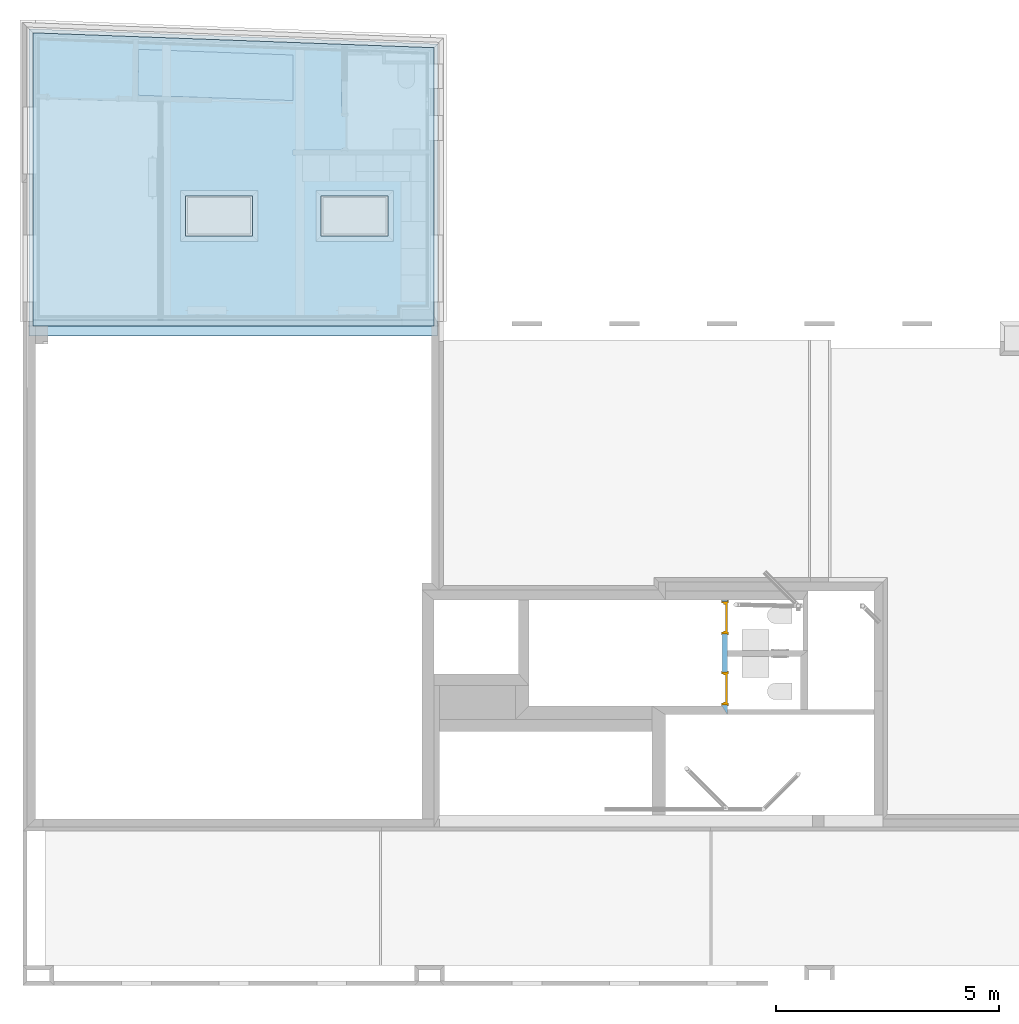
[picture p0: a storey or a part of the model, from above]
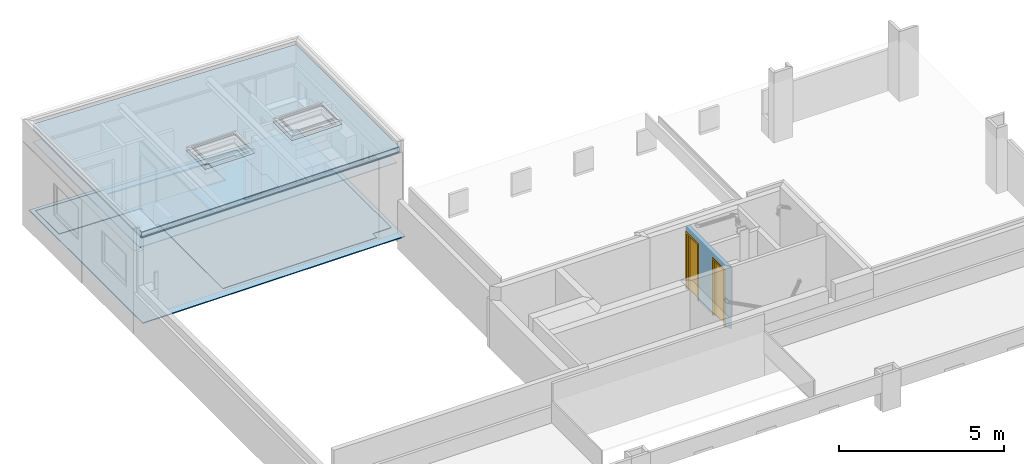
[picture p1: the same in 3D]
Properties of the parts of a building model (IFC2X3), part 2 of 16

# IfcBeam: A-Beams-Steel (159)
Name | In | Description | CodeSystem | Name = StructuralFramingCommon, Section Name | Structural Parameters, Section Name | Length (m) | Area | Cross-sectional (m2) | Area | Cross-sectional Modeled (m2) | Area | Side Surfaces Modeled (Gross) (m2) | Area | All Surfaces Modeled (Net) (m2) | Volume | Perforation(s) (m3) | Volume (Gross) (m3) | Volume (Gross Modeled) (m3) | Volume (Net) (m3) | Volume (Net Modeled) (m3) | Unit Weight | Length x Unit Weight | Volume (Gross) x Density | Volume (Gross Modeled) x Density | Volume (Net) x Density | Volume (Net Modeled) x Density | FireRating = Fire | Rating | ID | Number | ID | Keynote
RP | 5F | 5,SHE-13.STEEL.dgn ,Design Model:125234 | BS UC | UC203X203X46 | 1\BS UC\UC203X203X46 | 1.15342 | 0.00587 | 0.005784 | 1.39149 | 1.40306 | 0 | 0.006771 | 0.006671 | 0.006771 | 0.006671 | 46.100000 | 53.172740 | 53.149095 | 52.368971 | 53.149095 | 52.368971 | FD60 | RP | intumescent paint
RP | 5F | 5,SHE-13.STEEL.dgn ,Design Model:125236 | BS UC | UC203X203X46 | 1\BS UC\UC203X203X46 | 1.15342 | 0.00587 | 0.005784 | 1.39149 | 1.40306 | 0 | 0.006771 | 0.006671 | 0.006771 | 0.006671 | 46.100000 | 53.172740 | 53.149095 | 52.368971 | 53.149095 | 52.368971 | FD60 | RP | intumescent paint
RP | 5F | 5,SHE-13.STEEL.dgn ,Design Model:125238 | BS UC | UC203X203X46 | 1\BS UC\UC203X203X46 | 2.1776 | 0.00587 | 0.005784 | 2.62706 | 2.63862 | 0 | 0.012783 | 0.012595 | 0.012783 | 0.012595 | 46.100000 | 100.387360 | 100.342719 | 98.869886 | 100.342719 | 98.869886 | FD60 | RP | intumescent paint
RP | 5F | 5,SHE-13.STEEL.dgn ,Design Model:125240 | BS UC | UC203X203X46 | 1\BS UC\UC203X203X46 | 2.4968 | 0.00587 | 0.005784 | 3.01214 | 3.02371 | 0 | 0.014656 | 0.014441 | 0.014656 | 0.014441 | 46.100000 | 115.102480 | 115.051296 | 113.362570 | 115.051296 | 113.362570 | FD60 | RP | intumescent paint
RP | 5F | 5,SHE-13.STEEL.dgn ,Design Model:125242 | BS UC | UC203X203X46 | 1\BS UC\UC203X203X46 | 2.2808 | 0.00587 | 0.005784 | 2.75156 | 2.76313 | 0 | 0.013388 | 0.013192 | 0.013388 | 0.013192 | 46.100000 | 105.144880 | 105.098124 | 103.555491 | 105.098124 | 103.555491 | FD60 | RP | intumescent paint
RP | 5F | 5,SHE-13.STEEL.dgn ,Design Model:125244 | BS UC | UC203X203X46 | 1\BS UC\UC203X203X46 | 2.4849 | 0.00587 | 0.005784 | 2.99778 | 3.00935 | 0 | 0.014586 | 0.014372 | 0.014586 | 0.014372 | 46.100000 | 114.553890 | 114.502950 | 112.822273 | 114.502950 | 112.822273 | FD60 | RP | intumescent paint
RP | 5F | 5,SHE-13.STEEL.dgn ,Design Model:125246 | BS UC | UC203X203X46 | 1\BS UC\UC203X203X46 | 2.4857 | 0.00587 | 0.005784 | 2.99875 | 3.01032 | 0 | 0.014591 | 0.014377 | 0.014591 | 0.014377 | 46.100000 | 114.590770 | 114.539813 | 112.858595 | 114.539813 | 112.858595 | FD60 | RP | intumescent paint
RP | 5F | 5,SHE-13.STEEL.dgn ,Design Model:125248 | BS UC | UC203X203X46 | 1\BS UC\UC203X203X46 | 2.5992 | 0.00587 | 0.005784 | 3.13567 | 3.14724 | 0 | 0.015257 | 0.015033 | 0.015257 | 0.015033 | 46.100000 | 119.823120 | 119.769836 | 118.011852 | 119.769836 | 118.011852 | FD60 | RP | intumescent paint
RP | 5F | 5,SHE-13.STEEL.dgn ,Design Model:125250 | BS UC | UC203X203X46 | 1\BS UC\UC203X203X46 | 2.1776 | 0.00587 | 0.005784 | 2.62706 | 2.63862 | 0 | 0.012783 | 0.012595 | 0.012783 | 0.012595 | 46.100000 | 100.387360 | 100.342719 | 98.869886 | 100.342719 | 98.869886 | FD60 | RP | intumescent paint
RP | 5F | 5,SHE-13.STEEL.dgn ,Design Model:125252 | BS UC | UC203X203X46 | 1\BS UC\UC203X203X46 | 2.495 | 0.00587 | 0.005784 | 3.00997 | 3.02154 | 0 | 0.014646 | 0.014431 | 0.014646 | 0.014431 | 46.100000 | 115.019500 | 114.968353 | 113.280844 | 114.968353 | 113.280844 | FD60 | RP | intumescent paint
RP | 5F | 5,SHE-13.STEEL.dgn ,Design Model:125254 | BS UC | UC203X203X46 | 1\BS UC\UC203X203X46 | 2.179 | 0.00587 | 0.005784 | 2.62875 | 2.64031 | 0 | 0.012791 | 0.012603 | 0.012791 | 0.012603 | 46.100000 | 100.451900 | 100.407230 | 98.933451 | 100.407230 | 98.933451 | FD60 | RP | intumescent paint
RP | 5F | 5,SHE-13.STEEL.dgn ,Design Model:125256 | BS UC | UC203X203X46 | 1\BS UC\UC203X203X46 | 2.546 | 0.00587 | 0.005784 | 3.07149 | 3.08306 | 0 | 0.014945 | 0.014726 | 0.014945 | 0.014726 | 46.100000 | 117.370600 | 117.318407 | 115.596405 | 117.318407 | 115.596405 | FD60 | RP | intumescent paint
RP | 5F | 5,SHE-13.STEEL.dgn ,Design Model:125258 | BS UC | UC203X203X46 | 1\BS UC\UC203X203X46 | 2.4936 | 0.00587 | 0.005784 | 3.00828 | 3.01985 | 0 | 0.014637 | 0.014423 | 0.014637 | 0.014423 | 46.100000 | 114.954960 | 114.903841 | 113.217280 | 114.903841 | 113.217280 | FD60 | RP | intumescent paint
RP | 5F | 5,SHE-13.STEEL.dgn ,Design Model:125260 | BS UC | UC203X203X46 | 1\BS UC\UC203X203X46 | 2.546 | 0.00587 | 0.005784 | 3.07149 | 3.08306 | 0 | 0.014945 | 0.014726 | 0.014945 | 0.014726 | 46.100000 | 117.370600 | 117.318407 | 115.596405 | 117.318407 | 115.596405 | FD60 | RP | intumescent paint
RP | 5F | 5,SHE-13.STEEL.dgn ,Design Model:125262 | BS UC | UC203X203X46 | 1\BS UC\UC203X203X46 | 2.3424 | 0.00587 | 0.005784 | 2.82587 | 2.83744 | 0 | 0.01375 | 0.013548 | 0.01375 | 0.013548 | 46.100000 | 107.984640 | 107.936621 | 106.352325 | 107.936621 | 106.352325 | FD60 | RP | intumescent paint
RP | 5F | 5,SHE-13.STEEL.dgn ,Design Model:125264 | BS UC | UC203X203X46 | 1\BS UC\UC203X203X46 | 2.4936 | 0.00587 | 0.005784 | 3.00828 | 3.01985 | 0 | 0.014637 | 0.014423 | 0.014637 | 0.014423 | 46.100000 | 114.954960 | 114.903841 | 113.217280 | 114.903841 | 113.217280 | FD60 | RP | intumescent paint
RP | 5F | 5,SHE-13.STEEL.dgn ,Design Model:125266 | BS UC | UC203X203X46 | 1\BS UC\UC203X203X46 | 2.3424 | 0.00587 | 0.005784 | 2.82587 | 2.83744 | 0 | 0.01375 | 0.013548 | 0.01375 | 0.013548 | 46.100000 | 107.984640 | 107.936621 | 106.352325 | 107.936621 | 106.352325 | FD60 | RP | intumescent paint
RP | 5F | 5,SHE-13.STEEL.dgn ,Design Model:125268 | BS UC | UC203X203X46 | 1\BS UC\UC203X203X46 | 1.13364 | 0.00587 | 0.005784 | 1.36762 | 1.37919 | 0 | 0.006654 | 0.006557 | 0.006654 | 0.006557 | 46.100000 | 52.260631 | 52.237392 | 51.470650 | 52.237392 | 51.470650 | FD60 | RP | intumescent paint
RP | 5F | 5,SHE-13.STEEL.dgn ,Design Model:125270 | BS UC | UC203X203X46 | 1\BS UC\UC203X203X46 | 1.13364 | 0.00587 | 0.005784 | 1.36762 | 1.37919 | 0 | 0.006654 | 0.006557 | 0.006654 | 0.006557 | 46.100000 | 52.260631 | 52.237392 | 51.470650 | 52.237392 | 51.470650 | FD60 | RP | intumescent paint
RP | 5F | 5,SHE-13.STEEL.dgn ,Design Model:125272 | BS UC | UC203X203X46 | 1\BS UC\UC203X203X46 | 2.0364 | 0.00587 | 0.005784 | 2.45671 | 2.46828 | 0 | 0.011954 | 0.011778 | 0.011954 | 0.011778 | 46.100000 | 93.878040 | 93.836294 | 92.458962 | 93.836294 | 92.458962 | FD60 | RP | intumescent paint
RP | 5F | 5,SHE-13.STEEL.dgn ,Design Model:125274 | BS UC | UC203X203X46 | 1\BS UC\UC203X203X46 | 1.9664 | 0.00587 | 0.005784 | 2.37227 | 2.38383 | 0 | 0.011543 | 0.011373 | 0.011543 | 0.011373 | 46.100000 | 90.651040 | 90.610729 | 89.280742 | 90.610729 | 89.280742 | FD60 | RP | intumescent paint
RP | 5F | 5,SHE-13.STEEL.dgn ,Design Model:125276 | BS UC | UC203X203X46 | 1\BS UC\UC203X203X46 | 1.9597 | 0.00587 | 0.005784 | 2.36418 | 2.37575 | 0 | 0.011503 | 0.011335 | 0.011503 | 0.011335 | 46.100000 | 90.342170 | 90.301996 | 88.976541 | 90.301996 | 88.976541 | FD60 | RP | intumescent paint
RP | 5F | 5,SHE-13.STEEL.dgn ,Design Model:125278 | BS UC | UC203X203X46 | 1\BS UC\UC203X203X46 | 2.4839 | 0.00587 | 0.005784 | 2.99658 | 3.00814 | 0 | 0.01458 | 0.014366 | 0.01458 | 0.014366 | 46.100000 | 114.507790 | 114.456870 | 112.776869 | 114.456870 | 112.776869 | FD60 | RP | intumescent paint
RP | 5F | 5,SHE-13.STEEL.dgn ,Design Model:125280 | BS UC | UC203X203X46 | 1\BS UC\UC203X203X46 | 2.0297 | 0.00587 | 0.005784 | 2.44863 | 2.4602 | 0 | 0.011914 | 0.011739 | 0.011914 | 0.011739 | 46.100000 | 93.569170 | 93.527561 | 92.154761 | 93.527561 | 92.154761 | FD60 | RP | intumescent paint
RP | 5F | 5,SHE-13.STEEL.dgn ,Design Model:125282 | BS UC | UC203X203X46 | 1\BS UC\UC203X203X46 | 0.6964 | 0.00587 | 0.005784 | 0.840137 | 0.851705 | 0 | 0.004088 | 0.004028 | 0.004088 | 0.004028 | 46.100000 | 32.104040 | 32.089764 | 31.618749 | 32.089764 | 31.618749 | FD60 | RP | intumescent paint
RP | 5F | 5,SHE-13.STEEL.dgn ,Design Model:125284 | BS UC | UC203X203X46 | 1\BS UC\UC203X203X46 | 2.179 | 0.00587 | 0.005784 | 2.62875 | 2.64031 | 0 | 0.012791 | 0.012603 | 0.012791 | 0.012603 | 46.100000 | 100.451900 | 100.407230 | 98.933451 | 100.407230 | 98.933451 | FD60 | RP | intumescent paint
RP | 5F | 5,SHE-13.STEEL.dgn ,Design Model:125286 | BS UC | UC203X203X46 | 1\BS UC\UC203X203X46 | 4.25305 | 0.00587 | 0.005784 | 5.13088 | 5.14245 | 0 | 0.024965 | 0.024599 | 0.024965 | 0.024599 | 46.100000 | 196.065605 | 195.978417 | 193.101842 | 195.978417 | 193.101842 | FD60 | RP | intumescent paint
RP | 5F | 5,SHE-13.STEEL.dgn ,Design Model:125288 | BS UC | UC203X203X46 | 1\BS UC\UC203X203X46 | 4.2564 | 0.00587 | 0.005784 | 5.13492 | 5.14649 | 0 | 0.024985 | 0.024618 | 0.024985 | 0.024618 | 46.100000 | 196.220040 | 196.132784 | 193.253942 | 196.132784 | 193.253942 | FD60 | RP | intumescent paint
RP | 5F | 5,SHE-13.STEEL.dgn ,Design Model:125290 | BS UC | UC203X203X46 | 1\BS UC\UC203X203X46 | 4.2582 | 0.00587 | 0.005784 | 5.13709 | 5.14866 | 0 | 0.024996 | 0.024629 | 0.024996 | 0.024629 | 46.100000 | 196.303020 | 196.215727 | 193.335668 | 196.215727 | 193.335668 | FD60 | RP | intumescent paint
RP | 5F | 5,SHE-13.STEEL.dgn ,Design Model:125292 | BS UC | UC203X203X46 | 1\BS UC\UC203X203X46 | 4.2082 | 0.00587 | 0.005784 | 5.07677 | 5.08834 | 0 | 0.024702 | 0.02434 | 0.024702 | 0.02434 | 46.100000 | 193.998020 | 193.911752 | 191.065511 | 193.911752 | 191.065511 | FD60 | RP | intumescent paint
RP | 5F | 5,SHE-13.STEEL.dgn ,Design Model:125294 | BS UC | UC203X203X71 | 1\BS UC\UC203X203X71 | 5.53365 | 0.00904 | 0.008953 | 6.84623 | 6.86414 | 0 | 0.050024 | 0.049545 | 0.050024 | 0.049545 | 71.000000 | 392.889150 | 392.689939 | 388.929846 | 392.689939 | 388.929846 | FD60 | RP | intumescent paint
RP | 5F | 5,SHE-13.STEEL.dgn ,Design Model:125296 | BS UC | UC203X203X71 | 1\BS UC\UC203X203X71 | 5.537 | 0.00904 | 0.008953 | 6.85038 | 6.86828 | 0 | 0.050054 | 0.049575 | 0.050054 | 0.049575 | 71.000000 | 393.127000 | 392.927668 | 389.165299 | 392.927668 | 389.165299 | FD60 | RP | intumescent paint
RP | 5F | 5,SHE-13.STEEL.dgn ,Design Model:125298 | BS UC | UC203X203X71 | 1\BS UC\UC203X203X71 | 5.4672 | 0.00904 | 0.008953 | 6.76402 | 6.78193 | 0 | 0.049424 | 0.04895 | 0.049424 | 0.04895 | 71.000000 | 388.171352 | 387.974533 | 384.259591 | 387.974533 | 384.259591 | FD60 | RP | intumescent paint
RP | 5F | 5,SHE-13.STEEL.dgn ,Design Model:125300 | BS UC | UC203X203X71 | 1\BS UC\UC203X203X71 | 5.4672 | 0.00904 | 0.008953 | 6.76402 | 6.78193 | 0 | 0.049424 | 0.04895 | 0.049424 | 0.04895 | 71.000000 | 388.171352 | 387.974533 | 384.259591 | 387.974533 | 384.259591 | FD60 | RP | intumescent paint
RP | 5F | 5,SHE-13.STEEL.dgn ,Design Model:125302 | BS UC | UC305X305X240 | 1\BS UC\UC305X305X240 | 8.38637 | 0.0306 | 0.030381 | 16.2075 | 16.2683 | 0 | 0.256623 | 0.254783 | 0.256623 | 0.254783 | 240.000000 | 2012.727813 | 2014.488949 | 2000.049145 | 2014.488949 | 2000.049145 | FD60 | RP | intumescent paint
RP | 5F | 5,SHE-13.STEEL.dgn ,Design Model:125306 | BS UC | UC305X305X240 | 1\BS UC\UC305X305X240 | 8.38638 | 0.0306 | 0.030381 | 16.2075 | 16.2683 | 0 | 0.256623 | 0.254784 | 0.256623 | 0.254784 | 240.000000 | 2012.730796 | 2014.491935 | 2000.052110 | 2014.491935 | 2000.052110 | FD60 | RP | intumescent paint
RP | 5F | 5,SHE-13.STEEL.dgn ,Design Model:125308 | BS UC | UC305X305X240 | 1\BS UC\UC305X305X240 | 8.38637 | 0.0306 | 0.030381 | 16.2075 | 16.2683 | 0 | 0.256623 | 0.254783 | 0.256623 | 0.254783 | 240.000000 | 2012.727813 | 2014.488949 | 2000.049145 | 2014.488949 | 2000.049145 | FD60 | RP | intumescent paint
A-Beams-Steel | GF | 15 ,SHE-14.BALCONY.dgn,Design Model:168529 | BS5950_UC | UC152X152X51 | 1\BS5950_UC\UC152X152X51 | 5.3944 | 0.0065 | 0.006469 | 5.11389 | 5.04575 | 0.000509 | 0.035064 | 0.034897 | 0.034554 | 0.034388 | 51.200000 | 276.193337 | 275.249317 | 273.943365 | 271.252702 | 269.946750
A-Beams-Steel | GF | 15 ,SHE-14.BALCONY.dgn,Design Model:168535 | BS5950_UC | UC152X152X51 | 1\BS5950_UC\UC152X152X51 | 5.4786 | 0.0065 | 0.006469 | 5.19371 | 5.0445 | 0.001018 | 0.035611 | 0.035442 | 0.034593 | 0.034424 | 51.200000 | 280.504377 | 279.545622 | 278.219285 | 271.552392 | 270.226056
A-Beams-Steel | GF | 15 ,SHE-14.BALCONY.dgn,Design Model:168539 | BS5950_UC | UC152X152X51 | 1\BS5950_UC\UC152X152X51 | 5.4786 | 0.0065 | 0.006469 | 5.19371 | 5.0445 | 0.001018 | 0.035611 | 0.035442 | 0.034593 | 0.034424 | 51.200000 | 280.504377 | 279.545622 | 278.219285 | 271.552392 | 270.226056
A-Beams-Steel | GF | 15 ,SHE-14.BALCONY.dgn,Design Model:168541 | BS5950_UC | UC152X152X51 | 1\BS5950_UC\UC152X152X51 | 2.905 | 0.0065 | 0.006469 | 2.75394 | 2.60473 | 0.001018 | 0.018882 | 0.018793 | 0.017864 | 0.017775 | 51.200000 | 148.736000 | 148.227625 | 147.524342 | 140.234396 | 139.531113
A-Beams-Steel | GF | 15 ,SHE-14.BALCONY.dgn,Design Model:168551 | BS5950_UC | UC152X152X51 | 1\BS5950_UC\UC152X152X51 | 3.84218 | 0.0065 | 0.006469 | 3.64239 | 3.57425 | 0.000509 | 0.024974 | 0.024856 | 0.024465 | 0.024347 | 51.200000 | 196.719650 | 196.047268 | 195.117099 | 192.050653 | 191.120485
A-Beams-Steel | GF | 15 ,SHE-14.BALCONY.dgn,Design Model:169209 | BS5950_UC | UC152X152X51 | 1\BS5950_UC\UC152X152X51 | 1.01038 | 0.0065 | 0.006469 | 0.957841 | 0.970779 | 0 | 0.006567 | 0.006536 | 0.006567 | 0.006536 | 51.200000 | 51.731490 | 51.554673 | 51.310066 | 51.554673 | 51.310066
A-Beams-Steel | GF | 15 ,SHE-14.BALCONY.dgn,Design Model:174204 | BS5950_UC | UC152X152X51 | 1\BS5950_UC\UC152X152X51 | 1.01038 | 0.0065 | 0.006469 | 0.957841 | 0.970779 | 0 | 0.006567 | 0.006536 | 0.006567 | 0.006536 | 51.200000 | 51.731490 | 51.554673 | 51.310066 | 51.554673 | 51.310066
A-Beams-Steel | GF | 15 ,SHE-14.BALCONY.dgn,Design Model:174262 | BS5950_UC | UC152X152X51 | 1\BS5950_UC\UC152X152X51 | 1.01038 | 0.0065 | 0.006469 | 0.957841 | 0.970779 | 0 | 0.006567 | 0.006536 | 0.006567 | 0.006536 | 51.200000 | 51.731490 | 51.554673 | 51.310066 | 51.554673 | 51.310066
A-Beams-Steel | GF | 15 ,SHE-14.BALCONY.dgn,Design Model:179383 | BS5950_UC | UC152X152X51 | 1\BS5950_UC\UC152X152X51 | 2.905 | 0.0065 | 0.006469 | 2.75394 | 2.60473 | 0.001018 | 0.018882 | 0.018793 | 0.017864 | 0.017775 | 51.200000 | 148.736000 | 148.227625 | 147.524342 | 140.234396 | 139.531113
A-Beams-Steel | GF | 15 ,SHE-14.BALCONY.dgn,Design Model:179385 | BS5950_UC | UC152X152X51 | 1\BS5950_UC\UC152X152X51 | 2.905 | 0.0065 | 0.006469 | 2.75394 | 2.60473 | 0.001018 | 0.018882 | 0.018793 | 0.017864 | 0.017775 | 51.200000 | 148.736000 | 148.227625 | 147.524342 | 140.234396 | 139.531113
A-Beams-Steel | GF | 15 ,SHE-14.BALCONY.dgn,Design Model:179389 | BS5950_UC | UC152X152X51 | 1\BS5950_UC\UC152X152X51 | 3.84218 | 0.0065 | 0.006469 | 3.64239 | 3.57425 | 0.000509 | 0.024974 | 0.024856 | 0.024465 | 0.024347 | 51.200000 | 196.719650 | 196.047268 | 195.117099 | 192.050653 | 191.120485
A-Beams-Steel | GF | 15 ,SHE-14.BALCONY.dgn,Design Model:179391 | BS5950_UC | UC152X152X51 | 1\BS5950_UC\UC152X152X51 | 3.84218 | 0.0065 | 0.006469 | 3.64239 | 3.57425 | 0.000509 | 0.024974 | 0.024856 | 0.024465 | 0.024347 | 51.200000 | 196.719650 | 196.047268 | 195.117099 | 192.050653 | 191.120485
A-Beams-Steel | GF | 15 ,SHE-14.BALCONY.dgn,Design Model:179394 | BS5950_UC | UC152X152X51 | 1\BS5950_UC\UC152X152X51 | 5.4786 | 0.0065 | 0.006469 | 5.19371 | 5.0445 | 0.001018 | 0.035611 | 0.035442 | 0.034593 | 0.034424 | 51.200000 | 280.504377 | 279.545622 | 278.219285 | 271.552392 | 270.226056
A-Beams-Steel | GF | 15 ,SHE-14.BALCONY.dgn,Design Model:179404 | BS5950_UC | UC152X152X51 | 1\BS5950_UC\UC152X152X51 | 5.3944 | 0.0065 | 0.006469 | 5.11389 | 5.04575 | 0.000509 | 0.035064 | 0.034897 | 0.034554 | 0.034388 | 51.200000 | 276.193337 | 275.249317 | 273.943365 | 271.252702 | 269.946750
A-Beams-Steel | GF | 15 ,SHE-14.BALCONY.dgn,Design Model:179406 | BS5950_UC | UC152X152X51 | 1\BS5950_UC\UC152X152X51 | 5.3944 | 0.0065 | 0.006469 | 5.11389 | 5.04575 | 0.000509 | 0.035064 | 0.034897 | 0.034554 | 0.034388 | 51.200000 | 276.193337 | 275.249317 | 273.943365 | 271.252702 | 269.946750

# IfcBeam: S-Beams-PrecastConcrete (24)
In: GF
Type - PredefinedType: BEAM
Type - Thermal Transmittance - Is External: no; Is Below Grade: no
Type - Structural Usage - Structural | Function: Undefined; Structural | Material: Concrete
Type - Structural Parameters - Section Name: 300x600; Structural Type: Beam; Tapered Member: no
Type - Quantities | Structural - Length: 0 m; Area | Cross-sectional: 0 m2; Area | Cross-sectional Modeled: 0 m2; Volume | Perforation(s): 0 m3; Volume (Gross): 0 m3; Volume (Gross Modeled): 0 m3; Volume (Net): 0 m3; Volume (Net Modeled): 0 m3; Unit Weight: 0; Material Density: 0; Length x Unit Weight: 0; Volume (Gross) x Density: 0; Volume (Gross Modeled) x Density: 0; Volume (Net) x Density: 0; Volume (Net Modeled) x Density: 0
Type - Materials - Part Definition: S-Beams::S_BSUK_Beams_PrecastConcrete
Type - LEED Parameters - LEED | Pre-consumer Recycled (%): 0; LEED | Regional Material: no; LEED | Post-consumer Recycled (%): 0
Type - Fire Resistance - Fire | IsCombustible: no; Fire | Compartmentation: no
Type - Discipline - Discipline: Structural
Type - Construction Phase - Phase: New Construction
Type - Classification - Uniclass2015: Pr_20_85_08_15
Material: S_BSUK_Beams_PrecastConcrete
Pset_BeamCommon - IsExternal: no; LoadBearing: no
Quantities | Structural - Material Density: 2400.000000
Construction Phase - Phase: Existing to Remain
BuildingDesignerForm - Type: Beam; Material: Concrete; Grade: C40; Class: Gravity; Cope Flange Clearance: 0.000; Cope Web Clearance: 0.000; Cope Corner Treatment: 0; Cope Corner Radius: 0.000; Local Y Offset: 0.000; Local Z Offset: 0.000
Name | Description | StructuralFramingCommon, Section Name | Structural Parameters, Section Name | Length (m) | Area | Cross-sectional (m2) = Area | Cross-sectional Modeled (m2) | Area | Side Surfaces Modeled (Gross) (m2) | Area | All Surfaces Modeled (Net) (m2) | Volume (Gross) (m3) = Volume (Gross Modeled) (m3) = Volume (Net) (m3) = Volume (Net Modeled) (m3) | Unit Weight | Length x Unit Weight | Volume (Gross) x Density = Volume (Gross Modeled) x Density = Volume (Net) x Density = Volume (Net Modeled) x Density
S-Beams-PrecastConcrete | 9 ,SHE-10.CONCRETE.dgn,Design Model:202130 | 0.400X0.500 | 6\RECTANGLE\0.400X0.500 | 14.06 | 0.2 | 25.308 | 25.708 | 2.812 | 1570.000000 | 22074.200000 | 6748.800000
S-Beams-PrecastConcrete | 9 ,SHE-10.CONCRETE.dgn,Design Model:202139 | 0.400X0.500 | 6\RECTANGLE\0.400X0.500 | 14.06 | 0.2 | 25.308 | 25.708 | 2.812 | 1570.000000 | 22074.200000 | 6748.800000
S-Beams-PrecastConcrete | 9 ,SHE-10.CONCRETE.dgn,Design Model:202150 | 0.400X0.500 | 6\RECTANGLE\0.400X0.500 | 14.06 | 0.2 | 25.308 | 25.708 | 2.812 | 1570.000000 | 22074.200000 | 6748.800000
S-Beams-PrecastConcrete | 9 ,SHE-10.CONCRETE.dgn,Design Model:202152 | 0.400X0.500 | 6\RECTANGLE\0.400X0.500 | 14.06 | 0.2 | 25.308 | 25.708 | 2.812 | 1570.000000 | 22074.200000 | 6748.800000
S-Beams-PrecastConcrete | 9 ,SHE-10.CONCRETE.dgn,Design Model:202154 | 0.400X0.500 | 6\RECTANGLE\0.400X0.500 | 14.06 | 0.2 | 25.308 | 25.708 | 2.812 | 1570.000000 | 22074.200000 | 6748.800000
S-Beams-PrecastConcrete | 9 ,SHE-10.CONCRETE.dgn,Design Model:202156 | 0.400X0.500 | 6\RECTANGLE\0.400X0.500 | 14.06 | 0.2 | 25.308 | 25.708 | 2.812 | 1570.000000 | 22074.200000 | 6748.800000
S-Beams-PrecastConcrete | 9 ,SHE-10.CONCRETE.dgn,Design Model:201619 | 0.400X0.380 | 6\RECTANGLE\0.400X0.380 | 11.1535 | 0.152 | 17.3995 | 17.7035 | 1.69534 | 1193.200000 | 13308.401638 | 4068.810692
S-Beams-PrecastConcrete | 9 ,SHE-10.CONCRETE.dgn,Design Model:141247 | 0.500X1.800 | 6\RECTANGLE\0.500X1.800 | 13.62 | 0.9 | 62.652 | 64.452 | 12.258 | 7065.000000 | 96225.300000 | 29419.200000
S-Beams-PrecastConcrete | 9 ,SHE-10.CONCRETE.dgn,Design Model:201617 | 0.400X1.030 | 6\RECTANGLE\0.400X1.030 | 3.54646 | 0.412 | 10.1429 | 10.9669 | 1.46114 | 3234.200000 | 11469.967139 | 3506.741546
S-Beams-PrecastConcrete | 9 ,SHE-10.CONCRETE.dgn,Design Model:141269 | 0.300X1.030 | 6\RECTANGLE\0.300X1.030 | 25.98 | 0.309 | 69.1068 | 69.7248 | 8.02782 | 2425.650000 | 63018.387000 | 19266.768000
S-Beams-PrecastConcrete | 9 ,SHE-10.CONCRETE.dgn,Design Model:201404 | 0.400X1.030 | 6\RECTANGLE\0.400X1.030 | 3.54646 | 0.412 | 10.1429 | 10.9669 | 1.46114 | 3234.200000 | 11469.967139 | 3506.741546
S-Beams-PrecastConcrete | 9 ,SHE-10.CONCRETE.dgn,Design Model:201590 | 0.400X0.380 | 6\RECTANGLE\0.400X0.380 | 11.1535 | 0.152 | 17.3995 | 17.7035 | 1.69534 | 1193.200000 | 13308.401638 | 4068.810692
S-Beams-PrecastConcrete | 9 ,SHE-10.CONCRETE.dgn,Design Model:204340 | 0.500X0.380 | 6\RECTANGLE\0.500X0.380 | 4.07 | 0.19 | 7.1632 | 7.5432 | 0.7733 | 1491.500000 | 6070.405000 | 1855.920000
S-Beams-PrecastConcrete | 9 ,SHE-10.CONCRETE.dgn,Design Model:204388 | 0.500X0.380 | 6\RECTANGLE\0.500X0.380 | 8.29 | 0.19 | 14.5904 | 14.9704 | 1.5751 | 1491.500000 | 12364.535000 | 3780.240000
S-Beams-PrecastConcrete | 9 ,SHE-10.CONCRETE.dgn,Design Model:221948 | 0.300X0.250 | 6\RECTANGLE\0.300X0.250 | 8.36 | 0.075 | 9.196 | 9.346 | 0.627 | 588.750000 | 4921.950000 | 1504.800000
S-Beams-PrecastConcrete | 9 ,SHE-10.CONCRETE.dgn,Design Model:223033 | 0.250X0.700 | 6\RECTANGLE\0.250X0.700 | 8.40304 | 0.175 | 15.9658 | 16.3158 | 1.47053 | 1373.750000 | 11543.673441 | 3529.275956
S-Beams-PrecastConcrete | 9 ,SHE-10.CONCRETE.dgn,Design Model:223466 | 0.400X0.340 | 6\RECTANGLE\0.400X0.340 | 14.06 | 0.136 | 20.8088 | 21.0808 | 1.91216 | 1067.600000 | 15010.456000 | 4589.184000
S-Beams-PrecastConcrete | 9 ,SHE-10.CONCRETE.dgn,Design Model:223473 | 0.400X0.340 | 6\RECTANGLE\0.400X0.340 | 14.06 | 0.136 | 20.8088 | 21.0808 | 1.91216 | 1067.600000 | 15010.456000 | 4589.184000
S-Beams-PrecastConcrete | 9 ,SHE-10.CONCRETE.dgn,Design Model:224976 | 0.400X0.340 | 6\RECTANGLE\0.400X0.340 | 6.47788 | 0.136 | 9.58727 | 9.85927 | 0.880992 | 1067.600000 | 6915.788288 | 2114.381133
S-Beams-PrecastConcrete | 9 ,SHE-10.CONCRETE.dgn,Design Model:224978 | 0.400X0.340 | 6\RECTANGLE\0.400X0.340 | 6.17178 | 0.136 | 9.13424 | 9.40624 | 0.839363 | 1067.600000 | 6588.997190 | 2014.470479
S-Beams-PrecastConcrete | 9 ,SHE-10.CONCRETE.dgn,Design Model:292563 | 0.330X0.950 | 6\RECTANGLE\0.330X0.950 | 25.9 | 0.3135 | 66.304 | 66.931 | 8.11965 | 2460.975000 | 63739.252500 | 19487.160000
S-Beams-PrecastConcrete | 9 ,SHE-10.CONCRETE.dgn,Design Model:292566 | 0.370X0.950 | 6\RECTANGLE\0.370X0.950 | 14.56 | 0.3515 | 38.4384 | 39.1414 | 5.11784 | 2759.275000 | 40175.044000 | 12282.816000
S-Beams-PrecastConcrete | 9 ,SHE-10.CONCRETE.dgn,Design Model:292568 | 0.330X0.950 | 6\RECTANGLE\0.330X0.950 | 25.9 | 0.3135 | 66.304 | 66.931 | 8.11965 | 2460.975000 | 63739.252500 | 19487.160000
S-Beams-PrecastConcrete | 9 ,SHE-10.CONCRETE.dgn,Design Model:292570 | 0.370X0.950 | 6\RECTANGLE\0.370X0.950 | 14.56 | 0.3515 | 38.4384 | 39.1414 | 5.11784 | 2759.275000 | 40175.044000 | 12282.816000

# IfcBeam: SHE_A-Beams-Steel-Purlin_150m15 (639)
In: 5F
Type - Description: cold formed purlin; PredefinedType: BEAM
Type - Profile - CodeSystem: AS_C_PURLINS; Name: C15015
Type - Thermal Transmittance - Is External: no; Is Below Grade: no
Type - Structural Usage - Structural | Material: Steel
Type - Structural Parameters - Section Name: 1\AS_C_PURLINS\C15015; Structural Type: Beam; Tapered Member: no
Type - Steel Beam Results - Camber: 0 m; End 1 Shear: 0; End 2 Shear: 0
Type - Materials - Part Definition: A-Beams::A_BSUK_Beams_Steel
Type - Identification - ID | Type ID: 150m15; ID | Description: cold formed purlin
Type - Fireproofing - Has Fireproofing: no; Fireproofing Thickness: 0 m
Type - Fire Resistance - Fire | IsCombustible: no; Fire | Compartmentation: no
Type - Discipline - Discipline: Architectural
Type - Construction Phase - Phase: New Construction
Type - Classification - Uniclass2015: Pr_20_85_08_11
Material: A_BSUK_Beams_Steel
Pset_BeamCommon - FireRating: FD60; IsExternal: no; LoadBearing: no
StructuralFramingCommon - Section Name: C15015
Quantities | Structural - Area | Cross-sectional: 0.00443 m2; Volume | Perforation(s): 0 m3; Unit Weight: 3.590000; Material Density: 7850.000000
Identification - ID | Keynote: intumescent paint
Fire Resistance - Fire | Rating: FD60
BuildingDesignerForm - Cope Flange Clearance: 0.000; Cope Web Clearance: 0.000; Cope Corner Treatment: 0; Cope Corner Radius: 0.000; Local Y Offset: 0.000; Local Z Offset: 0.000
Name | Description | Length (m) | Area | Cross-sectional Modeled (m2) | Area | Side Surfaces Modeled (Gross) (m2) | Area | All Surfaces Modeled (Net) (m2) | Volume (Gross) (m3) = Volume (Net) (m3) | Volume (Gross Modeled) (m3) = Volume (Net Modeled) (m3) | Length x Unit Weight | Volume (Gross) x Density = Volume (Net) x Density | Volume (Gross Modeled) x Density = Volume (Net Modeled) x Density | ID | Number
4F | 150m15 - cold formed purlin :5,SHE-13.STEEL.dgn,Design Model:123656 | 3.9209 | 0.000457 | 2.40351 | 2.40443 | 0.01737 | 0.001794 | 14.076031 | 136.351258 | 14.081422 | 4F
4F | 150m15 - cold formed purlin :5,SHE-13.STEEL.dgn,Design Model:123658 | 3.9209 | 0.000457 | 2.40351 | 2.40443 | 0.01737 | 0.001794 | 14.076031 | 136.351258 | 14.081422 | 4F
4F | 150m15 - cold formed purlin :5,SHE-13.STEEL.dgn,Design Model:123660 | 3.9209 | 0.000457 | 2.40351 | 2.40443 | 0.01737 | 0.001794 | 14.076031 | 136.351258 | 14.081422 | 4F
4F | 150m15 - cold formed purlin :5,SHE-13.STEEL.dgn,Design Model:123662 | 3.9209 | 0.000457 | 2.40351 | 2.40443 | 0.01737 | 0.001794 | 14.076031 | 136.351258 | 14.081422 | 4F
4F | 150m15 - cold formed purlin :5,SHE-13.STEEL.dgn,Design Model:123664 | 3.9209 | 0.000457 | 2.40351 | 2.40443 | 0.01737 | 0.001794 | 14.076031 | 136.351258 | 14.081422 | 4F
4F | 150m15 - cold formed purlin :5,SHE-13.STEEL.dgn,Design Model:123666 | 3.9209 | 0.000457 | 2.40351 | 2.40443 | 0.01737 | 0.001794 | 14.076031 | 136.351258 | 14.081422 | 4F
4F | 150m15 - cold formed purlin :5,SHE-13.STEEL.dgn,Design Model:123668 | 3.9209 | 0.000457 | 2.40351 | 2.40443 | 0.01737 | 0.001794 | 14.076031 | 136.351258 | 14.081422 | 4F
4F | 150m15 - cold formed purlin :5,SHE-13.STEEL.dgn,Design Model:123670 | 3.9209 | 0.000457 | 2.40351 | 2.40443 | 0.01737 | 0.001794 | 14.076031 | 136.351258 | 14.081422 | 4F
4F | 150m15 - cold formed purlin :5,SHE-13.STEEL.dgn,Design Model:123672 | 3.9209 | 0.000457 | 2.40351 | 2.40443 | 0.01737 | 0.001794 | 14.076031 | 136.351258 | 14.081422 | 4F
4F | 150m15 - cold formed purlin :5,SHE-13.STEEL.dgn,Design Model:123674 | 3.9209 | 0.000457 | 2.40351 | 2.40443 | 0.01737 | 0.001794 | 14.076031 | 136.351258 | 14.081422 | 4F
4F | 150m15 - cold formed purlin :5,SHE-13.STEEL.dgn,Design Model:123676 | 3.9209 | 0.000457 | 2.40351 | 2.40443 | 0.01737 | 0.001794 | 14.076031 | 136.351258 | 14.081422 | 4F
4F | 150m15 - cold formed purlin :5,SHE-13.STEEL.dgn,Design Model:123678 | 3.9209 | 0.000457 | 2.40351 | 2.40443 | 0.01737 | 0.001794 | 14.076031 | 136.351258 | 14.081422 | 4F
4F | 150m15 - cold formed purlin :5,SHE-13.STEEL.dgn,Design Model:123682 | 4.2509 | 0.000457 | 2.6058 | 2.60672 | 0.018831 | 0.001945 | 15.260731 | 147.827173 | 15.266576 | 4F
4F | 150m15 - cold formed purlin :5,SHE-13.STEEL.dgn,Design Model:123684 | 4.2509 | 0.000457 | 2.6058 | 2.60672 | 0.018831 | 0.001945 | 15.260731 | 147.827173 | 15.266576 | 4F
4F | 150m15 - cold formed purlin :5,SHE-13.STEEL.dgn,Design Model:123686 | 4.2509 | 0.000457 | 2.6058 | 2.60672 | 0.018831 | 0.001945 | 15.260731 | 147.827173 | 15.266576 | 4F
4F | 150m15 - cold formed purlin :5,SHE-13.STEEL.dgn,Design Model:123688 | 4.2509 | 0.000457 | 2.6058 | 2.60672 | 0.018831 | 0.001945 | 15.260731 | 147.827173 | 15.266576 | 4F
4F | 150m15 - cold formed purlin :5,SHE-13.STEEL.dgn,Design Model:123690 | 4.2509 | 0.000457 | 2.6058 | 2.60672 | 0.018831 | 0.001945 | 15.260731 | 147.827173 | 15.266576 | 4F
4F | 150m15 - cold formed purlin :5,SHE-13.STEEL.dgn,Design Model:123692 | 4.2509 | 0.000457 | 2.6058 | 2.60672 | 0.018831 | 0.001945 | 15.260731 | 147.827173 | 15.266576 | 4F
4F | 150m15 - cold formed purlin :5,SHE-13.STEEL.dgn,Design Model:123694 | 4.2509 | 0.000457 | 2.6058 | 2.60672 | 0.018831 | 0.001945 | 15.260731 | 147.827173 | 15.266576 | 4F
4F | 150m15 - cold formed purlin :5,SHE-13.STEEL.dgn,Design Model:123696 | 4.2509 | 0.000457 | 2.6058 | 2.60672 | 0.018831 | 0.001945 | 15.260731 | 147.827173 | 15.266576 | 4F
4F | 150m15 - cold formed purlin :5,SHE-13.STEEL.dgn,Design Model:123698 | 4.2509 | 0.000457 | 2.6058 | 2.60672 | 0.018831 | 0.001945 | 15.260731 | 147.827173 | 15.266576 | 4F
4F | 150m15 - cold formed purlin :5,SHE-13.STEEL.dgn,Design Model:123700 | 4.2509 | 0.000457 | 2.6058 | 2.60672 | 0.018831 | 0.001945 | 15.260731 | 147.827173 | 15.266576 | 4F
4F | 150m15 - cold formed purlin :5,SHE-13.STEEL.dgn,Design Model:123702 | 4.2509 | 0.000457 | 2.6058 | 2.60672 | 0.018831 | 0.001945 | 15.260731 | 147.827173 | 15.266576 | 4F
4F | 150m15 - cold formed purlin :5,SHE-13.STEEL.dgn,Design Model:123704 | 4.2509 | 0.000457 | 2.6058 | 2.60672 | 0.018831 | 0.001945 | 15.260731 | 147.827173 | 15.266576 | 4F
4F | 150m15 - cold formed purlin :5,SHE-13.STEEL.dgn,Design Model:123708 | 4.2009 | 0.000457 | 2.57515 | 2.57607 | 0.01861 | 0.001922 | 15.081231 | 146.088398 | 15.087007 | 4F
4F | 150m15 - cold formed purlin :5,SHE-13.STEEL.dgn,Design Model:123710 | 4.2009 | 0.000457 | 2.57515 | 2.57607 | 0.01861 | 0.001922 | 15.081231 | 146.088398 | 15.087007 | 4F
4F | 150m15 - cold formed purlin :5,SHE-13.STEEL.dgn,Design Model:123712 | 4.2009 | 0.000457 | 2.57515 | 2.57607 | 0.01861 | 0.001922 | 15.081231 | 146.088398 | 15.087007 | 4F
4F | 150m15 - cold formed purlin :5,SHE-13.STEEL.dgn,Design Model:123714 | 4.2009 | 0.000457 | 2.57515 | 2.57607 | 0.01861 | 0.001922 | 15.081231 | 146.088398 | 15.087007 | 4F
4F | 150m15 - cold formed purlin :5,SHE-13.STEEL.dgn,Design Model:123716 | 4.2009 | 0.000457 | 2.57515 | 2.57607 | 0.01861 | 0.001922 | 15.081231 | 146.088398 | 15.087007 | 4F
4F | 150m15 - cold formed purlin :5,SHE-13.STEEL.dgn,Design Model:123718 | 4.2009 | 0.000457 | 2.57515 | 2.57607 | 0.01861 | 0.001922 | 15.081231 | 146.088398 | 15.087007 | 4F
4F | 150m15 - cold formed purlin :5,SHE-13.STEEL.dgn,Design Model:123720 | 4.2009 | 0.000457 | 2.57515 | 2.57607 | 0.01861 | 0.001922 | 15.081231 | 146.088398 | 15.087007 | 4F
4F | 150m15 - cold formed purlin :5,SHE-13.STEEL.dgn,Design Model:123722 | 4.2009 | 0.000457 | 2.57515 | 2.57607 | 0.01861 | 0.001922 | 15.081231 | 146.088398 | 15.087007 | 4F
4F | 150m15 - cold formed purlin :5,SHE-13.STEEL.dgn,Design Model:123724 | 4.2009 | 0.000457 | 2.57515 | 2.57607 | 0.01861 | 0.001922 | 15.081231 | 146.088398 | 15.087007 | 4F
4F | 150m15 - cold formed purlin :5,SHE-13.STEEL.dgn,Design Model:123726 | 4.2009 | 0.000457 | 2.57515 | 2.57607 | 0.01861 | 0.001922 | 15.081231 | 146.088398 | 15.087007 | 4F
4F | 150m15 - cold formed purlin :5,SHE-13.STEEL.dgn,Design Model:123728 | 4.2009 | 0.000457 | 2.57515 | 2.57607 | 0.01861 | 0.001922 | 15.081231 | 146.088398 | 15.087007 | 4F
4F | 150m15 - cold formed purlin :5,SHE-13.STEEL.dgn,Design Model:123730 | 4.2009 | 0.000457 | 2.57515 | 2.57607 | 0.01861 | 0.001922 | 15.081231 | 146.088398 | 15.087007 | 4F
4F | 150m15 - cold formed purlin :5,SHE-13.STEEL.dgn,Design Model:123762 | 3.9709 | 0.000457 | 2.43416 | 2.43508 | 0.017591 | 0.001817 | 14.255531 | 138.090033 | 14.260991 | 4F
4F | 150m15 - cold formed purlin :5,SHE-13.STEEL.dgn,Design Model:123764 | 3.9709 | 0.000457 | 2.43416 | 2.43508 | 0.017591 | 0.001817 | 14.255531 | 138.090033 | 14.260991 | 4F
4F | 150m15 - cold formed purlin :5,SHE-13.STEEL.dgn,Design Model:123766 | 3.9709 | 0.000457 | 2.43416 | 2.43508 | 0.017591 | 0.001817 | 14.255531 | 138.090033 | 14.260991 | 4F
4F | 150m15 - cold formed purlin :5,SHE-13.STEEL.dgn,Design Model:123768 | 3.9709 | 0.000457 | 2.43416 | 2.43508 | 0.017591 | 0.001817 | 14.255531 | 138.090033 | 14.260991 | 4F
4F | 150m15 - cold formed purlin :5,SHE-13.STEEL.dgn,Design Model:123770 | 3.9709 | 0.000457 | 2.43416 | 2.43508 | 0.017591 | 0.001817 | 14.255531 | 138.090033 | 14.260991 | 4F
4F | 150m15 - cold formed purlin :5,SHE-13.STEEL.dgn,Design Model:123772 | 3.9709 | 0.000457 | 2.43416 | 2.43508 | 0.017591 | 0.001817 | 14.255531 | 138.090033 | 14.260991 | 4F
4F | 150m15 - cold formed purlin :5,SHE-13.STEEL.dgn,Design Model:123774 | 3.9709 | 0.000457 | 2.43416 | 2.43508 | 0.017591 | 0.001817 | 14.255531 | 138.090033 | 14.260991 | 4F
4F | 150m15 - cold formed purlin :5,SHE-13.STEEL.dgn,Design Model:123776 | 3.9709 | 0.000457 | 2.43416 | 2.43508 | 0.017591 | 0.001817 | 14.255531 | 138.090033 | 14.260991 | 4F
4F | 150m15 - cold formed purlin :5,SHE-13.STEEL.dgn,Design Model:123778 | 3.9709 | 0.000457 | 2.43416 | 2.43508 | 0.017591 | 0.001817 | 14.255531 | 138.090033 | 14.260991 | 4F
4F | 150m15 - cold formed purlin :5,SHE-13.STEEL.dgn,Design Model:123780 | 3.9709 | 0.000457 | 2.43416 | 2.43508 | 0.017591 | 0.001817 | 14.255531 | 138.090033 | 14.260991 | 4F
4F | 150m15 - cold formed purlin :5,SHE-13.STEEL.dgn,Design Model:123782 | 3.9709 | 0.000457 | 2.43416 | 2.43508 | 0.017591 | 0.001817 | 14.255531 | 138.090033 | 14.260991 | 4F
4F | 150m15 - cold formed purlin :5,SHE-13.STEEL.dgn,Design Model:123784 | 3.9709 | 0.000457 | 2.43416 | 2.43508 | 0.017591 | 0.001817 | 14.255531 | 138.090033 | 14.260991 | 4F
4F | 150m15 - cold formed purlin :5,SHE-13.STEEL.dgn,Design Model:123786 | 3.9709 | 0.000457 | 2.43416 | 2.43508 | 0.017591 | 0.001817 | 14.255531 | 138.090033 | 14.260991 | 4F
4F | 150m15 - cold formed purlin :5,SHE-13.STEEL.dgn,Design Model:123790 | 3.9209 | 0.000457 | 2.40351 | 2.40443 | 0.01737 | 0.001794 | 14.076031 | 136.351258 | 14.081422 | 4F
4F | 150m15 - cold formed purlin :5,SHE-13.STEEL.dgn,Design Model:123792 | 3.9209 | 0.000457 | 2.40351 | 2.40443 | 0.01737 | 0.001794 | 14.076031 | 136.351258 | 14.081422 | 4F
4F | 150m15 - cold formed purlin :5,SHE-13.STEEL.dgn,Design Model:123794 | 3.9209 | 0.000457 | 2.40351 | 2.40443 | 0.01737 | 0.001794 | 14.076031 | 136.351258 | 14.081422 | 4F
4F | 150m15 - cold formed purlin :5,SHE-13.STEEL.dgn,Design Model:123796 | 3.9209 | 0.000457 | 2.40351 | 2.40443 | 0.01737 | 0.001794 | 14.076031 | 136.351258 | 14.081422 | 4F
4F | 150m15 - cold formed purlin :5,SHE-13.STEEL.dgn,Design Model:123798 | 3.9209 | 0.000457 | 2.40351 | 2.40443 | 0.01737 | 0.001794 | 14.076031 | 136.351258 | 14.081422 | 4F
4F | 150m15 - cold formed purlin :5,SHE-13.STEEL.dgn,Design Model:123800 | 3.9209 | 0.000457 | 2.40351 | 2.40443 | 0.01737 | 0.001794 | 14.076031 | 136.351258 | 14.081422 | 4F
4F | 150m15 - cold formed purlin :5,SHE-13.STEEL.dgn,Design Model:123802 | 3.9209 | 0.000457 | 2.40351 | 2.40443 | 0.01737 | 0.001794 | 14.076031 | 136.351258 | 14.081422 | 4F
4F | 150m15 - cold formed purlin :5,SHE-13.STEEL.dgn,Design Model:123804 | 3.9209 | 0.000457 | 2.40351 | 2.40443 | 0.01737 | 0.001794 | 14.076031 | 136.351258 | 14.081422 | 4F
4F | 150m15 - cold formed purlin :5,SHE-13.STEEL.dgn,Design Model:123806 | 3.9209 | 0.000457 | 2.40351 | 2.40443 | 0.01737 | 0.001794 | 14.076031 | 136.351258 | 14.081422 | 4F
4F | 150m15 - cold formed purlin :5,SHE-13.STEEL.dgn,Design Model:123808 | 3.9209 | 0.000457 | 2.40351 | 2.40443 | 0.01737 | 0.001794 | 14.076031 | 136.351258 | 14.081422 | 4F
4F | 150m15 - cold formed purlin :5,SHE-13.STEEL.dgn,Design Model:123810 | 3.9209 | 0.000457 | 2.40351 | 2.40443 | 0.01737 | 0.001794 | 14.076031 | 136.351258 | 14.081422 | 4F
4F | 150m15 - cold formed purlin :5,SHE-13.STEEL.dgn,Design Model:123812 | 3.9209 | 0.000457 | 2.40351 | 2.40443 | 0.01737 | 0.001794 | 14.076031 | 136.351258 | 14.081422 | 4F
4F | 150m15 - cold formed purlin :5,SHE-13.STEEL.dgn,Design Model:123814 | 3.9209 | 0.000457 | 2.40351 | 2.40443 | 0.01737 | 0.001794 | 14.076031 | 136.351258 | 14.081422 | 4F
4F | 150m15 - cold formed purlin :5,SHE-13.STEEL.dgn,Design Model:123816 | 4.2509 | 0.000457 | 2.6058 | 2.60672 | 0.018831 | 0.001945 | 15.260731 | 147.827173 | 15.266576 | 4F
4F | 150m15 - cold formed purlin :5,SHE-13.STEEL.dgn,Design Model:123818 | 4.2509 | 0.000457 | 2.6058 | 2.60672 | 0.018831 | 0.001945 | 15.260731 | 147.827173 | 15.266576 | 4F
4F | 150m15 - cold formed purlin :5,SHE-13.STEEL.dgn,Design Model:123820 | 4.2509 | 0.000457 | 2.6058 | 2.60672 | 0.018831 | 0.001945 | 15.260731 | 147.827173 | 15.266576 | 4F
4F | 150m15 - cold formed purlin :5,SHE-13.STEEL.dgn,Design Model:123822 | 4.2509 | 0.000457 | 2.6058 | 2.60672 | 0.018831 | 0.001945 | 15.260731 | 147.827173 | 15.266576 | 4F
4F | 150m15 - cold formed purlin :5,SHE-13.STEEL.dgn,Design Model:123824 | 4.2509 | 0.000457 | 2.6058 | 2.60672 | 0.018831 | 0.001945 | 15.260731 | 147.827173 | 15.266576 | 4F
4F | 150m15 - cold formed purlin :5,SHE-13.STEEL.dgn,Design Model:123826 | 4.2509 | 0.000457 | 2.6058 | 2.60672 | 0.018831 | 0.001945 | 15.260731 | 147.827173 | 15.266576 | 4F
4F | 150m15 - cold formed purlin :5,SHE-13.STEEL.dgn,Design Model:123828 | 4.2509 | 0.000457 | 2.6058 | 2.60672 | 0.018831 | 0.001945 | 15.260731 | 147.827173 | 15.266576 | 4F
4F | 150m15 - cold formed purlin :5,SHE-13.STEEL.dgn,Design Model:123830 | 4.2509 | 0.000457 | 2.6058 | 2.60672 | 0.018831 | 0.001945 | 15.260731 | 147.827173 | 15.266576 | 4F
4F | 150m15 - cold formed purlin :5,SHE-13.STEEL.dgn,Design Model:123842 | 3.9709 | 0.000457 | 2.43416 | 2.43508 | 0.017591 | 0.001817 | 14.255531 | 138.090033 | 14.260991 | 4F
4F | 150m15 - cold formed purlin :5,SHE-13.STEEL.dgn,Design Model:123844 | 3.9709 | 0.000457 | 2.43416 | 2.43508 | 0.017591 | 0.001817 | 14.255531 | 138.090033 | 14.260991 | 4F
4F | 150m15 - cold formed purlin :5,SHE-13.STEEL.dgn,Design Model:123846 | 3.9709 | 0.000457 | 2.43416 | 2.43508 | 0.017591 | 0.001817 | 14.255531 | 138.090033 | 14.260991 | 4F
4F | 150m15 - cold formed purlin :5,SHE-13.STEEL.dgn,Design Model:123848 | 3.9709 | 0.000457 | 2.43416 | 2.43508 | 0.017591 | 0.001817 | 14.255531 | 138.090033 | 14.260991 | 4F
4F | 150m15 - cold formed purlin :5,SHE-13.STEEL.dgn,Design Model:123850 | 3.9709 | 0.000457 | 2.43416 | 2.43508 | 0.017591 | 0.001817 | 14.255531 | 138.090033 | 14.260991 | 4F
4F | 150m15 - cold formed purlin :5,SHE-13.STEEL.dgn,Design Model:123852 | 3.9709 | 0.000457 | 2.43416 | 2.43508 | 0.017591 | 0.001817 | 14.255531 | 138.090033 | 14.260991 | 4F
4F | 150m15 - cold formed purlin :5,SHE-13.STEEL.dgn,Design Model:123854 | 3.9709 | 0.000457 | 2.43416 | 2.43508 | 0.017591 | 0.001817 | 14.255531 | 138.090033 | 14.260991 | 4F
4F | 150m15 - cold formed purlin :5,SHE-13.STEEL.dgn,Design Model:123856 | 3.9709 | 0.000457 | 2.43416 | 2.43508 | 0.017591 | 0.001817 | 14.255531 | 138.090033 | 14.260991 | 4F
4F | 150m15 - cold formed purlin :5,SHE-13.STEEL.dgn,Design Model:123858 | 3.9709 | 0.000457 | 2.43416 | 2.43508 | 0.017591 | 0.001817 | 14.255531 | 138.090033 | 14.260991 | 4F
4F | 150m15 - cold formed purlin :5,SHE-13.STEEL.dgn,Design Model:123860 | 3.9709 | 0.000457 | 2.43416 | 2.43508 | 0.017591 | 0.001817 | 14.255531 | 138.090033 | 14.260991 | 4F
4F | 150m15 - cold formed purlin :5,SHE-13.STEEL.dgn,Design Model:123862 | 3.9709 | 0.000457 | 2.43416 | 2.43508 | 0.017591 | 0.001817 | 14.255531 | 138.090033 | 14.260991 | 4F
4F | 150m15 - cold formed purlin :5,SHE-13.STEEL.dgn,Design Model:123864 | 3.9709 | 0.000457 | 2.43416 | 2.43508 | 0.017591 | 0.001817 | 14.255531 | 138.090033 | 14.260991 | 4F
4F | 150m15 - cold formed purlin :5,SHE-13.STEEL.dgn,Design Model:123866 | 3.9709 | 0.000457 | 2.43416 | 2.43508 | 0.017591 | 0.001817 | 14.255531 | 138.090033 | 14.260991 | 4F
4F | 150m15 - cold formed purlin :5,SHE-13.STEEL.dgn,Design Model:123868 | 4.2009 | 0.000457 | 2.57515 | 2.57607 | 0.01861 | 0.001922 | 15.081231 | 146.088398 | 15.087007 | 4F
4F | 150m15 - cold formed purlin :5,SHE-13.STEEL.dgn,Design Model:123870 | 4.2009 | 0.000457 | 2.57515 | 2.57607 | 0.01861 | 0.001922 | 15.081231 | 146.088398 | 15.087007 | 4F
4F | 150m15 - cold formed purlin :5,SHE-13.STEEL.dgn,Design Model:123872 | 4.2009 | 0.000457 | 2.57515 | 2.57607 | 0.01861 | 0.001922 | 15.081231 | 146.088398 | 15.087007 | 4F
4F | 150m15 - cold formed purlin :5,SHE-13.STEEL.dgn,Design Model:123874 | 4.2009 | 0.000457 | 2.57515 | 2.57607 | 0.01861 | 0.001922 | 15.081231 | 146.088398 | 15.087007 | 4F
4F | 150m15 - cold formed purlin :5,SHE-13.STEEL.dgn,Design Model:123876 | 4.2009 | 0.000457 | 2.57515 | 2.57607 | 0.01861 | 0.001922 | 15.081231 | 146.088398 | 15.087007 | 4F
4F | 150m15 - cold formed purlin :5,SHE-13.STEEL.dgn,Design Model:123878 | 4.2009 | 0.000457 | 2.57515 | 2.57607 | 0.01861 | 0.001922 | 15.081231 | 146.088398 | 15.087007 | 4F
4F | 150m15 - cold formed purlin :5,SHE-13.STEEL.dgn,Design Model:123880 | 4.2009 | 0.000457 | 2.57515 | 2.57607 | 0.01861 | 0.001922 | 15.081231 | 146.088398 | 15.087007 | 4F
4F | 150m15 - cold formed purlin :5,SHE-13.STEEL.dgn,Design Model:123882 | 4.2009 | 0.000457 | 2.57515 | 2.57607 | 0.01861 | 0.001922 | 15.081231 | 146.088398 | 15.087007 | 4F
5F | 150m15 - cold formed purlin :5,SHE-13.STEEL.dgn,Design Model:123895 | 3.5036 | 0.000457 | 2.14771 | 2.14862 | 0.015521 | 0.001603 | 12.577924 | 121.839442 | 12.582741 | 5F
5F | 150m15 - cold formed purlin :5,SHE-13.STEEL.dgn,Design Model:123897 | 3.5036 | 0.000457 | 2.14771 | 2.14862 | 0.015521 | 0.001603 | 12.577924 | 121.839442 | 12.582741 | 5F
5F | 150m15 - cold formed purlin :5,SHE-13.STEEL.dgn,Design Model:123899 | 3.5036 | 0.000457 | 2.14771 | 2.14862 | 0.015521 | 0.001603 | 12.577924 | 121.839442 | 12.582741 | 5F
5F | 150m15 - cold formed purlin :5,SHE-13.STEEL.dgn,Design Model:123901 | 3.5036 | 0.000457 | 2.14771 | 2.14862 | 0.015521 | 0.001603 | 12.577924 | 121.839442 | 12.582741 | 5F
5F | 150m15 - cold formed purlin :5,SHE-13.STEEL.dgn,Design Model:123903 | 3.5036 | 0.000457 | 2.14771 | 2.14862 | 0.015521 | 0.001603 | 12.577924 | 121.839442 | 12.582741 | 5F
5F | 150m15 - cold formed purlin :5,SHE-13.STEEL.dgn,Design Model:123905 | 3.5036 | 0.000457 | 2.14771 | 2.14862 | 0.015521 | 0.001603 | 12.577924 | 121.839442 | 12.582741 | 5F
5F | 150m15 - cold formed purlin :5,SHE-13.STEEL.dgn,Design Model:123907 | 3.5036 | 0.000457 | 2.14771 | 2.14862 | 0.015521 | 0.001603 | 12.577924 | 121.839442 | 12.582741 | 5F
5F | 150m15 - cold formed purlin :5,SHE-13.STEEL.dgn,Design Model:123909 | 3.5036 | 0.000457 | 2.14771 | 2.14862 | 0.015521 | 0.001603 | 12.577924 | 121.839442 | 12.582741 | 5F
5F | 150m15 - cold formed purlin :5,SHE-13.STEEL.dgn,Design Model:123911 | 3.5036 | 0.000457 | 2.14771 | 2.14862 | 0.015521 | 0.001603 | 12.577924 | 121.839442 | 12.582741 | 5F
5F | 150m15 - cold formed purlin :5,SHE-13.STEEL.dgn,Design Model:123913 | 3.5036 | 0.000457 | 2.14771 | 2.14862 | 0.015521 | 0.001603 | 12.577924 | 121.839442 | 12.582741 | 5F
5F | 150m15 - cold formed purlin :5,SHE-13.STEEL.dgn,Design Model:123915 | 3.5036 | 0.000457 | 2.14771 | 2.14862 | 0.015521 | 0.001603 | 12.577924 | 121.839442 | 12.582741 | 5F
5F | 150m15 - cold formed purlin :5,SHE-13.STEEL.dgn,Design Model:123917 | 2.50563 | 0.000458 | 1.53595 | 1.53686 | 0.0111 | 0.001146 | 8.995199 | 87.134415 | 8.998644 | 5F
5F | 150m15 - cold formed purlin :5,SHE-13.STEEL.dgn,Design Model:123919 | 2.50563 | 0.000458 | 1.53595 | 1.53686 | 0.0111 | 0.001146 | 8.995199 | 87.134415 | 8.998644 | 5F
5F | 150m15 - cold formed purlin :5,SHE-13.STEEL.dgn,Design Model:123921 | 2.50563 | 0.000458 | 1.53595 | 1.53686 | 0.0111 | 0.001146 | 8.995199 | 87.134415 | 8.998644 | 5F
5F | 150m15 - cold formed purlin :5,SHE-13.STEEL.dgn,Design Model:123923 | 2.50563 | 0.000458 | 1.53595 | 1.53686 | 0.0111 | 0.001146 | 8.995199 | 87.134415 | 8.998644 | 5F
5F | 150m15 - cold formed purlin :5,SHE-13.STEEL.dgn,Design Model:123925 | 2.50563 | 0.000458 | 1.53595 | 1.53686 | 0.0111 | 0.001146 | 8.995199 | 87.134415 | 8.998644 | 5F
5F | 150m15 - cold formed purlin :5,SHE-13.STEEL.dgn,Design Model:123927 | 2.50563 | 0.000458 | 1.53595 | 1.53686 | 0.0111 | 0.001146 | 8.995199 | 87.134415 | 8.998644 | 5F
5F | 150m15 - cold formed purlin :5,SHE-13.STEEL.dgn,Design Model:123929 | 2.50563 | 0.000458 | 1.53595 | 1.53686 | 0.0111 | 0.001146 | 8.995199 | 87.134415 | 8.998644 | 5F
5F | 150m15 - cold formed purlin :5,SHE-13.STEEL.dgn,Design Model:123931 | 2.50563 | 0.000458 | 1.53595 | 1.53686 | 0.0111 | 0.001146 | 8.995199 | 87.134415 | 8.998644 | 5F
5F | 150m15 - cold formed purlin :5,SHE-13.STEEL.dgn,Design Model:123933 | 2.50563 | 0.000458 | 1.53595 | 1.53686 | 0.0111 | 0.001146 | 8.995199 | 87.134415 | 8.998644 | 5F
5F | 150m15 - cold formed purlin :5,SHE-13.STEEL.dgn,Design Model:123935 | 1.9564 | 0.000457 | 1.19927 | 1.20019 | 0.008667 | 0.000895 | 7.023476 | 68.034788 | 7.026166 | 5F
5F | 150m15 - cold formed purlin :5,SHE-13.STEEL.dgn,Design Model:123937 | 1.9564 | 0.000457 | 1.19927 | 1.20019 | 0.008667 | 0.000895 | 7.023476 | 68.034788 | 7.026166 | 5F
5F | 150m15 - cold formed purlin :5,SHE-13.STEEL.dgn,Design Model:123939 | 1.9564 | 0.000457 | 1.19927 | 1.20019 | 0.008667 | 0.000895 | 7.023476 | 68.034788 | 7.026166 | 5F
5F | 150m15 - cold formed purlin :5,SHE-13.STEEL.dgn,Design Model:123941 | 1.9564 | 0.000457 | 1.19927 | 1.20019 | 0.008667 | 0.000895 | 7.023476 | 68.034788 | 7.026166 | 5F
5F | 150m15 - cold formed purlin :5,SHE-13.STEEL.dgn,Design Model:123943 | 1.9564 | 0.000457 | 1.19927 | 1.20019 | 0.008667 | 0.000895 | 7.023476 | 68.034788 | 7.026166 | 5F
5F | 150m15 - cold formed purlin :5,SHE-13.STEEL.dgn,Design Model:123945 | 1.9564 | 0.000457 | 1.19927 | 1.20019 | 0.008667 | 0.000895 | 7.023476 | 68.034788 | 7.026166 | 5F
5F | 150m15 - cold formed purlin :5,SHE-13.STEEL.dgn,Design Model:123947 | 1.9564 | 0.000457 | 1.19927 | 1.20019 | 0.008667 | 0.000895 | 7.023476 | 68.034788 | 7.026166 | 5F
5F | 150m15 - cold formed purlin :5,SHE-13.STEEL.dgn,Design Model:123949 | 1.9564 | 0.000457 | 1.19927 | 1.20019 | 0.008667 | 0.000895 | 7.023476 | 68.034788 | 7.026166 | 5F
5F | 150m15 - cold formed purlin :5,SHE-13.STEEL.dgn,Design Model:123951 | 1.9564 | 0.000457 | 1.19927 | 1.20019 | 0.008667 | 0.000895 | 7.023476 | 68.034788 | 7.026166 | 5F
5F | 150m15 - cold formed purlin :5,SHE-13.STEEL.dgn,Design Model:123953 | 1.9564 | 0.000457 | 1.19927 | 1.20019 | 0.008667 | 0.000895 | 7.023476 | 68.034788 | 7.026166 | 5F
5F | 150m15 - cold formed purlin :5,SHE-13.STEEL.dgn,Design Model:123955 | 1.9564 | 0.000457 | 1.19927 | 1.20019 | 0.008667 | 0.000895 | 7.023476 | 68.034788 | 7.026166 | 5F
5F | 150m15 - cold formed purlin :5,SHE-13.STEEL.dgn,Design Model:123957 | 1.9564 | 0.000457 | 1.19927 | 1.20019 | 0.008667 | 0.000895 | 7.023476 | 68.034788 | 7.026166 | 5F
5F | 150m15 - cold formed purlin :5,SHE-13.STEEL.dgn,Design Model:123959 | 1.9564 | 0.000457 | 1.19927 | 1.20019 | 0.008667 | 0.000895 | 7.023476 | 68.034788 | 7.026166 | 5F
5F | 150m15 - cold formed purlin :5,SHE-13.STEEL.dgn,Design Model:123961 | 1.9564 | 0.000457 | 1.19927 | 1.20019 | 0.008667 | 0.000895 | 7.023476 | 68.034788 | 7.026166 | 5F
5F | 150m15 - cold formed purlin :5,SHE-13.STEEL.dgn,Design Model:123963 | 1.9564 | 0.000457 | 1.19927 | 1.20019 | 0.008667 | 0.000895 | 7.023476 | 68.034788 | 7.026166 | 5F
5F | 150m15 - cold formed purlin :5,SHE-13.STEEL.dgn,Design Model:123965 | 1.9564 | 0.000457 | 1.19927 | 1.20019 | 0.008667 | 0.000895 | 7.023476 | 68.034788 | 7.026166 | 5F
5F | 150m15 - cold formed purlin :5,SHE-13.STEEL.dgn,Design Model:123967 | 1.9564 | 0.000457 | 1.19927 | 1.20019 | 0.008667 | 0.000895 | 7.023476 | 68.034788 | 7.026166 | 5F
5F | 150m15 - cold formed purlin :5,SHE-13.STEEL.dgn,Design Model:123969 | 1.9564 | 0.000457 | 1.19927 | 1.20019 | 0.008667 | 0.000895 | 7.023476 | 68.034788 | 7.026166 | 5F
5F | 150m15 - cold formed purlin :5,SHE-13.STEEL.dgn,Design Model:123971 | 1.9564 | 0.000457 | 1.19927 | 1.20019 | 0.008667 | 0.000895 | 7.023476 | 68.034788 | 7.026166 | 5F
5F | 150m15 - cold formed purlin :5,SHE-13.STEEL.dgn,Design Model:123973 | 1.9564 | 0.000457 | 1.19927 | 1.20019 | 0.008667 | 0.000895 | 7.023476 | 68.034788 | 7.026166 | 5F
5F | 150m15 - cold formed purlin :5,SHE-13.STEEL.dgn,Design Model:123975 | 1.9564 | 0.000457 | 1.19927 | 1.20019 | 0.008667 | 0.000895 | 7.023476 | 68.034788 | 7.026166 | 5F
5F | 150m15 - cold formed purlin :5,SHE-13.STEEL.dgn,Design Model:123977 | 1.9564 | 0.000457 | 1.19927 | 1.20019 | 0.008667 | 0.000895 | 7.023476 | 68.034788 | 7.026166 | 5F
5F | 150m15 - cold formed purlin :5,SHE-13.STEEL.dgn,Design Model:123979 | 1.9564 | 0.000457 | 1.19927 | 1.20019 | 0.008667 | 0.000895 | 7.023476 | 68.034788 | 7.026166 | 5F
5F | 150m15 - cold formed purlin :5,SHE-13.STEEL.dgn,Design Model:123981 | 1.9564 | 0.000457 | 1.19927 | 1.20019 | 0.008667 | 0.000895 | 7.023476 | 68.034788 | 7.026166 | 5F
5F | 150m15 - cold formed purlin :5,SHE-13.STEEL.dgn,Design Model:123983 | 1.9564 | 0.000457 | 1.19927 | 1.20019 | 0.008667 | 0.000895 | 7.023476 | 68.034788 | 7.026166 | 5F
5F | 150m15 - cold formed purlin :5,SHE-13.STEEL.dgn,Design Model:123985 | 1.9564 | 0.000457 | 1.19927 | 1.20019 | 0.008667 | 0.000895 | 7.023476 | 68.034788 | 7.026166 | 5F
5F | 150m15 - cold formed purlin :5,SHE-13.STEEL.dgn,Design Model:123987 | 1.9564 | 0.000457 | 1.19927 | 1.20019 | 0.008667 | 0.000895 | 7.023476 | 68.034788 | 7.026166 | 5F
5F | 150m15 - cold formed purlin :5,SHE-13.STEEL.dgn,Design Model:123989 | 1.9564 | 0.000457 | 1.19927 | 1.20019 | 0.008667 | 0.000895 | 7.023476 | 68.034788 | 7.026166 | 5F
5F | 150m15 - cold formed purlin :5,SHE-13.STEEL.dgn,Design Model:123991 | 1.9564 | 0.000457 | 1.19927 | 1.20019 | 0.008667 | 0.000895 | 7.023476 | 68.034788 | 7.026166 | 5F
5F | 150m15 - cold formed purlin :5,SHE-13.STEEL.dgn,Design Model:123993 | 1.9564 | 0.000457 | 1.19927 | 1.20019 | 0.008667 | 0.000895 | 7.023476 | 68.034788 | 7.026166 | 5F
5F | 150m15 - cold formed purlin :5,SHE-13.STEEL.dgn,Design Model:123995 | 1.9564 | 0.000457 | 1.19927 | 1.20019 | 0.008667 | 0.000895 | 7.023476 | 68.034788 | 7.026166 | 5F
5F | 150m15 - cold formed purlin :5,SHE-13.STEEL.dgn,Design Model:123997 | 1.9564 | 0.000457 | 1.19927 | 1.20019 | 0.008667 | 0.000895 | 7.023476 | 68.034788 | 7.026166 | 5F
5F | 150m15 - cold formed purlin :5,SHE-13.STEEL.dgn,Design Model:123999 | 1.9564 | 0.000457 | 1.19927 | 1.20019 | 0.008667 | 0.000895 | 7.023476 | 68.034788 | 7.026166 | 5F
5F | 150m15 - cold formed purlin :5,SHE-13.STEEL.dgn,Design Model:124001 | 1.9564 | 0.000457 | 1.19927 | 1.20019 | 0.008667 | 0.000895 | 7.023476 | 68.034788 | 7.026166 | 5F
5F | 150m15 - cold formed purlin :5,SHE-13.STEEL.dgn,Design Model:124003 | 1.9564 | 0.000457 | 1.19927 | 1.20019 | 0.008667 | 0.000895 | 7.023476 | 68.034788 | 7.026166 | 5F
5F | 150m15 - cold formed purlin :5,SHE-13.STEEL.dgn,Design Model:124005 | 1.9564 | 0.000457 | 1.19927 | 1.20019 | 0.008667 | 0.000895 | 7.023476 | 68.034788 | 7.026166 | 5F
5F | 150m15 - cold formed purlin :5,SHE-13.STEEL.dgn,Design Model:124007 | 1.9564 | 0.000457 | 1.19927 | 1.20019 | 0.008667 | 0.000895 | 7.023476 | 68.034788 | 7.026166 | 5F
5F | 150m15 - cold formed purlin :5,SHE-13.STEEL.dgn,Design Model:124009 | 1.9564 | 0.000457 | 1.19927 | 1.20019 | 0.008667 | 0.000895 | 7.023476 | 68.034788 | 7.026166 | 5F
5F | 150m15 - cold formed purlin :5,SHE-13.STEEL.dgn,Design Model:124011 | 3.4636 | 0.000457 | 2.12319 | 2.1241 | 0.015344 | 0.001585 | 12.434324 | 120.448422 | 12.439086 | 5F
5F | 150m15 - cold formed purlin :5,SHE-13.STEEL.dgn,Design Model:124013 | 3.4636 | 0.000457 | 2.12319 | 2.1241 | 0.015344 | 0.001585 | 12.434324 | 120.448422 | 12.439086 | 5F
5F | 150m15 - cold formed purlin :5,SHE-13.STEEL.dgn,Design Model:124015 | 3.4636 | 0.000457 | 2.12319 | 2.1241 | 0.015344 | 0.001585 | 12.434324 | 120.448422 | 12.439086 | 5F
5F | 150m15 - cold formed purlin :5,SHE-13.STEEL.dgn,Design Model:124017 | 3.4636 | 0.000457 | 2.12319 | 2.1241 | 0.015344 | 0.001585 | 12.434324 | 120.448422 | 12.439086 | 5F
5F | 150m15 - cold formed purlin :5,SHE-13.STEEL.dgn,Design Model:124019 | 3.4636 | 0.000457 | 2.12319 | 2.1241 | 0.015344 | 0.001585 | 12.434324 | 120.448422 | 12.439086 | 5F
5F | 150m15 - cold formed purlin :5,SHE-13.STEEL.dgn,Design Model:124021 | 3.4636 | 0.000457 | 2.12319 | 2.1241 | 0.015344 | 0.001585 | 12.434324 | 120.448422 | 12.439086 | 5F
5F | 150m15 - cold formed purlin :5,SHE-13.STEEL.dgn,Design Model:124023 | 3.4636 | 0.000457 | 2.12319 | 2.1241 | 0.015344 | 0.001585 | 12.434324 | 120.448422 | 12.439086 | 5F
5F | 150m15 - cold formed purlin :5,SHE-13.STEEL.dgn,Design Model:124025 | 3.4636 | 0.000457 | 2.12319 | 2.1241 | 0.015344 | 0.001585 | 12.434324 | 120.448422 | 12.439086 | 5F
5F | 150m15 - cold formed purlin :5,SHE-13.STEEL.dgn,Design Model:124027 | 3.4636 | 0.000457 | 2.12319 | 2.1241 | 0.015344 | 0.001585 | 12.434324 | 120.448422 | 12.439086 | 5F
5F | 150m15 - cold formed purlin :5,SHE-13.STEEL.dgn,Design Model:124029 | 3.4636 | 0.000457 | 2.12319 | 2.1241 | 0.015344 | 0.001585 | 12.434324 | 120.448422 | 12.439086 | 5F
5F | 150m15 - cold formed purlin :5,SHE-13.STEEL.dgn,Design Model:124031 | 3.4636 | 0.000457 | 2.12319 | 2.1241 | 0.015344 | 0.001585 | 12.434324 | 120.448422 | 12.439086 | 5F
5F | 150m15 - cold formed purlin :5,SHE-13.STEEL.dgn,Design Model:124033 | 2.50563 | 0.000458 | 1.53595 | 1.53686 | 0.0111 | 0.001146 | 8.995199 | 87.134415 | 8.998644 | 5F
5F | 150m15 - cold formed purlin :5,SHE-13.STEEL.dgn,Design Model:124035 | 2.50563 | 0.000458 | 1.53595 | 1.53686 | 0.0111 | 0.001146 | 8.995199 | 87.134415 | 8.998644 | 5F
5F | 150m15 - cold formed purlin :5,SHE-13.STEEL.dgn,Design Model:124037 | 2.50563 | 0.000458 | 1.53595 | 1.53686 | 0.0111 | 0.001146 | 8.995199 | 87.134415 | 8.998644 | 5F
5F | 150m15 - cold formed purlin :5,SHE-13.STEEL.dgn,Design Model:124039 | 2.50563 | 0.000458 | 1.53595 | 1.53686 | 0.0111 | 0.001146 | 8.995199 | 87.134415 | 8.998644 | 5F
5F | 150m15 - cold formed purlin :5,SHE-13.STEEL.dgn,Design Model:124041 | 2.50563 | 0.000458 | 1.53595 | 1.53686 | 0.0111 | 0.001146 | 8.995199 | 87.134415 | 8.998644 | 5F
5F | 150m15 - cold formed purlin :5,SHE-13.STEEL.dgn,Design Model:124043 | 2.50563 | 0.000458 | 1.53595 | 1.53686 | 0.0111 | 0.001146 | 8.995199 | 87.134415 | 8.998644 | 5F
5F | 150m15 - cold formed purlin :5,SHE-13.STEEL.dgn,Design Model:124045 | 2.50563 | 0.000458 | 1.53595 | 1.53686 | 0.0111 | 0.001146 | 8.995199 | 87.134415 | 8.998644 | 5F
5F | 150m15 - cold formed purlin :5,SHE-13.STEEL.dgn,Design Model:124047 | 2.50563 | 0.000458 | 1.53595 | 1.53686 | 0.0111 | 0.001146 | 8.995199 | 87.134415 | 8.998644 | 5F
5F | 150m15 - cold formed purlin :5,SHE-13.STEEL.dgn,Design Model:124049 | 2.50563 | 0.000458 | 1.53595 | 1.53686 | 0.0111 | 0.001146 | 8.995199 | 87.134415 | 8.998644 | 5F
5F | 150m15 - cold formed purlin :5,SHE-13.STEEL.dgn,Design Model:124051 | 2.5364 | 0.000457 | 1.55481 | 1.55573 | 0.011236 | 0.00116 | 9.105673 | 88.204546 | 9.109160 | 5F
5F | 150m15 - cold formed purlin :5,SHE-13.STEEL.dgn,Design Model:124053 | 2.5364 | 0.000457 | 1.55481 | 1.55573 | 0.011236 | 0.00116 | 9.105673 | 88.204546 | 9.109160 | 5F
5F | 150m15 - cold formed purlin :5,SHE-13.STEEL.dgn,Design Model:124055 | 2.5364 | 0.000457 | 1.55481 | 1.55573 | 0.011236 | 0.00116 | 9.105673 | 88.204546 | 9.109160 | 5F
5F | 150m15 - cold formed purlin :5,SHE-13.STEEL.dgn,Design Model:124057 | 2.5364 | 0.000457 | 1.55481 | 1.55573 | 0.011236 | 0.00116 | 9.105673 | 88.204546 | 9.109160 | 5F
5F | 150m15 - cold formed purlin :5,SHE-13.STEEL.dgn,Design Model:124059 | 2.5364 | 0.000457 | 1.55481 | 1.55573 | 0.011236 | 0.00116 | 9.105673 | 88.204546 | 9.109160 | 5F
5F | 150m15 - cold formed purlin :5,SHE-13.STEEL.dgn,Design Model:124061 | 2.5364 | 0.000457 | 1.55481 | 1.55573 | 0.011236 | 0.00116 | 9.105673 | 88.204546 | 9.109160 | 5F
5F | 150m15 - cold formed purlin :5,SHE-13.STEEL.dgn,Design Model:124063 | 2.5364 | 0.000457 | 1.55481 | 1.55573 | 0.011236 | 0.00116 | 9.105673 | 88.204546 | 9.109160 | 5F
5F | 150m15 - cold formed purlin :5,SHE-13.STEEL.dgn,Design Model:124065 | 2.5364 | 0.000457 | 1.55481 | 1.55573 | 0.011236 | 0.00116 | 9.105673 | 88.204546 | 9.109160 | 5F
5F | 150m15 - cold formed purlin :5,SHE-13.STEEL.dgn,Design Model:124067 | 2.5364 | 0.000457 | 1.55481 | 1.55573 | 0.011236 | 0.00116 | 9.105673 | 88.204546 | 9.109160 | 5F
5F | 150m15 - cold formed purlin :5,SHE-13.STEEL.dgn,Design Model:124069 | 2.5364 | 0.000457 | 1.55481 | 1.55573 | 0.011236 | 0.00116 | 9.105673 | 88.204546 | 9.109160 | 5F
5F | 150m15 - cold formed purlin :5,SHE-13.STEEL.dgn,Design Model:124071 | 3.305 | 0.000457 | 2.02596 | 2.02688 | 0.014641 | 0.001512 | 11.864950 | 114.933028 | 11.869494 | 5F
5F | 150m15 - cold formed purlin :5,SHE-13.STEEL.dgn,Design Model:124073 | 3.305 | 0.000457 | 2.02596 | 2.02688 | 0.014641 | 0.001512 | 11.864950 | 114.933028 | 11.869494 | 5F
5F | 150m15 - cold formed purlin :5,SHE-13.STEEL.dgn,Design Model:124075 | 3.305 | 0.000457 | 2.02596 | 2.02688 | 0.014641 | 0.001512 | 11.864950 | 114.933028 | 11.869494 | 5F
5F | 150m15 - cold formed purlin :5,SHE-13.STEEL.dgn,Design Model:124077 | 3.305 | 0.000457 | 2.02596 | 2.02688 | 0.014641 | 0.001512 | 11.864950 | 114.933028 | 11.869494 | 5F
5F | 150m15 - cold formed purlin :5,SHE-13.STEEL.dgn,Design Model:124079 | 3.305 | 0.000457 | 2.02596 | 2.02688 | 0.014641 | 0.001512 | 11.864950 | 114.933028 | 11.869494 | 5F
5F | 150m15 - cold formed purlin :5,SHE-13.STEEL.dgn,Design Model:124081 | 3.305 | 0.000457 | 2.02596 | 2.02688 | 0.014641 | 0.001512 | 11.864950 | 114.933028 | 11.869494 | 5F
5F | 150m15 - cold formed purlin :5,SHE-13.STEEL.dgn,Design Model:124083 | 3.5036 | 0.000457 | 2.14771 | 2.14862 | 0.015521 | 0.001603 | 12.577924 | 121.839442 | 12.582741 | 5F
5F | 150m15 - cold formed purlin :5,SHE-13.STEEL.dgn,Design Model:124085 | 3.5036 | 0.000457 | 2.14771 | 2.14862 | 0.015521 | 0.001603 | 12.577924 | 121.839442 | 12.582741 | 5F
5F | 150m15 - cold formed purlin :5,SHE-13.STEEL.dgn,Design Model:124087 | 3.5036 | 0.000457 | 2.14771 | 2.14862 | 0.015521 | 0.001603 | 12.577924 | 121.839442 | 12.582741 | 5F
5F | 150m15 - cold formed purlin :5,SHE-13.STEEL.dgn,Design Model:124089 | 3.5036 | 0.000457 | 2.14771 | 2.14862 | 0.015521 | 0.001603 | 12.577924 | 121.839442 | 12.582741 | 5F
5F | 150m15 - cold formed purlin :5,SHE-13.STEEL.dgn,Design Model:124091 | 3.5036 | 0.000457 | 2.14771 | 2.14862 | 0.015521 | 0.001603 | 12.577924 | 121.839442 | 12.582741 | 5F
5F | 150m15 - cold formed purlin :5,SHE-13.STEEL.dgn,Design Model:124093 | 3.5036 | 0.000457 | 2.14771 | 2.14862 | 0.015521 | 0.001603 | 12.577924 | 121.839442 | 12.582741 | 5F
5F | 150m15 - cold formed purlin :5,SHE-13.STEEL.dgn,Design Model:124095 | 3.5036 | 0.000457 | 2.14771 | 2.14862 | 0.015521 | 0.001603 | 12.577924 | 121.839442 | 12.582741 | 5F
5F | 150m15 - cold formed purlin :5,SHE-13.STEEL.dgn,Design Model:124097 | 3.5036 | 0.000457 | 2.14771 | 2.14862 | 0.015521 | 0.001603 | 12.577924 | 121.839442 | 12.582741 | 5F
5F | 150m15 - cold formed purlin :5,SHE-13.STEEL.dgn,Design Model:124099 | 3.5036 | 0.000457 | 2.14771 | 2.14862 | 0.015521 | 0.001603 | 12.577924 | 121.839442 | 12.582741 | 5F
5F | 150m15 - cold formed purlin :5,SHE-13.STEEL.dgn,Design Model:124101 | 3.5036 | 0.000457 | 2.14771 | 2.14862 | 0.015521 | 0.001603 | 12.577924 | 121.839442 | 12.582741 | 5F
5F | 150m15 - cold formed purlin :5,SHE-13.STEEL.dgn,Design Model:124103 | 3.5036 | 0.000457 | 2.14771 | 2.14862 | 0.015521 | 0.001603 | 12.577924 | 121.839442 | 12.582741 | 5F
5F | 150m15 - cold formed purlin :5,SHE-13.STEEL.dgn,Design Model:124105 | 1.9564 | 0.000457 | 1.19927 | 1.20019 | 0.008667 | 0.000895 | 7.023476 | 68.034788 | 7.026166 | 5F
5F | 150m15 - cold formed purlin :5,SHE-13.STEEL.dgn,Design Model:124107 | 1.9564 | 0.000457 | 1.19927 | 1.20019 | 0.008667 | 0.000895 | 7.023476 | 68.034788 | 7.026166 | 5F
5F | 150m15 - cold formed purlin :5,SHE-13.STEEL.dgn,Design Model:124109 | 1.9564 | 0.000457 | 1.19927 | 1.20019 | 0.008667 | 0.000895 | 7.023476 | 68.034788 | 7.026166 | 5F
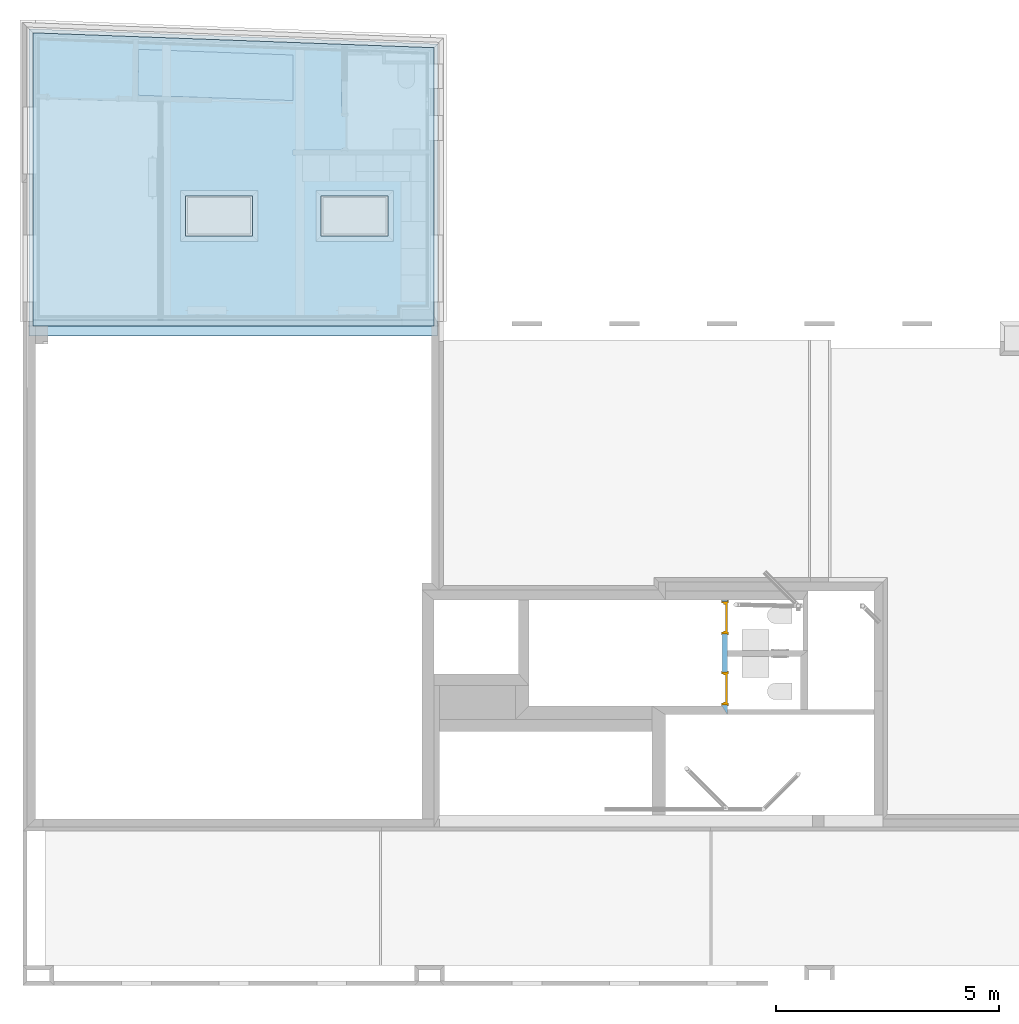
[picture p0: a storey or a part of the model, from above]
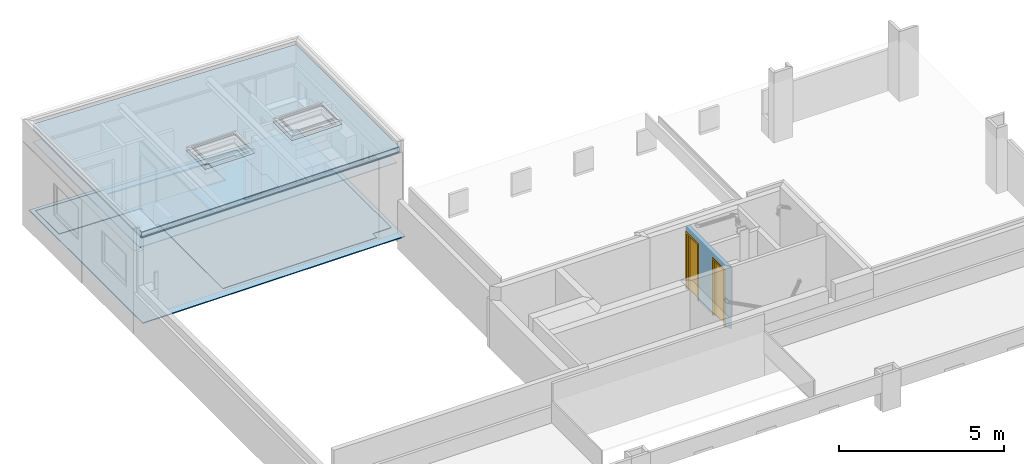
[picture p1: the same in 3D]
Properties of the parts of a building model (IFC2X3), part 3 of 16

# IfcBeam: SHE_A-Beams-Steel-Purlin_150m15 (639)
Name | Description | Length (m) | Area | Cross-sectional Modeled (m2) | Area | Side Surfaces Modeled (Gross) (m2) | Area | All Surfaces Modeled (Net) (m2) | Volume (Gross) (m3) = Volume (Net) (m3) | Volume (Gross Modeled) (m3) = Volume (Net Modeled) (m3) | Length x Unit Weight | Volume (Gross) x Density = Volume (Net) x Density | Volume (Gross Modeled) x Density = Volume (Net Modeled) x Density | ID | Number
5F | 150m15 - cold formed purlin :5,SHE-13.STEEL.dgn,Design Model:124111 | 1.9564 | 0.000457 | 1.19927 | 1.20019 | 0.008667 | 0.000895 | 7.023476 | 68.034788 | 7.026166 | 5F
5F | 150m15 - cold formed purlin :5,SHE-13.STEEL.dgn,Design Model:124113 | 1.9564 | 0.000457 | 1.19927 | 1.20019 | 0.008667 | 0.000895 | 7.023476 | 68.034788 | 7.026166 | 5F
5F | 150m15 - cold formed purlin :5,SHE-13.STEEL.dgn,Design Model:124115 | 1.9564 | 0.000457 | 1.19927 | 1.20019 | 0.008667 | 0.000895 | 7.023476 | 68.034788 | 7.026166 | 5F
5F | 150m15 - cold formed purlin :5,SHE-13.STEEL.dgn,Design Model:124117 | 1.9564 | 0.000457 | 1.19927 | 1.20019 | 0.008667 | 0.000895 | 7.023476 | 68.034788 | 7.026166 | 5F
5F | 150m15 - cold formed purlin :5,SHE-13.STEEL.dgn,Design Model:124119 | 1.9564 | 0.000457 | 1.19927 | 1.20019 | 0.008667 | 0.000895 | 7.023476 | 68.034788 | 7.026166 | 5F
5F | 150m15 - cold formed purlin :5,SHE-13.STEEL.dgn,Design Model:124121 | 1.9564 | 0.000457 | 1.19927 | 1.20019 | 0.008667 | 0.000895 | 7.023476 | 68.034788 | 7.026166 | 5F
5F | 150m15 - cold formed purlin :5,SHE-13.STEEL.dgn,Design Model:124123 | 2.50557 | 0.000458 | 1.53592 | 1.53683 | 0.0111 | 0.001146 | 8.995009 | 87.132568 | 8.998454 | 5F
5F | 150m15 - cold formed purlin :5,SHE-13.STEEL.dgn,Design Model:124125 | 2.50557 | 0.000458 | 1.53592 | 1.53683 | 0.0111 | 0.001146 | 8.995009 | 87.132568 | 8.998454 | 5F
5F | 150m15 - cold formed purlin :5,SHE-13.STEEL.dgn,Design Model:124127 | 2.50557 | 0.000458 | 1.53592 | 1.53683 | 0.0111 | 0.001146 | 8.995009 | 87.132568 | 8.998454 | 5F
5F | 150m15 - cold formed purlin :5,SHE-13.STEEL.dgn,Design Model:124129 | 2.50557 | 0.000458 | 1.53592 | 1.53683 | 0.0111 | 0.001146 | 8.995009 | 87.132568 | 8.998454 | 5F
5F | 150m15 - cold formed purlin :5,SHE-13.STEEL.dgn,Design Model:124131 | 2.50557 | 0.000458 | 1.53592 | 1.53683 | 0.0111 | 0.001146 | 8.995009 | 87.132568 | 8.998454 | 5F
5F | 150m15 - cold formed purlin :5,SHE-13.STEEL.dgn,Design Model:124133 | 2.50557 | 0.000458 | 1.53592 | 1.53683 | 0.0111 | 0.001146 | 8.995009 | 87.132568 | 8.998454 | 5F
5F | 150m15 - cold formed purlin :5,SHE-13.STEEL.dgn,Design Model:124135 | 2.50557 | 0.000458 | 1.53592 | 1.53683 | 0.0111 | 0.001146 | 8.995009 | 87.132568 | 8.998454 | 5F
5F | 150m15 - cold formed purlin :5,SHE-13.STEEL.dgn,Design Model:124137 | 2.50557 | 0.000458 | 1.53592 | 1.53683 | 0.0111 | 0.001146 | 8.995009 | 87.132568 | 8.998454 | 5F
5F | 150m15 - cold formed purlin :5,SHE-13.STEEL.dgn,Design Model:124139 | 2.50557 | 0.000458 | 1.53592 | 1.53683 | 0.0111 | 0.001146 | 8.995009 | 87.132568 | 8.998454 | 5F
5F | 150m15 - cold formed purlin :5,SHE-13.STEEL.dgn,Design Model:124141 | 1.9564 | 0.000457 | 1.19927 | 1.20019 | 0.008667 | 0.000895 | 7.023476 | 68.034788 | 7.026166 | 5F
5F | 150m15 - cold formed purlin :5,SHE-13.STEEL.dgn,Design Model:124143 | 1.9564 | 0.000457 | 1.19927 | 1.20019 | 0.008667 | 0.000895 | 7.023476 | 68.034788 | 7.026166 | 5F
5F | 150m15 - cold formed purlin :5,SHE-13.STEEL.dgn,Design Model:124145 | 1.9564 | 0.000457 | 1.19927 | 1.20019 | 0.008667 | 0.000895 | 7.023476 | 68.034788 | 7.026166 | 5F
5F | 150m15 - cold formed purlin :5,SHE-13.STEEL.dgn,Design Model:124147 | 1.9564 | 0.000457 | 1.19927 | 1.20019 | 0.008667 | 0.000895 | 7.023476 | 68.034788 | 7.026166 | 5F
5F | 150m15 - cold formed purlin :5,SHE-13.STEEL.dgn,Design Model:124149 | 1.9564 | 0.000457 | 1.19927 | 1.20019 | 0.008667 | 0.000895 | 7.023476 | 68.034788 | 7.026166 | 5F
5F | 150m15 - cold formed purlin :5,SHE-13.STEEL.dgn,Design Model:124151 | 1.9564 | 0.000457 | 1.19927 | 1.20019 | 0.008667 | 0.000895 | 7.023476 | 68.034788 | 7.026166 | 5F
5F | 150m15 - cold formed purlin :5,SHE-13.STEEL.dgn,Design Model:124153 | 1.9564 | 0.000457 | 1.19927 | 1.20019 | 0.008667 | 0.000895 | 7.023476 | 68.034788 | 7.026166 | 5F
5F | 150m15 - cold formed purlin :5,SHE-13.STEEL.dgn,Design Model:124155 | 1.9564 | 0.000457 | 1.19927 | 1.20019 | 0.008667 | 0.000895 | 7.023476 | 68.034788 | 7.026166 | 5F
5F | 150m15 - cold formed purlin :5,SHE-13.STEEL.dgn,Design Model:124157 | 1.9564 | 0.000457 | 1.19927 | 1.20019 | 0.008667 | 0.000895 | 7.023476 | 68.034788 | 7.026166 | 5F
5F | 150m15 - cold formed purlin :5,SHE-13.STEEL.dgn,Design Model:124159 | 1.9564 | 0.000457 | 1.19927 | 1.20019 | 0.008667 | 0.000895 | 7.023476 | 68.034788 | 7.026166 | 5F
5F | 150m15 - cold formed purlin :5,SHE-13.STEEL.dgn,Design Model:124161 | 1.9564 | 0.000457 | 1.19927 | 1.20019 | 0.008667 | 0.000895 | 7.023476 | 68.034788 | 7.026166 | 5F
5F | 150m15 - cold formed purlin :5,SHE-13.STEEL.dgn,Design Model:124163 | 1.9564 | 0.000457 | 1.19927 | 1.20019 | 0.008667 | 0.000895 | 7.023476 | 68.034788 | 7.026166 | 5F
5F | 150m15 - cold formed purlin :5,SHE-13.STEEL.dgn,Design Model:124165 | 1.9564 | 0.000457 | 1.19927 | 1.20019 | 0.008667 | 0.000895 | 7.023476 | 68.034788 | 7.026166 | 5F
5F | 150m15 - cold formed purlin :5,SHE-13.STEEL.dgn,Design Model:124167 | 1.9564 | 0.000457 | 1.19927 | 1.20019 | 0.008667 | 0.000895 | 7.023476 | 68.034788 | 7.026166 | 5F
5F | 150m15 - cold formed purlin :5,SHE-13.STEEL.dgn,Design Model:124169 | 1.9564 | 0.000457 | 1.19927 | 1.20019 | 0.008667 | 0.000895 | 7.023476 | 68.034788 | 7.026166 | 5F
5F | 150m15 - cold formed purlin :5,SHE-13.STEEL.dgn,Design Model:124171 | 1.9564 | 0.000457 | 1.19927 | 1.20019 | 0.008667 | 0.000895 | 7.023476 | 68.034788 | 7.026166 | 5F
5F | 150m15 - cold formed purlin :5,SHE-13.STEEL.dgn,Design Model:124173 | 1.9564 | 0.000457 | 1.19927 | 1.20019 | 0.008667 | 0.000895 | 7.023476 | 68.034788 | 7.026166 | 5F
5F | 150m15 - cold formed purlin :5,SHE-13.STEEL.dgn,Design Model:124175 | 1.9564 | 0.000457 | 1.19927 | 1.20019 | 0.008667 | 0.000895 | 7.023476 | 68.034788 | 7.026166 | 5F
5F | 150m15 - cold formed purlin :5,SHE-13.STEEL.dgn,Design Model:124177 | 1.9564 | 0.000457 | 1.19927 | 1.20019 | 0.008667 | 0.000895 | 7.023476 | 68.034788 | 7.026166 | 5F
5F | 150m15 - cold formed purlin :5,SHE-13.STEEL.dgn,Design Model:124179 | 1.9564 | 0.000457 | 1.19927 | 1.20019 | 0.008667 | 0.000895 | 7.023476 | 68.034788 | 7.026166 | 5F
5F | 150m15 - cold formed purlin :5,SHE-13.STEEL.dgn,Design Model:124181 | 1.9564 | 0.000457 | 1.19927 | 1.20019 | 0.008667 | 0.000895 | 7.023476 | 68.034788 | 7.026166 | 5F
5F | 150m15 - cold formed purlin :5,SHE-13.STEEL.dgn,Design Model:124183 | 1.9564 | 0.000457 | 1.19927 | 1.20019 | 0.008667 | 0.000895 | 7.023476 | 68.034788 | 7.026166 | 5F
5F | 150m15 - cold formed purlin :5,SHE-13.STEEL.dgn,Design Model:124185 | 1.9564 | 0.000457 | 1.19927 | 1.20019 | 0.008667 | 0.000895 | 7.023476 | 68.034788 | 7.026166 | 5F
5F | 150m15 - cold formed purlin :5,SHE-13.STEEL.dgn,Design Model:124187 | 1.9564 | 0.000457 | 1.19927 | 1.20019 | 0.008667 | 0.000895 | 7.023476 | 68.034788 | 7.026166 | 5F
5F | 150m15 - cold formed purlin :5,SHE-13.STEEL.dgn,Design Model:124189 | 1.9564 | 0.000457 | 1.19927 | 1.20019 | 0.008667 | 0.000895 | 7.023476 | 68.034788 | 7.026166 | 5F
5F | 150m15 - cold formed purlin :5,SHE-13.STEEL.dgn,Design Model:124191 | 1.9564 | 0.000457 | 1.19927 | 1.20019 | 0.008667 | 0.000895 | 7.023476 | 68.034788 | 7.026166 | 5F
5F | 150m15 - cold formed purlin :5,SHE-13.STEEL.dgn,Design Model:124193 | 1.9564 | 0.000457 | 1.19927 | 1.20019 | 0.008667 | 0.000895 | 7.023476 | 68.034788 | 7.026166 | 5F
5F | 150m15 - cold formed purlin :5,SHE-13.STEEL.dgn,Design Model:124195 | 1.9564 | 0.000457 | 1.19927 | 1.20019 | 0.008667 | 0.000895 | 7.023476 | 68.034788 | 7.026166 | 5F
5F | 150m15 - cold formed purlin :5,SHE-13.STEEL.dgn,Design Model:124197 | 1.9564 | 0.000457 | 1.19927 | 1.20019 | 0.008667 | 0.000895 | 7.023476 | 68.034788 | 7.026166 | 5F
5F | 150m15 - cold formed purlin :5,SHE-13.STEEL.dgn,Design Model:124199 | 2.50557 | 0.000458 | 1.53592 | 1.53683 | 0.0111 | 0.001146 | 8.995009 | 87.132568 | 8.998454 | 5F
5F | 150m15 - cold formed purlin :5,SHE-13.STEEL.dgn,Design Model:124201 | 2.50557 | 0.000458 | 1.53592 | 1.53683 | 0.0111 | 0.001146 | 8.995009 | 87.132568 | 8.998454 | 5F
5F | 150m15 - cold formed purlin :5,SHE-13.STEEL.dgn,Design Model:124203 | 2.50557 | 0.000458 | 1.53592 | 1.53683 | 0.0111 | 0.001146 | 8.995009 | 87.132568 | 8.998454 | 5F
5F | 150m15 - cold formed purlin :5,SHE-13.STEEL.dgn,Design Model:124205 | 2.50557 | 0.000458 | 1.53592 | 1.53683 | 0.0111 | 0.001146 | 8.995009 | 87.132568 | 8.998454 | 5F
5F | 150m15 - cold formed purlin :5,SHE-13.STEEL.dgn,Design Model:124207 | 2.50557 | 0.000458 | 1.53592 | 1.53683 | 0.0111 | 0.001146 | 8.995009 | 87.132568 | 8.998454 | 5F
5F | 150m15 - cold formed purlin :5,SHE-13.STEEL.dgn,Design Model:124209 | 2.50557 | 0.000458 | 1.53592 | 1.53683 | 0.0111 | 0.001146 | 8.995009 | 87.132568 | 8.998454 | 5F
5F | 150m15 - cold formed purlin :5,SHE-13.STEEL.dgn,Design Model:124211 | 2.50557 | 0.000458 | 1.53592 | 1.53683 | 0.0111 | 0.001146 | 8.995009 | 87.132568 | 8.998454 | 5F
5F | 150m15 - cold formed purlin :5,SHE-13.STEEL.dgn,Design Model:124213 | 2.50557 | 0.000458 | 1.53592 | 1.53683 | 0.0111 | 0.001146 | 8.995009 | 87.132568 | 8.998454 | 5F
5F | 150m15 - cold formed purlin :5,SHE-13.STEEL.dgn,Design Model:124215 | 2.50557 | 0.000458 | 1.53592 | 1.53683 | 0.0111 | 0.001146 | 8.995009 | 87.132568 | 8.998454 | 5F
5F | 150m15 - cold formed purlin :5,SHE-13.STEEL.dgn,Design Model:124217 | 2.5364 | 0.000457 | 1.55481 | 1.55573 | 0.011236 | 0.00116 | 9.105679 | 88.204607 | 9.109167 | 5F
5F | 150m15 - cold formed purlin :5,SHE-13.STEEL.dgn,Design Model:124219 | 2.5364 | 0.000457 | 1.55481 | 1.55573 | 0.011236 | 0.00116 | 9.105679 | 88.204607 | 9.109167 | 5F
5F | 150m15 - cold formed purlin :5,SHE-13.STEEL.dgn,Design Model:124221 | 2.5364 | 0.000457 | 1.55481 | 1.55573 | 0.011236 | 0.00116 | 9.105679 | 88.204607 | 9.109167 | 5F
5F | 150m15 - cold formed purlin :5,SHE-13.STEEL.dgn,Design Model:124223 | 2.5364 | 0.000457 | 1.55481 | 1.55573 | 0.011236 | 0.00116 | 9.105679 | 88.204607 | 9.109167 | 5F
5F | 150m15 - cold formed purlin :5,SHE-13.STEEL.dgn,Design Model:124225 | 2.5364 | 0.000457 | 1.55481 | 1.55573 | 0.011236 | 0.00116 | 9.105679 | 88.204607 | 9.109167 | 5F
5F | 150m15 - cold formed purlin :5,SHE-13.STEEL.dgn,Design Model:124227 | 2.5364 | 0.000457 | 1.55481 | 1.55573 | 0.011236 | 0.00116 | 9.105679 | 88.204607 | 9.109167 | 5F
5F | 150m15 - cold formed purlin :5,SHE-13.STEEL.dgn,Design Model:124229 | 2.5364 | 0.000457 | 1.55481 | 1.55573 | 0.011236 | 0.00116 | 9.105679 | 88.204607 | 9.109167 | 5F
5F | 150m15 - cold formed purlin :5,SHE-13.STEEL.dgn,Design Model:124231 | 2.5364 | 0.000457 | 1.55481 | 1.55573 | 0.011236 | 0.00116 | 9.105679 | 88.204607 | 9.109167 | 5F
5F | 150m15 - cold formed purlin :5,SHE-13.STEEL.dgn,Design Model:124233 | 2.5364 | 0.000457 | 1.55481 | 1.55573 | 0.011236 | 0.00116 | 9.105679 | 88.204607 | 9.109167 | 5F
5F | 150m15 - cold formed purlin :5,SHE-13.STEEL.dgn,Design Model:124235 | 2.5364 | 0.000457 | 1.55481 | 1.55573 | 0.011236 | 0.00116 | 9.105679 | 88.204607 | 9.109167 | 5F
5F | 150m15 - cold formed purlin :5,SHE-13.STEEL.dgn,Design Model:124237 | 2.5364 | 0.000457 | 1.55481 | 1.55573 | 0.011236 | 0.00116 | 9.105679 | 88.204607 | 9.109167 | 5F
5F | 150m15 - cold formed purlin :5,SHE-13.STEEL.dgn,Design Model:124239 | 2.5364 | 0.000457 | 1.55481 | 1.55573 | 0.011236 | 0.00116 | 9.105679 | 88.204607 | 9.109167 | 5F
5F | 150m15 - cold formed purlin :5,SHE-13.STEEL.dgn,Design Model:124241 | 2.5364 | 0.000457 | 1.55481 | 1.55573 | 0.011236 | 0.00116 | 9.105679 | 88.204607 | 9.109167 | 5F
5F | 150m15 - cold formed purlin :5,SHE-13.STEEL.dgn,Design Model:124243 | 2.5364 | 0.000457 | 1.55481 | 1.55573 | 0.011236 | 0.00116 | 9.105679 | 88.204607 | 9.109167 | 5F
5F | 150m15 - cold formed purlin :5,SHE-13.STEEL.dgn,Design Model:124245 | 2.5364 | 0.000457 | 1.55481 | 1.55573 | 0.011236 | 0.00116 | 9.105679 | 88.204607 | 9.109167 | 5F
5F | 150m15 - cold formed purlin :5,SHE-13.STEEL.dgn,Design Model:124247 | 2.5364 | 0.000457 | 1.55481 | 1.55573 | 0.011236 | 0.00116 | 9.105679 | 88.204607 | 9.109167 | 5F
5F | 150m15 - cold formed purlin :5,SHE-13.STEEL.dgn,Design Model:124249 | 2.5364 | 0.000457 | 1.55481 | 1.55573 | 0.011236 | 0.00116 | 9.105679 | 88.204607 | 9.109167 | 5F
5F | 150m15 - cold formed purlin :5,SHE-13.STEEL.dgn,Design Model:124251 | 2.5364 | 0.000457 | 1.55481 | 1.55573 | 0.011236 | 0.00116 | 9.105679 | 88.204607 | 9.109167 | 5F
5F | 150m15 - cold formed purlin :5,SHE-13.STEEL.dgn,Design Model:124253 | 2.5364 | 0.000457 | 1.55481 | 1.55573 | 0.011236 | 0.00116 | 9.105679 | 88.204607 | 9.109167 | 5F
5F | 150m15 - cold formed purlin :5,SHE-13.STEEL.dgn,Design Model:124255 | 2.5364 | 0.000457 | 1.55481 | 1.55573 | 0.011236 | 0.00116 | 9.105679 | 88.204607 | 9.109167 | 5F
5F | 150m15 - cold formed purlin :5,SHE-13.STEEL.dgn,Design Model:124257 | 0.576401 | 0.000457 | 0.353334 | 0.354249 | 0.002553 | 0.000264 | 2.069279 | 20.044630 | 2.070072 | 5F
5F | 150m15 - cold formed purlin :5,SHE-13.STEEL.dgn,Design Model:124259 | 0.576401 | 0.000457 | 0.353334 | 0.354249 | 0.002553 | 0.000264 | 2.069279 | 20.044630 | 2.070072 | 5F
5F | 150m15 - cold formed purlin :5,SHE-13.STEEL.dgn,Design Model:124261 | 0.576401 | 0.000457 | 0.353334 | 0.354249 | 0.002553 | 0.000264 | 2.069279 | 20.044630 | 2.070072 | 5F
5F | 150m15 - cold formed purlin :5,SHE-13.STEEL.dgn,Design Model:124263 | 0.576401 | 0.000457 | 0.353334 | 0.354249 | 0.002553 | 0.000264 | 2.069279 | 20.044630 | 2.070072 | 5F
5F | 150m15 - cold formed purlin :5,SHE-13.STEEL.dgn,Design Model:124275 | 2.4964 | 0.000457 | 1.53029 | 1.53121 | 0.011059 | 0.001142 | 8.962076 | 86.813561 | 8.965509 | 5F
5F | 150m15 - cold formed purlin :5,SHE-13.STEEL.dgn,Design Model:124277 | 2.4964 | 0.000457 | 1.53029 | 1.53121 | 0.011059 | 0.001142 | 8.962076 | 86.813561 | 8.965509 | 5F
5F | 150m15 - cold formed purlin :5,SHE-13.STEEL.dgn,Design Model:124279 | 2.4964 | 0.000457 | 1.53029 | 1.53121 | 0.011059 | 0.001142 | 8.962076 | 86.813561 | 8.965509 | 5F
5F | 150m15 - cold formed purlin :5,SHE-13.STEEL.dgn,Design Model:124281 | 2.4964 | 0.000457 | 1.53029 | 1.53121 | 0.011059 | 0.001142 | 8.962076 | 86.813561 | 8.965509 | 5F
5F | 150m15 - cold formed purlin :5,SHE-13.STEEL.dgn,Design Model:124283 | 2.4964 | 0.000457 | 1.53029 | 1.53121 | 0.011059 | 0.001142 | 8.962076 | 86.813561 | 8.965509 | 5F
5F | 150m15 - cold formed purlin :5,SHE-13.STEEL.dgn,Design Model:124285 | 2.4964 | 0.000457 | 1.53029 | 1.53121 | 0.011059 | 0.001142 | 8.962076 | 86.813561 | 8.965509 | 5F
5F | 150m15 - cold formed purlin :5,SHE-13.STEEL.dgn,Design Model:124287 | 2.4964 | 0.000457 | 1.53029 | 1.53121 | 0.011059 | 0.001142 | 8.962076 | 86.813561 | 8.965509 | 5F
5F | 150m15 - cold formed purlin :5,SHE-13.STEEL.dgn,Design Model:124289 | 2.4964 | 0.000457 | 1.53029 | 1.53121 | 0.011059 | 0.001142 | 8.962076 | 86.813561 | 8.965509 | 5F
5F | 150m15 - cold formed purlin :5,SHE-13.STEEL.dgn,Design Model:124291 | 2.4964 | 0.000457 | 1.53029 | 1.53121 | 0.011059 | 0.001142 | 8.962076 | 86.813561 | 8.965509 | 5F
5F | 150m15 - cold formed purlin :5,SHE-13.STEEL.dgn,Design Model:124293 | 2.4964 | 0.000457 | 1.53029 | 1.53121 | 0.011059 | 0.001142 | 8.962076 | 86.813561 | 8.965509 | 5F
5F | 150m15 - cold formed purlin :5,SHE-13.STEEL.dgn,Design Model:124295 | 1.08477 | 0.000457 | 0.664966 | 0.665881 | 0.004806 | 0.000496 | 3.894337 | 37.723540 | 3.895828 | 5F
5F | 150m15 - cold formed purlin :5,SHE-13.STEEL.dgn,Design Model:124297 | 1.08477 | 0.000457 | 0.664966 | 0.665881 | 0.004806 | 0.000496 | 3.894337 | 37.723540 | 3.895828 | 5F
5F | 150m15 - cold formed purlin :5,SHE-13.STEEL.dgn,Design Model:124299 | 1.08477 | 0.000457 | 0.664966 | 0.665881 | 0.004806 | 0.000496 | 3.894337 | 37.723540 | 3.895828 | 5F
5F | 150m15 - cold formed purlin :5,SHE-13.STEEL.dgn,Design Model:124321 | 1.08477 | 0.000457 | 0.664966 | 0.665881 | 0.004806 | 0.000496 | 3.894337 | 37.723540 | 3.895828 | 5F
5F | 150m15 - cold formed purlin :5,SHE-13.STEEL.dgn,Design Model:124323 | 1.08477 | 0.000457 | 0.664966 | 0.665881 | 0.004806 | 0.000496 | 3.894337 | 37.723540 | 3.895828 | 5F
5F | 150m15 - cold formed purlin :5,SHE-13.STEEL.dgn,Design Model:124325 | 1.08477 | 0.000457 | 0.664966 | 0.665881 | 0.004806 | 0.000496 | 3.894337 | 37.723540 | 3.895828 | 5F
5F | 150m15 - cold formed purlin :5,SHE-13.STEEL.dgn,Design Model:124327 | 1.08477 | 0.000457 | 0.664966 | 0.665881 | 0.004806 | 0.000496 | 3.894337 | 37.723540 | 3.895828 | 5F
5F | 150m15 - cold formed purlin :5,SHE-13.STEEL.dgn,Design Model:124329 | 1.08477 | 0.000457 | 0.664966 | 0.665881 | 0.004806 | 0.000496 | 3.894337 | 37.723540 | 3.895828 | 5F
5F | 150m15 - cold formed purlin :5,SHE-13.STEEL.dgn,Design Model:124331 | 1.08477 | 0.000457 | 0.664966 | 0.665881 | 0.004806 | 0.000496 | 3.894337 | 37.723540 | 3.895828 | 5F
5F | 150m15 - cold formed purlin :5,SHE-13.STEEL.dgn,Design Model:124371 | 1.08483 | 0.000457 | 0.664999 | 0.665914 | 0.004806 | 0.000496 | 3.894527 | 37.725387 | 3.896019 | 5F
5F | 150m15 - cold formed purlin :5,SHE-13.STEEL.dgn,Design Model:124373 | 1.08483 | 0.000457 | 0.664999 | 0.665914 | 0.004806 | 0.000496 | 3.894527 | 37.725387 | 3.896019 | 5F
5F | 150m15 - cold formed purlin :5,SHE-13.STEEL.dgn,Design Model:124375 | 1.08483 | 0.000457 | 0.664999 | 0.665914 | 0.004806 | 0.000496 | 3.894527 | 37.725387 | 3.896019 | 5F
5F | 150m15 - cold formed purlin :5,SHE-13.STEEL.dgn,Design Model:124377 | 1.08483 | 0.000457 | 0.664999 | 0.665914 | 0.004806 | 0.000496 | 3.894527 | 37.725387 | 3.896019 | 5F
5F | 150m15 - cold formed purlin :5,SHE-13.STEEL.dgn,Design Model:124379 | 1.08483 | 0.000457 | 0.664999 | 0.665914 | 0.004806 | 0.000496 | 3.894527 | 37.725387 | 3.896019 | 5F
5F | 150m15 - cold formed purlin :5,SHE-13.STEEL.dgn,Design Model:124381 | 1.08483 | 0.000457 | 0.664999 | 0.665914 | 0.004806 | 0.000496 | 3.894527 | 37.725387 | 3.896019 | 5F
5F | 150m15 - cold formed purlin :5,SHE-13.STEEL.dgn,Design Model:124383 | 1.08483 | 0.000457 | 0.664999 | 0.665914 | 0.004806 | 0.000496 | 3.894527 | 37.725387 | 3.896019 | 5F
5F | 150m15 - cold formed purlin :5,SHE-13.STEEL.dgn,Design Model:124385 | 1.08483 | 0.000457 | 0.664999 | 0.665914 | 0.004806 | 0.000496 | 3.894527 | 37.725387 | 3.896019 | 5F
5F | 150m15 - cold formed purlin :5,SHE-13.STEEL.dgn,Design Model:124409 | 1.08477 | 0.000457 | 0.664966 | 0.665881 | 0.004806 | 0.000496 | 3.894337 | 37.723540 | 3.895828 | 5F
5F | 150m15 - cold formed purlin :5,SHE-13.STEEL.dgn,Design Model:124411 | 1.08477 | 0.000457 | 0.664966 | 0.665881 | 0.004806 | 0.000496 | 3.894337 | 37.723540 | 3.895828 | 5F
5F | 150m15 - cold formed purlin :5,SHE-13.STEEL.dgn,Design Model:124413 | 1.08477 | 0.000457 | 0.664966 | 0.665881 | 0.004806 | 0.000496 | 3.894337 | 37.723540 | 3.895828 | 5F
5F | 150m15 - cold formed purlin :5,SHE-13.STEEL.dgn,Design Model:124415 | 1.08477 | 0.000457 | 0.664966 | 0.665881 | 0.004806 | 0.000496 | 3.894337 | 37.723540 | 3.895828 | 5F
5F | 150m15 - cold formed purlin :5,SHE-13.STEEL.dgn,Design Model:124417 | 1.08477 | 0.000457 | 0.664966 | 0.665881 | 0.004806 | 0.000496 | 3.894337 | 37.723540 | 3.895828 | 5F
5F | 150m15 - cold formed purlin :5,SHE-13.STEEL.dgn,Design Model:124419 | 1.08477 | 0.000457 | 0.664966 | 0.665881 | 0.004806 | 0.000496 | 3.894337 | 37.723540 | 3.895828 | 5F
5F | 150m15 - cold formed purlin :5,SHE-13.STEEL.dgn,Design Model:124421 | 1.08477 | 0.000457 | 0.664966 | 0.665881 | 0.004806 | 0.000496 | 3.894337 | 37.723540 | 3.895828 | 5F
5F | 150m15 - cold formed purlin :5,SHE-13.STEEL.dgn,Design Model:124423 | 1.08477 | 0.000457 | 0.664966 | 0.665881 | 0.004806 | 0.000496 | 3.894337 | 37.723540 | 3.895828 | 5F
5F | 150m15 - cold formed purlin :5,SHE-13.STEEL.dgn,Design Model:124425 | 1.08477 | 0.000457 | 0.664966 | 0.665881 | 0.004806 | 0.000496 | 3.894337 | 37.723540 | 3.895828 | 5F
5F | 150m15 - cold formed purlin :5,SHE-13.STEEL.dgn,Design Model:124445 | 3.4636 | 0.000457 | 2.12319 | 2.1241 | 0.015344 | 0.001585 | 12.434324 | 120.448422 | 12.439086 | 5F
5F | 150m15 - cold formed purlin :5,SHE-13.STEEL.dgn,Design Model:124447 | 3.4636 | 0.000457 | 2.12319 | 2.1241 | 0.015344 | 0.001585 | 12.434324 | 120.448422 | 12.439086 | 5F
5F | 150m15 - cold formed purlin :5,SHE-13.STEEL.dgn,Design Model:124449 | 3.4636 | 0.000457 | 2.12319 | 2.1241 | 0.015344 | 0.001585 | 12.434324 | 120.448422 | 12.439086 | 5F
5F | 150m15 - cold formed purlin :5,SHE-13.STEEL.dgn,Design Model:124451 | 3.4636 | 0.000457 | 2.12319 | 2.1241 | 0.015344 | 0.001585 | 12.434324 | 120.448422 | 12.439086 | 5F
5F | 150m15 - cold formed purlin :5,SHE-13.STEEL.dgn,Design Model:124453 | 3.4636 | 0.000457 | 2.12319 | 2.1241 | 0.015344 | 0.001585 | 12.434324 | 120.448422 | 12.439086 | 5F
5F | 150m15 - cold formed purlin :5,SHE-13.STEEL.dgn,Design Model:124455 | 3.4636 | 0.000457 | 2.12319 | 2.1241 | 0.015344 | 0.001585 | 12.434324 | 120.448422 | 12.439086 | 5F
5F | 150m15 - cold formed purlin :5,SHE-13.STEEL.dgn,Design Model:124457 | 3.4636 | 0.000457 | 2.12319 | 2.1241 | 0.015344 | 0.001585 | 12.434324 | 120.448422 | 12.439086 | 5F
5F | 150m15 - cold formed purlin :5,SHE-13.STEEL.dgn,Design Model:124459 | 3.4636 | 0.000457 | 2.12319 | 2.1241 | 0.015344 | 0.001585 | 12.434324 | 120.448422 | 12.439086 | 5F
5F | 150m15 - cold formed purlin :5,SHE-13.STEEL.dgn,Design Model:124461 | 3.4636 | 0.000457 | 2.12319 | 2.1241 | 0.015344 | 0.001585 | 12.434324 | 120.448422 | 12.439086 | 5F
5F | 150m15 - cold formed purlin :5,SHE-13.STEEL.dgn,Design Model:124463 | 3.4636 | 0.000457 | 2.12319 | 2.1241 | 0.015344 | 0.001585 | 12.434324 | 120.448422 | 12.439086 | 5F
5F | 150m15 - cold formed purlin :5,SHE-13.STEEL.dgn,Design Model:124465 | 3.4636 | 0.000457 | 2.12319 | 2.1241 | 0.015344 | 0.001585 | 12.434324 | 120.448422 | 12.439086 | 5F
5F | 150m15 - cold formed purlin :5,SHE-13.STEEL.dgn,Design Model:124516 | 1.08483 | 0.000457 | 0.664999 | 0.665914 | 0.004806 | 0.000496 | 3.894527 | 37.725387 | 3.896019 | 5F
5F | 150m15 - cold formed purlin :5,SHE-13.STEEL.dgn,Design Model:124518 | 1.08483 | 0.000457 | 0.664999 | 0.665914 | 0.004806 | 0.000496 | 3.894527 | 37.725387 | 3.896019 | 5F
5F | 150m15 - cold formed purlin :5,SHE-13.STEEL.dgn,Design Model:124540 | 1.08483 | 0.000457 | 0.664999 | 0.665914 | 0.004806 | 0.000496 | 3.894527 | 37.725387 | 3.896019 | 5F
5F | 150m15 - cold formed purlin :5,SHE-13.STEEL.dgn,Design Model:124542 | 1.08483 | 0.000457 | 0.664999 | 0.665914 | 0.004806 | 0.000496 | 3.894527 | 37.725387 | 3.896019 | 5F
5F | 150m15 - cold formed purlin :5,SHE-13.STEEL.dgn,Design Model:124544 | 1.08483 | 0.000457 | 0.664999 | 0.665914 | 0.004806 | 0.000496 | 3.894527 | 37.725387 | 3.896019 | 5F
5F | 150m15 - cold formed purlin :5,SHE-13.STEEL.dgn,Design Model:124546 | 1.08483 | 0.000457 | 0.664999 | 0.665914 | 0.004806 | 0.000496 | 3.894527 | 37.725387 | 3.896019 | 5F
5F | 150m15 - cold formed purlin :5,SHE-13.STEEL.dgn,Design Model:124548 | 1.08483 | 0.000457 | 0.664999 | 0.665914 | 0.004806 | 0.000496 | 3.894527 | 37.725387 | 3.896019 | 5F
5F | 150m15 - cold formed purlin :5,SHE-13.STEEL.dgn,Design Model:124550 | 1.08483 | 0.000457 | 0.664999 | 0.665914 | 0.004806 | 0.000496 | 3.894527 | 37.725387 | 3.896019 | 5F
5F | 150m15 - cold formed purlin :5,SHE-13.STEEL.dgn,Design Model:124552 | 1.08483 | 0.000457 | 0.664999 | 0.665914 | 0.004806 | 0.000496 | 3.894527 | 37.725387 | 3.896019 | 5F
5F | 150m15 - cold formed purlin :5,SHE-13.STEEL.dgn,Design Model:124572 | 0.695 | 0.000458 | 0.426035 | 0.42695 | 0.003079 | 0.000318 | 2.495050 | 24.168972 | 2.496006 | 5F
5F | 150m15 - cold formed purlin :5,SHE-13.STEEL.dgn,Design Model:124574 | 0.695 | 0.000458 | 0.426035 | 0.42695 | 0.003079 | 0.000318 | 2.495050 | 24.168972 | 2.496006 | 5F
5F | 150m15 - cold formed purlin :5,SHE-13.STEEL.dgn,Design Model:124959 | 1.1428 | 0.000457 | 0.700537 | 0.701452 | 0.005063 | 0.000523 | 4.102655 | 39.741474 | 4.104227 | 5F
5F | 150m15 - cold formed purlin :5,SHE-13.STEEL.dgn,Design Model:124961 | 1.1428 | 0.000457 | 0.700537 | 0.701452 | 0.005063 | 0.000523 | 4.102655 | 39.741474 | 4.104227 | 5F
5F | 150m15 - cold formed purlin :5,SHE-13.STEEL.dgn,Design Model:124963 | 1.1428 | 0.000457 | 0.700537 | 0.701452 | 0.005063 | 0.000523 | 4.102655 | 39.741474 | 4.104227 | 5F
5F | 150m15 - cold formed purlin :5,SHE-13.STEEL.dgn,Design Model:124965 | 1.1428 | 0.000457 | 0.700537 | 0.701452 | 0.005063 | 0.000523 | 4.102655 | 39.741474 | 4.104227 | 5F
5F | 150m15 - cold formed purlin :5,SHE-13.STEEL.dgn,Design Model:124967 | 1.1428 | 0.000457 | 0.700537 | 0.701452 | 0.005063 | 0.000523 | 4.102655 | 39.741474 | 4.104227 | 5F
4F | 150m15 - cold formed purlin :5,SHE-13.STEEL.dgn,Design Model:124969 | 2.3816 | 0.000457 | 1.45992 | 1.46084 | 0.01055 | 0.00109 | 8.549944 | 82.821331 | 8.553219 | 4F
4F | 150m15 - cold formed purlin :5,SHE-13.STEEL.dgn,Design Model:124971 | 2.3816 | 0.000457 | 1.45992 | 1.46084 | 0.01055 | 0.00109 | 8.549944 | 82.821331 | 8.553219 | 4F
4F | 150m15 - cold formed purlin :5,SHE-13.STEEL.dgn,Design Model:124973 | 2.3816 | 0.000457 | 1.45992 | 1.46084 | 0.01055 | 0.00109 | 8.549944 | 82.821331 | 8.553219 | 4F
4F | 150m15 - cold formed purlin :5,SHE-13.STEEL.dgn,Design Model:124975 | 2.3816 | 0.000457 | 1.45992 | 1.46084 | 0.01055 | 0.00109 | 8.549944 | 82.821331 | 8.553219 | 4F
4F | 150m15 - cold formed purlin :5,SHE-13.STEEL.dgn,Design Model:124977 | 2.3816 | 0.000457 | 1.45992 | 1.46084 | 0.01055 | 0.00109 | 8.549944 | 82.821331 | 8.553219 | 4F
4F | 150m15 - cold formed purlin :5,SHE-13.STEEL.dgn,Design Model:124979 | 2.3816 | 0.000457 | 1.45992 | 1.46084 | 0.01055 | 0.00109 | 8.549944 | 82.821331 | 8.553219 | 4F
4F | 150m15 - cold formed purlin :5,SHE-13.STEEL.dgn,Design Model:124981 | 2.3816 | 0.000457 | 1.45992 | 1.46084 | 0.01055 | 0.00109 | 8.549944 | 82.821331 | 8.553219 | 4F
4F | 150m15 - cold formed purlin :5,SHE-13.STEEL.dgn,Design Model:124983 | 2.3816 | 0.000457 | 1.45992 | 1.46084 | 0.01055 | 0.00109 | 8.549944 | 82.821331 | 8.553219 | 4F
4F | 150m15 - cold formed purlin :5,SHE-13.STEEL.dgn,Design Model:124985 | 2.3816 | 0.000457 | 1.45992 | 1.46084 | 0.01055 | 0.00109 | 8.549944 | 82.821331 | 8.553219 | 4F
4F | 150m15 - cold formed purlin :5,SHE-13.STEEL.dgn,Design Model:124987 | 2.3816 | 0.000457 | 1.45992 | 1.46084 | 0.01055 | 0.00109 | 8.549944 | 82.821331 | 8.553219 | 4F
4F | 150m15 - cold formed purlin :5,SHE-13.STEEL.dgn,Design Model:124989 | 2.3816 | 0.000457 | 1.45992 | 1.46084 | 0.01055 | 0.00109 | 8.549944 | 82.821331 | 8.553219 | 4F
4F | 150m15 - cold formed purlin :5,SHE-13.STEEL.dgn,Design Model:124991 | 2.3816 | 0.000457 | 1.45992 | 1.46084 | 0.01055 | 0.00109 | 8.549944 | 82.821331 | 8.553219 | 4F
4F | 150m15 - cold formed purlin :5,SHE-13.STEEL.dgn,Design Model:124993 | 2.3816 | 0.000457 | 1.45992 | 1.46084 | 0.01055 | 0.00109 | 8.549944 | 82.821331 | 8.553219 | 4F
4F | 150m15 - cold formed purlin :5,SHE-13.STEEL.dgn,Design Model:124995 | 2.3816 | 0.000457 | 1.45992 | 1.46084 | 0.01055 | 0.00109 | 8.549944 | 82.821331 | 8.553219 | 4F
4F | 150m15 - cold formed purlin :5,SHE-13.STEEL.dgn,Design Model:124997 | 2.3816 | 0.000457 | 1.45992 | 1.46084 | 0.01055 | 0.00109 | 8.549944 | 82.821331 | 8.553219 | 4F
4F | 150m15 - cold formed purlin :5,SHE-13.STEEL.dgn,Design Model:124999 | 2.3816 | 0.000457 | 1.45992 | 1.46084 | 0.01055 | 0.00109 | 8.549944 | 82.821331 | 8.553219 | 4F
4F | 150m15 - cold formed purlin :5,SHE-13.STEEL.dgn,Design Model:125001 | 2.3816 | 0.000457 | 1.45992 | 1.46084 | 0.01055 | 0.00109 | 8.549944 | 82.821331 | 8.553219 | 4F
4F | 150m15 - cold formed purlin :5,SHE-13.STEEL.dgn,Design Model:125003 | 2.3816 | 0.000457 | 1.45992 | 1.46084 | 0.01055 | 0.00109 | 8.549944 | 82.821331 | 8.553219 | 4F
4F | 150m15 - cold formed purlin :5,SHE-13.STEEL.dgn,Design Model:125005 | 2.3816 | 0.000457 | 1.45992 | 1.46084 | 0.01055 | 0.00109 | 8.549944 | 82.821331 | 8.553219 | 4F
4F | 150m15 - cold formed purlin :5,SHE-13.STEEL.dgn,Design Model:125007 | 2.3816 | 0.000457 | 1.45992 | 1.46084 | 0.01055 | 0.00109 | 8.549944 | 82.821331 | 8.553219 | 4F
4F | 150m15 - cold formed purlin :5,SHE-13.STEEL.dgn,Design Model:125009 | 2.3816 | 0.000457 | 1.45992 | 1.46084 | 0.01055 | 0.00109 | 8.549944 | 82.821331 | 8.553219 | 4F
4F | 150m15 - cold formed purlin :5,SHE-13.STEEL.dgn,Design Model:125011 | 2.3816 | 0.000457 | 1.45992 | 1.46084 | 0.01055 | 0.00109 | 8.549944 | 82.821331 | 8.553219 | 4F
4F | 150m15 - cold formed purlin :5,SHE-13.STEEL.dgn,Design Model:125013 | 2.3816 | 0.000457 | 1.45992 | 1.46084 | 0.01055 | 0.00109 | 8.549944 | 82.821331 | 8.553219 | 4F
4F | 150m15 - cold formed purlin :5,SHE-13.STEEL.dgn,Design Model:125015 | 2.3816 | 0.000457 | 1.45992 | 1.46084 | 0.01055 | 0.00109 | 8.549944 | 82.821331 | 8.553219 | 4F
4F | 150m15 - cold formed purlin :5,SHE-13.STEEL.dgn,Design Model:125017 | 2.3816 | 0.000457 | 1.45992 | 1.46084 | 0.01055 | 0.00109 | 8.549944 | 82.821331 | 8.553219 | 4F
4F | 150m15 - cold formed purlin :5,SHE-13.STEEL.dgn,Design Model:125019 | 2.3816 | 0.000457 | 1.45992 | 1.46084 | 0.01055 | 0.00109 | 8.549944 | 82.821331 | 8.553219 | 4F
4F | 150m15 - cold formed purlin :5,SHE-13.STEEL.dgn,Design Model:125021 | 2.3816 | 0.000457 | 1.45992 | 1.46084 | 0.01055 | 0.00109 | 8.549944 | 82.821331 | 8.553219 | 4F
4F | 150m15 - cold formed purlin :5,SHE-13.STEEL.dgn,Design Model:125023 | 2.3816 | 0.000457 | 1.45992 | 1.46084 | 0.01055 | 0.00109 | 8.549944 | 82.821331 | 8.553219 | 4F
4F | 150m15 - cold formed purlin :5,SHE-13.STEEL.dgn,Design Model:125025 | 2.3816 | 0.000457 | 1.45992 | 1.46084 | 0.01055 | 0.00109 | 8.549944 | 82.821331 | 8.553219 | 4F
4F | 150m15 - cold formed purlin :5,SHE-13.STEEL.dgn,Design Model:125027 | 2.3816 | 0.000457 | 1.45992 | 1.46084 | 0.01055 | 0.00109 | 8.549944 | 82.821331 | 8.553219 | 4F
4F | 150m15 - cold formed purlin :5,SHE-13.STEEL.dgn,Design Model:125029 | 2.3816 | 0.000457 | 1.45992 | 1.46084 | 0.01055 | 0.00109 | 8.549944 | 82.821331 | 8.553219 | 4F
4F | 150m15 - cold formed purlin :5,SHE-13.STEEL.dgn,Design Model:125031 | 2.3816 | 0.000457 | 1.45992 | 1.46084 | 0.01055 | 0.00109 | 8.549944 | 82.821331 | 8.553219 | 4F
4F | 150m15 - cold formed purlin :5,SHE-13.STEEL.dgn,Design Model:125033 | 2.3816 | 0.000457 | 1.45992 | 1.46084 | 0.01055 | 0.00109 | 8.549944 | 82.821331 | 8.553219 | 4F
4F | 150m15 - cold formed purlin :5,SHE-13.STEEL.dgn,Design Model:125035 | 2.3816 | 0.000457 | 1.45992 | 1.46084 | 0.01055 | 0.00109 | 8.549944 | 82.821331 | 8.553219 | 4F
4F | 150m15 - cold formed purlin :5,SHE-13.STEEL.dgn,Design Model:125037 | 2.3816 | 0.000457 | 1.45992 | 1.46084 | 0.01055 | 0.00109 | 8.549944 | 82.821331 | 8.553219 | 4F
4F | 150m15 - cold formed purlin :5,SHE-13.STEEL.dgn,Design Model:125039 | 2.3816 | 0.000457 | 1.45992 | 1.46084 | 0.01055 | 0.00109 | 8.549944 | 82.821331 | 8.553219 | 4F
4F | 150m15 - cold formed purlin :5,SHE-13.STEEL.dgn,Design Model:125041 | 2.3816 | 0.000457 | 1.45992 | 1.46084 | 0.01055 | 0.00109 | 8.549944 | 82.821331 | 8.553219 | 4F
4F | 150m15 - cold formed purlin :5,SHE-13.STEEL.dgn,Design Model:125043 | 2.3816 | 0.000457 | 1.45992 | 1.46084 | 0.01055 | 0.00109 | 8.549944 | 82.821331 | 8.553219 | 4F
4F | 150m15 - cold formed purlin :5,SHE-13.STEEL.dgn,Design Model:125045 | 2.3816 | 0.000457 | 1.45992 | 1.46084 | 0.01055 | 0.00109 | 8.549944 | 82.821331 | 8.553219 | 4F
4F | 150m15 - cold formed purlin :5,SHE-13.STEEL.dgn,Design Model:125047 | 2.3816 | 0.000457 | 1.45992 | 1.46084 | 0.01055 | 0.00109 | 8.549944 | 82.821331 | 8.553219 | 4F
4F | 150m15 - cold formed purlin :5,SHE-13.STEEL.dgn,Design Model:125049 | 2.3816 | 0.000457 | 1.45992 | 1.46084 | 0.01055 | 0.00109 | 8.549944 | 82.821331 | 8.553219 | 4F
4F | 150m15 - cold formed purlin :5,SHE-13.STEEL.dgn,Design Model:125051 | 0.519 | 0.000457 | 0.318147 | 0.319062 | 0.002299 | 0.000237 | 1.863210 | 18.048487 | 1.863924 | 4F
4F | 150m15 - cold formed purlin :5,SHE-13.STEEL.dgn,Design Model:125053 | 0.519 | 0.000457 | 0.318147 | 0.319062 | 0.002299 | 0.000237 | 1.863210 | 18.048487 | 1.863924 | 4F
4F | 150m15 - cold formed purlin :5,SHE-13.STEEL.dgn,Design Model:125055 | 0.519 | 0.000457 | 0.318147 | 0.319062 | 0.002299 | 0.000237 | 1.863210 | 18.048487 | 1.863924 | 4F
4F | 150m15 - cold formed purlin :5,SHE-13.STEEL.dgn,Design Model:125057 | 0.519 | 0.000457 | 0.318147 | 0.319062 | 0.002299 | 0.000237 | 1.863210 | 18.048487 | 1.863924 | 4F
4F | 150m15 - cold formed purlin :5,SHE-13.STEEL.dgn,Design Model:125059 | 2.3816 | 0.000457 | 1.45992 | 1.46084 | 0.01055 | 0.00109 | 8.549944 | 82.821331 | 8.553219 | 4F
4F | 150m15 - cold formed purlin :5,SHE-13.STEEL.dgn,Design Model:125061 | 2.3816 | 0.000457 | 1.45992 | 1.46084 | 0.01055 | 0.00109 | 8.549944 | 82.821331 | 8.553219 | 4F
4F | 150m15 - cold formed purlin :5,SHE-13.STEEL.dgn,Design Model:125063 | 2.3816 | 0.000457 | 1.45992 | 1.46084 | 0.01055 | 0.00109 | 8.549944 | 82.821331 | 8.553219 | 4F
4F | 150m15 - cold formed purlin :5,SHE-13.STEEL.dgn,Design Model:125065 | 2.3816 | 0.000457 | 1.45992 | 1.46084 | 0.01055 | 0.00109 | 8.549944 | 82.821331 | 8.553219 | 4F
4F | 150m15 - cold formed purlin :5,SHE-13.STEEL.dgn,Design Model:125067 | 2.3816 | 0.000457 | 1.45992 | 1.46084 | 0.01055 | 0.00109 | 8.549944 | 82.821331 | 8.553219 | 4F
4F | 150m15 - cold formed purlin :5,SHE-13.STEEL.dgn,Design Model:125069 | 2.3816 | 0.000457 | 1.45992 | 1.46084 | 0.01055 | 0.00109 | 8.549944 | 82.821331 | 8.553219 | 4F
4F | 150m15 - cold formed purlin :5,SHE-13.STEEL.dgn,Design Model:125071 | 2.3816 | 0.000457 | 1.45992 | 1.46084 | 0.01055 | 0.00109 | 8.549944 | 82.821331 | 8.553219 | 4F
4F | 150m15 - cold formed purlin :5,SHE-13.STEEL.dgn,Design Model:125073 | 2.3816 | 0.000457 | 1.45992 | 1.46084 | 0.01055 | 0.00109 | 8.549944 | 82.821331 | 8.553219 | 4F
4F | 150m15 - cold formed purlin :5,SHE-13.STEEL.dgn,Design Model:125081 | 4.01635 | 0.000457 | 2.46202 | 2.46294 | 0.017792 | 0.001837 | 14.418697 | 139.670579 | 14.424219 | 4F
4F | 150m15 - cold formed purlin :5,SHE-13.STEEL.dgn,Design Model:125083 | 4.01635 | 0.000457 | 2.46202 | 2.46294 | 0.017792 | 0.001837 | 14.418697 | 139.670579 | 14.424219 | 4F
4F | 150m15 - cold formed purlin :5,SHE-13.STEEL.dgn,Design Model:125085 | 4.01635 | 0.000457 | 2.46202 | 2.46294 | 0.017792 | 0.001837 | 14.418697 | 139.670579 | 14.424219 | 4F
4F | 150m15 - cold formed purlin :5,SHE-13.STEEL.dgn,Design Model:125087 | 4.01635 | 0.000457 | 2.46202 | 2.46294 | 0.017792 | 0.001837 | 14.418697 | 139.670579 | 14.424219 | 4F
4F | 150m15 - cold formed purlin :5,SHE-13.STEEL.dgn,Design Model:125089 | 4.01635 | 0.000457 | 2.46202 | 2.46294 | 0.017792 | 0.001837 | 14.418697 | 139.670579 | 14.424219 | 4F
4F | 150m15 - cold formed purlin :5,SHE-13.STEEL.dgn,Design Model:125091 | 4.01635 | 0.000457 | 2.46202 | 2.46294 | 0.017792 | 0.001837 | 14.418697 | 139.670579 | 14.424219 | 4F
4F | 150m15 - cold formed purlin :5,SHE-13.STEEL.dgn,Design Model:125093 | 4.01635 | 0.000457 | 2.46202 | 2.46294 | 0.017792 | 0.001837 | 14.418697 | 139.670579 | 14.424219 | 4F
4F | 150m15 - cold formed purlin :5,SHE-13.STEEL.dgn,Design Model:125095 | 4.01635 | 0.000457 | 2.46202 | 2.46294 | 0.017792 | 0.001837 | 14.418697 | 139.670579 | 14.424219 | 4F
4F | 150m15 - cold formed purlin :5,SHE-13.STEEL.dgn,Design Model:125097 | 4.01635 | 0.000457 | 2.46202 | 2.46294 | 0.017792 | 0.001837 | 14.418697 | 139.670579 | 14.424219 | 4F
4F | 150m15 - cold formed purlin :5,SHE-13.STEEL.dgn,Design Model:125099 | 4.01635 | 0.000457 | 2.46202 | 2.46294 | 0.017792 | 0.001837 | 14.418697 | 139.670579 | 14.424219 | 4F
4F | 150m15 - cold formed purlin :5,SHE-13.STEEL.dgn,Design Model:125101 | 4.01635 | 0.000457 | 2.46202 | 2.46294 | 0.017792 | 0.001837 | 14.418697 | 139.670579 | 14.424219 | 4F
4F | 150m15 - cold formed purlin :5,SHE-13.STEEL.dgn,Design Model:125103 | 4.01635 | 0.000457 | 2.46202 | 2.46294 | 0.017792 | 0.001837 | 14.418697 | 139.670579 | 14.424219 | 4F
4F | 150m15 - cold formed purlin :5,SHE-13.STEEL.dgn,Design Model:125105 | 4.01635 | 0.000457 | 2.46202 | 2.46294 | 0.017792 | 0.001837 | 14.418697 | 139.670579 | 14.424219 | 4F
4F | 150m15 - cold formed purlin :5,SHE-13.STEEL.dgn,Design Model:125107 | 4.01635 | 0.000457 | 2.46202 | 2.46294 | 0.017792 | 0.001837 | 14.418697 | 139.670579 | 14.424219 | 4F
4F | 150m15 - cold formed purlin :5,SHE-13.STEEL.dgn,Design Model:125109 | 4.01635 | 0.000457 | 2.46202 | 2.46294 | 0.017792 | 0.001837 | 14.418697 | 139.670579 | 14.424219 | 4F
4F | 150m15 - cold formed purlin :5,SHE-13.STEEL.dgn,Design Model:125111 | 4.01635 | 0.000457 | 2.46202 | 2.46294 | 0.017792 | 0.001837 | 14.418697 | 139.670579 | 14.424219 | 4F
4F | 150m15 - cold formed purlin :5,SHE-13.STEEL.dgn,Design Model:125113 | 4.01635 | 0.000457 | 2.46202 | 2.46294 | 0.017792 | 0.001837 | 14.418697 | 139.670579 | 14.424219 | 4F
4F | 150m15 - cold formed purlin :5,SHE-13.STEEL.dgn,Design Model:125115 | 4.01635 | 0.000457 | 2.46202 | 2.46294 | 0.017792 | 0.001837 | 14.418697 | 139.670579 | 14.424219 | 4F
4F | 150m15 - cold formed purlin :5,SHE-13.STEEL.dgn,Design Model:125117 | 4.01635 | 0.000457 | 2.46202 | 2.46294 | 0.017792 | 0.001837 | 14.418697 | 139.670579 | 14.424219 | 4F
4F | 150m15 - cold formed purlin :5,SHE-13.STEEL.dgn,Design Model:125119 | 4.01635 | 0.000457 | 2.46202 | 2.46294 | 0.017792 | 0.001837 | 14.418697 | 139.670579 | 14.424219 | 4F
4F | 150m15 - cold formed purlin :5,SHE-13.STEEL.dgn,Design Model:125121 | 4.01635 | 0.000457 | 2.46202 | 2.46294 | 0.017792 | 0.001837 | 14.418697 | 139.670579 | 14.424219 | 4F
4F | 150m15 - cold formed purlin :5,SHE-13.STEEL.dgn,Design Model:125123 | 4.01635 | 0.000457 | 2.46202 | 2.46294 | 0.017792 | 0.001837 | 14.418697 | 139.670579 | 14.424219 | 4F
4F | 150m15 - cold formed purlin :5,SHE-13.STEEL.dgn,Design Model:125125 | 4.01635 | 0.000457 | 2.46202 | 2.46294 | 0.017792 | 0.001837 | 14.418697 | 139.670579 | 14.424219 | 4F
4F | 150m15 - cold formed purlin :5,SHE-13.STEEL.dgn,Design Model:125127 | 4.01635 | 0.000457 | 2.46202 | 2.46294 | 0.017792 | 0.001837 | 14.418697 | 139.670579 | 14.424219 | 4F
4F | 150m15 - cold formed purlin :5,SHE-13.STEEL.dgn,Design Model:125129 | 4.01635 | 0.000457 | 2.46202 | 2.46294 | 0.017792 | 0.001837 | 14.418697 | 139.670579 | 14.424219 | 4F
4F | 150m15 - cold formed purlin :5,SHE-13.STEEL.dgn,Design Model:125133 | 4.03635 | 0.000457 | 2.47428 | 2.4752 | 0.017881 | 0.001847 | 14.490496 | 140.366089 | 14.496046 | 4F
4F | 150m15 - cold formed purlin :5,SHE-13.STEEL.dgn,Design Model:125135 | 4.03635 | 0.000457 | 2.47428 | 2.4752 | 0.017881 | 0.001847 | 14.490496 | 140.366089 | 14.496046 | 4F
4F | 150m15 - cold formed purlin :5,SHE-13.STEEL.dgn,Design Model:125137 | 4.03635 | 0.000457 | 2.47428 | 2.4752 | 0.017881 | 0.001847 | 14.490496 | 140.366089 | 14.496046 | 4F
4F | 150m15 - cold formed purlin :5,SHE-13.STEEL.dgn,Design Model:125139 | 4.03635 | 0.000457 | 2.47428 | 2.4752 | 0.017881 | 0.001847 | 14.490496 | 140.366089 | 14.496046 | 4F
4F | 150m15 - cold formed purlin :5,SHE-13.STEEL.dgn,Design Model:125141 | 4.03635 | 0.000457 | 2.47428 | 2.4752 | 0.017881 | 0.001847 | 14.490496 | 140.366089 | 14.496046 | 4F
4F | 150m15 - cold formed purlin :5,SHE-13.STEEL.dgn,Design Model:125143 | 4.03635 | 0.000457 | 2.47428 | 2.4752 | 0.017881 | 0.001847 | 14.490496 | 140.366089 | 14.496046 | 4F
4F | 150m15 - cold formed purlin :5,SHE-13.STEEL.dgn,Design Model:125145 | 4.03635 | 0.000457 | 2.47428 | 2.4752 | 0.017881 | 0.001847 | 14.490496 | 140.366089 | 14.496046 | 4F
4F | 150m15 - cold formed purlin :5,SHE-13.STEEL.dgn,Design Model:125147 | 4.03635 | 0.000457 | 2.47428 | 2.4752 | 0.017881 | 0.001847 | 14.490496 | 140.366089 | 14.496046 | 4F
4F | 150m15 - cold formed purlin :5,SHE-13.STEEL.dgn,Design Model:125149 | 4.03635 | 0.000457 | 2.47428 | 2.4752 | 0.017881 | 0.001847 | 14.490496 | 140.366089 | 14.496046 | 4F
4F | 150m15 - cold formed purlin :5,SHE-13.STEEL.dgn,Design Model:125151 | 4.03635 | 0.000457 | 2.47428 | 2.4752 | 0.017881 | 0.001847 | 14.490496 | 140.366089 | 14.496046 | 4F
4F | 150m15 - cold formed purlin :5,SHE-13.STEEL.dgn,Design Model:125153 | 4.03635 | 0.000457 | 2.47428 | 2.4752 | 0.017881 | 0.001847 | 14.490496 | 140.366089 | 14.496046 | 4F
4F | 150m15 - cold formed purlin :5,SHE-13.STEEL.dgn,Design Model:125155 | 4.03635 | 0.000457 | 2.47428 | 2.4752 | 0.017881 | 0.001847 | 14.490496 | 140.366089 | 14.496046 | 4F
4F | 150m15 - cold formed purlin :5,SHE-13.STEEL.dgn,Design Model:125157 | 4.03635 | 0.000457 | 2.47428 | 2.4752 | 0.017881 | 0.001847 | 14.490496 | 140.366089 | 14.496046 | 4F
4F | 150m15 - cold formed purlin :5,SHE-13.STEEL.dgn,Design Model:125159 | 4.03635 | 0.000457 | 2.47428 | 2.4752 | 0.017881 | 0.001847 | 14.490496 | 140.366089 | 14.496046 | 4F
4F | 150m15 - cold formed purlin :5,SHE-13.STEEL.dgn,Design Model:125161 | 4.03635 | 0.000457 | 2.47428 | 2.4752 | 0.017881 | 0.001847 | 14.490496 | 140.366089 | 14.496046 | 4F
4F | 150m15 - cold formed purlin :5,SHE-13.STEEL.dgn,Design Model:125163 | 4.03635 | 0.000457 | 2.47428 | 2.4752 | 0.017881 | 0.001847 | 14.490496 | 140.366089 | 14.496046 | 4F
4F | 150m15 - cold formed purlin :5,SHE-13.STEEL.dgn,Design Model:125165 | 4.03635 | 0.000457 | 2.47428 | 2.4752 | 0.017881 | 0.001847 | 14.490496 | 140.366089 | 14.496046 | 4F
4F | 150m15 - cold formed purlin :5,SHE-13.STEEL.dgn,Design Model:125167 | 4.03635 | 0.000457 | 2.47428 | 2.4752 | 0.017881 | 0.001847 | 14.490496 | 140.366089 | 14.496046 | 4F
4F | 150m15 - cold formed purlin :5,SHE-13.STEEL.dgn,Design Model:125169 | 4.03635 | 0.000457 | 2.47428 | 2.4752 | 0.017881 | 0.001847 | 14.490496 | 140.366089 | 14.496046 | 4F
4F | 150m15 - cold formed purlin :5,SHE-13.STEEL.dgn,Design Model:125171 | 4.03635 | 0.000457 | 2.47428 | 2.4752 | 0.017881 | 0.001847 | 14.490496 | 140.366089 | 14.496046 | 4F
4F | 150m15 - cold formed purlin :5,SHE-13.STEEL.dgn,Design Model:125173 | 4.03635 | 0.000457 | 2.47428 | 2.4752 | 0.017881 | 0.001847 | 14.490496 | 140.366089 | 14.496046 | 4F
4F | 150m15 - cold formed purlin :5,SHE-13.STEEL.dgn,Design Model:125175 | 4.03635 | 0.000457 | 2.47428 | 2.4752 | 0.017881 | 0.001847 | 14.490496 | 140.366089 | 14.496046 | 4F
4F | 150m15 - cold formed purlin :5,SHE-13.STEEL.dgn,Design Model:125177 | 4.03635 | 0.000457 | 2.47428 | 2.4752 | 0.017881 | 0.001847 | 14.490496 | 140.366089 | 14.496046 | 4F
4F | 150m15 - cold formed purlin :5,SHE-13.STEEL.dgn,Design Model:125179 | 4.03635 | 0.000457 | 2.47428 | 2.4752 | 0.017881 | 0.001847 | 14.490496 | 140.366089 | 14.496046 | 4F
4F | 150m15 - cold formed purlin :5,SHE-13.STEEL.dgn,Design Model:125181 | 4.03635 | 0.000457 | 2.47428 | 2.4752 | 0.017881 | 0.001847 | 14.490496 | 140.366089 | 14.496046 | 4F
4F | 150m15 - cold formed purlin :5,SHE-13.STEEL.dgn,Design Model:125183 | 4.03635 | 0.000457 | 2.47428 | 2.4752 | 0.017881 | 0.001847 | 14.490496 | 140.366089 | 14.496046 | 4F
RP | 150m15 - cold formed purlin :5,SHE-13.STEEL.dgn,Design Model:125316 | 1.15342 | 0.000457 | 0.707047 | 0.707962 | 0.00511 | 0.000528 | 4.140784 | 40.110816 | 4.142370 | RP
RP | 150m15 - cold formed purlin :5,SHE-13.STEEL.dgn,Design Model:125318 | 1.15342 | 0.000457 | 0.707047 | 0.707962 | 0.00511 | 0.000528 | 4.140784 | 40.110816 | 4.142370 | RP
RP | 150m15 - cold formed purlin :5,SHE-13.STEEL.dgn,Design Model:125320 | 1.15342 | 0.000457 | 0.707047 | 0.707962 | 0.00511 | 0.000528 | 4.140784 | 40.110816 | 4.142370 | RP
RP | 150m15 - cold formed purlin :5,SHE-13.STEEL.dgn,Design Model:125322 | 1.15342 | 0.000457 | 0.707047 | 0.707962 | 0.00511 | 0.000528 | 4.140784 | 40.110816 | 4.142370 | RP
RP | 150m15 - cold formed purlin :5,SHE-13.STEEL.dgn,Design Model:125324 | 1.15342 | 0.000457 | 0.707047 | 0.707962 | 0.00511 | 0.000528 | 4.140784 | 40.110816 | 4.142370 | RP
RP | 150m15 - cold formed purlin :5,SHE-13.STEEL.dgn,Design Model:125326 | 2.1776 | 0.000457 | 1.33487 | 1.33578 | 0.009647 | 0.000996 | 7.817584 | 75.727129 | 7.820578 | RP
RP | 150m15 - cold formed purlin :5,SHE-13.STEEL.dgn,Design Model:125328 | 2.1776 | 0.000457 | 1.33487 | 1.33578 | 0.009647 | 0.000996 | 7.817584 | 75.727129 | 7.820578 | RP
RP | 150m15 - cold formed purlin :5,SHE-13.STEEL.dgn,Design Model:125330 | 2.1776 | 0.000457 | 1.33487 | 1.33578 | 0.009647 | 0.000996 | 7.817584 | 75.727129 | 7.820578 | RP
RP | 150m15 - cold formed purlin :5,SHE-13.STEEL.dgn,Design Model:125332 | 2.1776 | 0.000457 | 1.33487 | 1.33578 | 0.009647 | 0.000996 | 7.817584 | 75.727129 | 7.820578 | RP
RP | 150m15 - cold formed purlin :5,SHE-13.STEEL.dgn,Design Model:125334 | 2.1776 | 0.000457 | 1.33487 | 1.33578 | 0.009647 | 0.000996 | 7.817584 | 75.727129 | 7.820578 | RP
RP | 150m15 - cold formed purlin :5,SHE-13.STEEL.dgn,Design Model:125336 | 2.1776 | 0.000457 | 1.33487 | 1.33578 | 0.009647 | 0.000996 | 7.817584 | 75.727129 | 7.820578 | RP
RP | 150m15 - cold formed purlin :5,SHE-13.STEEL.dgn,Design Model:125338 | 2.1776 | 0.000457 | 1.33487 | 1.33578 | 0.009647 | 0.000996 | 7.817584 | 75.727129 | 7.820578 | RP
RP | 150m15 - cold formed purlin :5,SHE-13.STEEL.dgn,Design Model:125340 | 2.1776 | 0.000457 | 1.33487 | 1.33578 | 0.009647 | 0.000996 | 7.817584 | 75.727129 | 7.820578 | RP
RP | 150m15 - cold formed purlin :5,SHE-13.STEEL.dgn,Design Model:125342 | 2.1776 | 0.000457 | 1.33487 | 1.33578 | 0.009647 | 0.000996 | 7.817584 | 75.727129 | 7.820578 | RP
RP | 150m15 - cold formed purlin :5,SHE-13.STEEL.dgn,Design Model:125344 | 1.15342 | 0.000457 | 0.707047 | 0.707962 | 0.00511 | 0.000528 | 4.140784 | 40.110816 | 4.142370 | RP
RP | 150m15 - cold formed purlin :5,SHE-13.STEEL.dgn,Design Model:125346 | 1.15342 | 0.000457 | 0.707047 | 0.707962 | 0.00511 | 0.000528 | 4.140784 | 40.110816 | 4.142370 | RP
RP | 150m15 - cold formed purlin :5,SHE-13.STEEL.dgn,Design Model:125348 | 1.15342 | 0.000457 | 0.707047 | 0.707962 | 0.00511 | 0.000528 | 4.140784 | 40.110816 | 4.142370 | RP
RP | 150m15 - cold formed purlin :5,SHE-13.STEEL.dgn,Design Model:125350 | 1.15342 | 0.000457 | 0.707047 | 0.707962 | 0.00511 | 0.000528 | 4.140784 | 40.110816 | 4.142370 | RP
RP | 150m15 - cold formed purlin :5,SHE-13.STEEL.dgn,Design Model:125352 | 1.15342 | 0.000457 | 0.707047 | 0.707962 | 0.00511 | 0.000528 | 4.140784 | 40.110816 | 4.142370 | RP
RP | 150m15 - cold formed purlin :5,SHE-13.STEEL.dgn,Design Model:125354 | 1.15342 | 0.000457 | 0.707047 | 0.707962 | 0.00511 | 0.000528 | 4.140784 | 40.110816 | 4.142370 | RP
RP | 150m15 - cold formed purlin :5,SHE-13.STEEL.dgn,Design Model:125356 | 1.15342 | 0.000457 | 0.707047 | 0.707962 | 0.00511 | 0.000528 | 4.140784 | 40.110816 | 4.142370 | RP
RP | 150m15 - cold formed purlin :5,SHE-13.STEEL.dgn,Design Model:125358 | 1.15342 | 0.000457 | 0.707047 | 0.707962 | 0.00511 | 0.000528 | 4.140784 | 40.110816 | 4.142370 | RP
RP | 150m15 - cold formed purlin :5,SHE-13.STEEL.dgn,Design Model:125360 | 1.15342 | 0.000457 | 0.707047 | 0.707962 | 0.00511 | 0.000528 | 4.140784 | 40.110816 | 4.142370 | RP
RP | 150m15 - cold formed purlin :5,SHE-13.STEEL.dgn,Design Model:125362 | 1.15342 | 0.000457 | 0.707047 | 0.707962 | 0.00511 | 0.000528 | 4.140784 | 40.110816 | 4.142370 | RP
RP | 150m15 - cold formed purlin :5,SHE-13.STEEL.dgn,Design Model:125364 | 1.15342 | 0.000457 | 0.707047 | 0.707962 | 0.00511 | 0.000528 | 4.140784 | 40.110816 | 4.142370 | RP
RP | 150m15 - cold formed purlin :5,SHE-13.STEEL.dgn,Design Model:125366 | 2.4936 | 0.000457 | 1.52858 | 1.52949 | 0.011047 | 0.001141 | 8.952024 | 86.716187 | 8.955453 | RP
RP | 150m15 - cold formed purlin :5,SHE-13.STEEL.dgn,Design Model:125368 | 2.4936 | 0.000457 | 1.52858 | 1.52949 | 0.011047 | 0.001141 | 8.952024 | 86.716187 | 8.955453 | RP
RP | 150m15 - cold formed purlin :5,SHE-13.STEEL.dgn,Design Model:125370 | 2.4936 | 0.000457 | 1.52858 | 1.52949 | 0.011047 | 0.001141 | 8.952024 | 86.716187 | 8.955453 | RP
RP | 150m15 - cold formed purlin :5,SHE-13.STEEL.dgn,Design Model:125372 | 2.4936 | 0.000457 | 1.52858 | 1.52949 | 0.011047 | 0.001141 | 8.952024 | 86.716187 | 8.955453 | RP
RP | 150m15 - cold formed purlin :5,SHE-13.STEEL.dgn,Design Model:125374 | 2.4936 | 0.000457 | 1.52858 | 1.52949 | 0.011047 | 0.001141 | 8.952024 | 86.716187 | 8.955453 | RP
RP | 150m15 - cold formed purlin :5,SHE-13.STEEL.dgn,Design Model:125376 | 2.4936 | 0.000457 | 1.52858 | 1.52949 | 0.011047 | 0.001141 | 8.952024 | 86.716187 | 8.955453 | RP
RP | 150m15 - cold formed purlin :5,SHE-13.STEEL.dgn,Design Model:125378 | 2.4936 | 0.000457 | 1.52858 | 1.52949 | 0.011047 | 0.001141 | 8.952024 | 86.716187 | 8.955453 | RP
RP | 150m15 - cold formed purlin :5,SHE-13.STEEL.dgn,Design Model:125380 | 2.4936 | 0.000457 | 1.52858 | 1.52949 | 0.011047 | 0.001141 | 8.952024 | 86.716187 | 8.955453 | RP
RP | 150m15 - cold formed purlin :5,SHE-13.STEEL.dgn,Design Model:125382 | 2.4936 | 0.000457 | 1.52858 | 1.52949 | 0.011047 | 0.001141 | 8.952024 | 86.716187 | 8.955453 | RP
RP | 150m15 - cold formed purlin :5,SHE-13.STEEL.dgn,Design Model:125384 | 2.4936 | 0.000457 | 1.52858 | 1.52949 | 0.011047 | 0.001141 | 8.952024 | 86.716187 | 8.955453 | RP
RP | 150m15 - cold formed purlin :5,SHE-13.STEEL.dgn,Design Model:125386 | 2.1776 | 0.000458 | 1.33487 | 1.33578 | 0.009647 | 0.000996 | 7.817584 | 75.727129 | 7.820578 | RP
RP | 150m15 - cold formed purlin :5,SHE-13.STEEL.dgn,Design Model:125388 | 2.1776 | 0.000458 | 1.33487 | 1.33578 | 0.009647 | 0.000996 | 7.817584 | 75.727129 | 7.820578 | RP
RP | 150m15 - cold formed purlin :5,SHE-13.STEEL.dgn,Design Model:125390 | 2.1776 | 0.000458 | 1.33487 | 1.33578 | 0.009647 | 0.000996 | 7.817584 | 75.727129 | 7.820578 | RP
RP | 150m15 - cold formed purlin :5,SHE-13.STEEL.dgn,Design Model:125392 | 2.1776 | 0.000458 | 1.33487 | 1.33578 | 0.009647 | 0.000996 | 7.817584 | 75.727129 | 7.820578 | RP
RP | 150m15 - cold formed purlin :5,SHE-13.STEEL.dgn,Design Model:125394 | 2.1776 | 0.000458 | 1.33487 | 1.33578 | 0.009647 | 0.000996 | 7.817584 | 75.727129 | 7.820578 | RP
RP | 150m15 - cold formed purlin :5,SHE-13.STEEL.dgn,Design Model:125396 | 2.1776 | 0.000458 | 1.33487 | 1.33578 | 0.009647 | 0.000996 | 7.817584 | 75.727129 | 7.820578 | RP
RP | 150m15 - cold formed purlin :5,SHE-13.STEEL.dgn,Design Model:125398 | 2.1776 | 0.000458 | 1.33487 | 1.33578 | 0.009647 | 0.000996 | 7.817584 | 75.727129 | 7.820578 | RP
RP | 150m15 - cold formed purlin :5,SHE-13.STEEL.dgn,Design Model:125400 | 2.1776 | 0.000458 | 1.33487 | 1.33578 | 0.009647 | 0.000996 | 7.817584 | 75.727129 | 7.820578 | RP
RP | 150m15 - cold formed purlin :5,SHE-13.STEEL.dgn,Design Model:125402 | 2.1776 | 0.000458 | 1.33487 | 1.33578 | 0.009647 | 0.000996 | 7.817584 | 75.727129 | 7.820578 | RP
RP | 150m15 - cold formed purlin :5,SHE-13.STEEL.dgn,Design Model:125404 | 2.179 | 0.000457 | 1.33573 | 1.33664 | 0.009653 | 0.000997 | 7.822610 | 75.775815 | 7.825606 | RP
RP | 150m15 - cold formed purlin :5,SHE-13.STEEL.dgn,Design Model:125406 | 2.179 | 0.000457 | 1.33573 | 1.33664 | 0.009653 | 0.000997 | 7.822610 | 75.775815 | 7.825606 | RP
RP | 150m15 - cold formed purlin :5,SHE-13.STEEL.dgn,Design Model:125408 | 2.179 | 0.000457 | 1.33573 | 1.33664 | 0.009653 | 0.000997 | 7.822610 | 75.775815 | 7.825606 | RP
RP | 150m15 - cold formed purlin :5,SHE-13.STEEL.dgn,Design Model:125410 | 2.179 | 0.000457 | 1.33573 | 1.33664 | 0.009653 | 0.000997 | 7.822610 | 75.775815 | 7.825606 | RP
RP | 150m15 - cold formed purlin :5,SHE-13.STEEL.dgn,Design Model:125412 | 2.179 | 0.000457 | 1.33573 | 1.33664 | 0.009653 | 0.000997 | 7.822610 | 75.775815 | 7.825606 | RP
RP | 150m15 - cold formed purlin :5,SHE-13.STEEL.dgn,Design Model:125414 | 2.179 | 0.000457 | 1.33573 | 1.33664 | 0.009653 | 0.000997 | 7.822610 | 75.775815 | 7.825606 | RP
RP | 150m15 - cold formed purlin :5,SHE-13.STEEL.dgn,Design Model:125416 | 2.179 | 0.000457 | 1.33573 | 1.33664 | 0.009653 | 0.000997 | 7.822610 | 75.775815 | 7.825606 | RP
RP | 150m15 - cold formed purlin :5,SHE-13.STEEL.dgn,Design Model:125418 | 2.179 | 0.000457 | 1.33573 | 1.33664 | 0.009653 | 0.000997 | 7.822610 | 75.775815 | 7.825606 | RP
RP | 150m15 - cold formed purlin :5,SHE-13.STEEL.dgn,Design Model:125420 | 2.179 | 0.000457 | 1.33573 | 1.33664 | 0.009653 | 0.000997 | 7.822610 | 75.775815 | 7.825606 | RP
RP | 150m15 - cold formed purlin :5,SHE-13.STEEL.dgn,Design Model:125422 | 2.179 | 0.000458 | 1.33573 | 1.33664 | 0.009653 | 0.000997 | 7.822610 | 75.775815 | 7.825606 | RP
RP | 150m15 - cold formed purlin :5,SHE-13.STEEL.dgn,Design Model:125424 | 2.179 | 0.000458 | 1.33573 | 1.33664 | 0.009653 | 0.000997 | 7.822610 | 75.775815 | 7.825606 | RP
RP | 150m15 - cold formed purlin :5,SHE-13.STEEL.dgn,Design Model:125426 | 2.179 | 0.000458 | 1.33573 | 1.33664 | 0.009653 | 0.000997 | 7.822610 | 75.775815 | 7.825606 | RP
RP | 150m15 - cold formed purlin :5,SHE-13.STEEL.dgn,Design Model:125428 | 2.179 | 0.000458 | 1.33573 | 1.33664 | 0.009653 | 0.000997 | 7.822610 | 75.775815 | 7.825606 | RP
RP | 150m15 - cold formed purlin :5,SHE-13.STEEL.dgn,Design Model:125430 | 2.179 | 0.000458 | 1.33573 | 1.33664 | 0.009653 | 0.000997 | 7.822610 | 75.775815 | 7.825606 | RP
RP | 150m15 - cold formed purlin :5,SHE-13.STEEL.dgn,Design Model:125432 | 2.179 | 0.000458 | 1.33573 | 1.33664 | 0.009653 | 0.000997 | 7.822610 | 75.775815 | 7.825606 | RP
RP | 150m15 - cold formed purlin :5,SHE-13.STEEL.dgn,Design Model:125434 | 2.179 | 0.000458 | 1.33573 | 1.33664 | 0.009653 | 0.000997 | 7.822610 | 75.775815 | 7.825606 | RP
RP | 150m15 - cold formed purlin :5,SHE-13.STEEL.dgn,Design Model:125436 | 2.179 | 0.000458 | 1.33573 | 1.33664 | 0.009653 | 0.000997 | 7.822610 | 75.775815 | 7.825606 | RP
RP | 150m15 - cold formed purlin :5,SHE-13.STEEL.dgn,Design Model:125438 | 2.179 | 0.000458 | 1.33573 | 1.33664 | 0.009653 | 0.000997 | 7.822610 | 75.775815 | 7.825606 | RP
RP | 150m15 - cold formed purlin :5,SHE-13.STEEL.dgn,Design Model:125440 | 2.179 | 0.000458 | 1.33573 | 1.33664 | 0.009653 | 0.000997 | 7.822610 | 75.775815 | 7.825606 | RP
RP | 150m15 - cold formed purlin :5,SHE-13.STEEL.dgn,Design Model:125442 | 2.1776 | 0.000458 | 1.33487 | 1.33578 | 0.009647 | 0.000996 | 7.817584 | 75.727129 | 7.820578 | RP
RP | 150m15 - cold formed purlin :5,SHE-13.STEEL.dgn,Design Model:125444 | 2.1776 | 0.000458 | 1.33487 | 1.33578 | 0.009647 | 0.000996 | 7.817584 | 75.727129 | 7.820578 | RP
RP | 150m15 - cold formed purlin :5,SHE-13.STEEL.dgn,Design Model:125446 | 2.1776 | 0.000458 | 1.33487 | 1.33578 | 0.009647 | 0.000996 | 7.817584 | 75.727129 | 7.820578 | RP
RP | 150m15 - cold formed purlin :5,SHE-13.STEEL.dgn,Design Model:125448 | 2.1776 | 0.000458 | 1.33487 | 1.33578 | 0.009647 | 0.000996 | 7.817584 | 75.727129 | 7.820578 | RP
RP | 150m15 - cold formed purlin :5,SHE-13.STEEL.dgn,Design Model:125450 | 2.1776 | 0.000458 | 1.33487 | 1.33578 | 0.009647 | 0.000996 | 7.817584 | 75.727129 | 7.820578 | RP
RP | 150m15 - cold formed purlin :5,SHE-13.STEEL.dgn,Design Model:125452 | 2.1776 | 0.000458 | 1.33487 | 1.33578 | 0.009647 | 0.000996 | 7.817584 | 75.727129 | 7.820578 | RP
RP | 150m15 - cold formed purlin :5,SHE-13.STEEL.dgn,Design Model:125454 | 2.1776 | 0.000458 | 1.33487 | 1.33578 | 0.009647 | 0.000996 | 7.817584 | 75.727129 | 7.820578 | RP
RP | 150m15 - cold formed purlin :5,SHE-13.STEEL.dgn,Design Model:125456 | 2.1776 | 0.000458 | 1.33487 | 1.33578 | 0.009647 | 0.000996 | 7.817584 | 75.727129 | 7.820578 | RP
RP | 150m15 - cold formed purlin :5,SHE-13.STEEL.dgn,Design Model:125458 | 2.1776 | 0.000458 | 1.33487 | 1.33578 | 0.009647 | 0.000996 | 7.817584 | 75.727129 | 7.820578 | RP
RP | 150m15 - cold formed purlin :5,SHE-13.STEEL.dgn,Design Model:125460 | 2.1776 | 0.000458 | 1.33487 | 1.33578 | 0.009647 | 0.000996 | 7.817584 | 75.727129 | 7.820578 | RP
RP | 150m15 - cold formed purlin :5,SHE-13.STEEL.dgn,Design Model:125462 | 1.13364 | 0.000457 | 0.694919 | 0.695834 | 0.005022 | 0.000519 | 4.069754 | 39.422768 | 4.071313 | RP
RP | 150m15 - cold formed purlin :5,SHE-13.STEEL.dgn,Design Model:125464 | 1.13364 | 0.000457 | 0.694919 | 0.695834 | 0.005022 | 0.000519 | 4.069754 | 39.422768 | 4.071313 | RP
RP | 150m15 - cold formed purlin :5,SHE-13.STEEL.dgn,Design Model:125466 | 1.13364 | 0.000457 | 0.694919 | 0.695834 | 0.005022 | 0.000519 | 4.069754 | 39.422768 | 4.071313 | RP
RP | 150m15 - cold formed purlin :5,SHE-13.STEEL.dgn,Design Model:125468 | 1.13364 | 0.000457 | 0.694919 | 0.695834 | 0.005022 | 0.000519 | 4.069754 | 39.422768 | 4.071313 | RP
RP | 150m15 - cold formed purlin :5,SHE-13.STEEL.dgn,Design Model:125470 | 1.13364 | 0.000457 | 0.694919 | 0.695834 | 0.005022 | 0.000519 | 4.069754 | 39.422768 | 4.071313 | RP
RP | 150m15 - cold formed purlin :5,SHE-13.STEEL.dgn,Design Model:125472 | 1.13364 | 0.000457 | 0.694919 | 0.695834 | 0.005022 | 0.000519 | 4.069754 | 39.422768 | 4.071313 | RP
RP | 150m15 - cold formed purlin :5,SHE-13.STEEL.dgn,Design Model:125474 | 1.13364 | 0.000457 | 0.694919 | 0.695834 | 0.005022 | 0.000519 | 4.069754 | 39.422768 | 4.071313 | RP
RP | 150m15 - cold formed purlin :5,SHE-13.STEEL.dgn,Design Model:125476 | 1.13364 | 0.000457 | 0.694919 | 0.695834 | 0.005022 | 0.000519 | 4.069754 | 39.422768 | 4.071313 | RP
RP | 150m15 - cold formed purlin :5,SHE-13.STEEL.dgn,Design Model:125478 | 1.13364 | 0.000457 | 0.694919 | 0.695834 | 0.005022 | 0.000519 | 4.069754 | 39.422768 | 4.071313 | RP
RP | 150m15 - cold formed purlin :5,SHE-13.STEEL.dgn,Design Model:125480 | 1.13364 | 0.000457 | 0.694919 | 0.695834 | 0.005022 | 0.000519 | 4.069754 | 39.422768 | 4.071313 | RP
RP | 150m15 - cold formed purlin :5,SHE-13.STEEL.dgn,Design Model:125482 | 1.13364 | 0.000457 | 0.694919 | 0.695834 | 0.005022 | 0.000519 | 4.069754 | 39.422768 | 4.071313 | RP
RP | 150m15 - cold formed purlin :5,SHE-13.STEEL.dgn,Design Model:125484 | 2.4936 | 0.000457 | 1.52858 | 1.52949 | 0.011047 | 0.001141 | 8.952024 | 86.716187 | 8.955453 | RP
RP | 150m15 - cold formed purlin :5,SHE-13.STEEL.dgn,Design Model:125486 | 2.4936 | 0.000457 | 1.52858 | 1.52949 | 0.011047 | 0.001141 | 8.952024 | 86.716187 | 8.955453 | RP
RP | 150m15 - cold formed purlin :5,SHE-13.STEEL.dgn,Design Model:125488 | 2.4936 | 0.000457 | 1.52858 | 1.52949 | 0.011047 | 0.001141 | 8.952024 | 86.716187 | 8.955453 | RP
RP | 150m15 - cold formed purlin :5,SHE-13.STEEL.dgn,Design Model:125490 | 2.4936 | 0.000457 | 1.52858 | 1.52949 | 0.011047 | 0.001141 | 8.952024 | 86.716187 | 8.955453 | RP
RP | 150m15 - cold formed purlin :5,SHE-13.STEEL.dgn,Design Model:125492 | 2.4936 | 0.000457 | 1.52858 | 1.52949 | 0.011047 | 0.001141 | 8.952024 | 86.716187 | 8.955453 | RP
RP | 150m15 - cold formed purlin :5,SHE-13.STEEL.dgn,Design Model:125494 | 2.4936 | 0.000457 | 1.52858 | 1.52949 | 0.011047 | 0.001141 | 8.952024 | 86.716187 | 8.955453 | RP
RP | 150m15 - cold formed purlin :5,SHE-13.STEEL.dgn,Design Model:125496 | 2.4936 | 0.000457 | 1.52858 | 1.52949 | 0.011047 | 0.001141 | 8.952024 | 86.716187 | 8.955453 | RP
RP | 150m15 - cold formed purlin :5,SHE-13.STEEL.dgn,Design Model:125498 | 2.4936 | 0.000457 | 1.52858 | 1.52949 | 0.011047 | 0.001141 | 8.952024 | 86.716187 | 8.955453 | RP
RP | 150m15 - cold formed purlin :5,SHE-13.STEEL.dgn,Design Model:125500 | 2.4936 | 0.000457 | 1.52858 | 1.52949 | 0.011047 | 0.001141 | 8.952024 | 86.716187 | 8.955453 | RP
RP | 150m15 - cold formed purlin :5,SHE-13.STEEL.dgn,Design Model:125502 | 2.4936 | 0.000457 | 1.52858 | 1.52949 | 0.011047 | 0.001141 | 8.952024 | 86.716187 | 8.955453 | RP
RP | 150m15 - cold formed purlin :5,SHE-13.STEEL.dgn,Design Model:125504 | 2.1776 | 0.000457 | 1.33487 | 1.33578 | 0.009647 | 0.000996 | 7.817584 | 75.727129 | 7.820578 | RP
RP | 150m15 - cold formed purlin :5,SHE-13.STEEL.dgn,Design Model:125506 | 2.1776 | 0.000457 | 1.33487 | 1.33578 | 0.009647 | 0.000996 | 7.817584 | 75.727129 | 7.820578 | RP
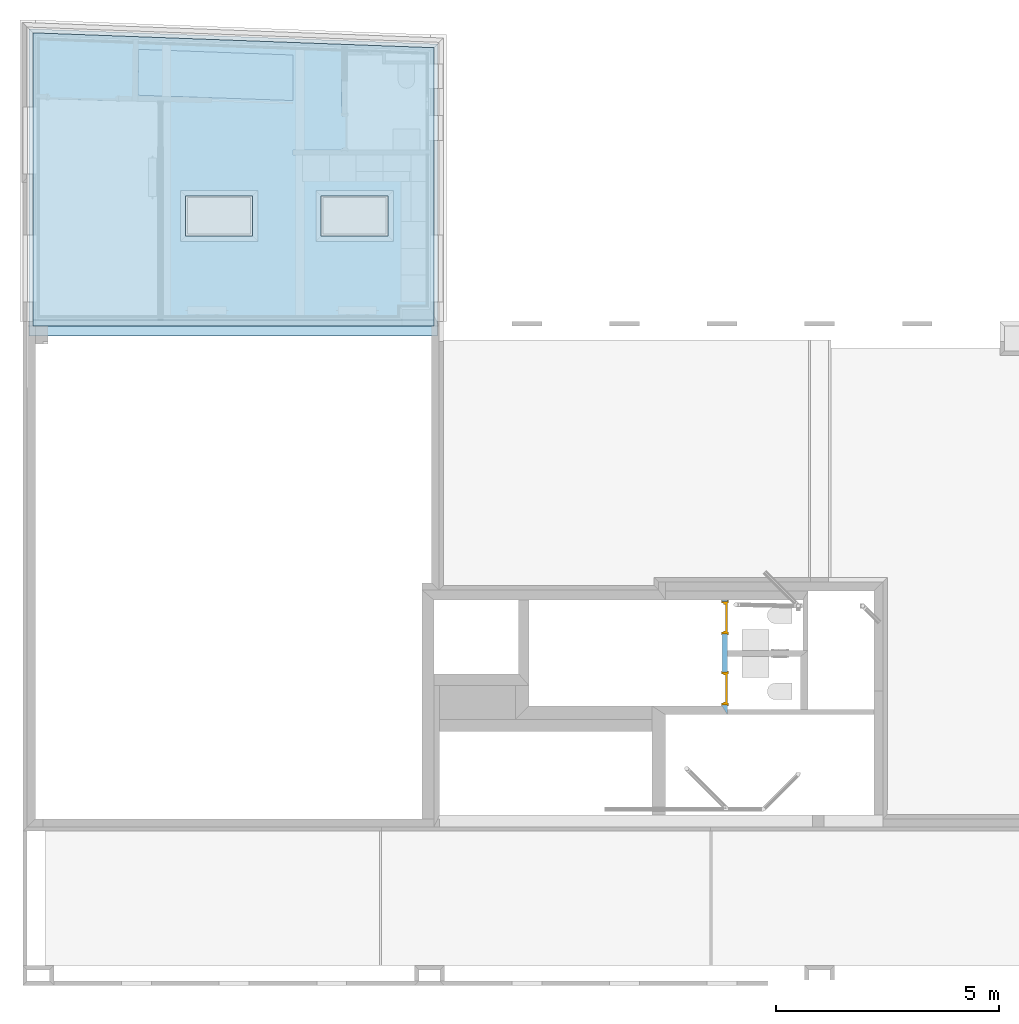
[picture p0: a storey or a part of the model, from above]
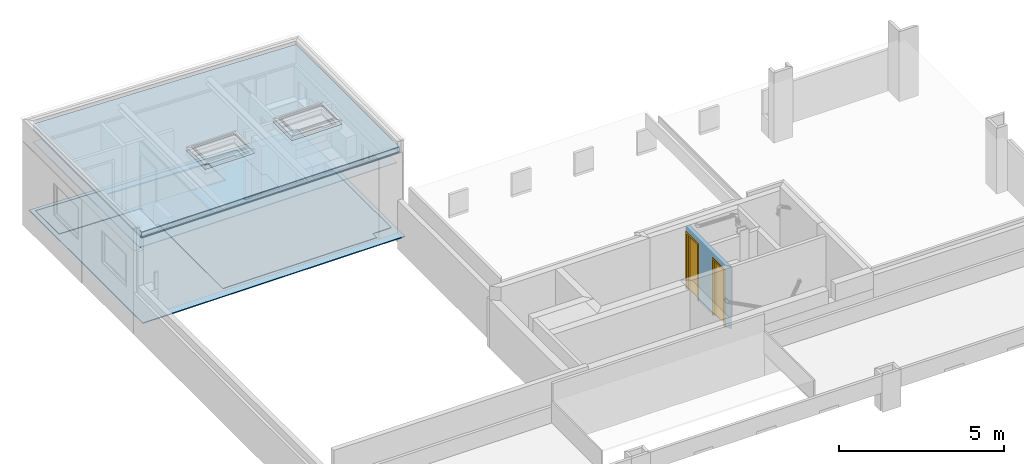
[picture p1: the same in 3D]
Properties of the parts of a building model (IFC2X3), part 4 of 16

# IfcBeam: SHE_A-Beams-Steel-Purlin_150m15 (639)
Name | Description | Length (m) | Area | Cross-sectional Modeled (m2) | Area | Side Surfaces Modeled (Gross) (m2) | Area | All Surfaces Modeled (Net) (m2) | Volume (Gross) (m3) = Volume (Net) (m3) | Volume (Gross Modeled) (m3) = Volume (Net Modeled) (m3) | Length x Unit Weight | Volume (Gross) x Density = Volume (Net) x Density | Volume (Gross Modeled) x Density = Volume (Net Modeled) x Density | ID | Number
RP | 150m15 - cold formed purlin :5,SHE-13.STEEL.dgn,Design Model:125508 | 2.1776 | 0.000457 | 1.33487 | 1.33578 | 0.009647 | 0.000996 | 7.817584 | 75.727129 | 7.820578 | RP
RP | 150m15 - cold formed purlin :5,SHE-13.STEEL.dgn,Design Model:125510 | 2.1776 | 0.000457 | 1.33487 | 1.33578 | 0.009647 | 0.000996 | 7.817584 | 75.727129 | 7.820578 | RP
RP | 150m15 - cold formed purlin :5,SHE-13.STEEL.dgn,Design Model:125512 | 2.1776 | 0.000457 | 1.33487 | 1.33578 | 0.009647 | 0.000996 | 7.817584 | 75.727129 | 7.820578 | RP
RP | 150m15 - cold formed purlin :5,SHE-13.STEEL.dgn,Design Model:125514 | 2.1776 | 0.000457 | 1.33487 | 1.33578 | 0.009647 | 0.000996 | 7.817584 | 75.727129 | 7.820578 | RP
RP | 150m15 - cold formed purlin :5,SHE-13.STEEL.dgn,Design Model:125516 | 2.1776 | 0.000457 | 1.33487 | 1.33578 | 0.009647 | 0.000996 | 7.817584 | 75.727129 | 7.820578 | RP
RP | 150m15 - cold formed purlin :5,SHE-13.STEEL.dgn,Design Model:125518 | 2.1776 | 0.000457 | 1.33487 | 1.33578 | 0.009647 | 0.000996 | 7.817584 | 75.727129 | 7.820578 | RP
RP | 150m15 - cold formed purlin :5,SHE-13.STEEL.dgn,Design Model:125520 | 2.1776 | 0.000457 | 1.33487 | 1.33578 | 0.009647 | 0.000996 | 7.817584 | 75.727129 | 7.820578 | RP
RP | 150m15 - cold formed purlin :5,SHE-13.STEEL.dgn,Design Model:125522 | 1.13364 | 0.000457 | 0.694919 | 0.695834 | 0.005022 | 0.000519 | 4.069754 | 39.422768 | 4.071313 | RP
RP | 150m15 - cold formed purlin :5,SHE-13.STEEL.dgn,Design Model:125524 | 1.13364 | 0.000457 | 0.694919 | 0.695834 | 0.005022 | 0.000519 | 4.069754 | 39.422768 | 4.071313 | RP
RP | 150m15 - cold formed purlin :5,SHE-13.STEEL.dgn,Design Model:125526 | 1.13364 | 0.000457 | 0.694919 | 0.695834 | 0.005022 | 0.000519 | 4.069754 | 39.422768 | 4.071313 | RP
RP | 150m15 - cold formed purlin :5,SHE-13.STEEL.dgn,Design Model:125528 | 1.13364 | 0.000457 | 0.694919 | 0.695834 | 0.005022 | 0.000519 | 4.069754 | 39.422768 | 4.071313 | RP
RP | 150m15 - cold formed purlin :5,SHE-13.STEEL.dgn,Design Model:125530 | 1.13364 | 0.000457 | 0.694919 | 0.695834 | 0.005022 | 0.000519 | 4.069754 | 39.422768 | 4.071313 | RP
RP | 150m15 - cold formed purlin :5,SHE-13.STEEL.dgn,Design Model:125532 | 1.13364 | 0.000457 | 0.694919 | 0.695834 | 0.005022 | 0.000519 | 4.069754 | 39.422768 | 4.071313 | RP
RP | 150m15 - cold formed purlin :5,SHE-13.STEEL.dgn,Design Model:125534 | 2.179 | 0.000458 | 1.33573 | 1.33664 | 0.009653 | 0.000997 | 7.822610 | 75.775814 | 7.825606 | RP
RP | 150m15 - cold formed purlin :5,SHE-13.STEEL.dgn,Design Model:125536 | 2.179 | 0.000458 | 1.33573 | 1.33664 | 0.009653 | 0.000997 | 7.822610 | 75.775814 | 7.825606 | RP
RP | 150m15 - cold formed purlin :5,SHE-13.STEEL.dgn,Design Model:125538 | 2.179 | 0.000458 | 1.33573 | 1.33664 | 0.009653 | 0.000997 | 7.822610 | 75.775814 | 7.825606 | RP
RP | 150m15 - cold formed purlin :5,SHE-13.STEEL.dgn,Design Model:125540 | 2.179 | 0.000458 | 1.33573 | 1.33664 | 0.009653 | 0.000997 | 7.822610 | 75.775814 | 7.825606 | RP
RP | 150m15 - cold formed purlin :5,SHE-13.STEEL.dgn,Design Model:125542 | 2.179 | 0.000458 | 1.33573 | 1.33664 | 0.009653 | 0.000997 | 7.822610 | 75.775814 | 7.825606 | RP
RP | 150m15 - cold formed purlin :5,SHE-13.STEEL.dgn,Design Model:125544 | 2.179 | 0.000458 | 1.33573 | 1.33664 | 0.009653 | 0.000997 | 7.822610 | 75.775814 | 7.825606 | RP
RP | 150m15 - cold formed purlin :5,SHE-13.STEEL.dgn,Design Model:125546 | 2.179 | 0.000458 | 1.33573 | 1.33664 | 0.009653 | 0.000997 | 7.822610 | 75.775814 | 7.825606 | RP
RP | 150m15 - cold formed purlin :5,SHE-13.STEEL.dgn,Design Model:125548 | 2.179 | 0.000458 | 1.33573 | 1.33664 | 0.009653 | 0.000997 | 7.822610 | 75.775814 | 7.825606 | RP
RP | 150m15 - cold formed purlin :5,SHE-13.STEEL.dgn,Design Model:125550 | 2.179 | 0.000458 | 1.33573 | 1.33664 | 0.009653 | 0.000997 | 7.822610 | 75.775814 | 7.825606 | RP
RP | 150m15 - cold formed purlin :5,SHE-13.STEEL.dgn,Design Model:125552 | 2.179 | 0.000458 | 1.33573 | 1.33664 | 0.009653 | 0.000997 | 7.822610 | 75.775814 | 7.825606 | RP
RP | 150m15 - cold formed purlin :5,SHE-13.STEEL.dgn,Design Model:125554 | 1.7164 | 0.000457 | 1.05215 | 1.05307 | 0.007604 | 0.000785 | 6.161876 | 59.688668 | 6.164236 | RP
RP | 150m15 - cold formed purlin :5,SHE-13.STEEL.dgn,Design Model:125556 | 1.7164 | 0.000457 | 1.05215 | 1.05307 | 0.007604 | 0.000785 | 6.161876 | 59.688668 | 6.164236 | RP
RP | 150m15 - cold formed purlin :5,SHE-13.STEEL.dgn,Design Model:125558 | 1.7164 | 0.000457 | 1.05215 | 1.05307 | 0.007604 | 0.000785 | 6.161876 | 59.688668 | 6.164236 | RP
RP | 150m15 - cold formed purlin :5,SHE-13.STEEL.dgn,Design Model:125560 | 1.7164 | 0.000457 | 1.05215 | 1.05307 | 0.007604 | 0.000785 | 6.161876 | 59.688668 | 6.164236 | RP
RP | 150m15 - cold formed purlin :5,SHE-13.STEEL.dgn,Design Model:125562 | 0.5764 | 0.000457 | 0.353333 | 0.354248 | 0.002553 | 0.000264 | 2.069276 | 20.044598 | 2.070069 | RP
RP | 150m15 - cold formed purlin :5,SHE-13.STEEL.dgn,Design Model:125564 | 0.5764 | 0.000457 | 0.353333 | 0.354248 | 0.002553 | 0.000264 | 2.069276 | 20.044598 | 2.070069 | RP
RP | 150m15 - cold formed purlin :5,SHE-13.STEEL.dgn,Design Model:125566 | 0.5764 | 0.000457 | 0.353333 | 0.354248 | 0.002553 | 0.000264 | 2.069276 | 20.044598 | 2.070069 | RP
RP | 150m15 - cold formed purlin :5,SHE-13.STEEL.dgn,Design Model:125568 | 0.5764 | 0.000457 | 0.353333 | 0.354248 | 0.002553 | 0.000264 | 2.069276 | 20.044598 | 2.070069 | RP
RP | 150m15 - cold formed purlin :5,SHE-13.STEEL.dgn,Design Model:125570 | 1.1464 | 0.000457 | 0.702743 | 0.703658 | 0.005079 | 0.000524 | 4.115576 | 39.866633 | 4.117152 | RP
RP | 150m15 - cold formed purlin :5,SHE-13.STEEL.dgn,Design Model:125572 | 1.1464 | 0.000457 | 0.702743 | 0.703658 | 0.005079 | 0.000524 | 4.115576 | 39.866633 | 4.117152 | RP
RP | 150m15 - cold formed purlin :5,SHE-13.STEEL.dgn,Design Model:125574 | 1.1464 | 0.000457 | 0.702743 | 0.703658 | 0.005079 | 0.000524 | 4.115576 | 39.866633 | 4.117152 | RP
RP | 150m15 - cold formed purlin :5,SHE-13.STEEL.dgn,Design Model:125576 | 1.1464 | 0.000457 | 0.702743 | 0.703658 | 0.005079 | 0.000524 | 4.115576 | 39.866633 | 4.117152 | RP
RP | 150m15 - cold formed purlin :5,SHE-13.STEEL.dgn,Design Model:125578 | 1.1464 | 0.000457 | 0.702743 | 0.703658 | 0.005079 | 0.000524 | 4.115576 | 39.866633 | 4.117152 | RP
RP | 150m15 - cold formed purlin :5,SHE-13.STEEL.dgn,Design Model:125580 | 1.1464 | 0.000457 | 0.702743 | 0.703658 | 0.005079 | 0.000524 | 4.115576 | 39.866633 | 4.117152 | RP
RP | 150m15 - cold formed purlin :5,SHE-13.STEEL.dgn,Design Model:125582 | 1.1464 | 0.000457 | 0.702743 | 0.703658 | 0.005079 | 0.000524 | 4.115576 | 39.866633 | 4.117152 | RP
RP | 150m15 - cold formed purlin :5,SHE-13.STEEL.dgn,Design Model:125584 | 1.1464 | 0.000457 | 0.702743 | 0.703658 | 0.005079 | 0.000524 | 4.115576 | 39.866633 | 4.117152 | RP
RP | 150m15 - cold formed purlin :5,SHE-13.STEEL.dgn,Design Model:125586 | 1.1464 | 0.000457 | 0.702743 | 0.703658 | 0.005079 | 0.000524 | 4.115576 | 39.866633 | 4.117152 | RP
RP | 150m15 - cold formed purlin :5,SHE-13.STEEL.dgn,Design Model:125588 | 1.1464 | 0.000457 | 0.702743 | 0.703658 | 0.005079 | 0.000524 | 4.115576 | 39.866633 | 4.117152 | RP
RP | 150m15 - cold formed purlin :5,SHE-13.STEEL.dgn,Design Model:125590 | 1.1464 | 0.000457 | 0.702743 | 0.703658 | 0.005079 | 0.000524 | 4.115576 | 39.866633 | 4.117152 | RP
RP | 150m15 - cold formed purlin :5,SHE-13.STEEL.dgn,Design Model:125592 | 1.1464 | 0.000457 | 0.702743 | 0.703658 | 0.005079 | 0.000524 | 4.115576 | 39.866633 | 4.117152 | RP
RP | 150m15 - cold formed purlin :5,SHE-13.STEEL.dgn,Design Model:125594 | 1.1464 | 0.000457 | 0.702743 | 0.703658 | 0.005079 | 0.000524 | 4.115576 | 39.866633 | 4.117152 | RP
RP | 150m15 - cold formed purlin :5,SHE-13.STEEL.dgn,Design Model:125596 | 1.1464 | 0.000457 | 0.702743 | 0.703658 | 0.005079 | 0.000524 | 4.115576 | 39.866633 | 4.117152 | RP
RP | 150m15 - cold formed purlin :5,SHE-13.STEEL.dgn,Design Model:125598 | 1.1464 | 0.000457 | 0.702743 | 0.703658 | 0.005079 | 0.000524 | 4.115576 | 39.866633 | 4.117152 | RP
RP | 150m15 - cold formed purlin :5,SHE-13.STEEL.dgn,Design Model:125600 | 1.1464 | 0.000457 | 0.702743 | 0.703658 | 0.005079 | 0.000524 | 4.115576 | 39.866633 | 4.117152 | RP
RP | 150m15 - cold formed purlin :5,SHE-13.STEEL.dgn,Design Model:125602 | 1.1464 | 0.000457 | 0.702743 | 0.703658 | 0.005079 | 0.000524 | 4.115576 | 39.866633 | 4.117152 | RP
RP | 150m15 - cold formed purlin :5,SHE-13.STEEL.dgn,Design Model:125604 | 1.1464 | 0.000457 | 0.702743 | 0.703658 | 0.005079 | 0.000524 | 4.115576 | 39.866633 | 4.117152 | RP
RP | 150m15 - cold formed purlin :5,SHE-13.STEEL.dgn,Design Model:125606 | 1.1464 | 0.000457 | 0.702743 | 0.703658 | 0.005079 | 0.000524 | 4.115576 | 39.866633 | 4.117152 | RP
RP | 150m15 - cold formed purlin :5,SHE-13.STEEL.dgn,Design Model:125608 | 1.1464 | 0.000457 | 0.702743 | 0.703658 | 0.005079 | 0.000524 | 4.115576 | 39.866633 | 4.117152 | RP
RP | 150m15 - cold formed purlin :5,SHE-13.STEEL.dgn,Design Model:125610 | 1.1464 | 0.000457 | 0.702743 | 0.703658 | 0.005079 | 0.000524 | 4.115576 | 39.866633 | 4.117152 | RP
RP | 150m15 - cold formed purlin :5,SHE-13.STEEL.dgn,Design Model:125612 | 1.1464 | 0.000457 | 0.702743 | 0.703658 | 0.005079 | 0.000524 | 4.115576 | 39.866633 | 4.117152 | RP
RP | 150m15 - cold formed purlin :5,SHE-13.STEEL.dgn,Design Model:125614 | 1.1464 | 0.000457 | 0.702743 | 0.703658 | 0.005079 | 0.000524 | 4.115576 | 39.866633 | 4.117152 | RP
RP | 150m15 - cold formed purlin :5,SHE-13.STEEL.dgn,Design Model:125616 | 1.1464 | 0.000457 | 0.702743 | 0.703658 | 0.005079 | 0.000524 | 4.115576 | 39.866633 | 4.117152 | RP
RP | 150m15 - cold formed purlin :5,SHE-13.STEEL.dgn,Design Model:125618 | 1.1464 | 0.000457 | 0.702743 | 0.703658 | 0.005079 | 0.000524 | 4.115576 | 39.866633 | 4.117152 | RP
RP | 150m15 - cold formed purlin :5,SHE-13.STEEL.dgn,Design Model:125620 | 1.1464 | 0.000457 | 0.702743 | 0.703658 | 0.005079 | 0.000524 | 4.115576 | 39.866633 | 4.117152 | RP
RP | 150m15 - cold formed purlin :5,SHE-13.STEEL.dgn,Design Model:125622 | 0.7764 | 0.000457 | 0.475933 | 0.476848 | 0.003439 | 0.000355 | 2.787276 | 26.999698 | 2.788344 | RP
RP | 150m15 - cold formed purlin :5,SHE-13.STEEL.dgn,Design Model:125624 | 2.179 | 0.000457 | 1.33573 | 1.33664 | 0.009653 | 0.000997 | 7.822610 | 75.775815 | 7.825606 | RP
RP | 150m15 - cold formed purlin :5,SHE-13.STEEL.dgn,Design Model:125626 | 2.179 | 0.000457 | 1.33573 | 1.33664 | 0.009653 | 0.000997 | 7.822610 | 75.775815 | 7.825606 | RP
RP | 150m15 - cold formed purlin :5,SHE-13.STEEL.dgn,Design Model:125628 | 2.179 | 0.000457 | 1.33573 | 1.33664 | 0.009653 | 0.000997 | 7.822610 | 75.775815 | 7.825606 | RP
RP | 150m15 - cold formed purlin :5,SHE-13.STEEL.dgn,Design Model:125630 | 2.179 | 0.000457 | 1.33573 | 1.33664 | 0.009653 | 0.000997 | 7.822610 | 75.775815 | 7.825606 | RP
RP | 150m15 - cold formed purlin :5,SHE-13.STEEL.dgn,Design Model:125632 | 2.179 | 0.000457 | 1.33573 | 1.33664 | 0.009653 | 0.000997 | 7.822610 | 75.775815 | 7.825606 | RP
RP | 150m15 - cold formed purlin :5,SHE-13.STEEL.dgn,Design Model:125634 | 2.179 | 0.000457 | 1.33573 | 1.33664 | 0.009653 | 0.000997 | 7.822610 | 75.775815 | 7.825606 | RP
RP | 150m15 - cold formed purlin :5,SHE-13.STEEL.dgn,Design Model:125636 | 2.179 | 0.000457 | 1.33573 | 1.33664 | 0.009653 | 0.000997 | 7.822610 | 75.775815 | 7.825606 | RP
RP | 150m15 - cold formed purlin :5,SHE-13.STEEL.dgn,Design Model:125638 | 2.179 | 0.000457 | 1.33573 | 1.33664 | 0.009653 | 0.000997 | 7.822610 | 75.775815 | 7.825606 | RP
4F | 150m15 - cold formed purlin :5,SHE-13.STEEL.dgn,Design Model:125897 | 0.7764 | 0.000457 | 0.475933 | 0.476848 | 0.003439 | 0.000355 | 2.787276 | 26.999698 | 2.788344 | 4F
4F | 150m15 - cold formed purlin :5,SHE-13.STEEL.dgn,Design Model:125899 | 0.7764 | 0.000457 | 0.475933 | 0.476848 | 0.003439 | 0.000355 | 2.787276 | 26.999698 | 2.788344 | 4F
4F | 150m15 - cold formed purlin :5,SHE-13.STEEL.dgn,Design Model:125901 | 0.7764 | 0.000457 | 0.475933 | 0.476848 | 0.003439 | 0.000355 | 2.787276 | 26.999698 | 2.788344 | 4F
4F | 150m15 - cold formed purlin :5,SHE-13.STEEL.dgn,Design Model:125903 | 0.7764 | 0.000457 | 0.475933 | 0.476848 | 0.003439 | 0.000355 | 2.787276 | 26.999698 | 2.788344 | 4F
4F | 150m15 - cold formed purlin :5,SHE-13.STEEL.dgn,Design Model:125905 | 0.7764 | 0.000457 | 0.475933 | 0.476848 | 0.003439 | 0.000355 | 2.787276 | 26.999698 | 2.788344 | 4F
4F | 150m15 - cold formed purlin :5,SHE-13.STEEL.dgn,Design Model:125907 | 0.7764 | 0.000457 | 0.475933 | 0.476848 | 0.003439 | 0.000355 | 2.787276 | 26.999698 | 2.788344 | 4F
4F | 150m15 - cold formed purlin :5,SHE-13.STEEL.dgn,Design Model:125909 | 0.7764 | 0.000457 | 0.475933 | 0.476848 | 0.003439 | 0.000355 | 2.787276 | 26.999698 | 2.788344 | 4F
4F | 150m15 - cold formed purlin :5,SHE-13.STEEL.dgn,Design Model:125911 | 0.7764 | 0.000457 | 0.475933 | 0.476848 | 0.003439 | 0.000355 | 2.787276 | 26.999698 | 2.788344 | 4F
4F | 150m15 - cold formed purlin :5,SHE-13.STEEL.dgn,Design Model:125913 | 0.7764 | 0.000457 | 0.475933 | 0.476848 | 0.003439 | 0.000355 | 2.787276 | 26.999698 | 2.788344 | 4F
4F | 150m15 - cold formed purlin :5,SHE-13.STEEL.dgn,Design Model:125915 | 0.7764 | 0.000457 | 0.475933 | 0.476848 | 0.003439 | 0.000355 | 2.787276 | 26.999698 | 2.788344 | 4F
4F | 150m15 - cold formed purlin :5,SHE-13.STEEL.dgn,Design Model:125917 | 0.7764 | 0.000457 | 0.475933 | 0.476848 | 0.003439 | 0.000355 | 2.787276 | 26.999698 | 2.788344 | 4F
4F | 150m15 - cold formed purlin :5,SHE-13.STEEL.dgn,Design Model:125919 | 0.7764 | 0.000457 | 0.475933 | 0.476848 | 0.003439 | 0.000355 | 2.787276 | 26.999698 | 2.788344 | 4F
4F | 150m15 - cold formed purlin :5,SHE-13.STEEL.dgn,Design Model:125921 | 0.7764 | 0.000457 | 0.475933 | 0.476848 | 0.003439 | 0.000355 | 2.787276 | 26.999698 | 2.788344 | 4F
4F | 150m15 - cold formed purlin :5,SHE-13.STEEL.dgn,Design Model:125923 | 0.7764 | 0.000457 | 0.475933 | 0.476848 | 0.003439 | 0.000355 | 2.787276 | 26.999698 | 2.788344 | 4F
4F | 150m15 - cold formed purlin :5,SHE-13.STEEL.dgn,Design Model:125931 | 0.719 | 0.000457 | 0.440747 | 0.441662 | 0.003185 | 0.000329 | 2.581210 | 25.003582 | 2.582198 | 4F
4F | 150m15 - cold formed purlin :5,SHE-13.STEEL.dgn,Design Model:125933 | 0.719 | 0.000457 | 0.440747 | 0.441662 | 0.003185 | 0.000329 | 2.581210 | 25.003582 | 2.582198 | 4F
4F | 150m15 - cold formed purlin :5,SHE-13.STEEL.dgn,Design Model:125935 | 0.719 | 0.000457 | 0.440747 | 0.441662 | 0.003185 | 0.000329 | 2.581210 | 25.003582 | 2.582198 | 4F
4F | 150m15 - cold formed purlin :5,SHE-13.STEEL.dgn,Design Model:125937 | 0.719 | 0.000457 | 0.440747 | 0.441662 | 0.003185 | 0.000329 | 2.581210 | 25.003582 | 2.582198 | 4F
4F | 150m15 - cold formed purlin :5,SHE-13.STEEL.dgn,Design Model:125939 | 0.719 | 0.000457 | 0.440747 | 0.441662 | 0.003185 | 0.000329 | 2.581210 | 25.003582 | 2.582198 | 4F
4F | 150m15 - cold formed purlin :5,SHE-13.STEEL.dgn,Design Model:125941 | 0.719 | 0.000457 | 0.440747 | 0.441662 | 0.003185 | 0.000329 | 2.581210 | 25.003582 | 2.582198 | 4F
4F | 150m15 - cold formed purlin :5,SHE-13.STEEL.dgn,Design Model:125943 | 0.719 | 0.000457 | 0.440747 | 0.441662 | 0.003185 | 0.000329 | 2.581210 | 25.003582 | 2.582198 | 4F
4F | 150m15 - cold formed purlin :5,SHE-13.STEEL.dgn,Design Model:125945 | 0.719 | 0.000457 | 0.440747 | 0.441662 | 0.003185 | 0.000329 | 2.581210 | 25.003582 | 2.582198 | 4F
4F | 150m15 - cold formed purlin :5,SHE-13.STEEL.dgn,Design Model:125947 | 0.719 | 0.000457 | 0.440747 | 0.441662 | 0.003185 | 0.000329 | 2.581210 | 25.003582 | 2.582198 | 4F
4F | 150m15 - cold formed purlin :5,SHE-13.STEEL.dgn,Design Model:125949 | 0.719 | 0.000457 | 0.440747 | 0.441662 | 0.003185 | 0.000329 | 2.581210 | 25.003582 | 2.582198 | 4F
4F | 150m15 - cold formed purlin :5,SHE-13.STEEL.dgn,Design Model:125951 | 0.719 | 0.000457 | 0.440747 | 0.441662 | 0.003185 | 0.000329 | 2.581210 | 25.003582 | 2.582198 | 4F
4F | 150m15 - cold formed purlin :5,SHE-13.STEEL.dgn,Design Model:125953 | 0.719 | 0.000457 | 0.440747 | 0.441662 | 0.003185 | 0.000329 | 2.581210 | 25.003582 | 2.582198 | 4F
4F | 150m15 - cold formed purlin :5,SHE-13.STEEL.dgn,Design Model:125955 | 0.719 | 0.000457 | 0.440747 | 0.441662 | 0.003185 | 0.000329 | 2.581210 | 25.003582 | 2.582198 | 4F
4F | 150m15 - cold formed purlin :5,SHE-13.STEEL.dgn,Design Model:125957 | 0.719 | 0.000457 | 0.440747 | 0.441662 | 0.003185 | 0.000329 | 2.581210 | 25.003582 | 2.582198 | 4F
4F | 150m15 - cold formed purlin :5,SHE-13.STEEL.dgn,Design Model:125959 | 0.719 | 0.000457 | 0.440747 | 0.441662 | 0.003185 | 0.000329 | 2.581210 | 25.003582 | 2.582198 | 4F
4F | 150m15 - cold formed purlin :5,SHE-13.STEEL.dgn,Design Model:125961 | 0.719 | 0.000457 | 0.440747 | 0.441662 | 0.003185 | 0.000329 | 2.581210 | 25.003582 | 2.582198 | 4F
4F | 150m15 - cold formed purlin :5,SHE-13.STEEL.dgn,Design Model:125963 | 0.719 | 0.000457 | 0.440747 | 0.441662 | 0.003185 | 0.000329 | 2.581210 | 25.003582 | 2.582198 | 4F
4F | 150m15 - cold formed purlin :5,SHE-13.STEEL.dgn,Design Model:125965 | 0.719 | 0.000457 | 0.440747 | 0.441662 | 0.003185 | 0.000329 | 2.581210 | 25.003582 | 2.582198 | 4F
4F | 150m15 - cold formed purlin :5,SHE-13.STEEL.dgn,Design Model:125967 | 0.719 | 0.000457 | 0.440747 | 0.441662 | 0.003185 | 0.000329 | 2.581210 | 25.003582 | 2.582198 | 4F
4F | 150m15 - cold formed purlin :5,SHE-13.STEEL.dgn,Design Model:125969 | 0.719 | 0.000457 | 0.440747 | 0.441662 | 0.003185 | 0.000329 | 2.581210 | 25.003582 | 2.582198 | 4F

# IfcBuildingElementPart (3832)
Name | In | Material
10 x 1 | GF | A_BSUK_Walls_Timber
18 x 2 | GF | A_BSUK_WallInternal_Finishes_Plasterboard
5 x 3 | GF | A_BSUK_WallInternal_Finishes_Plasterboard
3 x 4 | GF | Air Cavity
3 x 5 | GF | A_BSUK_Insulation
3 x 6 | GF | Air Cavity
3 x 7 | GF | A_BSUK_WallInternal_Finishes_Plasterboard
5 x 8 | GF | A_BSUK_WallInternal_Finishes_Plasterboard
4 x 9 | GF | A_BSUK_Walls_Timber
5 x 3 | GF | Air Cavity
5 x 4 | GF | A_BSUK_Insulation
7 x 5 | GF | Air Cavity
5 x 6 | GF | A_BSUK_WallInternal_Finishes_Plasterboard
5 x 7 | GF | A_BSUK_Walls_Timber
3 x 2 | GF | A_BSUK_Walls_Timber
2 x 4 | GF | A_BSUK_WallInternal_Finishes_Plasterboard
2 x 6 | GF | A_BSUK_Insulation
2 x 7 | GF | Air Cavity
9 | GF | A_BSUK_WallInternal_Finishes_Plasterboard
10 | GF | A_BSUK_Walls_Timber
11 | GF | A_BSUK_Walls_Timber
11 x 1 | GF | A_BSUK_Insulation
11 x 3 | GF | A_BSUK_Walls_Timber
2 x 1 | MF | A_BSUK_Walls_Timber
13 x 2 | MF | A_BSUK_WallInternal_Finishes_Plasterboard
2 x 3 | MF | Air Cavity
2 x 4 | MF | A_BSUK_Insulation
2 x 5 | MF | Air Cavity
2 x 6 | MF | A_BSUK_WallInternal_Finishes_Plasterboard
2 x 7 | MF | A_BSUK_Walls_Timber
11 x 1 | MF | A_BSUK_Insulation
11 x 3 | MF | A_BSUK_Walls_Timber
161 x 1 | 1F | A_BSUK_Walls_Timber
245 x 2 | 1F | A_BSUK_WallInternal_Finishes_Plasterboard
6 x 3 | 1F | A_BSUK_WallsInternal_Block
6 x 4 | 1F | A_BSUK_WallInternal_Finishes_Plaster
5 x 5 | 1F | A_BSUK_WallInternal_Finishes_Plaster
39 x 6 | 1F | A_BSUK_Walls_Timber
5 x 5 | 1F | A_BSUK_Walls_Timber
72 x 3 | 1F | A_BSUK_WallInternal_Finishes_Plasterboard
47 x 4 | 1F | Air Cavity
46 x 5 | 1F | A_BSUK_Insulation
22 x 6 | 1F | Air Cavity
34 x 7 | 1F | A_BSUK_WallInternal_Finishes_Plasterboard
35 x 8 | 1F | A_BSUK_WallInternal_Finishes_Plasterboard
33 x 9 | 1F | A_BSUK_Walls_Timber
110 x 1 | 1F | A_BSUK_Insulation
87 x 3 | 1F | A_BSUK_Walls_Timber
29 x 4 | 1F | A_BSUK_WallInternal_Finishes_Plasterboard
17 x 5 | 1F | A_BSUK_WallInternal_Finishes_Plasterboard
2 x 7 | 1F | A_BSUK_Insulation
5 x 8 | 1F | Air Cavity
9 x 9 | 1F | A_BSUK_WallInternal_Finishes_Plasterboard
7 x 10 | 1F | A_BSUK_WallInternal_Finishes_Plasterboard
8 x 11 | 1F | A_BSUK_WallInternal_Finishes_Plasterboard
8 x 12 | 1F | A_BSUK_WallInternal_Finishes_Plasterboard
5 x 13 | 1F | A_BSUK_Walls_Timber
72 x 3 | 1F | Air Cavity
73 x 4 | 1F | A_BSUK_Insulation
86 x 5 | 1F | Air Cavity
81 x 6 | 1F | A_BSUK_WallInternal_Finishes_Plasterboard
75 x 7 | 1F | A_BSUK_Walls_Timber
26 x 2 | 1F | A_BSUK_Walls_Timber
14 x 6 | 1F | A_BSUK_Insulation
42 x 7 | 1F | Air Cavity
11 x 10 | 1F | A_BSUK_Walls_Timber
6 x 11 | 1F | A_BSUK_Walls_Timber
4 x 8 | 1F | A_BSUK_Insulation
5 x 9 | 1F | Air Cavity
5 x 12 | 1F | A_BSUK_Walls_Timber
5 x 14 | 1F | A_BSUK_Walls_Timber
3 x 9 | 1F | A_BSUK_Insulation
3 x 10 | 1F | Air Cavity
5 x 13 | 1F | A_BSUK_WallInternal_Finishes_Plasterboard
3 x 14 | 1F | A_BSUK_WallInternal_Finishes_Plasterboard
4 x 15 | 1F | A_BSUK_Walls_Timber
4 x 16 | 1F | A_BSUK_Walls_Timber
17 | 1F | A_BSUK_Walls_Timber
18 | 1F | A_BSUK_Walls_Timber
19 | 1F | A_BSUK_Walls_Timber
5 | 1F | A_BSUK_WallsInternal_Block
6 | 1F | A_BSUK_WallInternal_Finishes_Plaster
10 x 8 | 1F | A_BSUK_Walls_Timber
2 x 10 | 1F | A_BSUK_Insulation
2 x 11 | 1F | Air Cavity
28 x 4 | 1F | A_BSUK_Walls_Timber
2 x 8 | 1F | A_BSUK_WallsInternal_Block
2 x 9 | 1F | A_BSUK_WallInternal_Finishes_Plaster
10 | 1F | A_BSUK_WallInternal_Finishes_Plaster
11 | 1F | A_BSUK_WallInternal_Finishes_Plaster
36 x 3 | 1F | A_BSUK_Insulation
82 x 1 | 3F | A_BSUK_Walls_Timber
148 x 2 | 3F | A_BSUK_WallInternal_Finishes_Plasterboard
4 x 3 | 3F | A_BSUK_WallsInternal_Block
4 x 4 | 3F | A_BSUK_WallInternal_Finishes_Plaster
2 x 5 | 3F | A_BSUK_WallInternal_Finishes_Plaster
7 x 6 | 3F | A_BSUK_Walls_Timber
4 x 5 | 3F | A_BSUK_Walls_Timber
48 x 3 | 3F | A_BSUK_WallInternal_Finishes_Plasterboard
8 x 4 | 3F | Air Cavity
8 x 5 | 3F | A_BSUK_Insulation
10 x 6 | 3F | Air Cavity
15 x 7 | 3F | A_BSUK_WallInternal_Finishes_Plasterboard
15 x 8 | 3F | A_BSUK_WallInternal_Finishes_Plasterboard
15 x 9 | 3F | A_BSUK_Walls_Timber
82 x 1 | 3F | A_BSUK_Insulation
71 x 3 | 3F | A_BSUK_Walls_Timber
18 x 4 | 3F | A_BSUK_WallInternal_Finishes_Plasterboard
11 x 5 | 3F | A_BSUK_WallInternal_Finishes_Plasterboard
5 x 7 | 3F | A_BSUK_Insulation
3 x 8 | 3F | Air Cavity
5 x 9 | 3F | A_BSUK_WallInternal_Finishes_Plasterboard
3 x 10 | 3F | A_BSUK_WallInternal_Finishes_Plasterboard
4 x 11 | 3F | A_BSUK_WallInternal_Finishes_Plasterboard
4 x 12 | 3F | A_BSUK_WallInternal_Finishes_Plasterboard
3 x 13 | 3F | A_BSUK_Walls_Timber
17 x 4 | 3F | A_BSUK_Walls_Timber
41 x 3 | 3F | Air Cavity
53 x 4 | 3F | A_BSUK_Insulation
47 x 5 | 3F | Air Cavity
47 x 6 | 3F | A_BSUK_WallInternal_Finishes_Plasterboard
42 x 7 | 3F | A_BSUK_Walls_Timber
16 x 2 | 3F | A_BSUK_Walls_Timber
6 x 6 | 3F | A_BSUK_Insulation
7 x 7 | 3F | Air Cavity
8 x 10 | 3F | A_BSUK_Walls_Timber
3 x 11 | 3F | A_BSUK_Walls_Timber
8 | 3F | A_BSUK_Insulation
2 x 9 | 3F | Air Cavity
3 x 12 | 3F | A_BSUK_Walls_Timber
2 x 14 | 3F | A_BSUK_Walls_Timber
9 | 3F | A_BSUK_Insulation
10 | 3F | Air Cavity
2 x 13 | 3F | A_BSUK_WallInternal_Finishes_Plasterboard
14 | 3F | A_BSUK_WallInternal_Finishes_Plasterboard
2 x 15 | 3F | A_BSUK_Walls_Timber
16 | 3F | A_BSUK_Walls_Timber
17 | 3F | A_BSUK_Walls_Timber
18 | 3F | A_BSUK_Walls_Timber
19 | 3F | A_BSUK_Walls_Timber
5 | 3F | A_BSUK_WallsInternal_Block
6 | 3F | A_BSUK_WallInternal_Finishes_Plaster
4 x 8 | 3F | A_BSUK_Walls_Timber
10 | 3F | A_BSUK_Insulation
11 | 3F | Air Cavity
2 x 8 | 3F | A_BSUK_WallsInternal_Block
2 x 9 | 3F | A_BSUK_WallInternal_Finishes_Plaster
10 | 3F | A_BSUK_WallInternal_Finishes_Plaster
11 | 3F | A_BSUK_WallInternal_Finishes_Plaster
25 x 8 | 1F | A_BSUK_WallInternal_Finishes_Metal
1 | 1F | A_BSUK_WallInternal_Finishes_Metal
2 x 2 | 1F | Air Cavity
15 | 1F | A_BSUK_WallInternal_Finishes_Plasterboard
1 | 1F | A_BSUK_WallInternal_Finishes_Plasterboard
4 | 1F | A_BSUK_WallsInternal_Block
11 x 1 | 5F | A_BSUK_Walls_Timber
9 x 2 | 5F | A_BSUK_WallInternal_Finishes_Plasterboard
10 x 3 | 5F | A_BSUK_WallInternal_Finishes_Plasterboard
12 x 4 | 5F | Air Cavity
9 x 5 | 5F | A_BSUK_Insulation
10 x 6 | 5F | Air Cavity
19 x 7 | 5F | A_BSUK_WallInternal_Finishes_Plasterboard
12 x 8 | 5F | A_BSUK_WallInternal_Finishes_Plasterboard
12 x 9 | 5F | A_BSUK_Walls_Timber
6 x 1 | 5F | A_BSUK_WallInternal_Finishes_Metal
9 x 2 | 5F | Air Cavity
7 x 3 | 5F | A_BSUK_Walls_Timber
6 x 4 | 5F | A_BSUK_Insulation
6 x 5 | 5F | Air Cavity
6 x 6 | 5F | A_BSUK_Insulation
7 x 8 | 5F | A_BSUK_Walls_Timber
2 x 10 | 5F | A_BSUK_Walls_Timber
2 x 2 | 5F | A_BSUK_Walls_Timber
2 x 4 | 5F | A_BSUK_WallInternal_Finishes_Plasterboard
5 x 5 | 5F | A_BSUK_WallInternal_Finishes_Plasterboard
4 x 6 | 5F | A_BSUK_WallInternal_Finishes_Plasterboard
2 x 9 | 5F | A_BSUK_WallInternal_Finishes_Plasterboard
10 | 5F | Air Cavity
11 | 5F | A_BSUK_Insulation
12 | 5F | Air Cavity
13 | 5F | A_BSUK_WallInternal_Finishes_Plasterboard
14 | 5F | A_BSUK_WallInternal_Finishes_Plasterboard
15 | 5F | A_BSUK_Walls_Timber
3 x 1 | 5F | A_BSUK_WallInternal_Finishes_Plasterboard
3 x 3 | 5F | A_BSUK_Insulation
7 | 5F | A_BSUK_Insulation
8 | 5F | Air Cavity
86 x 1 | 2F | A_BSUK_Walls_Timber
149 x 2 | 2F | A_BSUK_WallInternal_Finishes_Plasterboard
4 x 3 | 2F | A_BSUK_WallsInternal_Block
4 x 4 | 2F | A_BSUK_WallInternal_Finishes_Plaster
2 x 5 | 2F | A_BSUK_WallInternal_Finishes_Plaster
8 x 6 | 2F | A_BSUK_Walls_Timber
4 x 5 | 2F | A_BSUK_Walls_Timber
48 x 3 | 2F | A_BSUK_WallInternal_Finishes_Plasterboard
8 x 4 | 2F | Air Cavity
8 x 5 | 2F | A_BSUK_Insulation
10 x 6 | 2F | Air Cavity
15 x 7 | 2F | A_BSUK_WallInternal_Finishes_Plasterboard
15 x 8 | 2F | A_BSUK_WallInternal_Finishes_Plasterboard
15 x 9 | 2F | A_BSUK_Walls_Timber
78 x 1 | 2F | A_BSUK_Insulation
71 x 3 | 2F | A_BSUK_Walls_Timber
18 x 4 | 2F | A_BSUK_WallInternal_Finishes_Plasterboard
11 x 5 | 2F | A_BSUK_WallInternal_Finishes_Plasterboard
4 x 7 | 2F | A_BSUK_Insulation
3 x 8 | 2F | Air Cavity
5 x 9 | 2F | A_BSUK_WallInternal_Finishes_Plasterboard
3 x 10 | 2F | A_BSUK_WallInternal_Finishes_Plasterboard
4 x 11 | 2F | A_BSUK_WallInternal_Finishes_Plasterboard
4 x 12 | 2F | A_BSUK_WallInternal_Finishes_Plasterboard
3 x 13 | 2F | A_BSUK_Walls_Timber
12 x 4 | 2F | A_BSUK_Walls_Timber
41 x 3 | 2F | Air Cavity
58 x 4 | 2F | A_BSUK_Insulation
47 x 5 | 2F | Air Cavity
46 x 6 | 2F | A_BSUK_WallInternal_Finishes_Plasterboard
43 x 7 | 2F | A_BSUK_Walls_Timber
15 x 2 | 2F | A_BSUK_Walls_Timber
6 x 6 | 2F | A_BSUK_Insulation
7 x 7 | 2F | Air Cavity
8 x 10 | 2F | A_BSUK_Walls_Timber
3 x 11 | 2F | A_BSUK_Walls_Timber
8 | 2F | A_BSUK_Insulation
2 x 9 | 2F | Air Cavity
3 x 12 | 2F | A_BSUK_Walls_Timber
2 x 14 | 2F | A_BSUK_Walls_Timber
5 | 2F | A_BSUK_WallsInternal_Block
6 | 2F | A_BSUK_WallInternal_Finishes_Plaster
4 x 8 | 2F | A_BSUK_Walls_Timber
10 | 2F | A_BSUK_Insulation
11 | 2F | Air Cavity
2 x 13 | 2F | A_BSUK_WallInternal_Finishes_Plasterboard
2 x 15 | 2F | A_BSUK_Walls_Timber
2 x 8 | 2F | A_BSUK_WallsInternal_Block
2 x 9 | 2F | A_BSUK_WallInternal_Finishes_Plaster
10 | 2F | A_BSUK_WallInternal_Finishes_Plaster
11 | 2F | A_BSUK_WallInternal_Finishes_Plaster
9 | 2F | A_BSUK_Insulation
10 | 2F | Air Cavity
14 | 2F | A_BSUK_WallInternal_Finishes_Plasterboard
16 | 2F | A_BSUK_Walls_Timber
17 | 2F | A_BSUK_Walls_Timber
18 | 2F | A_BSUK_Walls_Timber
19 | 2F | A_BSUK_Walls_Timber

# IfcBuildingElementProxy (45)
Name | In | Description
 | 1F | 7 ,SHE-06.FOURTH.dgn,Design Model:387761
 | 1F | 7 ,SHE-06.FOURTH.dgn,Design Model:388003
 | 1F | 7 ,SHE-06.FOURTH.dgn,Design Model:388052
 | 1F | 7 ,SHE-06.FOURTH.dgn,Design Model:388101
 | 1F | 7 ,SHE-06.FOURTH.dgn,Design Model:388150
 | 1F | 7 ,SHE-06.FOURTH.dgn,Design Model:388199
 | 1F | 7 ,SHE-06.FOURTH.dgn,Design Model:388248
 | 1F | 7 ,SHE-06.FOURTH.dgn,Design Model:388297
 | 1F | 7 ,SHE-06.FOURTH.dgn,Design Model:388346
 | 1F | 7 ,SHE-06.FOURTH.dgn,Design Model:388395
 | 1F | 7 ,SHE-06.FOURTH.dgn,Design Model:388493
 | 1F | 7 ,SHE-06.FOURTH.dgn,Design Model:388542
 | 1F | 7 ,SHE-06.FOURTH.dgn,Design Model:388591
 | 1F | 7 ,SHE-06.FOURTH.dgn,Design Model:388640
 | 1F | 7 ,SHE-06.FOURTH.dgn,Design Model:388689
 | 1F | 7 ,SHE-06.FOURTH.dgn,Design Model:388738
 | 1F | 7 ,SHE-06.FOURTH.dgn,Design Model:388787
 | 1F | 7 ,SHE-06.FOURTH.dgn,Design Model:388836
 | 1F | 7 ,SHE-06.FOURTH.dgn,Design Model:388885
 | 1F | 7 ,SHE-06.FOURTH.dgn,Design Model:388934
 | 1F | 7 ,SHE-06.FOURTH.dgn,Design Model:388983
 | 1F | 7 ,SHE-06.FOURTH.dgn,Design Model:389032
 | 1F | 7 ,SHE-06.FOURTH.dgn,Design Model:389081
 | 1F | 7 ,SHE-06.FOURTH.dgn,Design Model:389179
 | 1F | 7 ,SHE-06.FOURTH.dgn,Design Model:389228
 | 1F | 7 ,SHE-06.FOURTH.dgn,Design Model:389277
 | 5F | 8 ,SHE-07.FIFTH.dgn,Design Model:213484
 | 5F | 8 ,SHE-07.FIFTH.dgn,Design Model:213545
 | 5F | 8 ,SHE-07.FIFTH.dgn,Design Model:294809
 | 5F | 8 ,SHE-07.FIFTH.dgn,Design Model:294810
 | 5F | 8 ,SHE-07.FIFTH.dgn,Design Model:295030
 | 5F | 8 ,SHE-07.FIFTH.dgn,Design Model:295250
 | GF | 9 ,SHE-10.CONCRETE.dgn,Design Model:220361
 | GF | 9 ,SHE-10.CONCRETE.dgn,Design Model:220623
 | GF | 9 ,SHE-10.CONCRETE.dgn,Design Model:221043
 | GF | 9 ,SHE-10.CONCRETE.dgn,Design Model:223608
 | GF | 9 ,SHE-10.CONCRETE.dgn,Design Model:223614
 | GF | 9 ,SHE-10.CONCRETE.dgn,Design Model:223954
 | GF | 9 ,SHE-10.CONCRETE.dgn,Design Model:224296
 | GF | 9 ,SHE-10.CONCRETE.dgn,Design Model:224636
 | GF | 9 ,SHE-10.CONCRETE.dgn,Design Model:208085
 | GF | 11 ,SHE-15.MEHP.dgn,Design Model:265965
 | GF | 11 ,SHE-15.MEHP.dgn,Design Model:266692
 | GF | 11 ,SHE-15.MEHP.dgn,Design Model:267722
 | GF | 11 ,SHE-15.MEHP.dgn,Design Model:271784

# IfcBuildingElementProxy: Fireproofing:Cementitious (9)
In: 5F
Material: Cementitious
Name | Description
Fireproofing--Cementitious | 5,SHE-13.STEEL.dgn,Design Model:126144
Fireproofing--Cementitious | 5,SHE-13.STEEL.dgn,Design Model:126243
Fireproofing--Cementitious | 5,SHE-13.STEEL.dgn,Design Model:126342
Fireproofing--Cementitious | 5,SHE-13.STEEL.dgn,Design Model:126409
Fireproofing--Cementitious | 5,SHE-13.STEEL.dgn,Design Model:126460
Fireproofing--Cementitious | 5,SHE-13.STEEL.dgn,Design Model:126511
Fireproofing--Cementitious | 5,SHE-13.STEEL.dgn,Design Model:126562
Fireproofing--Cementitious | 5,SHE-13.STEEL.dgn,Design Model:126613
Fireproofing--Cementitious | 5,SHE-13.STEEL.dgn,Design Model:126664

# IfcColumn: A-Columns-Concrete (27)
In: GF
Type - PredefinedType: COLUMN
Type - Thermal Transmittance - Is External: no; Is Below Grade: no
Type - Structural Usage - Structural | Material: Concrete
Type - Structural Parameters - Section Name: 600x600; Structural Type: Column; Tapered Member: no
Type - Space Bounding - Is Space Bounding: yes
Type - Materials - Part Definition: A-Columns::A_BSUK_Columns_ReinforcedConcrete
Type - Fire Resistance - Fire | IsCombustible: no; Fire | Compartmentation: no
Type - Discipline - Discipline: Architectural
Type - Construction Phase - Phase: New Construction
Type - Classification - Uniclass2015: Pr_20_85_16_15
Material: A_BSUK_Columns_ReinforcedConcrete
Pset_ColumnCommon - IsExternal: no; LoadBearing: no
Quantities | Structural - Volume | Perforation(s): 0 m3; Material Density: 2400.000000
Construction Phase - Phase: Existing to Remain
BuildingDesignerForm - Cope Flange Clearance: 0.000; Cope Web Clearance: 0.000; Cope Corner Treatment: 0; Cope Corner Radius: 0.000; Local Y Offset: 0.000; Local Z Offset: 0.000
Name | Description | StructuralFramingCommon, Section Name | Structural Parameters, Section Name | Column Location | Length (m) | Area | Cross-sectional (m2) = Area | Cross-sectional Modeled (m2) | Area | Side Surfaces Modeled (Gross) (m2) | Area | All Surfaces Modeled (Net) (m2) | Volume (Gross) (m3) = Volume (Gross Modeled) (m3) = Volume (Net) (m3) = Volume (Net Modeled) (m3) | Unit Weight | Length x Unit Weight | Volume (Gross) x Density = Volume (Gross Modeled) x Density = Volume (Net) x Density = Volume (Net Modeled) x Density
A-Columns-Concrete | 9 ,SHE-10.CONCRETE.dgn,Design Model:128950 | 0.400X0.400 | 6\RECTANGLE\0.400X0.400 | A-7 [0.300 , -0.050] | 4.115 | 0.16 | 6.584 | 6.904 | 0.6584 | 1256.000000 | 5168.440000 | 1580.160000
A-Columns-Concrete | 9 ,SHE-10.CONCRETE.dgn,Design Model:128956 | 0.500X0.350 | 6\RECTANGLE\0.500X0.350 | A-11 [0.350 , -0.275] | 10.48 | 0.175 | 17.816 | 18.166 | 1.834 | 1373.750000 | 14396.900000 | 4401.600000
A-Columns-Concrete | 9 ,SHE-10.CONCRETE.dgn,Design Model:129684 | 0.400X0.400 | 6\RECTANGLE\0.400X0.400 | A-5 [0.300, 0.050] | 4.115 | 0.16 | 6.584 | 6.904 | 0.6584 | 1256.000000 | 5168.440000 | 1580.160000
A-Columns-Concrete | 9 ,SHE-10.CONCRETE.dgn,Design Model:129690 | 0.400X0.400 | 6\RECTANGLE\0.400X0.400 | N-5 [-0.320 , 0.050] | 4.115 | 0.16 | 6.584 | 6.904 | 0.6584 | 1256.000000 | 5168.440000 | 1580.160000
A-Columns-Concrete | 9 ,SHE-10.CONCRETE.dgn,Design Model:129692 | 0.400X0.400 | 6\RECTANGLE\0.400X0.400 | N-7 [-0.320 , -0.050] | 4.115 | 0.16 | 6.584 | 6.904 | 0.6584 | 1256.000000 | 5168.440000 | 1580.160000
A-Columns-Concrete | 9 ,SHE-10.CONCRETE.dgn,Design Model:129694 | 0.500X0.300 | 6\RECTANGLE\0.500X0.300 | A-1 [0.350, 0.250] | 3.465 | 0.15 | 5.544 | 5.844 | 0.51975 | 1177.500000 | 4080.037500 | 1247.400000
A-Columns-Concrete | 9 ,SHE-10.CONCRETE.dgn,Design Model:130413 | 0.670X0.350 | 6\RECTANGLE\0.670X0.350 | E-11 [0.025 , -0.275] | 9.93 | 0.2345 | 20.2572 | 20.7262 | 2.32858 | 1840.825000 | 18279.392250 | 5588.604000
A-Columns-Concrete | 9 ,SHE-10.CONCRETE.dgn,Design Model:130415 | 0.670X0.350 | 6\RECTANGLE\0.670X0.350 | J-11 [-0.015 , -0.275] | 9.93 | 0.2345 | 20.2572 | 20.7262 | 2.32858 | 1840.825000 | 18279.392250 | 5588.604000
A-Columns-Concrete | 9 ,SHE-10.CONCRETE.dgn,Design Model:130419 | 0.500X0.300 | 6\RECTANGLE\0.500X0.300 | J-1 [0.000, 0.250] | 3.465 | 0.15 | 5.544 | 5.844 | 0.51975 | 1177.500000 | 4080.037500 | 1247.400000
A-Columns-Concrete | 9 ,SHE-10.CONCRETE.dgn,Design Model:130423 | 0.500X0.300 | 6\RECTANGLE\0.500X0.300 | E-1 [0.000, 0.250] | 3.465 | 0.15 | 5.544 | 5.844 | 0.51975 | 1177.500000 | 4080.037500 | 1247.400000
A-Columns-Concrete | 9 ,SHE-10.CONCRETE.dgn,Design Model:132869 | 0.500X0.300 | 6\RECTANGLE\0.500X0.300 | N-1 [-0.370 , 0.250] | 3.465 | 0.15 | 5.544 | 5.844 | 0.51975 | 1177.500000 | 4080.037500 | 1247.400000
A-Columns-Concrete | 9 ,SHE-10.CONCRETE.dgn,Design Model:132871 | 0.500X0.350 | 6\RECTANGLE\0.500X0.350 | N-11 [-0.370 , -0.275] | 10.48 | 0.175 | 17.816 | 18.166 | 1.834 | 1373.750000 | 14396.900000 | 4401.600000
A-Columns-Concrete | 9 ,SHE-10.CONCRETE.dgn,Design Model:141219 | 0.400X0.700 | 6\RECTANGLE\0.400X0.700 | E-11 [0.003 , -0.250] | 3.135 | 0.28 | 6.897 | 7.457 | 0.8778 | 2198.000000 | 6890.730000 | 2106.720000
A-Columns-Concrete | 9 ,SHE-10.CONCRETE.dgn,Design Model:141223 | 0.400X0.500 | 6\RECTANGLE\0.400X0.500 | N-11 [-0.320 , -0.350] | 3.97 | 0.2 | 7.146 | 7.546 | 0.794 | 1570.000000 | 6232.900000 | 1905.600000
A-Columns-Concrete | 9 ,SHE-10.CONCRETE.dgn,Design Model:141283 | 0.400X0.500 | 6\RECTANGLE\0.400X0.500 | L-11 [-0.090 , -0.350] | 3.1 | 0.2 | 5.58 | 5.98 | 0.62 | 1570.000000 | 4867.000000 | 1488.000000
A-Columns-Concrete | 9 ,SHE-10.CONCRETE.dgn,Design Model:200731 | 0.670X0.300 | 6\RECTANGLE\0.670X0.300 | E-1 [0.025, 0.250] | 10.48 | 0.201 | 20.3312 | 20.7332 | 2.10648 | 1577.850000 | 16535.868000 | 5055.552000
A-Columns-Concrete | 9 ,SHE-10.CONCRETE.dgn,Design Model:200733 | 0.670X0.300 | 6\RECTANGLE\0.670X0.300 | J-1 [-0.015 , 0.250] | 10.48 | 0.201 | 20.3312 | 20.7332 | 2.10648 | 1577.850000 | 16535.868000 | 5055.552000
A-Columns-Concrete | 9 ,SHE-10.CONCRETE.dgn,Design Model:201598 | 0.400X0.400 | 6\RECTANGLE\0.400X0.400 | A-11 [0.300 , -0.300] | 3.97 | 0.16 | 6.352 | 6.672 | 0.6352 | 1256.000000 | 4986.320000 | 1524.480000
A-Columns-Concrete | 9 ,SHE-10.CONCRETE.dgn,Design Model:201636 | 0.500X0.300 | 6\RECTANGLE\0.500X0.300 | N-1 [-0.370 , 0.250] | 10.48 | 0.15 | 16.768 | 17.068 | 1.572 | 1177.500000 | 12340.200000 | 3772.800000
A-Columns-Concrete | 9 ,SHE-10.CONCRETE.dgn,Design Model:201638 | 0.500X0.300 | 6\RECTANGLE\0.500X0.300 | A-1 [0.350, 0.250] | 10.48 | 0.15 | 16.768 | 17.068 | 1.572 | 1177.500000 | 12340.200000 | 3772.800000
A-Columns-Concrete | 9 ,SHE-10.CONCRETE.dgn,Design Model:201640 | 0.400X0.400 | 6\RECTANGLE\0.400X0.400 | A-5 [0.300, 0.050] | 10.48 | 0.16 | 16.768 | 17.088 | 1.6768 | 1256.000000 | 13162.880000 | 4024.320000
A-Columns-Concrete | 9 ,SHE-10.CONCRETE.dgn,Design Model:201642 | 0.400X0.400 | 6\RECTANGLE\0.400X0.400 | A-7 [0.300 , -0.050] | 10.48 | 0.16 | 16.768 | 17.088 | 1.6768 | 1256.000000 | 13162.880000 | 4024.320000
A-Columns-Concrete | 9 ,SHE-10.CONCRETE.dgn,Design Model:201644 | 0.400X0.400 | 6\RECTANGLE\0.400X0.400 | N-5 [-0.320 , 0.050] | 10.48 | 0.16 | 16.768 | 17.088 | 1.6768 | 1256.000000 | 13162.880000 | 4024.320000
A-Columns-Concrete | 9 ,SHE-10.CONCRETE.dgn,Design Model:201646 | 0.400X0.400 | 6\RECTANGLE\0.400X0.400 | N-7 [-0.320 , -0.050] | 10.48 | 0.16 | 16.768 | 17.088 | 1.6768 | 1256.000000 | 13162.880000 | 4024.320000
A-Columns-Concrete | 9 ,SHE-10.CONCRETE.dgn,Design Model:219914 | 0.250X0.250 | 6\RECTANGLE\0.250X0.250 | A-14 [0.266 , -0.317] | 2.535 | 0.0625 | 2.535 | 2.66 | 0.158437 | 490.625000 | 1243.734375 | 380.250000
A-Columns-Concrete | 9 ,SHE-10.CONCRETE.dgn,Design Model:219933 | 0.250X0.250 | 6\RECTANGLE\0.250X0.250 | E-14 [0.078 , -0.648] | 2.535 | 0.0625 | 2.535 | 2.66 | 0.158437 | 490.625000 | 1243.734375 | 380.250000
A-Columns-Concrete | 9 ,SHE-10.CONCRETE.dgn,Design Model:221932 | 0.300X0.500 | 6\RECTANGLE\0.300X0.500 | E-7 [0.075, 0.348] | 4.795 | 0.15 | 7.672 | 7.972 | 0.71925 | 1177.500000 | 5646.112500 | 1726.200000

# IfcColumn: A-Columns-Steel (97)
Type - PredefinedType: COLUMN
Type - Thermal Transmittance - Is External: no; Is Below Grade: no
Type - Structural Usage - Structural | Material: Steel
Type - Structural Parameters - Section Name: UC254X254X107; Structural Type: Column; Tapered Member: no
Type - Materials - Part Definition: A-Columns::A_BSUK_Columns_Steel
Type - Fireproofing - Has Fireproofing: no
Type - Fire Resistance - Fire | IsCombustible: no; Fire | Compartmentation: no
Type - Discipline - Discipline: Architectural
Type - Construction Phase - Phase: New Construction
Type - Classification - Uniclass2015: Pr_20_85_16_11
Material: A_BSUK_Columns_Steel
Pset_ColumnCommon - IsExternal: no; LoadBearing: no
Quantities | Structural - Material Density: 600.000000
BuildingDesignerForm - Cope Flange Clearance: 0.000; Cope Web Clearance: 0.000; Cope Corner Treatment: 0; Cope Corner Radius: 0.000; Local Y Offset: 0.000; Local Z Offset: 0.000
Name | In | Description | FireRating = Fire | Rating | StructuralFramingCommon, Section Name | Structural Parameters, Section Name | Column Location | Length (m) | Area | Cross-sectional (m2) | Area | Cross-sectional Modeled (m2) | Area | Side Surfaces Modeled (Gross) (m2) | Area | All Surfaces Modeled (Net) (m2) | Volume | Perforation(s) (m3) | Volume (Gross) (m3) | Volume (Gross Modeled) (m3) | Volume (Net) (m3) | Volume (Net Modeled) (m3) | Unit Weight | Length x Unit Weight | Volume (Gross) x Density | Volume (Gross Modeled) x Density | Volume (Net) x Density | Volume (Net Modeled) x Density | ID | Description | ID | Notes | Fireproofing Thickness (m) | ID | Type ID
1 | 5F | lift shaft :5 ,SHE-13.STEEL.dgn,Design Model:105129 | FD60 | UC203X203X100 | 1\BS_UC\UC203X203X100 | E-7 [-0.010 , 0.150] | 5.447 | 0.0127 | 0.012596 | 6.91442 | 6.93961 | 0 | 0.069177 | 0.068608 | 0.069177 | 0.068608 | 99.600000 | 542.521200 | 41.506140 | 41.165005 | 41.506140 | 41.165005 | lift shaft | intumescent paint | 0.02 | Identification - ID | Number: 1; ID | Keynote: GL E7; Fireproofing - Has Fireproofing: yes; Fire Proofing Type: S-Fireproofing-Cementitious; Fireproofing Material: Cementitious; Fireproofing Part Definition: Fireproofing::Cementitious
2 | 5F | lift shaft and stair wall :5,SHE-13.STEEL.dgn,Design Model:105131 | FD60 | UC203X203X100 | 1\BS_UC\UC203X203X100 | F-7 [-0.040 , 0.150] | 5.447 | 0.0127 | 0.012596 | 6.91442 | 6.93961 | 0 | 0.069177 | 0.068608 | 0.069177 | 0.068608 | 99.600000 | 542.521200 | 41.506140 | 41.165005 | 41.506140 | 41.165005 | lift shaft and stair wall | intumescent paint | 0.02 | Identification - ID | Number: 2; ID | Keynote: GL F7; Fireproofing - Has Fireproofing: yes; Fire Proofing Type: S-Fireproofing-Cementitious; Fireproofing Material: Cementitious; Fireproofing Part Definition: Fireproofing::Cementitious
3 | 5F | party and stair wall (55dB ) :5,SHE-13.STEEL.dgn,Design Model:105133 | FD60 | UC203X203X100 | 1\BS_UC\UC203X203X100 | G-7 [-0.000 , 0.150] | 5.447 | 0.0127 | 0.012596 | 6.91442 | 6.93961 | 0 | 0.069177 | 0.068608 | 0.069177 | 0.068608 | 99.600000 | 542.521200 | 41.506140 | 41.165005 | 41.506140 | 41.165005 | party and stair wall (55dB) | intumescent paint | 0.02 | Identification - ID | Number: 3; ID | Keynote: GL G7; Fireproofing - Has Fireproofing: yes; Fire Proofing Type: S-Fireproofing-Cementitious; Fireproofing Material: Cementitious; Fireproofing Part Definition: Fireproofing::Cementitious
4 | 5F | free standing :5 ,SHE-13.STEEL.dgn,Design Model:105136 | FD60 | SHS150X150X5 | 1\BS HYBOX SHS\SHS150X150X5 | J-7 [0.060, 0.150] | 5.447 | 0.00284 | 0.0029 | 6.31852 | 6.32432 | 0 | 0.015469 | 0.015796 | 0.015469 | 0.015796 | 22.300000 | 121.468100 | 9.281688 | 9.477780 | 9.281688 | 9.477780 | free standing | intumescent paint | 0.02 | Identification - ID | Number: 4; ID | Keynote: GL J7; Fireproofing - Has Fireproofing: yes; Fire Proofing Type: S-Fireproofing-Cementitious; Fireproofing Material: Cementitious; Fireproofing Part Definition: Fireproofing::Cementitious
5 | 5F | corridor wall and free standing :5,SHE-13.STEEL.dgn,Design Model:105139 | FD60 | RHS200X100X10 | 1\BS CELSIUS RHS\RHS200X100X10 | E-5 [-0.010 , -0.100] | 5.447 | 0.00549 | 0.0056 | 6.10064 | 6.11184 | 0 | 0.029904 | 0.030503 | 0.029904 | 0.030503 | 43.100000 | 234.765700 | 17.942418 | 18.301920 | 17.942418 | 18.301920 | corridor wall and free standing | intumescent paint | 0.02 | Identification - ID | Number: 5; ID | Keynote: GL E5; Fireproofing - Has Fireproofing: yes; Fire Proofing Type: S-Fireproofing-Cementitious; Fireproofing Material: Cementitious; Fireproofing Part Definition: Fireproofing::Cementitious
6-4F | 5F | lift shaft and stair wall :5,SHE-13.STEEL.dgn,Design Model:105141 | FD60 | RHS200X100X10 | 1\BS CELSIUS RHS\RHS200X100X10 | F-6 [-0.040 , -0.520] | 2.497 | 0.00549 | 0.0056 | 2.79664 | 2.80784 | 0 | 0.013709 | 0.013983 | 0.013709 | 0.013983 | 43.100000 | 107.620700 | 8.225118 | 8.389920 | 8.225118 | 8.389920 | lift shaft and stair wall | intumescent paint | 0.02 | Identification - ID | Number: 6-4F; ID | Keynote: GL F5/6 - 4F; Fireproofing - Has Fireproofing: yes; Fire Proofing Type: S-Fireproofing-Cementitious; Fireproofing Material: Cementitious; Fireproofing Part Definition: Fireproofing::Cementitious
6-5F | 5F | lift shaft and stair wall :5,SHE-13.STEEL.dgn,Design Model:105143 | FD60 | RHS200X100X10 | 1\BS CELSIUS RHS\RHS200X100X10 | F-6 [-0.040 , -0.520] | 2.747 | 0.00549 | 0.0056 | 3.07664 | 3.08784 | 0 | 0.015081 | 0.015383 | 0.015081 | 0.015383 | 43.100000 | 118.395700 | 9.048618 | 9.229920 | 9.048618 | 9.229920 | lift shaft and stair wall | intumescent paint | 0.02 | Identification - ID | Number: 6-5F; ID | Keynote: GL F5/6 - 5F; Fireproofing - Has Fireproofing: yes; Fire Proofing Type: S-Fireproofing-Cementitious; Fireproofing Material: Cementitious; Fireproofing Part Definition: Fireproofing::Cementitious
7 | 5F | free standing and party wall (55dB) :5,SHE-13.STEEL.dgn,Design Model:105145 | FD60 | RHS200X100X10 | 1\BS CELSIUS RHS\RHS200X100X10 | G-5 [0.000 , -0.100] | 5.447 | 0.00549 | 0.0056 | 6.10064 | 6.11184 | 0 | 0.029904 | 0.030503 | 0.029904 | 0.030503 | 43.100000 | 234.765700 | 17.942418 | 18.301920 | 17.942418 | 18.301920 | free standing and party wall (55dB) | intumescent paint | 0.02 | Identification - ID | Number: 7; ID | Keynote: GL G5; Fireproofing - Has Fireproofing: yes; Fire Proofing Type: S-Fireproofing-Cementitious; Fireproofing Material: Cementitious; Fireproofing Part Definition: Fireproofing::Cementitious
8 | 5F | free standing :5 ,SHE-13.STEEL.dgn,Design Model:105147 | FD60 | RHS200X100X10 | 1\BS CELSIUS RHS\RHS200X100X10 | J-5 [0.060 , -0.100] | 5.447 | 0.00549 | 0.0056 | 6.10064 | 6.11184 | 0 | 0.029904 | 0.030503 | 0.029904 | 0.030503 | 43.100000 | 234.765700 | 17.942418 | 18.301920 | 17.942418 | 18.301920 | free standing | intumescent paint | 0.02 | Identification - ID | Number: 8; ID | Keynote: GL J5; Fireproofing - Has Fireproofing: yes; Fire Proofing Type: S-Fireproofing-Cementitious; Fireproofing Material: Cementitious; Fireproofing Part Definition: Fireproofing::Cementitious
A2 | 5F | A2 - mansard roof profile :5,SHE-13.STEEL.dgn,Design Model:105152 | FD60 | UC203X203X127 | 1\BS5950_UC\UC203X203X127 | L-1 [-0.210 , 0.670] | 2.966 | 0.0162 | 0.016156 | 3.86232 | 3.81468 | 0.000596 | 0.048049 | 0.04792 | 0.047454 | 0.047325 | 127.500000 | 378.165000 | 28.829520 | 28.752107 | 28.472143 | 28.394730 | mansard roof profile | intumescent paint | 0 | A2
A2 | 5F | A2 - mansard roof profile :5,SHE-13.STEEL.dgn,Design Model:105154 | FD60 | UC203X203X127 | 1\BS5950_UC\UC203X203X127 | L-2 [-0.210 , -0.674] | 0.846044 | 0.0162 | 0.016157 | 1.10172 | 1.09298 | 0.000309 | 0.013706 | 0.013669 | 0.013397 | 0.01336 | 127.500000 | 107.870640 | 8.223550 | 8.201468 | 8.038232 | 8.016150 | mansard roof profile | intumescent paint | 0 | A2
A2 | 5F | A2 - mansard roof profile :5,SHE-13.STEEL.dgn,Design Model:105158 | FD60 | UC203X203X127 | 1\BS5950_UC\UC203X203X127 | J-2 [0.060 , -0.674] | 0.969944 | 0.0162 | 0.016157 | 1.26306 | 1.25432 | 0.000309 | 0.015713 | 0.015671 | 0.015404 | 0.015362 | 127.500000 | 123.667890 | 9.427858 | 9.402542 | 9.242540 | 9.217224 | mansard roof profile | intumescent paint | 0 | A2
A2 | 5F | A2 - mansard roof profile :5,SHE-13.STEEL.dgn,Design Model:105160 | FD60 | UC203X203X127 | 1\BS5950_UC\UC203X203X127 | J-1 [0.060, 0.670] | 1.808 | 0.0162 | 0.016156 | 2.35438 | 2.34564 | 0.000309 | 0.02929 | 0.029211 | 0.028981 | 0.028902 | 127.500000 | 230.520000 | 17.573760 | 17.526571 | 17.388442 | 17.341253 | mansard roof profile | intumescent paint | 0 | A2
A2 | 5F | A2 - mansard roof profile :5,SHE-13.STEEL.dgn,Design Model:105162 | FD60 | UC203X203X127 | 1\BS5950_UC\UC203X203X127 | G-2 [-0.000 , -0.674] | 0.820644 | 0.0162 | 0.016157 | 1.06864 | 1.05991 | 0.000309 | 0.013294 | 0.013259 | 0.012986 | 0.01295 | 127.500000 | 104.632140 | 7.976662 | 7.955243 | 7.791344 | 7.769925 | mansard roof profile | intumescent paint | 0 | A2
A2 | 5F | A2 - mansard roof profile :5,SHE-13.STEEL.dgn,Design Model:105164 | FD60 | UC203X203X127 | 1\BS5950_UC\UC203X203X127 | G-1 [-0.000 , 0.670] | 2.966 | 0.0162 | 0.016157 | 3.86232 | 3.81468 | 0.000596 | 0.048049 | 0.04792 | 0.047454 | 0.047325 | 127.500000 | 378.165000 | 28.829520 | 28.752107 | 28.472143 | 28.394731 | mansard roof profile | intumescent paint | 0 | A2
A2 | 5F | A2 - mansard roof profile :5,SHE-13.STEEL.dgn,Design Model:105170 | FD60 | UC203X203X127 | 1\BS5950_UC\UC203X203X127 | E-2 [-0.010 , -0.674] | 0.969944 | 0.0162 | 0.016157 | 1.26306 | 1.25432 | 0.000309 | 0.015713 | 0.015671 | 0.015404 | 0.015362 | 127.500000 | 123.667890 | 9.427858 | 9.402542 | 9.242540 | 9.217224 | mansard roof profile | intumescent paint | 0 | A2
A2 | 5F | A2 - mansard roof profile :5,SHE-13.STEEL.dgn,Design Model:105172 | FD60 | UC203X203X127 | 1\BS5950_UC\UC203X203X127 | E-1 [-0.010 , 0.670] | 1.808 | 0.0162 | 0.016156 | 2.35438 | 2.34564 | 0.000309 | 0.02929 | 0.029211 | 0.028981 | 0.028902 | 127.500000 | 230.520000 | 17.573760 | 17.526571 | 17.388442 | 17.341253 | mansard roof profile | intumescent paint | 0 | A2
A2 | 5F | A2 - mansard roof profile :5,SHE-13.STEEL.dgn,Design Model:105174 | FD60 | UC203X203X127 | 1\BS5950_UC\UC203X203X127 | C-2 [0.210 , -0.674] | 0.846044 | 0.0162 | 0.016157 | 1.10172 | 1.09298 | 0.000309 | 0.013706 | 0.013669 | 0.013397 | 0.01336 | 127.500000 | 107.870640 | 8.223550 | 8.201468 | 8.038232 | 8.016150 | mansard roof profile | intumescent paint | 0 | A2
A2 | 5F | A2 - mansard roof profile :5,SHE-13.STEEL.dgn,Design Model:105176 | FD60 | UC203X203X127 | 1\BS5950_UC\UC203X203X127 | C-1 [0.210, 0.670] | 2.966 | 0.0162 | 0.016157 | 3.86232 | 3.81468 | 0.000596 | 0.048049 | 0.04792 | 0.047454 | 0.047325 | 127.500000 | 378.165000 | 28.829520 | 28.752107 | 28.472143 | 28.394731 | mansard roof profile | intumescent paint | 0 | A2
A2 | 5F | A2 - mansard roof profile :5,SHE-13.STEEL.dgn,Design Model:105186 | FD60 | UC203X203X127 | 1\BS5950_UC\UC203X203X127 | C-10 [0.210 , -0.236] | 2.966 | 0.0162 | 0.016157 | 3.86232 | 3.81466 | 0.000596 | 0.048049 | 0.04792 | 0.047454 | 0.047325 | 127.500000 | 378.165000 | 28.829520 | 28.752107 | 28.472145 | 28.394733 | mansard roof profile | intumescent paint | 0 | A2
A2 | 5F | A2 - mansard roof profile :5,SHE-13.STEEL.dgn,Design Model:105188 | FD60 | UC203X203X127 | 1\BS5950_UC\UC203X203X127 | C-10 [0.210 , 0.674] | 0.846044 | 0.0162 | 0.016157 | 1.10172 | 1.09298 | 0.000309 | 0.013706 | 0.013669 | 0.013397 | 0.01336 | 127.500000 | 107.870640 | 8.223550 | 8.201468 | 8.038232 | 8.016150 | mansard roof profile | intumescent paint | 0 | A2
A2 | 5F | A2 - mansard roof profile :5,SHE-13.STEEL.dgn,Design Model:105190 | FD60 | UC203X203X127 | 1\BS5950_UC\UC203X203X127 | E-10 [-0.010 , 0.122] | 1.80756 | 0.0162 | 0.016157 | 2.35381 | 2.34507 | 0.000309 | 0.029283 | 0.029204 | 0.028974 | 0.028895 | 127.500000 | 230.464369 | 17.569519 | 17.522342 | 17.384201 | 17.337023 | mansard roof profile | intumescent paint | 0 | A2
A2 | 5F | A2 - mansard roof profile :5,SHE-13.STEEL.dgn,Design Model:105192 | FD60 | UC203X203X127 | 1\BS5950_UC\UC203X203X127 | E-10 [-0.010 , 0.674] | 0.97 | 0.0162 | 0.016157 | 1.26313 | 1.2544 | 0.000309 | 0.015714 | 0.015672 | 0.015405 | 0.015363 | 127.500000 | 123.675000 | 9.428400 | 9.403083 | 9.243082 | 9.217765 | mansard roof profile | intumescent paint | 0 | A2
A2 | 5F | A2 - mansard roof profile :5,SHE-13.STEEL.dgn,Design Model:105194 | FD60 | UC203X203X127 | 1\BS5950_UC\UC203X203X127 | G-10 [-0.000 , 0.674] | 0.820644 | 0.0162 | 0.016157 | 1.06864 | 1.05991 | 0.000309 | 0.013294 | 0.013259 | 0.012986 | 0.01295 | 127.500000 | 104.632140 | 7.976662 | 7.955243 | 7.791344 | 7.769925 | mansard roof profile | intumescent paint | 0 | A2
A2 | 5F | A2 - mansard roof profile :5,SHE-13.STEEL.dgn,Design Model:105196 | FD60 | UC203X203X127 | 1\BS5950_UC\UC203X203X127 | G-10 [-0.000 , -0.236] | 2.966 | 0.0162 | 0.016157 | 3.86232 | 3.81466 | 0.000596 | 0.048049 | 0.04792 | 0.047454 | 0.047325 | 127.500000 | 378.165000 | 28.829520 | 28.752107 | 28.472145 | 28.394733 | mansard roof profile | intumescent paint | 0 | A2
A2 | 5F | A2 - mansard roof profile :5,SHE-13.STEEL.dgn,Design Model:105202 | FD60 | UC203X203X127 | 1\BS5950_UC\UC203X203X127 | J-10 [0.060 , 0.674] | 0.97 | 0.0162 | 0.016157 | 1.26313 | 1.2544 | 0.000309 | 0.015714 | 0.015672 | 0.015405 | 0.015363 | 127.500000 | 123.675000 | 9.428400 | 9.403083 | 9.243082 | 9.217765 | mansard roof profile | intumescent paint | 0 | A2
A2 | 5F | A2 - mansard roof profile :5,SHE-13.STEEL.dgn,Design Model:105204 | FD60 | UC203X203X127 | 1\BS5950_UC\UC203X203X127 | J-10 [0.060 , 0.122] | 1.80756 | 0.0162 | 0.016157 | 2.35381 | 2.34507 | 0.000309 | 0.029283 | 0.029204 | 0.028974 | 0.028895 | 127.500000 | 230.464369 | 17.569519 | 17.522342 | 17.384201 | 17.337023 | mansard roof profile | intumescent paint | 0 | A2
A2 | 5F | A2 - mansard roof profile :5,SHE-13.STEEL.dgn,Design Model:105206 | FD60 | UC203X203X127 | 1\BS5950_UC\UC203X203X127 | L-10 [-0.210 , 0.674] | 0.846044 | 0.0162 | 0.016157 | 1.10172 | 1.09298 | 0.000309 | 0.013706 | 0.013669 | 0.013397 | 0.01336 | 127.500000 | 107.870640 | 8.223550 | 8.201468 | 8.038232 | 8.016150 | mansard roof profile | intumescent paint | 0 | A2
A2 | 5F | A2 - mansard roof profile :5,SHE-13.STEEL.dgn,Design Model:105208 | FD60 | UC203X203X127 | 1\BS5950_UC\UC203X203X127 | L-10 [-0.210 , -0.236] | 2.966 | 0.0162 | 0.016157 | 3.86232 | 3.81466 | 0.000596 | 0.048049 | 0.04792 | 0.047454 | 0.047325 | 127.500000 | 378.165000 | 28.829520 | 28.752107 | 28.472145 | 28.394733 | mansard roof profile | intumescent paint | 0 | A2
A2 | 5F | A2 - mansard roof profile :5,SHE-13.STEEL.dgn,Design Model:105216 | FD60 | UC203X203X127 | 1\BS5950_UC\UC203X203X127 | B-7 [0.377, 0.150] | 2.26935 | 0.0162 | 0.016157 | 2.95515 | 2.94781 | 0.000291 | 0.036763 | 0.036665 | 0.036472 | 0.036373 | 127.500000 | 289.342189 | 22.058087 | 21.998857 | 21.883221 | 21.823991 | mansard roof profile | intumescent paint | 0 | A2
A2 | 5F | A2 - mansard roof profile :5,SHE-13.STEEL.dgn,Design Model:105218 | FD60 | UC203X203X127 | 1\BS5950_UC\UC203X203X127 | B-7 [-0.909 , 0.150] | 2.966 | 0.0162 | 0.016156 | 3.86232 | 3.81466 | 0.000596 | 0.048049 | 0.04792 | 0.047454 | 0.047325 | 127.500000 | 378.165000 | 28.829520 | 28.752107 | 28.472145 | 28.394733 | mansard roof profile | intumescent paint | 0 | A2
A2 | 5F | A2 - mansard roof profile :5,SHE-13.STEEL.dgn,Design Model:105220 | FD60 | UC203X203X127 | 1\BS5950_UC\UC203X203X127 | A-7 [0.681, 0.150] | 0.97 | 0.0162 | 0.016157 | 1.26313 | 1.2544 | 0.000309 | 0.015714 | 0.015672 | 0.015405 | 0.015363 | 127.500000 | 123.675000 | 9.428400 | 9.403083 | 9.243082 | 9.217765 | mansard roof profile | intumescent paint | 0 | A2
A2 | 5F | A2 - mansard roof profile :5,SHE-13.STEEL.dgn,Design Model:105222 | FD60 | UC203X203X127 | 1\BS5950_UC\UC203X203X127 | A-5 [0.681 , -0.150] | 0.97 | 0.0162 | 0.016157 | 1.26313 | 1.2544 | 0.000309 | 0.015714 | 0.015672 | 0.015405 | 0.015363 | 127.500000 | 123.675000 | 9.428400 | 9.403083 | 9.243082 | 9.217765 | mansard roof profile | intumescent paint | 0 | A2
A2 | 5F | A2 - mansard roof profile :5,SHE-13.STEEL.dgn,Design Model:105224 | FD60 | UC203X203X127 | 1\BS5950_UC\UC203X203X127 | B-5 [-0.909 , -0.150] | 2.966 | 0.0162 | 0.016156 | 3.86232 | 3.81466 | 0.000596 | 0.048049 | 0.04792 | 0.047454 | 0.047325 | 127.500000 | 378.165000 | 28.829520 | 28.752107 | 28.472145 | 28.394733 | mansard roof profile | intumescent paint | 0 | A2
A2 | 5F | A2 - mansard roof profile :5,SHE-13.STEEL.dgn,Design Model:105226 | FD60 | UC203X203X127 | 1\BS5950_UC\UC203X203X127 | B-5 [0.377 , -0.150] | 2.26935 | 0.0162 | 0.016156 | 2.95515 | 2.94781 | 0.000291 | 0.036763 | 0.036665 | 0.036472 | 0.036373 | 127.500000 | 289.342189 | 22.058087 | 21.998857 | 21.883221 | 21.823991 | mansard roof profile | intumescent paint | 0 | A2
A2 | 5F | A2 - mansard roof profile :5,SHE-13.STEEL.dgn,Design Model:105230 | FD60 | UC203X203X127 | 1\BS5950_UC\UC203X203X127 | N-7 [-0.701 , 0.150] | 0.969944 | 0.0162 | 0.016157 | 1.26306 | 1.25432 | 0.000309 | 0.015713 | 0.015671 | 0.015404 | 0.015362 | 127.500000 | 123.667890 | 9.427858 | 9.402542 | 9.242540 | 9.217224 | mansard roof profile | intumescent paint | 0 | A2
A2 | 5F | A2 - mansard roof profile :5,SHE-13.STEEL.dgn,Design Model:105232 | FD60 | UC203X203X127 | 1\BS5950_UC\UC203X203X127 | N-7 [-0.695 , 0.150] | 2.966 | 0.0162 | 0.016156 | 3.86232 | 3.81468 | 0.000596 | 0.048049 | 0.04792 | 0.047454 | 0.047325 | 127.500000 | 378.165000 | 28.829520 | 28.752107 | 28.472143 | 28.394731 | mansard roof profile | intumescent paint | 0 | A2
A2 | 5F | A2 - mansard roof profile :5,SHE-13.STEEL.dgn,Design Model:105234 | FD60 | UC203X203X127 | 1\BS5950_UC\UC203X203X127 | M-7 [0.904, 0.150] | 2.269 | 0.0162 | 0.016157 | 2.95469 | 2.94736 | 0.000291 | 0.036758 | 0.036659 | 0.036466 | 0.036368 | 127.500000 | 289.297500 | 22.054680 | 21.995459 | 21.879814 | 21.820593 | mansard roof profile | intumescent paint | 0 | A2
A2 | 5F | A2 - mansard roof profile :5,SHE-13.STEEL.dgn,Design Model:105240 | FD60 | UC203X203X127 | 1\BS5950_UC\UC203X203X127 | M-5 [0.904 , -0.150] | 2.269 | 0.0162 | 0.016157 | 2.95469 | 2.94736 | 0.000291 | 0.036758 | 0.036659 | 0.036466 | 0.036368 | 127.500000 | 289.297500 | 22.054680 | 21.995459 | 21.879814 | 21.820593 | mansard roof profile | intumescent paint | 0 | A2
A2 | 5F | A2 - mansard roof profile :5,SHE-13.STEEL.dgn,Design Model:105242 | FD60 | UC203X203X127 | 1\BS5950_UC\UC203X203X127 | N-5 [-0.695 , -0.150] | 2.966 | 0.0162 | 0.016156 | 3.86232 | 3.81468 | 0.000596 | 0.048049 | 0.04792 | 0.047454 | 0.047325 | 127.500000 | 378.165000 | 28.829520 | 28.752107 | 28.472143 | 28.394731 | mansard roof profile | intumescent paint | 0 | A2
A2 | 5F | A2 - mansard roof profile :5,SHE-13.STEEL.dgn,Design Model:105244 | FD60 | UC203X203X127 | 1\BS5950_UC\UC203X203X127 | N-5 [-0.701 , -0.150] | 0.969944 | 0.0162 | 0.016157 | 1.26306 | 1.25432 | 0.000309 | 0.015713 | 0.015671 | 0.015404 | 0.015362 | 127.500000 | 123.667890 | 9.427858 | 9.402542 | 9.242540 | 9.217224 | mansard roof profile | intumescent paint | 0 | A2
A2 | 5F | A2 - mansard roof profile :5,SHE-13.STEEL.dgn,Design Model:105246 | FD60 | UC203X203X127 | 1\BS5950_UC\UC203X203X127 | N-2 [-0.737 , -0.643] | 2.93867 | 0.0162 | 0.016157 | 3.82673 | 3.76452 | 0.000772 | 0.047606 | 0.047479 | 0.046834 | 0.046707 | 127.500000 | 374.679987 | 28.563839 | 28.487140 | 28.100697 | 28.023997 | mansard roof profile | intumescent paint | 0 | A2
A2 | 5F | A2 - mansard roof profile :5,SHE-13.STEEL.dgn,Design Model:105248 | FD60 | UC203X203X127 | 1\BS5950_UC\UC203X203X127 | N-2 [-0.746 , -0.634] | 1.148 | 0.0162 | 0.016156 | 1.49493 | 1.47488 | 0.000451 | 0.018598 | 0.018548 | 0.018146 | 0.018096 | 127.500000 | 146.370000 | 11.158560 | 11.128597 | 10.887740 | 10.857777 | mansard roof profile | intumescent paint | 0 | A2
A2 | 5F | A2 - mansard roof profile :5,SHE-13.STEEL.dgn,Design Model:105266 | FD60 | UC203X203X127 | 1\BS5950_UC\UC203X203X127 | M-2 [0.861, 0.264] | 2.601 | 0.0162 | 0.016157 | 3.38702 | 3.2961 | 0.001128 | 0.042136 | 0.042023 | 0.041008 | 0.040895 | 127.500000 | 331.627500 | 25.281720 | 25.213834 | 24.604703 | 24.536817 | mansard roof profile | intumescent paint | 0 | A2
A2 | 5F | A2 - mansard roof profile :5,SHE-13.STEEL.dgn,Design Model:105268 | FD60 | UC203X203X127 | 1\BS5950_UC\UC203X203X127 | N-10 [-0.746 , 0.634] | 1.148 | 0.0162 | 0.016157 | 1.49493 | 1.47438 | 0.000455 | 0.018598 | 0.018548 | 0.018142 | 0.018092 | 127.500000 | 146.370000 | 11.158560 | 11.128597 | 10.885339 | 10.855376 | mansard roof profile | intumescent paint | 0 | A2
A2 | 5F | A2 - mansard roof profile :5,SHE-13.STEEL.dgn,Design Model:105270 | FD60 | UC203X203X127 | 1\BS5950_UC\UC203X203X127 | M-10 [0.845 , -0.280] | 2.93867 | 0.0162 | 0.016157 | 3.82673 | 3.76452 | 0.000772 | 0.047606 | 0.047479 | 0.046834 | 0.046707 | 127.500000 | 374.679987 | 28.563839 | 28.487140 | 28.100697 | 28.023997 | mansard roof profile | intumescent paint | 0 | A2
A2 | 5F | A2 - mansard roof profile :5,SHE-13.STEEL.dgn,Design Model:105272 | FD60 | UC203X203X127 | 1\BS5950_UC\UC203X203X127 | M-9 [-0.430 , 0.288] | 2.601 | 0.0162 | 0.016157 | 3.38702 | 3.29617 | 0.001128 | 0.042136 | 0.042023 | 0.041008 | 0.040895 | 127.500000 | 331.627500 | 25.281720 | 25.213834 | 24.604701 | 24.536815 | mansard roof profile | intumescent paint | 0 | A2
A2 | 5F | A2 - mansard roof profile :5,SHE-13.STEEL.dgn,Design Model:105276 | FD60 | UC203X203X127 | 1\BS5950_UC\UC203X203X127 | A-10 [0.726 , 0.634] | 1.148 | 0.0162 | 0.016157 | 1.49493 | 1.47488 | 0.000451 | 0.018598 | 0.018548 | 0.018146 | 0.018096 | 127.500000 | 146.370000 | 11.158560 | 11.128597 | 10.887740 | 10.857777 | mansard roof profile | intumescent paint | 0 | A2
A2 | 5F | A2 - mansard roof profile :5,SHE-13.STEEL.dgn,Design Model:105278 | FD60 | UC203X203X127 | 1\BS5950_UC\UC203X203X127 | A-10 [0.717 , 0.643] | 2.93867 | 0.0162 | 0.016156 | 3.82673 | 3.76452 | 0.000772 | 0.047606 | 0.047479 | 0.046834 | 0.046707 | 127.500000 | 374.679987 | 28.563839 | 28.487140 | 28.100697 | 28.023997 | mansard roof profile | intumescent paint | 0 | A2
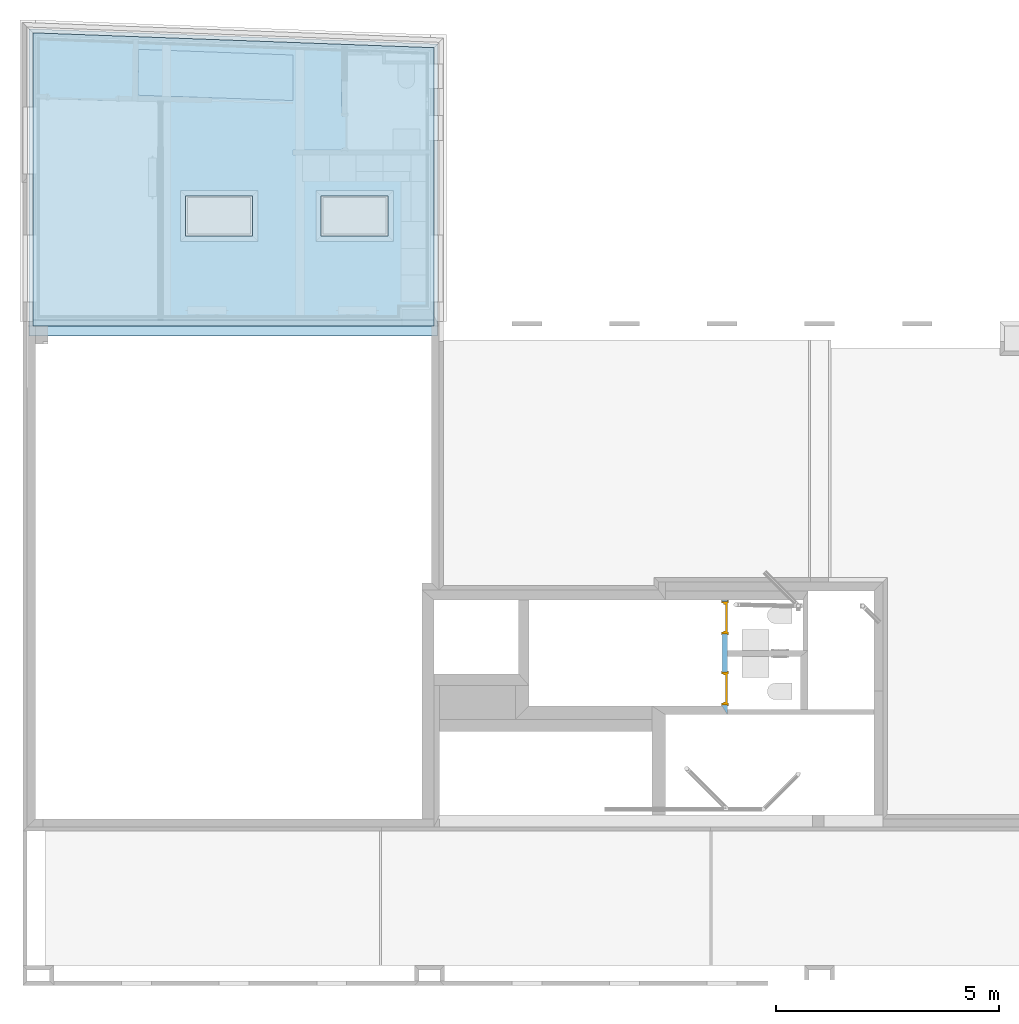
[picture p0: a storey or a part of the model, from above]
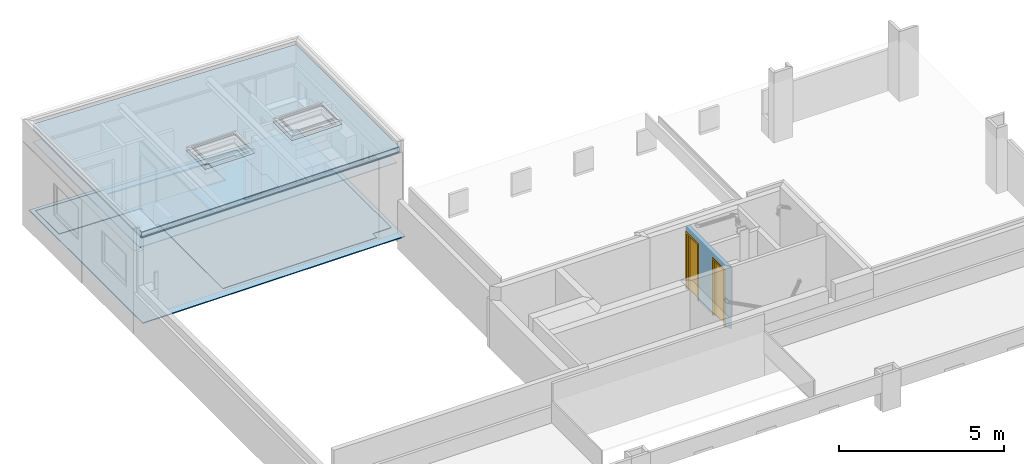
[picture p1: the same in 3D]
Properties of the parts of a building model (IFC2X3), part 5 of 16

# IfcColumn: A-Columns-Steel (97)
Name | In | Description | FireRating = Fire | Rating | StructuralFramingCommon, Section Name | Structural Parameters, Section Name | Column Location | Length (m) | Area | Cross-sectional (m2) | Area | Cross-sectional Modeled (m2) | Area | Side Surfaces Modeled (Gross) (m2) | Area | All Surfaces Modeled (Net) (m2) | Volume | Perforation(s) (m3) | Volume (Gross) (m3) | Volume (Gross Modeled) (m3) | Volume (Net) (m3) | Volume (Net Modeled) (m3) | Unit Weight | Length x Unit Weight | Volume (Gross) x Density | Volume (Gross Modeled) x Density | Volume (Net) x Density | Volume (Net Modeled) x Density | ID | Description | ID | Notes | Fireproofing Thickness (m) | ID | Type ID
A2 | 5F | A2 - mansard roof profile :5,SHE-13.STEEL.dgn,Design Model:105280 | FD60 | UC203X203X127 | 1\BS5950_UC\UC203X203X127 | B-10 [-0.881 , -0.264] | 2.601 | 0.0162 | 0.016157 | 3.38702 | 3.2961 | 0.001128 | 0.042136 | 0.042023 | 0.041008 | 0.040895 | 127.500000 | 331.627500 | 25.281720 | 25.213834 | 24.604703 | 24.536817 | mansard roof profile | intumescent paint | 0 | A2
A2 | 5F | A2 - mansard roof profile :5,SHE-13.STEEL.dgn,Design Model:105286 | FD60 | UC203X203X127 | 1\BS5950_UC\UC203X203X127 | B-3 [0.410 , -0.288] | 2.601 | 0.0162 | 0.016156 | 3.38702 | 3.29617 | 0.001128 | 0.042136 | 0.042023 | 0.041008 | 0.040895 | 127.500000 | 331.627500 | 25.281720 | 25.213834 | 24.604701 | 24.536815 | mansard roof profile | intumescent paint | 0 | A2
A2 | 5F | A2 - mansard roof profile :5,SHE-13.STEEL.dgn,Design Model:105288 | FD60 | UC203X203X127 | 1\BS5950_UC\UC203X203X127 | B-2 [-0.865 , 0.280] | 2.93867 | 0.0162 | 0.016156 | 3.82673 | 3.76452 | 0.000772 | 0.047606 | 0.047479 | 0.046834 | 0.046707 | 127.500000 | 374.679987 | 28.563839 | 28.487140 | 28.100697 | 28.023997 | mansard roof profile | intumescent paint | 0 | A2
A2 | 5F | A2 - mansard roof profile :5,SHE-13.STEEL.dgn,Design Model:105290 | FD60 | UC203X203X127 | 1\BS5950_UC\UC203X203X127 | A-2 [0.726 , -0.634] | 1.148 | 0.0162 | 0.016157 | 1.49493 | 1.47438 | 0.000455 | 0.018598 | 0.018548 | 0.018142 | 0.018092 | 127.500000 | 146.370000 | 11.158560 | 11.128597 | 10.885339 | 10.855376 | mansard roof profile | intumescent paint | 0 | A2
A2 | 5F | A2 - mansard roof profile :5,SHE-13.STEEL.dgn,Design Model:125198 | FD60 | UC203X203X127 | 1\BS5950_UC\UC203X203X127 | B-7 [0.951, 0.150] | 0.672919 | 0.0162 | 0.016157 | 0.876275 | 0.867537 | 0.000309 | 0.010901 | 0.010872 | 0.010592 | 0.010563 | 127.500000 | 85.797167 | 6.540772 | 6.523209 | 6.355454 | 6.337891 | mansard roof profile | intumescent paint | 0 | A2
A2 | 5F | A2 - mansard roof profile :5,SHE-13.STEEL.dgn,Design Model:125200 | FD60 | UC203X203X127 | 1\BS5950_UC\UC203X203X127 | B-5 [0.951 , -0.150] | 0.672919 | 0.0162 | 0.016157 | 0.876275 | 0.867537 | 0.000309 | 0.010901 | 0.010872 | 0.010592 | 0.010563 | 127.500000 | 85.797167 | 6.540772 | 6.523209 | 6.355454 | 6.337891 | mansard roof profile | intumescent paint | 0 | A2
A2 | 5F | A2 - mansard roof profile :5,SHE-13.STEEL.dgn,Design Model:125202 | FD60 | UC203X203X127 | 1\BS5950_UC\UC203X203X127 | M-7 [-0.298 , 0.150] | 0.673 | 0.0162 | 0.016157 | 0.876381 | 0.867643 | 0.000309 | 0.010903 | 0.010873 | 0.010594 | 0.010564 | 127.500000 | 85.807500 | 6.541560 | 6.523995 | 6.356242 | 6.338676 | mansard roof profile | intumescent paint | 0 | A2
A2 | 5F | A2 - mansard roof profile :5,SHE-13.STEEL.dgn,Design Model:125204 | FD60 | UC203X203X127 | 1\BS5950_UC\UC203X203X127 | M-5 [-0.298 , -0.150] | 0.673 | 0.0162 | 0.016157 | 0.876381 | 0.867643 | 0.000309 | 0.010903 | 0.010873 | 0.010594 | 0.010564 | 127.500000 | 85.807500 | 6.541560 | 6.523995 | 6.356242 | 6.338676 | mansard roof profile | intumescent paint | 0 | A2
A2 | 5F | A2 - mansard roof profile :5,SHE-13.STEEL.dgn,Design Model:125206 | FD60 | UC203X203X127 | 1\BS5950_UC\UC203X203X127 | M-3 [-0.369 , -0.349] | 1.065 | 0.0162 | 0.016156 | 1.38684 | 1.33746 | 0.000813 | 0.017253 | 0.017207 | 0.01644 | 0.016393 | 127.500000 | 135.787500 | 10.351800 | 10.324004 | 9.863878 | 9.836081 | mansard roof profile | intumescent paint | 0 | A2
A2 | 5F | A2 - mansard roof profile :5,SHE-13.STEEL.dgn,Design Model:125208 | FD60 | UC203X203X127 | 1\BS5950_UC\UC203X203X127 | L-9 [1.079 , -0.406] | 1.065 | 0.0162 | 0.016156 | 1.38684 | 1.33801 | 0.000808 | 0.017253 | 0.017207 | 0.016445 | 0.016399 | 127.500000 | 135.787500 | 10.351800 | 10.324004 | 9.867236 | 9.839440 | mansard roof profile | intumescent paint | 0 | A2
A2 | 5F | A2 - mansard roof profile :5,SHE-13.STEEL.dgn,Design Model:125210 | FD60 | UC203X203X127 | 1\BS5950_UC\UC203X203X127 | B-9 [0.349, 0.349] | 1.066 | 0.0162 | 0.016156 | 1.38814 | 1.33876 | 0.000813 | 0.017269 | 0.017223 | 0.016456 | 0.01641 | 127.500000 | 135.915000 | 10.361520 | 10.333697 | 9.873598 | 9.845775 | mansard roof profile | intumescent paint | 0 | A2
A2 | 5F | A2 - mansard roof profile :5,SHE-13.STEEL.dgn,Design Model:125212 | FD60 | UC203X203X127 | 1\BS5950_UC\UC203X203X127 | C-3 [-1.099 , 0.407] | 1.06588 | 0.0162 | 0.016157 | 1.38799 | 1.3386 | 0.000813 | 0.017267 | 0.017221 | 0.016454 | 0.016408 | 127.500000 | 135.899522 | 10.360340 | 10.332521 | 9.872418 | 9.844598 | mansard roof profile | intumescent paint | 0 | A2
A2 | 5F | A2 - mansard roof profile :5,SHE-13.STEEL.dgn,Design Model:140408 | FD60 | UC203X203X127 | 1\BS5950_UC\UC203X203X127 | L-2 [-0.210 , 0.220] | 2.26923 | 0.0162 | 0.016157 | 2.95499 | 2.84764 | 0.001332 | 0.036761 | 0.036663 | 0.03543 | 0.035331 | 127.500000 | 289.326245 | 22.056871 | 21.997645 | 21.257800 | 21.198574 | mansard roof profile | intumescent paint | 0 | A2
A2 | 5F | A2 - mansard roof profile :5,SHE-13.STEEL.dgn,Design Model:140410 | FD60 | UC203X203X127 | 1\BS5950_UC\UC203X203X127 | L-3 [-0.210 , -0.427] | 0.677837 | 0.0162 | 0.016157 | 0.882679 | 0.817008 | 0.001015 | 0.010981 | 0.010951 | 0.009966 | 0.009936 | 127.500000 | 86.424216 | 6.588576 | 6.570884 | 5.979426 | 5.961734 | mansard roof profile | intumescent paint | 0 | A2
A2 | 5F | A2 - mansard roof profile :5,SHE-13.STEEL.dgn,Design Model:140415 | FD60 | UC203X203X127 | 1\BS5950_UC\UC203X203X127 | G-2 [0.000, 0.220] | 2.26923 | 0.0162 | 0.016156 | 2.95499 | 2.84764 | 0.001332 | 0.036761 | 0.036663 | 0.03543 | 0.035331 | 127.500000 | 289.326245 | 22.056871 | 21.997645 | 21.257800 | 21.198574 | mansard roof profile | intumescent paint | 0 | A2
A2 | 5F | A2 - mansard roof profile :5,SHE-13.STEEL.dgn,Design Model:140417 | FD60 | UC203X203X127 | 1\BS5950_UC\UC203X203X127 | G-3 [-0.000 , -0.427] | 0.727837 | 0.0162 | 0.016157 | 0.947789 | 0.882118 | 0.001015 | 0.011791 | 0.011759 | 0.010776 | 0.010744 | 127.500000 | 92.799216 | 7.074576 | 7.055579 | 6.465426 | 6.446429 | mansard roof profile | intumescent paint | 0 | A2
A2 | 5F | A2 - mansard roof profile :5,SHE-13.STEEL.dgn,Design Model:140429 | FD60 | UC203X203X127 | 1\BS5950_UC\UC203X203X127 | C-2 [0.210, 0.220] | 2.26923 | 0.0162 | 0.016157 | 2.95499 | 2.84764 | 0.001332 | 0.036761 | 0.036663 | 0.03543 | 0.035331 | 127.500000 | 289.326245 | 22.056871 | 21.997645 | 21.257800 | 21.198574 | mansard roof profile | intumescent paint | 0 | A2
A2 | 5F | A2 - mansard roof profile :5,SHE-13.STEEL.dgn,Design Model:140431 | FD60 | UC203X203X127 | 1\BS5950_UC\UC203X203X127 | C-3 [0.210 , -0.427] | 0.677837 | 0.0162 | 0.016157 | 0.882679 | 0.817008 | 0.001015 | 0.010981 | 0.010951 | 0.009966 | 0.009936 | 127.500000 | 86.424216 | 6.588576 | 6.570884 | 5.979426 | 5.961734 | mansard roof profile | intumescent paint | 0 | A2
A2 | 5F | A2 - mansard roof profile :5,SHE-13.STEEL.dgn,Design Model:140441 | FD60 | UC203X203X127 | 1\BS5950_UC\UC203X203X127 | G-9 [0.000, 0.328] | 2.26923 | 0.0162 | 0.016156 | 2.95499 | 2.84764 | 0.001332 | 0.036761 | 0.036663 | 0.03543 | 0.035331 | 127.500000 | 289.326245 | 22.056871 | 21.997645 | 21.257800 | 21.198574 | mansard roof profile | intumescent paint | 0 | A2
A2 | 5F | A2 - mansard roof profile :5,SHE-13.STEEL.dgn,Design Model:140443 | FD60 | UC203X203X127 | 1\BS5950_UC\UC203X203X127 | G-9 [0.000 , -0.301] | 0.727837 | 0.0162 | 0.016157 | 0.947789 | 0.882118 | 0.001015 | 0.011791 | 0.011759 | 0.010776 | 0.010744 | 127.500000 | 92.799216 | 7.074576 | 7.055579 | 6.465426 | 6.446429 | mansard roof profile | intumescent paint | 0 | A2
A2 | 5F | A2 - mansard roof profile :5,SHE-13.STEEL.dgn,Design Model:140452 | FD60 | UC203X203X127 | 1\BS5950_UC\UC203X203X127 | L-9 [-0.210 , 0.328] | 2.26923 | 0.0162 | 0.016156 | 2.95499 | 2.84764 | 0.001332 | 0.036761 | 0.036663 | 0.03543 | 0.035331 | 127.500000 | 289.326245 | 22.056871 | 21.997645 | 21.257800 | 21.198574 | mansard roof profile | intumescent paint | 0 | A2
A2 | 5F | A2 - mansard roof profile :5,SHE-13.STEEL.dgn,Design Model:140454 | FD60 | UC203X203X127 | 1\BS5950_UC\UC203X203X127 | L-9 [-0.210 , -0.251] | 0.677837 | 0.0162 | 0.016157 | 0.882679 | 0.817008 | 0.001015 | 0.010981 | 0.010951 | 0.009966 | 0.009936 | 127.500000 | 86.424216 | 6.588576 | 6.570884 | 5.979426 | 5.961734 | mansard roof profile | intumescent paint | 0 | A2
A2 | 5F | A2 - mansard roof profile :5,SHE-13.STEEL.dgn,Design Model:140456 | FD60 | UC203X203X127 | 1\BS5950_UC\UC203X203X127 | C-9 [0.210, 0.328] | 2.26923 | 0.0162 | 0.016156 | 2.95499 | 2.84764 | 0.001332 | 0.036761 | 0.036663 | 0.03543 | 0.035331 | 127.500000 | 289.326245 | 22.056871 | 21.997645 | 21.257800 | 21.198574 | mansard roof profile | intumescent paint | 0 | A2
A2 | 5F | A2 - mansard roof profile :5,SHE-13.STEEL.dgn,Design Model:140458 | FD60 | UC203X203X127 | 1\BS5950_UC\UC203X203X127 | C-9 [0.210 , -0.251] | 0.677837 | 0.0162 | 0.016157 | 0.882679 | 0.817008 | 0.001015 | 0.010981 | 0.010951 | 0.009966 | 0.009936 | 127.500000 | 86.424216 | 6.588576 | 6.570884 | 5.979426 | 5.961734 | mansard roof profile | intumescent paint | 0 | A2
A-Columns-Steel | GF | 15 ,SHE-14.BALCONY.dgn,Design Model:168506 |  | UC152X152X51 | 1\BS5950_UC\UC152X152X51 | N-12 [-0.595 , 0.016] | 4.894 | 0.0065 | 0.006469 | 4.63951 | 4.65245 | 0 | 0.031811 | 0.03166 | 0.031811 | 0.03166 | 51.200000 | 250.572800 | 19.086600 | 18.996041 | 19.086600 | 18.996041 |  |  | 0 | Construction Phase - Phase: Temporary Construction
A-Columns-Steel | GF | 15 ,SHE-14.BALCONY.dgn,Design Model:168508 |  | UC152X152X51 | 1\BS5950_UC\UC152X152X51 | N-13 [-0.595 , 0.013] | 4.894 | 0.0065 | 0.006469 | 4.63951 | 4.65245 | 0 | 0.031811 | 0.03166 | 0.031811 | 0.03166 | 51.200000 | 250.572800 | 19.086600 | 18.996041 | 19.086600 | 18.996041 |  |  | 0 | Construction Phase - Phase: Temporary Construction
A-Columns-Steel | GF | 15 ,SHE-14.BALCONY.dgn,Design Model:168510 |  | UC152X152X51 | 1\BS5950_UC\UC152X152X51 | M-13 [0.355 , 0.013] | 4.894 | 0.0065 | 0.006469 | 4.63951 | 4.65245 | 0 | 0.031811 | 0.03166 | 0.031811 | 0.03166 | 51.200000 | 250.572800 | 19.086600 | 18.996041 | 19.086600 | 18.996041 |  |  | 0 | Construction Phase - Phase: Temporary Construction
A-Columns-Steel | GF | 15 ,SHE-14.BALCONY.dgn,Design Model:168512 |  | UC152X152X51 | 1\BS5950_UC\UC152X152X51 | M-12 [0.355 , 0.016] | 4.894 | 0.0065 | 0.006469 | 4.63951 | 4.65245 | 0 | 0.031811 | 0.03166 | 0.031811 | 0.03166 | 51.200000 | 250.572800 | 19.086600 | 18.996041 | 19.086600 | 18.996041 |  |  | 0 | Construction Phase - Phase: Temporary Construction
A-Columns-Steel | GF | 15 ,SHE-14.BALCONY.dgn,Design Model:168514 |  | UC152X152X51 | 1\BS5950_UC\UC152X152X51 | L-13 [-0.015 , 0.013] | 4.894 | 0.0065 | 0.006469 | 4.63951 | 4.65245 | 0 | 0.031811 | 0.03166 | 0.031811 | 0.03166 | 51.200000 | 250.572800 | 19.086600 | 18.996041 | 19.086600 | 18.996041 |  |  | 0 | Construction Phase - Phase: Temporary Construction
A-Columns-Steel | GF | 15 ,SHE-14.BALCONY.dgn,Design Model:168516 |  | UC152X152X51 | 1\BS5950_UC\UC152X152X51 | L-12 [-0.015 , 0.016] | 4.894 | 0.0065 | 0.006469 | 4.63951 | 4.65245 | 0 | 0.031811 | 0.03166 | 0.031811 | 0.03166 | 51.200000 | 250.572800 | 19.086600 | 18.996041 | 19.086600 | 18.996041 |  |  | 0 | Construction Phase - Phase: Temporary Construction
A-Columns-Steel | GF | 15 ,SHE-14.BALCONY.dgn,Design Model:168518 |  | UC152X152X51 | 1\BS5950_UC\UC152X152X51 | K-13 [0.997 , 0.013] | 4.894 | 0.0065 | 0.006469 | 4.63951 | 4.65245 | 0 | 0.031811 | 0.03166 | 0.031811 | 0.03166 | 51.200000 | 250.572800 | 19.086600 | 18.996041 | 19.086600 | 18.996041 |  |  | 0 | Construction Phase - Phase: Temporary Construction
A-Columns-Steel | GF | 15 ,SHE-14.BALCONY.dgn,Design Model:168520 |  | UC152X152X51 | 1\BS5950_UC\UC152X152X51 | K-12 [0.997 , 0.016] | 4.894 | 0.0065 | 0.006469 | 4.63951 | 4.65245 | 0 | 0.031811 | 0.03166 | 0.031811 | 0.03166 | 51.200000 | 250.572800 | 19.086600 | 18.996041 | 19.086600 | 18.996041 |  |  | 0 | Construction Phase - Phase: Temporary Construction
A-Columns-Steel | GF | 15 ,SHE-14.BALCONY.dgn,Design Model:179408 |  | UC152X152X51 | 1\BS5950_UC\UC152X152X51 | N-13 [-0.595 , 0.013] | 3.353 | 0.0065 | 0.006469 | 3.17864 | 3.19158 | 0 | 0.021795 | 0.021691 | 0.021795 | 0.021691 | 51.200000 | 171.673600 | 13.076700 | 13.014656 | 13.076700 | 13.014656 |  |  | 0 | Construction Phase - Phase: Temporary Construction
A-Columns-Steel | GF | 15 ,SHE-14.BALCONY.dgn,Design Model:179410 |  | UC152X152X51 | 1\BS5950_UC\UC152X152X51 | N-12 [-0.595 , 0.016] | 3.353 | 0.0065 | 0.006469 | 3.17864 | 3.19158 | 0 | 0.021795 | 0.021691 | 0.021795 | 0.021691 | 51.200000 | 171.673600 | 13.076700 | 13.014656 | 13.076700 | 13.014656 |  |  | 0 | Construction Phase - Phase: Temporary Construction
A-Columns-Steel | GF | 15 ,SHE-14.BALCONY.dgn,Design Model:179412 |  | UC152X152X51 | 1\BS5950_UC\UC152X152X51 | M-13 [0.355 , 0.013] | 3.353 | 0.0065 | 0.006469 | 3.17864 | 3.19158 | 0 | 0.021795 | 0.021691 | 0.021795 | 0.021691 | 51.200000 | 171.673600 | 13.076700 | 13.014656 | 13.076700 | 13.014656 |  |  | 0 | Construction Phase - Phase: Temporary Construction
A-Columns-Steel | GF | 15 ,SHE-14.BALCONY.dgn,Design Model:179414 |  | UC152X152X51 | 1\BS5950_UC\UC152X152X51 | M-12 [0.355 , 0.016] | 3.353 | 0.0065 | 0.006469 | 3.17864 | 3.19158 | 0 | 0.021795 | 0.021691 | 0.021795 | 0.021691 | 51.200000 | 171.673600 | 13.076700 | 13.014656 | 13.076700 | 13.014656 |  |  | 0 | Construction Phase - Phase: Temporary Construction
A-Columns-Steel | GF | 15 ,SHE-14.BALCONY.dgn,Design Model:179416 |  | UC152X152X51 | 1\BS5950_UC\UC152X152X51 | L-13 [-0.015 , 0.013] | 3.353 | 0.0065 | 0.006469 | 3.17864 | 3.19158 | 0 | 0.021795 | 0.021691 | 0.021795 | 0.021691 | 51.200000 | 171.673600 | 13.076700 | 13.014656 | 13.076700 | 13.014656 |  |  | 0 | Construction Phase - Phase: Temporary Construction
A-Columns-Steel | GF | 15 ,SHE-14.BALCONY.dgn,Design Model:179418 |  | UC152X152X51 | 1\BS5950_UC\UC152X152X51 | L-12 [-0.015 , 0.016] | 3.353 | 0.0065 | 0.006469 | 3.17864 | 3.19158 | 0 | 0.021795 | 0.021691 | 0.021795 | 0.021691 | 51.200000 | 171.673600 | 13.076700 | 13.014656 | 13.076700 | 13.014656 |  |  | 0 | Construction Phase - Phase: Temporary Construction
A-Columns-Steel | GF | 15 ,SHE-14.BALCONY.dgn,Design Model:179420 |  | UC152X152X51 | 1\BS5950_UC\UC152X152X51 | K-13 [0.997 , 0.013] | 3.353 | 0.0065 | 0.006469 | 3.17864 | 3.19158 | 0 | 0.021795 | 0.021691 | 0.021795 | 0.021691 | 51.200000 | 171.673600 | 13.076700 | 13.014656 | 13.076700 | 13.014656 |  |  | 0 | Construction Phase - Phase: Temporary Construction
A-Columns-Steel | GF | 15 ,SHE-14.BALCONY.dgn,Design Model:179422 |  | UC152X152X51 | 1\BS5950_UC\UC152X152X51 | K-12 [0.997 , 0.016] | 3.353 | 0.0065 | 0.006469 | 3.17864 | 3.19158 | 0 | 0.021795 | 0.021691 | 0.021795 | 0.021691 | 51.200000 | 171.673600 | 13.076700 | 13.014656 | 13.076700 | 13.014656 |  |  | 0 | Construction Phase - Phase: Temporary Construction
A-Columns-Steel | GF | 15 ,SHE-14.BALCONY.dgn,Design Model:179424 |  | UC152X152X51 | 1\BS5950_UC\UC152X152X51 | K-13 [0.997 , 0.013] | 3.413 | 0.0065 | 0.006469 | 3.23552 | 3.24846 | 0 | 0.022184 | 0.022079 | 0.022184 | 0.022079 | 51.200000 | 174.745600 | 13.310700 | 13.247546 | 13.310700 | 13.247546 |  |  | 0 | Construction Phase - Phase: Temporary Construction
A-Columns-Steel | GF | 15 ,SHE-14.BALCONY.dgn,Design Model:179426 |  | UC152X152X51 | 1\BS5950_UC\UC152X152X51 | K-12 [0.997 , 0.016] | 3.413 | 0.0065 | 0.006469 | 3.23552 | 3.24846 | 0 | 0.022184 | 0.022079 | 0.022184 | 0.022079 | 51.200000 | 174.745600 | 13.310700 | 13.247546 | 13.310700 | 13.247546 |  |  | 0 | Construction Phase - Phase: Temporary Construction
A-Columns-Steel | GF | 15 ,SHE-14.BALCONY.dgn,Design Model:179428 |  | UC152X152X51 | 1\BS5950_UC\UC152X152X51 | L-13 [-0.015 , 0.013] | 3.413 | 0.0065 | 0.006469 | 3.23552 | 3.24846 | 0 | 0.022184 | 0.022079 | 0.022184 | 0.022079 | 51.200000 | 174.745600 | 13.310700 | 13.247546 | 13.310700 | 13.247546 |  |  | 0 | Construction Phase - Phase: Temporary Construction
A-Columns-Steel | GF | 15 ,SHE-14.BALCONY.dgn,Design Model:179430 |  | UC152X152X51 | 1\BS5950_UC\UC152X152X51 | L-12 [-0.015 , 0.016] | 3.413 | 0.0065 | 0.006469 | 3.23552 | 3.24846 | 0 | 0.022184 | 0.022079 | 0.022184 | 0.022079 | 51.200000 | 174.745600 | 13.310700 | 13.247546 | 13.310700 | 13.247546 |  |  | 0 | Construction Phase - Phase: Temporary Construction
A-Columns-Steel | GF | 15 ,SHE-14.BALCONY.dgn,Design Model:179432 |  | UC152X152X51 | 1\BS5950_UC\UC152X152X51 | M-13 [0.355 , 0.013] | 3.413 | 0.0065 | 0.006469 | 3.23552 | 3.24846 | 0 | 0.022184 | 0.022079 | 0.022184 | 0.022079 | 51.200000 | 174.745600 | 13.310700 | 13.247546 | 13.310700 | 13.247546 |  |  | 0 | Construction Phase - Phase: Temporary Construction
A-Columns-Steel | GF | 15 ,SHE-14.BALCONY.dgn,Design Model:179434 |  | UC152X152X51 | 1\BS5950_UC\UC152X152X51 | M-12 [0.355 , 0.016] | 3.413 | 0.0065 | 0.006469 | 3.23552 | 3.24846 | 0 | 0.022184 | 0.022079 | 0.022184 | 0.022079 | 51.200000 | 174.745600 | 13.310700 | 13.247546 | 13.310700 | 13.247546 |  |  | 0 | Construction Phase - Phase: Temporary Construction
A-Columns-Steel | GF | 15 ,SHE-14.BALCONY.dgn,Design Model:179436 |  | UC152X152X51 | 1\BS5950_UC\UC152X152X51 | N-13 [-0.595 , 0.013] | 3.413 | 0.0065 | 0.006469 | 3.23552 | 3.24846 | 0 | 0.022184 | 0.022079 | 0.022184 | 0.022079 | 51.200000 | 174.745600 | 13.310700 | 13.247546 | 13.310700 | 13.247546 |  |  | 0 | Construction Phase - Phase: Temporary Construction
A-Columns-Steel | GF | 15 ,SHE-14.BALCONY.dgn,Design Model:179438 |  | UC152X152X51 | 1\BS5950_UC\UC152X152X51 | N-12 [-0.595 , 0.016] | 3.413 | 0.0065 | 0.006469 | 3.23552 | 3.24846 | 0 | 0.022184 | 0.022079 | 0.022184 | 0.022079 | 51.200000 | 174.745600 | 13.310700 | 13.247546 | 13.310700 | 13.247546 |  |  | 0 | Construction Phase - Phase: Temporary Construction

# IfcColumn: A-Columns:A_BSUK_Columns_ReinforcedConcrete (2)
In: GF
Material: A_BSUK_Columns_ReinforcedConcrete
BuildingDesignerForm - Cope Flange Clearance: 0.000; Cope Web Clearance: 0.000; Cope Corner Treatment: 0; Cope Corner Radius: 0.000; Local Y Offset: 0.000; Local Z Offset: 0.000
Name | Description | Section Name
A-Columns--A_BSUK_Columns_ReinforcedConcrete | 16,SHE-12.STAIR.dgn ,Design Model:202031 | 0.670X0.300
A-Columns--A_BSUK_Columns_ReinforcedConcrete | 16,SHE-12.STAIR.dgn ,Design Model:202033 | 0.500X0.300

# IfcColumn: A-Columns:A_BSUK_Columns_Steel (2)
In: GF
Material: A_BSUK_Columns_Steel
StructuralFramingCommon - Section Name: UC203X203X127
BuildingDesignerForm - Cope Flange Clearance: 0.000; Cope Web Clearance: 0.000; Cope Corner Treatment: 0; Cope Corner Radius: 0.000; Local Y Offset: 0.000; Local Z Offset: 0.000
Name | Description
A-Columns--A_BSUK_Columns_Steel | 11,SHE-15.MEHP.dgn,Design Model:127930
A-Columns--A_BSUK_Columns_Steel | 11,SHE-15.MEHP.dgn,Design Model:128039

# IfcCurtainWall: Generic - Maximum Spacing (4)
Type - Space Bounding - Is Space Bounding: yes
Type - Materials - Part Definition: A-CurtainWall::A-CurtainWall_Frame
Type - Curtain Wall | Panel - Panel | Type: Glazing Type 1; Panel | Thickness: 0.02 m; Panel | Offset: 0 m
Type - Curtain Wall | Mullion - Vertical - Vertical | Profile: _Generic - Mullion; Vertical | Width: 0.05 m; Vertical | Depth: 0.15 m
Type - Curtain Wall | Mullion - Horizontal - Horizontal | Profile: _Generic - Mullion; Horizontal | Width: 0.05 m; Horizontal | Depth: 0.15 m
Type - Curtain Wall | Frame - Sill - Sill | Same as Jamb: yes
Type - Curtain Wall | Frame - Jamb - Jamb | Profile: _Generic - Frame; Jamb | Width: 0.05 m; Jamb | Depth: 0.15 m
Type - Curtain Wall | Frame - Head - Head | Same as Jamb: yes
Type - Curtain Wall | Frame - Corner - Corner | Profile: _Generic - Corner; Corner | Width: 0.05 m; Corner | Depth: 0.15 m
Type - Curtain Wall Properties - Hurricane Resistant: no
Type - Curtain Wall Parameters - Curtain Wall Type: Storefront; Perforate Host: yes; Sense Distance: 0.3 m; Mullion Continuity: Continuous Vertical; Layout | Horizontal Layout: Maximum Spacing; Layout | Horizontal Justification: Bottom; Layout | Horizontal Number: 1; Layout | Horizontal Spacing: 2 m; Layout | Horizontal Pattern: no; Layout | Horizontal Pattern Spacing: 2000;1000;1000; Layout | Vertical Layout: Maximum Spacing; Layout | Vertical Justification: Start; Layout | Vertical Number: 1; Layout | Vertical Spacing: 1 m; Layout | Vertical Pattern: no; Layout | Vertical Pattern Spacing: 3000;1000
Type - Classification - Uniclass2015: Ss_25_10_20
Material: A-CurtainWall_Frame
Identification - ID | Description: AOV1 vented hall louver
Curtain Wall | Panel - Panel | Type: Louvers
Curtain Wall | Frame - Sill - Sill | Profile: _Generic - Frame; Sill | Width: 0.05 m; Sill | Depth: 0.15 m
Curtain Wall | Frame - Head - Head | Profile: _Generic - Frame; Head | Width: 0.05 m; Head | Depth: 0.15 m
Curtain Wall | Frame - Corner - Corner | Width: 0.18 m
Curtain Wall Parameters - Curtain Wall Type: Punched Opening; Height: 1.5 m; Length: 0.9 m; Layout | Horizontal Spacing: 1.5 m; Layout | Horizontal Pattern Spacing: 2.000;1.000;1.000; Layout | Vertical Spacing: 1.5 m; Layout | Vertical Pattern Spacing: 3.000;1.000
Name | In | Description
Generic - Maximum Spacing | 1F | AOV1 vented hall louver :4,SHE-03.FIRST.dgn,Design Model:147014
Generic - Maximum Spacing | 3F | AOV1 vented hall louver :6,SHE-05.THIRD.dgn,Design Model:147014
Generic - Maximum Spacing | 1F | AOV1 vented hall louver :7,SHE-06.FOURTH.dgn,Design Model:212650 | Curtain Wall | Frame - Jamb - Jamb | Profile: SHE_50x100Center - Frame; Jamb | Depth: 0.1 m
Generic - Maximum Spacing | 2F | AOV1 vented hall louver :18,SHE-04.SECOND.dgn,Design Model:147014

# IfcCurtainWall: Pattern - Maximum Spacing (30)
In: 1F
Type - Space Bounding - Is Space Bounding: yes
Type - Materials - Part Definition: A-CurtainWall::A-CurtainWall_Frame
Type - Curtain Wall | Panel - Panel | Type: Glazing Type 1; Panel | Thickness: 0.02 m; Panel | Offset: 0 m
Type - Curtain Wall | Mullion - Vertical - Vertical | Profile: _Generic - Mullion; Vertical | Width: 0.05 m; Vertical | Depth: 0.15 m
Type - Curtain Wall | Mullion - Horizontal - Horizontal | Profile: _Generic - Mullion; Horizontal | Width: 0.05 m; Horizontal | Depth: 0.15 m
Type - Curtain Wall | Frame - Sill - Sill | Same as Jamb: yes
Type - Curtain Wall | Frame - Jamb - Jamb | Profile: _Generic - Frame; Jamb | Width: 0.05 m; Jamb | Depth: 0.15 m
Type - Curtain Wall | Frame - Head - Head | Same as Jamb: yes
Type - Curtain Wall | Frame - Corner - Corner | Profile: _Generic - Corner; Corner | Width: 0.05 m; Corner | Depth: 0.15 m
Type - Curtain Wall Properties - Hurricane Resistant: no
Type - Curtain Wall Parameters - Curtain Wall Type: Storefront; Perforate Host: yes; Sense Distance: 0.3 m; Mullion Continuity: Continuous Vertical; Layout | Horizontal Layout: Maximum Spacing; Layout | Horizontal Justification: Bottom; Layout | Horizontal Number: 1; Layout | Horizontal Spacing: 2 m; Layout | Horizontal Pattern: yes; Layout | Horizontal Pattern Spacing: 2000;1000;1000; Layout | Vertical Layout: Maximum Spacing; Layout | Vertical Justification: Start; Layout | Vertical Number: 1; Layout | Vertical Spacing: 1 m; Layout | Vertical Pattern: yes; Layout | Vertical Pattern Spacing: 3000;1000
Type - Classification - Uniclass2015: Ss_25_10_20
Material: A-CurtainWall_Frame
Identification - ID | Type ID: U-Value 1.4; ID | Name (Alternate): G-Value 0.6; ID | Asset Tag: safety glass internal up to 800mm, balustrade Part K compliance , brocken mullion, double glazed opaque spandral panel , no capping above spandral panel
Curtain Wall | Panel - Panel | Thickness: 0.01 m
Curtain Wall | Mullion - Vertical - Vertical | Profile: SHE_50x100Center - Mullion; Vertical | Depth: 0.1 m
Curtain Wall | Mullion - Horizontal - Horizontal | Profile: SHE_50x100Center - Mullion; Horizontal | Depth: 0.1 m
Curtain Wall | Frame - Sill - Sill | Profile: _Generic - Frame; Sill | Width: 0.05 m; Sill | Depth: 0.15 m
Curtain Wall | Frame - Jamb - Jamb | Profile: SHE_50x100Center - Frame; Jamb | Depth: 0.1 m
Curtain Wall | Frame - Head - Head | Profile: _Generic - Frame; Head | Width: 0.05 m; Head | Depth: 0.15 m
Curtain Wall | Frame - Corner - Corner | Width: 0.18 m
Curtain Wall Parameters - Curtain Wall Type: Curtain Wall; Length: 1.52 m; Layout | Vertical Pattern Spacing: 1.60
Name | Description | ID | Number | ID | Description | ID | Keynote | ID | Notes | Height (m) | Layout | Horizontal Pattern Spacing
09 | U-Value 1.4 - bedroom at back/over flat roof :3,SHE-09.FACADE.dgn ,Design Model:105400 | 09 | bedroom at back/over flat roof | Rw 37dB, Rw+Ctr 35dB , trickle vent 45dB | 3 x tilt and turn windows 1.4x1.6m | 8.2 | 1.200;0.900;0.900;1.700;0.900;0.900;1.680;
02 | U-Value 1.4 - kdl at back :3,SHE-09.FACADE.dgn,Design Model:105404 | 02 | kdl at back | Rw 34dB, Rw+Ctr 30dB , trickle vent 45dB | 3 x tilt and turn windows 1.4x1.6m | 10.75 | 1.130;0.900;1.700;0.900;0.900;1.700;0.900;0.900;1.680;
03 | U-Value 1.4 - bedroom at back :3,SHE-09.FACADE.dgn,Design Model:105409 | 03 | bedroom at back | Rw 37dB, Rw+Ctr 35dB , trickle vent 45dB | 3 x tilt and turn windows 1.4x1.6m | 10.75 | 1.130;0.900;1.700;0.900;0.900;1.700;0.900;0.900;1.680;
04 | U-Value 1.4 - bedroom at back :3,SHE-09.FACADE.dgn,Design Model:105414 | 04 | bedroom at back | Rw 37dB, Rw+Ctr 35dB , trickle vent 45dB | 3 x tilt and turn windows 1.4x1.6m | 10.75 | 1.130;0.900;1.700;0.900;0.900;1.700;0.900;0.900;1.680;
05 | U-Value 1.4 - bedroom at back :3,SHE-09.FACADE.dgn,Design Model:105419 | 05 | bedroom at back | Rw 37dB, Rw+Ctr 35dB , trickle vent 45dB | 3 x tilt and turn windows 1.4x1.6m | 10.75 | 1.130;0.900;1.700;0.900;0.900;1.700;0.900;0.900;1.680;
06 | U-Value 1.4 - kdl at back :3,SHE-09.FACADE.dgn,Design Model:105424 | 06 | kdl at back | Rw 34dB, Rw+Ctr 30dB , trickle vent 45dB | 3 x tilt and turn windows 1.4x1.6m | 10.75 | 1.130;0.900;1.700;0.900;0.900;1.700;0.900;0.900;1.680;
07 | U-Value 1.4 - kdl at back :3,SHE-09.FACADE.dgn,Design Model:105429 | 07 | kdl at back | Rw 34dB, Rw+Ctr 30dB , trickle vent 45dB | 3 x tilt and turn windows 1.4x1.6m | 10.75 | 1.130;0.900;1.700;0.900;0.900;1.700;0.900;0.900;1.680;
08 | U-Value 1.4 - bedroom at back :3,SHE-09.FACADE.dgn,Design Model:105434 | 08 | bedroom at back | Rw 37dB, Rw+Ctr 35dB , trickle vent 45dB | 3 x tilt and turn windows 1.4x1.6m | 10.75 | 1.130;0.900;1.700;0.900;0.900;1.700;0.900;0.900;1.680;
01 | U-Value 1.4 - kdl at back with balcony doors :3,SHE-09.FACADE.dgn ,Design Model:106177 | 01 | kdl at back with balcony doors | Rw 34dB, Rw+Ctr 30dB , trickle vent 45dB | 3 x glass doors 1.05x2 ,1m with top/side panel | 10.75 | 1.130;0.900;1.700;0.900;0.900;1.700;0.900;0.900;1.680;
10 | U-Value 1.4 - kdl at back/over flat roof :3,SHE-09.FACADE.dgn ,Design Model:106183 | 10 | kdl at back/over flat roof | Rw 34dB, Rw+Ctr 30dB , trickle vent 45dB | 3 x tilt and turn windows 1.4x1.6m | 8.2 | 1.200;0.900;0.900;1.700;0.900;0.900;1.680;
11 | U-Value 1.4 - kdl at back/over flat roof :3,SHE-09.FACADE.dgn ,Design Model:106188 | 11 | kdl at back/over flat roof | Rw 34dB, Rw+Ctr 30dB , trickle vent 45dB | 3 x tilt and turn windows 1.4x1.6m | 8.2 | 1.200;0.900;0.900;1.700;0.900;0.900;1.680;
12 | U-Value 1.4 - kdl at back/over flat roof :3,SHE-09.FACADE.dgn ,Design Model:106193 | 12 | kdl at back/over flat roof | Rw 34dB, Rw+Ctr 30dB , trickle vent 45dB | 3 x tilt and turn windows 1.4x1.6m | 8.2 | 1.200;0.900;0.900;1.700;0.900;0.900;1.680;
13 | U-Value 1.4 - bedroom at side :3,SHE-09.FACADE.dgn,Design Model:106198 | 13 | bedroom at side | Rw 37dB, Rw+Ctr 35dB , trickle vent 45dB | 3 x tilt and turn windows 1.4x1.6m | 8.7 | 1.700;0.900;0.900;1.700;0.900;0.900;1.680;
14 | U-Value 1.4 - kdl at side :3,SHE-09.FACADE.dgn,Design Model:106203 | 14 | kdl at side | Rw 34dB, Rw+Ctr 30dB , trickle vent 45dB | 3 x tilt and turn windows 1.4x1.6m | 8.7 | 1.700;0.900;0.900;1.700;0.900;0.900;1.680;
15 | U-Value 1.4 - kdl at side :3,SHE-09.FACADE.dgn,Design Model:106208 | 15 | kdl at side | Rw 34dB, Rw+Ctr 30dB , trickle vent 45dB | 3 x tilt and turn windows 1.4x1.6m | 8.7 | 1.700;0.900;0.900;1.700;0.900;0.900;1.680;
30 | U-Value 1.4 - kdl at side :3,SHE-09.FACADE.dgn,Design Model:106213 | 30 | kdl at side | Rw 34dB, Rw+Ctr 30dB , trickle vent 45dB | 3 x tilt and turn windows 1.4x1.6m | 8.7 | 1.700;0.900;0.900;1.700;0.900;0.900;1.680;
29 | U-Value 1.4 - kdl at side :3,SHE-09.FACADE.dgn,Design Model:106218 | 29 | kdl at side | Rw 34dB, Rw+Ctr 30dB , trickle vent 45dB | 3 x tilt and turn windows 1.4x1.6m | 8.7 | 1.700;0.900;0.900;1.700;0.900;0.900;1.680;
28 | U-Value 1.4 - kdl at side :3,SHE-09.FACADE.dgn,Design Model:106223 | 28 | kdl at side | Rw 34dB, Rw+Ctr 30dB , trickle vent 45dB | 3 x tilt and turn windows 1.4x1.6m | 8.7 | 1.700;0.900;0.900;1.700;0.900;0.900;1.680;
26 | U-Value 1.4 - bedroom at front :3,SHE-09.FACADE.dgn,Design Model:106227 | 26 | bedroom at front | Rw 37dB, Rw+Ctr 35dB , trickle vent 45dB | 3 x tilt and turn windows 1.4x1.6m | 10.75 | 1.130;0.900;1.700;0.900;0.900;1.700;0.900;0.900;1.680;
25 | U-Value 1.4 - bedroom at front :3,SHE-09.FACADE.dgn,Design Model:106232 | 25 | bedroom at front | Rw 37dB, Rw+Ctr 35dB , trickle vent 45dB | 3 x tilt and turn windows 1.4x1.6m | 10.75 | 1.130;0.900;1.700;0.900;0.900;1.700;0.900;0.900;1.680;
24 | U-Value 1.4 - kdl at front :3,SHE-09.FACADE.dgn,Design Model:106237 | 24 | kdl at front | Rw 34dB, Rw+Ctr 30dB , trickle vent 45dB | 3 x tilt and turn windows 1.4x1.6m | 10.75 | 1.130;0.900;1.700;0.900;0.900;1.700;0.900;0.900;1.680;
23 | U-Value 1.4 - kdl at front :3,SHE-09.FACADE.dgn,Design Model:106242 | 23 | kdl at front | Rw 34dB, Rw+Ctr 30dB , trickle vent 45dB | 3 x tilt and turn windows 1.4x1.6m | 10.75 | 1.130;0.900;1.700;0.900;0.900;1.700;0.900;0.900;1.680;
22 | U-Value 1.4 - kdl at front :3,SHE-09.FACADE.dgn,Design Model:106247 | 22 | kdl at front | Rw 34dB, Rw+Ctr 30dB , trickle vent 45dB | 3 x tilt and turn windows 1.4x1.6m | 10.75 | 1.130;0.900;1.700;0.900;0.900;1.700;0.900;0.900;1.680;
21 | U-Value 1.4 - kdl at front :3,SHE-09.FACADE.dgn,Design Model:106252 | 21 | kdl at front | Rw 34dB, Rw+Ctr 30dB , trickle vent 45dB | 3 x tilt and turn windows 1.4x1.6m | 10.75 | 1.130;0.900;1.700;0.900;0.900;1.700;0.900;0.900;1.680;
20 | U-Value 1.4 - kdl at front :3,SHE-09.FACADE.dgn,Design Model:106257 | 20 | kdl at front | Rw 34dB, Rw+Ctr 30dB , trickle vent 45dB | 3 x tilt and turn windows 1.4x1.6m | 10.75 | 1.130;0.900;1.700;0.900;0.900;1.700;0.900;0.900;1.680;
27 | U-Value 1.4 - bedroom at front :3,SHE-09.FACADE.dgn,Design Model:106262 | 27 | bedroom at front | Rw 37dB, Rw+Ctr 35dB , trickle vent 45dB | 3 x tilt and turn windows 1.4x1.6m | 10.75 | 1.130;0.900;1.700;0.900;0.900;1.700;0.900;0.900;1.680;
19 | U-Value 1.4 - kdl at front :3,SHE-09.FACADE.dgn,Design Model:106267 | 19 | kdl at front | Rw 34dB, Rw+Ctr 30dB , trickle vent 45dB | 3 x tilt and turn windows 1.4x1.6m | 10.75 | 1.130;0.900;1.700;0.900;0.900;1.700;0.900;0.900;1.680;
18 | U-Value 1.4 - bedroom at front :3,SHE-09.FACADE.dgn,Design Model:106272 | 18 | bedroom at front | Rw 37dB, Rw+Ctr 35dB , trickle vent 45dB | 3 x tilt and turn windows 1.4x1.6m | 10.75 | 1.130;0.900;1.700;0.900;0.900;1.700;0.900;0.900;1.680;
17 | U-Value 1.4 - bedroom at front :3,SHE-09.FACADE.dgn,Design Model:106277 | 17 | bedroom at front | Rw 37dB, Rw+Ctr 35dB , trickle vent 45dB | 3 x tilt and turn windows 1.4x1.6m | 10.75 | 1.130;0.900;1.700;0.900;0.900;1.700;0.900;0.900;1.680;
16 | U-Value 1.4 - bedroom at front :3,SHE-09.FACADE.dgn,Design Model:106282 | 16 | bedroom at front | Rw 37dB, Rw+Ctr 35dB , trickle vent 45dB | 3 x tilt and turn windows 1.4x1.6m | 10.75 | 1.130;0.900;1.700;0.900;0.900;1.700;0.900;0.900;1.680;

# IfcDistributionFlowElement: M-BmvCthwconnection-CTHWConnection (4)
Type - Parameters - Insulation | Thickness (mm): 0; Lining | Thickness (mm): 0; Correction Factor: 1.0; Wall Thickness: 0
Type - End Spec1_1 (1 Connection: Rect) - Width 1 (W1): 1150; Depth 1 (D1): 250
Type - Classification - Uniclass2015: Pr_60_60_13
Type - Cabinet Type with Hot Water Connection - Tag: CTHWConnection; Box | Height: 625; Box | Width: 1250; Box | Length: 1250; Connection 1 | Length (L1): 0; Coil Inlet | Top Offset: 50; Coil Inlet | Side Offset: 625; Coil Outlet | Top Offset: 50; Coil Outlet | Side Offset: 625; Coil Inlet-Outlet | Diameter: 50; Coil | Length: 50; Coil Inlet | Connection Side: 1-left; Coil Outlet | Connection Side: 2-right; Connection | End Type: -;; View Display: Iso
Material: M_BSUK_Ventilation
Parameters - Surface Area: 2.56391 m2; Center Of Gravity: 500.00; -0.93; 6.19;; Insulation | Surface Area: 0 m2; Lining | Surface Area: 0 m2; Status: BSUK; Air Flow: M
End Spec1_1 (1 Connection: Rect) - Width 1 (W1): 360
Cabinet Type with Hot Water Connection - Box | Width: 400; Box | Length: 1000; Coil Inlet | Side Offset: 350; Coil Outlet | Side Offset: 350
Name | In | Description
M-BmvCthwconnection-CTHWConnection | ter.26 | 8,SHE-07.FIFTH.dgn,Design Model:281830
M-BmvCthwconnection-CTHWConnection | ter.23 | 8,SHE-07.FIFTH.dgn,Design Model:282996
M-BmvCthwconnection-CTHWConnection | ter.24 | 8,SHE-07.FIFTH.dgn,Design Model:283090
M-BmvCthwconnection-CTHWConnection | ter.25 | 8,SHE-07.FIFTH.dgn,Design Model:283184

# IfcDoor: A-Doors-DoubleFlush, 0.05
In: ENTRANCE
Type - OperationType: DOUBLE_DOOR_SINGLE_SWING; ConstructionType: USERDEFINED; ParameterTakesPrecedence: no; Sizeable: no
Type - Lining - LiningDepth: 0.07 m; LiningThickness: 0.069 m
Type - Thermal Transmittance - Is External: no; Is Below Grade: no
Type - Fire Resistance - Fire | IsCombustible: no; Fire | Compartmentation: no
Type - Door Parameters - Parametric | File Type: PAZ; Parametric | File Name: DoorDoubleFlush; Dimension | Leaf Width: 1.726 m; Dimension | Height: 2.058 m; Dimension | Frame Depth: 0.07 m; Dimension | Frame Depth Match Wall: yes; Dimension | Architrave Width: 0.069 m; Dimension | Leaf Thickness: 0.04 m
Type - Door - Door | Type: F - Flush; Door | IsEgress: no; Frame | Material: HM
Type - Discipline - Discipline: Architectural
Type - Classification - Uniclass2015: Pr_30_59_23
Description: riser duct :1 ,SHE-01.GROUND.dgn,Design Model:101662; OverallHeight: 2.127 m; OverallWidth: 1.178 m; Material: A_BSUK_Doors
Pset_DoorCommon - FireExit: no; FireRating: FD30
Identification - ID | Number: 0.05; ID | Description: riser duct; ID | Keynote: FIRE DOOR KEEP CLOSED
Fire Resistance - Fire | Rating: FD30
Door Parameters - Dimension | Leaf Width: 1.04 m
Door - Door | Finish: white; Door | Under Cut: 0 m; Glazing: no; Louver: no
Construction Phase - Phase: New Construction

# IfcDoor: A-Doors-DoubleFlush, 0.17
In: 01
Type - OperationType: DOUBLE_DOOR_SINGLE_SWING; ConstructionType: USERDEFINED; ParameterTakesPrecedence: no; Sizeable: no
Type - Lining - LiningDepth: 0.08 m; LiningThickness: 0.069 m
Type - Thermal Transmittance - Is External: no; Is Below Grade: no
Type - Fire Resistance - Fire | IsCombustible: no; Fire | Compartmentation: no
Type - Door Parameters - Parametric | File Type: PAZ; Parametric | File Name: DoorDoubleFlush; Dimension | Leaf Width: 1.726 m; Dimension | Height: 2.058 m; Dimension | Frame Depth: 0.08 m; Dimension | Frame Depth Match Wall: yes; Dimension | Architrave Width: 0.069 m; Dimension | Leaf Thickness: 0.04 m
Type - Door - Door | Type: F - Flush; Door | IsEgress: no; Frame | Material: HM
Type - Discipline - Discipline: Architectural
Type - Classification - Uniclass2015: Pr_30_59_23
Description: storage :1 ,SHE-01.GROUND.dgn,Design Model:160385; OverallHeight: 2.127 m; OverallWidth: 1.178 m; Material: A_BSUK_Doors
Pset_DoorCommon - FireExit: no
Identification - ID | Number: 0.17; ID | Description: storage
Door Parameters - Dimension | Leaf Width: 1.04 m
Door - Door | Finish: white; Door | Under Cut: 0 m; Glazing: no; Louver: no
Construction Phase - Phase: New Construction

# IfcDoor: A-Doors-DoubleFlush (4)
Type - OperationType: DOUBLE_DOOR_SINGLE_SWING; ConstructionType: USERDEFINED; ParameterTakesPrecedence: no; Sizeable: no
Type - Lining - LiningDepth: 0.1 m; LiningThickness: 0.069 m
Type - Thermal Transmittance - Is External: no; Is Below Grade: no
Type - Fire Resistance - Fire | IsCombustible: no; Fire | Compartmentation: no
Type - Door Parameters - Parametric | File Type: PAZ; Parametric | File Name: DoorDoubleFlush; Dimension | Leaf Width: 1.726 m; Dimension | Height: 2.058 m; Dimension | Frame Depth: 0.1 m; Dimension | Frame Depth Match Wall: yes; Dimension | Architrave Width: 0.069 m; Dimension | Leaf Thickness: 0.04 m
Type - Door - Door | Type: F - Flush; Door | IsEgress: no; Frame | Material: HM
Type - Discipline - Discipline: Architectural
Type - Classification - Uniclass2015: Pr_30_59_23
Material: A_BSUK_Doors
Pset_DoorCommon - FireExit: no
Door - Door | Finish: white; Door | Under Cut: 0 m; Glazing: no; Louver: no
Construction Phase - Phase: New Construction
Name | In | Description | OverallHeight (m) | OverallWidth (m) | ID | Number | ID | Description | Dimension | Leaf Width (m)
0.02 | UNDERCROFT (back) | storage :1 ,SHE-01.GROUND.dgn,Design Model:98220 | 2.1 | 1.784 | 0.02 | storage | 1.7
0.03 | UNDERCROFT (back) | storage :1 ,SHE-01.GROUND.dgn,Design Model:98529 | 2.1 | 1.784 | 0.03 | storage | 1.7
0.23 | 01 | storage :2 ,SHE-02.MEZZANINE.dgn,Design Model:95957 | 2.127 | 1.658 | 0.23 | storage | 1.52
4.03 | hall (vented) | riser duct :7 ,SHE-06.FOURTH.dgn,Design Model:212337 | 2.13 | 0.984 | 4.03 | riser duct | 0.9 | Pset_DoorCommon - FireRating: FD30; Identification - ID | Keynote: FIRE DOOR KEEP CLOSED; Fire Resistance - Fire | Rating: FD30; Door Parameters - Dimension | Frame Depth Match Wall: no

# IfcDoor: A-Doors-DoubleFlush (3)
In: 2
Type - OperationType: DOUBLE_DOOR_SINGLE_SWING; ConstructionType: USERDEFINED; ParameterTakesPrecedence: no; Sizeable: no
Type - Lining - LiningDepth: 0.102 m; LiningThickness: 0.069 m
Type - Thermal Transmittance - Is External: no; Is Below Grade: no
Type - Fire Resistance - Fire | IsCombustible: no; Fire | Compartmentation: no
Type - Door Parameters - Parametric | File Type: PAZ; Parametric | File Name: DoorDoubleFlush; Dimension | Leaf Width: 1.726 m; Dimension | Height: 2.058 m; Dimension | Frame Depth: 0.102 m; Dimension | Frame Depth Match Wall: yes; Dimension | Architrave Width: 0.069 m; Dimension | Leaf Thickness: 0.04 m
Type - Door - Door | Type: F - Flush; Door | IsEgress: no; Frame | Material: HM
Type - Discipline - Discipline: Architectural
Type - Classification - Uniclass2015: Pr_30_59_23
OverallHeight: 2.1 m; OverallWidth: 0.984 m; Material: A_BSUK_Doors
Pset_DoorCommon - FireExit: no; FireRating: FD30
Identification - ID | Description: riser duct; ID | Keynote: FIRE DOOR KEEP CLOSED
Fire Resistance - Fire | Rating: FD30
Door Parameters - Dimension | Leaf Width: 0.9 m
Door - Door | Finish: white; Door | Under Cut: 0 m; Glazing: no; Louver: no
Construction Phase - Phase: New Construction
Name | Description | ID | Number
1.28 | riser duct :4 ,SHE-03.FIRST.dgn,Design Model:163330 | 1.28
3.28 | riser duct :6 ,SHE-05.THIRD.dgn,Design Model:163330 | 3.28
2.28 | riser duct :18 ,SHE-04.SECOND.dgn,Design Model:163330 | 2.28

# IfcDoor: A-Doors-DoubleFlush (2)
In: ENTRANCE
Type - OperationType: DOUBLE_DOOR_SINGLE_SWING; ConstructionType: USERDEFINED; ParameterTakesPrecedence: no; Sizeable: no
Type - Lining - LiningDepth: 0.103 m; LiningThickness: 0.069 m
Type - Thermal Transmittance - Is External: no; Is Below Grade: no
Type - Fire Resistance - Fire | IsCombustible: no; Fire | Compartmentation: no
Type - Door Parameters - Parametric | File Type: PAZ; Parametric | File Name: DoorDoubleFlush; Dimension | Leaf Width: 1.726 m; Dimension | Height: 2.058 m; Dimension | Frame Depth: 0.103 m; Dimension | Frame Depth Match Wall: yes; Dimension | Architrave Width: 0.069 m; Dimension | Leaf Thickness: 0.04 m
Type - Door - Door | Type: F - Flush; Door | IsEgress: no; Frame | Material: HM
Type - Discipline - Discipline: Architectural
Type - Classification - Uniclass2015: Pr_30_59_23
OverallHeight: 2.127 m; OverallWidth: 1.703 m; Material: A_BSUK_Doors
Pset_DoorCommon - FireExit: no; FireRating: FD30
Identification - ID | Description: riser duct; ID | Keynote: FIRE DOOR KEEP CLOSED
Fire Resistance - Fire | Rating: FD30
Door Parameters - Dimension | Leaf Width: 1.565 m
Door - Door | Finish: white; Door | Under Cut: 0 m; Glazing: no; Louver: no
Construction Phase - Phase: New Construction
Name | Description | ID | Number
0.06 | riser duct :1 ,SHE-01.GROUND.dgn,Design Model:101971 | 0.06
0.07 | riser duct :1 ,SHE-01.GROUND.dgn,Design Model:102276 | 0.07

# IfcDoor: A-Doors-DoubleFlush, 0.01
In: UNDERCROFT (front)
Type - OperationType: DOUBLE_DOOR_SINGLE_SWING; ConstructionType: USERDEFINED; ParameterTakesPrecedence: no; Sizeable: no
Type - Lining - LiningDepth: 0.1524 m; LiningThickness: 0.069 m
Type - Thermal Transmittance - Is External: no; Is Below Grade: no
Type - Fire Resistance - Fire | IsCombustible: no; Fire | Compartmentation: no
Type - Door Parameters - Parametric | File Type: PAZ; Parametric | File Name: DoorDoubleFlush; Dimension | Leaf Width: 1.726 m; Dimension | Height: 2.058 m; Dimension | Frame Depth: 0.1524 m; Dimension | Frame Depth Match Wall: yes; Dimension | Architrave Width: 0.069 m; Dimension | Leaf Thickness: 0.04 m
Type - Door - Door | Type: F - Flush; Door | IsEgress: no; Frame | Material: HM
Type - Discipline - Discipline: Architectural
Type - Classification - Uniclass2015: Pr_30_59_23
Description: entrance - main residential :1,SHE-01.GROUND.dgn,Design Model:137758; OverallHeight: 2.1 m; OverallWidth: 1.934 m; Material: A_BSUK_Doors
Pset_DoorCommon - FireExit: no
Identification - ID | Number: 0.01; ID | Description: entrance - main residential; ID | Keynote: security - Part Q / PAS24 compliance, Emergency Exit Lock
Door Parameters - Dimension | Leaf Width: 1.85 m
Door - Door | Finish: RAL 9017 - traffic black matt textured; Door | Under Cut: 0 m; Glazing: no; Louver: no; Frame | Material: Glass
Construction Phase - Phase: New Construction

# IfcDoor: A-Doors-DoubleFlush (3)
In: hall (vented)
Type - OperationType: DOUBLE_DOOR_SINGLE_SWING; ConstructionType: USERDEFINED; ParameterTakesPrecedence: no; Sizeable: no
Type - Lining - LiningDepth: 0.17 m; LiningThickness: 0.069 m
Type - Thermal Transmittance - Is External: no; Is Below Grade: no
Type - Fire Resistance - Fire | IsCombustible: no; Fire | Compartmentation: no
Type - Door Parameters - Parametric | File Type: PAZ; Parametric | File Name: DoorDoubleFlush; Dimension | Leaf Width: 1.726 m; Dimension | Height: 2.058 m; Dimension | Frame Depth: 0.17 m; Dimension | Frame Depth Match Wall: yes; Dimension | Architrave Width: 0.069 m; Dimension | Leaf Thickness: 0.04 m
Type - Door - Door | Type: F - Flush; Door | IsEgress: no; Frame | Material: HM
Type - Discipline - Discipline: Architectural
Type - Classification - Uniclass2015: Pr_30_59_23
OverallHeight: 2.127 m; OverallWidth: 1.038 m; Material: A_BSUK_Doors
Pset_DoorCommon - FireExit: no; FireRating: FD30
Identification - ID | Description: riser duct; ID | Keynote: FIRE DOOR KEEP CLOSED
Fire Resistance - Fire | Rating: FD30
Door Parameters - Dimension | Leaf Width: 0.9 m; Dimension | Frame Depth Match Wall: no
Door - Door | Finish: white; Door | Under Cut: 0 m; Glazing: no; Louver: no
Construction Phase - Phase: New Construction
Name | Description | ID | Number
1.03 | riser duct :4 ,SHE-03.FIRST.dgn,Design Model:140797 | 1.03
3.03 | riser duct :6 ,SHE-05.THIRD.dgn,Design Model:140797 | 3.03
2.03 | riser duct :18 ,SHE-04.SECOND.dgn,Design Model:140797 | 2.03

# IfcDoor: A-Doors-SingleFlush (9)
Type - OperationType: SINGLE_SWING_LEFT; ConstructionType: USERDEFINED; ParameterTakesPrecedence: no; Sizeable: no
Type - Lining - LiningDepth: 0.08 m; LiningThickness: 0.069 m
Type - Thermal Transmittance - Is External: no; Is Below Grade: no
Type - Fire Resistance - Fire | IsCombustible: no; Fire | Compartmentation: no
Type - Door Parameters - Parametric | File Type: PAZ; Parametric | File Name: DoorSingleFlush; Dimension | Leaf Width: 0.826 m; Dimension | Height: 2.058 m; Dimension | Frame Depth: 0.08 m; Dimension | Frame Depth Match Wall: yes; Dimension | Architrave Width: 0.069 m; Dimension | Leaf Thickness: 0.04 m
Type - Door - Door | Type: F - Flush; Door | IsEgress: no; Frame | Material: HM
Type - Discipline - Discipline: Architectural
Type - Classification - Uniclass2015: Pr_30_59_23
Material: A_BSUK_Doors
Pset_DoorCommon - FireExit: no
Door Parameters - Dimension | Frame Depth Match Wall: no
Door - Door | Finish: white; Door | Under Cut: 0 m; Glazing: no; Louver: no
Construction Phase - Phase: New Construction
Name | In | Description | OverallHeight (m) | OverallWidth (m) | ID | Number | ID | Description | Dimension | Leaf Width (m) | Dimension | Height (m)
0.16 | 0 | WC :1,SHE-01.GROUND.dgn ,Design Model:153928 | 2.127 | 0.888 | 0.16 | WC | 0.75
4.27 | 26 | bedroom :7 ,SHE-06.FOURTH.dgn,Design Model:106404 | 2.169 | 1.038 | 4.27 | bedroom | 0.9 | 2.1 | Pset_DoorCommon - FireRating: FD30; Fire Resistance - Fire | Rating: FD30
4.19 | 25 | bathroom :7 ,SHE-06.FOURTH.dgn,Design Model:108984 | 2.169 | 0.888 | 4.19 | bathroom | 0.75 | 2.1
4.20 | 25 | bedroom :7 ,SHE-06.FOURTH.dgn,Design Model:109242 | 2.169 | 1.038 | 4.20 | bedroom | 0.9 | 2.1 | Pset_DoorCommon - FireRating: FD30; Fire Resistance - Fire | Rating: FD30
4.22 | 25 | bedroom :7 ,SHE-06.FOURTH.dgn,Design Model:109758 | 2.169 | 1.038 | 4.22 | bedroom | 0.9 | 2.1 | Pset_DoorCommon - FireRating: FD30; Fire Resistance - Fire | Rating: FD30
4.24 | 25 | storage :7 ,SHE-06.FOURTH.dgn,Design Model:110274 | 2.169 | 0.888 | 4.24 | storage | 0.75 | 2.1
4.13 | 24 | ensuite :7 ,SHE-06.FOURTH.dgn,Design Model:110532 | 2.169 | 0.888 | 4.13 | ensuite | 0.75 | 2.1
4.16 | 24 | bedroom :7 ,SHE-06.FOURTH.dgn,Design Model:111564 | 2.169 | 1.038 | 4.16 | bedroom | 0.9 | 2.1 | Pset_DoorCommon - FireRating: FD30; Fire Resistance - Fire | Rating: FD30
4.09 | 23 | ensuite :7 ,SHE-06.FOURTH.dgn,Design Model:261310 | 2.142 | 0.834 | 4.09 | ensuite | 0.75 | 2.1

# IfcDoor: A-Doors-SingleFlush (21)
Type - OperationType: SINGLE_SWING_LEFT; ConstructionType: USERDEFINED; ParameterTakesPrecedence: no; Sizeable: no
Type - Lining - LiningDepth: 0.095 m; LiningThickness: 0.069 m
Type - Thermal Transmittance - Is External: no; Is Below Grade: no
Type - Fire Resistance - Fire | IsCombustible: no; Fire | Compartmentation: no
Type - Door Parameters - Parametric | File Type: PAZ; Parametric | File Name: DoorSingleFlush; Dimension | Leaf Width: 0.826 m; Dimension | Height: 2.058 m; Dimension | Frame Depth: 0.095 m; Dimension | Frame Depth Match Wall: yes; Dimension | Architrave Width: 0.069 m; Dimension | Leaf Thickness: 0.04 m
Type - Door - Door | Type: F - Flush; Door | IsEgress: no; Frame | Material: HM
Type - Discipline - Discipline: Architectural
Type - Classification - Uniclass2015: Pr_30_59_23
Material: A_BSUK_Doors
Pset_DoorCommon - FireExit: no
Door Parameters - Dimension | Height: 2.1 m; Dimension | Frame Depth Match Wall: no
Door - Door | Finish: white; Door | Under Cut: 0 m; Glazing: no; Louver: no
Construction Phase - Phase: New Construction
Name | In | Description | OverallHeight (m) | OverallWidth (m) | ID | Number | ID | Description | Dimension | Leaf Width (m)
1.18 | 06 | bathroom :4 ,SHE-03.FIRST.dgn,Design Model:136605 | 2.169 | 0.888 | 1.18 | bathroom | 0.75
1.07 | 02 | bedroom :4 ,SHE-03.FIRST.dgn,Design Model:137379 | 2.169 | 1.038 | 1.07 | bedroom | 0.9
1.14 | 04 | bedroom :4 ,SHE-03.FIRST.dgn,Design Model:138411 | 2.157 | 1.56178 | 1.14 | bedroom | 0.9
1.15 | 05 | bathroom :4 ,SHE-03.FIRST.dgn,Design Model:142280 | 2.169 | 0.888 | 1.15 | bathroom | 0.75
1.21 | 07 | bedroom :4 ,SHE-03.FIRST.dgn,Design Model:222420 | 2.142 | 0.984 | 1.21 | bedroom | 0.9
1.05 | 02 | storage :4 ,SHE-03.FIRST.dgn,Design Model:227303 | 2.142 | 0.834 | 1.05 | storage | 0.75
1.19 | 06 | bedroom :4 ,SHE-03.FIRST.dgn,Design Model:224353 | 2.172 | 1.083 | 1.19 | bedroom | 0.9
3.18 | 20 | bathroom :6 ,SHE-05.THIRD.dgn,Design Model:136605 | 2.169 | 0.888 | 3.18 | bathroom | 0.75
3.07 | 16 | bedroom :6 ,SHE-05.THIRD.dgn,Design Model:137379 | 2.169 | 1.038 | 3.07 | bedroom | 0.9
3.14 | 18 | bedroom :6 ,SHE-05.THIRD.dgn,Design Model:138411 | 2.157 | 1.56178 | 3.14 | bedroom | 0.9
3.15 | 19 | bathroom :6 ,SHE-05.THIRD.dgn,Design Model:142280 | 2.169 | 0.888 | 3.15 | bathroom | 0.75
3.21 | 21 | bedroom :6 ,SHE-05.THIRD.dgn,Design Model:222420 | 2.142 | 0.984 | 3.21 | bedroom | 0.9
3.05 | 16 | storage :6 ,SHE-05.THIRD.dgn,Design Model:227303 | 2.142 | 0.834 | 3.05 | storage | 0.75
3.19 | 20 | bedroom :6 ,SHE-05.THIRD.dgn,Design Model:224353 | 2.172 | 1.083 | 3.19 | bedroom | 0.9
2.18 | 13 | bathroom :18 ,SHE-04.SECOND.dgn,Design Model:136605 | 2.169 | 0.888 | 2.18 | bathroom | 0.75
2.07 | 09 | bedroom :18 ,SHE-04.SECOND.dgn,Design Model:137379 | 2.169 | 1.038 | 2.07 | bedroom | 0.9
2.14 | 11 | bedroom :18 ,SHE-04.SECOND.dgn,Design Model:138411 | 2.157 | 1.56178 | 2.14 | bedroom | 0.9
2.15 | 12 | bathroom :18 ,SHE-04.SECOND.dgn,Design Model:142280 | 2.169 | 0.888 | 2.15 | bathroom | 0.75
2.21 | 14 | bedroom :18 ,SHE-04.SECOND.dgn,Design Model:222420 | 2.142 | 0.984 | 2.21 | bedroom | 0.9
2.05 | 09 | storage :18 ,SHE-04.SECOND.dgn,Design Model:227303 | 2.142 | 0.834 | 2.05 | storage | 0.75
2.19 | 13 | bedroom :18 ,SHE-04.SECOND.dgn,Design Model:224353 | 2.172 | 1.083 | 2.19 | bedroom | 0.9

# IfcDoor: A-Doors-SingleFlush, 0.20
In: ENTRANCE
Type - OperationType: SINGLE_SWING_LEFT; ConstructionType: USERDEFINED; ParameterTakesPrecedence: no; Sizeable: no
Type - Lining - LiningDepth: 0.118 m; LiningThickness: 0.069 m
Type - Thermal Transmittance - Is External: no; Is Below Grade: no
Type - Fire Resistance - Fire | IsCombustible: no; Fire | Compartmentation: no
Type - Door Parameters - Parametric | File Type: PAZ; Parametric | File Name: DoorSingleFlush; Dimension | Leaf Width: 0.826 m; Dimension | Height: 2.058 m; Dimension | Frame Depth: 0.118 m; Dimension | Frame Depth Match Wall: yes; Dimension | Architrave Width: 0.069 m; Dimension | Leaf Thickness: 0.04 m
Type - Door - Door | Type: F - Flush; Door | IsEgress: no; Frame | Material: HM
Type - Discipline - Discipline: Architectural
Type - Classification - Uniclass2015: Pr_30_59_23
Description: bathroom :2 ,SHE-02.MEZZANINE.dgn,Design Model:94311; OverallHeight: 2.1 m; OverallWidth: 0.734 m; Material: A_BSUK_Doors
Pset_DoorCommon - FireExit: no
Identification - ID | Number: 0.20; ID | Description: bathroom
Door Parameters - Dimension | Leaf Width: 0.65 m
Door - Door | Finish: white; Door | Under Cut: 0 m; Glazing: no; Louver: no
Construction Phase - Phase: New Construction

# IfcDoor: A-Doors-SingleFlush (2)
In: corridor (protected)
Type - OperationType: SINGLE_SWING_LEFT; ConstructionType: USERDEFINED; ParameterTakesPrecedence: no; Sizeable: no
Type - Lining - LiningDepth: 0.2 m; LiningThickness: 0.069 m
Type - Thermal Transmittance - Is External: no; Is Below Grade: no
Type - Fire Resistance - Fire | IsCombustible: no; Fire | Compartmentation: no
Type - Door Parameters - Parametric | File Type: PAZ; Parametric | File Name: DoorSingleFlush; Dimension | Leaf Width: 0.826 m; Dimension | Height: 2.058 m; Dimension | Frame Depth: 0.2 m; Dimension | Frame Depth Match Wall: yes; Dimension | Architrave Width: 0.069 m; Dimension | Leaf Thickness: 0.04 m
Type - Door - Door | Type: F - Flush; Door | IsEgress: no; Frame | Material: HM
Type - Discipline - Discipline: Architectural
Type - Classification - Uniclass2015: Pr_30_59_23
OverallHeight: 2.169 m; OverallWidth: 1.138 m; Material: A_BSUK_Doors
Pset_DoorCommon - FireExit: no; FireRating: FD30S
Identification - ID | Description: flat entrance
Fire Resistance - Fire | Rating: FD30S
Door Parameters - Dimension | Leaf Width: 1 m; Dimension | Height: 2.1 m; Dimension | Frame Depth Match Wall: no
Door - Door | Finish: french oak veneer; Door | Under Cut: 0 m; Glazing: no; Louver: no
Construction Phase - Phase: New Construction
Name | Description | ID | Number
4.04 | flat entrance :7 ,SHE-06.FOURTH.dgn,Design Model:104542 | 4.04
4.12 | flat entrance :7 ,SHE-06.FOURTH.dgn,Design Model:104800 | 4.12

# IfcDoor: A-Doors-SingleFlush (12)
Type - OperationType: SINGLE_SWING_LEFT; ConstructionType: USERDEFINED; ParameterTakesPrecedence: no; Sizeable: no
Type - Lining - LiningDepth: 0.225 m; LiningThickness: 0.069 m
Type - Thermal Transmittance - Is External: no; Is Below Grade: no
Type - Fire Resistance - Fire | IsCombustible: no; Fire | Compartmentation: no
Type - Door Parameters - Parametric | File Type: PAZ; Parametric | File Name: DoorSingleFlush; Dimension | Leaf Width: 0.826 m; Dimension | Height: 2.058 m; Dimension | Frame Depth: 0.225 m; Dimension | Frame Depth Match Wall: yes; Dimension | Architrave Width: 0.069 m; Dimension | Leaf Thickness: 0.04 m
Type - Door - Door | Type: F - Flush; Door | IsEgress: no; Frame | Material: HM
Type - Discipline - Discipline: Architectural
Type - Classification - Uniclass2015: Pr_30_59_23
Material: A_BSUK_Doors
Pset_DoorCommon - FireExit: no; FireRating: FD30S
Identification - ID | Description: flat entrance
Fire Resistance - Fire | Rating: FD30S
Door Parameters - Dimension | Leaf Width: 1 m; Dimension | Height: 2.1 m
Door - Door | Finish: french oak veneer; Door | Under Cut: 0 m; Glazing: no; Louver: no
Construction Phase - Phase: New Construction
Name | In | Description | OverallHeight (m) | OverallWidth (m) | ID | Number | Dimension | Frame Depth Match Wall
1.20 | corridor | flat entrance :4 ,SHE-03.FIRST.dgn,Design Model:132588 | 2.169 | 1.138 | 1.20
1.17 | 06 | flat entrance :4 ,SHE-03.FIRST.dgn,Design Model:132846 | 2.169 | 1.138 | 1.17 | no
1.12 | 04 | flat entrance :4 ,SHE-03.FIRST.dgn,Design Model:141364 | 2.169 | 1.138 | 1.12 | no
1.23 | corridor | flat entrance :4 ,SHE-03.FIRST.dgn,Design Model:169731 | 2.142 | 1.084 | 1.23 | no
3.20 | 21 | flat entrance :6 ,SHE-05.THIRD.dgn,Design Model:132588 | 2.169 | 1.138 | 3.20
3.17 | k/d/l | flat entrance :6 ,SHE-05.THIRD.dgn,Design Model:132846 | 2.169 | 1.138 | 3.17 | no
3.12 | 18 | flat entrance :6 ,SHE-05.THIRD.dgn,Design Model:141364 | 2.169 | 1.138 | 3.12 | no
3.23 | corridor | flat entrance :6 ,SHE-05.THIRD.dgn,Design Model:169731 | 2.142 | 1.084 | 3.23 | no
2.20 | corridor | flat entrance :18 ,SHE-04.SECOND.dgn,Design Model:132588 | 2.169 | 1.138 | 2.20
2.17 | 13 | flat entrance :18 ,SHE-04.SECOND.dgn,Design Model:132846 | 2.169 | 1.138 | 2.17 | no
2.12 | k/d/l | flat entrance :18 ,SHE-04.SECOND.dgn,Design Model:141364 | 2.169 | 1.138 | 2.12 | no
2.23 | corridor | flat entrance :18 ,SHE-04.SECOND.dgn,Design Model:169731 | 2.142 | 1.084 | 2.23 | no

# IfcDoor: A-Doors-SingleFlush, 0.04
In: ENTRANCE
Type - OperationType: SINGLE_SWING_LEFT; ConstructionType: USERDEFINED; ParameterTakesPrecedence: no; Sizeable: no
Type - Lining - LiningDepth: 0.231 m; LiningThickness: 0.069 m
Type - Thermal Transmittance - Is External: no; Is Below Grade: no
Type - Fire Resistance - Fire | IsCombustible: no; Fire | Compartmentation: no
Type - Door Parameters - Parametric | File Type: PAZ; Parametric | File Name: DoorSingleFlush; Dimension | Leaf Width: 0.826 m; Dimension | Height: 2.058 m; Dimension | Frame Depth: 0.231 m; Dimension | Frame Depth Match Wall: yes; Dimension | Architrave Width: 0.069 m; Dimension | Leaf Thickness: 0.04 m
Type - Door - Door | Type: F - Flush; Door | IsEgress: no; Frame | Material: HM
Type - Discipline - Discipline: Architectural
Type - Classification - Uniclass2015: Pr_30_59_23
Description: entrance - carpark :1 ,SHE-01.GROUND.dgn,Design Model:101400; OverallHeight: 2.142 m; OverallWidth: 1.084 m; Material: A_BSUK_Doors
Pset_DoorCommon - FireExit: no
Identification - ID | Number: 0.04; ID | Description: entrance - carpark; ID | Keynote: security - Part Q / PAS24 compliance
Door Parameters - Dimension | Leaf Width: 1 m; Dimension | Height: 2.1 m
Door - Door | Finish: RAL 9017 - traffic black matt textured; Door | Under Cut: 0 m; Glazing: no; Louver: no
Construction Phase - Phase: New Construction

# IfcDoor: A-Doors-SingleFlush, 0.08
In: 01
Type - OperationType: SINGLE_SWING_LEFT; ConstructionType: USERDEFINED; ParameterTakesPrecedence: no; Sizeable: no
Type - Lining - LiningDepth: 0.36 m; LiningThickness: 0.069 m
Type - Thermal Transmittance - Is External: no; Is Below Grade: no
Type - Fire Resistance - Fire | IsCombustible: no; Fire | Compartmentation: no
Type - Door Parameters - Parametric | File Type: PAZ; Parametric | File Name: DoorSingleFlush; Dimension | Leaf Width: 0.826 m; Dimension | Height: 2.058 m; Dimension | Frame Depth: 0.36 m; Dimension | Frame Depth Match Wall: yes; Dimension | Architrave Width: 0.069 m; Dimension | Leaf Thickness: 0.04 m
Type - Door - Door | Type: F - Flush; Door | IsEgress: no; Frame | Material: HM
Type - Discipline - Discipline: Architectural
Type - Classification - Uniclass2015: Pr_30_59_23
Description: entrance - mews house :1 ,SHE-01.GROUND.dgn,Design Model:98838; OverallHeight: 2.142 m; OverallWidth: 0.909 m; Material: A_BSUK_Doors
Pset_DoorCommon - FireExit: no
Identification - ID | Number: 0.08; ID | Description: entrance - mews house; ID | Keynote: security - Part Q / PAS24 compliance
Door Parameters - Dimension | Leaf Width: 0.825 m; Dimension | Height: 2.1 m
Door - Door | Finish: RAL 9017 - traffic black matt textured; Door | Under Cut: 0 m; Glazing: no; Louver: no
Construction Phase - Phase: New Construction

# IfcDoor: A-Doors-SingleFlush (18)
Type - OperationType: SINGLE_SWING_RIGHT; ConstructionType: USERDEFINED; ParameterTakesPrecedence: no; Sizeable: no
Type - Lining - LiningDepth: 0.08 m; LiningThickness: 0.069 m
Type - Thermal Transmittance - Is External: no; Is Below Grade: no
Type - Fire Resistance - Fire | IsCombustible: no; Fire | Compartmentation: no
Type - Door Parameters - Parametric | File Type: PAZ; Parametric | File Name: DoorSingleFlush; Dimension | Leaf Width: 0.826 m; Dimension | Height: 2.058 m; Dimension | Frame Depth: 0.08 m; Dimension | Frame Depth Match Wall: yes; Dimension | Architrave Width: 0.069 m; Dimension | Leaf Thickness: 0.04 m
Type - Door - Door | Type: F - Flush; Door | IsEgress: no; Frame | Material: HM
Type - Discipline - Discipline: Architectural
Type - Classification - Uniclass2015: Pr_30_59_23
Material: A_BSUK_Doors
Pset_DoorCommon - FireExit: no
Door - Door | Finish: white; Door | Under Cut: 0 m; Glazing: no; Louver: no
Construction Phase - Phase: New Construction
Name | In | Description | OverallHeight (m) | OverallWidth (m) | ID | Number | ID | Description | Dimension | Leaf Width (m) | Dimension | Frame Depth Match Wall | Dimension | Height (m)
0.11 | 01 | bathroom :1 ,SHE-01.GROUND.dgn,Design Model:103097 | 2.127 | 1.038 | 0.11 | bathroom | 0.9 | no
0.12 | 01 | bedroom :1 ,SHE-01.GROUND.dgn,Design Model:132007 | 2.127 | 1.038 | 0.12 | bedroom | 0.9 | no
0.15 | 0 | WC (disabl.) :1 ,SHE-01.GROUND.dgn,Design Model:153321 | 2.127 | 1.138 | 0.15 | WC (disabl.) | 1
0.22 | 01 | bedroom :2 ,SHE-02.MEZZANINE.dgn,Design Model:143206 | 2.1 | 0.984 | 0.22 | bedroom | 0.9
4.11 | 24 | storage :7 ,SHE-06.FOURTH.dgn,Design Model:96561 | 2.169 | 0.888 | 4.11 | storage | 0.75 | no | 2.1
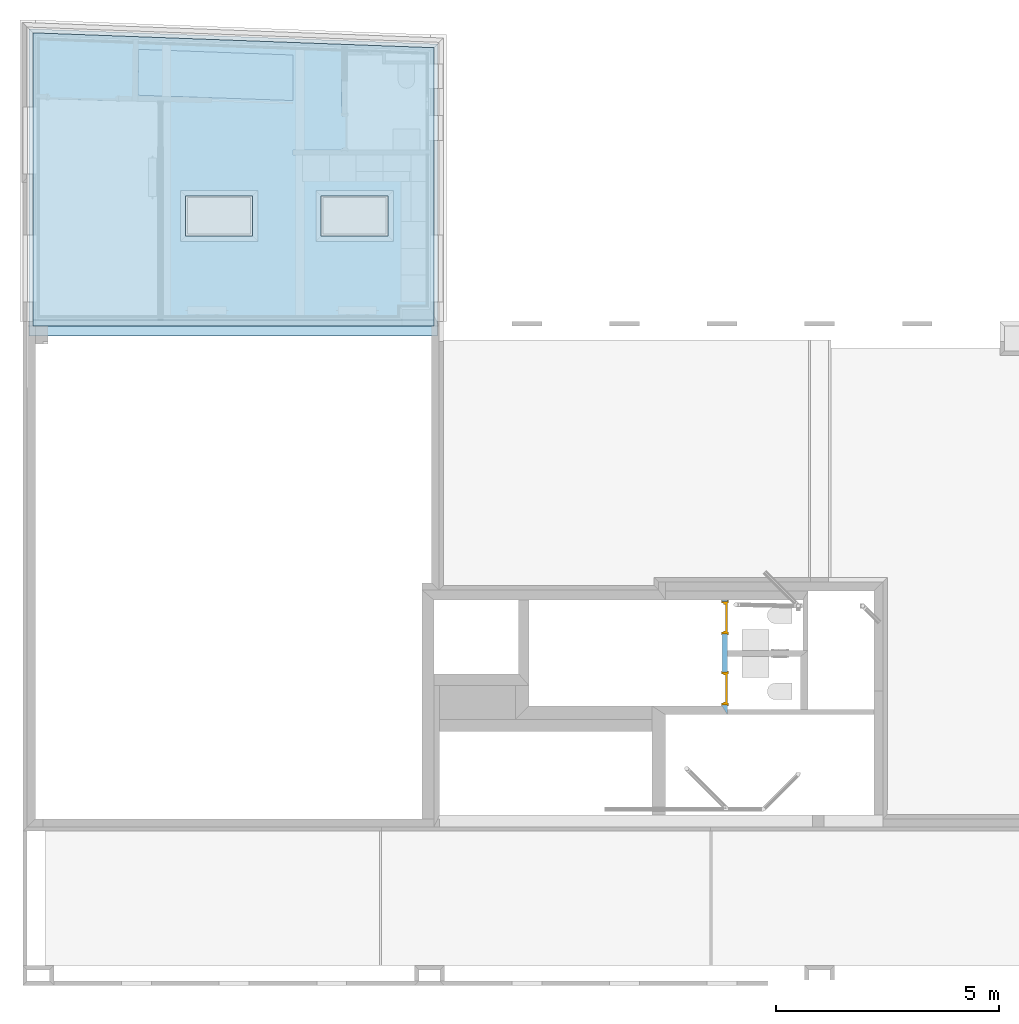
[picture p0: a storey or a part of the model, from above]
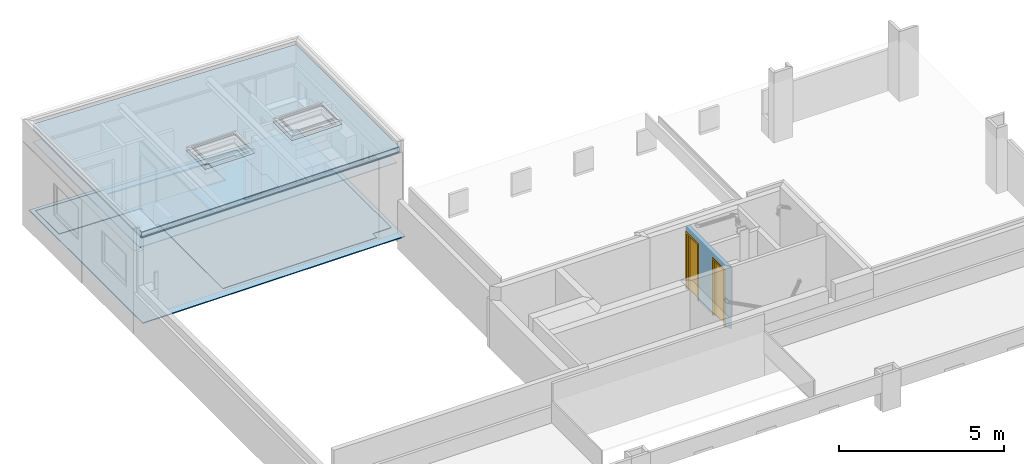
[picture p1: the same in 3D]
Properties of the parts of a building model (IFC2X3), part 7 of 16

# IfcFlowSegment: M-BmpStraightpipe-DefaultPipe (87)
Name | In | Description | Pipe Length | Slope Value | Slope Method | Surface Area (m2) | Center Of Gravity | System ID | Phase | Group
M-BmpStraightpipe-DefaultPipe | 1 | 11,SHE-15.MEHP.dgn,Design Model:228916 | 425.554 | 1 : 80 | Rise / Run | 0.133692 | 212.78; 0.00; 0.00; | SVP7 | New Construction | SVP
M-BmpStraightpipe-DefaultPipe | GF | 11,SHE-15.MEHP.dgn,Design Model:230579 | 1293.32 | 1 : 80 | Rise / Run | 0.406307 | 646.66; 0.00; 0.00; | SVP3-4-5-6 | New Construction | SVP3-4-5
M-BmpStraightpipe-DefaultPipe | GF | 11,SHE-15.MEHP.dgn,Design Model:230730 | 7759.69 | 0.0 | Degree | 2.43778 | 3879.85; 0.00; 0.00; | SVP3-4-5-6-7 | New Construction | SVP3-4-5-6
M-BmpStraightpipe-DefaultPipe | GF | 11,SHE-15.MEHP.dgn,Design Model:232045 | 7925.4 | 0.0 | Degree | 2.48984 | 3962.70; 0.00; 0.00; | SVP1-2 | New Construction | SVP1
M-BmpStraightpipe-DefaultPipe | 0 | 11,SHE-15.MEHP.dgn,Design Model:232102 | 4139.69 | 1 : 80 | Rise / Run | 1.30052 | 2069.84; 0.00; 0.00; | SVP1 | New Construction | SVP
M-BmpStraightpipe-DefaultPipe | 0 | 11,SHE-15.MEHP.dgn,Design Model:232199 | 362.22 | 1 : 80 | Rise / Run | 0.113795 | 181.11; 0.00; 0.00; | SVP1 | New Construction | SVP
M-BmpStraightpipe-DefaultPipe | 0 | 11,SHE-15.MEHP.dgn,Design Model:232296 | 5796.24 | 1 : 80 | Rise / Run | 1.82094 | 2898.12; 0.00; 0.00; | SVP1-2 | New Construction | SVP1
M-BmpStraightpipe-DefaultPipe | 0 | 11,SHE-15.MEHP.dgn,Design Model:232322 | 1522.04 | 1 : 80 | Rise / Run | 0.478162 | 761.02; 0.00; 0.00; | SVP2 | New Construction | SVP
M-BmpStraightpipe-DefaultPipe | 0 | 11,SHE-15.MEHP.dgn,Design Model:232419 | 403.638 | 1 : 80 | Rise / Run | 0.126807 | 201.82; 0.00; 0.00; | SVP2 | New Construction | SVP
M-BmpStraightpipe-DefaultPipe | GF | 11,SHE-15.MEHP.dgn,Design Model:167322 | 9027.6 | 0.0 | Degree | 2.83611 | 4513.80; 0.00; 0.00; | RW3 | New Construction | RW
M-BmpStraightpipe-DefaultPipe | GF | 11,SHE-15.MEHP.dgn,Design Model:167348 | 9229.31 | 0.0 | Degree | 2.89947 | 4614.66; 0.00; 0.00; | RW4 | New Construction | RW
M-BmpStraightpipe-DefaultPipe | GF | 11,SHE-15.MEHP.dgn,Design Model:167374 | 15176.6 | 0.0 | Degree | 4.76787 | 7588.31; 0.00; 0.00; | RW5 | New Construction | RW
M-BmpStraightpipe-DefaultPipe | GF | 11,SHE-15.MEHP.dgn,Design Model:245027 | 6071.43 | 0.0 | Degree | 1.9074 | 3035.71; 0.00; 0.00; | RW3 | New Construction | RW
M-BmpStraightpipe-DefaultPipe | GF | 11,SHE-15.MEHP.dgn,Design Model:245053 | 311.95 | 0.0 | Degree | 0.098002 | 155.98; 0.00; 0.00; | RW3 | New Construction | RW
M-BmpStraightpipe-DefaultPipe | 1 | 11,SHE-15.MEHP.dgn,Design Model:246186 | 5986.89 | 0.0 | Degree | 1.88084 | 2993.45; 0.00; 0.00; | RW4 | New Construction | RW
M-BmpStraightpipe-DefaultPipe | GF | 11,SHE-15.MEHP.dgn,Design Model:246262 | 234.392 | 0.0 | Degree | 0.073636 | 117.20; 0.00; 0.00; | RW4 | New Construction | RW
M-BmpStraightpipe-DefaultPipe | GF | 11,SHE-15.MEHP.dgn,Design Model:248830 | 50 | 1 : 80 | Rise / Run | 0.015708 | 25.00; 0.00; 0.00; | RW4 | New Construction | RW
M-BmpStraightpipe-DefaultPipe | 0 | 11,SHE-15.MEHP.dgn,Design Model:268855 | 15419.3 | 0.0 | Degree | 4.84412 | 7709.66; 0.00; 0.00; | RW6 | New Construction | RW
M-BmpStraightpipe-DefaultPipe | GF | 11,SHE-15.MEHP.dgn,Design Model:287569 | 1019.92 | 0.0 | Degree | 0.320417 | 509.96; 0.00; 0.00; | DRM | New Construction | DRM
M-BmpStraightpipe-DefaultPipe | 1 | 11,SHE-15.MEHP.dgn,Design Model:289773 | 1519.3 | 0.0 | Degree | 0.477302 | 759.65; 0.00; 0.00; | DRM | New Construction | DRM
M-BmpStraightpipe-DefaultPipe | GF | 11,SHE-15.MEHP.dgn,Design Model:290654 | 4452.11 | 1 : 80 | Rise / Run | 1.39867 | 2226.05; 0.00; 0.00; | DRM | New Construction | DRM
M-BmpStraightpipe-DefaultPipe | GF | 11,SHE-15.MEHP.dgn,Design Model:291245 | 466.449 | 1 : 80 | Rise / Run | 0.146539 | 233.22; 0.00; 0.00; | DRM | New Construction | DRM
M-BmpStraightpipe-DefaultPipe | GF | 11,SHE-15.MEHP.dgn,Design Model:292488 | 2439.99 | 0.0 | Degree | 0.766545 | 1219.99; 0.00; 0.00; | DRM | New Construction | DRM
M-BmpStraightpipe-DefaultPipe | GF | 11,SHE-15.MEHP.dgn,Design Model:293351 | 3379.99 | 0.0 | Degree | 1.06185 | 1689.99; 0.00; 0.00; | DRM | New Construction | DRM
M-BmpStraightpipe-DefaultPipe | GF | 11,SHE-15.MEHP.dgn,Design Model:293402 | 3379.99 | 0.0 | Degree | 1.06185 | 1689.99; 0.00; 0.00; | DRM | New Construction | DRM
M-BmpStraightpipe-DefaultPipe | landing | 11,SHE-15.MEHP.dgn,Design Model:293497 | 893.583 | 0.0 | Degree | 0.280727 | 446.79; 0.00; 0.00; | DRM | New Construction | DRM
M-BmpStraightpipe-DefaultPipe | landing | 11,SHE-15.MEHP.dgn,Design Model:293574 | 1647.66 | 0.0 | Degree | 0.517627 | 823.83; 0.00; 0.00; | DRM | New Construction | DRM
M-BmpStraightpipe-DefaultPipe | GF | 11,SHE-15.MEHP.dgn,Design Model:295986 | 13297.2 | 0.0 | Degree | 4.17744 | 6648.61; 0.00; 0.00; | RW5 | New Construction | RW
M-BmpStraightpipe-DefaultPipe | GF | 11,SHE-15.MEHP.dgn,Design Model:299780 | 14511.9 | 0.0 | Degree | 4.55904 | 7255.93; 0.00; 0.00; | RW5 | New Construction | RW
M-BmpStraightpipe-DefaultPipe | GF | 11,SHE-15.MEHP.dgn,Design Model:299932 | 4475.88 | 0.0 | Degree | 1.40614 | 2237.94; 0.00; 0.00; | RW5 | New Construction | RW
M-BmpStraightpipe-DefaultPipe | GF | 11,SHE-15.MEHP.dgn,Design Model:300211 | 8636.03 | 0.0 | Degree | 2.71309 | 4318.01; 0.00; 0.00; | RW5 | New Construction | RW
M-BmpStraightpipe-DefaultPipe | GF | 11,SHE-15.MEHP.dgn,Design Model:301880 | 117.502 | 0.0 | Degree | 0.036914 | 58.75; 0.00; 0.00; | RW3 | New Construction | RW
M-BmpStraightpipe-DefaultPipe | GF | 11,SHE-15.MEHP.dgn,Design Model:301906 | 12987.9 | 0.0 | Degree | 4.08026 | 6493.94; 0.00; 0.00; | RW3 | New Construction | RW
M-BmpStraightpipe-DefaultPipe | GF | 11,SHE-15.MEHP.dgn,Design Model:301982 | 14511.9 | 0.0 | Degree | 4.55904 | 7255.93; 0.00; 0.00; | RW3 | New Construction | RW
M-BmpStraightpipe-DefaultPipe | GF | 11,SHE-15.MEHP.dgn,Design Model:302058 | 13297.2 | 0.0 | Degree | 4.17744 | 6648.61; 0.00; 0.00; | RW3 | New Construction | RW
M-BmpStraightpipe-DefaultPipe | GF | 11,SHE-15.MEHP.dgn,Design Model:303276 | 5974.07 | 0.0 | Degree | 1.87681 | 2987.04; 0.00; 0.00; | RW2 | New Construction | RW
M-BmpStraightpipe-DefaultPipe | GF | 11,SHE-15.MEHP.dgn,Design Model:311016 | 18166 | 0.0 | Degree | 5.70702 | 9083.01; 0.00; 0.00; | RW2 | New Construction | RW
M-BmpStraightpipe-DefaultPipe | GF | 11,SHE-15.MEHP.dgn,Design Model:311767 | 172.177 | 1 : 80 | Rise / Run | 0.054091 | 86.09; 0.00; 0.00; | RW2 | New Construction | RW

# IfcFlowSegment: M-RoundDuct (25)
Type - PredefinedType: RIGIDSEGMENT
Type - Round Duct Parameters - Length: 2000; Minimum Length: 100; Connection 1 | Length (L1): 0; Connection 2 | Length (L2): 0; Connection | End Type: m-5;m-5; View Display: iso
Type - Parameters - Insulation | Thickness (mm): 0; Lining | Thickness (mm): 0; Correction Factor: 1.0; Wall Thickness: 0
Type - End Spec1_2 (1 Connection: Round) - Diameter 1 (D1 Ø): 500
Type - Classification - Uniclass2015: Pr_65_65_25_14
Material: M_BSUK_Ventilation
Round Duct Parameters - Connection | End Type: m-5;m-5;; Base Offset: 0.000
Parameters - Insulation | Surface Area: 0 m2; Lining | Surface Area: 0 m2; Status: BSUK; Air Flow: M
Name | In | Description | Length | VulcanParameters | Surface Area (m2) | Center Of Gravity | System ID | Diameter 1 (D1 Ø) | Phase | Group
M-RoundDuct | GF | 11 ,SHE-15.MEHP.dgn,Design Model:256730 | 3209.54 | FN=302-m;W=100;L=3209.544714;CN1=Male 5;CN2=Male 5;END | 1.00831 | 1604.77; 0.00; 0.00; | EXT. Flat 23 | 100 | New Construction | EXT. Flat
M-RoundDuct | GF | 11 ,SHE-15.MEHP.dgn,Design Model:256892 | 3108.93 | FN=302-m;W=100;L=3108.93321;CN1=Male 5;CN2=Male 5;END | 0.9767 | 1554.47; 0.00; 0.00; | EXT. Flat 26 | 100 | New Construction | EXT. Flat
M-RoundDuct | GF | 11 ,SHE-15.MEHP.dgn,Design Model:257407 | 100 | FN=302-m;W=100;L=100;CN1=Male 5;CN2=Male 5;END | 0.031416 | 50.00; 0.00; 0.00; | EXT. Flat 23 | 100 | New Construction | EXT. Flat
M-RoundDuct | GF | 11 ,SHE-15.MEHP.dgn,Design Model:257551 | 662.619 | FN=302-m;W=100;L=662.619324;CN1=Male 5;CN2=Male 5;END | 0.208168 | 331.31; 0.00; 0.00; | EXT. Flat 23 | 100 | New Construction | EXT. Flat
M-RoundDuct | GF | 11 ,SHE-15.MEHP.dgn,Design Model:257658 | 7980.06 | FN=302-m;W=100;L=7980.060544;CN1=Male 5;CN2=Male 5;END | 2.50701 | 3990.03; 0.00; 0.00; | EXT. Flat 23 | 100 | New Construction | EXT. Flat
M-RoundDuct | GF | 11 ,SHE-15.MEHP.dgn,Design Model:257853 | 282.911 | FN=302-m;W=100;L=282.910663;CN1=Male 5;CN2=Male 5;END | 0.088879 | 141.46; 0.00; 0.00; | EXT. Flat 23 | 100 | New Construction | EXT. Flat
M-RoundDuct | GF | 11 ,SHE-15.MEHP.dgn,Design Model:259062 | 2100.06 | FN=302-m;W=100;L=2100.060544;CN1=Male 5;CN2=Male 5;END | 0.659753 | 1050.03; 0.00; 0.00; | EXT. Flat 24 | 100 | New Construction | EXT. Flat
M-RoundDuct | GF | 11 ,SHE-15.MEHP.dgn,Design Model:259206 | 982.619 | FN=302-m;W=100;L=982.619324;CN1=Male 5;CN2=Male 5;END | 0.308699 | 491.31; 0.00; 0.00; | EXT. Flat 24 | 100 | New Construction | EXT. Flat
M-RoundDuct | GF | 11 ,SHE-15.MEHP.dgn,Design Model:259350 | 320.63 | FN=302-m;W=100;L=320.629531;CN1=Male 5;CN2=Male 5;END | 0.100729 | 160.31; 0.00; 0.00; | EXT. Flat 24 | 100 | New Construction | EXT. Flat
M-RoundDuct | GF | 11 ,SHE-15.MEHP.dgn,Design Model:260434 | 922.649 | FN=302-m;W=100;L=922.64892;CN1=Male 5;CN2=Male 5;END | 0.289859 | 461.32; 0.00; 0.00; | EXT. Flat 24 | 100 | New Construction | EXT. Flat
M-RoundDuct | GF | 11 ,SHE-15.MEHP.dgn,Design Model:260536 | 922.649 | FN=302-m;W=100;L=922.64892;CN1=Male 5;CN2=Male 5;END | 0.289859 | 461.32; 0.00; 0.00; | EXT. Flat 25 | 100 | New Construction | EXT. Flat
M-RoundDuct | GF | 11 ,SHE-15.MEHP.dgn,Design Model:260758 | 1172.6 | FN=302-m;W=100;L=1172.595446;CN1=Male 5;CN2=Male 5;END | 0.368382 | 586.30; 0.00; 0.00; | EXT. Flat 25 | 100 | New Construction | EXT. Flat
M-RoundDuct | GF | 11 ,SHE-15.MEHP.dgn,Design Model:260902 | 2120.1 | FN=302-m;W=100;L=2120.095613;CN1=Male 5;CN2=Male 5;END | 0.666048 | 1060.05; 0.00; 0.00; | EXT. Flat 25 | 100 | New Construction | EXT. Flat
M-RoundDuct | GF | 11 ,SHE-15.MEHP.dgn,Design Model:261701 | 2620.1 | FN=302-m;W=100;L=2620.095613;CN1=Male 5;CN2=Male 5;END | 0.823127 | 1310.05; 0.00; 0.00; | EXT. Flat 26 | 100 | New Construction | EXT. Flat
M-RoundDuct | GF | 11 ,SHE-15.MEHP.dgn,Design Model:262205 | 2682.64 | FN=302-m;W=100;L=2682.641613;CN1=Male 5;CN2=Male 5;END | 0.842777 | 1341.32; 0.00; 0.00; | EXT. Flat 26 | 100 | New Construction | EXT. Flat
M-RoundDuct | GF | 11 ,SHE-15.MEHP.dgn,Design Model:262349 | 1188.14 | FN=302-m;W=100;L=1188.137127;CN1=Male 5;CN2=Male 5;END | 0.373264 | 594.07; 0.00; 0.00; | EXT. Flat 26 | 100 | New Construction | EXT. Flat
M-RoundDuct | GF | 11 ,SHE-15.MEHP.dgn,Design Model:262853 | 2106.22 | FN=302-m;W=100;L=2106.217613;CN1=Male 5;CN2=Male 5;END | 0.661688 | 1053.11; 0.00; 0.00; | EXT. Flat 23 | 100 | New Construction | EXT. Flat
M-RoundDuct | GF | 11 ,SHE-15.MEHP.dgn,Design Model:262955 | 2106.22 | FN=302-m;W=100;L=2106.217613;CN1=Male 5;CN2=Male 5;END | 0.661688 | 1053.11; 0.00; 0.00; | EXT. Flat 24 | 100 | New Construction | EXT. Flat
M-RoundDuct | GF | 11 ,SHE-15.MEHP.dgn,Design Model:263057 | 1075 | FN=302-m;W=100;L=1075;CN1=Male 5;CN2=Male 5;END | 0.337721 | 537.50; 0.00; 0.00; | EXT. Flat 25 | 100 | New Construction | EXT. Flat
M-RoundDuct | flat roof | 11 ,SHE-15.MEHP.dgn,Design Model:263392 | 4044.55 | FN=302-m;W=1200;L=4044.548191;CN1=Male 5;CN2=Male 5;END | 15.2476 | 2022.27; 0.00; 0.00; | EXT. AOV | 1200 |  | EXT. AOV
M-RoundDuct | landing | 11 ,SHE-15.MEHP.dgn,Design Model:293776 | 100 | FN=302-m;W=100;L=100;CN1=Male 5;CN2=Male 5;END | 0.031416 | 50.00; 0.00; 0.00; | DRM | 100 | New Construction | DRM
M-RoundDuct | landing | 11 ,SHE-15.MEHP.dgn,Design Model:293938 | 100 | FN=302-m;W=100;L=100;CN1=Male 5;CN2=Male 5;END | 0.031416 | 50.00; 0.00; 0.00; | DRM | 100 | New Construction | DRM
M-RoundDuct | landing | 11 ,SHE-15.MEHP.dgn,Design Model:293980 | 100 | FN=302-m;W=100;L=100;CN1=Male 5;CN2=Male 5;END | 0.031416 | 50.00; 0.00; 0.00; | DRM | 100 | New Construction | DRM
M-RoundDuct | landing | 11 ,SHE-15.MEHP.dgn,Design Model:294022 | 100 | FN=302-m;W=100;L=100;CN1=Male 5;CN2=Male 5;END | 0.031416 | 50.00; 0.00; 0.00; | DRM | 100 | New Construction | DRM
M-RoundDuct | GF | 11 ,SHE-15.MEHP.dgn,Design Model:294064 | 100 | FN=302-m;W=100;L=100;CN1=Male 5;CN2=Male 5;END | 0.031416 | 50.00; 0.00; 0.00; | DRM | 100 | New Construction | DRM

# IfcFlowTerminal: M-BmvRadiator-Column (34)
Type - Radiator Parameters - Box | Height: 625; Box | Width: 150; Box | Length: 500; Number Of Sections: 10; Flow | Connection Side: 1-Left; Flow | Outside Diameter: 25; Flow Top Offset: 525; Flow | Length: 50; Return | Connection Side: 2-Right; Return | Outer Diameter: 25; Return | Top Offset: 100; Return | Length: 50; Connection 1 | Length (L1): 0; Connection | End Type: -; View Display: Iso
Type - Parameters - Insulation | Thickness (mm): 0; Lining | Thickness (mm): 0; Correction Factor: 1.0; Wall Thickness: 0
Type - End Spec1_2 (1 Connection: Round) - Diameter 1 (D1 Ø): 100
Type - Emitters Analytical Parameters - Heat Emission (W): 0; Pressure Drop Type: 1-k value; Emitter Pressure Drop: 0; Flow Valve Type: 1-No Valve; Flow Valve K Value (W/m°C): 0; Return Valve Type: 1-No Valve; Return Valve K Value (W/m°C): 0
Type - Classification - Uniclass2015: Pr_70_60_36_72
Material: M_BSUK_Ventilation
Radiator Parameters - Box | Height: 1200; Box | Width: 25; Number Of Sections: 5; Flow | Outside Diameter: 20; Flow Top Offset: 107.5; Return | Outer Diameter: 20; Return | Top Offset: 101.6; Connection | End Type: -;
Parameters - Type: Towel warmer; Insulation | Surface Area: 0 m2; Lining | Surface Area: 0 m2; Status: BSUK; Air Flow: M
Name | In | Description | Surface Area (m2) | Center Of Gravity
M-BmvRadiator-Column | bath | 1 ,SHE-01.GROUND.dgn,Design Model:262253 | 0.801283 | 150.00; 0.00; 3.89; | Radiator Parameters - Box | Length: 300
M-BmvRadiator-Column | 01 | 2 ,SHE-02.MEZZANINE.dgn,Design Model:194896 | 0.801283 | 150.00; 0.00; 3.89; | Radiator Parameters - Box | Length: 300
M-BmvRadiator-Column | WC | 2 ,SHE-02.MEZZANINE.dgn,Design Model:195239 | 0.801283 | 150.00; 0.00; 3.89; | Radiator Parameters - Box | Length: 300
M-BmvRadiator-Column | WC | 2 ,SHE-02.MEZZANINE.dgn,Design Model:195352 | 0.801283 | 150.00; 0.00; 3.89; | Radiator Parameters - Box | Length: 300
M-BmvRadiator-Column | bath | 4 ,SHE-03.FIRST.dgn,Design Model:133362 | 1.04628 | 200.00; 0.00; 2.98; | Radiator Parameters - Box | Length: 400
M-BmvRadiator-Column | bath | 4 ,SHE-03.FIRST.dgn,Design Model:143194 | 1.29128 | 250.00; 0.00; 2.41;
M-BmvRadiator-Column | bath | 4 ,SHE-03.FIRST.dgn,Design Model:145994 | 1.29128 | 250.00; 0.00; 2.41;
M-BmvRadiator-Column | bath | 4 ,SHE-03.FIRST.dgn,Design Model:142051 | 1.29128 | 250.00; 0.00; 2.41;
M-BmvRadiator-Column | 07 | 4 ,SHE-03.FIRST.dgn,Design Model:133475 | 0.801283 | 150.00; 0.00; 3.89; | Radiator Parameters - Box | Length: 300
M-BmvRadiator-Column | ensuite | 4 ,SHE-03.FIRST.dgn,Design Model:229302 | 1.29128 | 250.00; 0.00; 2.41;
M-BmvRadiator-Column | 05 | 4 ,SHE-03.FIRST.dgn,Design Model:300364 | 1.29128 | 250.00; 0.00; 2.41;
M-BmvRadiator-Column | bath | 4 ,SHE-03.FIRST.dgn,Design Model:352516 | 1.29128 | 250.00; 0.00; 2.41;
M-BmvRadiator-Column | bath | 6 ,SHE-05.THIRD.dgn,Design Model:133362 | 1.04628 | 200.00; 0.00; 2.98; | Radiator Parameters - Box | Length: 400
M-BmvRadiator-Column | bath | 6 ,SHE-05.THIRD.dgn,Design Model:143194 | 1.29128 | 250.00; 0.00; 2.41;
M-BmvRadiator-Column | bath | 6 ,SHE-05.THIRD.dgn,Design Model:145994 | 1.29128 | 250.00; 0.00; 2.41;
M-BmvRadiator-Column | bath | 6 ,SHE-05.THIRD.dgn,Design Model:142051 | 1.29128 | 250.00; 0.00; 2.41;
M-BmvRadiator-Column | 21 | 6 ,SHE-05.THIRD.dgn,Design Model:133475 | 0.801283 | 150.00; 0.00; 3.89; | Radiator Parameters - Box | Length: 300
M-BmvRadiator-Column | ensuite | 6 ,SHE-05.THIRD.dgn,Design Model:229302 | 1.29128 | 250.00; 0.00; 2.41;
M-BmvRadiator-Column | 19 | 6 ,SHE-05.THIRD.dgn,Design Model:300364 | 1.29128 | 250.00; 0.00; 2.41;
M-BmvRadiator-Column | bath | 6 ,SHE-05.THIRD.dgn,Design Model:435141 | 1.29128 | 250.00; 0.00; 2.41;
M-BmvRadiator-Column | 26 | 7 ,SHE-06.FOURTH.dgn,Design Model:485879 | 1.29128 | 250.00; 0.00; 2.41;
M-BmvRadiator-Column | 25 | 7 ,SHE-06.FOURTH.dgn,Design Model:488452 | 1.29128 | 250.00; 0.00; 2.41;
M-BmvRadiator-Column | ensuite | 7 ,SHE-06.FOURTH.dgn,Design Model:488565 | 1.29128 | 250.00; 0.00; 2.41;
M-BmvRadiator-Column | ensuite | 7 ,SHE-06.FOURTH.dgn,Design Model:488678 | 1.29128 | 250.00; 0.00; 2.41;
M-BmvRadiator-Column | 24 | 7 ,SHE-06.FOURTH.dgn,Design Model:488791 | 1.29128 | 250.00; 0.00; 2.41;
M-BmvRadiator-Column | ensuite | 7 ,SHE-06.FOURTH.dgn,Design Model:488904 | 1.29128 | 250.00; 0.00; 2.41;
M-BmvRadiator-Column | bath | 18,SHE-04.SECOND.dgn,Design Model:133362 | 1.04628 | 200.00; 0.00; 2.98; | Radiator Parameters - Box | Length: 400
M-BmvRadiator-Column | bath | 18,SHE-04.SECOND.dgn,Design Model:143194 | 1.29128 | 250.00; 0.00; 2.41;
M-BmvRadiator-Column | bath | 18,SHE-04.SECOND.dgn,Design Model:145994 | 1.29128 | 250.00; 0.00; 2.41;
M-BmvRadiator-Column | bath | 18,SHE-04.SECOND.dgn,Design Model:142051 | 1.29128 | 250.00; 0.00; 2.41;
M-BmvRadiator-Column | 14 | 18,SHE-04.SECOND.dgn,Design Model:133475 | 0.801283 | 150.00; 0.00; 3.89; | Radiator Parameters - Box | Length: 300
M-BmvRadiator-Column | ensuite | 18,SHE-04.SECOND.dgn,Design Model:229302 | 1.29128 | 250.00; 0.00; 2.41;
M-BmvRadiator-Column | 12 | 18,SHE-04.SECOND.dgn,Design Model:300364 | 1.29128 | 250.00; 0.00; 2.41;
M-BmvRadiator-Column | 15 | 18,SHE-04.SECOND.dgn,Design Model:374557 | 0.801283 | 150.00; 0.00; 3.89; | Radiator Parameters - Box | Length: 300

# IfcFlowTerminal: M-BmvRadiatorpanel-Panel (66)
Type - Radiator Panel Parameters - Box | Height: 450; Box | Width: 150; Box | Length: 750; Mounting Height: 350; Mounting Width: 50; Mounting Length: 600; Radiator Type: 1-Panel; Panel Type: 1-Single; Flow | Connection Side: 1-Left; Flow Location: 1-Panel 1; Flow | Outside Diameter: 25; Flow Top Offset: 375; Flow | Length: 50; Return | Connection Side: 2-Right; Return Location: 1-Panel 1; Return | Outer Diameter: 25; Return | Top Offset: 100; Return | Length: 50; Connection 1 | Length (L1): 0; Connection | End Type: -; View Display: Iso
Type - Parameters - Insulation | Thickness (mm): 0; Lining | Thickness (mm): 0; Correction Factor: 1.0; Wall Thickness: 0
Type - End Spec1_2 (1 Connection: Round) - Diameter 1 (D1 Ø): 100
Type - Emitters Analytical Parameters - Heat Emission (W): 0; Pressure Drop Type: 1-k value; Emitter Pressure Drop: 0; Flow Valve Type: 1-No Valve; Flow Valve K Value (W/m°C): 0; Return Valve Type: 1-No Valve; Return Valve K Value (W/m°C): 0
Type - Classification - Uniclass2015: Pr_70_60_36_71
Material: M_BSUK_Ventilation
Radiator Panel Parameters - Box | Height: 730; Box | Width: 185; Mounting Width: 25; Connection | End Type: -;
Parameters - Insulation | Surface Area: 0 m2; Lining | Surface Area: 0 m2; Status: BSUK; Air Flow: M
Construction Phase - Phase: New Construction
Name | In | Description | Box | Length | Type | Surface Area (m2) | Center Of Gravity
M-BmvRadiatorpanel-Panel | 01 | 1,SHE-01.GROUND.dgn,Design Model:257385 | 865 | Dimplex QM100RF | 2.3441 | 0.00; 0.00; 0.00;
M-BmvRadiatorpanel-Panel | 01 | 1,SHE-01.GROUND.dgn,Design Model:259679 | 865 | Dimplex QM100RF | 2.3441 | 0.00; 0.00; 0.00;
M-BmvRadiatorpanel-Panel | 01 | 2,SHE-02.MEZZANINE.dgn,Design Model:195011 | 865 | Dimplex QM100RF | 2.3441 | 0.00; 0.00; 0.00;
M-BmvRadiatorpanel-Panel | k/d/l | 2,SHE-02.MEZZANINE.dgn,Design Model:195087 | 865 | Dimplex QM100RF | 2.3441 | 0.00; 0.00; 0.00;
M-BmvRadiatorpanel-Panel | k/d/l | 2,SHE-02.MEZZANINE.dgn,Design Model:195163 | 865 | Dimplex QM100RF | 2.3441 | 0.00; 0.00; 0.00;
M-BmvRadiatorpanel-Panel | 07 | 4,SHE-03.FIRST.dgn,Design Model:351056 | 865 | Dimplex QM100RF | 2.3441 | 0.00; 0.00; 0.00;
M-BmvRadiatorpanel-Panel | k/d/l | 4,SHE-03.FIRST.dgn,Design Model:351132 | 1069 | Dimplex QM150RF | 2.71742 | 534.50; 23.45; 1.08;
M-BmvRadiatorpanel-Panel | k/d/l | 4,SHE-03.FIRST.dgn,Design Model:351832 | 1069 | Dimplex QM150RF | 2.71742 | 534.50; 23.45; 1.08;
M-BmvRadiatorpanel-Panel | studio | 4,SHE-03.FIRST.dgn,Design Model:351908 | 865 | Dimplex QM100RF | 2.3441 | 0.00; 0.00; 0.00;
M-BmvRadiatorpanel-Panel | 05 | 4,SHE-03.FIRST.dgn,Design Model:351984 | 1069 | Dimplex QM150RF | 2.71742 | 534.50; 23.45; 1.08;
M-BmvRadiatorpanel-Panel | studio | 4,SHE-03.FIRST.dgn,Design Model:352060 | 1069 | Dimplex QM150RF | 2.71742 | 534.50; 23.45; 1.08;
M-BmvRadiatorpanel-Panel | k/d/l | 4,SHE-03.FIRST.dgn,Design Model:352136 | 1069 | Dimplex QM150RF | 2.71742 | 534.50; 23.45; 1.08;
M-BmvRadiatorpanel-Panel | 02 | 4,SHE-03.FIRST.dgn,Design Model:352212 | 865 | Dimplex QM100RF | 2.3441 | 0.00; 0.00; 0.00;
M-BmvRadiatorpanel-Panel | 02 | 4,SHE-03.FIRST.dgn,Design Model:352288 | 865 | Dimplex QM100RF | 2.3441 | 0.00; 0.00; 0.00;
M-BmvRadiatorpanel-Panel | k/d/l | 4,SHE-03.FIRST.dgn,Design Model:352364 | 1069 | Dimplex QM150RF | 2.71742 | 534.50; 23.45; 1.08;
M-BmvRadiatorpanel-Panel | 08 | 4,SHE-03.FIRST.dgn,Design Model:352440 | 865 | Dimplex QM100RF | 2.3441 | 0.00; 0.00; 0.00;
M-BmvRadiatorpanel-Panel | 06 | 4,SHE-03.FIRST.dgn,Design Model:352815 | 865 | Dimplex QM100RF | 2.3441 | 0.00; 0.00; 0.00;
M-BmvRadiatorpanel-Panel | bed | 4,SHE-03.FIRST.dgn,Design Model:352967 | 865 | Dimplex QM100RF | 2.3441 | 0.00; 0.00; 0.00;
M-BmvRadiatorpanel-Panel | bed | 4,SHE-03.FIRST.dgn,Design Model:353043 | 865 | Dimplex QM100RF | 2.3441 | 0.00; 0.00; 0.00;
M-BmvRadiatorpanel-Panel | 04 | 4,SHE-03.FIRST.dgn,Design Model:353119 | 1069 | Dimplex QM150RF | 2.71742 | 534.50; 23.45; 1.08;
M-BmvRadiatorpanel-Panel | k/d/l | 6,SHE-05.THIRD.dgn,Design Model:435952 | 1069 | Dimplex QM150RF | 2.71742 | 534.50; 23.45; 1.08;
M-BmvRadiatorpanel-Panel | 21 | 6,SHE-05.THIRD.dgn,Design Model:436028 | 865 | Dimplex QM100RF | 2.3441 | 0.00; 0.00; 0.00;
M-BmvRadiatorpanel-Panel | k/d/l | 6,SHE-05.THIRD.dgn,Design Model:436104 | 1069 | Dimplex QM150RF | 2.71742 | 534.50; 23.45; 1.08;
M-BmvRadiatorpanel-Panel | 20 | 6,SHE-05.THIRD.dgn,Design Model:436180 | 865 | Dimplex QM100RF | 2.3441 | 0.00; 0.00; 0.00;
M-BmvRadiatorpanel-Panel | bed | 6,SHE-05.THIRD.dgn,Design Model:436256 | 865 | Dimplex QM100RF | 2.3441 | 0.00; 0.00; 0.00;
M-BmvRadiatorpanel-Panel | 19 | 6,SHE-05.THIRD.dgn,Design Model:436332 | 1069 | Dimplex QM150RF | 2.71742 | 534.50; 23.45; 1.08;
M-BmvRadiatorpanel-Panel | 18 | 6,SHE-05.THIRD.dgn,Design Model:436408 | 1069 | Dimplex QM150RF | 2.71742 | 534.50; 23.45; 1.08;
M-BmvRadiatorpanel-Panel | bed | 6,SHE-05.THIRD.dgn,Design Model:436484 | 865 | Dimplex QM100RF | 2.3441 | 0.00; 0.00; 0.00;
M-BmvRadiatorpanel-Panel | studio | 6,SHE-05.THIRD.dgn,Design Model:436560 | 1069 | Dimplex QM150RF | 2.71742 | 534.50; 23.45; 1.08;
M-BmvRadiatorpanel-Panel | studio | 6,SHE-05.THIRD.dgn,Design Model:436636 | 865 | Dimplex QM100RF | 2.3441 | 0.00; 0.00; 0.00;
M-BmvRadiatorpanel-Panel | k/d/l | 6,SHE-05.THIRD.dgn,Design Model:436712 | 1069 | Dimplex QM150RF | 2.71742 | 534.50; 23.45; 1.08;
M-BmvRadiatorpanel-Panel | 16 | 6,SHE-05.THIRD.dgn,Design Model:436788 | 865 | Dimplex QM100RF | 2.3441 | 0.00; 0.00; 0.00;
M-BmvRadiatorpanel-Panel | 16 | 6,SHE-05.THIRD.dgn,Design Model:436864 | 865 | Dimplex QM100RF | 2.3441 | 0.00; 0.00; 0.00;
M-BmvRadiatorpanel-Panel | k/d/l | 6,SHE-05.THIRD.dgn,Design Model:436940 | 1069 | Dimplex QM150RF | 2.71742 | 534.50; 23.45; 1.08;
M-BmvRadiatorpanel-Panel | 22 | 6,SHE-05.THIRD.dgn,Design Model:437016 | 865 | Dimplex QM100RF | 2.3441 | 0.00; 0.00; 0.00;
M-BmvRadiatorpanel-Panel | 26 | 7,SHE-06.FOURTH.dgn,Design Model:485803 | 865 | Dimplex QM100RF | 2.3441 | 0.00; 0.00; 0.00;
M-BmvRadiatorpanel-Panel | 26 | 7,SHE-06.FOURTH.dgn,Design Model:485992 | 865 | Dimplex QM100RF | 2.3441 | 0.00; 0.00; 0.00;
M-BmvRadiatorpanel-Panel | 26 | 7,SHE-06.FOURTH.dgn,Design Model:486068 | 865 | Dimplex QM100RF | 2.3441 | 0.00; 0.00; 0.00;
M-BmvRadiatorpanel-Panel | 23 | 7,SHE-06.FOURTH.dgn,Design Model:486144 | 865 | Dimplex QM100RF | 2.3441 | 0.00; 0.00; 0.00;
M-BmvRadiatorpanel-Panel | 23 | 7,SHE-06.FOURTH.dgn,Design Model:486220 | 865 | Dimplex QM100RF | 2.3441 | 0.00; 0.00; 0.00;
M-BmvRadiatorpanel-Panel | 26 | 7,SHE-06.FOURTH.dgn,Design Model:487072 | 580 | Dimplex QM150RF | 1.80702 | 290.00; 34.14; 1.58; | Radiator Panel Parameters - Mounting Length: 580
M-BmvRadiatorpanel-Panel | 23 | 7,SHE-06.FOURTH.dgn,Design Model:487616 | 580 | Dimplex QM150RF | 1.80702 | 290.00; 34.14; 1.58; | Radiator Panel Parameters - Mounting Length: 580
M-BmvRadiatorpanel-Panel | 24 | 7,SHE-06.FOURTH.dgn,Design Model:487692 | 580 | Dimplex QM150RF | 1.80702 | 290.00; 34.14; 1.58; | Radiator Panel Parameters - Mounting Length: 580
M-BmvRadiatorpanel-Panel | 25 | 7,SHE-06.FOURTH.dgn,Design Model:487768 | 580 | Dimplex QM150RF | 1.80702 | 290.00; 34.14; 1.58; | Radiator Panel Parameters - Mounting Length: 580
M-BmvRadiatorpanel-Panel | 25 | 7,SHE-06.FOURTH.dgn,Design Model:487920 | 865 | Dimplex QM100RF | 2.3441 | 0.00; 0.00; 0.00;
M-BmvRadiatorpanel-Panel | 25 | 7,SHE-06.FOURTH.dgn,Design Model:487996 | 865 | Dimplex QM100RF | 2.3441 | 0.00; 0.00; 0.00;
M-BmvRadiatorpanel-Panel | 25 | 7,SHE-06.FOURTH.dgn,Design Model:488072 | 865 | Dimplex QM100RF | 2.3441 | 0.00; 0.00; 0.00;
M-BmvRadiatorpanel-Panel | 24 | 7,SHE-06.FOURTH.dgn,Design Model:488148 | 865 | Dimplex QM100RF | 2.3441 | 0.00; 0.00; 0.00;
M-BmvRadiatorpanel-Panel | 24 | 7,SHE-06.FOURTH.dgn,Design Model:488224 | 865 | Dimplex QM100RF | 2.3441 | 0.00; 0.00; 0.00;
M-BmvRadiatorpanel-Panel | 24 | 7,SHE-06.FOURTH.dgn,Design Model:488300 | 865 | Dimplex QM100RF | 2.3441 | 0.00; 0.00; 0.00;
M-BmvRadiatorpanel-Panel | 23 | 7,SHE-06.FOURTH.dgn,Design Model:488376 | 865 | Dimplex QM100RF | 2.3441 | 0.00; 0.00; 0.00;
M-BmvRadiatorpanel-Panel | k/d/l | 18,SHE-04.SECOND.dgn,Design Model:373417 | 1069 | Dimplex QM150RF | 2.71742 | 534.50; 23.45; 1.08;
M-BmvRadiatorpanel-Panel | 14 | 18,SHE-04.SECOND.dgn,Design Model:373493 | 865 | Dimplex QM100RF | 2.3441 | 0.00; 0.00; 0.00;
M-BmvRadiatorpanel-Panel | k/d/l | 18,SHE-04.SECOND.dgn,Design Model:373569 | 1069 | Dimplex QM150RF | 2.71742 | 534.50; 23.45; 1.08;
M-BmvRadiatorpanel-Panel | 13 | 18,SHE-04.SECOND.dgn,Design Model:373645 | 865 | Dimplex QM100RF | 2.3441 | 0.00; 0.00; 0.00;
M-BmvRadiatorpanel-Panel | bed | 18,SHE-04.SECOND.dgn,Design Model:373721 | 865 | Dimplex QM100RF | 2.3441 | 0.00; 0.00; 0.00;
M-BmvRadiatorpanel-Panel | 12 | 18,SHE-04.SECOND.dgn,Design Model:373797 | 1069 | Dimplex QM150RF | 2.71742 | 534.50; 23.45; 1.08;
M-BmvRadiatorpanel-Panel | 11 | 18,SHE-04.SECOND.dgn,Design Model:373873 | 1069 | Dimplex QM150RF | 2.71742 | 534.50; 23.45; 1.08;
M-BmvRadiatorpanel-Panel | bed | 18,SHE-04.SECOND.dgn,Design Model:373949 | 865 | Dimplex QM100RF | 2.3441 | 0.00; 0.00; 0.00;
M-BmvRadiatorpanel-Panel | studio | 18,SHE-04.SECOND.dgn,Design Model:374025 | 1069 | Dimplex QM150RF | 2.71742 | 534.50; 23.45; 1.08;
M-BmvRadiatorpanel-Panel | studio | 18,SHE-04.SECOND.dgn,Design Model:374101 | 865 | Dimplex QM100RF | 2.3441 | 0.00; 0.00; 0.00;
M-BmvRadiatorpanel-Panel | k/d/l | 18,SHE-04.SECOND.dgn,Design Model:374177 | 1069 | Dimplex QM150RF | 2.71742 | 534.50; 23.45; 1.08;
M-BmvRadiatorpanel-Panel | 09 | 18,SHE-04.SECOND.dgn,Design Model:374253 | 865 | Dimplex QM100RF | 2.3441 | 0.00; 0.00; 0.00;
M-BmvRadiatorpanel-Panel | 09 | 18,SHE-04.SECOND.dgn,Design Model:374329 | 865 | Dimplex QM100RF | 2.3441 | 0.00; 0.00; 0.00;
M-BmvRadiatorpanel-Panel | k/d/l | 18,SHE-04.SECOND.dgn,Design Model:374405 | 1069 | Dimplex QM150RF | 2.71742 | 534.50; 23.45; 1.08;
M-BmvRadiatorpanel-Panel | 15 | 18,SHE-04.SECOND.dgn,Design Model:374481 | 865 | Dimplex QM100RF | 2.3441 | 0.00; 0.00; 0.00;

# IfcFlowTerminal: M-RectBarSlotsEndGrille-BarSlots (22)
Type - PredefinedType: REGISTER
Type - Parameters - Insulation | Thickness (mm): 0; Lining | Thickness (mm): 0; Status: New; Pressure Class: Low; Air Flow: Supply; Correction Factor: 1.0; Wall Thickness: 0
Type - End Spec1_1 (1 Connection: Rect) - Width 1 (W1): 400; Depth 1 (D1): 350
Type - Classification - Uniclass2015: Pr_70_65_04_03
Type - Bar Slot Rectangular Grille Parameters - Thickness: 75; Side Distance: 25; Bottom Distance: 25; Inside Width: 350; Inside Depth: 300; No. Of Slots: 10; Slot Thickness: 5; Horizontal: yes; Panel Width: 0; Panel Depth: 0; Panel Thickness: 0; With Damper: no; Damper | Angle: 0; Damper | Thickness: 0; Connection | Offset: 0; Blade Orientation: 2-opposing; View Display: iso; Air Flow Rate: 0; Air Flow Rate Unit: 1-l/s; Center Offset: 0
Material: M_BSUK_Ventilation
Parameters - Insulation | Surface Area: 0 m2; Lining | Surface Area: 0 m2; Status: BSUK; Air Flow: M
End Spec1_1 (1 Connection: Rect) - Width 1 (W1): 800
Bar Slot Rectangular Grille Parameters - AutoSize: 1-symprop; Thickness: 20; Side Distance: 40; Inside Width: 720; Panel Width: 800; Outlet Pressure (Pa): 0
Name | In | Description | Surface Area (m2) | Center Of Gravity | Depth 1 (D1) = Panel Depth | Bottom Distance | Inside Depth
M-RectBarSlotsEndGrille-BarSlots | 25 | 7,SHE-06.FOURTH.dgn,Design Model:503159 | 0.0632 | 14.43; 0.00; 0.00; | 80 | 4 | 72
M-RectBarSlotsEndGrille-BarSlots | 25 | 7,SHE-06.FOURTH.dgn,Design Model:503649 | 0.0632 | 14.43; 0.00; 0.00; | 80 | 4 | 72
M-RectBarSlotsEndGrille-BarSlots | 25 | 7,SHE-06.FOURTH.dgn,Design Model:503727 | 0.0632 | 14.43; 0.00; 0.00; | 80 | 4 | 72
M-RectBarSlotsEndGrille-BarSlots | 3 | 7,SHE-06.FOURTH.dgn,Design Model:503884 | 0.0632 | 14.43; 0.00; 0.00; | 80 | 4 | 72
M-RectBarSlotsEndGrille-BarSlots | 24 | 7,SHE-06.FOURTH.dgn,Design Model:503962 | 0.0632 | 14.43; 0.00; 0.00; | 80 | 4 | 72
M-RectBarSlotsEndGrille-BarSlots | 24 | 7,SHE-06.FOURTH.dgn,Design Model:504040 | 0.0632 | 14.43; 0.00; 0.00; | 80 | 4 | 72
M-RectBarSlotsEndGrille-BarSlots | 26 | 8,SHE-07.FIFTH.dgn,Design Model:291397 | 0.08 | 15.50; 0.00; 0.00; | 100 | 5 | 90
M-RectBarSlotsEndGrille-BarSlots | 26 | 8,SHE-07.FIFTH.dgn,Design Model:292002 | 0.08 | 15.50; 0.00; 0.00; | 100 | 5 | 90
M-RectBarSlotsEndGrille-BarSlots | 26 | 8,SHE-07.FIFTH.dgn,Design Model:292080 | 0.08 | 15.50; 0.00; 0.00; | 100 | 5 | 90
M-RectBarSlotsEndGrille-BarSlots | 26 | 8,SHE-07.FIFTH.dgn,Design Model:292158 | 0.08 | 15.50; 0.00; 0.00; | 100 | 5 | 90
M-RectBarSlotsEndGrille-BarSlots | 25 | 8,SHE-07.FIFTH.dgn,Design Model:292236 | 0.08 | 15.50; 0.00; 0.00; | 100 | 5 | 90
M-RectBarSlotsEndGrille-BarSlots | k/d/l | 8,SHE-07.FIFTH.dgn,Design Model:292314 | 0.08 | 15.50; 0.00; 0.00; | 100 | 5 | 90
M-RectBarSlotsEndGrille-BarSlots | 25 | 8,SHE-07.FIFTH.dgn,Design Model:292392 | 0.08 | 15.50; 0.00; 0.00; | 100 | 5 | 90
M-RectBarSlotsEndGrille-BarSlots | k/d/l | 8,SHE-07.FIFTH.dgn,Design Model:292470 | 0.08 | 15.50; 0.00; 0.00; | 100 | 5 | 90
M-RectBarSlotsEndGrille-BarSlots | k/d/l | 8,SHE-07.FIFTH.dgn,Design Model:292548 | 0.08 | 15.50; 0.00; 0.00; | 100 | 5 | 90
M-RectBarSlotsEndGrille-BarSlots | k/d/l | 8,SHE-07.FIFTH.dgn,Design Model:292626 | 0.08 | 15.50; 0.00; 0.00; | 100 | 5 | 90
M-RectBarSlotsEndGrille-BarSlots | 24 | 8,SHE-07.FIFTH.dgn,Design Model:292704 | 0.08 | 15.50; 0.00; 0.00; | 100 | 5 | 90
M-RectBarSlotsEndGrille-BarSlots | k/d/l | 8,SHE-07.FIFTH.dgn,Design Model:292782 | 0.08 | 15.50; 0.00; 0.00; | 100 | 5 | 90
M-RectBarSlotsEndGrille-BarSlots | k/d/l | 8,SHE-07.FIFTH.dgn,Design Model:292860 | 0.08 | 15.50; 0.00; 0.00; | 100 | 5 | 90
M-RectBarSlotsEndGrille-BarSlots | k/d/l | 8,SHE-07.FIFTH.dgn,Design Model:292938 | 0.08 | 15.50; 0.00; 0.00; | 100 | 5 | 90
M-RectBarSlotsEndGrille-BarSlots | 23 | 8,SHE-07.FIFTH.dgn,Design Model:293016 | 0.08 | 15.50; 0.00; 0.00; | 100 | 5 | 90
M-RectBarSlotsEndGrille-BarSlots | k/d/l | 8,SHE-07.FIFTH.dgn,Design Model:293094 | 0.08 | 15.50; 0.00; 0.00; | 100 | 5 | 90

# IfcFlowTerminal: SHE_A-Sink_47x100 (5)
Type - Plumbing Fixture - Connection | Vent: no
Type - Accessibility - Accessibility | Handicap Accessible: no; Has Non-skid Surface: no
Plumbing Fixture - Connection | Cold Water: 0 m; Connection | Hot Water: 0 m; Connection | Waste: 0 m; Mounting | Height: 0 m
Parametric Definition - Parametric | File Type: BXC; Parametric | File Name: K-3206-3
Identification - ID | Description: washbasin
Discipline - Discipline: Architectural
Construction Phase - Phase: New Construction
Classification - Uniclass2015: Pr_40_20_96_15
Name | In | Description | ID | Number | ID | Notes
24 | 24 | washbasin :7 ,SHE-06.FOURTH.dgn,Design Model:248381 | 24 | 600x470mm
23 | 23 | washbasin :7 ,SHE-06.FOURTH.dgn,Design Model:263952 | 23 | 1000x470mm
26 | 26 | washbasin :7 ,SHE-06.FOURTH.dgn,Design Model:406288 | 26 | 1000x470mm
25 | 25 | washbasin :7 ,SHE-06.FOURTH.dgn,Design Model:407116 | 25 | 1000x470mm
23 | 23 | washbasin :7 ,SHE-06.FOURTH.dgn,Design Model:416690 | 23 | 1000x470mm

# IfcFlowTerminal: SHE_A-Sink_47x60 (11)
Type - Plumbing Fixture - Connection | Vent: no
Type - Accessibility - Accessibility | Handicap Accessible: no; Has Non-skid Surface: no
Plumbing Fixture - Connection | Cold Water: 0 m; Connection | Hot Water: 0 m; Connection | Waste: 0 m; Mounting | Height: 0 m
Parametric Definition - Parametric | File Type: BXC; Parametric | File Name: K-3206-3
Identification - ID | Description: washbasin
Discipline - Discipline: Architectural
Construction Phase - Phase: New Construction
Classification - Uniclass2015: Pr_40_20_96_15
Name | In | Description | ID | Number | ID | Notes
00 | M | washbasin :1 ,SHE-01.GROUND.dgn,Design Model:155272 | 00 | 600x470mm
00 | 0 | washbasin :1 ,SHE-01.GROUND.dgn,Design Model:156320 | 00 | 600x470mm
00 | 01 | washbasin :2 ,SHE-02.MEZZANINE.dgn,Design Model:120921 | 00 | 600x470mm
00 | WC | washbasin :2 ,SHE-02.MEZZANINE.dgn,Design Model:120938 | 00 | 600x470mm
00 | WC | washbasin :2 ,SHE-02.MEZZANINE.dgn,Design Model:120946 | 00 | 600x470mm
07 | 07 | washbasin :4 ,SHE-03.FIRST.dgn,Design Model:146459 | 07 | 600x470mm
21 | bath | washbasin :6 ,SHE-05.THIRD.dgn,Design Model:146459 | 21 | 600x470mm
24 | 24 | washbasin :7 ,SHE-06.FOURTH.dgn,Design Model:248790 | 24 | 1000x470mm
25 | 25 | washbasin :7 ,SHE-06.FOURTH.dgn,Design Model:256519 | 25 | 600x470mm
26 | 26 | washbasin :7 ,SHE-06.FOURTH.dgn,Design Model:514928 | 26 | 600x470mm
14 | bath | washbasin :18 ,SHE-04.SECOND.dgn,Design Model:146459 | 14 | 600x470mm

# IfcFlowTerminal: SHE_A-Sink_47x70 (15)
Type - Plumbing Fixture - Connection | Vent: no
Type - Accessibility - Accessibility | Handicap Accessible: no; Has Non-skid Surface: no
Plumbing Fixture - Connection | Cold Water: 0 m; Connection | Hot Water: 0 m; Connection | Waste: 0 m; Mounting | Height: 0 m
Parametric Definition - Parametric | File Type: BXC; Parametric | File Name: K-3206-3
Identification - ID | Description: washbasin; ID | Notes: 600x470mm
Discipline - Discipline: Architectural
Construction Phase - Phase: New Construction
Classification - Uniclass2015: Pr_40_20_96_15
Name | In | Description | ID | Number
08 | 08 | washbasin :4 ,SHE-03.FIRST.dgn,Design Model:146478 | 08
03 | 03 | washbasin :4 ,SHE-03.FIRST.dgn,Design Model:292382 | 03
04 | bath | washbasin :4 ,SHE-03.FIRST.dgn,Design Model:299615 | 04
05 | 05 | washbasin :4 ,SHE-03.FIRST.dgn,Design Model:300571 | 05
06 | bath | washbasin :4 ,SHE-03.FIRST.dgn,Design Model:327377 | 06
22 | 22 | washbasin :6 ,SHE-05.THIRD.dgn,Design Model:146478 | 22
17 | bath | washbasin :6 ,SHE-05.THIRD.dgn,Design Model:292382 | 17
18 | bath | washbasin :6 ,SHE-05.THIRD.dgn,Design Model:299615 | 18
19 | 19 | washbasin :6 ,SHE-05.THIRD.dgn,Design Model:300571 | 19
20 | bath | washbasin :6 ,SHE-05.THIRD.dgn,Design Model:327377 | 20
15 | 15 | washbasin :18 ,SHE-04.SECOND.dgn,Design Model:146478 | 15
10 | 10 | washbasin :18 ,SHE-04.SECOND.dgn,Design Model:292382 | 10
11 | bath | washbasin :18 ,SHE-04.SECOND.dgn,Design Model:299615 | 11
12 | 12 | washbasin :18 ,SHE-04.SECOND.dgn,Design Model:300571 | 12
13 | bath | washbasin :18 ,SHE-04.SECOND.dgn,Design Model:327377 | 13

# IfcFlowTerminal: SHE_A-Sink_47x80 (7)
Type - Plumbing Fixture - Connection | Vent: no
Type - Accessibility - Accessibility | Handicap Accessible: no; Has Non-skid Surface: no
Plumbing Fixture - Connection | Cold Water: 0 m; Connection | Hot Water: 0 m; Connection | Waste: 0 m; Mounting | Height: 0 m
Parametric Definition - Parametric | File Type: BXC; Parametric | File Name: K-3206-3
Identification - ID | Description: washbasin; ID | Notes: 600x470mm
Discipline - Discipline: Architectural
Construction Phase - Phase: New Construction
Classification - Uniclass2015: Pr_40_20_96_15
Name | In | Description | ID | Number
01 | 01 | washbasin :1 ,SHE-01.GROUND.dgn,Design Model:141034 | 01
02 | bath | washbasin :4 ,SHE-03.FIRST.dgn,Design Model:146548 | 02
02 | 02 | washbasin :4 ,SHE-03.FIRST.dgn,Design Model:232319 | 02
16 | 16 | washbasin :6 ,SHE-05.THIRD.dgn,Design Model:146548 | 16
16 | 16 | washbasin :6 ,SHE-05.THIRD.dgn,Design Model:232319 | 16
09 | 09 | washbasin :18 ,SHE-04.SECOND.dgn,Design Model:146548 | 09
09 | 09 | washbasin :18 ,SHE-04.SECOND.dgn,Design Model:232319 | 09

# IfcFlowTerminal: SHE_A-Toilet_base (38)
Plumbing Fixture - Connection | Cold Water: 0 m; Connection | Hot Water: 0 m; Connection | Waste: 0 m; Connection | Vent: no; Mounting | Height: 0 m
Parametric Definition - Parametric | File Type: CEL; Parametric | File Name: toilet
Identification - ID | Description: toilet; ID | Notes: 550x370mm
Discipline - Discipline: Architectural
Construction Phase - Phase: New Construction
Classification - Uniclass2015: Pr_40_20_06_11
Accessibility - Accessibility | Handicap Accessible: no; Has Non-skid Surface: no
Name | In | Description | ID | Number
00 | 0 | toilet :1 ,SHE-01.GROUND.dgn,Design Model:155284 | 00
00 | 0 | toilet :1 ,SHE-01.GROUND.dgn,Design Model:155702 | 00
01 | 01 | toilet :1 ,SHE-01.GROUND.dgn,Design Model:183802 | 01
00 | 01 | toilet :2 ,SHE-02.MEZZANINE.dgn,Design Model:120912 | 00
00 | WC | toilet :2 ,SHE-02.MEZZANINE.dgn,Design Model:120929 | 00
00 | WC | toilet :2 ,SHE-02.MEZZANINE.dgn,Design Model:120954 | 00
08 | 08 | toilet :4 ,SHE-03.FIRST.dgn,Design Model:146467 | 08
03 | 03 | toilet :4 ,SHE-03.FIRST.dgn,Design Model:146486 | 03
02 | bath | toilet :4 ,SHE-03.FIRST.dgn,Design Model:146539 | 02
04 | 04 | toilet :4 ,SHE-03.FIRST.dgn,Design Model:146503 | 04
02 | ensuite | toilet :4 ,SHE-03.FIRST.dgn,Design Model:229416 | 02
07 | 07 | toilet :4 ,SHE-03.FIRST.dgn,Design Model:270354 | 07
05 | 05 | toilet :4 ,SHE-03.FIRST.dgn,Design Model:300522 | 05
06 | 06 | toilet :4 ,SHE-03.FIRST.dgn,Design Model:327218 | 06
22 | bath | toilet :6 ,SHE-05.THIRD.dgn,Design Model:146467 | 22
17 | bath | toilet :6 ,SHE-05.THIRD.dgn,Design Model:146486 | 17
16 | bath | toilet :6 ,SHE-05.THIRD.dgn,Design Model:146539 | 16
18 | 18 | toilet :6 ,SHE-05.THIRD.dgn,Design Model:146503 | 18
16 | ensuite | toilet :6 ,SHE-05.THIRD.dgn,Design Model:229416 | 16
21 | 21 | toilet :6 ,SHE-05.THIRD.dgn,Design Model:270354 | 21
19 | 19 | toilet :6 ,SHE-05.THIRD.dgn,Design Model:300522 | 19
20 | bath | toilet :6 ,SHE-05.THIRD.dgn,Design Model:327218 | 20
25 | bath | toilet :7 ,SHE-06.FOURTH.dgn,Design Model:546729 | 25
26 | ensuite | toilet :7 ,SHE-06.FOURTH.dgn,Design Model:546738 | 26
23 | bath | toilet :7 ,SHE-06.FOURTH.dgn,Design Model:546747 | 23
24 | ensuite | toilet :7 ,SHE-06.FOURTH.dgn,Design Model:546756 | 24
25 | ensuite | toilet :7 ,SHE-06.FOURTH.dgn,Design Model:546765 | 25
26 | bath | toilet :7 ,SHE-06.FOURTH.dgn,Design Model:546844 | 26
23 | ensuite | toilet :7 ,SHE-06.FOURTH.dgn,Design Model:546958 | 23
24 | bath | toilet :7 ,SHE-06.FOURTH.dgn,Design Model:546967 | 24
15 | 15 | toilet :18 ,SHE-04.SECOND.dgn,Design Model:146467 | 15
10 | 10 | toilet :18 ,SHE-04.SECOND.dgn,Design Model:146486 | 10
09 | bath | toilet :18 ,SHE-04.SECOND.dgn,Design Model:146539 | 09
11 | bath | toilet :18 ,SHE-04.SECOND.dgn,Design Model:146503 | 11
09 | ensuite | toilet :18 ,SHE-04.SECOND.dgn,Design Model:229416 | 09
14 | 14 | toilet :18 ,SHE-04.SECOND.dgn,Design Model:270354 | 14
12 | 12 | toilet :18 ,SHE-04.SECOND.dgn,Design Model:300522 | 12
13 | 13 | toilet :18 ,SHE-04.SECOND.dgn,Design Model:327218 | 13

# IfcFurnishingElement: SHE_A-Cupboard_Electro (26)
Type - Pset_FurnitureTypeCommon - NominalDepth: 0.25 m; NominalHeight: 2.5 m; NominalLength: 0.7 m
Type - Discipline - Discipline: Architectural
Type - Classification - Uniclass2015: Pr_40_30_78
Type - Casework Parameters - Casework | Type: Tall
Type - Casework - Parametric | File Type: BXF; Parametric | File Name: 01-TallUK; Dimension | Width: 0.7 m; Dimension | Height: 2.5 m; Dimension | Depth: 0.25 m
Casework - Dimension | Width: 0.25 m
Name | In | Description | ID | Number
01 | corridor | 1 ,SHE-01.GROUND.dgn,Design Model:263240 | 01
06 | 06 | 4 ,SHE-03.FIRST.dgn,Design Model:135481 | 06
08 | storage | 4 ,SHE-03.FIRST.dgn,Design Model:135495 | 08
02 | storage | 4 ,SHE-03.FIRST.dgn,Design Model:135502 | 02
03 | 03 | 4 ,SHE-03.FIRST.dgn,Design Model:135523 | 03
07 | storage | 4 ,SHE-03.FIRST.dgn,Design Model:272307 | 07
04 | 04 | 4 ,SHE-03.FIRST.dgn,Design Model:288350 | 04
05 | 05 | 4 ,SHE-03.FIRST.dgn,Design Model:302316 | 05
20 | 20 | 6 ,SHE-05.THIRD.dgn,Design Model:135481 | 20
22 | storage | 6 ,SHE-05.THIRD.dgn,Design Model:135495 | 22
16 | storage | 6 ,SHE-05.THIRD.dgn,Design Model:135502 | 16
17 | storage | 6 ,SHE-05.THIRD.dgn,Design Model:135523 | 17
21 | 21 | 6 ,SHE-05.THIRD.dgn,Design Model:272307 | 21
18 | 18 | 6 ,SHE-05.THIRD.dgn,Design Model:288350 | 18
19 | 19 | 6 ,SHE-05.THIRD.dgn,Design Model:302316 | 19
26 | storage | 7 ,SHE-06.FOURTH.dgn,Design Model:490931 | 26
25 | 25 | 7 ,SHE-06.FOURTH.dgn,Design Model:490940 | 25
24 | storage | 7 ,SHE-06.FOURTH.dgn,Design Model:490947 | 24
23 | 3 | 7 ,SHE-06.FOURTH.dgn,Design Model:490954 | 23
13 | 13 | 18 ,SHE-04.SECOND.dgn,Design Model:135481 | 13
15 | storage | 18 ,SHE-04.SECOND.dgn,Design Model:135495 | 15
09 | storage | 18 ,SHE-04.SECOND.dgn,Design Model:135502 | 09
10 | 10 | 18 ,SHE-04.SECOND.dgn,Design Model:135523 | 10
14 | storage | 18 ,SHE-04.SECOND.dgn,Design Model:272307 | 14
11 | storage | 18 ,SHE-04.SECOND.dgn,Design Model:288350 | 11
12 | storage | 18 ,SHE-04.SECOND.dgn,Design Model:302316 | 12

# IfcFurnishingElement: SHE_A-Kitchenunit-Base (120)
Type - Pset_FurnitureTypeCommon - NominalDepth: 0.6 m; NominalHeight: 0.86 m; NominalLength: 0.6 m
Type - Discipline - Discipline: Architectural
Type - Classification - Uniclass2015: Pr_40_30_78
Type - Casework Parameters - Casework | Type: Base
Type - Casework - Parametric | File Type: BXF; Parametric | File Name: 01-BaseUK; Dimension | Width: 0.6 m; Dimension | Height: 0.86 m; Dimension | Depth: 0.6 m
Material: A_BSUK_StorageScreening_Ffe
Name | In | Description | ID | Number
01 | 01 | 2 ,SHE-02.MEZZANINE.dgn,Design Model:120072 | 01
01 | 01 | 2 ,SHE-02.MEZZANINE.dgn,Design Model:120083 | 01
01 | 01 | 2 ,SHE-02.MEZZANINE.dgn,Design Model:120092 | 01
01 | 01 | 2 ,SHE-02.MEZZANINE.dgn,Design Model:120100 | 01
01 | 01 | 2 ,SHE-02.MEZZANINE.dgn,Design Model:147775 | 01
01 | 01 | 2 ,SHE-02.MEZZANINE.dgn,Design Model:226182 | 01
06 | 06 | 4 ,SHE-03.FIRST.dgn,Design Model:134902 | 06
06 | 06 | 4 ,SHE-03.FIRST.dgn,Design Model:134910 | 06
06 | 06 | 4 ,SHE-03.FIRST.dgn,Design Model:134918 | 06
08 | 08 | 4 ,SHE-03.FIRST.dgn,Design Model:134968 | 08
08 | 08 | 4 ,SHE-03.FIRST.dgn,Design Model:134976 | 08
08 | 08 | 4 ,SHE-03.FIRST.dgn,Design Model:134977 | 08
08 | 08 | 4 ,SHE-03.FIRST.dgn,Design Model:134978 | 08
08 | 08 | 4 ,SHE-03.FIRST.dgn,Design Model:134979 | 08
08 | 08 | 4 ,SHE-03.FIRST.dgn,Design Model:135001 | 08
02 | k/d/l | 4 ,SHE-03.FIRST.dgn,Design Model:135003 | 02
02 | k/d/l | 4 ,SHE-03.FIRST.dgn,Design Model:135011 | 02
02 | k/d/l | 4 ,SHE-03.FIRST.dgn,Design Model:135019 | 02
02 | 02 | 4 ,SHE-03.FIRST.dgn,Design Model:135027 | 02
02 | 02 | 4 ,SHE-03.FIRST.dgn,Design Model:135035 | 02
03 | 03 | 4 ,SHE-03.FIRST.dgn,Design Model:135088 | 03
03 | 03 | 4 ,SHE-03.FIRST.dgn,Design Model:135176 | 03
03 | 03 | 4 ,SHE-03.FIRST.dgn,Design Model:135226 | 03
03 | 03 | 4 ,SHE-03.FIRST.dgn,Design Model:135269 | 03
04 | k/d/l | 4 ,SHE-03.FIRST.dgn,Design Model:135326 | 04
04 | k/d/l | 4 ,SHE-03.FIRST.dgn,Design Model:135405 | 04
04 | k/d/l | 4 ,SHE-03.FIRST.dgn,Design Model:135455 | 04
05 | 05 | 4 ,SHE-03.FIRST.dgn,Design Model:135463 | 05
05 | 05 | 4 ,SHE-03.FIRST.dgn,Design Model:135471 | 05
05 | 05 | 4 ,SHE-03.FIRST.dgn,Design Model:135479 | 05
07 | k/d/l | 4 ,SHE-03.FIRST.dgn,Design Model:186406 | 07
07 | k/d/l | 4 ,SHE-03.FIRST.dgn,Design Model:186431 | 07
07 | 07 | 4 ,SHE-03.FIRST.dgn,Design Model:254800 | 07 | Casework - Dimension | Width: 0.9 m
07 | k/d/l | 4 ,SHE-03.FIRST.dgn,Design Model:272203 | 07
07 | k/d/l | 4 ,SHE-03.FIRST.dgn,Design Model:272232 | 07
07 | k/d/l | 4 ,SHE-03.FIRST.dgn,Design Model:272292 | 07
20 | k/d/l | 6 ,SHE-05.THIRD.dgn,Design Model:134902 | 20
20 | k/d/l | 6 ,SHE-05.THIRD.dgn,Design Model:134910 | 20
20 | k/d/l | 6 ,SHE-05.THIRD.dgn,Design Model:134918 | 20
22 | k/d/l | 6 ,SHE-05.THIRD.dgn,Design Model:134968 | 22
22 | k/d/l | 6 ,SHE-05.THIRD.dgn,Design Model:134976 | 22
22 | k/d/l | 6 ,SHE-05.THIRD.dgn,Design Model:134977 | 22
22 | k/d/l | 6 ,SHE-05.THIRD.dgn,Design Model:134978 | 22
22 | k/d/l | 6 ,SHE-05.THIRD.dgn,Design Model:134979 | 22
22 | k/d/l | 6 ,SHE-05.THIRD.dgn,Design Model:135001 | 22
16 | k/d/l | 6 ,SHE-05.THIRD.dgn,Design Model:135003 | 16
16 | k/d/l | 6 ,SHE-05.THIRD.dgn,Design Model:135011 | 16
16 | k/d/l | 6 ,SHE-05.THIRD.dgn,Design Model:135019 | 16
16 | k/d/l | 6 ,SHE-05.THIRD.dgn,Design Model:135027 | 16
16 | k/d/l | 6 ,SHE-05.THIRD.dgn,Design Model:135035 | 16
17 | studio | 6 ,SHE-05.THIRD.dgn,Design Model:135088 | 17
17 | studio | 6 ,SHE-05.THIRD.dgn,Design Model:135176 | 17
17 | studio | 6 ,SHE-05.THIRD.dgn,Design Model:135226 | 17
17 | studio | 6 ,SHE-05.THIRD.dgn,Design Model:135269 | 17
18 | 18 | 6 ,SHE-05.THIRD.dgn,Design Model:135326 | 18
18 | 18 | 6 ,SHE-05.THIRD.dgn,Design Model:135405 | 18
18 | 18 | 6 ,SHE-05.THIRD.dgn,Design Model:135455 | 18
19 | 19 | 6 ,SHE-05.THIRD.dgn,Design Model:135463 | 19
19 | 19 | 6 ,SHE-05.THIRD.dgn,Design Model:135471 | 19
19 | 19 | 6 ,SHE-05.THIRD.dgn,Design Model:135479 | 19
21 | 21 | 6 ,SHE-05.THIRD.dgn,Design Model:186406 | 21
21 | 21 | 6 ,SHE-05.THIRD.dgn,Design Model:186431 | 21
21 | 21 | 6 ,SHE-05.THIRD.dgn,Design Model:254800 | 21 | Casework - Dimension | Width: 0.9 m
21 | 21 | 6 ,SHE-05.THIRD.dgn,Design Model:272203 | 21
21 | 21 | 6 ,SHE-05.THIRD.dgn,Design Model:272232 | 21
21 | 21 | 6 ,SHE-05.THIRD.dgn,Design Model:272292 | 21
23 | k/d/l | 8 ,SHE-07.FIFTH.dgn,Design Model:157111 | 23
23 | k/d/l | 8 ,SHE-07.FIFTH.dgn,Design Model:157192 | 23
23 | k/d/l | 8 ,SHE-07.FIFTH.dgn,Design Model:157200 | 23
23 | k/d/l | 8 ,SHE-07.FIFTH.dgn,Design Model:157208 | 23
23 | k/d/l | 8 ,SHE-07.FIFTH.dgn,Design Model:157232 | 23
23 | k/d/l | 8 ,SHE-07.FIFTH.dgn,Design Model:157255 | 23
23 | k/d/l | 8 ,SHE-07.FIFTH.dgn,Design Model:157278 | 23
24 | k/d/l | 8 ,SHE-07.FIFTH.dgn,Design Model:157287 | 24
24 | k/d/l | 8 ,SHE-07.FIFTH.dgn,Design Model:157295 | 24
24 | k/d/l | 8 ,SHE-07.FIFTH.dgn,Design Model:157303 | 24
24 | k/d/l | 8 ,SHE-07.FIFTH.dgn,Design Model:157311 | 24
24 | 24 | 8 ,SHE-07.FIFTH.dgn,Design Model:157335 | 24
24 | 24 | 8 ,SHE-07.FIFTH.dgn,Design Model:157358 | 24
24 | 24 | 8 ,SHE-07.FIFTH.dgn,Design Model:157381 | 24
25 | 25 | 8 ,SHE-07.FIFTH.dgn,Design Model:157426 | 25
25 | 25 | 8 ,SHE-07.FIFTH.dgn,Design Model:157470 | 25
25 | k/d/l | 8 ,SHE-07.FIFTH.dgn,Design Model:157523 | 25
25 | k/d/l | 8 ,SHE-07.FIFTH.dgn,Design Model:157546 | 25
25 | k/d/l | 8 ,SHE-07.FIFTH.dgn,Design Model:157569 | 25
26 | 26 | 8 ,SHE-07.FIFTH.dgn,Design Model:157637 | 26
26 | k/d/l | 8 ,SHE-07.FIFTH.dgn,Design Model:157645 | 26
26 | k/d/l | 8 ,SHE-07.FIFTH.dgn,Design Model:157653 | 26
26 | k/d/l | 8 ,SHE-07.FIFTH.dgn,Design Model:157661 | 26
26 | 26 | 8 ,SHE-07.FIFTH.dgn,Design Model:157669 | 26
13 | 13 | 18 ,SHE-04.SECOND.dgn,Design Model:134902 | 13
13 | 13 | 18 ,SHE-04.SECOND.dgn,Design Model:134910 | 13
13 | 13 | 18 ,SHE-04.SECOND.dgn,Design Model:134918 | 13
15 | k/d/l | 18 ,SHE-04.SECOND.dgn,Design Model:134968 | 15
15 | k/d/l | 18 ,SHE-04.SECOND.dgn,Design Model:134976 | 15
15 | k/d/l | 18 ,SHE-04.SECOND.dgn,Design Model:134977 | 15
15 | k/d/l | 18 ,SHE-04.SECOND.dgn,Design Model:134978 | 15
15 | k/d/l | 18 ,SHE-04.SECOND.dgn,Design Model:134979 | 15
15 | k/d/l | 18 ,SHE-04.SECOND.dgn,Design Model:135001 | 15
09 | k/d/l | 18 ,SHE-04.SECOND.dgn,Design Model:135003 | 09
09 | k/d/l | 18 ,SHE-04.SECOND.dgn,Design Model:135011 | 09
09 | k/d/l | 18 ,SHE-04.SECOND.dgn,Design Model:135019 | 09
09 | k/d/l | 18 ,SHE-04.SECOND.dgn,Design Model:135027 | 09
09 | k/d/l | 18 ,SHE-04.SECOND.dgn,Design Model:135035 | 09
10 | 10 | 18 ,SHE-04.SECOND.dgn,Design Model:135088 | 10
10 | 10 | 18 ,SHE-04.SECOND.dgn,Design Model:135176 | 10
10 | 10 | 18 ,SHE-04.SECOND.dgn,Design Model:135226 | 10
10 | 10 | 18 ,SHE-04.SECOND.dgn,Design Model:135269 | 10
11 | k/d/l | 18 ,SHE-04.SECOND.dgn,Design Model:135326 | 11
11 | k/d/l | 18 ,SHE-04.SECOND.dgn,Design Model:135405 | 11
11 | k/d/l | 18 ,SHE-04.SECOND.dgn,Design Model:135455 | 11
12 | k/d/l | 18 ,SHE-04.SECOND.dgn,Design Model:135463 | 12
12 | k/d/l | 18 ,SHE-04.SECOND.dgn,Design Model:135471 | 12
12 | k/d/l | 18 ,SHE-04.SECOND.dgn,Design Model:135479 | 12
14 | k/d/l | 18 ,SHE-04.SECOND.dgn,Design Model:186406 | 14
14 | k/d/l | 18 ,SHE-04.SECOND.dgn,Design Model:186431 | 14
14 | k/d/l | 18 ,SHE-04.SECOND.dgn,Design Model:254800 | 14 | Casework - Dimension | Width: 0.9 m
14 | k/d/l | 18 ,SHE-04.SECOND.dgn,Design Model:272203 | 14
14 | k/d/l | 18 ,SHE-04.SECOND.dgn,Design Model:272232 | 14
14 | k/d/l | 18 ,SHE-04.SECOND.dgn,Design Model:272292 | 14

# IfcFurnishingElement: SHE_A-Kitchenunit-Base 37x60 (9)
In: k/d/l
Type - Pset_FurnitureTypeCommon - NominalDepth: 0.37 m; NominalHeight: 0.86 m; NominalLength: 0.6 m
Type - Discipline - Discipline: Architectural
Type - Classification - Uniclass2015: Pr_40_30_78
Type - Casework Parameters - Casework | Type: Base
Type - Casework - Parametric | File Type: BXF; Parametric | File Name: 01-BaseUK; Dimension | Width: 0.6 m; Dimension | Height: 0.86 m; Dimension | Depth: 0.37 m
Material: A_BSUK_StorageScreening_Ffe
Name | Description | ID | Number
23 | 8 ,SHE-07.FIFTH.dgn,Design Model:157136 | 23
23 | 8 ,SHE-07.FIFTH.dgn,Design Model:157233 | 23
23 | 8 ,SHE-07.FIFTH.dgn,Design Model:157256 | 23
24 | 8 ,SHE-07.FIFTH.dgn,Design Model:157313 | 24
24 | 8 ,SHE-07.FIFTH.dgn,Design Model:157336 | 24
24 | 8 ,SHE-07.FIFTH.dgn,Design Model:157359 | 24
25 | 8 ,SHE-07.FIFTH.dgn,Design Model:157522 | 25
25 | 8 ,SHE-07.FIFTH.dgn,Design Model:157545 | 25
25 | 8 ,SHE-07.FIFTH.dgn,Design Model:157568 | 25

# IfcFurnishingElement: SHE_A-Kitchenunit-Base60x30, 25
In: 25
Type - Pset_FurnitureTypeCommon - NominalDepth: 0.6 m; NominalHeight: 0.86 m; NominalLength: 0.3 m
Type - Discipline - Discipline: Architectural
Type - Classification - Uniclass2015: Pr_40_30_78
Type - Casework Parameters - Casework | Type: Base
Type - Casework - Parametric | File Type: BXF; Parametric | File Name: 01-BaseUK; Dimension | Width: 0.3 m; Dimension | Height: 0.86 m; Dimension | Depth: 0.6 m
Description: 8 ,SHE-07.FIFTH.dgn,Design Model:158601; Material: A_BSUK_StorageScreening_Ffe
Identification - ID | Number: 25

# IfcFurnishingElement: SHE_A-Kitchenunit-Base60x45 (10)
Type - Pset_FurnitureTypeCommon - NominalDepth: 0.6 m; NominalHeight: 0.86 m; NominalLength: 0.45 m
Type - Discipline - Discipline: Architectural
Type - Classification - Uniclass2015: Pr_40_30_78
Type - Casework Parameters - Casework | Type: Base
Type - Casework - Parametric | File Type: BXF; Parametric | File Name: 01-BaseUK; Dimension | Width: 0.45 m; Dimension | Height: 0.86 m; Dimension | Depth: 0.6 m
Material: A_BSUK_StorageScreening_Ffe
Name | In | Description | ID | Number
04 | k/d/l | 4 ,SHE-03.FIRST.dgn,Design Model:135593 | 04
05 | 05 | 4 ,SHE-03.FIRST.dgn,Design Model:135643 | 05
06 | 06 | 4 ,SHE-03.FIRST.dgn,Design Model:135651 | 06
18 | 18 | 6 ,SHE-05.THIRD.dgn,Design Model:135593 | 18
19 | 19 | 6 ,SHE-05.THIRD.dgn,Design Model:135643 | 19
20 | k/d/l | 6 ,SHE-05.THIRD.dgn,Design Model:135651 | 20
25 | k/d/l | 8 ,SHE-07.FIFTH.dgn,Design Model:158593 | 25
11 | k/d/l | 18 ,SHE-04.SECOND.dgn,Design Model:135593 | 11
12 | k/d/l | 18 ,SHE-04.SECOND.dgn,Design Model:135643 | 12
13 | 13 | 18 ,SHE-04.SECOND.dgn,Design Model:135651 | 13

# IfcFurnishingElement: SHE_A-Kitchenunit-Base60x75, 25
In: 25
Type - Pset_FurnitureTypeCommon - NominalDepth: 0.6 m; NominalHeight: 0.86 m; NominalLength: 0.75 m
Type - Discipline - Discipline: Architectural
Type - Classification - Uniclass2015: Pr_40_30_78
Type - Casework Parameters - Casework | Type: Base
Type - Casework - Parametric | File Type: BXF; Parametric | File Name: 01-BaseUK; Dimension | Width: 0.75 m; Dimension | Height: 0.86 m; Dimension | Depth: 0.6 m
Description: 8 ,SHE-07.FIFTH.dgn,Design Model:158585; Material: A_BSUK_StorageScreening_Ffe
Identification - ID | Number: 25

# IfcFurnishingElement: SHE_A-Kitchenunit-Base60x90, 01
In: 01
Type - Pset_FurnitureTypeCommon - NominalDepth: 0.6 m; NominalHeight: 0.86 m; NominalLength: 0.9 m
Type - Discipline - Discipline: Architectural
Type - Classification - Uniclass2015: Pr_40_30_78
Type - Casework Parameters - Casework | Type: Base
Type - Casework - Parametric | File Type: BXF; Parametric | File Name: 01-BaseUK; Dimension | Width: 0.9 m; Dimension | Height: 0.86 m; Dimension | Depth: 0.6 m
Description: 2 ,SHE-02.MEZZANINE.dgn,Design Model:120963; Material: A_BSUK_StorageScreening_Ffe
Identification - ID | Number: 01

# IfcFurnishingElement: SHE_A-Kitchenunit-Tall (35)
Type - Pset_FurnitureTypeCommon - NominalDepth: 0.6 m; NominalHeight: 2.26 m; NominalLength: 0.6 m
Type - Discipline - Discipline: Architectural
Type - Classification - Uniclass2015: Pr_40_30_78
Type - Casework Parameters - Casework | Type: Tall
Type - Casework - Parametric | File Type: BXF; Parametric | File Name: 01-TallUK; Dimension | Width: 0.6 m; Dimension | Height: 2.26 m; Dimension | Depth: 0.6 m
Material: A_BSUK_StorageScreening_Ffe
Name | In | Description | ID | Number
01 | 01 | 2 ,SHE-02.MEZZANINE.dgn,Design Model:120048 | 01
01 | 01 | 2 ,SHE-02.MEZZANINE.dgn,Design Model:120091 | 01
06 | k/d/l | 4 ,SHE-03.FIRST.dgn,Design Model:134878 | 06
08 | k/d/l | 4 ,SHE-03.FIRST.dgn,Design Model:134967 | 08
02 | 02 | 4 ,SHE-03.FIRST.dgn,Design Model:135002 | 02
02 | k/d/l | 4 ,SHE-03.FIRST.dgn,Design Model:135043 | 02
03 | 03 | 4 ,SHE-03.FIRST.dgn,Design Model:135126 | 03
04 | k/d/l | 4 ,SHE-03.FIRST.dgn,Design Model:135355 | 04
05 | 05 | 4 ,SHE-03.FIRST.dgn,Design Model:135480 | 05
07 | k/d/l | 4 ,SHE-03.FIRST.dgn,Design Model:186405 | 07
20 | k/d/l | 6 ,SHE-05.THIRD.dgn,Design Model:134878 | 20
22 | k/d/l | 6 ,SHE-05.THIRD.dgn,Design Model:134967 | 22
16 | 16 | 6 ,SHE-05.THIRD.dgn,Design Model:135002 | 16
16 | k/d/l | 6 ,SHE-05.THIRD.dgn,Design Model:135043 | 16
17 | studio | 6 ,SHE-05.THIRD.dgn,Design Model:135126 | 17
18 | 18 | 6 ,SHE-05.THIRD.dgn,Design Model:135355 | 18
19 | 19 | 6 ,SHE-05.THIRD.dgn,Design Model:135480 | 19
21 | 21 | 6 ,SHE-05.THIRD.dgn,Design Model:186405 | 21
23 | k/d/l | 8 ,SHE-07.FIFTH.dgn,Design Model:157080 | 23
23 | k/d/l | 8 ,SHE-07.FIFTH.dgn,Design Model:157209 | 23
24 | 24 | 8 ,SHE-07.FIFTH.dgn,Design Model:157279 | 24
24 | 24 | 8 ,SHE-07.FIFTH.dgn,Design Model:157312 | 24
25 | 25 | 8 ,SHE-07.FIFTH.dgn,Design Model:157441 | 25
26 | 26 | 8 ,SHE-07.FIFTH.dgn,Design Model:157584 | 26
26 | 26 | 8 ,SHE-07.FIFTH.dgn,Design Model:157599 | 26
26 | 26 | 8 ,SHE-07.FIFTH.dgn,Design Model:157614 | 26
26 | 26 | 8 ,SHE-07.FIFTH.dgn,Design Model:157629 | 26
13 | 13 | 18 ,SHE-04.SECOND.dgn,Design Model:134878 | 13
15 | k/d/l | 18 ,SHE-04.SECOND.dgn,Design Model:134967 | 15
09 | 09 | 18 ,SHE-04.SECOND.dgn,Design Model:135002 | 09
09 | k/d/l | 18 ,SHE-04.SECOND.dgn,Design Model:135043 | 09
10 | 10 | 18 ,SHE-04.SECOND.dgn,Design Model:135126 | 10
11 | k/d/l | 18 ,SHE-04.SECOND.dgn,Design Model:135355 | 11
12 | k/d/l | 18 ,SHE-04.SECOND.dgn,Design Model:135480 | 12
14 | k/d/l | 18 ,SHE-04.SECOND.dgn,Design Model:186405 | 14

# IfcFurnishingElement: SHE_A-Kitchenunit-Wall (101)
Type - Pset_FurnitureTypeCommon - NominalDepth: 0.37 m; NominalHeight: 0.76 m; NominalLength: 0.6 m
Type - Discipline - Discipline: Architectural
Type - Classification - Uniclass2015: Pr_40_30_78
Type - Casework Parameters - Casework | Type: Wall
Type - Casework - Parametric | File Type: BXF; Parametric | File Name: 01-WallUK; Dimension | Width: 0.6 m; Dimension | Height: 0.76 m; Dimension | Depth: 0.37 m
Casework - Dimension | Width: 0.37 m; Dimension | Depth: 0.6 m
Name | In | Description | ID | Number
01 | k/d/l | 2 ,SHE-02.MEZZANINE.dgn,Design Model:120073 | 01
01 | 01 | 2 ,SHE-02.MEZZANINE.dgn,Design Model:120084 | 01
06 | k/d/l | 4 ,SHE-03.FIRST.dgn,Design Model:134903 | 06
06 | k/d/l | 4 ,SHE-03.FIRST.dgn,Design Model:134911 | 06
06 | k/d/l | 4 ,SHE-03.FIRST.dgn,Design Model:134919 | 06
08 | k/d/l | 4 ,SHE-03.FIRST.dgn,Design Model:134969 | 08
08 | k/d/l | 4 ,SHE-03.FIRST.dgn,Design Model:134980 | 08
08 | k/d/l | 4 ,SHE-03.FIRST.dgn,Design Model:134987 | 08
08 | k/d/l | 4 ,SHE-03.FIRST.dgn,Design Model:134994 | 08
02 | 02 | 4 ,SHE-03.FIRST.dgn,Design Model:135004 | 02
02 | 02 | 4 ,SHE-03.FIRST.dgn,Design Model:135012 | 02
02 | 02 | 4 ,SHE-03.FIRST.dgn,Design Model:135020 | 02
02 | 02 | 4 ,SHE-03.FIRST.dgn,Design Model:135028 | 02
02 | 02 | 4 ,SHE-03.FIRST.dgn,Design Model:135036 | 02
03 | studio | 4 ,SHE-03.FIRST.dgn,Design Model:135089 | 03
03 | studio | 4 ,SHE-03.FIRST.dgn,Design Model:135127 | 03
03 | studio | 4 ,SHE-03.FIRST.dgn,Design Model:135177 | 03
03 | studio | 4 ,SHE-03.FIRST.dgn,Design Model:135270 | 03
04 | 04 | 4 ,SHE-03.FIRST.dgn,Design Model:135277 | 04
04 | 04 | 4 ,SHE-03.FIRST.dgn,Design Model:135356 | 04
04 | k/d/l | 4 ,SHE-03.FIRST.dgn,Design Model:135406 | 04
05 | k/d/l | 4 ,SHE-03.FIRST.dgn,Design Model:135456 | 05
05 | k/d/l | 4 ,SHE-03.FIRST.dgn,Design Model:135464 | 05
05 | k/d/l | 4 ,SHE-03.FIRST.dgn,Design Model:135472 | 05
07 | k/d/l | 4 ,SHE-03.FIRST.dgn,Design Model:186432 | 07
07 | k/d/l | 4 ,SHE-03.FIRST.dgn,Design Model:255109 | 07
07 | k/d/l | 4 ,SHE-03.FIRST.dgn,Design Model:255116 | 07
07 | k/d/l | 4 ,SHE-03.FIRST.dgn,Design Model:272204 | 07
07 | k/d/l | 4 ,SHE-03.FIRST.dgn,Design Model:272233 | 07
07 | k/d/l | 4 ,SHE-03.FIRST.dgn,Design Model:272300 | 07
20 | 20 | 6 ,SHE-05.THIRD.dgn,Design Model:134903 | 20
20 | 20 | 6 ,SHE-05.THIRD.dgn,Design Model:134911 | 20
20 | 20 | 6 ,SHE-05.THIRD.dgn,Design Model:134919 | 20
22 | 22 | 6 ,SHE-05.THIRD.dgn,Design Model:134969 | 22
22 | 22 | 6 ,SHE-05.THIRD.dgn,Design Model:134980 | 22
22 | 22 | 6 ,SHE-05.THIRD.dgn,Design Model:134987 | 22
22 | 22 | 6 ,SHE-05.THIRD.dgn,Design Model:134994 | 22
16 | k/d/l | 6 ,SHE-05.THIRD.dgn,Design Model:135004 | 16
16 | k/d/l | 6 ,SHE-05.THIRD.dgn,Design Model:135012 | 16
16 | k/d/l | 6 ,SHE-05.THIRD.dgn,Design Model:135020 | 16
16 | 16 | 6 ,SHE-05.THIRD.dgn,Design Model:135028 | 16
16 | 16 | 6 ,SHE-05.THIRD.dgn,Design Model:135036 | 16
17 | studio | 6 ,SHE-05.THIRD.dgn,Design Model:135089 | 17
17 | 17 | 6 ,SHE-05.THIRD.dgn,Design Model:135127 | 17
17 | studio | 6 ,SHE-05.THIRD.dgn,Design Model:135177 | 17
17 | studio | 6 ,SHE-05.THIRD.dgn,Design Model:135270 | 17
18 | 18 | 6 ,SHE-05.THIRD.dgn,Design Model:135277 | 18
18 | 18 | 6 ,SHE-05.THIRD.dgn,Design Model:135356 | 18
18 | 18 | 6 ,SHE-05.THIRD.dgn,Design Model:135406 | 18
19 | 19 | 6 ,SHE-05.THIRD.dgn,Design Model:135456 | 19
19 | 19 | 6 ,SHE-05.THIRD.dgn,Design Model:135464 | 19
19 | 19 | 6 ,SHE-05.THIRD.dgn,Design Model:135472 | 19
21 | k/d/l | 6 ,SHE-05.THIRD.dgn,Design Model:186432 | 21
21 | k/d/l | 6 ,SHE-05.THIRD.dgn,Design Model:255109 | 21
21 | k/d/l | 6 ,SHE-05.THIRD.dgn,Design Model:255116 | 21
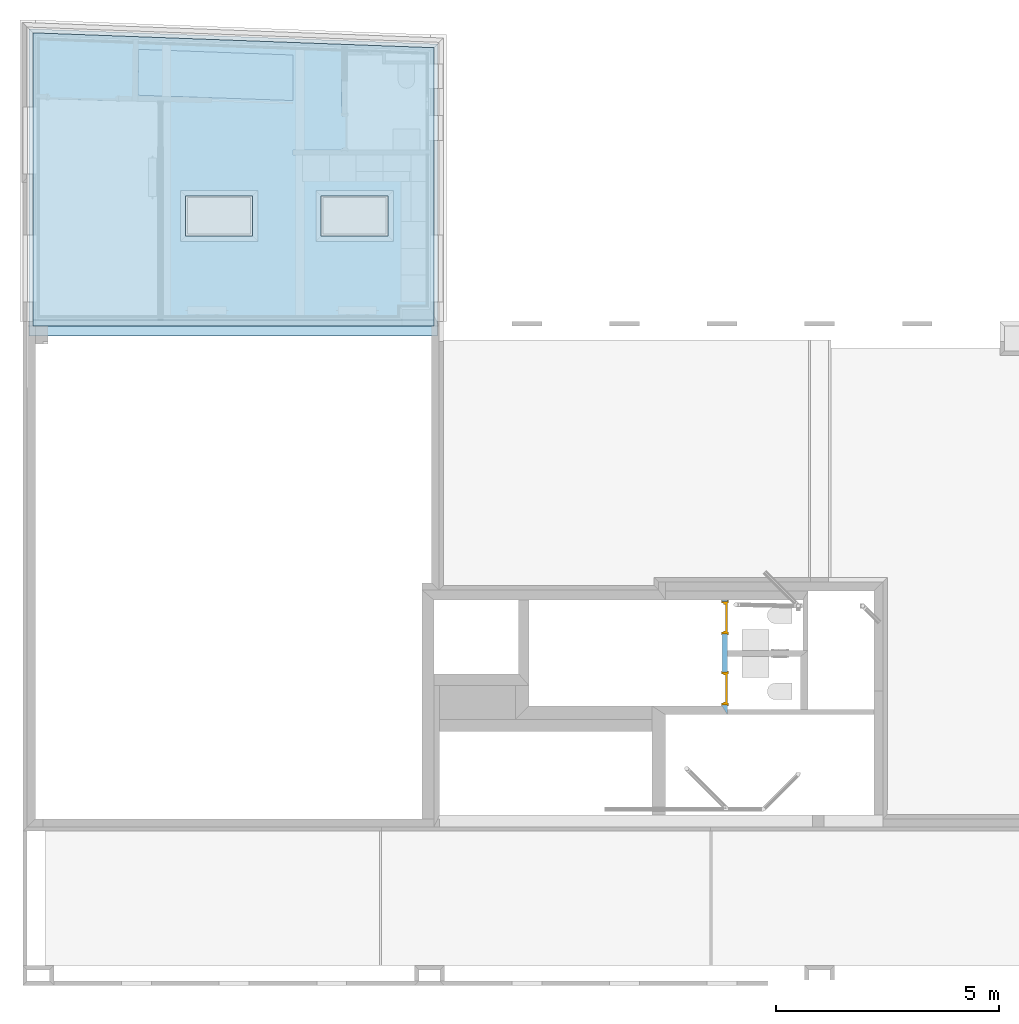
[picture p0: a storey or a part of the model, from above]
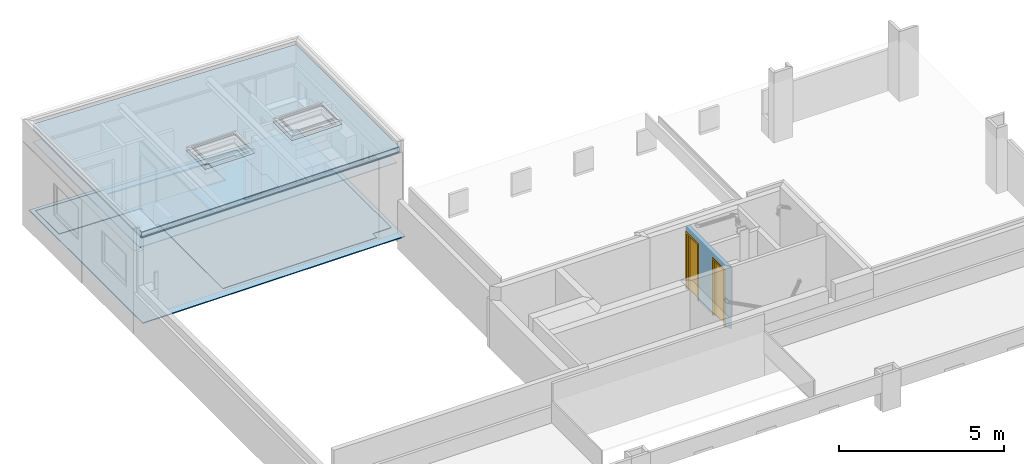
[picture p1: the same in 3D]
Properties of the parts of a building model (IFC2X3), part 8 of 16

# IfcFurnishingElement: SHE_A-Kitchenunit-Wall (101)
Name | In | Description | ID | Number
21 | k/d/l | 6 ,SHE-05.THIRD.dgn,Design Model:272204 | 21
21 | k/d/l | 6 ,SHE-05.THIRD.dgn,Design Model:272233 | 21
21 | k/d/l | 6 ,SHE-05.THIRD.dgn,Design Model:272300 | 21
23 | 23 | 8 ,SHE-07.FIFTH.dgn,Design Model:157081 | 23
23 | 23 | 8 ,SHE-07.FIFTH.dgn,Design Model:157185 | 23
23 | k/d/l | 8 ,SHE-07.FIFTH.dgn,Design Model:157193 | 23
23 | 23 | 8 ,SHE-07.FIFTH.dgn,Design Model:157201 | 23
24 | 24 | 8 ,SHE-07.FIFTH.dgn,Design Model:157280 | 24
24 | 24 | 8 ,SHE-07.FIFTH.dgn,Design Model:157288 | 24
24 | 24 | 8 ,SHE-07.FIFTH.dgn,Design Model:157296 | 24
24 | 24 | 8 ,SHE-07.FIFTH.dgn,Design Model:157304 | 24
25 | k/d/l | 8 ,SHE-07.FIFTH.dgn,Design Model:157398 | 25
25 | k/d/l | 8 ,SHE-07.FIFTH.dgn,Design Model:157442 | 25
26 | k/d/l | 8 ,SHE-07.FIFTH.dgn,Design Model:157630 | 26
26 | k/d/l | 8 ,SHE-07.FIFTH.dgn,Design Model:157638 | 26
26 | k/d/l | 8 ,SHE-07.FIFTH.dgn,Design Model:157646 | 26
26 | 26 | 8 ,SHE-07.FIFTH.dgn,Design Model:157654 | 26
26 | 26 | 8 ,SHE-07.FIFTH.dgn,Design Model:157662 | 26
13 | 13 | 18 ,SHE-04.SECOND.dgn,Design Model:134903 | 13
13 | 13 | 18 ,SHE-04.SECOND.dgn,Design Model:134911 | 13
13 | 13 | 18 ,SHE-04.SECOND.dgn,Design Model:134919 | 13
15 | 15 | 18 ,SHE-04.SECOND.dgn,Design Model:134969 | 15
15 | 15 | 18 ,SHE-04.SECOND.dgn,Design Model:134980 | 15
15 | 15 | 18 ,SHE-04.SECOND.dgn,Design Model:134987 | 15
15 | 15 | 18 ,SHE-04.SECOND.dgn,Design Model:134994 | 15
09 | k/d/l | 18 ,SHE-04.SECOND.dgn,Design Model:135004 | 09
09 | k/d/l | 18 ,SHE-04.SECOND.dgn,Design Model:135012 | 09
09 | k/d/l | 18 ,SHE-04.SECOND.dgn,Design Model:135020 | 09
09 | 09 | 18 ,SHE-04.SECOND.dgn,Design Model:135028 | 09
09 | 09 | 18 ,SHE-04.SECOND.dgn,Design Model:135036 | 09
10 | studio | 18 ,SHE-04.SECOND.dgn,Design Model:135089 | 10
10 | studio | 18 ,SHE-04.SECOND.dgn,Design Model:135127 | 10
10 | studio | 18 ,SHE-04.SECOND.dgn,Design Model:135177 | 10
10 | studio | 18 ,SHE-04.SECOND.dgn,Design Model:135270 | 10
11 | 11 | 18 ,SHE-04.SECOND.dgn,Design Model:135277 | 11
11 | 11 | 18 ,SHE-04.SECOND.dgn,Design Model:135356 | 11
11 | 11 | 18 ,SHE-04.SECOND.dgn,Design Model:135406 | 11
12 | 12 | 18 ,SHE-04.SECOND.dgn,Design Model:135456 | 12
12 | 12 | 18 ,SHE-04.SECOND.dgn,Design Model:135464 | 12
12 | 12 | 18 ,SHE-04.SECOND.dgn,Design Model:135472 | 12
14 | k/d/l | 18 ,SHE-04.SECOND.dgn,Design Model:186432 | 14
14 | k/d/l | 18 ,SHE-04.SECOND.dgn,Design Model:255109 | 14
14 | k/d/l | 18 ,SHE-04.SECOND.dgn,Design Model:255116 | 14
14 | k/d/l | 18 ,SHE-04.SECOND.dgn,Design Model:272204 | 14
14 | k/d/l | 18 ,SHE-04.SECOND.dgn,Design Model:272233 | 14
14 | k/d/l | 18 ,SHE-04.SECOND.dgn,Design Model:272300 | 14

# IfcFurnishingElement: SHE_A-Kitchenunit-Wall37x30 (2)
In: 25
Type - Pset_FurnitureTypeCommon - NominalDepth: 0.37 m; NominalHeight: 0.76 m; NominalLength: 0.3 m
Type - Discipline - Discipline: Architectural
Type - Classification - Uniclass2015: Pr_40_30_78
Type - Casework Parameters - Casework | Type: Wall
Type - Casework - Parametric | File Type: BXF; Parametric | File Name: 01-WallUK; Dimension | Width: 0.3 m; Dimension | Height: 0.76 m; Dimension | Depth: 0.37 m
Identification - ID | Number: 25
Casework - Dimension | Width: 0.37 m
Name | Description
25 | 8 ,SHE-07.FIFTH.dgn,Design Model:158602
25 | 8 ,SHE-07.FIFTH.dgn,Design Model:158609

# IfcFurnishingElement: SHE_A-Kitchenunit-Wall37x45 (10)
Type - Pset_FurnitureTypeCommon - NominalDepth: 0.37 m; NominalHeight: 0.76 m; NominalLength: 0.45 m
Type - Discipline - Discipline: Architectural
Type - Classification - Uniclass2015: Pr_40_30_78
Type - Casework Parameters - Casework | Type: Wall
Type - Casework - Parametric | File Type: BXF; Parametric | File Name: 01-WallUK; Dimension | Width: 0.45 m; Dimension | Height: 0.76 m; Dimension | Depth: 0.37 m
Casework - Dimension | Width: 0.37 m
Name | In | Description | ID | Number
04 | 04 | 4 ,SHE-03.FIRST.dgn,Design Model:135594 | 04
05 | 05 | 4 ,SHE-03.FIRST.dgn,Design Model:135644 | 05
06 | 06 | 4 ,SHE-03.FIRST.dgn,Design Model:135652 | 06
18 | k/d/l | 6 ,SHE-05.THIRD.dgn,Design Model:135594 | 18
19 | 19 | 6 ,SHE-05.THIRD.dgn,Design Model:135644 | 19
20 | 20 | 6 ,SHE-05.THIRD.dgn,Design Model:135652 | 20
25 | 25 | 8 ,SHE-07.FIFTH.dgn,Design Model:158594 | 25
11 | k/d/l | 18 ,SHE-04.SECOND.dgn,Design Model:135594 | 11
12 | 12 | 18 ,SHE-04.SECOND.dgn,Design Model:135644 | 12
13 | 13 | 18 ,SHE-04.SECOND.dgn,Design Model:135652 | 13

# IfcFurnishingElement: SHE_A-Kitchenunit-Wall37x75, 25
In: 25
Type - Pset_FurnitureTypeCommon - NominalDepth: 0.37 m; NominalHeight: 0.76 m; NominalLength: 0.75 m
Type - Discipline - Discipline: Architectural
Type - Classification - Uniclass2015: Pr_40_30_78
Type - Casework Parameters - Casework | Type: Wall
Type - Casework - Parametric | File Type: BXF; Parametric | File Name: 01-WallUK; Dimension | Width: 0.75 m; Dimension | Height: 0.76 m; Dimension | Depth: 0.37 m
Description: 8 ,SHE-07.FIFTH.dgn,Design Model:158586
Identification - ID | Number: 25
Casework - Dimension | Width: 0.37 m

# IfcFurnishingElement: SHE_A-Kitchenunit-Wall37x90 (2)
Type - Pset_FurnitureTypeCommon - NominalDepth: 0.37 m; NominalHeight: 0.76 m; NominalLength: 0.9 m
Type - Discipline - Discipline: Architectural
Type - Classification - Uniclass2015: Pr_40_30_78
Type - Casework Parameters - Casework | Type: Wall
Type - Casework - Parametric | File Type: BXF; Parametric | File Name: 01-WallUK; Dimension | Width: 0.9 m; Dimension | Height: 0.76 m; Dimension | Depth: 0.37 m
Identification - ID | Number: 01
Casework - Dimension | Width: 0.37 m
Name | In | Description
01 | 01 | 2 ,SHE-02.MEZZANINE.dgn,Design Model:120964
01 | k/d/l | 2 ,SHE-02.MEZZANINE.dgn,Design Model:147783

# IfcFurnishingElement: SHE_A-UtilityCupbord (36)
Type - Pset_FurnitureTypeCommon - NominalDepth: 0.05 m; NominalHeight: 2.5 m; NominalLength: 0.7 m
Type - Discipline - Discipline: Architectural
Type - Classification - Uniclass2015: Pr_40_30_78
Type - Casework Parameters - Casework | Type: Tall
Type - Casework - Parametric | File Type: BXF; Parametric | File Name: 01-TallUK; Dimension | Width: 0.7 m; Dimension | Height: 2.5 m; Dimension | Depth: 0.05 m
Name | In | Description | ID | Number | Dimension | Width (m)
06 | k/d/l | 4 ,SHE-03.FIRST.dgn,Design Model:146573 | 06 | 1.5817
03 | studio | 4 ,SHE-03.FIRST.dgn,Design Model:146594 | 03 | 0.7725
04 | k/d/l | 4 ,SHE-03.FIRST.dgn,Design Model:165590 | 04 | 0.85
04 | k/d/l | 4 ,SHE-03.FIRST.dgn,Design Model:165597 | 04 | 0.85
07 | corridor | 4 ,SHE-03.FIRST.dgn,Design Model:189947 | 07 | 0.6
02 | corridor | 4 ,SHE-03.FIRST.dgn,Design Model:243611 | 02 | 0.3525
02 | corridor | 4 ,SHE-03.FIRST.dgn,Design Model:243618 | 02 | 0.3525
03 | 03 | 4 ,SHE-03.FIRST.dgn,Design Model:267279 | 03 | 1.402 | Material: A_BSUK_StorageScreening_Ffe
07 | corridor | 4 ,SHE-03.FIRST.dgn,Design Model:272168 | 07 | 0.6
07 | corridor | 4 ,SHE-03.FIRST.dgn,Design Model:272175 | 07 | 0.6
05 | k/d/l | 4 ,SHE-03.FIRST.dgn,Design Model:302323 | 05 | 0.85
05 | k/d/l | 4 ,SHE-03.FIRST.dgn,Design Model:302330 | 05 | 0.85
20 | k/d/l | 6 ,SHE-05.THIRD.dgn,Design Model:146573 | 20 | 1.5817
17 | studio | 6 ,SHE-05.THIRD.dgn,Design Model:146594 | 17 | 0.7725
18 | k/d/l | 6 ,SHE-05.THIRD.dgn,Design Model:165590 | 18 | 0.85
18 | k/d/l | 6 ,SHE-05.THIRD.dgn,Design Model:165597 | 18 | 0.85
21 | corridor | 6 ,SHE-05.THIRD.dgn,Design Model:189947 | 21 | 0.6
16 | corridor | 6 ,SHE-05.THIRD.dgn,Design Model:243611 | 16 | 0.3525
16 | corridor | 6 ,SHE-05.THIRD.dgn,Design Model:243618 | 16 | 0.3525
17 | storage | 6 ,SHE-05.THIRD.dgn,Design Model:267279 | 17 | 1.402 | Material: A_BSUK_StorageScreening_Ffe
21 | corridor | 6 ,SHE-05.THIRD.dgn,Design Model:272168 | 21 | 0.6
21 | corridor | 6 ,SHE-05.THIRD.dgn,Design Model:272175 | 21 | 0.6
19 | k/d/l | 6 ,SHE-05.THIRD.dgn,Design Model:302323 | 19 | 0.85
19 | k/d/l | 6 ,SHE-05.THIRD.dgn,Design Model:302330 | 19 | 0.85
13 | k/d/l | 18 ,SHE-04.SECOND.dgn,Design Model:146573 | 13 | 1.5817
10 | studio | 18 ,SHE-04.SECOND.dgn,Design Model:146594 | 10 | 0.7725
11 | k/d/l | 18 ,SHE-04.SECOND.dgn,Design Model:165590 | 11 | 0.85
11 | k/d/l | 18 ,SHE-04.SECOND.dgn,Design Model:165597 | 11 | 0.85
14 | corridor | 18 ,SHE-04.SECOND.dgn,Design Model:189947 | 14 | 0.6
09 | corridor | 18 ,SHE-04.SECOND.dgn,Design Model:243611 | 09 | 0.3525
09 | corridor | 18 ,SHE-04.SECOND.dgn,Design Model:243618 | 09 | 0.3525
10 | 10 | 18 ,SHE-04.SECOND.dgn,Design Model:267279 | 10 | 1.402 | Material: A_BSUK_StorageScreening_Ffe
14 | corridor | 18 ,SHE-04.SECOND.dgn,Design Model:272168 | 14 | 0.6
14 | corridor | 18 ,SHE-04.SECOND.dgn,Design Model:272175 | 14 | 0.6
12 | k/d/l | 18 ,SHE-04.SECOND.dgn,Design Model:302323 | 12 | 0.85
12 | k/d/l | 18 ,SHE-04.SECOND.dgn,Design Model:302330 | 12 | 0.85

# IfcFurnishingElement: SHE_A-Wardrobe_hall 40x90 (15)
Type - Pset_FurnitureTypeCommon - NominalDepth: 0.4 m; NominalHeight: 2.1 m; NominalLength: 0.9 m
Type - Discipline - Discipline: Architectural
Type - Classification - Uniclass2015: Pr_40_30_78
Type - Casework Parameters - Casework | Type: Tall
Type - Casework - Parametric | File Type: BXF; Parametric | File Name: 01-TallUK; Dimension | Width: 0.9 m; Dimension | Height: 2.1 m; Dimension | Depth: 0.4 m
Casework - Dimension | Width: 0.6 m
Name | In | Description | ID | Number
06 | 06 | 4 ,SHE-03.FIRST.dgn,Design Model:134933 | 06
03 | 03 | 4 ,SHE-03.FIRST.dgn,Design Model:279673 | 03
08 | 08 | 4 ,SHE-03.FIRST.dgn,Design Model:282336 | 08
05 | 05 | 4 ,SHE-03.FIRST.dgn,Design Model:282519 | 05
04 | k/d/l | 4 ,SHE-03.FIRST.dgn,Design Model:282526 | 04
20 | k/d/l | 6 ,SHE-05.THIRD.dgn,Design Model:134933 | 20
17 | studio | 6 ,SHE-05.THIRD.dgn,Design Model:279673 | 17
22 | corridor | 6 ,SHE-05.THIRD.dgn,Design Model:282336 | 22
19 | 19 | 6 ,SHE-05.THIRD.dgn,Design Model:282519 | 19
18 | 18 | 6 ,SHE-05.THIRD.dgn,Design Model:282526 | 18
13 | 13 | 18 ,SHE-04.SECOND.dgn,Design Model:134933 | 13
10 | 10 | 18 ,SHE-04.SECOND.dgn,Design Model:279673 | 10
15 | 15 | 18 ,SHE-04.SECOND.dgn,Design Model:282336 | 15
12 | k/d/l | 18 ,SHE-04.SECOND.dgn,Design Model:282519 | 12
11 | k/d/l | 18 ,SHE-04.SECOND.dgn,Design Model:282526 | 11

# IfcGrid, OrthogonalGrid
In: Building01
Description: Grid Template\Default, Orthogonal

# IfcMember: A-Baseplate (42)
In: GF
Type - PredefinedType: PLATE
Type - Parametric Definition - Parametric | File Type: PAZ; Parametric | File Name: BasePlate_NoGrout_Architectural
Type - Discipline - Discipline: Architectural
Type - Classification - Uniclass2015: Pr_20_29_03_13
Type - Base Plate | Steel - Plate | Thickness: 0.025 m; Plate | Length: 0.3 m; Plate | Width: 0.3 m; Grout | Thickness: 0 m; Grout | Angle: n/a
Material: A_BSUK_BasePlates
Identification - ID | Type ID: Solar panel
Construction Phase - Phase: New Construction
Base Plate | Steel - Bottom Elevation: 0 m; Plate | Thickness: 0.05 m; Plate | Length: 1 m; Plate | Width: 1.7 m
Name | Description
Solar panel | 11 ,SHE-15.MEHP.dgn,Design Model:263505
Solar panel | 11 ,SHE-15.MEHP.dgn,Design Model:263564
Solar panel | 11 ,SHE-15.MEHP.dgn,Design Model:263623
Solar panel | 11 ,SHE-15.MEHP.dgn,Design Model:263682
Solar panel | 11 ,SHE-15.MEHP.dgn,Design Model:263741
Solar panel | 11 ,SHE-15.MEHP.dgn,Design Model:263800
Solar panel | 11 ,SHE-15.MEHP.dgn,Design Model:263859
Solar panel | 11 ,SHE-15.MEHP.dgn,Design Model:263918
Solar panel | 11 ,SHE-15.MEHP.dgn,Design Model:263977
Solar panel | 11 ,SHE-15.MEHP.dgn,Design Model:264036
Solar panel | 11 ,SHE-15.MEHP.dgn,Design Model:264095
Solar panel | 11 ,SHE-15.MEHP.dgn,Design Model:264154
Solar panel | 11 ,SHE-15.MEHP.dgn,Design Model:264213
Solar panel | 11 ,SHE-15.MEHP.dgn,Design Model:264272
Solar panel | 11 ,SHE-15.MEHP.dgn,Design Model:264331
Solar panel | 11 ,SHE-15.MEHP.dgn,Design Model:264390
Solar panel | 11 ,SHE-15.MEHP.dgn,Design Model:264449
Solar panel | 11 ,SHE-15.MEHP.dgn,Design Model:264508
Solar panel | 11 ,SHE-15.MEHP.dgn,Design Model:264862
Solar panel | 11 ,SHE-15.MEHP.dgn,Design Model:264921
Solar panel | 11 ,SHE-15.MEHP.dgn,Design Model:264980
Solar panel | 11 ,SHE-15.MEHP.dgn,Design Model:265039
Solar panel | 11 ,SHE-15.MEHP.dgn,Design Model:265098
Solar panel | 11 ,SHE-15.MEHP.dgn,Design Model:265157
Solar panel | 11 ,SHE-15.MEHP.dgn,Design Model:265216
Solar panel | 11 ,SHE-15.MEHP.dgn,Design Model:265275
Solar panel | 11 ,SHE-15.MEHP.dgn,Design Model:265334
Solar panel | 11 ,SHE-15.MEHP.dgn,Design Model:265393
Solar panel | 11 ,SHE-15.MEHP.dgn,Design Model:265452
Solar panel | 11 ,SHE-15.MEHP.dgn,Design Model:265511
Solar panel | 11 ,SHE-15.MEHP.dgn,Design Model:265570
Solar panel | 11 ,SHE-15.MEHP.dgn,Design Model:265629
Solar panel | 11 ,SHE-15.MEHP.dgn,Design Model:265688
Solar panel | 11 ,SHE-15.MEHP.dgn,Design Model:265747
Solar panel | 11 ,SHE-15.MEHP.dgn,Design Model:265806
Solar panel | 11 ,SHE-15.MEHP.dgn,Design Model:265865
Solar panel | 11 ,SHE-15.MEHP.dgn,Design Model:294804
Solar panel | 11 ,SHE-15.MEHP.dgn,Design Model:294863
Solar panel | 11 ,SHE-15.MEHP.dgn,Design Model:294922
Solar panel | 11 ,SHE-15.MEHP.dgn,Design Model:294981
Solar panel | 11 ,SHE-15.MEHP.dgn,Design Model:295040
Solar panel | 11 ,SHE-15.MEHP.dgn,Design Model:295099

# IfcMember: A-FrameElements:A_BSUK_Steel_Miscellaneous (5)
In: GF
Material: A_BSUK_Steel_Miscellaneous
Name | Description
A-FrameElements--A_BSUK_Steel_Miscellaneous | 1,SHE-01.GROUND.dgn ,Design Model:148739
A-FrameElements--A_BSUK_Steel_Miscellaneous | 1,SHE-01.GROUND.dgn ,Design Model:148741
A-FrameElements--A_BSUK_Steel_Miscellaneous | 1,SHE-01.GROUND.dgn ,Design Model:148742
A-FrameElements--A_BSUK_Steel_Miscellaneous | 1,SHE-01.GROUND.dgn ,Design Model:148743
A-FrameElements--A_BSUK_Steel_Miscellaneous | 1,SHE-01.GROUND.dgn ,Design Model:148744

# IfcRailing: A-Handrail-900mm (6)
In: GF
Type - Railing Quantities - Start Post | Count: 0; Corner Post | Count: 0; End Post | Count: 0; Intermediate Post | Count: 0; Mounting Bracket | Count: 0; Balusters 1 | Count: 0; Balusters 2 | Count: 0; Balusters 3 | Count: 0
Type - Railing Parameters - Part Definition: A-FrameElements::A_BSUK_Steel_Miscellaneous; Generate Drawing Symbols: no; Rail 1 | Name: Handrail; Rail 1 | Height: 0.9 m; Rail 1 | Profile Type: Structural Section; Rail 1 | Profile: CHS76.1X5; Rail 1 | Side Offset: 0.1 m; Rail 1 | Part Definition: A-FrameElements::A_BSUK_Steel_Miscellaneous; Rail 1 | Join Method: Vertical; Rail 2 | Name: Middle; Rail 2 | Height: 0.8 m; Rail 2 | Profile Type: <none>; Rail 2 | Profile: CHS42.4X3.2; Rail 2 | Side Offset: 0 m; Rail 2 | Part Definition: A-FrameElements::A_BSUK_Steel_Miscellaneous; Rail 2 | Join Method: Vertical; Rail 3 | Name: Bottom; Rail 3 | Height: 0.15 m; Rail 3 | Profile Type: <none>; Rail 3 | Profile: CHS42.4X3.2; Rail 3 | Side Offset: 0 m; Rail 3 | Part definition: A-FrameElements::A_BSUK_Steel_Miscellaneous; Rail 3 | Join Method: Vertical; Rail 4 | Name: Lower; Rail 4 | Height: 0.1 m; Rail 4 | Profile Type: <none>; Rail 4 | Profile: CHS42.4X3.2; Rail 4 | Side Offset: 0.1 m; Rail 4 | Join Method: Vertical; Rail 5 | Profile Type: <none>; Rail 5 | Height: 0 m; Rail 5 | Side Offset: 0 m; Rail 5 | Join Method: Vertical; Rail 6 | Profile Type: <none>; Rail 6 | Height: 0 m; Rail 6 | Side Offset: 0 m; Rail 6 | Join Method: Vertical; Start Post | Name: Start Post; Start Post | Spacing: 0 m; Start Post | Profile Type: <none>; Start Post | Profile: SHS40x40x3.0; Start Post | Height: 0.001 m; Start Post | Base Offset: 0 m; Start Post | Side Offset: 0 m; Start Post | Part Definition: A-FrameElements::A_BSUK_Steel_Miscellaneous; Corner Post | Name: Corner Post; Corner Post | Spacing: 0 m; Corner Post | Profile Type: <none>; Corner Post | Profile: SHS40x40x3.0; Corner Post | Height: 0.86 m; Corner Post | Base Offset: 0 m; Corner Post | Side Offset: 0 m; Corner Post | Part Definition: A-FrameElements::A_BSUK_Steel_Miscellaneous; End Post | Name: End Post; End Post | Spacing: 0 m; End Post | Profile Type: <none>; End Post | Profile: SHS40x40x3.0; End Post | Height: 0.86 m; End Post | Base Offset: 0 m; End Post | Side Offset: 0 m; End Post | Part Definition: A-FrameElements::A_BSUK_Steel_Miscellaneous; Intermediate Post 1 | Name: Intermediate Post; Intermediate Post 1 | Spacing: 1.2 m; Intermediate Post 1 | Profile Type: <none>; Intermediate Post 1 | Profile: SHS40x40x3.0; Intermediate Post1 | Height: 0.86 m; Intermediate Post1 | Base Offset: 0 m; Intermediate Post1 | Side Offset: 0 m; Intermediate Post 1 | Spacing Type: Max Spacing; Mounting Bracket | Spacing: 0 m; Mounting Bracket | Profile Type: <none>; Mounting Bracket | Height: 0 m; Mounting Bracket | Base Offset: 0 m; Mounting Bracket | Side Offset: 0 m; Mounting Bracket | Spacing Type: Max Spacing; Balusters 1 | Name: Pickets; Balusters 1 | Spacing: 0.1 m; Balusters 1 | Spacing Type: Max Spacing; Balusters 1 | Profile Type: <none>; Balusters 1 | Profile: CHS26.9x3.2; Balusters 1 | Height: 0.78 m; Balusters 1 | Base Offset: 0.15 m; Balusters 1 | Side Offset: 0 m; Balusters 1 | Part Definition: A-FrameElements::A_BSUK_Steel_Miscellaneous; Balusters 2 | Spacing: 0.1 m; Balusters 2 | Spacing Type: Max Spacing; Balusters 2 | Profile Type: <none>; Balusters 2 | Profile: CHS26.9x3.2; Balusters 2 | Height: 0.75 m; Balusters 2 | Base Offset: 0 m; Balusters 2 | Side Offset: 0 m; Balusters 2 | Part Definition: A-FrameElements::A_BSUK_Steel_Miscellaneous; Balusters 3 | Spacing: 0.425 m; Balusters 3 | Spacing Type: Max Spacing; Balusters 3 | Profile Type: <none>; Balusters 3 | Profile: CHS26.9x3.2; Balusters 3 | Height: 0.75 m; Balusters 3 | Base Offset: 0 m; Balusters 3 | Side Offset: 0 m; Balusters 3 | Part Definition: A-FrameElements::A_BSUK_Steel_Miscellaneous; Railing End | Start Name: Start; Railing End | Start Top Offset: 0 m; Railing End | Start Side Offset: 0.1 m; Railing End | End Name: End; Railing Ends | End Top Offset: 0 m; Railing End | End Side Offset: 0.1 m
Type - Classification - Uniclass2015: Ss_25_15_60_66
PredefinedType: HANDRAIL; Material: A_BSUK_Steel_Miscellaneous
Railing Quantities - Rail 2 | Length: 0 m; Rail 3 | Length: 0 m; Rail 4 | Length: 0 m; Rail 5 | Length: 0 m; Rail 6 | Length: 0 m; Start Post | Length: 0 m; Start Post | Total Length: 0 m; Corner Post | Length: 0 m; Corner Post | Total Length: 0 m; End Post | Length: 0 m; End Post | Total Length: 0 m; Intermediate Post | Length: 0 m; Intermediate Post | Total Length: 0 m; Mounting Bracket | Length: 0 m; Mounting Bracket | Total Length: 0 m; Balusters 1 | Length: 0 m; Balusters 1 | Total Length: 0 m; Balusters 2 | Length: 0 m; Balusters 2 | Total Length: 0 m; Balusters 3 | Length: 0 m; Balusters 3 | Total Length: 0 m
Railing Parameters - Rail 1 | Profile Type: ProStructures Shape; Balusters 1 | Thickness: 0 m; Balusters 2 | Thickness: 0 m; Balusters 3 | Thickness: 0 m
Name | Description | Rail 1 | Length (m) | Rail 1 | Profile | Rail 1 | Side Offset (m)
A-Handrail-900mm | 1 ,SHE-01.GROUND.dgn,Design Model:156478 | 1.7989 | 1\ANSI_PIPE\15NBX3.73WT_PIPE | 0
A-Handrail-900mm | 1 ,SHE-01.GROUND.dgn,Design Model:156544 | 1.13322 | 1\ANSI_PIPE\15NBX3.73WT_PIPE | 0
A-Handrail-900mm | 16 ,SHE-12.STAIR.dgn,Design Model:223116 | 6.23703 | 1\AS_SHS_C450\40X4.0SHS | 0
A-Handrail-900mm | 16 ,SHE-12.STAIR.dgn,Design Model:223387 | 6.37497 | 1\AS_SHS_C450\40X4.0SHS | 0
A-Handrail-900mm | 16 ,SHE-12.STAIR.dgn,Design Model:223924 | 6.20102 | 1\AS_SHS_C450\40X4.0SHS | 0.001
A-Handrail-900mm | 16 ,SHE-12.STAIR.dgn,Design Model:224304 | 4.98098 | 1\AS_SHS_C450\40X4.0SHS | 0

# IfcRailing: A-RailingGlassPanel-1050mm (25)
Type - Railing Parameters - Part Definition: A-FrameElements::A_BSUK_Steel_Miscellaneous; Generate Drawing Symbols: no; Rail 1 | Name: Top; Rail 1 | Height: 1.05 m; Rail 1 | Profile Type: Profile; Rail 1 | Profile: Round Cap; Rail 1 | Side Offset: 0 m; Rail 1 | Part Definition: A-Finishes::A_BSUK_ChromeRailingSystems; Rail 1 | Join Method: Vertical; Rail 2 | Name: Bottom; Rail 2 | Height: 0 m; Rail 2 | Profile Type: Profile; Rail 2 | Profile: Shoe 65x100; Rail 2 | Side Offset: 0 m; Rail 2 | Part Definition: A-Finishes::A_BSUK_ChromeRailingSystems; Rail 2 | Join Method: <none>; Rail 3 | Name: Bottom; Rail 3 | Height: 0.15 m; Rail 3 | Profile Type: <none>; Rail 3 | Profile: CHS42.4X3.2; Rail 3 | Side Offset: 0 m; Rail 3 | Part definition: A-FrameElements::A_BSUK_Steel_Miscellaneous; Rail 3 | Join Method: Vertical; Rail 4 | Name: Lower; Rail 4 | Height: 0.1 m; Rail 4 | Profile Type: <none>; Rail 4 | Profile: CHS42.4X3.2; Rail 4 | Side Offset: 0.1 m; Rail 4 | Join Method: Vertical; Rail 5 | Profile Type: <none>; Rail 5 | Height: 0 m; Rail 5 | Side Offset: 0 m; Rail 5 | Join Method: Vertical; Rail 6 | Profile Type: <none>; Rail 6 | Height: 0 m; Rail 6 | Side Offset: 0 m; Rail 6 | Join Method: Vertical; Start Post | Name: Start Post; Start Post | Spacing: 0 m; Start Post | Profile Type: Cell; Start Post | Profile: Gap; Start Post | Height: 1.05 m; Start Post | Base Offset: 0 m; Start Post | Side Offset: 0 m; Start Post | Part Definition: A-FrameElements::A_BSUK_Steel_Miscellaneous; Corner Post | Name: Corner Post; Corner Post | Spacing: 0 m; Corner Post | Profile Type: Cell; Corner Post | Profile: Gap; Corner Post | Height: 1.02 m; Corner Post | Base Offset: 0 m; Corner Post | Side Offset: 0 m; Corner Post | Part Definition: A-FrameElements::A_BSUK_Steel_Miscellaneous; End Post | Name: End Post; End Post | Spacing: 0 m; End Post | Profile Type: Cell; End Post | Profile: Gap; End Post | Height: 1.05 m; End Post | Base Offset: 0 m; End Post | Side Offset: 0 m; End Post | Part Definition: A-FrameElements::A_BSUK_Steel_Miscellaneous; Intermediate Post 1 | Name: Intermediate; Intermediate Post 1 | Spacing: 1.5 m; Intermediate Post 1 | Profile Type: Cell; Intermediate Post 1 | Profile: Gap; Intermediate Post1 | Height: 1.03 m; Intermediate Post1 | Base Offset: 0 m; Intermediate Post1 | Side Offset: 0 m; Intermediate Post 1 | Part Definition: A-Finishes::A_BSUK_ChromeRailingSystems; Intermediate Post 1 | Spacing Type: Max Spacing; Mounting Bracket | Spacing: 0 m; Mounting Bracket | Profile Type: <none>; Mounting Bracket | Height: 0 m; Mounting Bracket | Base Offset: 0 m; Mounting Bracket | Side Offset: 0 m; Balusters 1 | Name: Baluster 1; Balusters 1 | Spacing: 0 m; Balusters 1 | Spacing Type: Max Spacing; Balusters 1 | Profile Type: Parametric Panel; Balusters 1 | Profile: Panel Glass; Balusters 1 | Height: 1.025 m; Balusters 1 | Base Offset: 0.05 m; Balusters 1 | Side Offset: 0 m; Balusters 1 | Thickness: 0.01 m; Balusters 1 | Part Definition: A-Finishes::A_BSUK_GlassPanelRailingSystems; Balusters 2 | Spacing: 0.1 m; Balusters 2 | Spacing Type: Max Spacing; Balusters 2 | Profile Type: <none>; Balusters 2 | Profile: CHS26.9x3.2; Balusters 2 | Height: 0.75 m; Balusters 2 | Base Offset: 0 m; Balusters 2 | Side Offset: 0 m; Balusters 2 | Thickness: 0 m; Balusters 2 | Part Definition: A-FrameElements::A_BSUK_Steel_Miscellaneous; Balusters 3 | Spacing: 0.425 m; Balusters 3 | Spacing Type: Max Spacing; Balusters 3 | Profile Type: <none>; Balusters 3 | Profile: CHS26.9x3.2; Balusters 3 | Height: 0.75 m; Balusters 3 | Base Offset: 0 m; Balusters 3 | Side Offset: 0 m; Balusters 3 | Thickness: 0 m; Balusters 3 | Part Definition: A-FrameElements::A_BSUK_Steel_Miscellaneous; Railing End | Start Name: Start; Railing End | Start Top Offset: 0 m; Railing End | Start Side Offset: 0.1 m; Railing End | End Name: End; Railing Ends | End Top Offset: 0 m; Railing End | End Side Offset: 0.1 m
Type - Classification - Uniclass2015: Ss_25_15_60_66
PredefinedType: HANDRAIL; Material: A_BSUK_Steel_Miscellaneous
Railing Quantities - Rail 3 | Length: 0 m; Rail 4 | Length: 0 m; Rail 5 | Length: 0 m; Rail 6 | Length: 0 m; Start Post | Count: 1; Start Post | Length: 1.2 m; Start Post | Total Length: 1.2 m; End Post | Count: 1; End Post | Length: 1.2 m; End Post | Total Length: 1.2 m; Mounting Bracket | Count: 0; Mounting Bracket | Length: 0 m; Mounting Bracket | Total Length: 0 m; Balusters 1 | Length: 0 m; Balusters 1 | Total Length: 0 m; Balusters 2 | Count: 0; Balusters 2 | Length: 0 m; Balusters 2 | Total Length: 0 m; Balusters 3 | Count: 0; Balusters 3 | Length: 0 m; Balusters 3 | Total Length: 0 m
Name | In | Description | Rail 1 | Length (m) | Rail 2 | Length (m) | Corner Post | Count | Corner Post | Length (m) | Corner Post | Total Length (m) | Intermediate Post | Count | Intermediate Post | Length (m) | Intermediate Post | Total Length (m) | Balusters 1 | Count | Phase
A-RailingGlassPanel-1050mm | MF | 2,SHE-02.MEZZANINE.dgn,Design Model:204526 | 1.82104 | 1.82104 | 0 | 0 | 0 | 1 | 1.2 | 1.2 | 2 | Railing Parameters - Rail 1 | Height: 0.855 m; Rail 1 | Profile: Square 45x45mm; Rail 2 | Profile: Square 45x45mm; Balusters 1 | Height: 0.85 m
A-RailingGlassPanel-1050mm | 5F | 8,SHE-07.FIFTH.dgn,Design Model:331689 | 5.50502 | 5.42594 | 3 | 1.2 | 3.6 | 2 | 1.2 | 2.4 | 6 | Railing Parameters - Rail 1 | Height: 0.855 m; Rail 1 | Profile: Square 45x45mm; Rail 2 | Profile: Square 45x45mm; Balusters 1 | Height: 0.85 m
A-RailingGlassPanel-1050mm | 5F | 8,SHE-07.FIFTH.dgn,Design Model:332696 | 2.42085 | 2.42085 | 0 | 0 | 0 | 1 | 1.2 | 1.2 | 2 | Railing Parameters - Rail 1 | Height: 0.855 m; Rail 1 | Profile: Square 45x45mm; Rail 2 | Profile: Square 45x45mm; Balusters 1 | Height: 0.85 m
A-RailingGlassPanel-1050mm | 5F | 8,SHE-07.FIFTH.dgn,Design Model:332857 | 1.21662 | 1.21662 | 0 | 0 | 0 | 0 | 0 | 0 | 1 | Railing Parameters - Rail 1 | Height: 0.855 m; Rail 1 | Profile: Square 45x45mm; Rail 2 | Profile: Square 45x45mm; Balusters 1 | Height: 0.85 m
A-RailingGlassPanel-1050mm | 5F | 8,SHE-07.FIFTH.dgn,Design Model:333239 | 5.89924 | 5.82016 | 3 | 1.2 | 3.6 | 2 | 1.2 | 2.4 | 6 | Railing Parameters - Rail 1 | Height: 0.855 m; Rail 1 | Profile: Square 45x45mm; Rail 2 | Profile: Square 45x45mm; Balusters 1 | Height: 0.85 m
A-RailingGlassPanel-1050mm | 5F | 8,SHE-07.FIFTH.dgn,Design Model:334241 | 5.56748 | 5.48839 | 3 | 1.2 | 3.6 | 2 | 1.2 | 2.4 | 6 | Railing Parameters - Rail 1 | Height: 0.855 m; Rail 1 | Profile: Square 45x45mm; Rail 2 | Profile: Square 45x45mm; Balusters 1 | Height: 0.85 m
A-RailingGlassPanel-1050mm | GF | 15,SHE-14.BALCONY.dgn,Design Model:174469 | 2.7366 | 2.7366 | 0 | 0 | 0 | 0 | 0 | 0 | 1 | New Construction
A-RailingGlassPanel-1050mm | GF | 15,SHE-14.BALCONY.dgn,Design Model:174632 | 1.0182 | 1.0182 | 0 | 0 | 0 | 0 | 0 | 0 | 1 | New Construction
A-RailingGlassPanel-1050mm | GF | 15,SHE-14.BALCONY.dgn,Design Model:174789 | 2.3998 | 2.3998 | 0 | 0 | 0 | 0 | 0 | 0 | 1 | New Construction
A-RailingGlassPanel-1050mm | GF | 15,SHE-14.BALCONY.dgn,Design Model:174944 | 1.3798 | 1.3798 | 0 | 0 | 0 | 0 | 0 | 0 | 1 | New Construction
A-RailingGlassPanel-1050mm | GF | 15,SHE-14.BALCONY.dgn,Design Model:175104 | 2.7366 | 2.7366 | 0 | 0 | 0 | 0 | 0 | 0 | 1 | New Construction
A-RailingGlassPanel-1050mm | GF | 15,SHE-14.BALCONY.dgn,Design Model:175267 | 1.01038 | 1.01038 | 0 | 0 | 0 | 0 | 0 | 0 | 1 | New Construction
A-RailingGlassPanel-1050mm | GF | 15,SHE-14.BALCONY.dgn,Design Model:175593 | 2.7366 | 2.7366 | 0 | 0 | 0 | 0 | 0 | 0 | 1 | New Construction
A-RailingGlassPanel-1050mm | GF | 15,SHE-14.BALCONY.dgn,Design Model:175756 | 1.0182 | 1.0182 | 0 | 0 | 0 | 0 | 0 | 0 | 1 | New Construction
A-RailingGlassPanel-1050mm | GF | 15,SHE-14.BALCONY.dgn,Design Model:175913 | 2.3998 | 2.3998 | 0 | 0 | 0 | 0 | 0 | 0 | 1 | New Construction
A-RailingGlassPanel-1050mm | GF | 15,SHE-14.BALCONY.dgn,Design Model:176068 | 1.3798 | 1.3798 | 0 | 0 | 0 | 0 | 0 | 0 | 1 | New Construction
A-RailingGlassPanel-1050mm | GF | 15,SHE-14.BALCONY.dgn,Design Model:176228 | 2.7366 | 2.7366 | 0 | 0 | 0 | 0 | 0 | 0 | 1 | New Construction
A-RailingGlassPanel-1050mm | GF | 15,SHE-14.BALCONY.dgn,Design Model:176391 | 1.01038 | 1.01038 | 0 | 0 | 0 | 0 | 0 | 0 | 1 | New Construction
A-RailingGlassPanel-1050mm | GF | 15,SHE-14.BALCONY.dgn,Design Model:176718 | 1.01038 | 1.01038 | 0 | 0 | 0 | 0 | 0 | 0 | 1 | New Construction
A-RailingGlassPanel-1050mm | GF | 15,SHE-14.BALCONY.dgn,Design Model:176881 | 1.01038 | 1.01038 | 0 | 0 | 0 | 0 | 0 | 0 | 1 | New Construction
A-RailingGlassPanel-1050mm | GF | 15,SHE-14.BALCONY.dgn,Design Model:177356 | 2.3998 | 2.3998 | 0 | 0 | 0 | 0 | 0 | 0 | 1 | New Construction
A-RailingGlassPanel-1050mm | GF | 15,SHE-14.BALCONY.dgn,Design Model:177511 | 1.0182 | 1.0182 | 0 | 0 | 0 | 0 | 0 | 0 | 1 | New Construction
A-RailingGlassPanel-1050mm | GF | 15,SHE-14.BALCONY.dgn,Design Model:177668 | 2.3998 | 2.3998 | 0 | 0 | 0 | 0 | 0 | 0 | 1 | New Construction
A-RailingGlassPanel-1050mm | GF | 15,SHE-14.BALCONY.dgn,Design Model:177823 | 1.0182 | 1.0182 | 0 | 0 | 0 | 0 | 0 | 0 | 1 | New Construction
A-RailingGlassPanel-1050mm | GF | 15,SHE-14.BALCONY.dgn,Design Model:178589 | 17.6468 | 17.4945 | 4 | 1.2 | 4.8 | 8 | 1.2 | 9.60001 | 13

# IfcRailing: S-Handrail-900mm (9)
Type - Railing Quantities - Start Post | Count: 0; Corner Post | Count: 0; End Post | Count: 0; Intermediate Post | Count: 0; Mounting Bracket | Count: 0; Balusters 1 | Count: 0; Balusters 2 | Count: 0; Balusters 3 | Count: 0
Type - Railing Parameters - Part Definition: A-FrameElements::A_BSUK_Steel_Miscellaneous; Generate Drawing Symbols: no; Rail 1 | Name: Handrail; Rail 1 | Height: 0.9 m; Rail 1 | Profile Type: Structural Section; Rail 1 | Profile: CHS76.1X5; Rail 1 | Side Offset: 0.1 m; Rail 1 | Part Definition: S-FrameElements::S_BSUK_Steel_Miscellaneous; Rail 1 | Join Method: Vertical; Rail 2 | Name: Middle; Rail 2 | Height: 0.8 m; Rail 2 | Profile Type: <none>; Rail 2 | Profile: CHS42.4X3.2; Rail 2 | Side Offset: 0 m; Rail 2 | Part Definition: S-FrameElements::S_BSUK_Steel_Miscellaneous; Rail 2 | Join Method: Vertical; Rail 3 | Name: Bottom; Rail 3 | Height: 0.15 m; Rail 3 | Profile Type: <none>; Rail 3 | Profile: CHS42.4X3.2; Rail 3 | Side Offset: 0 m; Rail 3 | Part definition: S-FrameElements::S_BSUK_Steel_Miscellaneous; Rail 3 | Join Method: Vertical; Rail 4 | Name: Lower; Rail 4 | Height: 0.1 m; Rail 4 | Profile Type: <none>; Rail 4 | Profile: CHS42.4X3.2; Rail 4 | Side Offset: 0.1 m; Rail 4 | Join Method: Vertical; Rail 5 | Profile Type: <none>; Rail 5 | Height: 0 m; Rail 5 | Side Offset: 0 m; Rail 5 | Join Method: Vertical; Rail 6 | Profile Type: <none>; Rail 6 | Height: 0 m; Rail 6 | Side Offset: 0 m; Rail 6 | Join Method: Vertical; Start Post | Name: Start Post; Start Post | Spacing: 0 m; Start Post | Profile Type: <none>; Start Post | Profile: SHS40x40x3.0; Start Post | Height: 0.001 m; Start Post | Base Offset: 0 m; Start Post | Side Offset: 0 m; Start Post | Part Definition: S-FrameElements::S_BSUK_Steel_Miscellaneous; Corner Post | Name: Corner Post; Corner Post | Spacing: 0 m; Corner Post | Profile Type: <none>; Corner Post | Profile: SHS40x40x3.0; Corner Post | Height: 0.86 m; Corner Post | Base Offset: 0 m; Corner Post | Side Offset: 0 m; Corner Post | Part Definition: S-FrameElements::S_BSUK_Steel_Miscellaneous; End Post | Name: End Post; End Post | Spacing: 0 m; End Post | Profile Type: <none>; End Post | Profile: SHS40x40x3.0; End Post | Height: 0.86 m; End Post | Base Offset: 0 m; End Post | Side Offset: 0 m; End Post | Part Definition: S-FrameElements::S_BSUK_Steel_Miscellaneous; Intermediate Post 1 | Name: Intermediate Post; Intermediate Post 1 | Spacing: 1.2 m; Intermediate Post 1 | Profile Type: <none>; Intermediate Post 1 | Profile: SHS40x40x3.0; Intermediate Post1 | Height: 0.86 m; Intermediate Post1 | Base Offset: 0 m; Intermediate Post1 | Side Offset: 0 m; Intermediate Post 1 | Spacing Type: Max Spacing; Mounting Bracket | Spacing: 0 m; Mounting Bracket | Profile Type: <none>; Mounting Bracket | Height: 0 m; Mounting Bracket | Base Offset: 0 m; Mounting Bracket | Side Offset: 0 m; Mounting Bracket | Spacing Type: Max Spacing; Balusters 1 | Name: Pickets; Balusters 1 | Spacing: 0.1 m; Balusters 1 | Spacing Type: Max Spacing; Balusters 1 | Profile Type: <none>; Balusters 1 | Profile: CHS26.9x3.2; Balusters 1 | Height: 0.78 m; Balusters 1 | Base Offset: 0.15 m; Balusters 1 | Side Offset: 0 m; Balusters 1 | Part Definition: S-FrameElements::S_BSUK_Steel_Miscellaneous; Balusters 2 | Spacing: 0.1 m; Balusters 2 | Spacing Type: Max Spacing; Balusters 2 | Profile Type: <none>; Balusters 2 | Profile: CHS26.9x3.2; Balusters 2 | Height: 0.75 m; Balusters 2 | Base Offset: 0 m; Balusters 2 | Side Offset: 0 m; Balusters 2 | Part Definition: S-FrameElements::S_BSUK_Steel_Miscellaneous; Balusters 3 | Spacing: 0.425 m; Balusters 3 | Spacing Type: Max Spacing; Balusters 3 | Profile Type: <none>; Balusters 3 | Profile: CHS26.9x3.2; Balusters 3 | Height: 0.75 m; Balusters 3 | Base Offset: 0 m; Balusters 3 | Side Offset: 0 m; Balusters 3 | Part Definition: S-FrameElements::S_BSUK_Steel_Miscellaneous; Railing End | Start Name: Start; Railing End | Start Top Offset: 0 m; Railing End | Start Side Offset: 0.1 m; Railing End | End Name: End; Railing Ends | End Top Offset: 0 m; Railing End | End Side Offset: 0.1 m
Type - Classification - Uniclass2015: Ss_25_15_60_66
PredefinedType: HANDRAIL; Material: A_BSUK_Steel_Miscellaneous
Railing Quantities - Rail 2 | Length: 0 m; Rail 3 | Length: 0 m; Rail 4 | Length: 0 m; Rail 5 | Length: 0 m; Rail 6 | Length: 0 m; Start Post | Length: 0 m; Start Post | Total Length: 0 m; Corner Post | Length: 0 m; Corner Post | Total Length: 0 m; End Post | Length: 0 m; End Post | Total Length: 0 m; Intermediate Post | Length: 0 m; Intermediate Post | Total Length: 0 m; Mounting Bracket | Length: 0 m; Mounting Bracket | Total Length: 0 m; Balusters 1 | Length: 0 m; Balusters 1 | Total Length: 0 m; Balusters 2 | Length: 0 m; Balusters 2 | Total Length: 0 m; Balusters 3 | Length: 0 m; Balusters 3 | Total Length: 0 m
Railing Parameters - Rail 1 | Profile Type: ProStructures Shape; Balusters 1 | Thickness: 0 m; Balusters 2 | Thickness: 0 m; Balusters 3 | Thickness: 0 m
Name | In | Description | Rail 1 | Length (m) | Rail 1 | Profile
S-Handrail-900mm | 1F | 7 ,SHE-06.FOURTH.dgn,Design Model:149595 | 4.29032 | 1\AS_SHS_C450\40X4.0SHS | Railing Parameters - Rail 1 | Side Offset: -0.1 m
S-Handrail-900mm | 1F | 7 ,SHE-06.FOURTH.dgn,Design Model:150039 | 4.1462 | 1\AS_SHS_C450\40X4.0SHS | Railing Parameters - Rail 1 | Side Offset: -0.1 m
S-Handrail-900mm | 1F | 7 ,SHE-06.FOURTH.dgn,Design Model:153072 | 4.56275 | 1\AS_SHS_C450\40X4.0SHS | Railing Parameters - Rail 1 | Side Offset: -0.1 m
S-Handrail-900mm | 1F | 7 ,SHE-06.FOURTH.dgn,Design Model:148849 | 4.21443 | 1\AS_SHS_C450\40X4.0SHS | Railing Parameters - Rail 1 | Side Offset: -0.1 m
S-Handrail-900mm | 5F | 8 ,SHE-07.FIFTH.dgn,Design Model:148301 | 8.31043 | 1\BS_CHS\CHS76.1X5 | Construction Phase - Phase: New Construction
S-Handrail-900mm | 5F | 8 ,SHE-07.FIFTH.dgn,Design Model:148337 | 8.31043 | 1\BS_CHS\CHS76.1X5 | Construction Phase - Phase: New Construction
S-Handrail-900mm | 5F | 8 ,SHE-07.FIFTH.dgn,Design Model:148350 | 8.31043 | 1\BS_CHS\CHS76.1X5 | Construction Phase - Phase: New Construction
S-Handrail-900mm | 5F | 8 ,SHE-07.FIFTH.dgn,Design Model:148361 | 8.31043 | 1\BS_CHS\CHS76.1X5 | Construction Phase - Phase: New Construction
S-Handrail-900mm | GF | 16 ,SHE-12.STAIR.dgn,Design Model:253213 | 1.22 | 1\AS_SHS_C450\40X4.0SHS

# IfcRoof: A-ZeeProfile01 (51)
ShapeType: FREEFORM; Material: A_BSUK_Roofs
Profile Parameters - Cell Symbol Name: Profiles::Zee-Profile-01; Rotation Angle: 0; Flip State: no
Materials - Part Definition: A-Roofs::A_BSUK_Roofs
Name | In | Description | Uniclass2015 | ID | Description | ID | Notes
A-ZeeProfile01 | MF | 2 ,SHE-02.MEZZANINE.dgn,Design Model:108082 | Pr_35_90_43
A-ZeeProfile01 | MF | 2 ,SHE-02.MEZZANINE.dgn,Design Model:108095 | Pr_35_90_43
A-ZeeProfile01 | MF | 2 ,SHE-02.MEZZANINE.dgn,Design Model:108107 | Pr_35_90_43
A-ZeeProfile01 | 5F | 8 ,SHE-07.FIFTH.dgn,Design Model:118604 | Pr_35_90_43
A-ZeeProfile01 | 5F | 8 ,SHE-07.FIFTH.dgn,Design Model:118616 | Pr_35_90_43
A-ZeeProfile01 | 5F | 8 ,SHE-07.FIFTH.dgn,Design Model:119524 | Pr_35_90_43
A-ZeeProfile01 | 5F | 8 ,SHE-07.FIFTH.dgn,Design Model:119536 | Pr_35_90_43
A-ZeeProfile01 | 5F | 8 ,SHE-07.FIFTH.dgn,Design Model:119911 | Pr_35_90_43
A-ZeeProfile01 | 5F | 8 ,SHE-07.FIFTH.dgn,Design Model:119923 | Pr_35_90_43
A-ZeeProfile01 | 5F | 8 ,SHE-07.FIFTH.dgn,Design Model:119937 | Pr_35_90_43
A-ZeeProfile01 | 5F | 8 ,SHE-07.FIFTH.dgn,Design Model:119949 | Pr_35_90_43
A-ZeeProfile01 | RL | ParapetCladding :10,SHE-08.ROOF.dgn,Design Model:112325 | Pr_35_90_43 | ParapetCladding | mansard roof
A-ZeeProfile01 | RL | ParapetCladding :10,SHE-08.ROOF.dgn,Design Model:112337 | Pr_35_90_43 | ParapetCladding | mansard roof
A-ZeeProfile01 | RL | ParapetCladding :10,SHE-08.ROOF.dgn,Design Model:113008 | Pr_20_76_51_04 | ParapetCladding | main building
A-ZeeProfile01 | RL | ParapetCladding :10,SHE-08.ROOF.dgn,Design Model:113022 | Pr_20_76_51_04 | ParapetCladding | main building
A-ZeeProfile01 | RL | ParapetCladding :10,SHE-08.ROOF.dgn,Design Model:113034 | Pr_20_76_51_04 | ParapetCladding | main building
A-ZeeProfile01 | RL | ParapetCladding :10,SHE-08.ROOF.dgn,Design Model:113048 | Pr_20_76_51_04 | ParapetCladding | main building
A-ZeeProfile01 | RL | ParapetCladding :10,SHE-08.ROOF.dgn,Design Model:113062 | Pr_20_76_51_04 | ParapetCladding | main building
A-ZeeProfile01 | RL | ParapetCladding :10,SHE-08.ROOF.dgn,Design Model:113124 | Pr_20_76_51_04 | ParapetCladding | main building
A-ZeeProfile01 | RL | ParapetCladding :10,SHE-08.ROOF.dgn,Design Model:113136 | Pr_20_76_51_04 | ParapetCladding | main building
A-ZeeProfile01 | RL | ParapetCladding :10,SHE-08.ROOF.dgn,Design Model:113148 | Pr_20_76_51_04 | ParapetCladding | main building
A-ZeeProfile01 | RL | ParapetCladding :10,SHE-08.ROOF.dgn,Design Model:113160 | Pr_20_76_51_04 | ParapetCladding | main building
A-ZeeProfile01 | RL | ParapetCladding :10,SHE-08.ROOF.dgn,Design Model:113172 | Pr_20_76_51_04 | ParapetCladding | main building
A-ZeeProfile01 | RL | ParapetCladding :10,SHE-08.ROOF.dgn,Design Model:113186 | Pr_20_76_51_04 | ParapetCladding | main building
A-ZeeProfile01 | RL | ParapetCladding :10,SHE-08.ROOF.dgn,Design Model:113200 | Pr_20_76_51_04 | ParapetCladding | main building
A-ZeeProfile01 | RL | ParapetCladding :10,SHE-08.ROOF.dgn,Design Model:113214 | Pr_20_76_51_04 | ParapetCladding | main building
A-ZeeProfile01 | RL | ParapetCladding :10,SHE-08.ROOF.dgn,Design Model:113228 | Pr_20_76_51_04 | ParapetCladding | main building
A-ZeeProfile01 | RL | ParapetCladding :10,SHE-08.ROOF.dgn,Design Model:113242 | Pr_20_76_51_04 | ParapetCladding | main building
A-ZeeProfile01 | RL | ParapetCladding :10,SHE-08.ROOF.dgn,Design Model:113256 | Pr_20_76_51_04 | ParapetCladding | main building
A-ZeeProfile01 | RL | ParapetCladding :10,SHE-08.ROOF.dgn,Design Model:113270 | Pr_20_76_51_04 | ParapetCladding | main building
A-ZeeProfile01 | RL | ParapetCladding :10,SHE-08.ROOF.dgn,Design Model:113284 | Pr_20_76_51_04 | ParapetCladding | main building
A-ZeeProfile01 | RL | ParapetCladding :10,SHE-08.ROOF.dgn,Design Model:113298 | Pr_20_76_51_04 | ParapetCladding | main building
A-ZeeProfile01 | RL | ParapetCladding :10,SHE-08.ROOF.dgn,Design Model:113312 | Pr_20_76_51_04 | ParapetCladding | main building
A-ZeeProfile01 | RL | ParapetCladding :10,SHE-08.ROOF.dgn,Design Model:113326 | Pr_20_76_51_04 | ParapetCladding | main building
A-ZeeProfile01 | RL | ParapetCladding :10,SHE-08.ROOF.dgn,Design Model:113340 | Pr_20_76_51_04 | ParapetCladding | main building
A-ZeeProfile01 | RL | ParapetCladding :10,SHE-08.ROOF.dgn,Design Model:113354 | Pr_20_76_51_04 | ParapetCladding | main building
A-ZeeProfile01 | RL | ParapetCladding :10,SHE-08.ROOF.dgn,Design Model:113368 | Pr_20_76_51_04 | ParapetCladding | main building
A-ZeeProfile01 | RL | ParapetCladding :10,SHE-08.ROOF.dgn,Design Model:113382 | Pr_20_76_51_04 | ParapetCladding | main building
A-ZeeProfile01 | RL | ParapetCladding :10,SHE-08.ROOF.dgn,Design Model:113396 | Pr_20_76_51_04 | ParapetCladding | main building
A-ZeeProfile01 | RL | ParapetCladding :10,SHE-08.ROOF.dgn,Design Model:113410 | Pr_20_76_51_04 | ParapetCladding | main building
A-ZeeProfile01 | RL | ParapetCladding :10,SHE-08.ROOF.dgn,Design Model:113424 | Pr_20_76_51_04 | ParapetCladding | main building
A-ZeeProfile01 | RL | ParapetCladding :10,SHE-08.ROOF.dgn,Design Model:113438 | Pr_20_76_51_04 | ParapetCladding | main building
A-ZeeProfile01 | RL | ParapetCladding :10,SHE-08.ROOF.dgn,Design Model:113452 | Pr_20_76_51_04 | ParapetCladding | main building
A-ZeeProfile01 | RL | ParapetCladding :10,SHE-08.ROOF.dgn,Design Model:113466 | Pr_20_76_51_04 | ParapetCladding | main building
A-ZeeProfile01 | RL | ParapetCladding :10,SHE-08.ROOF.dgn,Design Model:113480 | Pr_20_76_51_04 | ParapetCladding | main building
A-ZeeProfile01 | RL | ParapetCladding :10,SHE-08.ROOF.dgn,Design Model:113494 | Pr_20_76_51_04 | ParapetCladding | main building
A-ZeeProfile01 | RL | ParapetCladding :10,SHE-08.ROOF.dgn,Design Model:113508 | Pr_20_76_51_04 | ParapetCladding | main building
A-ZeeProfile01 | RL | ParapetCladding :10,SHE-08.ROOF.dgn,Design Model:113522 | Pr_20_76_51_04 | ParapetCladding | main building
A-ZeeProfile01 | RL | ParapetCladding :10,SHE-08.ROOF.dgn,Design Model:113536 | Pr_20_76_51_04 | ParapetCladding | main building
A-ZeeProfile01 | RL | ParapetCladding :10,SHE-08.ROOF.dgn,Design Model:113550 | Pr_20_76_51_04 | ParapetCladding | main building
A-ZeeProfile01 | RL | ParapetCladding :10,SHE-08.ROOF.dgn,Design Model:113564 | Pr_20_76_51_04 | ParapetCladding | main building

# IfcSlab: A-Finishes A_BSUK_Carpet-Pile (19)
In: 1F
Type - PredefinedType: FLOOR
Type - Thermal Transmittance - Is External: no; Is Below Grade: no
Type - Space Bounding - Is Space Bounding: yes
Type - Materials - Part Definition: A-Finishes::A_BSUK_Carpet-Pile
Type - Fire Resistance - Fire | IsCombustible: no; Fire | Compartmentation: no
Type - Classification - Uniclass2015: Pr_35_57_11
Material: A_BSUK_Carpet-Pile
Name | Description
A-Finishes A_BSUK_Carpet-Pile | 7 ,SHE-06.FOURTH.dgn,Design Model:272815
A-Finishes A_BSUK_Carpet-Pile | 7 ,SHE-06.FOURTH.dgn,Design Model:272848
A-Finishes A_BSUK_Carpet-Pile | 7 ,SHE-06.FOURTH.dgn,Design Model:272875
A-Finishes A_BSUK_Carpet-Pile | 7 ,SHE-06.FOURTH.dgn,Design Model:272902
A-Finishes A_BSUK_Carpet-Pile | 7 ,SHE-06.FOURTH.dgn,Design Model:272947
A-Finishes A_BSUK_Carpet-Pile | 7 ,SHE-06.FOURTH.dgn,Design Model:272986
A-Finishes A_BSUK_Carpet-Pile | 7 ,SHE-06.FOURTH.dgn,Design Model:273013
A-Finishes A_BSUK_Carpet-Pile | 7 ,SHE-06.FOURTH.dgn,Design Model:273040
A-Finishes A_BSUK_Carpet-Pile | 7 ,SHE-06.FOURTH.dgn,Design Model:273085
A-Finishes A_BSUK_Carpet-Pile | 7 ,SHE-06.FOURTH.dgn,Design Model:273118
A-Finishes A_BSUK_Carpet-Pile | 7 ,SHE-06.FOURTH.dgn,Design Model:273145
A-Finishes A_BSUK_Carpet-Pile | 7 ,SHE-06.FOURTH.dgn,Design Model:273178
A-Finishes A_BSUK_Carpet-Pile | 7 ,SHE-06.FOURTH.dgn,Design Model:273211
A-Finishes A_BSUK_Carpet-Pile | 7 ,SHE-06.FOURTH.dgn,Design Model:273244
A-Finishes A_BSUK_Carpet-Pile | 7 ,SHE-06.FOURTH.dgn,Design Model:273424
A-Finishes A_BSUK_Carpet-Pile | 7 ,SHE-06.FOURTH.dgn,Design Model:273499
A-Finishes A_BSUK_Carpet-Pile | 7 ,SHE-06.FOURTH.dgn,Design Model:273601
A-Finishes A_BSUK_Carpet-Pile | 7 ,SHE-06.FOURTH.dgn,Design Model:273664
A-Finishes A_BSUK_Carpet-Pile | 7 ,SHE-06.FOURTH.dgn,Design Model:273691

# IfcSlab: A-Finishes A_BSUK_Ceramic_FloorTiles (11)
Type - PredefinedType: FLOOR
Type - Thermal Transmittance - Is External: no; Is Below Grade: no
Type - Space Bounding - Is Space Bounding: yes
Type - Materials - Part Definition: A-Finishes::A_BSUK_Ceramic_FloorTiles
Type - Fire Resistance - Fire | IsCombustible: no; Fire | Compartmentation: no
Type - Classification - Uniclass2015: Pr_35_93_96
Material: A_BSUK_Ceramic_FloorTiles
Name | In | Description
A-Finishes A_BSUK_Ceramic_FloorTiles | GF | 1,SHE-01.GROUND.dgn ,Design Model:155307
A-Finishes A_BSUK_Ceramic_FloorTiles | GF | 1,SHE-01.GROUND.dgn ,Design Model:155662
A-Finishes A_BSUK_Ceramic_FloorTiles | GF | 1,SHE-01.GROUND.dgn ,Design Model:183812
A-Finishes A_BSUK_Ceramic_FloorTiles | 1F | 7,SHE-06.FOURTH.dgn ,Design Model:273277
A-Finishes A_BSUK_Ceramic_FloorTiles | 1F | 7,SHE-06.FOURTH.dgn ,Design Model:273346
A-Finishes A_BSUK_Ceramic_FloorTiles | 1F | 7,SHE-06.FOURTH.dgn ,Design Model:273439
A-Finishes A_BSUK_Ceramic_FloorTiles | 1F | 7,SHE-06.FOURTH.dgn ,Design Model:273457
A-Finishes A_BSUK_Ceramic_FloorTiles | 1F | 7,SHE-06.FOURTH.dgn ,Design Model:273547
A-Finishes A_BSUK_Ceramic_FloorTiles | 1F | 7,SHE-06.FOURTH.dgn ,Design Model:273574
A-Finishes A_BSUK_Ceramic_FloorTiles | 1F | 7,SHE-06.FOURTH.dgn ,Design Model:273643
A-Finishes A_BSUK_Ceramic_FloorTiles | 1F | 7,SHE-06.FOURTH.dgn ,Design Model:273712

# IfcSlab: A-FloorsSlabs A_BSUK_ExpandedPolystyreneBoards (87)
Type - PredefinedType: FLOOR
Type - Thermal Transmittance - Is External: no; Is Below Grade: no
Type - Space Bounding - Is Space Bounding: yes
Type - Materials - Part Definition: A-FloorsSlabs::A_BSUK_ExpandedPolystyreneBoards
Type - Fire Resistance - Fire | IsCombustible: no; Fire | Compartmentation: no
Type - Classification - Uniclass2015: Pr_25_71_63_26
Material: A_BSUK_ExpandedPolystyreneBoards
Name | In | Description
A-FloorsSlabs A_BSUK_ExpandedPolystyreneBoards | GF | 1,SHE-01.GROUND.dgn ,Design Model:189262
A-FloorsSlabs A_BSUK_ExpandedPolystyreneBoards | GF | 1,SHE-01.GROUND.dgn ,Design Model:189322
A-FloorsSlabs A_BSUK_ExpandedPolystyreneBoards | GF | 1,SHE-01.GROUND.dgn ,Design Model:189323
A-FloorsSlabs A_BSUK_ExpandedPolystyreneBoards | GF | 1,SHE-01.GROUND.dgn ,Design Model:189785
A-FloorsSlabs A_BSUK_ExpandedPolystyreneBoards | GF | 1,SHE-01.GROUND.dgn ,Design Model:189813
A-FloorsSlabs A_BSUK_ExpandedPolystyreneBoards | GF | 1,SHE-01.GROUND.dgn ,Design Model:235851
A-FloorsSlabs A_BSUK_ExpandedPolystyreneBoards | GF | 1,SHE-01.GROUND.dgn ,Design Model:237555
A-FloorsSlabs A_BSUK_ExpandedPolystyreneBoards | GF | 1,SHE-01.GROUND.dgn ,Design Model:239339
A-FloorsSlabs A_BSUK_ExpandedPolystyreneBoards | GF | 1,SHE-01.GROUND.dgn ,Design Model:239340
A-FloorsSlabs A_BSUK_ExpandedPolystyreneBoards | GF | 1,SHE-01.GROUND.dgn ,Design Model:239341
A-FloorsSlabs A_BSUK_ExpandedPolystyreneBoards | GF | 1,SHE-01.GROUND.dgn ,Design Model:239342
A-FloorsSlabs A_BSUK_ExpandedPolystyreneBoards | 1F | 4,SHE-03.FIRST.dgn ,Design Model:414607
A-FloorsSlabs A_BSUK_ExpandedPolystyreneBoards | 1F | 4,SHE-03.FIRST.dgn ,Design Model:414608
A-FloorsSlabs A_BSUK_ExpandedPolystyreneBoards | 1F | 4,SHE-03.FIRST.dgn ,Design Model:414609
A-FloorsSlabs A_BSUK_ExpandedPolystyreneBoards | 1F | 4,SHE-03.FIRST.dgn ,Design Model:414610
A-FloorsSlabs A_BSUK_ExpandedPolystyreneBoards | 1F | 4,SHE-03.FIRST.dgn ,Design Model:414611
A-FloorsSlabs A_BSUK_ExpandedPolystyreneBoards | 1F | 4,SHE-03.FIRST.dgn ,Design Model:414612
A-FloorsSlabs A_BSUK_ExpandedPolystyreneBoards | 1F | 4,SHE-03.FIRST.dgn ,Design Model:414613
A-FloorsSlabs A_BSUK_ExpandedPolystyreneBoards | 1F | 4,SHE-03.FIRST.dgn ,Design Model:414614
A-FloorsSlabs A_BSUK_ExpandedPolystyreneBoards | 1F | 4,SHE-03.FIRST.dgn ,Design Model:414615
A-FloorsSlabs A_BSUK_ExpandedPolystyreneBoards | 1F | 4,SHE-03.FIRST.dgn ,Design Model:414616
A-FloorsSlabs A_BSUK_ExpandedPolystyreneBoards | 1F | 4,SHE-03.FIRST.dgn ,Design Model:414617
A-FloorsSlabs A_BSUK_ExpandedPolystyreneBoards | 1F | 4,SHE-03.FIRST.dgn ,Design Model:414618
A-FloorsSlabs A_BSUK_ExpandedPolystyreneBoards | 1F | 4,SHE-03.FIRST.dgn ,Design Model:414619
A-FloorsSlabs A_BSUK_ExpandedPolystyreneBoards | 1F | 4,SHE-03.FIRST.dgn ,Design Model:414620
A-FloorsSlabs A_BSUK_ExpandedPolystyreneBoards | 1F | 4,SHE-03.FIRST.dgn ,Design Model:414621
A-FloorsSlabs A_BSUK_ExpandedPolystyreneBoards | 1F | 4,SHE-03.FIRST.dgn ,Design Model:414622
A-FloorsSlabs A_BSUK_ExpandedPolystyreneBoards | 1F | 4,SHE-03.FIRST.dgn ,Design Model:414623
A-FloorsSlabs A_BSUK_ExpandedPolystyreneBoards | 1F | 4,SHE-03.FIRST.dgn ,Design Model:414624
A-FloorsSlabs A_BSUK_ExpandedPolystyreneBoards | 1F | 4,SHE-03.FIRST.dgn ,Design Model:414625
A-FloorsSlabs A_BSUK_ExpandedPolystyreneBoards | 1F | 4,SHE-03.FIRST.dgn ,Design Model:414626
A-FloorsSlabs A_BSUK_ExpandedPolystyreneBoards | 1F | 4,SHE-03.FIRST.dgn ,Design Model:415567
A-FloorsSlabs A_BSUK_ExpandedPolystyreneBoards | 1F | 4,SHE-03.FIRST.dgn ,Design Model:415642
A-FloorsSlabs A_BSUK_ExpandedPolystyreneBoards | 1F | 4,SHE-03.FIRST.dgn ,Design Model:415643
A-FloorsSlabs A_BSUK_ExpandedPolystyreneBoards | 3F | 6,SHE-05.THIRD.dgn ,Design Model:134765
A-FloorsSlabs A_BSUK_ExpandedPolystyreneBoards | 3F | 6,SHE-05.THIRD.dgn ,Design Model:134792
A-FloorsSlabs A_BSUK_ExpandedPolystyreneBoards | 3F | 6,SHE-05.THIRD.dgn ,Design Model:134816
A-FloorsSlabs A_BSUK_ExpandedPolystyreneBoards | 3F | 6,SHE-05.THIRD.dgn ,Design Model:154694
A-FloorsSlabs A_BSUK_ExpandedPolystyreneBoards | 3F | 6,SHE-05.THIRD.dgn ,Design Model:154742
A-FloorsSlabs A_BSUK_ExpandedPolystyreneBoards | 3F | 6,SHE-05.THIRD.dgn ,Design Model:155063
A-FloorsSlabs A_BSUK_ExpandedPolystyreneBoards | 3F | 6,SHE-05.THIRD.dgn ,Design Model:155064
A-FloorsSlabs A_BSUK_ExpandedPolystyreneBoards | 3F | 6,SHE-05.THIRD.dgn ,Design Model:155065
A-FloorsSlabs A_BSUK_ExpandedPolystyreneBoards | 3F | 6,SHE-05.THIRD.dgn ,Design Model:155066
A-FloorsSlabs A_BSUK_ExpandedPolystyreneBoards | 3F | 6,SHE-05.THIRD.dgn ,Design Model:155067
A-FloorsSlabs A_BSUK_ExpandedPolystyreneBoards | 3F | 6,SHE-05.THIRD.dgn ,Design Model:155068
A-FloorsSlabs A_BSUK_ExpandedPolystyreneBoards | 3F | 6,SHE-05.THIRD.dgn ,Design Model:155069
A-FloorsSlabs A_BSUK_ExpandedPolystyreneBoards | 3F | 6,SHE-05.THIRD.dgn ,Design Model:155084
A-FloorsSlabs A_BSUK_ExpandedPolystyreneBoards | 3F | 6,SHE-05.THIRD.dgn ,Design Model:155099
A-FloorsSlabs A_BSUK_ExpandedPolystyreneBoards | 3F | 6,SHE-05.THIRD.dgn ,Design Model:155370
A-FloorsSlabs A_BSUK_ExpandedPolystyreneBoards | 3F | 6,SHE-05.THIRD.dgn ,Design Model:155371
A-FloorsSlabs A_BSUK_ExpandedPolystyreneBoards | 3F | 6,SHE-05.THIRD.dgn ,Design Model:155619
A-FloorsSlabs A_BSUK_ExpandedPolystyreneBoards | 3F | 6,SHE-05.THIRD.dgn ,Design Model:155620
A-FloorsSlabs A_BSUK_ExpandedPolystyreneBoards | 3F | 6,SHE-05.THIRD.dgn ,Design Model:155621
A-FloorsSlabs A_BSUK_ExpandedPolystyreneBoards | 3F | 6,SHE-05.THIRD.dgn ,Design Model:155622
A-FloorsSlabs A_BSUK_ExpandedPolystyreneBoards | 3F | 6,SHE-05.THIRD.dgn ,Design Model:155623
A-FloorsSlabs A_BSUK_ExpandedPolystyreneBoards | 3F | 6,SHE-05.THIRD.dgn ,Design Model:155624
A-FloorsSlabs A_BSUK_ExpandedPolystyreneBoards | 3F | 6,SHE-05.THIRD.dgn ,Design Model:155626
A-FloorsSlabs A_BSUK_ExpandedPolystyreneBoards | 3F | 6,SHE-05.THIRD.dgn ,Design Model:220881
A-FloorsSlabs A_BSUK_ExpandedPolystyreneBoards | 3F | 6,SHE-05.THIRD.dgn ,Design Model:220882
A-FloorsSlabs A_BSUK_ExpandedPolystyreneBoards | 3F | 6,SHE-05.THIRD.dgn ,Design Model:220883
A-FloorsSlabs A_BSUK_ExpandedPolystyreneBoards | 1F | 7,SHE-06.FOURTH.dgn ,Design Model:473652
A-FloorsSlabs A_BSUK_ExpandedPolystyreneBoards | 1F | 7,SHE-06.FOURTH.dgn ,Design Model:489978
A-FloorsSlabs A_BSUK_ExpandedPolystyreneBoards | 1F | 7,SHE-06.FOURTH.dgn ,Design Model:491292
A-FloorsSlabs A_BSUK_ExpandedPolystyreneBoards | 1F | 7,SHE-06.FOURTH.dgn ,Design Model:492620
A-FloorsSlabs A_BSUK_ExpandedPolystyreneBoards | 2F | 18,SHE-04.SECOND.dgn ,Design Model:389771
A-FloorsSlabs A_BSUK_ExpandedPolystyreneBoards | 2F | 18,SHE-04.SECOND.dgn ,Design Model:389772
A-FloorsSlabs A_BSUK_ExpandedPolystyreneBoards | 2F | 18,SHE-04.SECOND.dgn ,Design Model:389773
A-FloorsSlabs A_BSUK_ExpandedPolystyreneBoards | 2F | 18,SHE-04.SECOND.dgn ,Design Model:389774
A-FloorsSlabs A_BSUK_ExpandedPolystyreneBoards | 2F | 18,SHE-04.SECOND.dgn ,Design Model:389775
A-FloorsSlabs A_BSUK_ExpandedPolystyreneBoards | 2F | 18,SHE-04.SECOND.dgn ,Design Model:389776
A-FloorsSlabs A_BSUK_ExpandedPolystyreneBoards | 2F | 18,SHE-04.SECOND.dgn ,Design Model:389777
A-FloorsSlabs A_BSUK_ExpandedPolystyreneBoards | 2F | 18,SHE-04.SECOND.dgn ,Design Model:389778
A-FloorsSlabs A_BSUK_ExpandedPolystyreneBoards | 2F | 18,SHE-04.SECOND.dgn ,Design Model:389779
A-FloorsSlabs A_BSUK_ExpandedPolystyreneBoards | 2F | 18,SHE-04.SECOND.dgn ,Design Model:389780
A-FloorsSlabs A_BSUK_ExpandedPolystyreneBoards | 2F | 18,SHE-04.SECOND.dgn ,Design Model:389781
A-FloorsSlabs A_BSUK_ExpandedPolystyreneBoards | 2F | 18,SHE-04.SECOND.dgn ,Design Model:389782
A-FloorsSlabs A_BSUK_ExpandedPolystyreneBoards | 2F | 18,SHE-04.SECOND.dgn ,Design Model:389783
A-FloorsSlabs A_BSUK_ExpandedPolystyreneBoards | 2F | 18,SHE-04.SECOND.dgn ,Design Model:389784
A-FloorsSlabs A_BSUK_ExpandedPolystyreneBoards | 2F | 18,SHE-04.SECOND.dgn ,Design Model:389785
A-FloorsSlabs A_BSUK_ExpandedPolystyreneBoards | 2F | 18,SHE-04.SECOND.dgn ,Design Model:389786
A-FloorsSlabs A_BSUK_ExpandedPolystyreneBoards | 2F | 18,SHE-04.SECOND.dgn ,Design Model:389787
A-FloorsSlabs A_BSUK_ExpandedPolystyreneBoards | 2F | 18,SHE-04.SECOND.dgn ,Design Model:389788
A-FloorsSlabs A_BSUK_ExpandedPolystyreneBoards | 2F | 18,SHE-04.SECOND.dgn ,Design Model:389789
A-FloorsSlabs A_BSUK_ExpandedPolystyreneBoards | 2F | 18,SHE-04.SECOND.dgn ,Design Model:389790
A-FloorsSlabs A_BSUK_ExpandedPolystyreneBoards | 2F | 18,SHE-04.SECOND.dgn ,Design Model:389814
A-FloorsSlabs A_BSUK_ExpandedPolystyreneBoards | 2F | 18,SHE-04.SECOND.dgn ,Design Model:389867
A-FloorsSlabs A_BSUK_ExpandedPolystyreneBoards | 2F | 18,SHE-04.SECOND.dgn ,Design Model:389868

# IfcSlab: A-FloorsSlabs A_BSUK_InternalFinishes_FloorScreed (5)
In: 1F
Type - PredefinedType: FLOOR
Type - Thermal Transmittance - Is External: no; Is Below Grade: no
Type - Space Bounding - Is Space Bounding: yes
Type - Materials - Part Definition: A-FloorsSlabs::A_BSUK_InternalFinishes_FloorScreed
Type - Fire Resistance - Fire | IsCombustible: no; Fire | Compartmentation: no
Type - Classification - Uniclass2015: Pr_35_31_06_29
Material: A_BSUK_InternalFinishes_FloorScreed
Name | Description
A-FloorsSlabs A_BSUK_InternalFinishes_FloorScreed | 7,SHE-06.FOURTH.dgn ,Design Model:273307
A-FloorsSlabs A_BSUK_InternalFinishes_FloorScreed | 7,SHE-06.FOURTH.dgn ,Design Model:273385
A-FloorsSlabs A_BSUK_InternalFinishes_FloorScreed | 7,SHE-06.FOURTH.dgn ,Design Model:277592
A-FloorsSlabs A_BSUK_InternalFinishes_FloorScreed | 7,SHE-06.FOURTH.dgn ,Design Model:315857
A-FloorsSlabs A_BSUK_InternalFinishes_FloorScreed | 7,SHE-06.FOURTH.dgn ,Design Model:319650

# IfcSlab: A-FloorsSlabs A_BSUK_Slabs (1393)
Type - PredefinedType: FLOOR
Type - Thermal Transmittance - Is External: no; Is Below Grade: no
Type - Space Bounding - Is Space Bounding: yes
Type - Materials - Part Definition: A-FloorsSlabs::A_BSUK_Slabs
Type - Fire Resistance - Fire | IsCombustible: no; Fire | Compartmentation: no
Type - Classification - Uniclass2015: Ss_30_12_85_18
Name | In | Description | Material | Phase | Part Definition
A-FloorsSlabs A_BSUK_Slabs | GF | 1 ,SHE-01.GROUND.dgn,Design Model:90221 | A_BSUK_Slabs | Existing to Remain
A-FloorsSlabs A_BSUK_Slabs | GF | 1 ,SHE-01.GROUND.dgn,Design Model:90223 | A_BSUK_Slabs
A-FloorsSlabs A_BSUK_Slabs | GF | 1 ,SHE-01.GROUND.dgn,Design Model:90224 | A_BSUK_Slabs | Existing to Remain
A-FloorsSlabs A_BSUK_Slabs | GF | 1 ,SHE-01.GROUND.dgn,Design Model:90225 | A_BSUK_Slabs
A-FloorsSlabs A_BSUK_Slabs | GF | 1 ,SHE-01.GROUND.dgn,Design Model:90226 | A_BSUK_Slabs | Existing to Remain
A-FloorsSlabs A_BSUK_Slabs | GF | 1 ,SHE-01.GROUND.dgn,Design Model:90227 | A_BSUK_Slabs | Existing to Remain
A-FloorsSlabs A_BSUK_Slabs | GF | 1 ,SHE-01.GROUND.dgn,Design Model:90229 | A_BSUK_Slabs
A-FloorsSlabs A_BSUK_Slabs | GF | 1 ,SHE-01.GROUND.dgn,Design Model:90231 | A_BSUK_Slabs | Existing to Remain
A-FloorsSlabs A_BSUK_Slabs | GF | 1 ,SHE-01.GROUND.dgn,Design Model:90232 | A_BSUK_Slabs | Existing to Remain
A-FloorsSlabs A_BSUK_Slabs | GF | window sill - timber :1,SHE-01.GROUND.dgn,Design Model:90233 | A_BSUK_Slabs | Existing to Remain | Identification - ID | Description: window sill - timber
A-FloorsSlabs A_BSUK_Slabs | GF | window sill - timber :1,SHE-01.GROUND.dgn,Design Model:90234 | A_BSUK_Slabs | Existing to Remain | Identification - ID | Description: window sill - timber
A-FloorsSlabs A_BSUK_Slabs | GF | 1 ,SHE-01.GROUND.dgn,Design Model:90235 | A_BSUK_Slabs | Existing to Remain
A-FloorsSlabs A_BSUK_Slabs | GF | 1 ,SHE-01.GROUND.dgn,Design Model:90236 | A_BSUK_Slabs | Existing to Remain
A-FloorsSlabs A_BSUK_Slabs | GF | 1 ,SHE-01.GROUND.dgn,Design Model:90237 | A_BSUK_Slabs | Existing to Remain
A-FloorsSlabs A_BSUK_Slabs | GF | 1 ,SHE-01.GROUND.dgn,Design Model:90238 | A_BSUK_Slabs | Existing to Remain
A-FloorsSlabs A_BSUK_Slabs | GF | window sill - timber :1,SHE-01.GROUND.dgn,Design Model:90239 | A_BSUK_Slabs | Existing to Remain | Identification - ID | Description: window sill - timber
A-FloorsSlabs A_BSUK_Slabs | GF | 1 ,SHE-01.GROUND.dgn,Design Model:90240 | A_BSUK_Slabs | Existing to Remain
A-FloorsSlabs A_BSUK_Slabs | GF | 1 ,SHE-01.GROUND.dgn,Design Model:90241 | A_BSUK_Slabs | Existing to Remain
A-FloorsSlabs A_BSUK_Slabs | GF | 1 ,SHE-01.GROUND.dgn,Design Model:90242 | A_BSUK_Slabs | Existing to Remain
A-FloorsSlabs A_BSUK_Slabs | GF | 1 ,SHE-01.GROUND.dgn,Design Model:90243 | A_BSUK_Slabs
A-FloorsSlabs A_BSUK_Slabs | GF | 1 ,SHE-01.GROUND.dgn,Design Model:90244 | A_BSUK_Slabs
A-FloorsSlabs A_BSUK_Slabs | GF | 1 ,SHE-01.GROUND.dgn,Design Model:90245 | A_BSUK_Slabs
A-FloorsSlabs A_BSUK_Slabs | GF | 1 ,SHE-01.GROUND.dgn,Design Model:90246 | A_BSUK_Slabs
A-FloorsSlabs A_BSUK_Slabs | GF | 1 ,SHE-01.GROUND.dgn,Design Model:90247 | A_BSUK_Slabs | Existing to Remain
A-FloorsSlabs A_BSUK_Slabs | GF | 1 ,SHE-01.GROUND.dgn,Design Model:90248 | A_BSUK_Slabs | Existing to Remain
A-FloorsSlabs A_BSUK_Slabs | GF | 1 ,SHE-01.GROUND.dgn,Design Model:90249 | A_BSUK_Slabs | Existing to Remain
A-FloorsSlabs A_BSUK_Slabs | GF | 1 ,SHE-01.GROUND.dgn,Design Model:90250 | A_BSUK_Slabs | Existing to Remain
A-FloorsSlabs A_BSUK_Slabs | GF | 1 ,SHE-01.GROUND.dgn,Design Model:90251 | A_BSUK_Slabs
A-FloorsSlabs A_BSUK_Slabs | GF | 1 ,SHE-01.GROUND.dgn,Design Model:118360 | A_BSUK_Slabs
A-FloorsSlabs A_BSUK_Slabs | GF | 1 ,SHE-01.GROUND.dgn,Design Model:118459 | A_BSUK_Slabs
A-FloorsSlabs A_BSUK_Slabs | GF | 1 ,SHE-01.GROUND.dgn,Design Model:118506 | A_BSUK_Slabs
A-FloorsSlabs A_BSUK_Slabs | GF | 1 ,SHE-01.GROUND.dgn,Design Model:118727 | A_BSUK_Slabs
A-FloorsSlabs A_BSUK_Slabs | GF | 1 ,SHE-01.GROUND.dgn,Design Model:123091 | A_BSUK_Slabs | Existing to Remain
A-FloorsSlabs A_BSUK_Slabs | GF | 1 ,SHE-01.GROUND.dgn,Design Model:155799 | A_BSUK_Ceramic_WallTiles | New Construction | A-Finishes::A_BSUK_Ceramic_WallTiles
A-FloorsSlabs A_BSUK_Slabs | GF | 1 ,SHE-01.GROUND.dgn,Design Model:155800 | A_BSUK_Ceramic_WallTiles | New Construction | A-Finishes::A_BSUK_Ceramic_WallTiles
A-FloorsSlabs A_BSUK_Slabs | GF | 1 ,SHE-01.GROUND.dgn,Design Model:155855 | A_BSUK_Ceramic_WallTiles | New Construction | A-Finishes::A_BSUK_Ceramic_WallTiles
A-FloorsSlabs A_BSUK_Slabs | GF | 1 ,SHE-01.GROUND.dgn,Design Model:155856 | A_BSUK_Ceramic_WallTiles | New Construction | A-Finishes::A_BSUK_Ceramic_WallTiles
A-FloorsSlabs A_BSUK_Slabs | GF | 1 ,SHE-01.GROUND.dgn,Design Model:180163 | A_BSUK_Slabs
A-FloorsSlabs A_BSUK_Slabs | GF | 1 ,SHE-01.GROUND.dgn,Design Model:180256 | A_BSUK_Slabs
A-FloorsSlabs A_BSUK_Slabs | GF | 1 ,SHE-01.GROUND.dgn,Design Model:180811 | A_BSUK_Ceramic_FloorTiles |  | A-Finishes::A_BSUK_Ceramic_FloorTiles
A-FloorsSlabs A_BSUK_Slabs | GF | 1 ,SHE-01.GROUND.dgn,Design Model:181088 | A_BSUK_Carpet-Pile |  | A-Finishes::A_BSUK_Carpet-Pile
A-FloorsSlabs A_BSUK_Slabs | GF | 1 ,SHE-01.GROUND.dgn,Design Model:182836 | A_BSUK_Parquet_Floor |  | A-Finishes::A_BSUK_Parquet_Floor
A-FloorsSlabs A_BSUK_Slabs | GF | 1 ,SHE-01.GROUND.dgn,Design Model:183841 | A_BSUK_Ceramic_WallTiles | New Construction | A-Finishes::A_BSUK_Ceramic_WallTiles
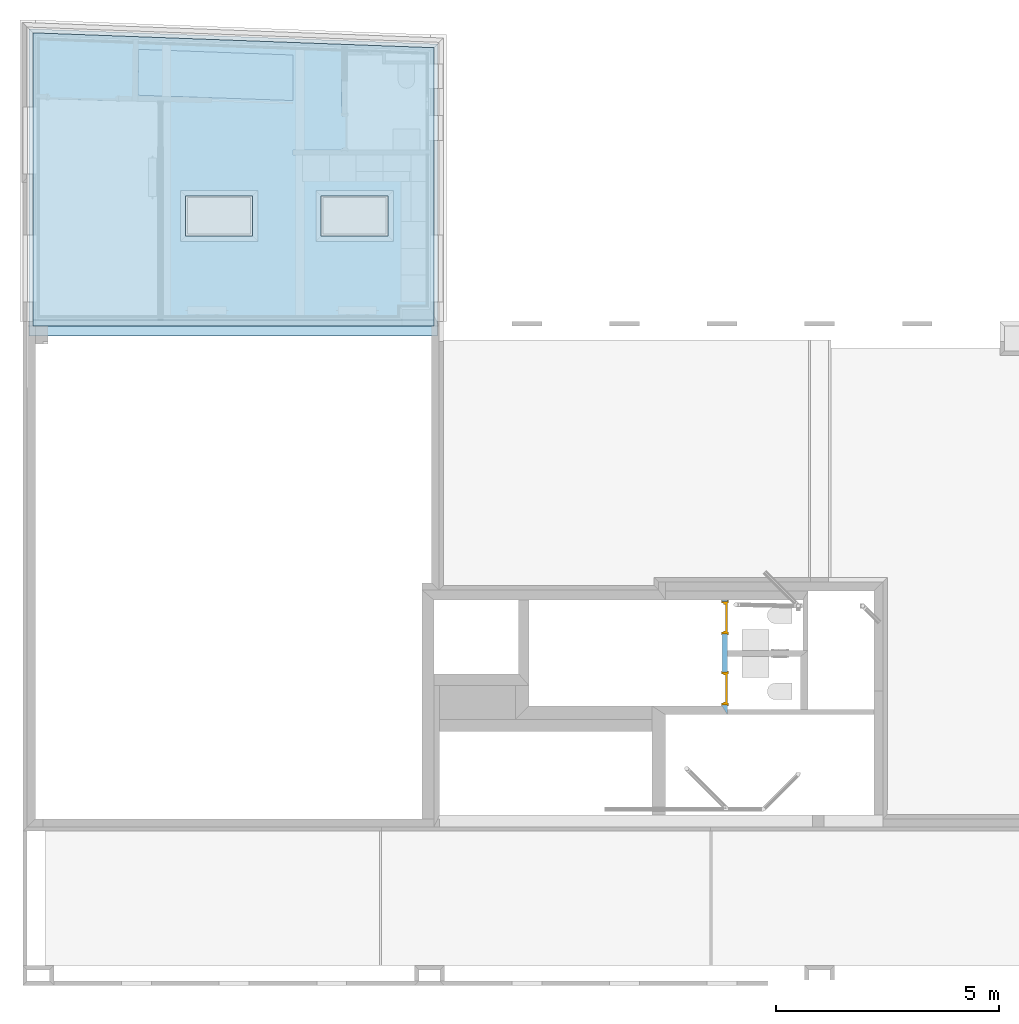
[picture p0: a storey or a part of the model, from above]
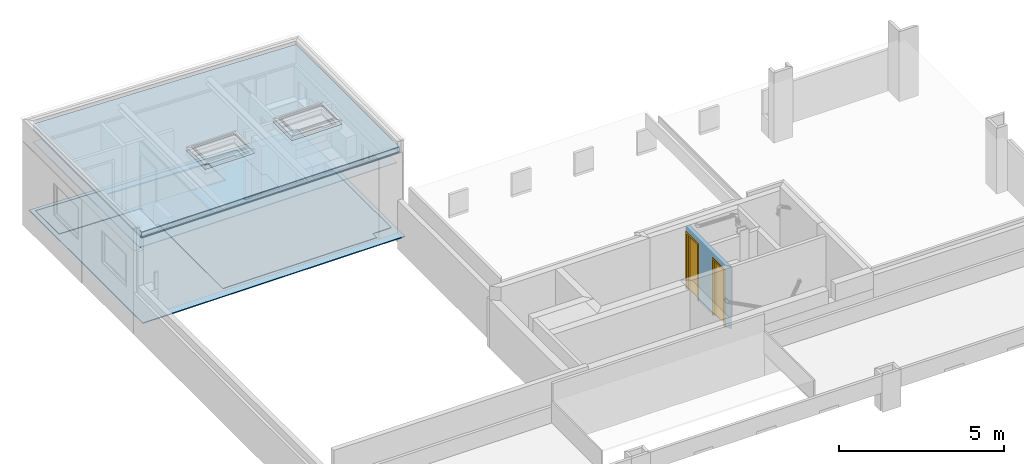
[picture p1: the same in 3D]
Properties of the parts of a building model (IFC2X3), part 9 of 16

# IfcSlab: A-FloorsSlabs A_BSUK_Slabs (1393)
Name | In | Description | Material | Phase | Part Definition
A-FloorsSlabs A_BSUK_Slabs | GF | 1 ,SHE-01.GROUND.dgn,Design Model:186951 | A_BSUK_CeilingSoffitFinishes_Suspended | New Construction | A-Ceilings::A_BSUK_CeilingSoffitFinishes_Suspended
A-FloorsSlabs A_BSUK_Slabs | GF | 1 ,SHE-01.GROUND.dgn,Design Model:188241 | A_BSUK_Timber_Miscellaneous | New Construction | A-FrameElements::A_BSUK_Timber_Miscellaneous
A-FloorsSlabs A_BSUK_Slabs | GF | 1 ,SHE-01.GROUND.dgn,Design Model:190233 | A_BSUK_Parquet_Floor | New Construction | A-Finishes::A_BSUK_Parquet_Floor
A-FloorsSlabs A_BSUK_Slabs | GF | 1 ,SHE-01.GROUND.dgn,Design Model:190248 | A_BSUK_Parquet_Floor | New Construction | A-Finishes::A_BSUK_Parquet_Floor
A-FloorsSlabs A_BSUK_Slabs | GF | plasterboard - ceiling :1,SHE-01.GROUND.dgn,Design Model:235747 | A_BSUK_Slabs | Existing to Remain | Identification - ID | Description: plasterboard - ceiling; ID | Notes: req. 60dB
A-FloorsSlabs A_BSUK_Slabs | GF | plasterboard - ceiling :1,SHE-01.GROUND.dgn,Design Model:235953 | A_BSUK_Slabs | Existing to Remain | Identification - ID | Description: plasterboard - ceiling; ID | Notes: req. 60dB
A-FloorsSlabs A_BSUK_Slabs | GF | plasterboard - ceiling :1,SHE-01.GROUND.dgn,Design Model:237528 | A_BSUK_Slabs | Existing to Remain | Identification - ID | Description: plasterboard - ceiling; ID | Notes: req. 60dB
A-FloorsSlabs A_BSUK_Slabs | GF | plasterboard - ceiling :1,SHE-01.GROUND.dgn,Design Model:237582 | A_BSUK_Slabs | Existing to Remain | Identification - ID | Description: plasterboard - ceiling; ID | Notes: req. 60dB
A-FloorsSlabs A_BSUK_Slabs | GF | plasterboard - ceiling :1,SHE-01.GROUND.dgn,Design Model:238977 | A_BSUK_CeilingSoffitFinishes_Suspended | New Construction | A-Ceilings::A_BSUK_CeilingSoffitFinishes_Suspended | Identification - ID | Description: plasterboard - ceiling
A-FloorsSlabs A_BSUK_Slabs | GF | plasterboard - ceiling :1,SHE-01.GROUND.dgn,Design Model:238978 | A_BSUK_CeilingSoffitFinishes_Suspended | New Construction | A-Ceilings::A_BSUK_CeilingSoffitFinishes_Suspended | Identification - ID | Description: plasterboard - ceiling
A-FloorsSlabs A_BSUK_Slabs | GF | plasterboard - ceiling :1,SHE-01.GROUND.dgn,Design Model:238979 | A_BSUK_CeilingSoffitFinishes_Suspended | New Construction | A-Ceilings::A_BSUK_CeilingSoffitFinishes_Suspended | Identification - ID | Description: plasterboard - ceiling
A-FloorsSlabs A_BSUK_Slabs | GF | plasterboard - ceiling :1,SHE-01.GROUND.dgn,Design Model:238980 | A_BSUK_CeilingSoffitFinishes_Suspended | New Construction | A-Ceilings::A_BSUK_CeilingSoffitFinishes_Suspended | Identification - ID | Description: plasterboard - ceiling
A-FloorsSlabs A_BSUK_Slabs | GF | 1 ,SHE-01.GROUND.dgn,Design Model:249470 | A_BSUK_Timber_Miscellaneous | New Construction | A-FrameElements::A_BSUK_Timber_Miscellaneous
A-FloorsSlabs A_BSUK_Slabs | GF | 1 ,SHE-01.GROUND.dgn,Design Model:249552 | A_BSUK_Timber_Miscellaneous | New Construction | A-FrameElements::A_BSUK_Timber_Miscellaneous
A-FloorsSlabs A_BSUK_Slabs | GF | 1 ,SHE-01.GROUND.dgn,Design Model:249580 | A_BSUK_Timber_Miscellaneous | New Construction | A-FrameElements::A_BSUK_Timber_Miscellaneous
A-FloorsSlabs A_BSUK_Slabs | GF | 1 ,SHE-01.GROUND.dgn,Design Model:249608 | A_BSUK_Timber_Miscellaneous | New Construction | A-FrameElements::A_BSUK_Timber_Miscellaneous
A-FloorsSlabs A_BSUK_Slabs | MF | 2 ,SHE-02.MEZZANINE.dgn,Design Model:90007 | A_BSUK_Slabs | Existing to Remain
A-FloorsSlabs A_BSUK_Slabs | MF | 2 ,SHE-02.MEZZANINE.dgn,Design Model:90008 | A_BSUK_Slabs | Existing to Remain
A-FloorsSlabs A_BSUK_Slabs | MF | 2 ,SHE-02.MEZZANINE.dgn,Design Model:90009 | A_BSUK_Slabs | Existing to Remain
A-FloorsSlabs A_BSUK_Slabs | MF | 2 ,SHE-02.MEZZANINE.dgn,Design Model:90010 | A_BSUK_Slabs | Existing to Remain
A-FloorsSlabs A_BSUK_Slabs | MF | 2 ,SHE-02.MEZZANINE.dgn,Design Model:90011 | A_BSUK_Slabs | Existing to Remain
A-FloorsSlabs A_BSUK_Slabs | MF | insulation - sound undercroft :2,SHE-02.MEZZANINE.dgn,Design Model:90018 | A_BSUK_ExpandedPolystyreneBoards | New Construction | A-FloorsSlabs::A_BSUK_ExpandedPolystyreneBoards | Identification - ID | Description: insulation - sound undercroft
A-FloorsSlabs A_BSUK_Slabs | MF | insulation - sound undercroft :2,SHE-02.MEZZANINE.dgn,Design Model:90019 | A_BSUK_ExpandedPolystyreneBoards | New Construction | A-FloorsSlabs::A_BSUK_ExpandedPolystyreneBoards | Identification - ID | Description: insulation - sound undercroft
A-FloorsSlabs A_BSUK_Slabs | MF | insulation - sound undercroft :2,SHE-02.MEZZANINE.dgn,Design Model:90020 | A_BSUK_ExpandedPolystyreneBoards | New Construction | A-FloorsSlabs::A_BSUK_ExpandedPolystyreneBoards | Identification - ID | Description: insulation - sound undercroft
A-FloorsSlabs A_BSUK_Slabs | MF | insulation - sound undercroft :2,SHE-02.MEZZANINE.dgn,Design Model:90021 | A_BSUK_ExpandedPolystyreneBoards | New Construction | A-FloorsSlabs::A_BSUK_ExpandedPolystyreneBoards | Identification - ID | Description: insulation - sound undercroft
A-FloorsSlabs A_BSUK_Slabs | MF | 2 ,SHE-02.MEZZANINE.dgn,Design Model:90026 | A_BSUK_Slabs | Existing to Remain
A-FloorsSlabs A_BSUK_Slabs | MF | 2 ,SHE-02.MEZZANINE.dgn,Design Model:90027 | A_BSUK_Slabs | Existing to Remain
A-FloorsSlabs A_BSUK_Slabs | MF | 2 ,SHE-02.MEZZANINE.dgn,Design Model:90028 | A_BSUK_Slabs | Existing to Remain
A-FloorsSlabs A_BSUK_Slabs | MF | 2 ,SHE-02.MEZZANINE.dgn,Design Model:90029 | A_BSUK_Slabs | Existing to Remain
A-FloorsSlabs A_BSUK_Slabs | MF | 2 ,SHE-02.MEZZANINE.dgn,Design Model:90030 | A_BSUK_Slabs | Existing to Remain
A-FloorsSlabs A_BSUK_Slabs | MF | 2 ,SHE-02.MEZZANINE.dgn,Design Model:111402 | A_BSUK_InternalFinishes_FloorScreed | Existing to Remain | A-FloorsSlabs::A_BSUK_InternalFinishes_FloorScreed
A-FloorsSlabs A_BSUK_Slabs | MF | 2 ,SHE-02.MEZZANINE.dgn,Design Model:111861 | A_BSUK_Parquet_Floor | New Construction | A-Finishes::A_BSUK_Parquet_Floor
A-FloorsSlabs A_BSUK_Slabs | MF | 2 ,SHE-02.MEZZANINE.dgn,Design Model:116897 | A_BSUK_Slabs | Existing to Remain
A-FloorsSlabs A_BSUK_Slabs | MF | 2 ,SHE-02.MEZZANINE.dgn,Design Model:117018 | A_BSUK_Slabs | Existing to Remain
A-FloorsSlabs A_BSUK_Slabs | MF | 2 ,SHE-02.MEZZANINE.dgn,Design Model:117055 | A_BSUK_Slabs | Existing to Remain
A-FloorsSlabs A_BSUK_Slabs | MF | 2 ,SHE-02.MEZZANINE.dgn,Design Model:117092 | A_BSUK_Slabs | Existing to Remain
A-FloorsSlabs A_BSUK_Slabs | MF | 2 ,SHE-02.MEZZANINE.dgn,Design Model:117258 | A_BSUK_Slabs | Existing to Remain
A-FloorsSlabs A_BSUK_Slabs | MF | insulation - sound undercroft :2,SHE-02.MEZZANINE.dgn,Design Model:119660 | A_BSUK_ExpandedPolystyreneBoards | New Construction | A-FloorsSlabs::A_BSUK_ExpandedPolystyreneBoards | Identification - ID | Description: insulation - sound undercroft
A-FloorsSlabs A_BSUK_Slabs | MF | 2 ,SHE-02.MEZZANINE.dgn,Design Model:127631 | A_BSUK_Ceramic_WallTiles |  | A-Finishes::A_BSUK_Ceramic_WallTiles
A-FloorsSlabs A_BSUK_Slabs | MF | 2 ,SHE-02.MEZZANINE.dgn,Design Model:127725 | A_BSUK_Ceramic_WallTiles |  | A-Finishes::A_BSUK_Ceramic_WallTiles
A-FloorsSlabs A_BSUK_Slabs | MF | 2 ,SHE-02.MEZZANINE.dgn,Design Model:145718 | A_BSUK_Carpet-Pile | New Construction | A-Finishes::A_BSUK_Carpet-Pile
A-FloorsSlabs A_BSUK_Slabs | MF | 2 ,SHE-02.MEZZANINE.dgn,Design Model:145759 | A_BSUK_Ceramic_FloorTiles | New Construction | A-Finishes::A_BSUK_Ceramic_FloorTiles
A-FloorsSlabs A_BSUK_Slabs | MF | 2 ,SHE-02.MEZZANINE.dgn,Design Model:148232 | A_BSUK_Timber_Miscellaneous |  | A-FrameElements::A_BSUK_Timber_Miscellaneous
A-FloorsSlabs A_BSUK_Slabs | MF | 2 ,SHE-02.MEZZANINE.dgn,Design Model:148352 | A_BSUK_Timber_Miscellaneous |  | A-FrameElements::A_BSUK_Timber_Miscellaneous
A-FloorsSlabs A_BSUK_Slabs | MF | 2 ,SHE-02.MEZZANINE.dgn,Design Model:148380 | A_BSUK_Timber_Miscellaneous |  | A-FrameElements::A_BSUK_Timber_Miscellaneous
A-FloorsSlabs A_BSUK_Slabs | MF | 2 ,SHE-02.MEZZANINE.dgn,Design Model:148421 | A_BSUK_Timber_Miscellaneous |  | A-FrameElements::A_BSUK_Timber_Miscellaneous
A-FloorsSlabs A_BSUK_Slabs | MF | 2 ,SHE-02.MEZZANINE.dgn,Design Model:148489 | A_BSUK_Timber_Miscellaneous |  | A-FrameElements::A_BSUK_Timber_Miscellaneous
A-FloorsSlabs A_BSUK_Slabs | MF | Celotex XR4000 :2,SHE-02.MEZZANINE.dgn,Design Model:148568 | A_BSUK_Insulation | New Construction | A-Walls::A_BSUK_Insulation | Identification - ID | Description: Celotex XR4000
A-FloorsSlabs A_BSUK_Slabs | MF | Deck (PLY) :2,SHE-02.MEZZANINE.dgn,Design Model:149582 | A_BSUK_Timber_Miscellaneous | New Construction | A-FrameElements::A_BSUK_Timber_Miscellaneous | Identification - ID | Description: Deck (PLY)
A-FloorsSlabs A_BSUK_Slabs | MF | single ply membrane or felt :2,SHE-02.MEZZANINE.dgn,Design Model:149695 | A_BSUK_Roofs | New Construction | A-Roofs::A_BSUK_Roofs | Identification - ID | Description: single ply membrane or felt
A-FloorsSlabs A_BSUK_Slabs | MF | 2 ,SHE-02.MEZZANINE.dgn,Design Model:149954 | A_BSUK_ExpandedPolystyreneBoards | Existing to Remain | A-FloorsSlabs::A_BSUK_ExpandedPolystyreneBoards
A-FloorsSlabs A_BSUK_Slabs | MF | insulation - sound undercroft rear :2,SHE-02.MEZZANINE.dgn ,Design Model:181350 | A_BSUK_ExpandedPolystyreneBoards | New Construction | A-FloorsSlabs::A_BSUK_ExpandedPolystyreneBoards | Identification - ID | Description: insulation - sound undercroft rear
A-FloorsSlabs A_BSUK_Slabs | MF | insulation - sound undercroft rear :2,SHE-02.MEZZANINE.dgn ,Design Model:181351 | A_BSUK_ExpandedPolystyreneBoards | New Construction | A-FloorsSlabs::A_BSUK_ExpandedPolystyreneBoards | Identification - ID | Description: insulation - sound undercroft rear
A-FloorsSlabs A_BSUK_Slabs | MF | insulation - sound undercroft rear :2,SHE-02.MEZZANINE.dgn ,Design Model:182230 | A_BSUK_ExpandedPolystyreneBoards | New Construction | A-FloorsSlabs::A_BSUK_ExpandedPolystyreneBoards | Identification - ID | Description: insulation - sound undercroft rear
A-FloorsSlabs A_BSUK_Slabs | MF | insulation - sound undercroft rear :2,SHE-02.MEZZANINE.dgn ,Design Model:182386 | A_BSUK_ExpandedPolystyreneBoards | New Construction | A-FloorsSlabs::A_BSUK_ExpandedPolystyreneBoards | Identification - ID | Description: insulation - sound undercroft rear
A-FloorsSlabs A_BSUK_Slabs | MF | insulation - sound undercroft rear :2,SHE-02.MEZZANINE.dgn ,Design Model:182453 | A_BSUK_ExpandedPolystyreneBoards | New Construction | A-FloorsSlabs::A_BSUK_ExpandedPolystyreneBoards | Identification - ID | Description: insulation - sound undercroft rear
A-FloorsSlabs A_BSUK_Slabs | MF | fire board - ceiling :2,SHE-02.MEZZANINE.dgn,Design Model:190283 | A_BSUK_CeilingSoffitFinishes_Suspended | New Construction | A-Ceilings::A_BSUK_CeilingSoffitFinishes_Suspended | Identification - ID | Description: fire board - ceiling
A-FloorsSlabs A_BSUK_Slabs | MF | ext. OSB panels :2,SHE-02.MEZZANINE.dgn,Design Model:190359 | A_BSUK_InternalFinishesCeilingOrSoffit | Existing to Remain | A-Ceilings::A_BSUK_InternalFinishesCeilingOrSoffit | Identification - ID | Description: ext. OSB panels
A-FloorsSlabs A_BSUK_Slabs | MF | dry screed board :2,SHE-02.MEZZANINE.dgn,Design Model:191699 | A_BSUK_InternalFinishes_FloorScreed | New Construction | A-FloorsSlabs::A_BSUK_InternalFinishes_FloorScreed | Identification - ID | Description: dry screed board
A-FloorsSlabs A_BSUK_Slabs | MF | fire board - ceiling :2,SHE-02.MEZZANINE.dgn,Design Model:193482 | A_BSUK_CeilingSoffitFinishes_Suspended | New Construction | A-Ceilings::A_BSUK_CeilingSoffitFinishes_Suspended | Identification - ID | Description: fire board - ceiling
A-FloorsSlabs A_BSUK_Slabs | 1F | shelving - bath :4,SHE-03.FIRST.dgn,Design Model:142164 | A_BSUK_Ceramic_WallTiles | New Construction | A-Finishes::A_BSUK_Ceramic_WallTiles | Identification - ID | Description: shelving - bath
A-FloorsSlabs A_BSUK_Slabs | 1F | shelving - bath :4,SHE-03.FIRST.dgn,Design Model:142179 | A_BSUK_Ceramic_WallTiles | New Construction | A-Finishes::A_BSUK_Ceramic_WallTiles | Identification - ID | Description: shelving - bath
A-FloorsSlabs A_BSUK_Slabs | 1F | shelving - bath :4,SHE-03.FIRST.dgn,Design Model:142194 | A_BSUK_Ceramic_WallTiles | New Construction | A-Finishes::A_BSUK_Ceramic_WallTiles | Identification - ID | Description: shelving - bath
A-FloorsSlabs A_BSUK_Slabs | 1F | shelving - bath :4,SHE-03.FIRST.dgn,Design Model:300477 | A_BSUK_Ceramic_WallTiles | New Construction | A-Finishes::A_BSUK_Ceramic_WallTiles | Identification - ID | Description: shelving - bath
A-FloorsSlabs A_BSUK_Slabs | 1F | shelving - bath :4,SHE-03.FIRST.dgn,Design Model:300491 | A_BSUK_Ceramic_WallTiles | New Construction | A-Finishes::A_BSUK_Ceramic_WallTiles | Identification - ID | Description: shelving - bath
A-FloorsSlabs A_BSUK_Slabs | 1F | shelving - bath :4,SHE-03.FIRST.dgn,Design Model:300505 | A_BSUK_Ceramic_WallTiles | New Construction | A-Finishes::A_BSUK_Ceramic_WallTiles | Identification - ID | Description: shelving - bath
A-FloorsSlabs A_BSUK_Slabs | 1F | shelving - bath :4,SHE-03.FIRST.dgn,Design Model:327204 | A_BSUK_Ceramic_WallTiles | New Construction | A-Finishes::A_BSUK_Ceramic_WallTiles | Identification - ID | Description: shelving - bath
A-FloorsSlabs A_BSUK_Slabs | 1F | 4 ,SHE-03.FIRST.dgn,Design Model:134765 | A_BSUK_CeilingSoffitFinishes_Suspended | New Construction | A-Ceilings::A_BSUK_CeilingSoffitFinishes_Suspended | Fire Resistance - Fire | Rating: FD60
A-FloorsSlabs A_BSUK_Slabs | 1F | 4 ,SHE-03.FIRST.dgn,Design Model:134792 | A_BSUK_CeilingSoffitFinishes_Suspended | New Construction | A-Ceilings::A_BSUK_CeilingSoffitFinishes_Suspended | Fire Resistance - Fire | Rating: FD60
A-FloorsSlabs A_BSUK_Slabs | 1F | 4 ,SHE-03.FIRST.dgn,Design Model:134816 | A_BSUK_CeilingSoffitFinishes_Suspended | New Construction | A-Ceilings::A_BSUK_CeilingSoffitFinishes_Suspended | Fire Resistance - Fire | Rating: FD60
A-FloorsSlabs A_BSUK_Slabs | 1F | 4 ,SHE-03.FIRST.dgn,Design Model:134859 | A_BSUK_InternalFinishes_FloorScreed | New Construction | A-FloorsSlabs::A_BSUK_InternalFinishes_FloorScreed
A-FloorsSlabs A_BSUK_Slabs | 1F | 4 ,SHE-03.FIRST.dgn,Design Model:134860 | A_BSUK_InternalFinishes_FloorScreed | New Construction | A-FloorsSlabs::A_BSUK_InternalFinishes_FloorScreed
A-FloorsSlabs A_BSUK_Slabs | 1F | 4 ,SHE-03.FIRST.dgn,Design Model:135695 | A_BSUK_Ceramic_WallTiles | New Construction | A-Finishes::A_BSUK_Ceramic_WallTiles
A-FloorsSlabs A_BSUK_Slabs | 1F | 4 ,SHE-03.FIRST.dgn,Design Model:135710 | A_BSUK_Ceramic_WallTiles | New Construction | A-Finishes::A_BSUK_Ceramic_WallTiles
A-FloorsSlabs A_BSUK_Slabs | 1F | 4 ,SHE-03.FIRST.dgn,Design Model:135725 | A_BSUK_Ceramic_WallTiles | New Construction | A-Finishes::A_BSUK_Ceramic_WallTiles
A-FloorsSlabs A_BSUK_Slabs | 1F | 4 ,SHE-03.FIRST.dgn,Design Model:135770 | A_BSUK_Ceramic_WallTiles | New Construction | A-Finishes::A_BSUK_Ceramic_WallTiles
A-FloorsSlabs A_BSUK_Slabs | 1F | 4 ,SHE-03.FIRST.dgn,Design Model:142049 | A_BSUK_InternalFinishes_FloorScreed | Existing to Remain | A-FloorsSlabs::A_BSUK_InternalFinishes_FloorScreed
A-FloorsSlabs A_BSUK_Slabs | 1F | 4 ,SHE-03.FIRST.dgn,Design Model:143321 | A_BSUK_Ceramic_WallTiles | New Construction | A-Finishes::A_BSUK_Ceramic_WallTiles
A-FloorsSlabs A_BSUK_Slabs | 1F | 4 ,SHE-03.FIRST.dgn,Design Model:143864 | A_BSUK_ExpandedPolystyreneBoards | New Construction | A-FloorsSlabs::A_BSUK_ExpandedPolystyreneBoards
A-FloorsSlabs A_BSUK_Slabs | 1F | 4 ,SHE-03.FIRST.dgn,Design Model:143891 | A_BSUK_ExpandedPolystyreneBoards | New Construction | A-FloorsSlabs::A_BSUK_ExpandedPolystyreneBoards
A-FloorsSlabs A_BSUK_Slabs | 1F | 4 ,SHE-03.FIRST.dgn,Design Model:143969 | A_BSUK_ExpandedPolystyreneBoards | New Construction | A-FloorsSlabs::A_BSUK_ExpandedPolystyreneBoards
A-FloorsSlabs A_BSUK_Slabs | 1F | 4 ,SHE-03.FIRST.dgn,Design Model:144064 | A_BSUK_ExpandedPolystyreneBoards | New Construction | A-FloorsSlabs::A_BSUK_ExpandedPolystyreneBoards
A-FloorsSlabs A_BSUK_Slabs | 1F | 4 ,SHE-03.FIRST.dgn,Design Model:144148 | A_BSUK_ExpandedPolystyreneBoards | New Construction | A-FloorsSlabs::A_BSUK_ExpandedPolystyreneBoards
A-FloorsSlabs A_BSUK_Slabs | 1F | 4 ,SHE-03.FIRST.dgn,Design Model:144277 | A_BSUK_ExpandedPolystyreneBoards | New Construction | A-FloorsSlabs::A_BSUK_ExpandedPolystyreneBoards
A-FloorsSlabs A_BSUK_Slabs | 1F | 4 ,SHE-03.FIRST.dgn,Design Model:144370 | A_BSUK_ExpandedPolystyreneBoards | New Construction | A-FloorsSlabs::A_BSUK_ExpandedPolystyreneBoards
A-FloorsSlabs A_BSUK_Slabs | 1F | 4 ,SHE-03.FIRST.dgn,Design Model:144454 | A_BSUK_ExpandedPolystyreneBoards | New Construction | A-FloorsSlabs::A_BSUK_ExpandedPolystyreneBoards
A-FloorsSlabs A_BSUK_Slabs | 1F | 4 ,SHE-03.FIRST.dgn,Design Model:144538 | A_BSUK_ExpandedPolystyreneBoards | New Construction | A-FloorsSlabs::A_BSUK_ExpandedPolystyreneBoards
A-FloorsSlabs A_BSUK_Slabs | 1F | 4 ,SHE-03.FIRST.dgn,Design Model:144628 | A_BSUK_ExpandedPolystyreneBoards | New Construction | A-FloorsSlabs::A_BSUK_ExpandedPolystyreneBoards
A-FloorsSlabs A_BSUK_Slabs | 1F | 4 ,SHE-03.FIRST.dgn,Design Model:144629 | A_BSUK_Parquet_Floor |  | A-Finishes::A_BSUK_Parquet_Floor
A-FloorsSlabs A_BSUK_Slabs | 1F | 4 ,SHE-03.FIRST.dgn,Design Model:144740 | A_BSUK_Carpet-Pile | New Construction | A-Finishes::A_BSUK_Carpet-Pile
A-FloorsSlabs A_BSUK_Slabs | 1F | 4 ,SHE-03.FIRST.dgn,Design Model:144773 | A_BSUK_Ceramic_FloorTiles |  | A-Finishes::A_BSUK_Ceramic_FloorTiles
A-FloorsSlabs A_BSUK_Slabs | 1F | 4 ,SHE-03.FIRST.dgn,Design Model:144788 | A_BSUK_Parquet_Floor |  | A-Finishes::A_BSUK_Parquet_Floor
A-FloorsSlabs A_BSUK_Slabs | 1F | 4 ,SHE-03.FIRST.dgn,Design Model:144899 | A_BSUK_Parquet_Floor |  | A-Finishes::A_BSUK_Parquet_Floor
A-FloorsSlabs A_BSUK_Slabs | 1F | 4 ,SHE-03.FIRST.dgn,Design Model:144914 | A_BSUK_Carpet-Pile |  | A-Finishes::A_BSUK_Carpet-Pile
A-FloorsSlabs A_BSUK_Slabs | 1F | 4 ,SHE-03.FIRST.dgn,Design Model:144959 | A_BSUK_Ceramic_FloorTiles |  | A-Finishes::A_BSUK_Ceramic_FloorTiles
A-FloorsSlabs A_BSUK_Slabs | 1F | 4 ,SHE-03.FIRST.dgn,Design Model:144974 | A_BSUK_Parquet_Floor |  | A-Finishes::A_BSUK_Parquet_Floor
A-FloorsSlabs A_BSUK_Slabs | 1F | 4 ,SHE-03.FIRST.dgn,Design Model:145109 | A_BSUK_Ceramic_FloorTiles |  | A-Finishes::A_BSUK_Ceramic_FloorTiles
A-FloorsSlabs A_BSUK_Slabs | 1F | 4 ,SHE-03.FIRST.dgn,Design Model:145124 | A_BSUK_Carpet-Pile |  | A-Finishes::A_BSUK_Carpet-Pile
A-FloorsSlabs A_BSUK_Slabs | 1F | 4 ,SHE-03.FIRST.dgn,Design Model:145163 | A_BSUK_Carpet-Pile |  | A-Finishes::A_BSUK_Carpet-Pile
A-FloorsSlabs A_BSUK_Slabs | 1F | 4 ,SHE-03.FIRST.dgn,Design Model:145196 | A_BSUK_Parquet_Floor |  | A-Finishes::A_BSUK_Parquet_Floor
A-FloorsSlabs A_BSUK_Slabs | 1F | 4 ,SHE-03.FIRST.dgn,Design Model:145313 | A_BSUK_Ceramic_FloorTiles |  | A-Finishes::A_BSUK_Ceramic_FloorTiles
A-FloorsSlabs A_BSUK_Slabs | 1F | 4 ,SHE-03.FIRST.dgn,Design Model:145328 | A_BSUK_Parquet_Floor |  | A-Finishes::A_BSUK_Parquet_Floor
A-FloorsSlabs A_BSUK_Slabs | 1F | 4 ,SHE-03.FIRST.dgn,Design Model:145427 | A_BSUK_Ceramic_FloorTiles |  | A-Finishes::A_BSUK_Ceramic_FloorTiles
A-FloorsSlabs A_BSUK_Slabs | 1F | 4 ,SHE-03.FIRST.dgn,Design Model:145448 | A_BSUK_Carpet-Pile |  | A-Finishes::A_BSUK_Carpet-Pile
A-FloorsSlabs A_BSUK_Slabs | 1F | 4 ,SHE-03.FIRST.dgn,Design Model:145631 | A_BSUK_Parquet_Floor |  | A-Finishes::A_BSUK_Parquet_Floor
A-FloorsSlabs A_BSUK_Slabs | 1F | 4 ,SHE-03.FIRST.dgn,Design Model:145632 | A_BSUK_Ceramic_FloorTiles |  | A-Finishes::A_BSUK_Ceramic_FloorTiles
A-FloorsSlabs A_BSUK_Slabs | 1F | 4 ,SHE-03.FIRST.dgn,Design Model:145633 | A_BSUK_Carpet-Pile |  | A-Finishes::A_BSUK_Carpet-Pile
A-FloorsSlabs A_BSUK_Slabs | 1F | 4 ,SHE-03.FIRST.dgn,Design Model:145634 | A_BSUK_Parquet_Floor |  | A-Finishes::A_BSUK_Parquet_Floor
A-FloorsSlabs A_BSUK_Slabs | 1F | 4 ,SHE-03.FIRST.dgn,Design Model:145739 | A_BSUK_Ceramic_FloorTiles |  | A-Finishes::A_BSUK_Ceramic_FloorTiles
A-FloorsSlabs A_BSUK_Slabs | 1F | 4 ,SHE-03.FIRST.dgn,Design Model:145754 | A_BSUK_Carpet-Pile | New Construction | A-Finishes::A_BSUK_Carpet-Pile
A-FloorsSlabs A_BSUK_Slabs | 1F | 4 ,SHE-03.FIRST.dgn,Design Model:145787 | A_BSUK_Carpet-Pile |  | A-Finishes::A_BSUK_Carpet-Pile
A-FloorsSlabs A_BSUK_Slabs | 1F | 4 ,SHE-03.FIRST.dgn,Design Model:145826 | A_BSUK_Carpet-Pile |  | A-Finishes::A_BSUK_Carpet-Pile
A-FloorsSlabs A_BSUK_Slabs | 1F | 4 ,SHE-03.FIRST.dgn,Design Model:145862 | A_BSUK_Carpet-Pile |  | A-Finishes::A_BSUK_Carpet-Pile
A-FloorsSlabs A_BSUK_Slabs | 1F | 4 ,SHE-03.FIRST.dgn,Design Model:145967 | A_BSUK_Carpet-Pile |  | A-Finishes::A_BSUK_Carpet-Pile
A-FloorsSlabs A_BSUK_Slabs | 1F | 4 ,SHE-03.FIRST.dgn,Design Model:154694 | A_BSUK_CeilingSoffitFinishes_Suspended | New Construction | A-Ceilings::A_BSUK_CeilingSoffitFinishes_Suspended
A-FloorsSlabs A_BSUK_Slabs | 1F | 4 ,SHE-03.FIRST.dgn,Design Model:154742 | A_BSUK_CeilingSoffitFinishes_Suspended |  | A-Ceilings::A_BSUK_CeilingSoffitFinishes_Suspended
A-FloorsSlabs A_BSUK_Slabs | 1F | 4 ,SHE-03.FIRST.dgn,Design Model:155063 | A_BSUK_CeilingSoffitFinishes_Suspended |  | A-Ceilings::A_BSUK_CeilingSoffitFinishes_Suspended
A-FloorsSlabs A_BSUK_Slabs | 1F | dropped ceiling :4,SHE-03.FIRST.dgn,Design Model:155064 | A_BSUK_CeilingSoffitFinishes_Suspended | New Construction | A-Ceilings::A_BSUK_CeilingSoffitFinishes_Suspended | Identification - ID | Description: dropped ceiling
A-FloorsSlabs A_BSUK_Slabs | 1F | 4 ,SHE-03.FIRST.dgn,Design Model:155065 | A_BSUK_CeilingSoffitFinishes_Suspended |  | A-Ceilings::A_BSUK_CeilingSoffitFinishes_Suspended
A-FloorsSlabs A_BSUK_Slabs | 1F | 4 ,SHE-03.FIRST.dgn,Design Model:155066 | A_BSUK_CeilingSoffitFinishes_Suspended |  | A-Ceilings::A_BSUK_CeilingSoffitFinishes_Suspended
A-FloorsSlabs A_BSUK_Slabs | 1F | 4 ,SHE-03.FIRST.dgn,Design Model:155067 | A_BSUK_CeilingSoffitFinishes_Suspended |  | A-Ceilings::A_BSUK_CeilingSoffitFinishes_Suspended
A-FloorsSlabs A_BSUK_Slabs | 1F | 4 ,SHE-03.FIRST.dgn,Design Model:155068 | A_BSUK_CeilingSoffitFinishes_Suspended |  | A-Ceilings::A_BSUK_CeilingSoffitFinishes_Suspended
A-FloorsSlabs A_BSUK_Slabs | 1F | 4 ,SHE-03.FIRST.dgn,Design Model:155069 | A_BSUK_CeilingSoffitFinishes_Suspended |  | A-Ceilings::A_BSUK_CeilingSoffitFinishes_Suspended
A-FloorsSlabs A_BSUK_Slabs | 1F | 4 ,SHE-03.FIRST.dgn,Design Model:155084 | A_BSUK_CeilingSoffitFinishes_Suspended |  | A-Ceilings::A_BSUK_CeilingSoffitFinishes_Suspended
A-FloorsSlabs A_BSUK_Slabs | 1F | 4 ,SHE-03.FIRST.dgn,Design Model:155099 | A_BSUK_CeilingSoffitFinishes_Suspended |  | A-Ceilings::A_BSUK_CeilingSoffitFinishes_Suspended
A-FloorsSlabs A_BSUK_Slabs | 1F | 4 ,SHE-03.FIRST.dgn,Design Model:155370 | A_BSUK_CeilingSoffitFinishes_Suspended |  | A-Ceilings::A_BSUK_CeilingSoffitFinishes_Suspended
A-FloorsSlabs A_BSUK_Slabs | 1F | 4 ,SHE-03.FIRST.dgn,Design Model:155371 | A_BSUK_CeilingSoffitFinishes_Suspended |  | A-Ceilings::A_BSUK_CeilingSoffitFinishes_Suspended
A-FloorsSlabs A_BSUK_Slabs | 1F | 4 ,SHE-03.FIRST.dgn,Design Model:155619 | A_BSUK_CeilingSoffitFinishes_Suspended | New Construction | A-Ceilings::A_BSUK_CeilingSoffitFinishes_Suspended
A-FloorsSlabs A_BSUK_Slabs | 1F | 4 ,SHE-03.FIRST.dgn,Design Model:155620 | A_BSUK_CeilingSoffitFinishes_Suspended |  | A-Ceilings::A_BSUK_CeilingSoffitFinishes_Suspended
A-FloorsSlabs A_BSUK_Slabs | 1F | 4 ,SHE-03.FIRST.dgn,Design Model:155621 | A_BSUK_CeilingSoffitFinishes_Suspended | New Construction | A-Ceilings::A_BSUK_CeilingSoffitFinishes_Suspended
A-FloorsSlabs A_BSUK_Slabs | 1F | 4 ,SHE-03.FIRST.dgn,Design Model:155622 | A_BSUK_CeilingSoffitFinishes_Suspended | New Construction | A-Ceilings::A_BSUK_CeilingSoffitFinishes_Suspended
A-FloorsSlabs A_BSUK_Slabs | 1F | 4 ,SHE-03.FIRST.dgn,Design Model:155623 | A_BSUK_CeilingSoffitFinishes_Suspended | New Construction | A-Ceilings::A_BSUK_CeilingSoffitFinishes_Suspended
A-FloorsSlabs A_BSUK_Slabs | 1F | 4 ,SHE-03.FIRST.dgn,Design Model:155624 | A_BSUK_CeilingSoffitFinishes_Suspended |  | A-Ceilings::A_BSUK_CeilingSoffitFinishes_Suspended
A-FloorsSlabs A_BSUK_Slabs | 1F | 4 ,SHE-03.FIRST.dgn,Design Model:155626 | A_BSUK_CeilingSoffitFinishes_Suspended | New Construction | A-Ceilings::A_BSUK_CeilingSoffitFinishes_Suspended
A-FloorsSlabs A_BSUK_Slabs | 1F | 4 ,SHE-03.FIRST.dgn,Design Model:220881 | A_BSUK_CeilingSoffitFinishes_Suspended |  | A-Ceilings::A_BSUK_CeilingSoffitFinishes_Suspended
A-FloorsSlabs A_BSUK_Slabs | 1F | 4 ,SHE-03.FIRST.dgn,Design Model:220882 | A_BSUK_CeilingSoffitFinishes_Suspended | New Construction | A-Ceilings::A_BSUK_CeilingSoffitFinishes_Suspended
A-FloorsSlabs A_BSUK_Slabs | 1F | 4 ,SHE-03.FIRST.dgn,Design Model:220883 | A_BSUK_CeilingSoffitFinishes_Suspended | New Construction | A-Ceilings::A_BSUK_CeilingSoffitFinishes_Suspended
A-FloorsSlabs A_BSUK_Slabs | 1F | 4 ,SHE-03.FIRST.dgn,Design Model:229439 | A_BSUK_Ceramic_WallTiles | New Construction | A-Finishes::A_BSUK_Ceramic_WallTiles
A-FloorsSlabs A_BSUK_Slabs | 1F | 4 ,SHE-03.FIRST.dgn,Design Model:232461 | A_BSUK_Ceramic_FloorTiles |  | A-Finishes::A_BSUK_Ceramic_FloorTiles
A-FloorsSlabs A_BSUK_Slabs | 1F | 4 ,SHE-03.FIRST.dgn,Design Model:270352 | A_BSUK_Ceramic_WallTiles | New Construction | A-Finishes::A_BSUK_Ceramic_WallTiles
A-FloorsSlabs A_BSUK_Slabs | 1F | 4 ,SHE-03.FIRST.dgn,Design Model:270751 | A_BSUK_Ceramic_WallTiles | New Construction | A-Finishes::A_BSUK_Ceramic_WallTiles
A-FloorsSlabs A_BSUK_Slabs | 1F | shelving - bath :4,SHE-03.FIRST.dgn,Design Model:277457 | A_BSUK_Ceramic_WallTiles | New Construction | A-Finishes::A_BSUK_Ceramic_WallTiles | Identification - ID | Description: shelving - bath
A-FloorsSlabs A_BSUK_Slabs | 1F | shelving - bath :4,SHE-03.FIRST.dgn,Design Model:280881 | A_BSUK_Ceramic_WallTiles | New Construction | A-Finishes::A_BSUK_Ceramic_WallTiles | Identification - ID | Description: shelving - bath
A-FloorsSlabs A_BSUK_Slabs | 1F | 4 ,SHE-03.FIRST.dgn,Design Model:282366 | A_BSUK_Ceramic_WallTiles | New Construction | A-Finishes::A_BSUK_Ceramic_WallTiles
A-FloorsSlabs A_BSUK_Slabs | 1F | shelving - window :4,SHE-03.FIRST.dgn,Design Model:295592 | A_BSUK_Timber_Miscellaneous | New Construction | A-FrameElements::A_BSUK_Timber_Miscellaneous | Identification - ID | Description: shelving - window
A-FloorsSlabs A_BSUK_Slabs | 1F | shelving - window :4,SHE-03.FIRST.dgn,Design Model:295737 | A_BSUK_Timber_Miscellaneous | New Construction | A-FrameElements::A_BSUK_Timber_Miscellaneous | Identification - ID | Description: shelving - window
A-FloorsSlabs A_BSUK_Slabs | 1F | shelving - window :4,SHE-03.FIRST.dgn,Design Model:295765 | A_BSUK_Timber_Miscellaneous | New Construction | A-FrameElements::A_BSUK_Timber_Miscellaneous | Identification - ID | Description: shelving - window
A-FloorsSlabs A_BSUK_Slabs | 1F | shelving - window :4,SHE-03.FIRST.dgn,Design Model:295793 | A_BSUK_Timber_Miscellaneous | New Construction | A-FrameElements::A_BSUK_Timber_Miscellaneous | Identification - ID | Description: shelving - window
A-FloorsSlabs A_BSUK_Slabs | 1F | shelving - window :4,SHE-03.FIRST.dgn,Design Model:295847 | A_BSUK_Timber_Miscellaneous | New Construction | A-FrameElements::A_BSUK_Timber_Miscellaneous | Identification - ID | Description: shelving - window
A-FloorsSlabs A_BSUK_Slabs | 1F | shelving - window :4,SHE-03.FIRST.dgn,Design Model:295875 | A_BSUK_Timber_Miscellaneous | New Construction | A-FrameElements::A_BSUK_Timber_Miscellaneous | Identification - ID | Description: shelving - window
A-FloorsSlabs A_BSUK_Slabs | 1F | shelving - window :4,SHE-03.FIRST.dgn,Design Model:295903 | A_BSUK_Timber_Miscellaneous | New Construction | A-FrameElements::A_BSUK_Timber_Miscellaneous | Identification - ID | Description: shelving - window
A-FloorsSlabs A_BSUK_Slabs | 1F | shelving - window :4,SHE-03.FIRST.dgn,Design Model:296022 | A_BSUK_Timber_Miscellaneous | New Construction | A-FrameElements::A_BSUK_Timber_Miscellaneous | Identification - ID | Description: shelving - window
A-FloorsSlabs A_BSUK_Slabs | 1F | shelving - window :4,SHE-03.FIRST.dgn,Design Model:296050 | A_BSUK_Timber_Miscellaneous | New Construction | A-FrameElements::A_BSUK_Timber_Miscellaneous | Identification - ID | Description: shelving - window
A-FloorsSlabs A_BSUK_Slabs | 1F | shelving - window :4,SHE-03.FIRST.dgn,Design Model:321361 | A_BSUK_Timber_Miscellaneous | New Construction | A-FrameElements::A_BSUK_Timber_Miscellaneous | Identification - ID | Description: shelving - window
A-FloorsSlabs A_BSUK_Slabs | 1F | fire board - ceiling :4,SHE-03.FIRST.dgn,Design Model:409334 | A_BSUK_CeilingSoffitFinishes_Suspended | New Construction | A-Ceilings::A_BSUK_CeilingSoffitFinishes_Suspended | Identification - ID | Description: fire board - ceiling
A-FloorsSlabs A_BSUK_Slabs | 1F | fire board - ceiling :4,SHE-03.FIRST.dgn,Design Model:409441 | A_BSUK_CeilingSoffitFinishes_Suspended | New Construction | A-Ceilings::A_BSUK_CeilingSoffitFinishes_Suspended | Identification - ID | Description: fire board - ceiling
A-FloorsSlabs A_BSUK_Slabs | 1F | fire board - ceiling :4,SHE-03.FIRST.dgn,Design Model:409495 | A_BSUK_CeilingSoffitFinishes_Suspended | New Construction | A-Ceilings::A_BSUK_CeilingSoffitFinishes_Suspended | Identification - ID | Description: fire board - ceiling
A-FloorsSlabs A_BSUK_Slabs | 1F | fire board - ceiling :4,SHE-03.FIRST.dgn,Design Model:409536 | A_BSUK_CeilingSoffitFinishes_Suspended | New Construction | A-Ceilings::A_BSUK_CeilingSoffitFinishes_Suspended | Identification - ID | Description: fire board - ceiling
A-FloorsSlabs A_BSUK_Slabs | 1F | fire board - ceiling :4,SHE-03.FIRST.dgn,Design Model:409577 | A_BSUK_CeilingSoffitFinishes_Suspended | New Construction | A-Ceilings::A_BSUK_CeilingSoffitFinishes_Suspended | Identification - ID | Description: fire board - ceiling
A-FloorsSlabs A_BSUK_Slabs | 1F | fire board - ceiling :4,SHE-03.FIRST.dgn,Design Model:409762 | A_BSUK_CeilingSoffitFinishes_Suspended | New Construction | A-Ceilings::A_BSUK_CeilingSoffitFinishes_Suspended | Identification - ID | Description: fire board - ceiling
A-FloorsSlabs A_BSUK_Slabs | 1F | fire board - ceiling :4,SHE-03.FIRST.dgn,Design Model:409763 | A_BSUK_CeilingSoffitFinishes_Suspended | New Construction | A-Ceilings::A_BSUK_CeilingSoffitFinishes_Suspended | Identification - ID | Description: fire board - ceiling
A-FloorsSlabs A_BSUK_Slabs | 1F | fire board - ceiling :4,SHE-03.FIRST.dgn,Design Model:409843 | A_BSUK_CeilingSoffitFinishes_Suspended | New Construction | A-Ceilings::A_BSUK_CeilingSoffitFinishes_Suspended | Identification - ID | Description: fire board - ceiling
A-FloorsSlabs A_BSUK_Slabs | 1F | fire board - ceiling :4,SHE-03.FIRST.dgn,Design Model:409884 | A_BSUK_CeilingSoffitFinishes_Suspended | New Construction | A-Ceilings::A_BSUK_CeilingSoffitFinishes_Suspended | Identification - ID | Description: fire board - ceiling
A-FloorsSlabs A_BSUK_Slabs | 1F | fire board - ceiling :4,SHE-03.FIRST.dgn,Design Model:409925 | A_BSUK_CeilingSoffitFinishes_Suspended | New Construction | A-Ceilings::A_BSUK_CeilingSoffitFinishes_Suspended | Identification - ID | Description: fire board - ceiling
A-FloorsSlabs A_BSUK_Slabs | 1F | fire board - ceiling :4,SHE-03.FIRST.dgn,Design Model:412315 | A_BSUK_CeilingSoffitFinishes_Suspended | New Construction | A-Ceilings::A_BSUK_CeilingSoffitFinishes_Suspended | Identification - ID | Description: fire board - ceiling
A-FloorsSlabs A_BSUK_Slabs | 1F | fire board - ceiling :4,SHE-03.FIRST.dgn,Design Model:412330 | A_BSUK_CeilingSoffitFinishes_Suspended | New Construction | A-Ceilings::A_BSUK_CeilingSoffitFinishes_Suspended | Identification - ID | Description: fire board - ceiling
A-FloorsSlabs A_BSUK_Slabs | 1F | fire board - ceiling :4,SHE-03.FIRST.dgn,Design Model:412345 | A_BSUK_CeilingSoffitFinishes_Suspended | New Construction | A-Ceilings::A_BSUK_CeilingSoffitFinishes_Suspended | Identification - ID | Description: fire board - ceiling
A-FloorsSlabs A_BSUK_Slabs | 1F | fire board - ceiling :4,SHE-03.FIRST.dgn,Design Model:412360 | A_BSUK_CeilingSoffitFinishes_Suspended | New Construction | A-Ceilings::A_BSUK_CeilingSoffitFinishes_Suspended | Identification - ID | Description: fire board - ceiling
A-FloorsSlabs A_BSUK_Slabs | 1F | fire board - ceiling :4,SHE-03.FIRST.dgn,Design Model:412375 | A_BSUK_CeilingSoffitFinishes_Suspended | New Construction | A-Ceilings::A_BSUK_CeilingSoffitFinishes_Suspended | Identification - ID | Description: fire board - ceiling
A-FloorsSlabs A_BSUK_Slabs | 1F | fire board - ceiling :4,SHE-03.FIRST.dgn,Design Model:412404 | A_BSUK_CeilingSoffitFinishes_Suspended | New Construction | A-Ceilings::A_BSUK_CeilingSoffitFinishes_Suspended | Identification - ID | Description: fire board - ceiling
A-FloorsSlabs A_BSUK_Slabs | 1F | fire board - ceiling :4,SHE-03.FIRST.dgn,Design Model:412405 | A_BSUK_CeilingSoffitFinishes_Suspended | New Construction | A-Ceilings::A_BSUK_CeilingSoffitFinishes_Suspended | Identification - ID | Description: fire board - ceiling
A-FloorsSlabs A_BSUK_Slabs | 1F | fire board - ceiling :4,SHE-03.FIRST.dgn,Design Model:412420 | A_BSUK_CeilingSoffitFinishes_Suspended | New Construction | A-Ceilings::A_BSUK_CeilingSoffitFinishes_Suspended | Identification - ID | Description: fire board - ceiling
A-FloorsSlabs A_BSUK_Slabs | 1F | fire board - ceiling :4,SHE-03.FIRST.dgn,Design Model:412435 | A_BSUK_CeilingSoffitFinishes_Suspended | New Construction | A-Ceilings::A_BSUK_CeilingSoffitFinishes_Suspended | Identification - ID | Description: fire board - ceiling
A-FloorsSlabs A_BSUK_Slabs | 1F | fire board - ceiling :4,SHE-03.FIRST.dgn,Design Model:412450 | A_BSUK_CeilingSoffitFinishes_Suspended | New Construction | A-Ceilings::A_BSUK_CeilingSoffitFinishes_Suspended | Identification - ID | Description: fire board - ceiling
A-FloorsSlabs A_BSUK_Slabs | 3F | shelving - bath :6,SHE-05.THIRD.dgn,Design Model:142164 | A_BSUK_Ceramic_WallTiles | New Construction | A-Finishes::A_BSUK_Ceramic_WallTiles | Identification - ID | Description: shelving - bath
A-FloorsSlabs A_BSUK_Slabs | 3F | shelving - bath :6,SHE-05.THIRD.dgn,Design Model:142179 | A_BSUK_Ceramic_WallTiles | New Construction | A-Finishes::A_BSUK_Ceramic_WallTiles | Identification - ID | Description: shelving - bath
A-FloorsSlabs A_BSUK_Slabs | 3F | shelving - bath :6,SHE-05.THIRD.dgn,Design Model:142194 | A_BSUK_Ceramic_WallTiles | New Construction | A-Finishes::A_BSUK_Ceramic_WallTiles | Identification - ID | Description: shelving - bath
A-FloorsSlabs A_BSUK_Slabs | 3F | shelving - bath :6,SHE-05.THIRD.dgn,Design Model:300477 | A_BSUK_Ceramic_WallTiles | New Construction | A-Finishes::A_BSUK_Ceramic_WallTiles | Identification - ID | Description: shelving - bath
A-FloorsSlabs A_BSUK_Slabs | 3F | shelving - bath :6,SHE-05.THIRD.dgn,Design Model:300491 | A_BSUK_Ceramic_WallTiles | New Construction | A-Finishes::A_BSUK_Ceramic_WallTiles | Identification - ID | Description: shelving - bath
A-FloorsSlabs A_BSUK_Slabs | 3F | shelving - bath :6,SHE-05.THIRD.dgn,Design Model:300505 | A_BSUK_Ceramic_WallTiles | New Construction | A-Finishes::A_BSUK_Ceramic_WallTiles | Identification - ID | Description: shelving - bath
A-FloorsSlabs A_BSUK_Slabs | 3F | shelving - bath :6,SHE-05.THIRD.dgn,Design Model:327204 | A_BSUK_Ceramic_WallTiles | New Construction | A-Finishes::A_BSUK_Ceramic_WallTiles | Identification - ID | Description: shelving - bath
A-FloorsSlabs A_BSUK_Slabs | 3F | 6 ,SHE-05.THIRD.dgn,Design Model:134859 | A_BSUK_InternalFinishes_FloorScreed | New Construction | A-FloorsSlabs::A_BSUK_InternalFinishes_FloorScreed
A-FloorsSlabs A_BSUK_Slabs | 3F | 6 ,SHE-05.THIRD.dgn,Design Model:134860 | A_BSUK_InternalFinishes_FloorScreed | New Construction | A-FloorsSlabs::A_BSUK_InternalFinishes_FloorScreed
A-FloorsSlabs A_BSUK_Slabs | 3F | 6 ,SHE-05.THIRD.dgn,Design Model:135695 | A_BSUK_Ceramic_WallTiles | New Construction | A-Finishes::A_BSUK_Ceramic_WallTiles
A-FloorsSlabs A_BSUK_Slabs | 3F | 6 ,SHE-05.THIRD.dgn,Design Model:135710 | A_BSUK_Ceramic_WallTiles | New Construction | A-Finishes::A_BSUK_Ceramic_WallTiles
A-FloorsSlabs A_BSUK_Slabs | 3F | 6 ,SHE-05.THIRD.dgn,Design Model:135725 | A_BSUK_Ceramic_WallTiles | New Construction | A-Finishes::A_BSUK_Ceramic_WallTiles
A-FloorsSlabs A_BSUK_Slabs | 3F | 6 ,SHE-05.THIRD.dgn,Design Model:135770 | A_BSUK_Ceramic_WallTiles | New Construction | A-Finishes::A_BSUK_Ceramic_WallTiles
A-FloorsSlabs A_BSUK_Slabs | 3F | 6 ,SHE-05.THIRD.dgn,Design Model:142049 | A_BSUK_InternalFinishes_FloorScreed | Existing to Remain | A-FloorsSlabs::A_BSUK_InternalFinishes_FloorScreed
A-FloorsSlabs A_BSUK_Slabs | 3F | 6 ,SHE-05.THIRD.dgn,Design Model:143321 | A_BSUK_Ceramic_WallTiles | New Construction | A-Finishes::A_BSUK_Ceramic_WallTiles
A-FloorsSlabs A_BSUK_Slabs | 3F | 6 ,SHE-05.THIRD.dgn,Design Model:143864 | A_BSUK_ExpandedPolystyreneBoards | New Construction | A-FloorsSlabs::A_BSUK_ExpandedPolystyreneBoards
A-FloorsSlabs A_BSUK_Slabs | 3F | 6 ,SHE-05.THIRD.dgn,Design Model:143891 | A_BSUK_ExpandedPolystyreneBoards | New Construction | A-FloorsSlabs::A_BSUK_ExpandedPolystyreneBoards
A-FloorsSlabs A_BSUK_Slabs | 3F | 6 ,SHE-05.THIRD.dgn,Design Model:143969 | A_BSUK_ExpandedPolystyreneBoards | New Construction | A-FloorsSlabs::A_BSUK_ExpandedPolystyreneBoards
A-FloorsSlabs A_BSUK_Slabs | 3F | 6 ,SHE-05.THIRD.dgn,Design Model:144064 | A_BSUK_ExpandedPolystyreneBoards | New Construction | A-FloorsSlabs::A_BSUK_ExpandedPolystyreneBoards
A-FloorsSlabs A_BSUK_Slabs | 3F | 6 ,SHE-05.THIRD.dgn,Design Model:144148 | A_BSUK_ExpandedPolystyreneBoards | New Construction | A-FloorsSlabs::A_BSUK_ExpandedPolystyreneBoards
A-FloorsSlabs A_BSUK_Slabs | 3F | 6 ,SHE-05.THIRD.dgn,Design Model:144277 | A_BSUK_ExpandedPolystyreneBoards | New Construction | A-FloorsSlabs::A_BSUK_ExpandedPolystyreneBoards
A-FloorsSlabs A_BSUK_Slabs | 3F | 6 ,SHE-05.THIRD.dgn,Design Model:144370 | A_BSUK_ExpandedPolystyreneBoards | New Construction | A-FloorsSlabs::A_BSUK_ExpandedPolystyreneBoards
A-FloorsSlabs A_BSUK_Slabs | 3F | 6 ,SHE-05.THIRD.dgn,Design Model:144454 | A_BSUK_ExpandedPolystyreneBoards | New Construction | A-FloorsSlabs::A_BSUK_ExpandedPolystyreneBoards
A-FloorsSlabs A_BSUK_Slabs | 3F | 6 ,SHE-05.THIRD.dgn,Design Model:144538 | A_BSUK_ExpandedPolystyreneBoards | New Construction | A-FloorsSlabs::A_BSUK_ExpandedPolystyreneBoards
A-FloorsSlabs A_BSUK_Slabs | 3F | 6 ,SHE-05.THIRD.dgn,Design Model:144628 | A_BSUK_ExpandedPolystyreneBoards | New Construction | A-FloorsSlabs::A_BSUK_ExpandedPolystyreneBoards
A-FloorsSlabs A_BSUK_Slabs | 3F | 6 ,SHE-05.THIRD.dgn,Design Model:144629 | A_BSUK_Parquet_Floor |  | A-Finishes::A_BSUK_Parquet_Floor
A-FloorsSlabs A_BSUK_Slabs | 3F | 6 ,SHE-05.THIRD.dgn,Design Model:144740 | A_BSUK_Carpet-Pile | New Construction | A-Finishes::A_BSUK_Carpet-Pile
A-FloorsSlabs A_BSUK_Slabs | 3F | 6 ,SHE-05.THIRD.dgn,Design Model:144773 | A_BSUK_Ceramic_FloorTiles |  | A-Finishes::A_BSUK_Ceramic_FloorTiles
A-FloorsSlabs A_BSUK_Slabs | 3F | 6 ,SHE-05.THIRD.dgn,Design Model:144788 | A_BSUK_Parquet_Floor |  | A-Finishes::A_BSUK_Parquet_Floor
A-FloorsSlabs A_BSUK_Slabs | 3F | 6 ,SHE-05.THIRD.dgn,Design Model:144899 | A_BSUK_Parquet_Floor |  | A-Finishes::A_BSUK_Parquet_Floor
A-FloorsSlabs A_BSUK_Slabs | 3F | 6 ,SHE-05.THIRD.dgn,Design Model:144914 | A_BSUK_Carpet-Pile |  | A-Finishes::A_BSUK_Carpet-Pile
A-FloorsSlabs A_BSUK_Slabs | 3F | 6 ,SHE-05.THIRD.dgn,Design Model:144959 | A_BSUK_Ceramic_FloorTiles |  | A-Finishes::A_BSUK_Ceramic_FloorTiles
A-FloorsSlabs A_BSUK_Slabs | 3F | 6 ,SHE-05.THIRD.dgn,Design Model:144974 | A_BSUK_Parquet_Floor |  | A-Finishes::A_BSUK_Parquet_Floor
A-FloorsSlabs A_BSUK_Slabs | 3F | 6 ,SHE-05.THIRD.dgn,Design Model:145109 | A_BSUK_Ceramic_FloorTiles |  | A-Finishes::A_BSUK_Ceramic_FloorTiles
A-FloorsSlabs A_BSUK_Slabs | 3F | 6 ,SHE-05.THIRD.dgn,Design Model:145124 | A_BSUK_Carpet-Pile |  | A-Finishes::A_BSUK_Carpet-Pile
A-FloorsSlabs A_BSUK_Slabs | 3F | 6 ,SHE-05.THIRD.dgn,Design Model:145163 | A_BSUK_Carpet-Pile |  | A-Finishes::A_BSUK_Carpet-Pile
A-FloorsSlabs A_BSUK_Slabs | 3F | 6 ,SHE-05.THIRD.dgn,Design Model:145196 | A_BSUK_Parquet_Floor |  | A-Finishes::A_BSUK_Parquet_Floor
A-FloorsSlabs A_BSUK_Slabs | 3F | 6 ,SHE-05.THIRD.dgn,Design Model:145313 | A_BSUK_Ceramic_FloorTiles |  | A-Finishes::A_BSUK_Ceramic_FloorTiles
A-FloorsSlabs A_BSUK_Slabs | 3F | 6 ,SHE-05.THIRD.dgn,Design Model:145328 | A_BSUK_Parquet_Floor |  | A-Finishes::A_BSUK_Parquet_Floor
A-FloorsSlabs A_BSUK_Slabs | 3F | 6 ,SHE-05.THIRD.dgn,Design Model:145427 | A_BSUK_Ceramic_FloorTiles |  | A-Finishes::A_BSUK_Ceramic_FloorTiles
A-FloorsSlabs A_BSUK_Slabs | 3F | 6 ,SHE-05.THIRD.dgn,Design Model:145448 | A_BSUK_Carpet-Pile |  | A-Finishes::A_BSUK_Carpet-Pile
A-FloorsSlabs A_BSUK_Slabs | 3F | 6 ,SHE-05.THIRD.dgn,Design Model:145631 | A_BSUK_Parquet_Floor |  | A-Finishes::A_BSUK_Parquet_Floor
A-FloorsSlabs A_BSUK_Slabs | 3F | 6 ,SHE-05.THIRD.dgn,Design Model:145632 | A_BSUK_Ceramic_FloorTiles |  | A-Finishes::A_BSUK_Ceramic_FloorTiles
A-FloorsSlabs A_BSUK_Slabs | 3F | 6 ,SHE-05.THIRD.dgn,Design Model:145633 | A_BSUK_Carpet-Pile |  | A-Finishes::A_BSUK_Carpet-Pile
A-FloorsSlabs A_BSUK_Slabs | 3F | 6 ,SHE-05.THIRD.dgn,Design Model:145634 | A_BSUK_Parquet_Floor |  | A-Finishes::A_BSUK_Parquet_Floor
A-FloorsSlabs A_BSUK_Slabs | 3F | 6 ,SHE-05.THIRD.dgn,Design Model:145739 | A_BSUK_Ceramic_FloorTiles |  | A-Finishes::A_BSUK_Ceramic_FloorTiles
A-FloorsSlabs A_BSUK_Slabs | 3F | 6 ,SHE-05.THIRD.dgn,Design Model:145754 | A_BSUK_Carpet-Pile | New Construction | A-Finishes::A_BSUK_Carpet-Pile
A-FloorsSlabs A_BSUK_Slabs | 3F | 6 ,SHE-05.THIRD.dgn,Design Model:145787 | A_BSUK_Carpet-Pile |  | A-Finishes::A_BSUK_Carpet-Pile
A-FloorsSlabs A_BSUK_Slabs | 3F | 6 ,SHE-05.THIRD.dgn,Design Model:145826 | A_BSUK_Carpet-Pile |  | A-Finishes::A_BSUK_Carpet-Pile
A-FloorsSlabs A_BSUK_Slabs | 3F | 6 ,SHE-05.THIRD.dgn,Design Model:145862 | A_BSUK_Carpet-Pile |  | A-Finishes::A_BSUK_Carpet-Pile
A-FloorsSlabs A_BSUK_Slabs | 3F | 6 ,SHE-05.THIRD.dgn,Design Model:145967 | A_BSUK_Carpet-Pile |  | A-Finishes::A_BSUK_Carpet-Pile
A-FloorsSlabs A_BSUK_Slabs | 3F | 6 ,SHE-05.THIRD.dgn,Design Model:229439 | A_BSUK_Ceramic_WallTiles | New Construction | A-Finishes::A_BSUK_Ceramic_WallTiles
A-FloorsSlabs A_BSUK_Slabs | 3F | 6 ,SHE-05.THIRD.dgn,Design Model:232461 | A_BSUK_Ceramic_FloorTiles |  | A-Finishes::A_BSUK_Ceramic_FloorTiles
A-FloorsSlabs A_BSUK_Slabs | 3F | 6 ,SHE-05.THIRD.dgn,Design Model:270352 | A_BSUK_Ceramic_WallTiles | New Construction | A-Finishes::A_BSUK_Ceramic_WallTiles
A-FloorsSlabs A_BSUK_Slabs | 3F | 6 ,SHE-05.THIRD.dgn,Design Model:270751 | A_BSUK_Ceramic_WallTiles | New Construction | A-Finishes::A_BSUK_Ceramic_WallTiles
A-FloorsSlabs A_BSUK_Slabs | 3F | shelving - bath :6,SHE-05.THIRD.dgn,Design Model:277457 | A_BSUK_Ceramic_WallTiles | New Construction | A-Finishes::A_BSUK_Ceramic_WallTiles | Identification - ID | Description: shelving - bath
A-FloorsSlabs A_BSUK_Slabs | 3F | shelving - bath :6,SHE-05.THIRD.dgn,Design Model:280881 | A_BSUK_Ceramic_WallTiles | New Construction | A-Finishes::A_BSUK_Ceramic_WallTiles | Identification - ID | Description: shelving - bath
A-FloorsSlabs A_BSUK_Slabs | 3F | 6 ,SHE-05.THIRD.dgn,Design Model:282366 | A_BSUK_Ceramic_WallTiles | New Construction | A-Finishes::A_BSUK_Ceramic_WallTiles
A-FloorsSlabs A_BSUK_Slabs | 3F | 6 ,SHE-05.THIRD.dgn,Design Model:419915 | A_BSUK_CeilingSoffitFinishes_Suspended | New Construction | A-Ceilings::A_BSUK_CeilingSoffitFinishes_Suspended | Fire Resistance - Fire | Rating: FD60
A-FloorsSlabs A_BSUK_Slabs | 3F | 6 ,SHE-05.THIRD.dgn,Design Model:419916 | A_BSUK_CeilingSoffitFinishes_Suspended | New Construction | A-Ceilings::A_BSUK_CeilingSoffitFinishes_Suspended | Fire Resistance - Fire | Rating: FD60
A-FloorsSlabs A_BSUK_Slabs | 3F | 6 ,SHE-05.THIRD.dgn,Design Model:419917 | A_BSUK_CeilingSoffitFinishes_Suspended | New Construction | A-Ceilings::A_BSUK_CeilingSoffitFinishes_Suspended | Fire Resistance - Fire | Rating: FD60
A-FloorsSlabs A_BSUK_Slabs | 3F | 6 ,SHE-05.THIRD.dgn,Design Model:419918 | A_BSUK_CeilingSoffitFinishes_Suspended | New Construction | A-Ceilings::A_BSUK_CeilingSoffitFinishes_Suspended | Fire Resistance - Fire | Rating: FD60
A-FloorsSlabs A_BSUK_Slabs | 3F | 6 ,SHE-05.THIRD.dgn,Design Model:419919 | A_BSUK_CeilingSoffitFinishes_Suspended | New Construction | A-Ceilings::A_BSUK_CeilingSoffitFinishes_Suspended | Fire Resistance - Fire | Rating: FD60
A-FloorsSlabs A_BSUK_Slabs | 3F | 6 ,SHE-05.THIRD.dgn,Design Model:419920 | A_BSUK_CeilingSoffitFinishes_Suspended | New Construction | A-Ceilings::A_BSUK_CeilingSoffitFinishes_Suspended | Fire Resistance - Fire | Rating: FD60
A-FloorsSlabs A_BSUK_Slabs | 3F | 6 ,SHE-05.THIRD.dgn,Design Model:419921 | A_BSUK_CeilingSoffitFinishes_Suspended | New Construction | A-Ceilings::A_BSUK_CeilingSoffitFinishes_Suspended | Fire Resistance - Fire | Rating: FD60
A-FloorsSlabs A_BSUK_Slabs | 3F | 6 ,SHE-05.THIRD.dgn,Design Model:419922 | A_BSUK_CeilingSoffitFinishes_Suspended | New Construction | A-Ceilings::A_BSUK_CeilingSoffitFinishes_Suspended | Fire Resistance - Fire | Rating: FD60
A-FloorsSlabs A_BSUK_Slabs | 3F | 6 ,SHE-05.THIRD.dgn,Design Model:419923 | A_BSUK_CeilingSoffitFinishes_Suspended | New Construction | A-Ceilings::A_BSUK_CeilingSoffitFinishes_Suspended | Fire Resistance - Fire | Rating: FD60
A-FloorsSlabs A_BSUK_Slabs | 3F | 6 ,SHE-05.THIRD.dgn,Design Model:419924 | A_BSUK_CeilingSoffitFinishes_Suspended | New Construction | A-Ceilings::A_BSUK_CeilingSoffitFinishes_Suspended | Fire Resistance - Fire | Rating: FD60
A-FloorsSlabs A_BSUK_Slabs | 3F | 6 ,SHE-05.THIRD.dgn,Design Model:419925 | A_BSUK_CeilingSoffitFinishes_Suspended | New Construction | A-Ceilings::A_BSUK_CeilingSoffitFinishes_Suspended | Fire Resistance - Fire | Rating: FD60
A-FloorsSlabs A_BSUK_Slabs | 3F | 6 ,SHE-05.THIRD.dgn,Design Model:419926 | A_BSUK_CeilingSoffitFinishes_Suspended | New Construction | A-Ceilings::A_BSUK_CeilingSoffitFinishes_Suspended | Fire Resistance - Fire | Rating: FD60
A-FloorsSlabs A_BSUK_Slabs | 3F | 6 ,SHE-05.THIRD.dgn,Design Model:419927 | A_BSUK_CeilingSoffitFinishes_Suspended | New Construction | A-Ceilings::A_BSUK_CeilingSoffitFinishes_Suspended | Fire Resistance - Fire | Rating: FD60
A-FloorsSlabs A_BSUK_Slabs | 3F | 6 ,SHE-05.THIRD.dgn,Design Model:419928 | A_BSUK_CeilingSoffitFinishes_Suspended | New Construction | A-Ceilings::A_BSUK_CeilingSoffitFinishes_Suspended | Fire Resistance - Fire | Rating: FD60
A-FloorsSlabs A_BSUK_Slabs | 3F | 6 ,SHE-05.THIRD.dgn,Design Model:419929 | A_BSUK_CeilingSoffitFinishes_Suspended | New Construction | A-Ceilings::A_BSUK_CeilingSoffitFinishes_Suspended | Fire Resistance - Fire | Rating: FD60
A-FloorsSlabs A_BSUK_Slabs | 3F | 6 ,SHE-05.THIRD.dgn,Design Model:419930 | A_BSUK_CeilingSoffitFinishes_Suspended | New Construction | A-Ceilings::A_BSUK_CeilingSoffitFinishes_Suspended | Fire Resistance - Fire | Rating: FD60
A-FloorsSlabs A_BSUK_Slabs | 3F | 6 ,SHE-05.THIRD.dgn,Design Model:419931 | A_BSUK_CeilingSoffitFinishes_Suspended | New Construction | A-Ceilings::A_BSUK_CeilingSoffitFinishes_Suspended | Fire Resistance - Fire | Rating: FD60
A-FloorsSlabs A_BSUK_Slabs | 3F | 6 ,SHE-05.THIRD.dgn,Design Model:419932 | A_BSUK_CeilingSoffitFinishes_Suspended | New Construction | A-Ceilings::A_BSUK_CeilingSoffitFinishes_Suspended | Fire Resistance - Fire | Rating: FD60
A-FloorsSlabs A_BSUK_Slabs | 3F | 6 ,SHE-05.THIRD.dgn,Design Model:419933 | A_BSUK_CeilingSoffitFinishes_Suspended | New Construction | A-Ceilings::A_BSUK_CeilingSoffitFinishes_Suspended | Fire Resistance - Fire | Rating: FD60
A-FloorsSlabs A_BSUK_Slabs | 3F | 6 ,SHE-05.THIRD.dgn,Design Model:419934 | A_BSUK_CeilingSoffitFinishes_Suspended | New Construction | A-Ceilings::A_BSUK_CeilingSoffitFinishes_Suspended | Fire Resistance - Fire | Rating: FD60
A-FloorsSlabs A_BSUK_Slabs | 3F | 6 ,SHE-05.THIRD.dgn,Design Model:419935 | A_BSUK_CeilingSoffitFinishes_Suspended | New Construction | A-Ceilings::A_BSUK_CeilingSoffitFinishes_Suspended | Fire Resistance - Fire | Rating: FD60
A-FloorsSlabs A_BSUK_Slabs | 3F | 6 ,SHE-05.THIRD.dgn,Design Model:419936 | A_BSUK_CeilingSoffitFinishes_Suspended | New Construction | A-Ceilings::A_BSUK_CeilingSoffitFinishes_Suspended | Fire Resistance - Fire | Rating: FD60
A-FloorsSlabs A_BSUK_Slabs | 3F | 6 ,SHE-05.THIRD.dgn,Design Model:419937 | A_BSUK_CeilingSoffitFinishes_Suspended | New Construction | A-Ceilings::A_BSUK_CeilingSoffitFinishes_Suspended | Fire Resistance - Fire | Rating: FD60
A-FloorsSlabs A_BSUK_Slabs | 3F | 6 ,SHE-05.THIRD.dgn,Design Model:419938 | A_BSUK_CeilingSoffitFinishes_Suspended | New Construction | A-Ceilings::A_BSUK_CeilingSoffitFinishes_Suspended | Fire Resistance - Fire | Rating: FD60
A-FloorsSlabs A_BSUK_Slabs | 3F | 6 ,SHE-05.THIRD.dgn,Design Model:419939 | A_BSUK_CeilingSoffitFinishes_Suspended | New Construction | A-Ceilings::A_BSUK_CeilingSoffitFinishes_Suspended | Fire Resistance - Fire | Rating: FD60
A-FloorsSlabs A_BSUK_Slabs | 3F | 6 ,SHE-05.THIRD.dgn,Design Model:419940 | A_BSUK_CeilingSoffitFinishes_Suspended | New Construction | A-Ceilings::A_BSUK_CeilingSoffitFinishes_Suspended | Fire Resistance - Fire | Rating: FD60
A-FloorsSlabs A_BSUK_Slabs | 3F | fire board - ceiling :6,SHE-05.THIRD.dgn,Design Model:466372 | A_BSUK_CeilingSoffitFinishes_Suspended | New Construction | A-Ceilings::A_BSUK_CeilingSoffitFinishes_Suspended | Identification - ID | Description: fire board - ceiling; Fire Resistance - Fire | Rating: F60
A-FloorsSlabs A_BSUK_Slabs | 3F | fire board - ceiling :6,SHE-05.THIRD.dgn,Design Model:466615 | A_BSUK_CeilingSoffitFinishes_Suspended | New Construction | A-Ceilings::A_BSUK_CeilingSoffitFinishes_Suspended | Identification - ID | Description: fire board - ceiling; ID | Notes: F60
A-FloorsSlabs A_BSUK_Slabs | 3F | fire board - ceiling :6,SHE-05.THIRD.dgn,Design Model:468576 | A_BSUK_CeilingSoffitFinishes_Suspended | New Construction | A-Ceilings::A_BSUK_CeilingSoffitFinishes_Suspended | Identification - ID | Description: fire board - ceiling; ID | Notes: F60
A-FloorsSlabs A_BSUK_Slabs | 3F | fire board - ceiling :6,SHE-05.THIRD.dgn,Design Model:468819 | A_BSUK_CeilingSoffitFinishes_Suspended | New Construction | A-Ceilings::A_BSUK_CeilingSoffitFinishes_Suspended | Identification - ID | Description: fire board - ceiling; ID | Notes: F60
A-FloorsSlabs A_BSUK_Slabs | 1F | 7 ,SHE-06.FOURTH.dgn,Design Model:248740 | A_BSUK_Ceramic_WallTiles | New Construction | A-Finishes::A_BSUK_Ceramic_WallTiles
A-FloorsSlabs A_BSUK_Slabs | 1F | 7 ,SHE-06.FOURTH.dgn,Design Model:256503 | A_BSUK_Ceramic_WallTiles | New Construction | A-Finishes::A_BSUK_Ceramic_WallTiles
A-FloorsSlabs A_BSUK_Slabs | 1F | 7 ,SHE-06.FOURTH.dgn,Design Model:243527 | A_BSUK_Ceramic_WallTiles | New Construction | A-Finishes::A_BSUK_Ceramic_WallTiles
A-FloorsSlabs A_BSUK_Slabs | 1F | 7 ,SHE-06.FOURTH.dgn,Design Model:243809 | A_BSUK_Ceramic_WallTiles | New Construction | A-Finishes::A_BSUK_Ceramic_WallTiles
A-FloorsSlabs A_BSUK_Slabs | 1F | 7 ,SHE-06.FOURTH.dgn,Design Model:243869 | A_BSUK_Ceramic_WallTiles | New Construction | A-Finishes::A_BSUK_Ceramic_WallTiles
A-FloorsSlabs A_BSUK_Slabs | 1F | 7 ,SHE-06.FOURTH.dgn,Design Model:245327 | A_BSUK_Ceramic_WallTiles | New Construction | A-Finishes::A_BSUK_Ceramic_WallTiles
A-FloorsSlabs A_BSUK_Slabs | 1F | 7 ,SHE-06.FOURTH.dgn,Design Model:245946 | A_BSUK_Ceramic_WallTiles | New Construction | A-Finishes::A_BSUK_Ceramic_WallTiles
A-FloorsSlabs A_BSUK_Slabs | 1F | 7 ,SHE-06.FOURTH.dgn,Design Model:247372 | A_BSUK_Ceramic_WallTiles | New Construction | A-Finishes::A_BSUK_Ceramic_WallTiles
A-FloorsSlabs A_BSUK_Slabs | 1F | 7 ,SHE-06.FOURTH.dgn,Design Model:247962 | A_BSUK_Ceramic_WallTiles | New Construction | A-Finishes::A_BSUK_Ceramic_WallTiles
A-FloorsSlabs A_BSUK_Slabs | 1F | 7 ,SHE-06.FOURTH.dgn,Design Model:269882 | A_BSUK_CeilingSoffitFinishes_Suspended | New Construction | A-Ceilings::A_BSUK_CeilingSoffitFinishes_Suspended
A-FloorsSlabs A_BSUK_Slabs | 1F | 7 ,SHE-06.FOURTH.dgn,Design Model:269977 | A_BSUK_CeilingSoffitFinishes_Suspended | New Construction | A-Ceilings::A_BSUK_CeilingSoffitFinishes_Suspended
A-FloorsSlabs A_BSUK_Slabs | 1F | 7 ,SHE-06.FOURTH.dgn,Design Model:270029 | A_BSUK_CeilingSoffitFinishes_Suspended | New Construction | A-Ceilings::A_BSUK_CeilingSoffitFinishes_Suspended
A-FloorsSlabs A_BSUK_Slabs | 1F | 7 ,SHE-06.FOURTH.dgn,Design Model:270081 | A_BSUK_CeilingSoffitFinishes_Suspended | New Construction | A-Ceilings::A_BSUK_CeilingSoffitFinishes_Suspended
A-FloorsSlabs A_BSUK_Slabs | 1F | 7 ,SHE-06.FOURTH.dgn,Design Model:270169 | A_BSUK_CeilingSoffitFinishes_Suspended | New Construction | A-Ceilings::A_BSUK_CeilingSoffitFinishes_Suspended
A-FloorsSlabs A_BSUK_Slabs | 1F | 7 ,SHE-06.FOURTH.dgn,Design Model:270245 | A_BSUK_CeilingSoffitFinishes_Suspended | New Construction | A-Ceilings::A_BSUK_CeilingSoffitFinishes_Suspended
A-FloorsSlabs A_BSUK_Slabs | 1F | 7 ,SHE-06.FOURTH.dgn,Design Model:270272 | A_BSUK_CeilingSoffitFinishes_Suspended | New Construction | A-Ceilings::A_BSUK_CeilingSoffitFinishes_Suspended
A-FloorsSlabs A_BSUK_Slabs | 1F | 7 ,SHE-06.FOURTH.dgn,Design Model:270349 | A_BSUK_CeilingSoffitFinishes_Suspended | New Construction | A-Ceilings::A_BSUK_CeilingSoffitFinishes_Suspended
A-FloorsSlabs A_BSUK_Slabs | 1F | 7 ,SHE-06.FOURTH.dgn,Design Model:270437 | A_BSUK_CeilingSoffitFinishes_Suspended | New Construction | A-Ceilings::A_BSUK_CeilingSoffitFinishes_Suspended
A-FloorsSlabs A_BSUK_Slabs | 1F | 7 ,SHE-06.FOURTH.dgn,Design Model:270470 | A_BSUK_CeilingSoffitFinishes_Suspended | New Construction | A-Ceilings::A_BSUK_CeilingSoffitFinishes_Suspended
A-FloorsSlabs A_BSUK_Slabs | 1F | 7 ,SHE-06.FOURTH.dgn,Design Model:270497 | A_BSUK_CeilingSoffitFinishes_Suspended | New Construction | A-Ceilings::A_BSUK_CeilingSoffitFinishes_Suspended
A-FloorsSlabs A_BSUK_Slabs | 1F | 7 ,SHE-06.FOURTH.dgn,Design Model:270617 | A_BSUK_CeilingSoffitFinishes_Suspended | New Construction | A-Ceilings::A_BSUK_CeilingSoffitFinishes_Suspended
A-FloorsSlabs A_BSUK_Slabs | 1F | 7 ,SHE-06.FOURTH.dgn,Design Model:270681 | A_BSUK_CeilingSoffitFinishes_Suspended | New Construction | A-Ceilings::A_BSUK_CeilingSoffitFinishes_Suspended
A-FloorsSlabs A_BSUK_Slabs | 1F | 7 ,SHE-06.FOURTH.dgn,Design Model:270714 | A_BSUK_CeilingSoffitFinishes_Suspended | New Construction | A-Ceilings::A_BSUK_CeilingSoffitFinishes_Suspended
A-FloorsSlabs A_BSUK_Slabs | 1F | 7 ,SHE-06.FOURTH.dgn,Design Model:270840 | A_BSUK_CeilingSoffitFinishes_Suspended | New Construction | A-Ceilings::A_BSUK_CeilingSoffitFinishes_Suspended
A-FloorsSlabs A_BSUK_Slabs | 1F | 7 ,SHE-06.FOURTH.dgn,Design Model:271066 | A_BSUK_CeilingSoffitFinishes_Suspended | New Construction | A-Ceilings::A_BSUK_CeilingSoffitFinishes_Suspended
A-FloorsSlabs A_BSUK_Slabs | 1F | 7 ,SHE-06.FOURTH.dgn,Design Model:271105 | A_BSUK_CeilingSoffitFinishes_Suspended | New Construction | A-Ceilings::A_BSUK_CeilingSoffitFinishes_Suspended
A-FloorsSlabs A_BSUK_Slabs | 1F | 7 ,SHE-06.FOURTH.dgn,Design Model:271144 | A_BSUK_CeilingSoffitFinishes_Suspended | New Construction | A-Ceilings::A_BSUK_CeilingSoffitFinishes_Suspended
A-FloorsSlabs A_BSUK_Slabs | 1F | 7 ,SHE-06.FOURTH.dgn,Design Model:271183 | A_BSUK_CeilingSoffitFinishes_Suspended | New Construction | A-Ceilings::A_BSUK_CeilingSoffitFinishes_Suspended
A-FloorsSlabs A_BSUK_Slabs | 1F | 7 ,SHE-06.FOURTH.dgn,Design Model:271198 | A_BSUK_CeilingSoffitFinishes_Suspended | New Construction | A-Ceilings::A_BSUK_CeilingSoffitFinishes_Suspended
A-FloorsSlabs A_BSUK_Slabs | 1F | 7 ,SHE-06.FOURTH.dgn,Design Model:271216 | A_BSUK_CeilingSoffitFinishes_Suspended | New Construction | A-Ceilings::A_BSUK_CeilingSoffitFinishes_Suspended
A-FloorsSlabs A_BSUK_Slabs | 1F | 7 ,SHE-06.FOURTH.dgn,Design Model:271231 | A_BSUK_CeilingSoffitFinishes_Suspended | New Construction | A-Ceilings::A_BSUK_CeilingSoffitFinishes_Suspended
A-FloorsSlabs A_BSUK_Slabs | 1F | 7 ,SHE-06.FOURTH.dgn,Design Model:271258 | A_BSUK_CeilingSoffitFinishes_Suspended | New Construction | A-Ceilings::A_BSUK_CeilingSoffitFinishes_Suspended
A-FloorsSlabs A_BSUK_Slabs | 1F | 7 ,SHE-06.FOURTH.dgn,Design Model:271285 | A_BSUK_CeilingSoffitFinishes_Suspended | New Construction | A-Ceilings::A_BSUK_CeilingSoffitFinishes_Suspended
A-FloorsSlabs A_BSUK_Slabs | 1F | 7 ,SHE-06.FOURTH.dgn,Design Model:271318 | A_BSUK_CeilingSoffitFinishes_Suspended | New Construction | A-Ceilings::A_BSUK_CeilingSoffitFinishes_Suspended
A-FloorsSlabs A_BSUK_Slabs | 1F | 7 ,SHE-06.FOURTH.dgn,Design Model:271345 | A_BSUK_CeilingSoffitFinishes_Suspended | New Construction | A-Ceilings::A_BSUK_CeilingSoffitFinishes_Suspended
A-FloorsSlabs A_BSUK_Slabs | 1F | 7 ,SHE-06.FOURTH.dgn,Design Model:271372 | A_BSUK_CeilingSoffitFinishes_Suspended | New Construction | A-Ceilings::A_BSUK_CeilingSoffitFinishes_Suspended
A-FloorsSlabs A_BSUK_Slabs | 1F | 7 ,SHE-06.FOURTH.dgn,Design Model:271771 | A_BSUK_CeilingSoffitFinishes_Suspended | New Construction | A-Ceilings::A_BSUK_CeilingSoffitFinishes_Suspended
A-FloorsSlabs A_BSUK_Slabs | 1F | 7 ,SHE-06.FOURTH.dgn,Design Model:271792 | A_BSUK_CeilingSoffitFinishes_Suspended | New Construction | A-Ceilings::A_BSUK_CeilingSoffitFinishes_Suspended
A-FloorsSlabs A_BSUK_Slabs | 1F | 7 ,SHE-06.FOURTH.dgn,Design Model:271819 | A_BSUK_CeilingSoffitFinishes_Suspended | New Construction | A-Ceilings::A_BSUK_CeilingSoffitFinishes_Suspended
A-FloorsSlabs A_BSUK_Slabs | 1F | 7 ,SHE-06.FOURTH.dgn,Design Model:271840 | A_BSUK_CeilingSoffitFinishes_Suspended | New Construction | A-Ceilings::A_BSUK_CeilingSoffitFinishes_Suspended
A-FloorsSlabs A_BSUK_Slabs | 1F | 7 ,SHE-06.FOURTH.dgn,Design Model:277591 | A_BSUK_InternalFinishes_FloorScreed | New Construction | A-FloorsSlabs::A_BSUK_InternalFinishes_FloorScreed
A-FloorsSlabs A_BSUK_Slabs | 1F | 7 ,SHE-06.FOURTH.dgn,Design Model:277593 | A_BSUK_InternalFinishes_FloorScreed | New Construction | A-FloorsSlabs::A_BSUK_InternalFinishes_FloorScreed
A-FloorsSlabs A_BSUK_Slabs | 1F | 7 ,SHE-06.FOURTH.dgn,Design Model:281259 | A_BSUK_ExpandedPolystyreneBoards | New Construction | A-FloorsSlabs::A_BSUK_ExpandedPolystyreneBoards
A-FloorsSlabs A_BSUK_Slabs | 1F | 7 ,SHE-06.FOURTH.dgn,Design Model:281260 | A_BSUK_ExpandedPolystyreneBoards | New Construction | A-FloorsSlabs::A_BSUK_ExpandedPolystyreneBoards
A-FloorsSlabs A_BSUK_Slabs | 1F | 7 ,SHE-06.FOURTH.dgn,Design Model:281261 | A_BSUK_ExpandedPolystyreneBoards | New Construction | A-FloorsSlabs::A_BSUK_ExpandedPolystyreneBoards
A-FloorsSlabs A_BSUK_Slabs | 1F | 7 ,SHE-06.FOURTH.dgn,Design Model:281262 | A_BSUK_ExpandedPolystyreneBoards | New Construction | A-FloorsSlabs::A_BSUK_ExpandedPolystyreneBoards
A-FloorsSlabs A_BSUK_Slabs | 1F | 7 ,SHE-06.FOURTH.dgn,Design Model:281263 | A_BSUK_ExpandedPolystyreneBoards | New Construction | A-FloorsSlabs::A_BSUK_ExpandedPolystyreneBoards
A-FloorsSlabs A_BSUK_Slabs | 1F | 7 ,SHE-06.FOURTH.dgn,Design Model:281264 | A_BSUK_ExpandedPolystyreneBoards | New Construction | A-FloorsSlabs::A_BSUK_ExpandedPolystyreneBoards
A-FloorsSlabs A_BSUK_Slabs | 1F | 7 ,SHE-06.FOURTH.dgn,Design Model:281265 | A_BSUK_ExpandedPolystyreneBoards | New Construction | A-FloorsSlabs::A_BSUK_ExpandedPolystyreneBoards
A-FloorsSlabs A_BSUK_Slabs | 1F | 7 ,SHE-06.FOURTH.dgn,Design Model:281266 | A_BSUK_ExpandedPolystyreneBoards | New Construction | A-FloorsSlabs::A_BSUK_ExpandedPolystyreneBoards
A-FloorsSlabs A_BSUK_Slabs | 1F | 7 ,SHE-06.FOURTH.dgn,Design Model:281267 | A_BSUK_ExpandedPolystyreneBoards | New Construction | A-FloorsSlabs::A_BSUK_ExpandedPolystyreneBoards
A-FloorsSlabs A_BSUK_Slabs | 1F | 7 ,SHE-06.FOURTH.dgn,Design Model:281268 | A_BSUK_ExpandedPolystyreneBoards | New Construction | A-FloorsSlabs::A_BSUK_ExpandedPolystyreneBoards
A-FloorsSlabs A_BSUK_Slabs | 1F | 7 ,SHE-06.FOURTH.dgn,Design Model:281269 | A_BSUK_ExpandedPolystyreneBoards | New Construction | A-FloorsSlabs::A_BSUK_ExpandedPolystyreneBoards
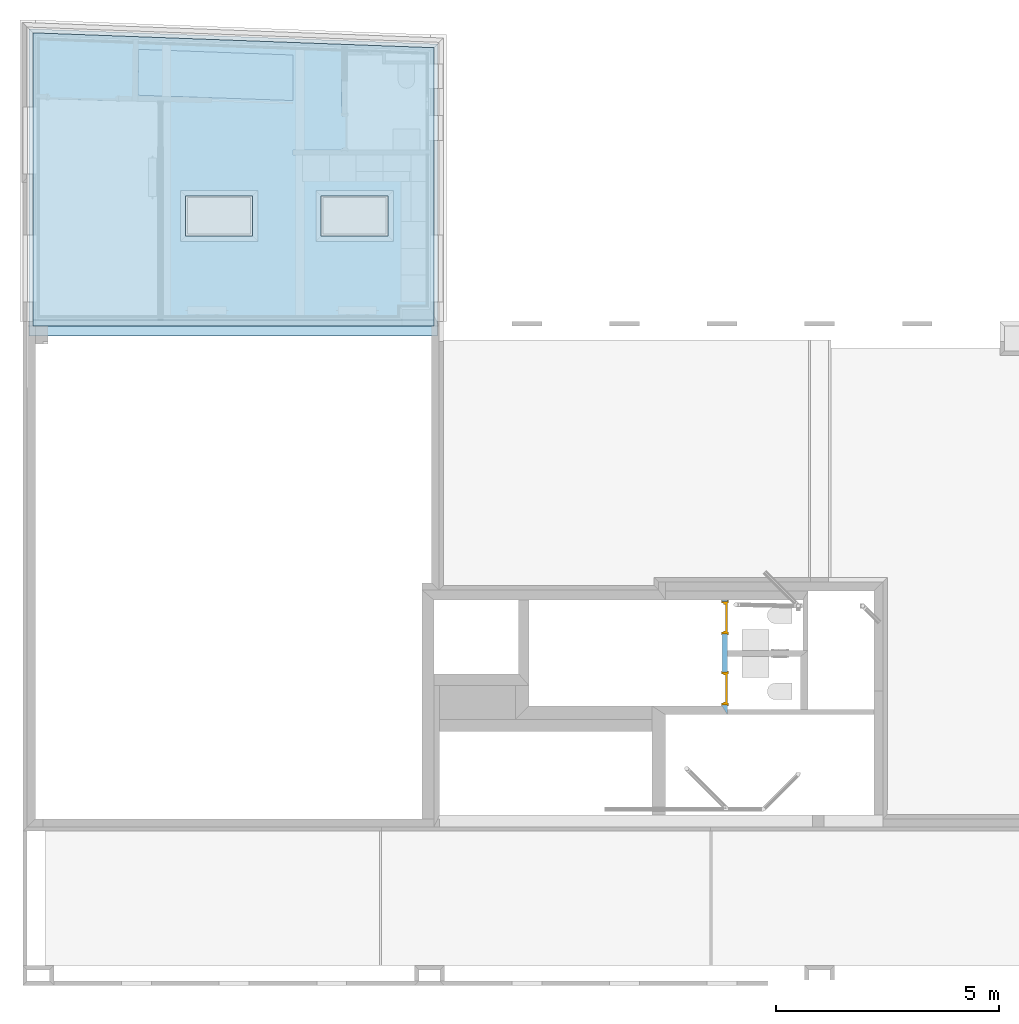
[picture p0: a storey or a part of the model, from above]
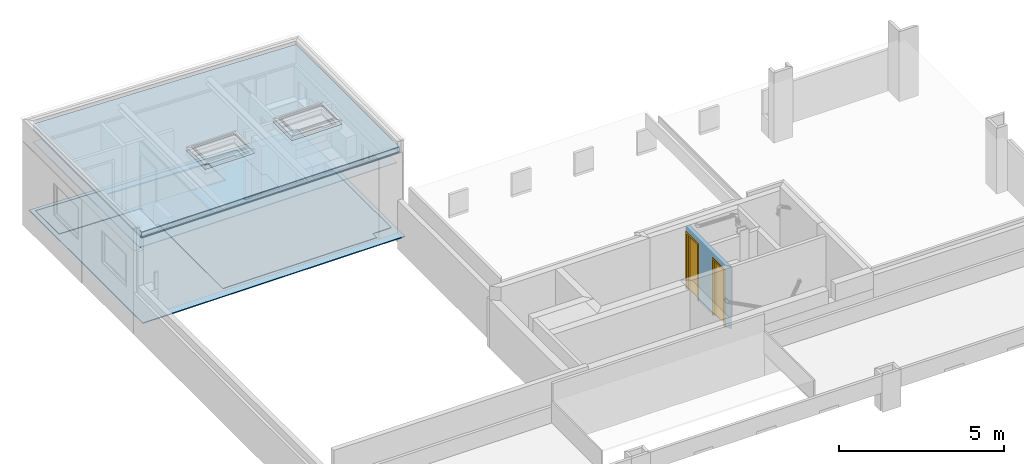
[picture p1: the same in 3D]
Properties of the parts of a building model (IFC2X3), part 10 of 16

# IfcSlab: A-FloorsSlabs A_BSUK_Slabs (1393)
Name | In | Description | Material | Phase | Part Definition
A-FloorsSlabs A_BSUK_Slabs | 1F | 7 ,SHE-06.FOURTH.dgn,Design Model:281270 | A_BSUK_ExpandedPolystyreneBoards | New Construction | A-FloorsSlabs::A_BSUK_ExpandedPolystyreneBoards
A-FloorsSlabs A_BSUK_Slabs | 1F | 7 ,SHE-06.FOURTH.dgn,Design Model:281271 | A_BSUK_ExpandedPolystyreneBoards | New Construction | A-FloorsSlabs::A_BSUK_ExpandedPolystyreneBoards
A-FloorsSlabs A_BSUK_Slabs | 1F | 7 ,SHE-06.FOURTH.dgn,Design Model:281272 | A_BSUK_ExpandedPolystyreneBoards | New Construction | A-FloorsSlabs::A_BSUK_ExpandedPolystyreneBoards
A-FloorsSlabs A_BSUK_Slabs | 1F | 7 ,SHE-06.FOURTH.dgn,Design Model:281273 | A_BSUK_ExpandedPolystyreneBoards | New Construction | A-FloorsSlabs::A_BSUK_ExpandedPolystyreneBoards
A-FloorsSlabs A_BSUK_Slabs | 1F | 7 ,SHE-06.FOURTH.dgn,Design Model:281274 | A_BSUK_ExpandedPolystyreneBoards | New Construction | A-FloorsSlabs::A_BSUK_ExpandedPolystyreneBoards
A-FloorsSlabs A_BSUK_Slabs | 1F | 7 ,SHE-06.FOURTH.dgn,Design Model:281275 | A_BSUK_ExpandedPolystyreneBoards | New Construction | A-FloorsSlabs::A_BSUK_ExpandedPolystyreneBoards
A-FloorsSlabs A_BSUK_Slabs | 1F | 7 ,SHE-06.FOURTH.dgn,Design Model:281276 | A_BSUK_ExpandedPolystyreneBoards | New Construction | A-FloorsSlabs::A_BSUK_ExpandedPolystyreneBoards
A-FloorsSlabs A_BSUK_Slabs | 1F | 7 ,SHE-06.FOURTH.dgn,Design Model:281277 | A_BSUK_ExpandedPolystyreneBoards | New Construction | A-FloorsSlabs::A_BSUK_ExpandedPolystyreneBoards
A-FloorsSlabs A_BSUK_Slabs | 1F | 7 ,SHE-06.FOURTH.dgn,Design Model:281278 | A_BSUK_ExpandedPolystyreneBoards | New Construction | A-FloorsSlabs::A_BSUK_ExpandedPolystyreneBoards
A-FloorsSlabs A_BSUK_Slabs | 1F | 7 ,SHE-06.FOURTH.dgn,Design Model:281279 | A_BSUK_ExpandedPolystyreneBoards | New Construction | A-FloorsSlabs::A_BSUK_ExpandedPolystyreneBoards
A-FloorsSlabs A_BSUK_Slabs | 1F | 7 ,SHE-06.FOURTH.dgn,Design Model:281280 | A_BSUK_ExpandedPolystyreneBoards | New Construction | A-FloorsSlabs::A_BSUK_ExpandedPolystyreneBoards
A-FloorsSlabs A_BSUK_Slabs | 1F | 7 ,SHE-06.FOURTH.dgn,Design Model:281281 | A_BSUK_ExpandedPolystyreneBoards | New Construction | A-FloorsSlabs::A_BSUK_ExpandedPolystyreneBoards
A-FloorsSlabs A_BSUK_Slabs | 1F | 7 ,SHE-06.FOURTH.dgn,Design Model:281282 | A_BSUK_ExpandedPolystyreneBoards | New Construction | A-FloorsSlabs::A_BSUK_ExpandedPolystyreneBoards
A-FloorsSlabs A_BSUK_Slabs | 1F | 7 ,SHE-06.FOURTH.dgn,Design Model:281283 | A_BSUK_ExpandedPolystyreneBoards | New Construction | A-FloorsSlabs::A_BSUK_ExpandedPolystyreneBoards
A-FloorsSlabs A_BSUK_Slabs | 1F | 7 ,SHE-06.FOURTH.dgn,Design Model:281284 | A_BSUK_ExpandedPolystyreneBoards | New Construction | A-FloorsSlabs::A_BSUK_ExpandedPolystyreneBoards
A-FloorsSlabs A_BSUK_Slabs | 1F | 7 ,SHE-06.FOURTH.dgn,Design Model:281285 | A_BSUK_ExpandedPolystyreneBoards | New Construction | A-FloorsSlabs::A_BSUK_ExpandedPolystyreneBoards
A-FloorsSlabs A_BSUK_Slabs | 1F | 7 ,SHE-06.FOURTH.dgn,Design Model:281287 | A_BSUK_ExpandedPolystyreneBoards | New Construction | A-FloorsSlabs::A_BSUK_ExpandedPolystyreneBoards
A-FloorsSlabs A_BSUK_Slabs | 1F | 7 ,SHE-06.FOURTH.dgn,Design Model:281288 | A_BSUK_ExpandedPolystyreneBoards | New Construction | A-FloorsSlabs::A_BSUK_ExpandedPolystyreneBoards
A-FloorsSlabs A_BSUK_Slabs | 1F | 7 ,SHE-06.FOURTH.dgn,Design Model:281289 | A_BSUK_ExpandedPolystyreneBoards | New Construction | A-FloorsSlabs::A_BSUK_ExpandedPolystyreneBoards
A-FloorsSlabs A_BSUK_Slabs | 1F | 7 ,SHE-06.FOURTH.dgn,Design Model:281290 | A_BSUK_ExpandedPolystyreneBoards | New Construction | A-FloorsSlabs::A_BSUK_ExpandedPolystyreneBoards
A-FloorsSlabs A_BSUK_Slabs | 1F | window sill :7,SHE-06.FOURTH.dgn,Design Model:345146 | A_BSUK_Timber_Miscellaneous | New Construction | A-FrameElements::A_BSUK_Timber_Miscellaneous | Identification - ID | Description: window sill
A-FloorsSlabs A_BSUK_Slabs | 1F | window sill :7,SHE-06.FOURTH.dgn,Design Model:345174 | A_BSUK_Timber_Miscellaneous | New Construction | A-FrameElements::A_BSUK_Timber_Miscellaneous | Identification - ID | Description: window sill
A-FloorsSlabs A_BSUK_Slabs | 1F | window sill :7,SHE-06.FOURTH.dgn,Design Model:345254 | A_BSUK_Timber_Miscellaneous | New Construction | A-FrameElements::A_BSUK_Timber_Miscellaneous | Identification - ID | Description: window sill
A-FloorsSlabs A_BSUK_Slabs | 1F | window sill :7,SHE-06.FOURTH.dgn,Design Model:345601 | A_BSUK_Timber_Miscellaneous | New Construction | A-FrameElements::A_BSUK_Timber_Miscellaneous | Identification - ID | Description: window sill
A-FloorsSlabs A_BSUK_Slabs | 1F | window sill :7,SHE-06.FOURTH.dgn,Design Model:345642 | A_BSUK_Timber_Miscellaneous | New Construction | A-FrameElements::A_BSUK_Timber_Miscellaneous | Identification - ID | Description: window sill
A-FloorsSlabs A_BSUK_Slabs | 1F | window sill :7,SHE-06.FOURTH.dgn,Design Model:385665 | A_BSUK_Timber_Miscellaneous | New Construction | A-FrameElements::A_BSUK_Timber_Miscellaneous | Identification - ID | Description: window sill
A-FloorsSlabs A_BSUK_Slabs | 1F | window sill :7,SHE-06.FOURTH.dgn,Design Model:385680 | A_BSUK_Timber_Miscellaneous | New Construction | A-FrameElements::A_BSUK_Timber_Miscellaneous | Identification - ID | Description: window sill
A-FloorsSlabs A_BSUK_Slabs | 1F | window sill :7,SHE-06.FOURTH.dgn,Design Model:385708 | A_BSUK_Timber_Miscellaneous | New Construction | A-FrameElements::A_BSUK_Timber_Miscellaneous | Identification - ID | Description: window sill
A-FloorsSlabs A_BSUK_Slabs | 1F | window sill :7,SHE-06.FOURTH.dgn,Design Model:385736 | A_BSUK_Timber_Miscellaneous | New Construction | A-FrameElements::A_BSUK_Timber_Miscellaneous | Identification - ID | Description: window sill
A-FloorsSlabs A_BSUK_Slabs | 1F | window sill :7,SHE-06.FOURTH.dgn,Design Model:385764 | A_BSUK_Timber_Miscellaneous | New Construction | A-FrameElements::A_BSUK_Timber_Miscellaneous | Identification - ID | Description: window sill
A-FloorsSlabs A_BSUK_Slabs | 1F | window sill :7,SHE-06.FOURTH.dgn,Design Model:385792 | A_BSUK_Timber_Miscellaneous | New Construction | A-FrameElements::A_BSUK_Timber_Miscellaneous | Identification - ID | Description: window sill
A-FloorsSlabs A_BSUK_Slabs | 1F | window sill :7,SHE-06.FOURTH.dgn,Design Model:385820 | A_BSUK_Timber_Miscellaneous | New Construction | A-FrameElements::A_BSUK_Timber_Miscellaneous | Identification - ID | Description: window sill
A-FloorsSlabs A_BSUK_Slabs | 1F | window sill :7,SHE-06.FOURTH.dgn,Design Model:385848 | A_BSUK_Timber_Miscellaneous | New Construction | A-FrameElements::A_BSUK_Timber_Miscellaneous | Identification - ID | Description: window sill
A-FloorsSlabs A_BSUK_Slabs | 1F | window sill :7,SHE-06.FOURTH.dgn,Design Model:385876 | A_BSUK_Timber_Miscellaneous | New Construction | A-FrameElements::A_BSUK_Timber_Miscellaneous | Identification - ID | Description: window sill
A-FloorsSlabs A_BSUK_Slabs | 1F | window sill :7,SHE-06.FOURTH.dgn,Design Model:385904 | A_BSUK_Timber_Miscellaneous | New Construction | A-FrameElements::A_BSUK_Timber_Miscellaneous | Identification - ID | Description: window sill
A-FloorsSlabs A_BSUK_Slabs | 1F | window sill :7,SHE-06.FOURTH.dgn,Design Model:385958 | A_BSUK_Timber_Miscellaneous | New Construction | A-FrameElements::A_BSUK_Timber_Miscellaneous | Identification - ID | Description: window sill
A-FloorsSlabs A_BSUK_Slabs | 1F | window sill :7,SHE-06.FOURTH.dgn,Design Model:385986 | A_BSUK_Timber_Miscellaneous | New Construction | A-FrameElements::A_BSUK_Timber_Miscellaneous | Identification - ID | Description: window sill
A-FloorsSlabs A_BSUK_Slabs | 1F | window sill :7,SHE-06.FOURTH.dgn,Design Model:386014 | A_BSUK_Timber_Miscellaneous | New Construction | A-FrameElements::A_BSUK_Timber_Miscellaneous | Identification - ID | Description: window sill
A-FloorsSlabs A_BSUK_Slabs | 1F | window sill :7,SHE-06.FOURTH.dgn,Design Model:386042 | A_BSUK_Timber_Miscellaneous | New Construction | A-FrameElements::A_BSUK_Timber_Miscellaneous | Identification - ID | Description: window sill
A-FloorsSlabs A_BSUK_Slabs | 1F | window sill :7,SHE-06.FOURTH.dgn,Design Model:386070 | A_BSUK_Timber_Miscellaneous | New Construction | A-FrameElements::A_BSUK_Timber_Miscellaneous | Identification - ID | Description: window sill
A-FloorsSlabs A_BSUK_Slabs | 1F | window sill :7,SHE-06.FOURTH.dgn,Design Model:386098 | A_BSUK_Timber_Miscellaneous | New Construction | A-FrameElements::A_BSUK_Timber_Miscellaneous | Identification - ID | Description: window sill
A-FloorsSlabs A_BSUK_Slabs | 1F | window sill :7,SHE-06.FOURTH.dgn,Design Model:386126 | A_BSUK_Timber_Miscellaneous | New Construction | A-FrameElements::A_BSUK_Timber_Miscellaneous | Identification - ID | Description: window sill
A-FloorsSlabs A_BSUK_Slabs | 1F | window sill :7,SHE-06.FOURTH.dgn,Design Model:386154 | A_BSUK_Timber_Miscellaneous | New Construction | A-FrameElements::A_BSUK_Timber_Miscellaneous | Identification - ID | Description: window sill
A-FloorsSlabs A_BSUK_Slabs | 1F | window sill :7,SHE-06.FOURTH.dgn,Design Model:386182 | A_BSUK_Timber_Miscellaneous | New Construction | A-FrameElements::A_BSUK_Timber_Miscellaneous | Identification - ID | Description: window sill
A-FloorsSlabs A_BSUK_Slabs | 1F | 7 ,SHE-06.FOURTH.dgn,Design Model:407641 | A_BSUK_Ceramic_WallTiles | New Construction | A-Finishes::A_BSUK_Ceramic_WallTiles
A-FloorsSlabs A_BSUK_Slabs | 1F | 7 ,SHE-06.FOURTH.dgn,Design Model:437550 | A_BSUK_CeilingSoffitFinishes_Suspended | New Construction | A-Ceilings::A_BSUK_CeilingSoffitFinishes_Suspended
A-FloorsSlabs A_BSUK_Slabs | 1F | 7 ,SHE-06.FOURTH.dgn,Design Model:437583 | A_BSUK_CeilingSoffitFinishes_Suspended | New Construction | A-Ceilings::A_BSUK_CeilingSoffitFinishes_Suspended
A-FloorsSlabs A_BSUK_Slabs | 1F | 7 ,SHE-06.FOURTH.dgn,Design Model:437610 | A_BSUK_CeilingSoffitFinishes_Suspended | New Construction | A-Ceilings::A_BSUK_CeilingSoffitFinishes_Suspended
A-FloorsSlabs A_BSUK_Slabs | 1F | 7 ,SHE-06.FOURTH.dgn,Design Model:437637 | A_BSUK_CeilingSoffitFinishes_Suspended | New Construction | A-Ceilings::A_BSUK_CeilingSoffitFinishes_Suspended
A-FloorsSlabs A_BSUK_Slabs | 1F | 7 ,SHE-06.FOURTH.dgn,Design Model:437682 | A_BSUK_CeilingSoffitFinishes_Suspended | New Construction | A-Ceilings::A_BSUK_CeilingSoffitFinishes_Suspended
A-FloorsSlabs A_BSUK_Slabs | 1F | 7 ,SHE-06.FOURTH.dgn,Design Model:437721 | A_BSUK_CeilingSoffitFinishes_Suspended | New Construction | A-Ceilings::A_BSUK_CeilingSoffitFinishes_Suspended
A-FloorsSlabs A_BSUK_Slabs | 1F | 7 ,SHE-06.FOURTH.dgn,Design Model:437748 | A_BSUK_CeilingSoffitFinishes_Suspended | New Construction | A-Ceilings::A_BSUK_CeilingSoffitFinishes_Suspended
A-FloorsSlabs A_BSUK_Slabs | 1F | 7 ,SHE-06.FOURTH.dgn,Design Model:437775 | A_BSUK_CeilingSoffitFinishes_Suspended | New Construction | A-Ceilings::A_BSUK_CeilingSoffitFinishes_Suspended
A-FloorsSlabs A_BSUK_Slabs | 1F | 7 ,SHE-06.FOURTH.dgn,Design Model:437820 | A_BSUK_CeilingSoffitFinishes_Suspended | New Construction | A-Ceilings::A_BSUK_CeilingSoffitFinishes_Suspended
A-FloorsSlabs A_BSUK_Slabs | 1F | 7 ,SHE-06.FOURTH.dgn,Design Model:437853 | A_BSUK_CeilingSoffitFinishes_Suspended | New Construction | A-Ceilings::A_BSUK_CeilingSoffitFinishes_Suspended
A-FloorsSlabs A_BSUK_Slabs | 1F | 7 ,SHE-06.FOURTH.dgn,Design Model:437880 | A_BSUK_CeilingSoffitFinishes_Suspended | New Construction | A-Ceilings::A_BSUK_CeilingSoffitFinishes_Suspended
A-FloorsSlabs A_BSUK_Slabs | 1F | 7 ,SHE-06.FOURTH.dgn,Design Model:437913 | A_BSUK_CeilingSoffitFinishes_Suspended | New Construction | A-Ceilings::A_BSUK_CeilingSoffitFinishes_Suspended
A-FloorsSlabs A_BSUK_Slabs | 1F | 7 ,SHE-06.FOURTH.dgn,Design Model:437946 | A_BSUK_CeilingSoffitFinishes_Suspended | New Construction | A-Ceilings::A_BSUK_CeilingSoffitFinishes_Suspended
A-FloorsSlabs A_BSUK_Slabs | 1F | 7 ,SHE-06.FOURTH.dgn,Design Model:437979 | A_BSUK_CeilingSoffitFinishes_Suspended | New Construction | A-Ceilings::A_BSUK_CeilingSoffitFinishes_Suspended
A-FloorsSlabs A_BSUK_Slabs | 1F | 7 ,SHE-06.FOURTH.dgn,Design Model:438012 | A_BSUK_CeilingSoffitFinishes_Suspended | New Construction | A-Ceilings::A_BSUK_CeilingSoffitFinishes_Suspended
A-FloorsSlabs A_BSUK_Slabs | 1F | 7 ,SHE-06.FOURTH.dgn,Design Model:438042 | A_BSUK_CeilingSoffitFinishes_Suspended | New Construction | A-Ceilings::A_BSUK_CeilingSoffitFinishes_Suspended
A-FloorsSlabs A_BSUK_Slabs | 1F | 7 ,SHE-06.FOURTH.dgn,Design Model:438081 | A_BSUK_CeilingSoffitFinishes_Suspended | New Construction | A-Ceilings::A_BSUK_CeilingSoffitFinishes_Suspended
A-FloorsSlabs A_BSUK_Slabs | 1F | 7 ,SHE-06.FOURTH.dgn,Design Model:438120 | A_BSUK_CeilingSoffitFinishes_Suspended | New Construction | A-Ceilings::A_BSUK_CeilingSoffitFinishes_Suspended
A-FloorsSlabs A_BSUK_Slabs | 1F | 7 ,SHE-06.FOURTH.dgn,Design Model:438156 | A_BSUK_CeilingSoffitFinishes_Suspended | New Construction | A-Ceilings::A_BSUK_CeilingSoffitFinishes_Suspended
A-FloorsSlabs A_BSUK_Slabs | 1F | 7 ,SHE-06.FOURTH.dgn,Design Model:438171 | A_BSUK_CeilingSoffitFinishes_Suspended | New Construction | A-Ceilings::A_BSUK_CeilingSoffitFinishes_Suspended
A-FloorsSlabs A_BSUK_Slabs | 1F | 7 ,SHE-06.FOURTH.dgn,Design Model:438189 | A_BSUK_CeilingSoffitFinishes_Suspended | New Construction | A-Ceilings::A_BSUK_CeilingSoffitFinishes_Suspended
A-FloorsSlabs A_BSUK_Slabs | 1F | 7 ,SHE-06.FOURTH.dgn,Design Model:438210 | A_BSUK_CeilingSoffitFinishes_Suspended | New Construction | A-Ceilings::A_BSUK_CeilingSoffitFinishes_Suspended
A-FloorsSlabs A_BSUK_Slabs | 1F | 7 ,SHE-06.FOURTH.dgn,Design Model:438237 | A_BSUK_CeilingSoffitFinishes_Suspended | New Construction | A-Ceilings::A_BSUK_CeilingSoffitFinishes_Suspended
A-FloorsSlabs A_BSUK_Slabs | 1F | 7 ,SHE-06.FOURTH.dgn,Design Model:438252 | A_BSUK_CeilingSoffitFinishes_Suspended | New Construction | A-Ceilings::A_BSUK_CeilingSoffitFinishes_Suspended
A-FloorsSlabs A_BSUK_Slabs | 1F | 7 ,SHE-06.FOURTH.dgn,Design Model:438285 | A_BSUK_CeilingSoffitFinishes_Suspended | New Construction | A-Ceilings::A_BSUK_CeilingSoffitFinishes_Suspended
A-FloorsSlabs A_BSUK_Slabs | 1F | 7 ,SHE-06.FOURTH.dgn,Design Model:438312 | A_BSUK_CeilingSoffitFinishes_Suspended | New Construction | A-Ceilings::A_BSUK_CeilingSoffitFinishes_Suspended
A-FloorsSlabs A_BSUK_Slabs | 1F | 7 ,SHE-06.FOURTH.dgn,Design Model:438339 | A_BSUK_CeilingSoffitFinishes_Suspended | New Construction | A-Ceilings::A_BSUK_CeilingSoffitFinishes_Suspended
A-FloorsSlabs A_BSUK_Slabs | 1F | Fire board - ceiling (120 min) :7,SHE-06.FOURTH.dgn,Design Model:438360 | A_BSUK_CeilingSoffitFinishes_Suspended | New Construction | A-Ceilings::A_BSUK_CeilingSoffitFinishes_Suspended | Identification - ID | Description: Fire board - ceiling (120 min)
A-FloorsSlabs A_BSUK_Slabs | 1F | 7 ,SHE-06.FOURTH.dgn,Design Model:438381 | A_BSUK_CeilingSoffitFinishes_Suspended | New Construction | A-Ceilings::A_BSUK_CeilingSoffitFinishes_Suspended
A-FloorsSlabs A_BSUK_Slabs | 1F | 7 ,SHE-06.FOURTH.dgn,Design Model:438408 | A_BSUK_CeilingSoffitFinishes_Suspended | New Construction | A-Ceilings::A_BSUK_CeilingSoffitFinishes_Suspended
A-FloorsSlabs A_BSUK_Slabs | 1F | 7 ,SHE-06.FOURTH.dgn,Design Model:438435 | A_BSUK_CeilingSoffitFinishes_Suspended | New Construction | A-Ceilings::A_BSUK_CeilingSoffitFinishes_Suspended
A-FloorsSlabs A_BSUK_Slabs | 1F | 7 ,SHE-06.FOURTH.dgn,Design Model:438456 | A_BSUK_CeilingSoffitFinishes_Suspended | New Construction | A-Ceilings::A_BSUK_CeilingSoffitFinishes_Suspended
A-FloorsSlabs A_BSUK_Slabs | 1F | Stair 5 :7,SHE-06.FOURTH.dgn,Design Model:459223 | A_BSUK_Slabs | Identification - ID | Description: Stair 5
A-FloorsSlabs A_BSUK_Slabs | 1F | Stair 5 :7,SHE-06.FOURTH.dgn,Design Model:459292 | A_BSUK_Slabs | Identification - ID | Description: Stair 5
A-FloorsSlabs A_BSUK_Slabs | 1F | Stair 5 :7,SHE-06.FOURTH.dgn,Design Model:459359 | A_BSUK_Slabs | Identification - ID | Description: Stair 5
A-FloorsSlabs A_BSUK_Slabs | 1F | Stair 5 :7,SHE-06.FOURTH.dgn,Design Model:459387 | A_BSUK_Slabs | Identification - ID | Description: Stair 5
A-FloorsSlabs A_BSUK_Slabs | 1F | Stair 5 :7,SHE-06.FOURTH.dgn,Design Model:459415 | A_BSUK_Slabs | Identification - ID | Description: Stair 5
A-FloorsSlabs A_BSUK_Slabs | 1F | Stair 5 :7,SHE-06.FOURTH.dgn,Design Model:459443 | A_BSUK_Slabs | Identification - ID | Description: Stair 5
A-FloorsSlabs A_BSUK_Slabs | 1F | Stair 5 :7,SHE-06.FOURTH.dgn,Design Model:459471 | A_BSUK_Slabs | Identification - ID | Description: Stair 5
A-FloorsSlabs A_BSUK_Slabs | 1F | Stair 5 :7,SHE-06.FOURTH.dgn,Design Model:459499 | A_BSUK_Slabs | Identification - ID | Description: Stair 5
A-FloorsSlabs A_BSUK_Slabs | 1F | Stair 5 :7,SHE-06.FOURTH.dgn,Design Model:459527 | A_BSUK_Slabs | Identification - ID | Description: Stair 5
A-FloorsSlabs A_BSUK_Slabs | 1F | Stair 5 :7,SHE-06.FOURTH.dgn,Design Model:459555 | A_BSUK_Slabs | Identification - ID | Description: Stair 5
A-FloorsSlabs A_BSUK_Slabs | 1F | Stair 5 :7,SHE-06.FOURTH.dgn,Design Model:459569 | A_BSUK_Slabs | Identification - ID | Description: Stair 5
A-FloorsSlabs A_BSUK_Slabs | 1F | Stair 5 :7,SHE-06.FOURTH.dgn,Design Model:459581 | A_BSUK_Slabs | Identification - ID | Description: Stair 5
A-FloorsSlabs A_BSUK_Slabs | 1F | Stair 5 :7,SHE-06.FOURTH.dgn,Design Model:459596 | A_BSUK_Slabs | Identification - ID | Description: Stair 5
A-FloorsSlabs A_BSUK_Slabs | 1F | Stair 5 :7,SHE-06.FOURTH.dgn,Design Model:459721 | A_BSUK_Slabs | Identification - ID | Description: Stair 5
A-FloorsSlabs A_BSUK_Slabs | 1F | Stair 6 :7,SHE-06.FOURTH.dgn,Design Model:460213 | A_BSUK_Slabs | Identification - ID | Description: Stair 6
A-FloorsSlabs A_BSUK_Slabs | 1F | Stair 6 :7,SHE-06.FOURTH.dgn,Design Model:460228 | A_BSUK_Slabs | Identification - ID | Description: Stair 6
A-FloorsSlabs A_BSUK_Slabs | 1F | Stair 6 :7,SHE-06.FOURTH.dgn,Design Model:460243 | A_BSUK_Slabs | Identification - ID | Description: Stair 6
A-FloorsSlabs A_BSUK_Slabs | 1F | Stair 6 :7,SHE-06.FOURTH.dgn,Design Model:460258 | A_BSUK_Slabs | Identification - ID | Description: Stair 6
A-FloorsSlabs A_BSUK_Slabs | 1F | Stair 6 :7,SHE-06.FOURTH.dgn,Design Model:460273 | A_BSUK_Slabs | Identification - ID | Description: Stair 6
A-FloorsSlabs A_BSUK_Slabs | 1F | Stair 6 :7,SHE-06.FOURTH.dgn,Design Model:460288 | A_BSUK_Slabs | Identification - ID | Description: Stair 6
A-FloorsSlabs A_BSUK_Slabs | 1F | Stair 6 :7,SHE-06.FOURTH.dgn,Design Model:460289 | A_BSUK_Slabs | Identification - ID | Description: Stair 6
A-FloorsSlabs A_BSUK_Slabs | 1F | Stair 6 :7,SHE-06.FOURTH.dgn,Design Model:460301 | A_BSUK_Slabs | Identification - ID | Description: Stair 6
A-FloorsSlabs A_BSUK_Slabs | 1F | Stair 6 :7,SHE-06.FOURTH.dgn,Design Model:460316 | A_BSUK_Slabs | Identification - ID | Description: Stair 6
A-FloorsSlabs A_BSUK_Slabs | 1F | Stair 6 :7,SHE-06.FOURTH.dgn,Design Model:460342 | A_BSUK_Slabs | Identification - ID | Description: Stair 6
A-FloorsSlabs A_BSUK_Slabs | 1F | Stair 6 :7,SHE-06.FOURTH.dgn,Design Model:461413 | A_BSUK_Slabs | Identification - ID | Description: Stair 6
A-FloorsSlabs A_BSUK_Slabs | 1F | Stair 6 :7,SHE-06.FOURTH.dgn,Design Model:461463 | A_BSUK_Slabs | Identification - ID | Description: Stair 6
A-FloorsSlabs A_BSUK_Slabs | 1F | Stair 6 :7,SHE-06.FOURTH.dgn,Design Model:461475 | A_BSUK_Slabs | Identification - ID | Description: Stair 6
A-FloorsSlabs A_BSUK_Slabs | 1F | Stair 6 :7,SHE-06.FOURTH.dgn,Design Model:461490 | A_BSUK_Slabs | Identification - ID | Description: Stair 6
A-FloorsSlabs A_BSUK_Slabs | 1F | Stair 4 :7,SHE-06.FOURTH.dgn,Design Model:463136 | A_BSUK_Slabs | Identification - ID | Description: Stair 4
A-FloorsSlabs A_BSUK_Slabs | 1F | Stair 4 :7,SHE-06.FOURTH.dgn,Design Model:463137 | A_BSUK_Slabs | Identification - ID | Description: Stair 4
A-FloorsSlabs A_BSUK_Slabs | 1F | Stair 4 :7,SHE-06.FOURTH.dgn,Design Model:463138 | A_BSUK_Slabs | Identification - ID | Description: Stair 4
A-FloorsSlabs A_BSUK_Slabs | 1F | Stair 4 :7,SHE-06.FOURTH.dgn,Design Model:463139 | A_BSUK_Slabs | Identification - ID | Description: Stair 4
A-FloorsSlabs A_BSUK_Slabs | 1F | Stair 4 :7,SHE-06.FOURTH.dgn,Design Model:463140 | A_BSUK_Slabs | Identification - ID | Description: Stair 4
A-FloorsSlabs A_BSUK_Slabs | 1F | Stair 4 :7,SHE-06.FOURTH.dgn,Design Model:463141 | A_BSUK_Slabs | Identification - ID | Description: Stair 4
A-FloorsSlabs A_BSUK_Slabs | 1F | Stair 4 :7,SHE-06.FOURTH.dgn,Design Model:463142 | A_BSUK_Slabs | Identification - ID | Description: Stair 4
A-FloorsSlabs A_BSUK_Slabs | 1F | Stair 4 :7,SHE-06.FOURTH.dgn,Design Model:463143 | A_BSUK_Slabs | Identification - ID | Description: Stair 4
A-FloorsSlabs A_BSUK_Slabs | 1F | Stair 4 :7,SHE-06.FOURTH.dgn,Design Model:463144 | A_BSUK_Slabs | Identification - ID | Description: Stair 4
A-FloorsSlabs A_BSUK_Slabs | 1F | Stair 4 :7,SHE-06.FOURTH.dgn,Design Model:463145 | A_BSUK_Slabs | Identification - ID | Description: Stair 4
A-FloorsSlabs A_BSUK_Slabs | 1F | Stair 4 :7,SHE-06.FOURTH.dgn,Design Model:463146 | A_BSUK_Slabs | Identification - ID | Description: Stair 4
A-FloorsSlabs A_BSUK_Slabs | 1F | Stair 4 :7,SHE-06.FOURTH.dgn,Design Model:463147 | A_BSUK_Slabs | Identification - ID | Description: Stair 4
A-FloorsSlabs A_BSUK_Slabs | 1F | Stair 4 :7,SHE-06.FOURTH.dgn,Design Model:463148 | A_BSUK_Slabs | Identification - ID | Description: Stair 4
A-FloorsSlabs A_BSUK_Slabs | 1F | Stair 4 :7,SHE-06.FOURTH.dgn,Design Model:463149 | A_BSUK_Slabs | Identification - ID | Description: Stair 4
A-FloorsSlabs A_BSUK_Slabs | 1F | Stair 3 :7,SHE-06.FOURTH.dgn,Design Model:463516 | A_BSUK_Slabs | Identification - ID | Description: Stair 3
A-FloorsSlabs A_BSUK_Slabs | 1F | Stair 3 :7,SHE-06.FOURTH.dgn,Design Model:463517 | A_BSUK_Slabs | Identification - ID | Description: Stair 3
A-FloorsSlabs A_BSUK_Slabs | 1F | Stair 3 :7,SHE-06.FOURTH.dgn,Design Model:463518 | A_BSUK_Slabs | Identification - ID | Description: Stair 3
A-FloorsSlabs A_BSUK_Slabs | 1F | Stair 3 :7,SHE-06.FOURTH.dgn,Design Model:463519 | A_BSUK_Slabs | Identification - ID | Description: Stair 3
A-FloorsSlabs A_BSUK_Slabs | 1F | Stair 3 :7,SHE-06.FOURTH.dgn,Design Model:463520 | A_BSUK_Slabs | Identification - ID | Description: Stair 3
A-FloorsSlabs A_BSUK_Slabs | 1F | Stair 3 :7,SHE-06.FOURTH.dgn,Design Model:463521 | A_BSUK_Slabs | Identification - ID | Description: Stair 3
A-FloorsSlabs A_BSUK_Slabs | 1F | Stair 3 :7,SHE-06.FOURTH.dgn,Design Model:463522 | A_BSUK_Slabs | Identification - ID | Description: Stair 3
A-FloorsSlabs A_BSUK_Slabs | 1F | Stair 3 :7,SHE-06.FOURTH.dgn,Design Model:463523 | A_BSUK_Slabs | Identification - ID | Description: Stair 3
A-FloorsSlabs A_BSUK_Slabs | 1F | Stair 3 :7,SHE-06.FOURTH.dgn,Design Model:463524 | A_BSUK_Slabs | Identification - ID | Description: Stair 3
A-FloorsSlabs A_BSUK_Slabs | 1F | Stair 3 :7,SHE-06.FOURTH.dgn,Design Model:463525 | A_BSUK_Slabs | Identification - ID | Description: Stair 3
A-FloorsSlabs A_BSUK_Slabs | 1F | Stair 3 :7,SHE-06.FOURTH.dgn,Design Model:463526 | A_BSUK_Slabs | Identification - ID | Description: Stair 3
A-FloorsSlabs A_BSUK_Slabs | 1F | Stair 3 :7,SHE-06.FOURTH.dgn,Design Model:463527 | A_BSUK_Slabs | Identification - ID | Description: Stair 3
A-FloorsSlabs A_BSUK_Slabs | 1F | Stair 3 :7,SHE-06.FOURTH.dgn,Design Model:463528 | A_BSUK_Slabs | Identification - ID | Description: Stair 3
A-FloorsSlabs A_BSUK_Slabs | 1F | Stair 3 :7,SHE-06.FOURTH.dgn,Design Model:463911 | A_BSUK_Slabs | Identification - ID | Description: Stair 3
A-FloorsSlabs A_BSUK_Slabs | 1F | Fire board - ceiling (120 min) :7,SHE-06.FOURTH.dgn,Design Model:467098 | A_BSUK_CeilingSoffitFinishes_Suspended | New Construction | A-Ceilings::A_BSUK_CeilingSoffitFinishes_Suspended | Identification - ID | Description: Fire board - ceiling (120 min)
A-FloorsSlabs A_BSUK_Slabs | 1F | Fire board - ceiling (120 min) :7,SHE-06.FOURTH.dgn,Design Model:468012 | A_BSUK_CeilingSoffitFinishes_Suspended | New Construction | A-Ceilings::A_BSUK_CeilingSoffitFinishes_Suspended | Identification - ID | Description: Fire board - ceiling (120 min)
A-FloorsSlabs A_BSUK_Slabs | 1F | plasterboard - ceiling :7,SHE-06.FOURTH.dgn,Design Model:473692 | A_BSUK_CeilingSoffitFinishes_Suspended | New Construction | A-Ceilings::A_BSUK_CeilingSoffitFinishes_Suspended | Identification - ID | Description: plasterboard - ceiling
A-FloorsSlabs A_BSUK_Slabs | 1F | plasterboard - ceiling :7,SHE-06.FOURTH.dgn,Design Model:489881 | A_BSUK_CeilingSoffitFinishes_Suspended | New Construction | A-Ceilings::A_BSUK_CeilingSoffitFinishes_Suspended | Identification - ID | Description: plasterboard - ceiling
A-FloorsSlabs A_BSUK_Slabs | 1F | plasterboard - ceiling :7,SHE-06.FOURTH.dgn,Design Model:491293 | A_BSUK_CeilingSoffitFinishes_Suspended | New Construction | A-Ceilings::A_BSUK_CeilingSoffitFinishes_Suspended | Identification - ID | Description: plasterboard - ceiling
A-FloorsSlabs A_BSUK_Slabs | 1F | plasterboard - ceiling :7,SHE-06.FOURTH.dgn,Design Model:492526 | A_BSUK_CeilingSoffitFinishes_Suspended | New Construction | A-Ceilings::A_BSUK_CeilingSoffitFinishes_Suspended | Identification - ID | Description: plasterboard - ceiling
A-FloorsSlabs A_BSUK_Slabs | 1F | 7 ,SHE-06.FOURTH.dgn,Design Model:501214 | A_BSUK_CeilingSoffitFinishes_Suspended | New Construction | A-Ceilings::A_BSUK_CeilingSoffitFinishes_Suspended
A-FloorsSlabs A_BSUK_Slabs | 1F | 7 ,SHE-06.FOURTH.dgn,Design Model:501244 | A_BSUK_CeilingSoffitFinishes_Suspended | New Construction | A-Ceilings::A_BSUK_CeilingSoffitFinishes_Suspended
A-FloorsSlabs A_BSUK_Slabs | 1F | 7 ,SHE-06.FOURTH.dgn,Design Model:501324 | A_BSUK_CeilingSoffitFinishes_Suspended | New Construction | A-Ceilings::A_BSUK_CeilingSoffitFinishes_Suspended
A-FloorsSlabs A_BSUK_Slabs | 1F | 7 ,SHE-06.FOURTH.dgn,Design Model:501360 | A_BSUK_CeilingSoffitFinishes_Suspended | New Construction | A-Ceilings::A_BSUK_CeilingSoffitFinishes_Suspended
A-FloorsSlabs A_BSUK_Slabs | 1F | 7 ,SHE-06.FOURTH.dgn,Design Model:505726 | A_BSUK_CeilingSoffitFinishes_Suspended | New Construction | A-Ceilings::A_BSUK_CeilingSoffitFinishes_Suspended
A-FloorsSlabs A_BSUK_Slabs | 1F | 7 ,SHE-06.FOURTH.dgn,Design Model:505871 | A_BSUK_CeilingSoffitFinishes_Suspended | New Construction | A-Ceilings::A_BSUK_CeilingSoffitFinishes_Suspended
A-FloorsSlabs A_BSUK_Slabs | 1F | 7 ,SHE-06.FOURTH.dgn,Design Model:505938 | A_BSUK_CeilingSoffitFinishes_Suspended | New Construction | A-Ceilings::A_BSUK_CeilingSoffitFinishes_Suspended
A-FloorsSlabs A_BSUK_Slabs | 1F | 7 ,SHE-06.FOURTH.dgn,Design Model:505979 | A_BSUK_CeilingSoffitFinishes_Suspended | New Construction | A-Ceilings::A_BSUK_CeilingSoffitFinishes_Suspended
A-FloorsSlabs A_BSUK_Slabs | 1F | 7 ,SHE-06.FOURTH.dgn,Design Model:506020 | A_BSUK_CeilingSoffitFinishes_Suspended | New Construction | A-Ceilings::A_BSUK_CeilingSoffitFinishes_Suspended
A-FloorsSlabs A_BSUK_Slabs | 1F | 7 ,SHE-06.FOURTH.dgn,Design Model:514022 | A_BSUK_Ceramic_WallTiles | New Construction | A-Finishes::A_BSUK_Ceramic_WallTiles
A-FloorsSlabs A_BSUK_Slabs | 1F | 7 ,SHE-06.FOURTH.dgn,Design Model:514111 | A_BSUK_Ceramic_WallTiles | New Construction | A-Finishes::A_BSUK_Ceramic_WallTiles
A-FloorsSlabs A_BSUK_Slabs | 5F | 8 ,SHE-07.FIFTH.dgn,Design Model:119427 | A_BSUK_Roofs |  | A-Roofs::A_BSUK_Roofs
A-FloorsSlabs A_BSUK_Slabs | 5F | 8 ,SHE-07.FIFTH.dgn,Design Model:120266 | A_BSUK_Roofs |  | A-Roofs::A_BSUK_Roofs
A-FloorsSlabs A_BSUK_Slabs | 5F | 8 ,SHE-07.FIFTH.dgn,Design Model:120377 | A_BSUK_Roofs |  | A-Roofs::A_BSUK_Roofs
A-FloorsSlabs A_BSUK_Slabs | 5F | 8 ,SHE-07.FIFTH.dgn,Design Model:120417 | A_BSUK_Roofs |  | A-Roofs::A_BSUK_Roofs
A-FloorsSlabs A_BSUK_Slabs | 5F | 8 ,SHE-07.FIFTH.dgn,Design Model:125642 | A_BSUK_Slabs
A-FloorsSlabs A_BSUK_Slabs | 5F | 8 ,SHE-07.FIFTH.dgn,Design Model:128062 | A_BSUK_Slabs | New Construction
A-FloorsSlabs A_BSUK_Slabs | 5F | 8 ,SHE-07.FIFTH.dgn,Design Model:128169 | A_BSUK_Slabs | New Construction
A-FloorsSlabs A_BSUK_Slabs | 5F | GIFA floor :8,SHE-07.FIFTH.dgn,Design Model:165428 | A_BSUK_InternalFinishes_FloorScreed | New Construction | A-FloorsSlabs::A_BSUK_InternalFinishes_FloorScreed | Identification - ID | Description: GIFA floor
A-FloorsSlabs A_BSUK_Slabs | 5F | 8 ,SHE-07.FIFTH.dgn,Design Model:177279 | A_BSUK_ExpandedPolystyreneBoards | New Construction | A-FloorsSlabs::A_BSUK_ExpandedPolystyreneBoards
A-FloorsSlabs A_BSUK_Slabs | 5F | 8 ,SHE-07.FIFTH.dgn,Design Model:177361 | A_BSUK_ExpandedPolystyreneBoards | New Construction | A-FloorsSlabs::A_BSUK_ExpandedPolystyreneBoards
A-FloorsSlabs A_BSUK_Slabs | 5F | 8 ,SHE-07.FIFTH.dgn,Design Model:177425 | A_BSUK_ExpandedPolystyreneBoards | New Construction | A-FloorsSlabs::A_BSUK_ExpandedPolystyreneBoards
A-FloorsSlabs A_BSUK_Slabs | 5F | 8 ,SHE-07.FIFTH.dgn,Design Model:177489 | A_BSUK_ExpandedPolystyreneBoards | New Construction | A-FloorsSlabs::A_BSUK_ExpandedPolystyreneBoards
A-FloorsSlabs A_BSUK_Slabs | 5F | 8 ,SHE-07.FIFTH.dgn,Design Model:177919 | A_BSUK_Parquet_Floor | New Construction | A-Finishes::A_BSUK_Parquet_Floor
A-FloorsSlabs A_BSUK_Slabs | 5F | 8 ,SHE-07.FIFTH.dgn,Design Model:177920 | A_BSUK_Parquet_Floor | New Construction | A-Finishes::A_BSUK_Parquet_Floor
A-FloorsSlabs A_BSUK_Slabs | 5F | 8 ,SHE-07.FIFTH.dgn,Design Model:177921 | A_BSUK_Parquet_Floor | New Construction | A-Finishes::A_BSUK_Parquet_Floor
A-FloorsSlabs A_BSUK_Slabs | 5F | 8 ,SHE-07.FIFTH.dgn,Design Model:177922 | A_BSUK_Parquet_Floor | New Construction | A-Finishes::A_BSUK_Parquet_Floor
A-FloorsSlabs A_BSUK_Slabs | 5F | 8 ,SHE-07.FIFTH.dgn,Design Model:186063 | A_BSUK_CeilingSoffitFinishes_Suspended | New Construction | A-Ceilings::A_BSUK_CeilingSoffitFinishes_Suspended
A-FloorsSlabs A_BSUK_Slabs | 5F | 8 ,SHE-07.FIFTH.dgn,Design Model:186432 | A_BSUK_CeilingSoffitFinishes_Suspended | New Construction | A-Ceilings::A_BSUK_CeilingSoffitFinishes_Suspended
A-FloorsSlabs A_BSUK_Slabs | 5F | 8 ,SHE-07.FIFTH.dgn,Design Model:186499 | A_BSUK_CeilingSoffitFinishes_Suspended | New Construction | A-Ceilings::A_BSUK_CeilingSoffitFinishes_Suspended
A-FloorsSlabs A_BSUK_Slabs | 5F | 8 ,SHE-07.FIFTH.dgn,Design Model:186553 | A_BSUK_CeilingSoffitFinishes_Suspended | New Construction | A-Ceilings::A_BSUK_CeilingSoffitFinishes_Suspended
A-FloorsSlabs A_BSUK_Slabs | 5F | 8 ,SHE-07.FIFTH.dgn,Design Model:186581 | A_BSUK_CeilingSoffitFinishes_Suspended | New Construction | A-Ceilings::A_BSUK_CeilingSoffitFinishes_Suspended
A-FloorsSlabs A_BSUK_Slabs | 5F | 8 ,SHE-07.FIFTH.dgn,Design Model:186609 | A_BSUK_CeilingSoffitFinishes_Suspended | New Construction | A-Ceilings::A_BSUK_CeilingSoffitFinishes_Suspended
A-FloorsSlabs A_BSUK_Slabs | 5F | 8 ,SHE-07.FIFTH.dgn,Design Model:186637 | A_BSUK_CeilingSoffitFinishes_Suspended | New Construction | A-Ceilings::A_BSUK_CeilingSoffitFinishes_Suspended
A-FloorsSlabs A_BSUK_Slabs | 5F | 8 ,SHE-07.FIFTH.dgn,Design Model:186665 | A_BSUK_CeilingSoffitFinishes_Suspended | New Construction | A-Ceilings::A_BSUK_CeilingSoffitFinishes_Suspended
A-FloorsSlabs A_BSUK_Slabs | 5F | 8 ,SHE-07.FIFTH.dgn,Design Model:186882 | A_BSUK_CeilingSoffitFinishes_Suspended | New Construction | A-Ceilings::A_BSUK_CeilingSoffitFinishes_Suspended
A-FloorsSlabs A_BSUK_Slabs | 5F | 8 ,SHE-07.FIFTH.dgn,Design Model:187054 | A_BSUK_CeilingSoffitFinishes_Suspended | New Construction | A-Ceilings::A_BSUK_CeilingSoffitFinishes_Suspended
A-FloorsSlabs A_BSUK_Slabs | 5F | 8 ,SHE-07.FIFTH.dgn,Design Model:187631 | A_BSUK_CeilingSoffitFinishes_Suspended | New Construction | A-Ceilings::A_BSUK_CeilingSoffitFinishes_Suspended
A-FloorsSlabs A_BSUK_Slabs | 5F | 8 ,SHE-07.FIFTH.dgn,Design Model:188153 | A_BSUK_CeilingSoffitFinishes_Suspended | New Construction | A-Ceilings::A_BSUK_CeilingSoffitFinishes_Suspended
A-FloorsSlabs A_BSUK_Slabs | 5F | 8 ,SHE-07.FIFTH.dgn,Design Model:188991 | A_BSUK_CeilingSoffitFinishes_Suspended | New Construction | A-Ceilings::A_BSUK_CeilingSoffitFinishes_Suspended
A-FloorsSlabs A_BSUK_Slabs | 5F | 8 ,SHE-07.FIFTH.dgn,Design Model:189067 | A_BSUK_CeilingSoffitFinishes_Suspended | New Construction | A-Ceilings::A_BSUK_CeilingSoffitFinishes_Suspended
A-FloorsSlabs A_BSUK_Slabs | 5F | 8 ,SHE-07.FIFTH.dgn,Design Model:189654 | A_BSUK_CeilingSoffitFinishes_Suspended | New Construction | A-Ceilings::A_BSUK_CeilingSoffitFinishes_Suspended
A-FloorsSlabs A_BSUK_Slabs | 5F | 8 ,SHE-07.FIFTH.dgn,Design Model:189957 | A_BSUK_CeilingSoffitFinishes_Suspended | New Construction | A-Ceilings::A_BSUK_CeilingSoffitFinishes_Suspended
A-FloorsSlabs A_BSUK_Slabs | 5F | 8 ,SHE-07.FIFTH.dgn,Design Model:193630 | A_BSUK_CeilingSoffitFinishes_Suspended | New Construction | A-Ceilings::A_BSUK_CeilingSoffitFinishes_Suspended
A-FloorsSlabs A_BSUK_Slabs | 5F | 8 ,SHE-07.FIFTH.dgn,Design Model:194352 | A_BSUK_CeilingSoffitFinishes_Suspended | New Construction | A-Ceilings::A_BSUK_CeilingSoffitFinishes_Suspended
A-FloorsSlabs A_BSUK_Slabs | 5F | 8 ,SHE-07.FIFTH.dgn,Design Model:194432 | A_BSUK_CeilingSoffitFinishes_Suspended | New Construction | A-Ceilings::A_BSUK_CeilingSoffitFinishes_Suspended
A-FloorsSlabs A_BSUK_Slabs | 5F | 8 ,SHE-07.FIFTH.dgn,Design Model:194473 | A_BSUK_CeilingSoffitFinishes_Suspended | New Construction | A-Ceilings::A_BSUK_CeilingSoffitFinishes_Suspended
A-FloorsSlabs A_BSUK_Slabs | 5F | 8 ,SHE-07.FIFTH.dgn,Design Model:194838 | A_BSUK_CeilingSoffitFinishes_Suspended | New Construction | A-Ceilings::A_BSUK_CeilingSoffitFinishes_Suspended
A-FloorsSlabs A_BSUK_Slabs | 5F | 8 ,SHE-07.FIFTH.dgn,Design Model:194839 | A_BSUK_CeilingSoffitFinishes_Suspended | New Construction | A-Ceilings::A_BSUK_CeilingSoffitFinishes_Suspended
A-FloorsSlabs A_BSUK_Slabs | 5F | 8 ,SHE-07.FIFTH.dgn,Design Model:194894 | A_BSUK_CeilingSoffitFinishes_Suspended | New Construction | A-Ceilings::A_BSUK_CeilingSoffitFinishes_Suspended
A-FloorsSlabs A_BSUK_Slabs | 5F | 8 ,SHE-07.FIFTH.dgn,Design Model:194895 | A_BSUK_CeilingSoffitFinishes_Suspended | New Construction | A-Ceilings::A_BSUK_CeilingSoffitFinishes_Suspended
A-FloorsSlabs A_BSUK_Slabs | 5F | 8 ,SHE-07.FIFTH.dgn,Design Model:194950 | A_BSUK_CeilingSoffitFinishes_Suspended | New Construction | A-Ceilings::A_BSUK_CeilingSoffitFinishes_Suspended
A-FloorsSlabs A_BSUK_Slabs | 5F | 8 ,SHE-07.FIFTH.dgn,Design Model:194951 | A_BSUK_CeilingSoffitFinishes_Suspended | New Construction | A-Ceilings::A_BSUK_CeilingSoffitFinishes_Suspended
A-FloorsSlabs A_BSUK_Slabs | 5F | 8 ,SHE-07.FIFTH.dgn,Design Model:195006 | A_BSUK_CeilingSoffitFinishes_Suspended | New Construction | A-Ceilings::A_BSUK_CeilingSoffitFinishes_Suspended
A-FloorsSlabs A_BSUK_Slabs | 5F | 8 ,SHE-07.FIFTH.dgn,Design Model:195007 | A_BSUK_CeilingSoffitFinishes_Suspended | New Construction | A-Ceilings::A_BSUK_CeilingSoffitFinishes_Suspended
A-FloorsSlabs A_BSUK_Slabs | 5F | 8 ,SHE-07.FIFTH.dgn,Design Model:195061 | A_BSUK_CeilingSoffitFinishes_Suspended | New Construction | A-Ceilings::A_BSUK_CeilingSoffitFinishes_Suspended
A-FloorsSlabs A_BSUK_Slabs | 5F | 8 ,SHE-07.FIFTH.dgn,Design Model:195102 | A_BSUK_CeilingSoffitFinishes_Suspended | New Construction | A-Ceilings::A_BSUK_CeilingSoffitFinishes_Suspended
A-FloorsSlabs A_BSUK_Slabs | 5F | 8 ,SHE-07.FIFTH.dgn,Design Model:195130 | A_BSUK_CeilingSoffitFinishes_Suspended | New Construction | A-Ceilings::A_BSUK_CeilingSoffitFinishes_Suspended
A-FloorsSlabs A_BSUK_Slabs | 5F | 8 ,SHE-07.FIFTH.dgn,Design Model:195171 | A_BSUK_CeilingSoffitFinishes_Suspended | New Construction | A-Ceilings::A_BSUK_CeilingSoffitFinishes_Suspended
A-FloorsSlabs A_BSUK_Slabs | 5F | 8 ,SHE-07.FIFTH.dgn,Design Model:195213 | A_BSUK_CeilingSoffitFinishes_Suspended | New Construction | A-Ceilings::A_BSUK_CeilingSoffitFinishes_Suspended
A-FloorsSlabs A_BSUK_Slabs | 5F | 8 ,SHE-07.FIFTH.dgn,Design Model:195214 | A_BSUK_CeilingSoffitFinishes_Suspended | New Construction | A-Ceilings::A_BSUK_CeilingSoffitFinishes_Suspended
A-FloorsSlabs A_BSUK_Slabs | 5F | 8 ,SHE-07.FIFTH.dgn,Design Model:195255 | A_BSUK_CeilingSoffitFinishes_Suspended | New Construction | A-Ceilings::A_BSUK_CeilingSoffitFinishes_Suspended
A-FloorsSlabs A_BSUK_Slabs | 5F | 8 ,SHE-07.FIFTH.dgn,Design Model:195283 | A_BSUK_CeilingSoffitFinishes_Suspended | New Construction | A-Ceilings::A_BSUK_CeilingSoffitFinishes_Suspended
A-FloorsSlabs A_BSUK_Slabs | 5F | 8 ,SHE-07.FIFTH.dgn,Design Model:195311 | A_BSUK_CeilingSoffitFinishes_Suspended | New Construction | A-Ceilings::A_BSUK_CeilingSoffitFinishes_Suspended
A-FloorsSlabs A_BSUK_Slabs | 5F | 8 ,SHE-07.FIFTH.dgn,Design Model:195352 | A_BSUK_CeilingSoffitFinishes_Suspended | New Construction | A-Ceilings::A_BSUK_CeilingSoffitFinishes_Suspended
A-FloorsSlabs A_BSUK_Slabs | 5F | 8 ,SHE-07.FIFTH.dgn,Design Model:195380 | A_BSUK_CeilingSoffitFinishes_Suspended | New Construction | A-Ceilings::A_BSUK_CeilingSoffitFinishes_Suspended
A-FloorsSlabs A_BSUK_Slabs | 5F | 8 ,SHE-07.FIFTH.dgn,Design Model:195421 | A_BSUK_CeilingSoffitFinishes_Suspended | New Construction | A-Ceilings::A_BSUK_CeilingSoffitFinishes_Suspended
A-FloorsSlabs A_BSUK_Slabs | 5F | 8 ,SHE-07.FIFTH.dgn,Design Model:195463 | A_BSUK_CeilingSoffitFinishes_Suspended | New Construction | A-Ceilings::A_BSUK_CeilingSoffitFinishes_Suspended
A-FloorsSlabs A_BSUK_Slabs | 5F | 8 ,SHE-07.FIFTH.dgn,Design Model:195464 | A_BSUK_CeilingSoffitFinishes_Suspended | New Construction | A-Ceilings::A_BSUK_CeilingSoffitFinishes_Suspended
A-FloorsSlabs A_BSUK_Slabs | 5F | 8 ,SHE-07.FIFTH.dgn,Design Model:195533 | A_BSUK_CeilingSoffitFinishes_Suspended | New Construction | A-Ceilings::A_BSUK_CeilingSoffitFinishes_Suspended
A-FloorsSlabs A_BSUK_Slabs | 5F | 8 ,SHE-07.FIFTH.dgn,Design Model:195574 | A_BSUK_CeilingSoffitFinishes_Suspended | New Construction | A-Ceilings::A_BSUK_CeilingSoffitFinishes_Suspended
A-FloorsSlabs A_BSUK_Slabs | 5F | 8 ,SHE-07.FIFTH.dgn,Design Model:195631 | A_BSUK_CeilingSoffitFinishes_Suspended | New Construction | A-Ceilings::A_BSUK_CeilingSoffitFinishes_Suspended
A-FloorsSlabs A_BSUK_Slabs | 5F | 8 ,SHE-07.FIFTH.dgn,Design Model:195632 | A_BSUK_CeilingSoffitFinishes_Suspended | New Construction | A-Ceilings::A_BSUK_CeilingSoffitFinishes_Suspended
A-FloorsSlabs A_BSUK_Slabs | 5F | 8 ,SHE-07.FIFTH.dgn,Design Model:195686 | A_BSUK_CeilingSoffitFinishes_Suspended | New Construction | A-Ceilings::A_BSUK_CeilingSoffitFinishes_Suspended
A-FloorsSlabs A_BSUK_Slabs | 5F | 8 ,SHE-07.FIFTH.dgn,Design Model:195727 | A_BSUK_CeilingSoffitFinishes_Suspended | New Construction | A-Ceilings::A_BSUK_CeilingSoffitFinishes_Suspended
A-FloorsSlabs A_BSUK_Slabs | 5F | 8 ,SHE-07.FIFTH.dgn,Design Model:266283 | A_BSUK_CeilingSoffitFinishes_Suspended | New Construction | A-Ceilings::A_BSUK_CeilingSoffitFinishes_Suspended
A-FloorsSlabs A_BSUK_Slabs | 5F | 8 ,SHE-07.FIFTH.dgn,Design Model:266328 | A_BSUK_CeilingSoffitFinishes_Suspended | New Construction | A-Ceilings::A_BSUK_CeilingSoffitFinishes_Suspended
A-FloorsSlabs A_BSUK_Slabs | 5F | 8 ,SHE-07.FIFTH.dgn,Design Model:266349 | A_BSUK_CeilingSoffitFinishes_Suspended | New Construction | A-Ceilings::A_BSUK_CeilingSoffitFinishes_Suspended
A-FloorsSlabs A_BSUK_Slabs | 5F | 8 ,SHE-07.FIFTH.dgn,Design Model:266689 | A_BSUK_CeilingSoffitFinishes_Suspended | New Construction | A-Ceilings::A_BSUK_CeilingSoffitFinishes_Suspended
A-FloorsSlabs A_BSUK_Slabs | 5F | 8 ,SHE-07.FIFTH.dgn,Design Model:266873 | A_BSUK_CeilingSoffitFinishes_Suspended | New Construction | A-Ceilings::A_BSUK_CeilingSoffitFinishes_Suspended
A-FloorsSlabs A_BSUK_Slabs | 5F | 8 ,SHE-07.FIFTH.dgn,Design Model:266918 | A_BSUK_CeilingSoffitFinishes_Suspended | New Construction | A-Ceilings::A_BSUK_CeilingSoffitFinishes_Suspended
A-FloorsSlabs A_BSUK_Slabs | 5F | 8 ,SHE-07.FIFTH.dgn,Design Model:266939 | A_BSUK_CeilingSoffitFinishes_Suspended | New Construction | A-Ceilings::A_BSUK_CeilingSoffitFinishes_Suspended
A-FloorsSlabs A_BSUK_Slabs | 5F | 8 ,SHE-07.FIFTH.dgn,Design Model:266960 | A_BSUK_CeilingSoffitFinishes_Suspended | New Construction | A-Ceilings::A_BSUK_CeilingSoffitFinishes_Suspended
A-FloorsSlabs A_BSUK_Slabs | 5F | 8 ,SHE-07.FIFTH.dgn,Design Model:295615 | A_BSUK_CeilingSoffitFinishes_Suspended | New Construction | A-Ceilings::A_BSUK_CeilingSoffitFinishes_Suspended
A-FloorsSlabs A_BSUK_Slabs | 5F | 8 ,SHE-07.FIFTH.dgn,Design Model:295813 | A_BSUK_CeilingSoffitFinishes_Suspended | New Construction | A-Ceilings::A_BSUK_CeilingSoffitFinishes_Suspended
A-FloorsSlabs A_BSUK_Slabs | 5F | 8 ,SHE-07.FIFTH.dgn,Design Model:295946 | A_BSUK_CeilingSoffitFinishes_Suspended | New Construction | A-Ceilings::A_BSUK_CeilingSoffitFinishes_Suspended
A-FloorsSlabs A_BSUK_Slabs | 5F | 8 ,SHE-07.FIFTH.dgn,Design Model:295947 | A_BSUK_CeilingSoffitFinishes_Suspended | New Construction | A-Ceilings::A_BSUK_CeilingSoffitFinishes_Suspended
A-FloorsSlabs A_BSUK_Slabs | 5F | 8 ,SHE-07.FIFTH.dgn,Design Model:296100 | A_BSUK_CeilingSoffitFinishes_Suspended | New Construction | A-Ceilings::A_BSUK_CeilingSoffitFinishes_Suspended
A-FloorsSlabs A_BSUK_Slabs | 5F | 8 ,SHE-07.FIFTH.dgn,Design Model:296101 | A_BSUK_CeilingSoffitFinishes_Suspended | New Construction | A-Ceilings::A_BSUK_CeilingSoffitFinishes_Suspended
A-FloorsSlabs A_BSUK_Slabs | 5F | 8 ,SHE-07.FIFTH.dgn,Design Model:296251 | A_BSUK_CeilingSoffitFinishes_Suspended | New Construction | A-Ceilings::A_BSUK_CeilingSoffitFinishes_Suspended
A-FloorsSlabs A_BSUK_Slabs | 5F | 8 ,SHE-07.FIFTH.dgn,Design Model:296252 | A_BSUK_CeilingSoffitFinishes_Suspended | New Construction | A-Ceilings::A_BSUK_CeilingSoffitFinishes_Suspended
A-FloorsSlabs A_BSUK_Slabs | GF | 9 ,SHE-10.CONCRETE.dgn,Design Model:205626 | A_BSUK_Slabs | Existing to Remain
A-FloorsSlabs A_BSUK_Slabs | GF | 9 ,SHE-10.CONCRETE.dgn,Design Model:205640 | A_BSUK_Slabs | Existing to Remain
A-FloorsSlabs A_BSUK_Slabs | GF | 9 ,SHE-10.CONCRETE.dgn,Design Model:205654 | A_BSUK_Slabs | Existing to Remain
A-FloorsSlabs A_BSUK_Slabs | GF | 9 ,SHE-10.CONCRETE.dgn,Design Model:205668 | A_BSUK_Slabs | Existing to Remain
A-FloorsSlabs A_BSUK_Slabs | GF | 9 ,SHE-10.CONCRETE.dgn,Design Model:205682 | A_BSUK_Slabs | Existing to Remain
A-FloorsSlabs A_BSUK_Slabs | GF | 9 ,SHE-10.CONCRETE.dgn,Design Model:205696 | A_BSUK_Slabs | Existing to Remain
A-FloorsSlabs A_BSUK_Slabs | GF | 9 ,SHE-10.CONCRETE.dgn,Design Model:205710 | A_BSUK_Slabs | Existing to Remain
A-FloorsSlabs A_BSUK_Slabs | GF | 9 ,SHE-10.CONCRETE.dgn,Design Model:205724 | A_BSUK_Slabs | Existing to Remain
A-FloorsSlabs A_BSUK_Slabs | GF | 9 ,SHE-10.CONCRETE.dgn,Design Model:205752 | A_BSUK_Slabs | Existing to Remain
A-FloorsSlabs A_BSUK_Slabs | GF | 9 ,SHE-10.CONCRETE.dgn,Design Model:205766 | A_BSUK_Slabs | Existing to Remain
A-FloorsSlabs A_BSUK_Slabs | GF | 9 ,SHE-10.CONCRETE.dgn,Design Model:205780 | A_BSUK_Slabs | Existing to Remain
A-FloorsSlabs A_BSUK_Slabs | GF | 9 ,SHE-10.CONCRETE.dgn,Design Model:205794 | A_BSUK_Slabs | Existing to Remain
A-FloorsSlabs A_BSUK_Slabs | GF | 9 ,SHE-10.CONCRETE.dgn,Design Model:222997 | A_BSUK_Slabs | Existing to Remain
A-FloorsSlabs A_BSUK_Slabs | GF | 9 ,SHE-10.CONCRETE.dgn,Design Model:223011 | A_BSUK_Slabs | Existing to Remain
A-FloorsSlabs A_BSUK_Slabs | GF | 9 ,SHE-10.CONCRETE.dgn,Design Model:205625 | A_BSUK_Slabs | Existing to Remain
A-FloorsSlabs A_BSUK_Slabs | GF | 9 ,SHE-10.CONCRETE.dgn,Design Model:205834 | A_BSUK_Slabs
A-FloorsSlabs A_BSUK_Slabs | GF | 9 ,SHE-10.CONCRETE.dgn,Design Model:205982 | A_BSUK_Slabs
A-FloorsSlabs A_BSUK_Slabs | GF | 9 ,SHE-10.CONCRETE.dgn,Design Model:209136 | A_BSUK_Slabs | Existing to Remain
A-FloorsSlabs A_BSUK_Slabs | GF | 9 ,SHE-10.CONCRETE.dgn,Design Model:209137 | A_BSUK_Slabs | Existing to Remain
A-FloorsSlabs A_BSUK_Slabs | GF | 9 ,SHE-10.CONCRETE.dgn,Design Model:209206 | A_BSUK_Slabs | Existing to Remain
A-FloorsSlabs A_BSUK_Slabs | GF | 9 ,SHE-10.CONCRETE.dgn,Design Model:209616 | A_BSUK_Slabs | Existing to Remain
A-FloorsSlabs A_BSUK_Slabs | GF | 9 ,SHE-10.CONCRETE.dgn,Design Model:211024 | A_BSUK_Slabs | Existing to Remain
A-FloorsSlabs A_BSUK_Slabs | GF | 9 ,SHE-10.CONCRETE.dgn,Design Model:211025 | A_BSUK_Slabs | Existing to Remain
A-FloorsSlabs A_BSUK_Slabs | GF | 9 ,SHE-10.CONCRETE.dgn,Design Model:211092 | A_BSUK_Slabs | Existing to Remain
A-FloorsSlabs A_BSUK_Slabs | GF | 9 ,SHE-10.CONCRETE.dgn,Design Model:211093 | A_BSUK_Slabs | Existing to Remain
A-FloorsSlabs A_BSUK_Slabs | GF | 9 ,SHE-10.CONCRETE.dgn,Design Model:211315 | A_BSUK_Slabs | Existing to Remain
A-FloorsSlabs A_BSUK_Slabs | RL | 10 ,SHE-08.ROOF.dgn,Design Model:105330 | A_BSUK_Roofs | New Construction | A-Roofs::A_BSUK_Roofs
A-FloorsSlabs A_BSUK_Slabs | RL | 10 ,SHE-08.ROOF.dgn,Design Model:105344 | A_BSUK_Roofs | New Construction | A-Roofs::A_BSUK_Roofs
A-FloorsSlabs A_BSUK_Slabs | RL | 10 ,SHE-08.ROOF.dgn,Design Model:105359 | A_BSUK_Roofs | New Construction | A-Roofs::A_BSUK_Roofs
A-FloorsSlabs A_BSUK_Slabs | RL | 10 ,SHE-08.ROOF.dgn,Design Model:105370 | A_BSUK_Roofs | New Construction | A-Roofs::A_BSUK_Roofs
A-FloorsSlabs A_BSUK_Slabs | RL | 10 ,SHE-08.ROOF.dgn,Design Model:105384 | A_BSUK_Roofs | New Construction | A-Roofs::A_BSUK_Roofs
A-FloorsSlabs A_BSUK_Slabs | RL | 10 ,SHE-08.ROOF.dgn,Design Model:105398 | A_BSUK_Roofs | New Construction | A-Roofs::A_BSUK_Roofs
A-FloorsSlabs A_BSUK_Slabs | RL | 10 ,SHE-08.ROOF.dgn,Design Model:105412 | A_BSUK_Roofs | New Construction | A-Roofs::A_BSUK_Roofs
A-FloorsSlabs A_BSUK_Slabs | RL | 10 ,SHE-08.ROOF.dgn,Design Model:105426 | A_BSUK_Roofs | New Construction | A-Roofs::A_BSUK_Roofs
A-FloorsSlabs A_BSUK_Slabs | RL | 10 ,SHE-08.ROOF.dgn,Design Model:105440 | A_BSUK_Roofs | New Construction | A-Roofs::A_BSUK_Roofs
A-FloorsSlabs A_BSUK_Slabs | RL | 10 ,SHE-08.ROOF.dgn,Design Model:105454 | A_BSUK_Roofs | New Construction | A-Roofs::A_BSUK_Roofs
A-FloorsSlabs A_BSUK_Slabs | RL | 10 ,SHE-08.ROOF.dgn,Design Model:105468 | A_BSUK_Roofs | New Construction | A-Roofs::A_BSUK_Roofs
A-FloorsSlabs A_BSUK_Slabs | RL | 10 ,SHE-08.ROOF.dgn,Design Model:105482 | A_BSUK_Roofs | New Construction | A-Roofs::A_BSUK_Roofs
A-FloorsSlabs A_BSUK_Slabs | RL | 10 ,SHE-08.ROOF.dgn,Design Model:105497 | A_BSUK_Roofs | New Construction | A-Roofs::A_BSUK_Roofs
A-FloorsSlabs A_BSUK_Slabs | RL | 10 ,SHE-08.ROOF.dgn,Design Model:105508 | A_BSUK_Roofs | New Construction | A-Roofs::A_BSUK_Roofs
A-FloorsSlabs A_BSUK_Slabs | RL | 10 ,SHE-08.ROOF.dgn,Design Model:105522 | A_BSUK_Roofs | New Construction | A-Roofs::A_BSUK_Roofs
A-FloorsSlabs A_BSUK_Slabs | RL | 10 ,SHE-08.ROOF.dgn,Design Model:105536 | A_BSUK_Roofs | New Construction | A-Roofs::A_BSUK_Roofs
A-FloorsSlabs A_BSUK_Slabs | RL | 10 ,SHE-08.ROOF.dgn,Design Model:105551 | A_BSUK_Roofs | New Construction | A-Roofs::A_BSUK_Roofs
A-FloorsSlabs A_BSUK_Slabs | RL | 10 ,SHE-08.ROOF.dgn,Design Model:105562 | A_BSUK_Roofs | New Construction | A-Roofs::A_BSUK_Roofs
A-FloorsSlabs A_BSUK_Slabs | RL | 10 ,SHE-08.ROOF.dgn,Design Model:105576 | A_BSUK_Roofs | New Construction | A-Roofs::A_BSUK_Roofs
A-FloorsSlabs A_BSUK_Slabs | RL | 10 ,SHE-08.ROOF.dgn,Design Model:105590 | A_BSUK_Roofs | New Construction | A-Roofs::A_BSUK_Roofs
A-FloorsSlabs A_BSUK_Slabs | RL | 10 ,SHE-08.ROOF.dgn,Design Model:105604 | A_BSUK_Roofs | New Construction | A-Roofs::A_BSUK_Roofs
A-FloorsSlabs A_BSUK_Slabs | RL | 10 ,SHE-08.ROOF.dgn,Design Model:105618 | A_BSUK_Roofs | New Construction | A-Roofs::A_BSUK_Roofs
A-FloorsSlabs A_BSUK_Slabs | RL | 10 ,SHE-08.ROOF.dgn,Design Model:105632 | A_BSUK_Roofs | New Construction | A-Roofs::A_BSUK_Roofs
A-FloorsSlabs A_BSUK_Slabs | RL | 10 ,SHE-08.ROOF.dgn,Design Model:105646 | A_BSUK_Roofs | New Construction | A-Roofs::A_BSUK_Roofs
A-FloorsSlabs A_BSUK_Slabs | RL | 10 ,SHE-08.ROOF.dgn,Design Model:105660 | A_BSUK_Roofs | New Construction | A-Roofs::A_BSUK_Roofs
A-FloorsSlabs A_BSUK_Slabs | RL | 10 ,SHE-08.ROOF.dgn,Design Model:105674 | A_BSUK_Roofs | New Construction | A-Roofs::A_BSUK_Roofs
A-FloorsSlabs A_BSUK_Slabs | RL | 10 ,SHE-08.ROOF.dgn,Design Model:105689 | A_BSUK_Roofs | New Construction | A-Roofs::A_BSUK_Roofs
A-FloorsSlabs A_BSUK_Slabs | RL | 10 ,SHE-08.ROOF.dgn,Design Model:105700 | A_BSUK_Roofs | New Construction | A-Roofs::A_BSUK_Roofs
A-FloorsSlabs A_BSUK_Slabs | RL | 10 ,SHE-08.ROOF.dgn,Design Model:105714 | A_BSUK_Roofs | New Construction | A-Roofs::A_BSUK_Roofs
A-FloorsSlabs A_BSUK_Slabs | RL | 10 ,SHE-08.ROOF.dgn,Design Model:105728 | A_BSUK_Roofs | New Construction | A-Roofs::A_BSUK_Roofs
A-FloorsSlabs A_BSUK_Slabs | RL | 10 ,SHE-08.ROOF.dgn,Design Model:105742 | A_BSUK_Roofs | New Construction | A-Roofs::A_BSUK_Roofs
A-FloorsSlabs A_BSUK_Slabs | RL | 10 ,SHE-08.ROOF.dgn,Design Model:105756 | A_BSUK_Roofs | New Construction | A-Roofs::A_BSUK_Roofs
A-FloorsSlabs A_BSUK_Slabs | RL | 10 ,SHE-08.ROOF.dgn,Design Model:105770 | A_BSUK_Roofs | New Construction | A-Roofs::A_BSUK_Roofs
A-FloorsSlabs A_BSUK_Slabs | RL | 10 ,SHE-08.ROOF.dgn,Design Model:105784 | A_BSUK_Roofs | New Construction | A-Roofs::A_BSUK_Roofs
A-FloorsSlabs A_BSUK_Slabs | RL | 10 ,SHE-08.ROOF.dgn,Design Model:105798 | A_BSUK_Roofs | New Construction | A-Roofs::A_BSUK_Roofs
A-FloorsSlabs A_BSUK_Slabs | RL | 10 ,SHE-08.ROOF.dgn,Design Model:105812 | A_BSUK_Roofs | New Construction | A-Roofs::A_BSUK_Roofs
A-FloorsSlabs A_BSUK_Slabs | RL | 10 ,SHE-08.ROOF.dgn,Design Model:105826 | A_BSUK_Roofs | New Construction | A-Roofs::A_BSUK_Roofs
A-FloorsSlabs A_BSUK_Slabs | RL | 10 ,SHE-08.ROOF.dgn,Design Model:105840 | A_BSUK_Roofs | New Construction | A-Roofs::A_BSUK_Roofs
A-FloorsSlabs A_BSUK_Slabs | RL | 10 ,SHE-08.ROOF.dgn,Design Model:105854 | A_BSUK_Roofs | New Construction | A-Roofs::A_BSUK_Roofs
A-FloorsSlabs A_BSUK_Slabs | RL | 10 ,SHE-08.ROOF.dgn,Design Model:105868 | A_BSUK_Roofs | New Construction | A-Roofs::A_BSUK_Roofs
A-FloorsSlabs A_BSUK_Slabs | RL | 10 ,SHE-08.ROOF.dgn,Design Model:105883 | A_BSUK_Roofs | New Construction | A-Roofs::A_BSUK_Roofs
A-FloorsSlabs A_BSUK_Slabs | RL | 10 ,SHE-08.ROOF.dgn,Design Model:105909 | A_BSUK_Roofs | New Construction | A-Roofs::A_BSUK_Roofs
A-FloorsSlabs A_BSUK_Slabs | RL | 10 ,SHE-08.ROOF.dgn,Design Model:105925 | A_BSUK_Roofs | New Construction | A-Roofs::A_BSUK_Roofs
A-FloorsSlabs A_BSUK_Slabs | RL | 10 ,SHE-08.ROOF.dgn,Design Model:105938 | A_BSUK_Roofs | New Construction | A-Roofs::A_BSUK_Roofs
A-FloorsSlabs A_BSUK_Slabs | RL | 10 ,SHE-08.ROOF.dgn,Design Model:105952 | A_BSUK_Roofs | New Construction | A-Roofs::A_BSUK_Roofs
A-FloorsSlabs A_BSUK_Slabs | RL | 10 ,SHE-08.ROOF.dgn,Design Model:105963 | A_BSUK_Roofs | New Construction | A-Roofs::A_BSUK_Roofs
A-FloorsSlabs A_BSUK_Slabs | RL | 10 ,SHE-08.ROOF.dgn,Design Model:105977 | A_BSUK_Roofs | New Construction | A-Roofs::A_BSUK_Roofs
A-FloorsSlabs A_BSUK_Slabs | RL | 10 ,SHE-08.ROOF.dgn,Design Model:105991 | A_BSUK_Roofs | New Construction | A-Roofs::A_BSUK_Roofs
A-FloorsSlabs A_BSUK_Slabs | RL | 10 ,SHE-08.ROOF.dgn,Design Model:106002 | A_BSUK_Roofs | New Construction | A-Roofs::A_BSUK_Roofs
A-FloorsSlabs A_BSUK_Slabs | RL | 10 ,SHE-08.ROOF.dgn,Design Model:106016 | A_BSUK_Roofs | New Construction | A-Roofs::A_BSUK_Roofs
A-FloorsSlabs A_BSUK_Slabs | RL | 10 ,SHE-08.ROOF.dgn,Design Model:106030 | A_BSUK_Roofs | New Construction | A-Roofs::A_BSUK_Roofs
A-FloorsSlabs A_BSUK_Slabs | RL | 10 ,SHE-08.ROOF.dgn,Design Model:106041 | A_BSUK_Roofs | New Construction | A-Roofs::A_BSUK_Roofs
A-FloorsSlabs A_BSUK_Slabs | RL | 10 ,SHE-08.ROOF.dgn,Design Model:106055 | A_BSUK_Roofs | New Construction | A-Roofs::A_BSUK_Roofs
A-FloorsSlabs A_BSUK_Slabs | RL | 10 ,SHE-08.ROOF.dgn,Design Model:106066 | A_BSUK_Roofs | New Construction | A-Roofs::A_BSUK_Roofs
A-FloorsSlabs A_BSUK_Slabs | RL | 10 ,SHE-08.ROOF.dgn,Design Model:106080 | A_BSUK_Roofs | New Construction | A-Roofs::A_BSUK_Roofs
A-FloorsSlabs A_BSUK_Slabs | RL | 10 ,SHE-08.ROOF.dgn,Design Model:106091 | A_BSUK_Roofs | New Construction | A-Roofs::A_BSUK_Roofs
A-FloorsSlabs A_BSUK_Slabs | RL | 10 ,SHE-08.ROOF.dgn,Design Model:106105 | A_BSUK_Roofs | New Construction | A-Roofs::A_BSUK_Roofs
A-FloorsSlabs A_BSUK_Slabs | RL | 10 ,SHE-08.ROOF.dgn,Design Model:106116 | A_BSUK_Roofs | New Construction | A-Roofs::A_BSUK_Roofs
A-FloorsSlabs A_BSUK_Slabs | RL | 10 ,SHE-08.ROOF.dgn,Design Model:106130 | A_BSUK_Roofs | New Construction | A-Roofs::A_BSUK_Roofs
A-FloorsSlabs A_BSUK_Slabs | RL | 10 ,SHE-08.ROOF.dgn,Design Model:106141 | A_BSUK_Roofs | New Construction | A-Roofs::A_BSUK_Roofs
A-FloorsSlabs A_BSUK_Slabs | RL | 10 ,SHE-08.ROOF.dgn,Design Model:106155 | A_BSUK_Roofs | New Construction | A-Roofs::A_BSUK_Roofs
A-FloorsSlabs A_BSUK_Slabs | RL | 10 ,SHE-08.ROOF.dgn,Design Model:106169 | A_BSUK_Roofs | New Construction | A-Roofs::A_BSUK_Roofs
A-FloorsSlabs A_BSUK_Slabs | RL | 10 ,SHE-08.ROOF.dgn,Design Model:106185 | A_BSUK_Roofs | New Construction | A-Roofs::A_BSUK_Roofs
A-FloorsSlabs A_BSUK_Slabs | RL | 10 ,SHE-08.ROOF.dgn,Design Model:106196 | A_BSUK_Roofs | New Construction | A-Roofs::A_BSUK_Roofs
A-FloorsSlabs A_BSUK_Slabs | RL | 10 ,SHE-08.ROOF.dgn,Design Model:106210 | A_BSUK_Roofs | New Construction | A-Roofs::A_BSUK_Roofs
A-FloorsSlabs A_BSUK_Slabs | RL | 10 ,SHE-08.ROOF.dgn,Design Model:106226 | A_BSUK_Roofs | New Construction | A-Roofs::A_BSUK_Roofs
A-FloorsSlabs A_BSUK_Slabs | RL | 10 ,SHE-08.ROOF.dgn,Design Model:106237 | A_BSUK_Roofs | New Construction | A-Roofs::A_BSUK_Roofs
A-FloorsSlabs A_BSUK_Slabs | RL | 10 ,SHE-08.ROOF.dgn,Design Model:106251 | A_BSUK_Roofs | New Construction | A-Roofs::A_BSUK_Roofs
A-FloorsSlabs A_BSUK_Slabs | RL | 10 ,SHE-08.ROOF.dgn,Design Model:106267 | A_BSUK_Roofs | New Construction | A-Roofs::A_BSUK_Roofs
A-FloorsSlabs A_BSUK_Slabs | RL | 10 ,SHE-08.ROOF.dgn,Design Model:106278 | A_BSUK_Roofs | New Construction | A-Roofs::A_BSUK_Roofs
A-FloorsSlabs A_BSUK_Slabs | RL | 10 ,SHE-08.ROOF.dgn,Design Model:106292 | A_BSUK_Roofs | New Construction | A-Roofs::A_BSUK_Roofs
A-FloorsSlabs A_BSUK_Slabs | RL | 10 ,SHE-08.ROOF.dgn,Design Model:106306 | A_BSUK_Roofs | New Construction | A-Roofs::A_BSUK_Roofs
A-FloorsSlabs A_BSUK_Slabs | RL | 10 ,SHE-08.ROOF.dgn,Design Model:106320 | A_BSUK_Roofs | New Construction | A-Roofs::A_BSUK_Roofs
A-FloorsSlabs A_BSUK_Slabs | RL | 10 ,SHE-08.ROOF.dgn,Design Model:106334 | A_BSUK_Roofs | New Construction | A-Roofs::A_BSUK_Roofs
A-FloorsSlabs A_BSUK_Slabs | RL | 10 ,SHE-08.ROOF.dgn,Design Model:106348 | A_BSUK_Roofs | New Construction | A-Roofs::A_BSUK_Roofs
A-FloorsSlabs A_BSUK_Slabs | RL | 10 ,SHE-08.ROOF.dgn,Design Model:106362 | A_BSUK_Roofs | New Construction | A-Roofs::A_BSUK_Roofs
A-FloorsSlabs A_BSUK_Slabs | RL | 10 ,SHE-08.ROOF.dgn,Design Model:106376 | A_BSUK_Roofs | New Construction | A-Roofs::A_BSUK_Roofs
A-FloorsSlabs A_BSUK_Slabs | RL | 10 ,SHE-08.ROOF.dgn,Design Model:106390 | A_BSUK_Roofs | New Construction | A-Roofs::A_BSUK_Roofs
A-FloorsSlabs A_BSUK_Slabs | RL | 10 ,SHE-08.ROOF.dgn,Design Model:106404 | A_BSUK_Roofs | New Construction | A-Roofs::A_BSUK_Roofs
A-FloorsSlabs A_BSUK_Slabs | RL | 10 ,SHE-08.ROOF.dgn,Design Model:106419 | A_BSUK_Roofs | New Construction | A-Roofs::A_BSUK_Roofs
A-FloorsSlabs A_BSUK_Slabs | RL | 10 ,SHE-08.ROOF.dgn,Design Model:106430 | A_BSUK_Roofs | New Construction | A-Roofs::A_BSUK_Roofs
A-FloorsSlabs A_BSUK_Slabs | RL | 10 ,SHE-08.ROOF.dgn,Design Model:106444 | A_BSUK_Roofs | New Construction | A-Roofs::A_BSUK_Roofs
A-FloorsSlabs A_BSUK_Slabs | RL | 10 ,SHE-08.ROOF.dgn,Design Model:106458 | A_BSUK_Roofs | New Construction | A-Roofs::A_BSUK_Roofs
A-FloorsSlabs A_BSUK_Slabs | RL | 10 ,SHE-08.ROOF.dgn,Design Model:106472 | A_BSUK_Roofs | New Construction | A-Roofs::A_BSUK_Roofs
A-FloorsSlabs A_BSUK_Slabs | RL | 10 ,SHE-08.ROOF.dgn,Design Model:106486 | A_BSUK_Roofs | New Construction | A-Roofs::A_BSUK_Roofs
A-FloorsSlabs A_BSUK_Slabs | RL | 10 ,SHE-08.ROOF.dgn,Design Model:106500 | A_BSUK_Roofs | New Construction | A-Roofs::A_BSUK_Roofs
A-FloorsSlabs A_BSUK_Slabs | RL | 10 ,SHE-08.ROOF.dgn,Design Model:106514 | A_BSUK_Roofs | New Construction | A-Roofs::A_BSUK_Roofs
A-FloorsSlabs A_BSUK_Slabs | RL | 10 ,SHE-08.ROOF.dgn,Design Model:106528 | A_BSUK_Roofs | New Construction | A-Roofs::A_BSUK_Roofs
A-FloorsSlabs A_BSUK_Slabs | RL | 10 ,SHE-08.ROOF.dgn,Design Model:106542 | A_BSUK_Roofs | New Construction | A-Roofs::A_BSUK_Roofs
A-FloorsSlabs A_BSUK_Slabs | RL | 10 ,SHE-08.ROOF.dgn,Design Model:106557 | A_BSUK_Roofs | New Construction | A-Roofs::A_BSUK_Roofs
A-FloorsSlabs A_BSUK_Slabs | RL | 10 ,SHE-08.ROOF.dgn,Design Model:106568 | A_BSUK_Roofs | New Construction | A-Roofs::A_BSUK_Roofs
A-FloorsSlabs A_BSUK_Slabs | RL | 10 ,SHE-08.ROOF.dgn,Design Model:106582 | A_BSUK_Roofs | New Construction | A-Roofs::A_BSUK_Roofs
A-FloorsSlabs A_BSUK_Slabs | RL | 10 ,SHE-08.ROOF.dgn,Design Model:106596 | A_BSUK_Roofs | New Construction | A-Roofs::A_BSUK_Roofs
A-FloorsSlabs A_BSUK_Slabs | RL | 10 ,SHE-08.ROOF.dgn,Design Model:106610 | A_BSUK_Roofs | New Construction | A-Roofs::A_BSUK_Roofs
A-FloorsSlabs A_BSUK_Slabs | RL | 10 ,SHE-08.ROOF.dgn,Design Model:106624 | A_BSUK_Roofs | New Construction | A-Roofs::A_BSUK_Roofs
A-FloorsSlabs A_BSUK_Slabs | RL | 10 ,SHE-08.ROOF.dgn,Design Model:106638 | A_BSUK_Roofs | New Construction | A-Roofs::A_BSUK_Roofs
A-FloorsSlabs A_BSUK_Slabs | RL | 10 ,SHE-08.ROOF.dgn,Design Model:106652 | A_BSUK_Roofs | New Construction | A-Roofs::A_BSUK_Roofs
A-FloorsSlabs A_BSUK_Slabs | RL | 10 ,SHE-08.ROOF.dgn,Design Model:106666 | A_BSUK_Roofs | New Construction | A-Roofs::A_BSUK_Roofs
A-FloorsSlabs A_BSUK_Slabs | RL | 10 ,SHE-08.ROOF.dgn,Design Model:106680 | A_BSUK_Roofs | New Construction | A-Roofs::A_BSUK_Roofs
A-FloorsSlabs A_BSUK_Slabs | RL | 10 ,SHE-08.ROOF.dgn,Design Model:106695 | A_BSUK_Roofs | New Construction | A-Roofs::A_BSUK_Roofs
A-FloorsSlabs A_BSUK_Slabs | RL | 10 ,SHE-08.ROOF.dgn,Design Model:106706 | A_BSUK_Roofs | New Construction | A-Roofs::A_BSUK_Roofs
A-FloorsSlabs A_BSUK_Slabs | RL | 10 ,SHE-08.ROOF.dgn,Design Model:106720 | A_BSUK_Roofs | New Construction | A-Roofs::A_BSUK_Roofs
A-FloorsSlabs A_BSUK_Slabs | RL | 10 ,SHE-08.ROOF.dgn,Design Model:106734 | A_BSUK_Roofs | New Construction | A-Roofs::A_BSUK_Roofs
A-FloorsSlabs A_BSUK_Slabs | RL | 10 ,SHE-08.ROOF.dgn,Design Model:106748 | A_BSUK_Roofs | New Construction | A-Roofs::A_BSUK_Roofs
A-FloorsSlabs A_BSUK_Slabs | RL | 10 ,SHE-08.ROOF.dgn,Design Model:106762 | A_BSUK_Roofs | New Construction | A-Roofs::A_BSUK_Roofs
A-FloorsSlabs A_BSUK_Slabs | RL | 10 ,SHE-08.ROOF.dgn,Design Model:106776 | A_BSUK_Roofs | New Construction | A-Roofs::A_BSUK_Roofs
A-FloorsSlabs A_BSUK_Slabs | RL | 10 ,SHE-08.ROOF.dgn,Design Model:106791 | A_BSUK_Roofs | New Construction | A-Roofs::A_BSUK_Roofs
A-FloorsSlabs A_BSUK_Slabs | RL | 10 ,SHE-08.ROOF.dgn,Design Model:106805 | A_BSUK_Roofs | New Construction | A-Roofs::A_BSUK_Roofs
A-FloorsSlabs A_BSUK_Slabs | RL | 10 ,SHE-08.ROOF.dgn,Design Model:106821 | A_BSUK_Roofs | New Construction | A-Roofs::A_BSUK_Roofs
A-FloorsSlabs A_BSUK_Slabs | RL | 10 ,SHE-08.ROOF.dgn,Design Model:106832 | A_BSUK_Roofs | New Construction | A-Roofs::A_BSUK_Roofs
A-FloorsSlabs A_BSUK_Slabs | RL | 10 ,SHE-08.ROOF.dgn,Design Model:106846 | A_BSUK_Roofs | New Construction | A-Roofs::A_BSUK_Roofs
A-FloorsSlabs A_BSUK_Slabs | RL | 10 ,SHE-08.ROOF.dgn,Design Model:106857 | A_BSUK_Roofs | New Construction | A-Roofs::A_BSUK_Roofs
A-FloorsSlabs A_BSUK_Slabs | RL | 10 ,SHE-08.ROOF.dgn,Design Model:106871 | A_BSUK_Roofs | New Construction | A-Roofs::A_BSUK_Roofs
A-FloorsSlabs A_BSUK_Slabs | RL | 10 ,SHE-08.ROOF.dgn,Design Model:106885 | A_BSUK_Roofs | New Construction | A-Roofs::A_BSUK_Roofs
A-FloorsSlabs A_BSUK_Slabs | RL | 10 ,SHE-08.ROOF.dgn,Design Model:106896 | A_BSUK_Roofs | New Construction | A-Roofs::A_BSUK_Roofs
A-FloorsSlabs A_BSUK_Slabs | RL | 10 ,SHE-08.ROOF.dgn,Design Model:106910 | A_BSUK_Roofs | New Construction | A-Roofs::A_BSUK_Roofs
A-FloorsSlabs A_BSUK_Slabs | RL | 10 ,SHE-08.ROOF.dgn,Design Model:106924 | A_BSUK_Roofs | New Construction | A-Roofs::A_BSUK_Roofs
A-FloorsSlabs A_BSUK_Slabs | RL | 10 ,SHE-08.ROOF.dgn,Design Model:106935 | A_BSUK_Roofs | New Construction | A-Roofs::A_BSUK_Roofs
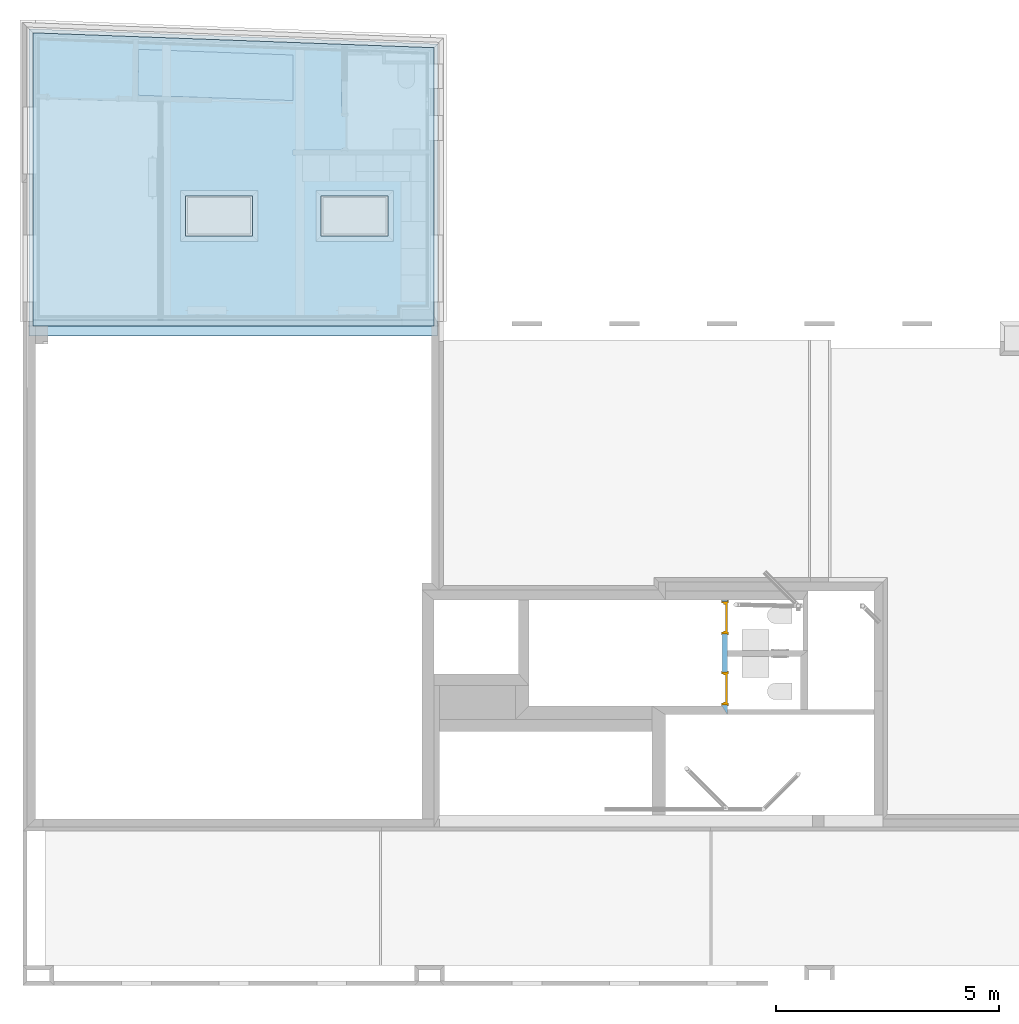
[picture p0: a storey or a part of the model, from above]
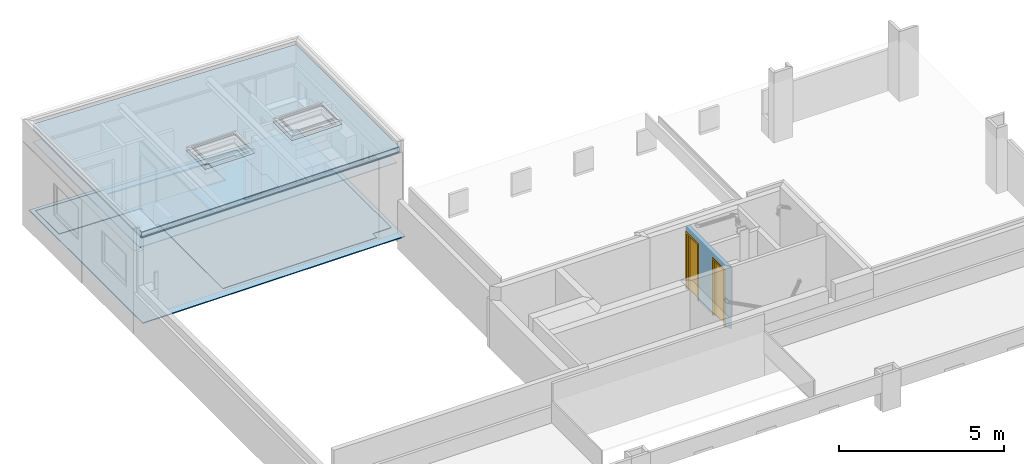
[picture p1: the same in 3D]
Properties of the parts of a building model (IFC2X3), part 13 of 16

# IfcWall: A-Walls:A_BSUK_WallInternal_Finishes_Plasterboard (10)
Name | Description
A-Walls--A_BSUK_WallInternal_Finishes_Plasterboard | 8,SHE-07.FIFTH.dgn ,Design Model:172565
A-Walls--A_BSUK_WallInternal_Finishes_Plasterboard | 8,SHE-07.FIFTH.dgn ,Design Model:172577
A-Walls--A_BSUK_WallInternal_Finishes_Plasterboard | 8,SHE-07.FIFTH.dgn ,Design Model:172589
A-Walls--A_BSUK_WallInternal_Finishes_Plasterboard | 8,SHE-07.FIFTH.dgn ,Design Model:172601
A-Walls--A_BSUK_WallInternal_Finishes_Plasterboard | 8,SHE-07.FIFTH.dgn ,Design Model:213326
A-Walls--A_BSUK_WallInternal_Finishes_Plasterboard | 8,SHE-07.FIFTH.dgn ,Design Model:213533
A-Walls--A_BSUK_WallInternal_Finishes_Plasterboard | 8,SHE-07.FIFTH.dgn ,Design Model:89663
A-Walls--A_BSUK_WallInternal_Finishes_Plasterboard | 8,SHE-07.FIFTH.dgn ,Design Model:172673
A-Walls--A_BSUK_WallInternal_Finishes_Plasterboard | 8,SHE-07.FIFTH.dgn ,Design Model:172685
A-Walls--A_BSUK_WallInternal_Finishes_Plasterboard | 8,SHE-07.FIFTH.dgn ,Design Model:172697

# IfcWall: A-Walls:A_BSUK_WallsExternal (10)
In: 5F
Material: A_BSUK_WallsExternal
Name | Description
A-Walls--A_BSUK_WallsExternal | 8 ,SHE-07.FIFTH.dgn,Design Model:89675
A-Walls--A_BSUK_WallsExternal | 8 ,SHE-07.FIFTH.dgn,Design Model:89691
A-Walls--A_BSUK_WallsExternal | 8 ,SHE-07.FIFTH.dgn,Design Model:89703
A-Walls--A_BSUK_WallsExternal | 8 ,SHE-07.FIFTH.dgn,Design Model:89715
A-Walls--A_BSUK_WallsExternal | 8 ,SHE-07.FIFTH.dgn,Design Model:89727
A-Walls--A_BSUK_WallsExternal | 8 ,SHE-07.FIFTH.dgn,Design Model:89743
A-Walls--A_BSUK_WallsExternal | 8 ,SHE-07.FIFTH.dgn,Design Model:89755
A-Walls--A_BSUK_WallsExternal | 8 ,SHE-07.FIFTH.dgn,Design Model:89771
A-Walls--A_BSUK_WallsExternal | 8 ,SHE-07.FIFTH.dgn,Design Model:89783
A-Walls--A_BSUK_WallsExternal | 8 ,SHE-07.FIFTH.dgn,Design Model:89799

# IfcWall: A-Walls:A_BSUK_WallsExternal_Block (2)
In: 5F
Material: A_BSUK_WallsExternal_Block
Name | Description
A-Walls--A_BSUK_WallsExternal_Block | 8,SHE-07.FIFTH.dgn,Design Model:89811
A-Walls--A_BSUK_WallsExternal_Block | 8,SHE-07.FIFTH.dgn,Design Model:89824

# IfcWall: A-Walls:A_BSUK_Walls_Timber (2)
In: 5F
Material: A_BSUK_Walls_Timber
Name | Description
A-Walls--A_BSUK_Walls_Timber | 8 ,SHE-07.FIFTH.dgn,Design Model:213290
A-Walls--A_BSUK_Walls_Timber | 8 ,SHE-07.FIFTH.dgn,Design Model:213497

# IfcWall: SHE_A-Walls_Type01a_Partywall_250mm_twin (3)
In: GF
Type - Description: SHE_A-Walls_Type01a_Partywall_250mm_twin
Type - Wall Parameters - Type: Wall; Compound Wall Assembly: yes
Type - Thermal Transmittance - Is External: no; Is Below Grade: no
Type - Space Bounding - Is Space Bounding: yes
Type - Materials - Part Definition: A-CompoundWalls::SHE_A-Walls_Type01a_Partywall_250mm_twin
Type - LEED Parameters - LEED | Pre-consumer Recycled (%): 0; LEED | Regional Material: no; LEED | Post-consumer Recycled (%): 0
Type - Identification - ID | Type ID: A216013 (EN); ID | Description: SHE_A-Walls_Type01a_Partywall_250mm_twin; ID | Notes: https://www.british-gypsu m.com/Specification/White-Book-Specification-Selector/internal-partitions-walls/gypwall-twin-frame-independent/a216013-en
Type - Fire Resistance - Fire | Rating: F90 (min. F60); Fire | IsCombustible: no; Fire | Compartmentation: no
Type - Discipline - Discipline: Architectural
Type - Construction Phase - Phase: New Construction
Type - Classification - Uniclass2015: EF_25_10
Type - Acoustical Parameters - Acoustic Rating (STC): 62 (min. 60)
Pset_WallCommon - AcousticRating: 62 (req. 60); Combustible: no; Compartmentation: no; FireRating: F90 (min. F60); IsExternal: no; LoadBearing: no
Identification - ID | Number: 1A; ID | Description: PartyWall; ID | Keynote: https://www.british-gyp sum.com/Specification/White-Book-Specification-Selector/internal-partitions-walls/gypwall-twin-frame-independent/a216013-en; ID | Notes: SHE_A-Walls_Type01a_Partywall_250mm_twin
Acoustical Parameters - Acoustic Rating (STC): 62 (req. 60)
Name | Description
1A | A216013 (EN) - PartyWall :1 ,SHE-01.GROUND.dgn,Design Model:150201
1A | A216013 (EN) - PartyWall :1 ,SHE-01.GROUND.dgn,Design Model:150265
1A | A216013 (EN) - PartyWall :1 ,SHE-01.GROUND.dgn,Design Model:160929

# IfcWall: SHE_A-Walls_Type01c_Partywall_225mm_twin_tall (48)
Type - Description: SHE_A-Walls_Type01c_Partywall_225mm_twin_tall
Type - Wall Parameters - Type: Wall; Compound Wall Assembly: yes
Type - Thermal Transmittance - Is External: no; Is Below Grade: no
Type - Space Bounding - Is Space Bounding: yes
Type - Materials - Part Definition: A-CompoundWalls::SHE_A-Walls_Type01c_Partywall_225mm_twin_tall
Type - LEED Parameters - LEED | Pre-consumer Recycled (%): 0; LEED | Regional Material: no; LEED | Post-consumer Recycled (%): 0
Type - Identification - ID | Type ID: L216017F (EN); ID | Description: SHE_A-Walls_Type01c_Partywall_225mm_twin_tall; ID | Notes: https://www.british-gypsu m.com/Specification/White-Book-Specification-Selector/internal-partitions-walls/gypwall-twin-frame-independent/L216017F-en
Type - Fire Resistance - Fire | Rating: F90 (min. F60); Fire | IsCombustible: no; Fire | Compartmentation: no
Type - Discipline - Discipline: Architectural
Type - Construction Phase - Phase: New Construction
Type - Classification - Uniclass2015: EF_25_10
Type - Acoustical Parameters - Acoustic Rating (STC): 57 (min. 53)
Pset_WallCommon - AcousticRating: 57 (req. 53); Combustible: no; Compartmentation: no; FireRating: F90 (min. F60); IsExternal: no; LoadBearing: no
Identification - ID | Number: 1C; ID | Description: PartyWall; ID | Keynote: https://www.british-gyp sum.com/Specification/White-Book-Specification-Selector/internal-partitions-walls/gypwall-twin-frame-independent/L216017F-en; ID | Notes: SHE_A-Walls_Type01c_Partywall_225mm_twin_tall
Acoustical Parameters - Acoustic Rating (STC): 57 (req. 53)
Name | In | Description
1C | 1F | L216017F (EN) - PartyWall :4 ,SHE-03.FIRST.dgn,Design Model:141623
1C | 1F | L216017F (EN) - PartyWall :4 ,SHE-03.FIRST.dgn,Design Model:142251
1C | 1F | L216017F (EN) - PartyWall :4 ,SHE-03.FIRST.dgn,Design Model:142252
1C | 1F | L216017F (EN) - PartyWall :4 ,SHE-03.FIRST.dgn,Design Model:142267
1C | 1F | L216017F (EN) - PartyWall :4 ,SHE-03.FIRST.dgn,Design Model:142269
1C | 1F | L216017F (EN) - PartyWall :4 ,SHE-03.FIRST.dgn,Design Model:142540
1C | 1F | L216017F (EN) - PartyWall :4 ,SHE-03.FIRST.dgn,Design Model:142541
1C | 1F | L216017F (EN) - PartyWall :4 ,SHE-03.FIRST.dgn,Design Model:142543
1C | 1F | L216017F (EN) - PartyWall :4 ,SHE-03.FIRST.dgn,Design Model:143075
1C | 1F | L216017F (EN) - PartyWall :4 ,SHE-03.FIRST.dgn,Design Model:143191
1C | 1F | L216017F (EN) - PartyWall :4 ,SHE-03.FIRST.dgn,Design Model:147003
1C | 1F | L216017F (EN) - PartyWall :4 ,SHE-03.FIRST.dgn,Design Model:147004
1C | 1F | L216017F (EN) - PartyWall :4 ,SHE-03.FIRST.dgn,Design Model:170354
1C | 1F | L216017F (EN) - PartyWall :4 ,SHE-03.FIRST.dgn,Design Model:258646
1C | 1F | L216017F (EN) - PartyWall :4 ,SHE-03.FIRST.dgn,Design Model:261780
1C | 1F | L216017F (EN) - PartyWall :4 ,SHE-03.FIRST.dgn,Design Model:376414
1C | 3F | L216017F (EN) - PartyWall :6 ,SHE-05.THIRD.dgn,Design Model:141623
1C | 3F | L216017F (EN) - PartyWall :6 ,SHE-05.THIRD.dgn,Design Model:142251
1C | 3F | L216017F (EN) - PartyWall :6 ,SHE-05.THIRD.dgn,Design Model:142252
1C | 3F | L216017F (EN) - PartyWall :6 ,SHE-05.THIRD.dgn,Design Model:142267
1C | 3F | L216017F (EN) - PartyWall :6 ,SHE-05.THIRD.dgn,Design Model:142269
1C | 3F | L216017F (EN) - PartyWall :6 ,SHE-05.THIRD.dgn,Design Model:142540
1C | 3F | L216017F (EN) - PartyWall :6 ,SHE-05.THIRD.dgn,Design Model:142541
1C | 3F | L216017F (EN) - PartyWall :6 ,SHE-05.THIRD.dgn,Design Model:142543
1C | 3F | L216017F (EN) - PartyWall :6 ,SHE-05.THIRD.dgn,Design Model:143075
1C | 3F | L216017F (EN) - PartyWall :6 ,SHE-05.THIRD.dgn,Design Model:143191
1C | 3F | L216017F (EN) - PartyWall :6 ,SHE-05.THIRD.dgn,Design Model:143374
1C | 3F | L216017F (EN) - PartyWall :6 ,SHE-05.THIRD.dgn,Design Model:147003
1C | 3F | L216017F (EN) - PartyWall :6 ,SHE-05.THIRD.dgn,Design Model:147004
1C | 3F | L216017F (EN) - PartyWall :6 ,SHE-05.THIRD.dgn,Design Model:170354
1C | 3F | L216017F (EN) - PartyWall :6 ,SHE-05.THIRD.dgn,Design Model:258646
1C | 3F | L216017F (EN) - PartyWall :6 ,SHE-05.THIRD.dgn,Design Model:261780
1C | 2F | L216017F (EN ) - PartyWall :18,SHE-04.SECOND.dgn,Design Model:141623
1C | 2F | L216017F (EN ) - PartyWall :18,SHE-04.SECOND.dgn,Design Model:142251
1C | 2F | L216017F (EN ) - PartyWall :18,SHE-04.SECOND.dgn,Design Model:142252
1C | 2F | L216017F (EN ) - PartyWall :18,SHE-04.SECOND.dgn,Design Model:142267
1C | 2F | L216017F (EN ) - PartyWall :18,SHE-04.SECOND.dgn,Design Model:142269
1C | 2F | L216017F (EN ) - PartyWall :18,SHE-04.SECOND.dgn,Design Model:142540
1C | 2F | L216017F (EN ) - PartyWall :18,SHE-04.SECOND.dgn,Design Model:142541
1C | 2F | L216017F (EN ) - PartyWall :18,SHE-04.SECOND.dgn,Design Model:142543
1C | 2F | L216017F (EN ) - PartyWall :18,SHE-04.SECOND.dgn,Design Model:143191
1C | 2F | L216017F (EN ) - PartyWall :18,SHE-04.SECOND.dgn,Design Model:143374
1C | 2F | L216017F (EN ) - PartyWall :18,SHE-04.SECOND.dgn,Design Model:147003
1C | 2F | L216017F (EN ) - PartyWall :18,SHE-04.SECOND.dgn,Design Model:147004
1C | 2F | L216017F (EN ) - PartyWall :18,SHE-04.SECOND.dgn,Design Model:170354
1C | 2F | L216017F (EN ) - PartyWall :18,SHE-04.SECOND.dgn,Design Model:258646
1C | 2F | L216017F (EN ) - PartyWall :18,SHE-04.SECOND.dgn,Design Model:261780
1C | 2F | L216017F (EN ) - PartyWall :18,SHE-04.SECOND.dgn,Design Model:378082

# IfcWall: SHE_A-Walls_Type01d_Partywall_200mm_twin (23)
Type - Description: SHE_A-Walls_Type01d_Partywall_200mm_twin
Type - Wall Parameters - Type: Wall; Compound Wall Assembly: yes
Type - Thermal Transmittance - Is External: no; Is Below Grade: no
Type - Space Bounding - Is Space Bounding: yes
Type - Materials - Part Definition: A-CompoundWalls::SHE_A-Walls_Type01d_Partywall_200mm_twin
Type - LEED Parameters - LEED | Pre-consumer Recycled (%): 0; LEED | Regional Material: no; LEED | Post-consumer Recycled (%): 0
Type - Identification - ID | Type ID: A216014 (EN); ID | Description: SHE_A-Walls_Type01d_Partywall_200mm_twin; ID | Notes: https://www.british-gypsu m.com/Specification/White-Book-Specification-Selector/internal-partitions-walls/gypwall-twin-frame-independent/a216014-en
Type - Fire Resistance - Fire | Rating: F90 (min. F60); Fire | IsCombustible: no; Fire | Compartmentation: no
Type - Discipline - Discipline: Architectural
Type - Construction Phase - Phase: New Construction
Type - Classification - Uniclass2015: EF_25_10
Type - Acoustical Parameters - Acoustic Rating (STC): 58 (min. 55)
Pset_WallCommon - AcousticRating: 58 (req. 55); Combustible: no; Compartmentation: no; FireRating: F90 (min. F60); IsExternal: no; LoadBearing: no
Identification - ID | Number: 1D; ID | Description: PartyWall; ID | Keynote: https://www.british-gyp sum.com/Specification/White-Book-Specification-Selector/internal-partitions-walls/gypwall-twin-frame-independent/a216014-en; ID | Notes: SHE_A-Walls_Type01d_Partywall_200mm_twin
Acoustical Parameters - Acoustic Rating (STC): 58 (req. 55)
Name | In | Description
1D | 1F | A216014 (EN) - PartyWall :7 ,SHE-06.FOURTH.dgn,Design Model:200870
1D | 1F | A216014 (EN) - PartyWall :7 ,SHE-06.FOURTH.dgn,Design Model:201195
1D | 1F | A216014 (EN) - PartyWall :7 ,SHE-06.FOURTH.dgn,Design Model:213592
1D | 1F | A216014 (EN) - PartyWall :7 ,SHE-06.FOURTH.dgn,Design Model:213656
1D | 1F | A216014 (EN) - PartyWall :7 ,SHE-06.FOURTH.dgn,Design Model:213720
1D | 1F | A216014 (EN) - PartyWall :7 ,SHE-06.FOURTH.dgn,Design Model:228670
1D | 1F | A216014 (EN) - PartyWall :7 ,SHE-06.FOURTH.dgn,Design Model:238168
1D | 1F | A216014 (EN) - PartyWall :7 ,SHE-06.FOURTH.dgn,Design Model:258699
1D | 1F | A216014 (EN) - PartyWall :7 ,SHE-06.FOURTH.dgn,Design Model:329798
1D | 1F | A216014 (EN) - PartyWall :7 ,SHE-06.FOURTH.dgn,Design Model:329967
1D | 1F | A216014 (EN) - PartyWall :7 ,SHE-06.FOURTH.dgn,Design Model:330218
1D | 1F | A216014 (EN) - PartyWall :7 ,SHE-06.FOURTH.dgn,Design Model:450240
1D | 1F | A216014 (EN) - PartyWall :7 ,SHE-06.FOURTH.dgn,Design Model:453325
1D | 1F | A216014 (EN) - PartyWall :7 ,SHE-06.FOURTH.dgn,Design Model:454108
1D | 1F | A216014 (EN) - PartyWall :7 ,SHE-06.FOURTH.dgn,Design Model:455433
1D | 1F | A216014 (EN) - PartyWall :7 ,SHE-06.FOURTH.dgn,Design Model:483168
1D | 5F | A216014 (EN) - PartyWall :8 ,SHE-07.FIFTH.dgn,Design Model:170079
1D | 5F | A216014 (EN) - PartyWall :8 ,SHE-07.FIFTH.dgn,Design Model:301138
1D | 5F | A216014 (EN) - PartyWall :8 ,SHE-07.FIFTH.dgn,Design Model:304604
1D | 5F | A216014 (EN) - PartyWall :8 ,SHE-07.FIFTH.dgn,Design Model:304668
1D | 5F | A216014 (EN) - PartyWall :8 ,SHE-07.FIFTH.dgn,Design Model:305057
1D | 5F | A216014 (EN) - PartyWall :8 ,SHE-07.FIFTH.dgn,Design Model:305831
1D | 5F | A216014 (EN) - PartyWall :8 ,SHE-07.FIFTH.dgn,Design Model:306404

# IfcWall: SHE_A-Walls_Type02b_LiftShaftWall_173mm, 2B
In: 1F
Type - Description: SHE_A-Walls_Type02b_LiftShaftWall_173mm
Type - Wall Parameters - Type: Wall; Compound Wall Assembly: yes
Type - Thermal Transmittance - Is External: no; Is Below Grade: no
Type - Space Bounding - Is Space Bounding: yes
Type - Materials - Part Definition: A-CompoundWalls::SHE_A-Walls_Type02b_LiftShaftWall_173mm
Type - LEED Parameters - LEED | Pre-consumer Recycled (%): 0; LEED | Regional Material: no; LEED | Post-consumer Recycled (%): 0
Type - Identification - ID | Type ID: A306020 (A) (EN); ID | Description: SHE_A-Walls_Type02b_LiftShaftWall_173mm; ID | Notes: https://www.british-gypsu m.com/Specification/White-Book-Specification-Selector/shaftwall/gypwall-shaft/a306020-a-en #0description
Type - Fire Resistance - Fire | Rating: F60; Fire | IsCombustible: no; Fire | Compartmentation: no
Type - Discipline - Discipline: Architectural
Type - Construction Phase - Phase: New Construction
Type - Classification - Uniclass2015: EF_25_10
Type - Acoustical Parameters - Acoustic Rating (STC): 52 (min. 52)
Description: A306020 (A) (EN ) - LiftShaftWall :7,SHE-06.FOURTH.dgn,Design Model:473824
Pset_WallCommon - AcousticRating: 52 (min. 52); Combustible: no; Compartmentation: no; FireRating: F60; IsExternal: no; LoadBearing: no
Identification - ID | Number: 2B; ID | Description: LiftShaftWall; ID | Keynote: https://www.british-gyp sum.com/Specification/White-Book-Specification-Selector/shaftwall/gypwall-shaft/a306020-a-en #0description; ID | Notes: SHE_A-Walls_Type02b_LiftShaftWall_173mm

# IfcWall: SHE_A-Walls_Type02c_LiftShaftWall_193mm (4)
In: 5F
Type - Description: SHE_A-Walls_Type02c_LiftShaftWall_193mm
Type - Wall Parameters - Type: Wall; Compound Wall Assembly: yes
Type - Thermal Transmittance - Is External: no; Is Below Grade: no
Type - Space Bounding - Is Space Bounding: yes
Type - Materials - Part Definition: A-CompoundWalls::SHE_A-Walls_Type02c_LiftShaftWall_193mm
Type - LEED Parameters - LEED | Pre-consumer Recycled (%): 0; LEED | Regional Material: no; LEED | Post-consumer Recycled (%): 0
Type - Identification - ID | Type ID: A306033 (A) (EN); ID | Description: SHE_A-Walls_Type02c_LiftShaftWall_193mm; ID | Notes: https://www.british-gypsu m.com/Specification/White-Book-Specification-Selector/shaftwall/gypwall-shaft/a306033-a-en
Type - Fire Resistance - Fire | Rating: FD120; Fire | IsCombustible: no; Fire | Compartmentation: no
Type - Discipline - Discipline: Architectural
Type - Construction Phase - Phase: New Construction
Type - Classification - Uniclass2015: EF_25_10
Type - Acoustical Parameters - Acoustic Rating (STC): 50 (min. 52)
Pset_WallCommon - AcousticRating: 50 (min. 52); Combustible: no; Compartmentation: no; FireRating: F120; IsExternal: no; LoadBearing: no
Identification - ID | Number: 2C; ID | Description: LiftShaftWall; ID | Keynote: https://www.british-gyp sum.com/Specification/White-Book-Specification-Selector/shaftwall/gypwall-shaft/a306020-a-en #0description; ID | Notes: SHE_A-Walls_Type02c_LiftShaftWall_193mm
Fire Resistance - Fire | Rating: F120
Name | Description
2C | A306033 (A) (EN ) - LiftShaftWall :8,SHE-07.FIFTH.dgn,Design Model:312602
2C | A306033 (A) (EN ) - LiftShaftWall :8,SHE-07.FIFTH.dgn,Design Model:312684
2C | A306033 (A) (EN ) - LiftShaftWall :8,SHE-07.FIFTH.dgn,Design Model:312739
2C | A306033 (A) (EN ) - LiftShaftWall :8,SHE-07.FIFTH.dgn,Design Model:313312

# IfcWall: SHE_A-Walls_Type03a_BlockworkWall_170mm (18)
Type - Description: SHE_A-Walls_Type03a_BlockworkWall_170mm
Type - Wall Parameters - Type: Wall; Compound Wall Assembly: yes
Type - Thermal Transmittance - Is External: no; Is Below Grade: no
Type - Space Bounding - Is Space Bounding: yes
Type - Materials - Part Definition: A-CompoundWalls::SHE_A-Walls_Type03a_BlockworkWall_170mm
Type - LEED Parameters - LEED | Pre-consumer Recycled (%): 0; LEED | Regional Material: no; LEED | Post-consumer Recycled (%): 0
Type - Identification - ID | Description: SHE_A-Walls_Type03a_BlockworkWall_170mm
Type - Fire Resistance - Fire | IsCombustible: no; Fire | Compartmentation: no
Type - Discipline - Discipline: Architectural
Type - Construction Phase - Phase: Existing to Remain
Type - Classification - Uniclass2015: EF_25_10
Type - Acoustical Parameters - Acoustic Rating (STC): (min.53)
Pset_WallCommon - Combustible: no; Compartmentation: no; FireRating: F120; IsExternal: no; LoadBearing: no
Identification - ID | Number: 4B; ID | Description: CoreWall existing; ID | Notes: SHE_A-Walls_Type03a_BlockworkWall_170mm
Fire Resistance - Fire | Rating: F120
Name | In | Description | AcousticRating = Acoustic Rating (STC)
4B | 1F | CoreWall existing :4 ,SHE-03.FIRST.dgn,Design Model:139322 | (req.53)
4B | 1F | CoreWall existing :4 ,SHE-03.FIRST.dgn,Design Model:139746 | (req.53)
4B | 1F | CoreWall existing :4 ,SHE-03.FIRST.dgn,Design Model:143193 | (req.53)
4B | 1F | CoreWall existing :4 ,SHE-03.FIRST.dgn,Design Model:230556 | (req.53)
4B | 1F | CoreWall existing :4 ,SHE-03.FIRST.dgn,Design Model:303433 | (req.53)
4B | 3F | CoreWall existing :6 ,SHE-05.THIRD.dgn,Design Model:139322 | (req.53)
4B | 3F | CoreWall existing :6 ,SHE-05.THIRD.dgn,Design Model:139746 | (req.53)
4B | 3F | CoreWall existing :6 ,SHE-05.THIRD.dgn,Design Model:143193 | (req.53)
4B | 3F | CoreWall existing :6 ,SHE-05.THIRD.dgn,Design Model:230556 | (req.53)
4B | 3F | CoreWall existing :6 ,SHE-05.THIRD.dgn,Design Model:303433 | (req.53)
4B | 1F | CoreWall existing :7 ,SHE-06.FOURTH.dgn,Design Model:191045 | (req.55)
4B | 1F | CoreWall existing :7 ,SHE-06.FOURTH.dgn,Design Model:191469 | (req.55)
4B | 1F | CoreWall existing :7 ,SHE-06.FOURTH.dgn,Design Model:483583 | (min.55)
4B | 2F | CoreWall existing :18 ,SHE-04.SECOND.dgn,Design Model:139322 | (req.53)
4B | 2F | CoreWall existing :18 ,SHE-04.SECOND.dgn,Design Model:139746 | (req.53)
4B | 2F | CoreWall existing :18 ,SHE-04.SECOND.dgn,Design Model:143193 | (req.53)
4B | 2F | CoreWall existing :18 ,SHE-04.SECOND.dgn,Design Model:230556 | (req.53)
4B | 2F | CoreWall existing :18 ,SHE-04.SECOND.dgn,Design Model:303433 | (req.53)

# IfcWall: SHE_A-Walls_Type03b_Firewall_200mm_twin (4)
Type - Description: SHE_A-Walls_Type03b_Firewall_200mm_twin
Type - Wall Parameters - Type: Wall; Compound Wall Assembly: yes
Type - Thermal Transmittance - Is External: no; Is Below Grade: no
Type - Space Bounding - Is Space Bounding: yes
Type - Materials - Part Definition: A-CompoundWalls::SHE_A-Walls_Type03b_Firewall_200mm_twin
Type - LEED Parameters - LEED | Pre-consumer Recycled (%): 0; LEED | Regional Material: no; LEED | Post-consumer Recycled (%): 0
Type - Identification - ID | Type ID: X216011 (EN); ID | Description: SHE_A-Walls_Type03b_Firewall_200mm_twin; ID | Notes: https://www.british-gypsu m.com/Specification/White-Book-Specification-Selector/internal-partitions-walls/gypwall-twin-frame-independent/x216011-en
Type - Fire Resistance - Fire | Rating: F120; Fire | IsCombustible: no; Fire | Compartmentation: no
Type - Discipline - Discipline: Architectural
Type - Construction Phase - Phase: New Construction
Type - Classification - Uniclass2015: EF_25_10
Type - Acoustical Parameters - Acoustic Rating (STC): 58 dB (min. 55 Rw+Ctr)
Pset_WallCommon - AcousticRating: 58dB (req. 55); Combustible: no; Compartmentation: no; FireRating: F120; IsExternal: no; LoadBearing: no
Identification - ID | Number: 3B; ID | Description: StairFireWall; ID | Notes: SHE_A-Walls_Type03b_Firewall_200mm_twin
Acoustical Parameters - Acoustic Rating (STC): 58dB (req. 55 )
Name | In | Description | ID | Keynote
3B | 1F | X216011 (EN ) - StairFireWall :7,SHE-06.FOURTH.dgn,Design Model:453738 | https://www.british-gyp sum.com/Specification/White-Book-Specification-Selector/internal-partitions-walls/gypwall-twin-frame-independent/x216011-en
3B | 5F | X216011 (EN ) - StairFireWall :8,SHE-07.FIFTH.dgn,Design Model:304928 | https://www.british-gyp sum.com/Specification/White-Book-Specification-Selector/internal-partitions-walls/gypwall-twin-frame-independent/a216014-en
3B | 5F | X216011 (EN ) - StairFireWall :8,SHE-07.FIFTH.dgn,Design Model:310293 | https://www.british-gyp sum.com/Specification/White-Book-Specification-Selector/internal-partitions-walls/gypwall-twin-frame-independent/a216014-en
3B | 5F | X216011 (EN ) - StairFireWall :8,SHE-07.FIFTH.dgn,Design Model:311878 | https://www.british-gyp sum.com/Specification/White-Book-Specification-Selector/internal-partitions-walls/gypwall-twin-frame-independent/a216014-en

# IfcWall: SHE_A-Walls_Type04a_BlockworkWall_130mm (6)
Type - Description: SHE_A-Walls_Type04a_BlockworkWall_130mm
Type - Wall Parameters - Type: Wall; Compound Wall Assembly: yes
Type - Thermal Transmittance - Is External: no; Is Below Grade: no
Type - Space Bounding - Is Space Bounding: yes
Type - Materials - Part Definition: A-CompoundWalls::SHE_A-Walls_Type04a_BlockworkWall_130mm
Type - LEED Parameters - LEED | Pre-consumer Recycled (%): 0; LEED | Regional Material: no; LEED | Post-consumer Recycled (%): 0
Type - Identification - ID | Description: SHE_A-Walls_Type04a_BlockworkWall_130mm
Type - Fire Resistance - Fire | IsCombustible: no; Fire | Compartmentation: no
Type - Discipline - Discipline: Architectural
Type - Construction Phase - Phase: Existing to Remain
Type - Classification - Uniclass2015: EF_25_10
Type - Acoustical Parameters - Acoustic Rating (STC): (min.53)
Pset_WallCommon - AcousticRating: (req.53); Combustible: no; Compartmentation: no; FireRating: F120; IsExternal: no; LoadBearing: no
Identification - ID | Number: 4A; ID | Description: CoreWall existing; ID | Notes: SHE_A-Walls_Type04a_BlockworkWall_130mm
Fire Resistance - Fire | Rating: F120
Acoustical Parameters - Acoustic Rating (STC): (req.53)
Name | In | Description
4A | 1F | CoreWall existing :4 ,SHE-03.FIRST.dgn,Design Model:139323
4A | 1F | CoreWall existing :4 ,SHE-03.FIRST.dgn,Design Model:143192
4A | 3F | CoreWall existing :6 ,SHE-05.THIRD.dgn,Design Model:139323
4A | 3F | CoreWall existing :6 ,SHE-05.THIRD.dgn,Design Model:143192
4A | 2F | CoreWall existing :18 ,SHE-04.SECOND.dgn,Design Model:139323
4A | 2F | CoreWall existing :18 ,SHE-04.SECOND.dgn,Design Model:143192

# IfcWall: SHE_A-Walls_Type05a_Partition_95mm_tall (132)
Type - Description: SHE_A-Walls_Type05a_Partition_95mm_tall
Type - Wall Parameters - Type: Wall; Compound Wall Assembly: yes
Type - Thermal Transmittance - Is External: no; Is Below Grade: no
Type - Space Bounding - Is Space Bounding: yes
Type - Materials - Part Definition: A-CompoundWalls::SHE_A-Walls_Type05a_Partition_95mm_tall
Type - LEED Parameters - LEED | Pre-consumer Recycled (%): 0; LEED | Regional Material: no; LEED | Post-consumer Recycled (%): 0
Type - Identification - ID | Type ID: A206045 (EN); ID | Description: SHE_A-Walls_Type05a_Partition_95mm_tall; ID | Notes: https://www.british-gypsu m.com/Specification/White-Book-Specification-Selector/internal-partitions-walls/gypwall-single-frame/A206045-en
Type - Fire Resistance - Fire | Rating: F30; Fire | IsCombustible: no; Fire | Compartmentation: no
Type - Discipline - Discipline: Architectural
Type - Classification - Uniclass2015: EF_25_10
Type - Acoustical Parameters - Acoustic Rating (STC): 42 (min. 40)
Pset_WallCommon - AcousticRating: 42 (req. 40); Combustible: no; Compartmentation: no; FireRating: F30; IsExternal: no; LoadBearing: no
Identification - ID | Number: 5A; ID | Description: Partition; ID | Keynote: https://www.british-gyp sum.com/Specification/White-Book-Specification-Selector/internal-partitions-walls/gypwall-single-frame/A206045-en; ID | Notes: SHE_A-Walls_Type05a_Partition_95mm_tall
Construction Phase - Phase: New Construction
Acoustical Parameters - Acoustic Rating (STC): 42 (req. 40)
Name | In | Description
5A | 1F | A206045 (EN) - Partition :4 ,SHE-03.FIRST.dgn,Design Model:142264
5A | 1F | A206045 (EN) - Partition :4 ,SHE-03.FIRST.dgn,Design Model:142271
5A | 1F | A206045 (EN) - Partition :4 ,SHE-03.FIRST.dgn,Design Model:142272
5A | 1F | A206045 (EN) - Partition :4 ,SHE-03.FIRST.dgn,Design Model:142274
5A | 1F | A206045 (EN) - Partition :4 ,SHE-03.FIRST.dgn,Design Model:142275
5A | 1F | A206045 (EN) - Partition :4 ,SHE-03.FIRST.dgn,Design Model:142806
5A | 1F | A206045 (EN) - Partition :4 ,SHE-03.FIRST.dgn,Design Model:142807
5A | 1F | A206045 (EN) - Partition :4 ,SHE-03.FIRST.dgn,Design Model:142813
5A | 1F | A206045 (EN) - Partition :4 ,SHE-03.FIRST.dgn,Design Model:142814
5A | 1F | A206045 (EN) - Partition :4 ,SHE-03.FIRST.dgn,Design Model:147005
5A | 1F | A206045 (EN) - Partition :4 ,SHE-03.FIRST.dgn,Design Model:147006
5A | 1F | A206045 (EN) - Partition :4 ,SHE-03.FIRST.dgn,Design Model:172228
5A | 1F | A206045 (EN) - Partition :4 ,SHE-03.FIRST.dgn,Design Model:172449
5A | 1F | A206045 (EN) - Partition :4 ,SHE-03.FIRST.dgn,Design Model:173632
5A | 1F | A206045 (EN) - Partition :4 ,SHE-03.FIRST.dgn,Design Model:230031
5A | 1F | A206045 (EN) - Partition :4 ,SHE-03.FIRST.dgn,Design Model:230345
5A | 1F | A206045 (EN) - Partition :4 ,SHE-03.FIRST.dgn,Design Model:230391
5A | 1F | A206045 (EN) - Partition :4 ,SHE-03.FIRST.dgn,Design Model:230437
5A | 1F | A206045 (EN) - Partition :4 ,SHE-03.FIRST.dgn,Design Model:231743
5A | 1F | A206045 (EN) - Partition :4 ,SHE-03.FIRST.dgn,Design Model:269095
5A | 1F | A206045 (EN) - Partition :4 ,SHE-03.FIRST.dgn,Design Model:269141
5A | 1F | A206045 (EN) - Partition :4 ,SHE-03.FIRST.dgn,Design Model:271053
5A | 1F | A206045 (EN) - Partition :4 ,SHE-03.FIRST.dgn,Design Model:272162
5A | 1F | A206045 (EN) - Partition :4 ,SHE-03.FIRST.dgn,Design Model:273961
5A | 1F | A206045 (EN) - Partition :4 ,SHE-03.FIRST.dgn,Design Model:274457
5A | 1F | A206045 (EN) - Partition :4 ,SHE-03.FIRST.dgn,Design Model:278735
5A | 1F | A206045 (EN) - Partition :4 ,SHE-03.FIRST.dgn,Design Model:278736
5A | 1F | A206045 (EN) - Partition :4 ,SHE-03.FIRST.dgn,Design Model:289175
5A | 1F | A206045 (EN) - Partition :4 ,SHE-03.FIRST.dgn,Design Model:290266
5A | 1F | A206045 (EN) - Partition :4 ,SHE-03.FIRST.dgn,Design Model:291273
5A | 1F | A206045 (EN) - Partition :4 ,SHE-03.FIRST.dgn,Design Model:297916
5A | 1F | A206045 (EN) - Partition :4 ,SHE-03.FIRST.dgn,Design Model:300531
5A | 1F | A206045 (EN) - Partition :4 ,SHE-03.FIRST.dgn,Design Model:300532
5A | 1F | A206045 (EN) - Partition :4 ,SHE-03.FIRST.dgn,Design Model:300570
5A | 1F | A206045 (EN) - Partition :4 ,SHE-03.FIRST.dgn,Design Model:304357
5A | 1F | A206045 (EN) - Partition :4 ,SHE-03.FIRST.dgn,Design Model:304647
5A | 1F | A206045 (EN) - Partition :4 ,SHE-03.FIRST.dgn,Design Model:332442
5A | 1F | A206045 (EN) - Partition :4 ,SHE-03.FIRST.dgn,Design Model:332488
5A | 1F | A206045 (EN) - Partition :4 ,SHE-03.FIRST.dgn,Design Model:354651
5A | 1F | A206045 (EN) - Partition :4 ,SHE-03.FIRST.dgn,Design Model:355951
5A | 1F | A206045 (EN) - Partition :4 ,SHE-03.FIRST.dgn,Design Model:362997
5A | 1F | A206045 (EN) - Partition :4 ,SHE-03.FIRST.dgn,Design Model:366252
5A | 1F | A206045 (EN) - Partition :4 ,SHE-03.FIRST.dgn,Design Model:374761
5A | 1F | A206045 (EN) - Partition :4 ,SHE-03.FIRST.dgn,Design Model:379423
5A | 3F | A206045 (EN) - Partition :6 ,SHE-05.THIRD.dgn,Design Model:142264
5A | 3F | A206045 (EN) - Partition :6 ,SHE-05.THIRD.dgn,Design Model:142271
5A | 3F | A206045 (EN) - Partition :6 ,SHE-05.THIRD.dgn,Design Model:142272
5A | 3F | A206045 (EN) - Partition :6 ,SHE-05.THIRD.dgn,Design Model:142274
5A | 3F | A206045 (EN) - Partition :6 ,SHE-05.THIRD.dgn,Design Model:142275
5A | 3F | A206045 (EN) - Partition :6 ,SHE-05.THIRD.dgn,Design Model:142804
5A | 3F | A206045 (EN) - Partition :6 ,SHE-05.THIRD.dgn,Design Model:142805
5A | 3F | A206045 (EN) - Partition :6 ,SHE-05.THIRD.dgn,Design Model:142806
5A | 3F | A206045 (EN) - Partition :6 ,SHE-05.THIRD.dgn,Design Model:142807
5A | 3F | A206045 (EN) - Partition :6 ,SHE-05.THIRD.dgn,Design Model:142813
5A | 3F | A206045 (EN) - Partition :6 ,SHE-05.THIRD.dgn,Design Model:142814
5A | 3F | A206045 (EN) - Partition :6 ,SHE-05.THIRD.dgn,Design Model:147005
5A | 3F | A206045 (EN) - Partition :6 ,SHE-05.THIRD.dgn,Design Model:147006
5A | 3F | A206045 (EN) - Partition :6 ,SHE-05.THIRD.dgn,Design Model:172228
5A | 3F | A206045 (EN) - Partition :6 ,SHE-05.THIRD.dgn,Design Model:172449
5A | 3F | A206045 (EN) - Partition :6 ,SHE-05.THIRD.dgn,Design Model:173632
5A | 3F | A206045 (EN) - Partition :6 ,SHE-05.THIRD.dgn,Design Model:230031
5A | 3F | A206045 (EN) - Partition :6 ,SHE-05.THIRD.dgn,Design Model:230345
5A | 3F | A206045 (EN) - Partition :6 ,SHE-05.THIRD.dgn,Design Model:230391
5A | 3F | A206045 (EN) - Partition :6 ,SHE-05.THIRD.dgn,Design Model:230437
5A | 3F | A206045 (EN) - Partition :6 ,SHE-05.THIRD.dgn,Design Model:231743
5A | 3F | A206045 (EN) - Partition :6 ,SHE-05.THIRD.dgn,Design Model:253334
5A | 3F | A206045 (EN) - Partition :6 ,SHE-05.THIRD.dgn,Design Model:269095
5A | 3F | A206045 (EN) - Partition :6 ,SHE-05.THIRD.dgn,Design Model:269141
5A | 3F | A206045 (EN) - Partition :6 ,SHE-05.THIRD.dgn,Design Model:271053
5A | 3F | A206045 (EN) - Partition :6 ,SHE-05.THIRD.dgn,Design Model:272162
5A | 3F | A206045 (EN) - Partition :6 ,SHE-05.THIRD.dgn,Design Model:273961
5A | 3F | A206045 (EN) - Partition :6 ,SHE-05.THIRD.dgn,Design Model:274457
5A | 3F | A206045 (EN) - Partition :6 ,SHE-05.THIRD.dgn,Design Model:278735
5A | 3F | A206045 (EN) - Partition :6 ,SHE-05.THIRD.dgn,Design Model:278736
5A | 3F | A206045 (EN) - Partition :6 ,SHE-05.THIRD.dgn,Design Model:289175
5A | 3F | A206045 (EN) - Partition :6 ,SHE-05.THIRD.dgn,Design Model:290266
5A | 3F | A206045 (EN) - Partition :6 ,SHE-05.THIRD.dgn,Design Model:291273
5A | 3F | A206045 (EN) - Partition :6 ,SHE-05.THIRD.dgn,Design Model:297916
5A | 3F | A206045 (EN) - Partition :6 ,SHE-05.THIRD.dgn,Design Model:300531
5A | 3F | A206045 (EN) - Partition :6 ,SHE-05.THIRD.dgn,Design Model:300532
5A | 3F | A206045 (EN) - Partition :6 ,SHE-05.THIRD.dgn,Design Model:300570
5A | 3F | A206045 (EN) - Partition :6 ,SHE-05.THIRD.dgn,Design Model:304357
5A | 3F | A206045 (EN) - Partition :6 ,SHE-05.THIRD.dgn,Design Model:304647
5A | 3F | A206045 (EN) - Partition :6 ,SHE-05.THIRD.dgn,Design Model:329167
5A | 3F | A206045 (EN) - Partition :6 ,SHE-05.THIRD.dgn,Design Model:329592
5A | 3F | A206045 (EN) - Partition :6 ,SHE-05.THIRD.dgn,Design Model:332442
5A | 3F | A206045 (EN) - Partition :6 ,SHE-05.THIRD.dgn,Design Model:332488
5A | 3F | A206045 (EN) - Partition :6 ,SHE-05.THIRD.dgn,Design Model:369086
5A | 2F | A206045 (EN) - Partition :18 ,SHE-04.SECOND.dgn,Design Model:142264
5A | 2F | A206045 (EN) - Partition :18 ,SHE-04.SECOND.dgn,Design Model:142271
5A | 2F | A206045 (EN) - Partition :18 ,SHE-04.SECOND.dgn,Design Model:142272
5A | 2F | A206045 (EN) - Partition :18 ,SHE-04.SECOND.dgn,Design Model:142274
5A | 2F | A206045 (EN) - Partition :18 ,SHE-04.SECOND.dgn,Design Model:142275
5A | 2F | A206045 (EN) - Partition :18 ,SHE-04.SECOND.dgn,Design Model:142804
5A | 2F | A206045 (EN) - Partition :18 ,SHE-04.SECOND.dgn,Design Model:142805
5A | 2F | A206045 (EN) - Partition :18 ,SHE-04.SECOND.dgn,Design Model:142806
5A | 2F | A206045 (EN) - Partition :18 ,SHE-04.SECOND.dgn,Design Model:142807
5A | 2F | A206045 (EN) - Partition :18 ,SHE-04.SECOND.dgn,Design Model:142813
5A | 2F | A206045 (EN) - Partition :18 ,SHE-04.SECOND.dgn,Design Model:142814
5A | 2F | A206045 (EN) - Partition :18 ,SHE-04.SECOND.dgn,Design Model:147005
5A | 2F | A206045 (EN) - Partition :18 ,SHE-04.SECOND.dgn,Design Model:147006
5A | 2F | A206045 (EN) - Partition :18 ,SHE-04.SECOND.dgn,Design Model:172228
5A | 2F | A206045 (EN) - Partition :18 ,SHE-04.SECOND.dgn,Design Model:172449
5A | 2F | A206045 (EN) - Partition :18 ,SHE-04.SECOND.dgn,Design Model:173632
5A | 2F | A206045 (EN) - Partition :18 ,SHE-04.SECOND.dgn,Design Model:230031
5A | 2F | A206045 (EN) - Partition :18 ,SHE-04.SECOND.dgn,Design Model:230345
5A | 2F | A206045 (EN) - Partition :18 ,SHE-04.SECOND.dgn,Design Model:230391
5A | 2F | A206045 (EN) - Partition :18 ,SHE-04.SECOND.dgn,Design Model:230437
5A | 2F | A206045 (EN) - Partition :18 ,SHE-04.SECOND.dgn,Design Model:231743
5A | 2F | A206045 (EN) - Partition :18 ,SHE-04.SECOND.dgn,Design Model:253334
5A | 2F | A206045 (EN) - Partition :18 ,SHE-04.SECOND.dgn,Design Model:269095
5A | 2F | A206045 (EN) - Partition :18 ,SHE-04.SECOND.dgn,Design Model:269141
5A | 2F | A206045 (EN) - Partition :18 ,SHE-04.SECOND.dgn,Design Model:271053
5A | 2F | A206045 (EN) - Partition :18 ,SHE-04.SECOND.dgn,Design Model:272162
5A | 2F | A206045 (EN) - Partition :18 ,SHE-04.SECOND.dgn,Design Model:273961
5A | 2F | A206045 (EN) - Partition :18 ,SHE-04.SECOND.dgn,Design Model:274457
5A | 2F | A206045 (EN) - Partition :18 ,SHE-04.SECOND.dgn,Design Model:278735
5A | 2F | A206045 (EN) - Partition :18 ,SHE-04.SECOND.dgn,Design Model:278736
5A | 2F | A206045 (EN) - Partition :18 ,SHE-04.SECOND.dgn,Design Model:289175
5A | 2F | A206045 (EN) - Partition :18 ,SHE-04.SECOND.dgn,Design Model:290266
5A | 2F | A206045 (EN) - Partition :18 ,SHE-04.SECOND.dgn,Design Model:291273
5A | 2F | A206045 (EN) - Partition :18 ,SHE-04.SECOND.dgn,Design Model:297916
5A | 2F | A206045 (EN) - Partition :18 ,SHE-04.SECOND.dgn,Design Model:300531
5A | 2F | A206045 (EN) - Partition :18 ,SHE-04.SECOND.dgn,Design Model:300532
5A | 2F | A206045 (EN) - Partition :18 ,SHE-04.SECOND.dgn,Design Model:300570
5A | 2F | A206045 (EN) - Partition :18 ,SHE-04.SECOND.dgn,Design Model:304357
5A | 2F | A206045 (EN) - Partition :18 ,SHE-04.SECOND.dgn,Design Model:304647
5A | 2F | A206045 (EN) - Partition :18 ,SHE-04.SECOND.dgn,Design Model:329167
5A | 2F | A206045 (EN) - Partition :18 ,SHE-04.SECOND.dgn,Design Model:329592
5A | 2F | A206045 (EN) - Partition :18 ,SHE-04.SECOND.dgn,Design Model:332442
5A | 2F | A206045 (EN) - Partition :18 ,SHE-04.SECOND.dgn,Design Model:332488
5A | 2F | A206045 (EN) - Partition :18 ,SHE-04.SECOND.dgn,Design Model:375811

# IfcWall: SHE_A-Walls_Type05b_Partition_80mm (48)
Type - Description: SHE_A-Walls_Type05b_Partition_80mm
Type - Wall Parameters - Type: Wall; Compound Wall Assembly: yes
Type - Thermal Transmittance - Is External: no; Is Below Grade: no
Type - Space Bounding - Is Space Bounding: yes
Type - Materials - Part Definition: A-CompoundWalls::SHE_A-Walls_Type05b_Partition_80mm
Type - LEED Parameters - LEED | Pre-consumer Recycled (%): 0; LEED | Regional Material: no; LEED | Post-consumer Recycled (%): 0
Type - Identification - ID | Type ID: A206034 (EN); ID | Description: SHE_A-Walls_Type05b_Partition_80mm; ID | Notes: https://www.british-gypsu m.com/Specification/White-Book-Specification-Selector/internal-partitions-walls/gypwall-single-frame/a206034-en
Type - Fire Resistance - Fire | Rating: F30; Fire | IsCombustible: no; Fire | Compartmentation: no
Type - Discipline - Discipline: Architectural
Type - Classification - Uniclass2015: EF_25_10
Type - Acoustical Parameters - Acoustic Rating (STC): 42 (min. 40)
Pset_WallCommon - AcousticRating: 42 (req. 40); Combustible: no; Compartmentation: no; FireRating: F30; IsExternal: no; LoadBearing: no
Identification - ID | Number: 5B; ID | Keynote: https://www.british-gyp sum.com/Specification/White-Book-Specification-Selector/internal-partitions-walls/gypwall-single-frame/a206034-en; ID | Notes: SHE_A-Walls_Type05b_Partition_80mm
Construction Phase - Phase: New Construction
Acoustical Parameters - Acoustic Rating (STC): 42 (req. 40)
Name | In | Description | ID | Description
5B | GF | A206034 (EN) - Partition :1 ,SHE-01.GROUND.dgn,Design Model:152839 | Partition
5B | GF | A206034 (EN) - Partition :1 ,SHE-01.GROUND.dgn,Design Model:159968 | Partition
5B | GF | A206034 (EN) - Partition :1 ,SHE-01.GROUND.dgn,Design Model:161854 | Partition
5B | GF | A206034 (EN) - Partition :1 ,SHE-01.GROUND.dgn,Design Model:178851 | Partition
5B | GF | A206034 (EN) - Partition :1 ,SHE-01.GROUND.dgn,Design Model:178897 | Partition
5B | GF | A206034 (EN) - Partition :1 ,SHE-01.GROUND.dgn,Design Model:182566 | Partition
5B | GF | A206034 (EN) - Partition :1 ,SHE-01.GROUND.dgn,Design Model:182835 | Partition
5B | MF | A206034 (EN) - Partition :2 ,SHE-02.MEZZANINE.dgn,Design Model:143593 | Partition
5B | MF | A206034 (EN) - Partition :2 ,SHE-02.MEZZANINE.dgn,Design Model:195705 | Partition
5B | 1F | A206034 (EN) - Partition :7 ,SHE-06.FOURTH.dgn,Design Model:215591 | Partition
5B | 1F | A206034 (EN) - Partition :7 ,SHE-06.FOURTH.dgn,Design Model:218434 | Partition
5B | 1F | A206034 (EN) - Partition :7 ,SHE-06.FOURTH.dgn,Design Model:219317 | Partition
5B | 1F | A206034 (EN) - Partition :7 ,SHE-06.FOURTH.dgn,Design Model:220209 | Partition
5B | 1F | A206034 (EN) - Partition :7 ,SHE-06.FOURTH.dgn,Design Model:222926 | Partition
5B | 1F | A206034 (EN) - Partition :7 ,SHE-06.FOURTH.dgn,Design Model:223212 | Partition
5B | 1F | A206034 (EN) - Partition :7 ,SHE-06.FOURTH.dgn,Design Model:223258 | Partition
5B | 1F | A206034 (EN) - Partition :7 ,SHE-06.FOURTH.dgn,Design Model:226024 | Partition
5B | 1F | A206034 (EN) - Partition :7 ,SHE-06.FOURTH.dgn,Design Model:226231 | Partition
5B | 1F | A206034 (EN) - Partition :7 ,SHE-06.FOURTH.dgn,Design Model:226611 | Partition
5B | 1F | A206034 (EN) - Partition :7 ,SHE-06.FOURTH.dgn,Design Model:226765 | Partition
5B | 1F | A206034 (EN) - Partition :7 ,SHE-06.FOURTH.dgn,Design Model:229615 | Partition
5B | 1F | A206034 (EN) - Partition :7 ,SHE-06.FOURTH.dgn,Design Model:229661 | Partition
5B | 1F | A206034 (EN) - Partition :7 ,SHE-06.FOURTH.dgn,Design Model:260211 | Partition
5B | 1F | A206034 (EN) - Partition :7 ,SHE-06.FOURTH.dgn,Design Model:262439 | Partition
5B | 1F | A206034 (EN) - Partition :7 ,SHE-06.FOURTH.dgn,Design Model:262558 | Partition
5B | 1F | A206034 (EN) - Partition :7 ,SHE-06.FOURTH.dgn,Design Model:262821 | Partition
5B | 1F | A206034 (EN) - Partition :7 ,SHE-06.FOURTH.dgn,Design Model:263509 | Partition
5B | 1F | A206034 (EN) - Partition :7 ,SHE-06.FOURTH.dgn,Design Model:333108 | Partition
5B | 1F | A206034 (EN) - Partition :7 ,SHE-06.FOURTH.dgn,Design Model:408223 | Partition
5B | 1F | A206034 (EN) - Partition :7 ,SHE-06.FOURTH.dgn,Design Model:408273 | Partition
5B | 1F | A206034 (EN) - Partition :7 ,SHE-06.FOURTH.dgn,Design Model:450822 | Partition
5B | 1F | A206034 (EN) - Partition :7 ,SHE-06.FOURTH.dgn,Design Model:451097 | Partition
5B | 1F | A206034 (EN) - Partition :7 ,SHE-06.FOURTH.dgn,Design Model:453259 | Partition
5B | 1F | A206034 (EN) - Partition :7 ,SHE-06.FOURTH.dgn,Design Model:482970 | Partition
5B | 1F | A206034 (EN) - Partition :7 ,SHE-06.FOURTH.dgn,Design Model:483089 | Partition
5B | 1F | A206034 (EN) - Partition :7 ,SHE-06.FOURTH.dgn,Design Model:483315 | Partition
5B | 1F | A206034 (EN ) - Partition F30 :7,SHE-06.FOURTH.dgn,Design Model:492922 | Partition F30
5B | 1F | A206034 (EN ) - Partition F30 :7,SHE-06.FOURTH.dgn,Design Model:492963 | Partition F30
5B | 1F | A206034 (EN ) - Partition F30 :7,SHE-06.FOURTH.dgn,Design Model:493012 | Partition F30
5B | 1F | A206034 (EN ) - Partition F30 :7,SHE-06.FOURTH.dgn,Design Model:493161 | Partition F30
5B | 1F | A206034 (EN ) - Partition F30 :7,SHE-06.FOURTH.dgn,Design Model:493206 | Partition F30
5B | 1F | A206034 (EN ) - Partition F30 :7,SHE-06.FOURTH.dgn,Design Model:493247 | Partition F30
5B | 1F | A206034 (EN ) - Partition F30 :7,SHE-06.FOURTH.dgn,Design Model:493288 | Partition F30
5B | 1F | A206034 (EN ) - Partition F30 :7,SHE-06.FOURTH.dgn,Design Model:493447 | Partition F30
5B | 1F | A206034 (EN ) - Partition F30 :7,SHE-06.FOURTH.dgn,Design Model:493542 | Partition F30
5B | 1F | A206034 (EN ) - Partition F30 :7,SHE-06.FOURTH.dgn,Design Model:493583 | Partition F30
5B | 1F | A206034 (EN ) - Partition F30 :7,SHE-06.FOURTH.dgn,Design Model:493624 | Partition F30
5B | 1F | A206034 (EN ) - Partition F30 :7,SHE-06.FOURTH.dgn,Design Model:493699 | Partition F30

# IfcWall: SHE_A-Walls_Type06c_ExternalWallInsulation_60mm (22)
Type - Description: SHE_A-Walls_Type06c_ExternalWallInsulation_60mm
Type - Wall Parameters - Type: Wall; Compound Wall Assembly: yes
Type - Thermal Transmittance - Is External: no; Is Below Grade: no
Type - Space Bounding - Is Space Bounding: yes
Type - Materials - Part Definition: A-CompoundWalls::SHE_A-Walls_Type06c_ExternalWallInsulation_60mm
Type - LEED Parameters - LEED | Pre-consumer Recycled (%): 0; LEED | Regional Material: no; LEED | Post-consumer Recycled (%): 0
Type - Identification - ID | Description: SHE_A-Walls_Type06c_ExternalWallInsulation_60mm; ID | Notes: https://celotex.co.uk/products/celotex-ga4000
Type - Fire Resistance - Fire | IsCombustible: no; Fire | Compartmentation: no
Type - Discipline - Discipline: Architectural
Type - Construction Phase - Phase: New Construction
Type - Classification - Uniclass2015: EF_25_10
Pset_WallCommon - Combustible: no; Compartmentation: no; IsExternal: no; LoadBearing: no
Identification - ID | Type ID: U-Value 0.3; ID | Number: 6C; ID | Description: FacadeInsulation; ID | Keynote: https://celotex.co.uk/products/celotex-ga4000; ID | Notes: SHE_A-Walls_Type06c_ExternalWallInsulation_60mm
Name | In | Description | AcousticRating = Acoustic Rating (STC)
6C | GF | U-Value 0.3 - FacadeInsulation :1,SHE-01.GROUND.dgn,Design Model:183216 | req. 48
6C | GF | U-Value 0.3 - FacadeInsulation :1,SHE-01.GROUND.dgn,Design Model:183330 | req. 48
6C | GF | U-Value 0.3 - FacadeInsulation :1,SHE-01.GROUND.dgn,Design Model:183358 | req. 48
6C | GF | U-Value 0.3 - FacadeInsulation :1,SHE-01.GROUND.dgn,Design Model:183895 | req. 48
6C | GF | U-Value 0.3 - FacadeInsulation :1,SHE-01.GROUND.dgn,Design Model:183923 | req. 48
6C | GF | U-Value 0.3 - FacadeInsulation :1,SHE-01.GROUND.dgn,Design Model:183951 | req. 48
6C | GF | U-Value 0.3 - FacadeInsulation :1,SHE-01.GROUND.dgn,Design Model:183979 | req. 48
6C | GF | U-Value 0.3 - FacadeInsulation :1,SHE-01.GROUND.dgn,Design Model:184491 | req. 48
6C | GF | U-Value 0.3 - FacadeInsulation :1,SHE-01.GROUND.dgn,Design Model:184519 | req. 48
6C | GF | U-Value 0.3 - FacadeInsulation :1,SHE-01.GROUND.dgn,Design Model:184547 | req. 48
6C | GF | U-Value 0.3 - FacadeInsulation :1,SHE-01.GROUND.dgn,Design Model:184575 | req. 48
6C | MF | U-Value 0.3 - FacadeInsulation :2,SHE-02.MEZZANINE.dgn,Design Model:203802 | Rw 52dB Rw+Ctr 48dB | Identification - ID | Asset Tag: .
6C | MF | U-Value 0.3 - FacadeInsulation :2,SHE-02.MEZZANINE.dgn,Design Model:203859 | Rw 52dB Rw+Ctr 48dB | Identification - ID | Asset Tag: .
6C | MF | U-Value 0.3 - FacadeInsulation :2,SHE-02.MEZZANINE.dgn,Design Model:203884 | Rw 52dB Rw+Ctr 48dB | Identification - ID | Asset Tag: .
6C | MF | U-Value 0.3 - FacadeInsulation :2,SHE-02.MEZZANINE.dgn,Design Model:203909 | Rw 52dB Rw+Ctr 48dB | Identification - ID | Asset Tag: .
6C | MF | U-Value 0.3 - FacadeInsulation :2,SHE-02.MEZZANINE.dgn,Design Model:203966 | Rw 52dB Rw+Ctr 48dB | Identification - ID | Asset Tag: .
6C | MF | U-Value 0.3 - FacadeInsulation :2,SHE-02.MEZZANINE.dgn,Design Model:203991 | Rw 52dB Rw+Ctr 48dB | Identification - ID | Asset Tag: .
6C | MF | U-Value 0.3 - FacadeInsulation :2,SHE-02.MEZZANINE.dgn,Design Model:204016 | Rw 52dB Rw+Ctr 48dB | Identification - ID | Asset Tag: .
6C | MF | U-Value 0.3 - FacadeInsulation :2,SHE-02.MEZZANINE.dgn,Design Model:204041 | Rw 52dB Rw+Ctr 48dB | Identification - ID | Asset Tag: .
6C | MF | U-Value 0.3 - FacadeInsulation :2,SHE-02.MEZZANINE.dgn,Design Model:204066 | Rw 52dB Rw+Ctr 48dB | Identification - ID | Asset Tag: .
6C | MF | U-Value 0.3 - FacadeInsulation :2,SHE-02.MEZZANINE.dgn,Design Model:204091 | Rw 52dB Rw+Ctr 48dB | Identification - ID | Asset Tag: .
6C | MF | U-Value 0.3 - FacadeInsulation :2,SHE-02.MEZZANINE.dgn,Design Model:204136 | Rw 52dB Rw+Ctr 48dB | Identification - ID | Asset Tag: .

# IfcWall: SHE_A-Walls_Type06d_ExternalWallInsulation_48mm (227)
Type - Description: SHE_A-Walls_Type06d_ExternalWallInsulation_48mm
Type - Wall Parameters - Type: Wall; Compound Wall Assembly: yes
Type - Thermal Transmittance - Is External: no; Is Below Grade: no
Type - Space Bounding - Is Space Bounding: yes
Type - Materials - Part Definition: A-CompoundWalls::SHE_A-Walls_Type06d_ExternalWallInsulation_48mm
Type - LEED Parameters - LEED | Pre-consumer Recycled (%): 0; LEED | Regional Material: no; LEED | Post-consumer Recycled (%): 0
Type - Identification - ID | Description: SHE_A-Walls_Type06d_ExternalWallInsulation_48mm
Type - Fire Resistance - Fire | IsCombustible: no; Fire | Compartmentation: no
Type - Discipline - Discipline: Architectural
Type - Construction Phase - Phase: New Construction
Type - Classification - Uniclass2015: EF_25_10
Pset_WallCommon - AcousticRating: req. 48; Combustible: no; Compartmentation: no; IsExternal: no; LoadBearing: no
Identification - ID | Type ID: U-Value 0.5; ID | Number: 6D; ID | Description: FacadeInsulation; ID | Keynote: https://www.british-gyp sum.com/products/board-products/gyproc-thermaline-plus-48mm; ID | Notes: SHE_A-Walls_Type06d_ExternalWallInsulation_48mm
Acoustical Parameters - Acoustic Rating (STC): req. 48
Name | In | Description
6D | 1F | U-Value 0.5 - FacadeInsulation :4,SHE-03.FIRST.dgn,Design Model:141902
6D | 1F | U-Value 0.5 - FacadeInsulation :4,SHE-03.FIRST.dgn,Design Model:141903
6D | 1F | U-Value 0.5 - FacadeInsulation :4,SHE-03.FIRST.dgn,Design Model:141904
6D | 1F | U-Value 0.5 - FacadeInsulation :4,SHE-03.FIRST.dgn,Design Model:141907
6D | 1F | U-Value 0.5 - FacadeInsulation :4,SHE-03.FIRST.dgn,Design Model:141908
6D | 1F | U-Value 0.5 - FacadeInsulation :4,SHE-03.FIRST.dgn,Design Model:141909
6D | 1F | U-Value 0.5 - FacadeInsulation :4,SHE-03.FIRST.dgn,Design Model:141910
6D | 1F | U-Value 0.5 - FacadeInsulation :4,SHE-03.FIRST.dgn,Design Model:141911
6D | 1F | U-Value 0.5 - FacadeInsulation :4,SHE-03.FIRST.dgn,Design Model:141912
6D | 1F | U-Value 0.5 - FacadeInsulation :4,SHE-03.FIRST.dgn,Design Model:141913
6D | 1F | U-Value 0.5 - FacadeInsulation :4,SHE-03.FIRST.dgn,Design Model:141914
6D | 1F | U-Value 0.5 - FacadeInsulation :4,SHE-03.FIRST.dgn,Design Model:141917
6D | 1F | U-Value 0.5 - FacadeInsulation :4,SHE-03.FIRST.dgn,Design Model:141918
6D | 1F | U-Value 0.5 - FacadeInsulation :4,SHE-03.FIRST.dgn,Design Model:141919
6D | 1F | U-Value 0.5 - FacadeInsulation :4,SHE-03.FIRST.dgn,Design Model:141920
6D | 1F | U-Value 0.5 - FacadeInsulation :4,SHE-03.FIRST.dgn,Design Model:141921
6D | 1F | U-Value 0.5 - FacadeInsulation :4,SHE-03.FIRST.dgn,Design Model:141922
6D | 1F | U-Value 0.5 - FacadeInsulation :4,SHE-03.FIRST.dgn,Design Model:141927
6D | 1F | U-Value 0.5 - FacadeInsulation :4,SHE-03.FIRST.dgn,Design Model:141928
6D | 1F | U-Value 0.5 - FacadeInsulation :4,SHE-03.FIRST.dgn,Design Model:141929
6D | 1F | U-Value 0.5 - FacadeInsulation :4,SHE-03.FIRST.dgn,Design Model:141960
6D | 1F | U-Value 0.5 - FacadeInsulation :4,SHE-03.FIRST.dgn,Design Model:141961
6D | 1F | U-Value 0.5 - FacadeInsulation :4,SHE-03.FIRST.dgn,Design Model:141962
6D | 1F | U-Value 0.5 - FacadeInsulation :4,SHE-03.FIRST.dgn,Design Model:390499
6D | 1F | U-Value 0.5 - FacadeInsulation :4,SHE-03.FIRST.dgn,Design Model:390500
6D | 1F | U-Value 0.5 - FacadeInsulation :4,SHE-03.FIRST.dgn,Design Model:390501
6D | 1F | U-Value 0.5 - FacadeInsulation :4,SHE-03.FIRST.dgn,Design Model:392991
6D | 1F | U-Value 0.5 - FacadeInsulation :4,SHE-03.FIRST.dgn,Design Model:394187
6D | 1F | U-Value 0.5 - FacadeInsulation :4,SHE-03.FIRST.dgn,Design Model:394284
6D | 1F | U-Value 0.5 - FacadeInsulation :4,SHE-03.FIRST.dgn,Design Model:394429
6D | 1F | U-Value 0.5 - FacadeInsulation :4,SHE-03.FIRST.dgn,Design Model:394526
6D | 1F | U-Value 0.5 - FacadeInsulation :4,SHE-03.FIRST.dgn,Design Model:394647
6D | 1F | U-Value 0.5 - FacadeInsulation :4,SHE-03.FIRST.dgn,Design Model:394744
6D | 1F | U-Value 0.5 - FacadeInsulation :4,SHE-03.FIRST.dgn,Design Model:394841
6D | 1F | U-Value 0.5 - FacadeInsulation :4,SHE-03.FIRST.dgn,Design Model:394938
6D | 1F | U-Value 0.5 - FacadeInsulation :4,SHE-03.FIRST.dgn,Design Model:395059
6D | 1F | U-Value 0.5 - FacadeInsulation :4,SHE-03.FIRST.dgn,Design Model:395132
6D | 1F | U-Value 0.5 - FacadeInsulation :4,SHE-03.FIRST.dgn,Design Model:395237
6D | 1F | U-Value 0.5 - FacadeInsulation :4,SHE-03.FIRST.dgn,Design Model:395334
6D | 1F | U-Value 0.5 - FacadeInsulation :4,SHE-03.FIRST.dgn,Design Model:395431
6D | 1F | U-Value 0.5 - FacadeInsulation :4,SHE-03.FIRST.dgn,Design Model:395552
6D | 1F | U-Value 0.5 - FacadeInsulation :4,SHE-03.FIRST.dgn,Design Model:395649
6D | 1F | U-Value 0.5 - FacadeInsulation :4,SHE-03.FIRST.dgn,Design Model:395722
6D | 1F | U-Value 0.5 - FacadeInsulation :4,SHE-03.FIRST.dgn,Design Model:395795
6D | 1F | U-Value 0.5 - FacadeInsulation :4,SHE-03.FIRST.dgn,Design Model:395892
6D | 1F | U-Value 0.5 - FacadeInsulation :4,SHE-03.FIRST.dgn,Design Model:395965
6D | 1F | U-Value 0.5 - FacadeInsulation :4,SHE-03.FIRST.dgn,Design Model:396078
6D | 1F | U-Value 0.5 - FacadeInsulation :4,SHE-03.FIRST.dgn,Design Model:396215
6D | 1F | U-Value 0.5 - FacadeInsulation :4,SHE-03.FIRST.dgn,Design Model:396288
6D | 1F | U-Value 0.5 - FacadeInsulation :4,SHE-03.FIRST.dgn,Design Model:396361
6D | 1F | U-Value 0.5 - FacadeInsulation :4,SHE-03.FIRST.dgn,Design Model:396498
6D | 1F | U-Value 0.5 - FacadeInsulation :4,SHE-03.FIRST.dgn,Design Model:396611
6D | 1F | U-Value 0.5 - FacadeInsulation :4,SHE-03.FIRST.dgn,Design Model:396684
6D | 1F | U-Value 0.5 - FacadeInsulation :4,SHE-03.FIRST.dgn,Design Model:396781
6D | 1F | U-Value 0.5 - FacadeInsulation :4,SHE-03.FIRST.dgn,Design Model:396854
6D | 1F | U-Value 0.5 - FacadeInsulation :4,SHE-03.FIRST.dgn,Design Model:396927
6D | 1F | U-Value 0.5 - FacadeInsulation :4,SHE-03.FIRST.dgn,Design Model:397024
6D | 1F | U-Value 0.5 - FacadeInsulation :4,SHE-03.FIRST.dgn,Design Model:397097
6D | 1F | U-Value 0.5 - FacadeInsulation :4,SHE-03.FIRST.dgn,Design Model:397202
6D | 1F | U-Value 0.5 - FacadeInsulation :4,SHE-03.FIRST.dgn,Design Model:397355
6D | 1F | U-Value 0.5 - FacadeInsulation :4,SHE-03.FIRST.dgn,Design Model:397444
6D | 1F | U-Value 0.5 - FacadeInsulation :4,SHE-03.FIRST.dgn,Design Model:397517
6D | 1F | U-Value 0.5 - FacadeInsulation :4,SHE-03.FIRST.dgn,Design Model:397614
6D | 1F | U-Value 0.5 - FacadeInsulation :4,SHE-03.FIRST.dgn,Design Model:397711
6D | 1F | U-Value 0.5 - FacadeInsulation :4,SHE-03.FIRST.dgn,Design Model:398116
6D | 1F | U-Value 0.5 - FacadeInsulation :4,SHE-03.FIRST.dgn,Design Model:398245
6D | 1F | U-Value 0.5 - FacadeInsulation :4,SHE-03.FIRST.dgn,Design Model:398342
6D | 1F | U-Value 0.5 - FacadeInsulation :4,SHE-03.FIRST.dgn,Design Model:398487
6D | 1F | U-Value 0.5 - FacadeInsulation :4,SHE-03.FIRST.dgn,Design Model:398584
6D | 1F | U-Value 0.5 - FacadeInsulation :4,SHE-03.FIRST.dgn,Design Model:398729
6D | 1F | U-Value 0.5 - FacadeInsulation :4,SHE-03.FIRST.dgn,Design Model:398826
6D | 1F | U-Value 0.5 - FacadeInsulation :4,SHE-03.FIRST.dgn,Design Model:398971
6D | 1F | U-Value 0.5 - FacadeInsulation :4,SHE-03.FIRST.dgn,Design Model:399044
6D | 1F | U-Value 0.5 - FacadeInsulation :4,SHE-03.FIRST.dgn,Design Model:399141
6D | 1F | U-Value 0.5 - FacadeInsulation :4,SHE-03.FIRST.dgn,Design Model:399238
6D | 1F | U-Value 0.5 - FacadeInsulation :4,SHE-03.FIRST.dgn,Design Model:399335
6D | 1F | U-Value 0.5 - FacadeInsulation :4,SHE-03.FIRST.dgn,Design Model:399496
6D | 1F | U-Value 0.5 - FacadeInsulation :4,SHE-03.FIRST.dgn,Design Model:399593
6D | 1F | U-Value 0.5 - FacadeInsulation :4,SHE-03.FIRST.dgn,Design Model:399690
6D | 1F | U-Value 0.5 - FacadeInsulation :4,SHE-03.FIRST.dgn,Design Model:399787
6D | 1F | U-Value 0.5 - FacadeInsulation :4,SHE-03.FIRST.dgn,Design Model:399908
6D | 1F | U-Value 0.5 - FacadeInsulation :4,SHE-03.FIRST.dgn,Design Model:400005
6D | 1F | U-Value 0.5 - FacadeInsulation :4,SHE-03.FIRST.dgn,Design Model:400102
6D | 1F | U-Value 0.5 - FacadeInsulation :4,SHE-03.FIRST.dgn,Design Model:400199
6D | 1F | U-Value 0.5 - FacadeInsulation :4,SHE-03.FIRST.dgn,Design Model:400296
6D | 1F | U-Value 0.5 - FacadeInsulation :4,SHE-03.FIRST.dgn,Design Model:400417
6D | 1F | U-Value 0.5 - FacadeInsulation :4,SHE-03.FIRST.dgn,Design Model:400514
6D | 1F | U-Value 0.5 - FacadeInsulation :4,SHE-03.FIRST.dgn,Design Model:400667
6D | 1F | U-Value 0.5 - FacadeInsulation :4,SHE-03.FIRST.dgn,Design Model:400780
6D | 1F | U-Value 0.5 - FacadeInsulation :4,SHE-03.FIRST.dgn,Design Model:400987
6D | 1F | U-Value 0.5 - FacadeInsulation :4,SHE-03.FIRST.dgn,Design Model:401092
6D | 3F | U-Value 0.5 - FacadeInsulation :6,SHE-05.THIRD.dgn,Design Model:141882
6D | 3F | U-Value 0.5 - FacadeInsulation :6,SHE-05.THIRD.dgn,Design Model:141883
6D | 3F | U-Value 0.5 - FacadeInsulation :6,SHE-05.THIRD.dgn,Design Model:141893
6D | 3F | U-Value 0.5 - FacadeInsulation :6,SHE-05.THIRD.dgn,Design Model:141894
6D | 3F | U-Value 0.5 - FacadeInsulation :6,SHE-05.THIRD.dgn,Design Model:141895
6D | 3F | U-Value 0.5 - FacadeInsulation :6,SHE-05.THIRD.dgn,Design Model:141896
6D | 3F | U-Value 0.5 - FacadeInsulation :6,SHE-05.THIRD.dgn,Design Model:141897
6D | 3F | U-Value 0.5 - FacadeInsulation :6,SHE-05.THIRD.dgn,Design Model:141900
6D | 3F | U-Value 0.5 - FacadeInsulation :6,SHE-05.THIRD.dgn,Design Model:141901
6D | 3F | U-Value 0.5 - FacadeInsulation :6,SHE-05.THIRD.dgn,Design Model:141902
6D | 3F | U-Value 0.5 - FacadeInsulation :6,SHE-05.THIRD.dgn,Design Model:141903
6D | 3F | U-Value 0.5 - FacadeInsulation :6,SHE-05.THIRD.dgn,Design Model:141904
6D | 3F | U-Value 0.5 - FacadeInsulation :6,SHE-05.THIRD.dgn,Design Model:141907
6D | 3F | U-Value 0.5 - FacadeInsulation :6,SHE-05.THIRD.dgn,Design Model:141908
6D | 3F | U-Value 0.5 - FacadeInsulation :6,SHE-05.THIRD.dgn,Design Model:141909
6D | 3F | U-Value 0.5 - FacadeInsulation :6,SHE-05.THIRD.dgn,Design Model:141910
6D | 3F | U-Value 0.5 - FacadeInsulation :6,SHE-05.THIRD.dgn,Design Model:141911
6D | 3F | U-Value 0.5 - FacadeInsulation :6,SHE-05.THIRD.dgn,Design Model:141912
6D | 3F | U-Value 0.5 - FacadeInsulation :6,SHE-05.THIRD.dgn,Design Model:141913
6D | 3F | U-Value 0.5 - FacadeInsulation :6,SHE-05.THIRD.dgn,Design Model:141914
6D | 3F | U-Value 0.5 - FacadeInsulation :6,SHE-05.THIRD.dgn,Design Model:141917
6D | 3F | U-Value 0.5 - FacadeInsulation :6,SHE-05.THIRD.dgn,Design Model:141918
6D | 3F | U-Value 0.5 - FacadeInsulation :6,SHE-05.THIRD.dgn,Design Model:141919
6D | 3F | U-Value 0.5 - FacadeInsulation :6,SHE-05.THIRD.dgn,Design Model:141920
6D | 3F | U-Value 0.5 - FacadeInsulation :6,SHE-05.THIRD.dgn,Design Model:141921
6D | 3F | U-Value 0.5 - FacadeInsulation :6,SHE-05.THIRD.dgn,Design Model:141922
6D | 3F | U-Value 0.5 - FacadeInsulation :6,SHE-05.THIRD.dgn,Design Model:141923
6D | 3F | U-Value 0.5 - FacadeInsulation :6,SHE-05.THIRD.dgn,Design Model:141924
6D | 3F | U-Value 0.5 - FacadeInsulation :6,SHE-05.THIRD.dgn,Design Model:141927
6D | 3F | U-Value 0.5 - FacadeInsulation :6,SHE-05.THIRD.dgn,Design Model:141928
6D | 3F | U-Value 0.5 - FacadeInsulation :6,SHE-05.THIRD.dgn,Design Model:141929
6D | 3F | U-Value 0.5 - FacadeInsulation :6,SHE-05.THIRD.dgn,Design Model:141931
6D | 3F | U-Value 0.5 - FacadeInsulation :6,SHE-05.THIRD.dgn,Design Model:141934
6D | 3F | U-Value 0.5 - FacadeInsulation :6,SHE-05.THIRD.dgn,Design Model:141938
6D | 3F | U-Value 0.5 - FacadeInsulation :6,SHE-05.THIRD.dgn,Design Model:141939
6D | 3F | U-Value 0.5 - FacadeInsulation :6,SHE-05.THIRD.dgn,Design Model:141940
6D | 3F | U-Value 0.5 - FacadeInsulation :6,SHE-05.THIRD.dgn,Design Model:141941
6D | 3F | U-Value 0.5 - FacadeInsulation :6,SHE-05.THIRD.dgn,Design Model:141942
6D | 3F | U-Value 0.5 - FacadeInsulation :6,SHE-05.THIRD.dgn,Design Model:141943
6D | 3F | U-Value 0.5 - FacadeInsulation :6,SHE-05.THIRD.dgn,Design Model:141944
6D | 3F | U-Value 0.5 - FacadeInsulation :6,SHE-05.THIRD.dgn,Design Model:141945
6D | 3F | U-Value 0.5 - FacadeInsulation :6,SHE-05.THIRD.dgn,Design Model:141948
6D | 3F | U-Value 0.5 - FacadeInsulation :6,SHE-05.THIRD.dgn,Design Model:141949
6D | 3F | U-Value 0.5 - FacadeInsulation :6,SHE-05.THIRD.dgn,Design Model:141950
6D | 3F | U-Value 0.5 - FacadeInsulation :6,SHE-05.THIRD.dgn,Design Model:141951
6D | 3F | U-Value 0.5 - FacadeInsulation :6,SHE-05.THIRD.dgn,Design Model:141952
6D | 3F | U-Value 0.5 - FacadeInsulation :6,SHE-05.THIRD.dgn,Design Model:141953
6D | 3F | U-Value 0.5 - FacadeInsulation :6,SHE-05.THIRD.dgn,Design Model:141954
6D | 3F | U-Value 0.5 - FacadeInsulation :6,SHE-05.THIRD.dgn,Design Model:141955
6D | 3F | U-Value 0.5 - FacadeInsulation :6,SHE-05.THIRD.dgn,Design Model:141956
6D | 3F | U-Value 0.5 - FacadeInsulation :6,SHE-05.THIRD.dgn,Design Model:141957
6D | 3F | U-Value 0.5 - FacadeInsulation :6,SHE-05.THIRD.dgn,Design Model:141958
6D | 3F | U-Value 0.5 - FacadeInsulation :6,SHE-05.THIRD.dgn,Design Model:141959
6D | 3F | U-Value 0.5 - FacadeInsulation :6,SHE-05.THIRD.dgn,Design Model:141960
6D | 3F | U-Value 0.5 - FacadeInsulation :6,SHE-05.THIRD.dgn,Design Model:141961
6D | 3F | U-Value 0.5 - FacadeInsulation :6,SHE-05.THIRD.dgn,Design Model:141962
6D | 3F | U-Value 0.5 - FacadeInsulation :6,SHE-05.THIRD.dgn,Design Model:141965
6D | 3F | U-Value 0.5 - FacadeInsulation :6,SHE-05.THIRD.dgn,Design Model:141966
6D | 3F | U-Value 0.5 - FacadeInsulation :6,SHE-05.THIRD.dgn,Design Model:141967
6D | 3F | U-Value 0.5 - FacadeInsulation :6,SHE-05.THIRD.dgn,Design Model:141968
6D | 3F | U-Value 0.5 - FacadeInsulation :6,SHE-05.THIRD.dgn,Design Model:141969
6D | 3F | U-Value 0.5 - FacadeInsulation :6,SHE-05.THIRD.dgn,Design Model:141978
6D | 3F | U-Value 0.5 - FacadeInsulation :6,SHE-05.THIRD.dgn,Design Model:141979
6D | 3F | U-Value 0.5 - FacadeInsulation :6,SHE-05.THIRD.dgn,Design Model:141980
6D | 3F | U-Value 0.5 - FacadeInsulation :6,SHE-05.THIRD.dgn,Design Model:142263
6D | 3F | U-Value 0.5 - FacadeInsulation :6,SHE-05.THIRD.dgn,Design Model:142268
6D | 3F | U-Value 0.5 - FacadeInsulation :6,SHE-05.THIRD.dgn,Design Model:142542
6D | 3F | U-Value 0.5 - FacadeInsulation :6,SHE-05.THIRD.dgn,Design Model:171807
6D | 2F | U-Value 0.5 - FacadeInsulation :18,SHE-04.SECOND.dgn,Design Model:141882
6D | 2F | U-Value 0.5 - FacadeInsulation :18,SHE-04.SECOND.dgn,Design Model:141883
6D | 2F | U-Value 0.5 - FacadeInsulation :18,SHE-04.SECOND.dgn,Design Model:141893
6D | 2F | U-Value 0.5 - FacadeInsulation :18,SHE-04.SECOND.dgn,Design Model:141894
6D | 2F | U-Value 0.5 - FacadeInsulation :18,SHE-04.SECOND.dgn,Design Model:141895
6D | 2F | U-Value 0.5 - FacadeInsulation :18,SHE-04.SECOND.dgn,Design Model:141896
6D | 2F | U-Value 0.5 - FacadeInsulation :18,SHE-04.SECOND.dgn,Design Model:141897
6D | 2F | U-Value 0.5 - FacadeInsulation :18,SHE-04.SECOND.dgn,Design Model:141900
6D | 2F | U-Value 0.5 - FacadeInsulation :18,SHE-04.SECOND.dgn,Design Model:141901
6D | 2F | U-Value 0.5 - FacadeInsulation :18,SHE-04.SECOND.dgn,Design Model:141902
6D | 2F | U-Value 0.5 - FacadeInsulation :18,SHE-04.SECOND.dgn,Design Model:141903
6D | 2F | U-Value 0.5 - FacadeInsulation :18,SHE-04.SECOND.dgn,Design Model:141904
6D | 2F | U-Value 0.5 - FacadeInsulation :18,SHE-04.SECOND.dgn,Design Model:141907
6D | 2F | U-Value 0.5 - FacadeInsulation :18,SHE-04.SECOND.dgn,Design Model:141908
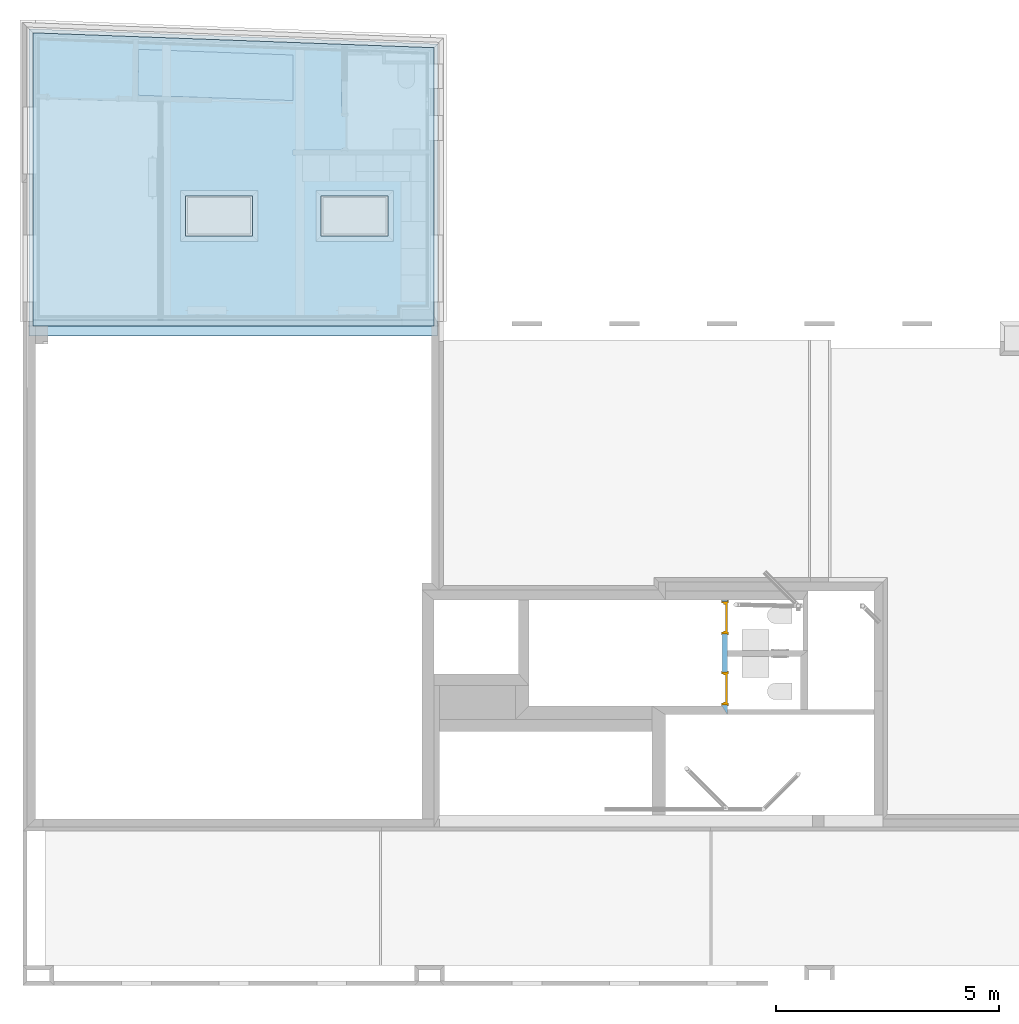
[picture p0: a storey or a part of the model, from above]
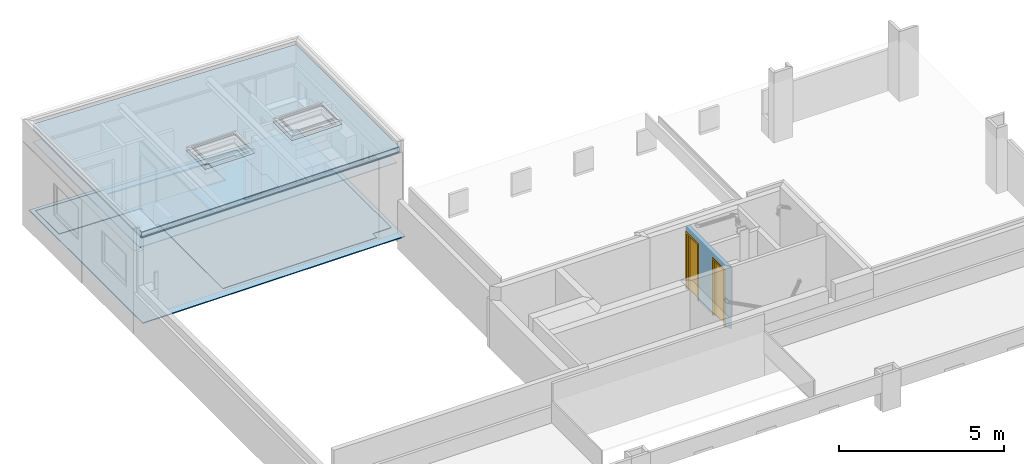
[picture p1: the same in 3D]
Properties of the parts of a building model (IFC2X3), part 15 of 16

# IfcWallStandardCase: A-Walls-ExternalBrick (106)
Name | In | Description | Material | ID | Description | ID | Notes | Phase
A-Walls-ExternalBrick | GF | Wall existing :1,SHE-01.GROUND.dgn ,Design Model:95846 | A_BSUK_WallsExternal_Brick 0.2 m | Wall existing | general | Existing to Remain
A-Walls-ExternalBrick | GF | Wall existing :1,SHE-01.GROUND.dgn ,Design Model:95855 | A_BSUK_WallsExternal_Brick 0.2 m | Wall existing | general | Existing to Remain
A-Walls-ExternalBrick | GF | Wall existing :1,SHE-01.GROUND.dgn ,Design Model:95864 | A_BSUK_WallsExternal_Brick 0.2 m | Wall existing | general | Existing to Remain
A-Walls-ExternalBrick | GF | Wall existing :1,SHE-01.GROUND.dgn ,Design Model:95873 | A_BSUK_WallsExternal_Brick 0.215 m | Wall existing | general | Existing to Remain
A-Walls-ExternalBrick | GF | Wall existing :1,SHE-01.GROUND.dgn ,Design Model:95882 | A_BSUK_WallsExternal_Brick 0.215 m | Wall existing | general | Existing to Remain
A-Walls-ExternalBrick | GF | Wall existing :1,SHE-01.GROUND.dgn ,Design Model:95891 | A_BSUK_WallsExternal_Brick 0.185 m | Wall existing | general | Existing to Remain
A-Walls-ExternalBrick | GF | Wall existing :1,SHE-01.GROUND.dgn ,Design Model:133297 | A_BSUK_WallsExternal_Brick 0.219 m | Wall existing | general | Existing to Remain
A-Walls-ExternalBrick | GF | Wall existing :1,SHE-01.GROUND.dgn ,Design Model:137288 | A_BSUK_WallsExternal_Brick 0.1 m | Wall existing | general | Existing to Remain
A-Walls-ExternalBrick | GF | Wall existing :1,SHE-01.GROUND.dgn ,Design Model:137299 | A_BSUK_WallsExternal_Brick 0.1 m | Wall existing | general | Existing to Remain
A-Walls-ExternalBrick | GF | Wall existing :1,SHE-01.GROUND.dgn ,Design Model:137318 | A_BSUK_WallsExternal_Brick 0.1 m | Wall existing | general | Existing to Remain
A-Walls-ExternalBrick | MF | Wall existing :2,SHE-02.MEZZANINE.dgn ,Design Model:92807 | A_BSUK_WallsExternal_Brick 0.1 m | Wall existing | general | Existing to Remain
A-Walls-ExternalBrick | MF | Wall existing :2,SHE-02.MEZZANINE.dgn ,Design Model:92816 | A_BSUK_WallsExternal_Brick 0.1 m | Wall existing | general | Existing to Remain
A-Walls-ExternalBrick | MF | Wall existing :2,SHE-02.MEZZANINE.dgn ,Design Model:92825 | A_BSUK_WallsExternal_Brick 0.1 m | Wall existing | general | Existing to Remain
A-Walls-ExternalBrick | MF | Wall existing :2,SHE-02.MEZZANINE.dgn ,Design Model:92843 | A_BSUK_WallsExternal_Brick 0.1 m | Wall existing | general | Existing to Remain
A-Walls-ExternalBrick | MF | Wall existing :2,SHE-02.MEZZANINE.dgn ,Design Model:92852 | A_BSUK_WallsExternal_Brick 0.1 m | Wall existing | general | Existing to Remain
A-Walls-ExternalBrick | MF | Wall existing :2,SHE-02.MEZZANINE.dgn ,Design Model:92861 | A_BSUK_WallsExternal_Brick 0.1 m | Wall existing | general | Existing to Remain
A-Walls-ExternalBrick | MF | Wall existing :2,SHE-02.MEZZANINE.dgn ,Design Model:92870 | A_BSUK_WallsExternal_Brick 0.1 m | Wall existing | general | Existing to Remain
A-Walls-ExternalBrick | MF | Wall existing :2,SHE-02.MEZZANINE.dgn ,Design Model:92933 | A_BSUK_WallsExternal_Brick 0.1 m | Wall existing | general | Existing to Remain
A-Walls-ExternalBrick | MF | Wall existing :2,SHE-02.MEZZANINE.dgn ,Design Model:92942 | A_BSUK_WallsExternal_Brick 0.1 m | Wall existing | general | Existing to Remain
A-Walls-ExternalBrick | MF | Wall existing :2,SHE-02.MEZZANINE.dgn ,Design Model:92951 | A_BSUK_WallsExternal_Brick 0.1 m | Wall existing | general | Existing to Remain
A-Walls-ExternalBrick | MF | Wall existing :2,SHE-02.MEZZANINE.dgn ,Design Model:92960 | A_BSUK_WallsExternal_Brick 0.1 m | Wall existing | general | Existing to Remain
A-Walls-ExternalBrick | MF | FacadeFacingBrick - infill :2,SHE-02.MEZZANINE.dgn ,Design Model:92987 | A_BSUK_WallsExternal_Brick 0.1 m | FacadeFacingBrick - infill | front elevation | New Construction
A-Walls-ExternalBrick | MF | Wall existing :2,SHE-02.MEZZANINE.dgn ,Design Model:93068 | A_BSUK_WallsExternal_Brick 0.1 m | Wall existing | general | Existing to Remain
A-Walls-ExternalBrick | MF | FacadeFacingBrick - infill :2,SHE-02.MEZZANINE.dgn ,Design Model:93077 | A_BSUK_WallsExternal_Brick 0.1 m | FacadeFacingBrick - infill | back elevation | New Construction
A-Walls-ExternalBrick | MF | FacadeFacingBrick - infill :2,SHE-02.MEZZANINE.dgn ,Design Model:93086 | A_BSUK_WallsExternal_Brick 0.1 m | FacadeFacingBrick - infill | back elevation | New Construction
A-Walls-ExternalBrick | MF | FacadeFacingBrick - infill :2,SHE-02.MEZZANINE.dgn ,Design Model:93095 | A_BSUK_WallsExternal_Brick 0.1 m | FacadeFacingBrick - infill | back elevation | New Construction
A-Walls-ExternalBrick | MF | FacadeFacingBrick - infill :2,SHE-02.MEZZANINE.dgn ,Design Model:93104 | A_BSUK_WallsExternal_Brick 0.1 m | FacadeFacingBrick - infill | back elevation | New Construction
A-Walls-ExternalBrick | MF | FacadeFacingBrick - infill :2,SHE-02.MEZZANINE.dgn ,Design Model:93113 | A_BSUK_WallsExternal_Brick 0.1 m | FacadeFacingBrick - infill | back elevation | New Construction
A-Walls-ExternalBrick | MF | Wall existing :2,SHE-02.MEZZANINE.dgn ,Design Model:93478 | A_BSUK_WallsExternal_Brick 0.1 m | Wall existing | general | Existing to Remain
A-Walls-ExternalBrick | MF | Wall existing :2,SHE-02.MEZZANINE.dgn ,Design Model:93559 | A_BSUK_WallsExternal_Brick 0.1 m | Wall existing | general | Existing to Remain
A-Walls-ExternalBrick | MF | Wall existing :2,SHE-02.MEZZANINE.dgn ,Design Model:93568 | A_BSUK_WallsExternal_Brick 0.1 m | Wall existing | general | Existing to Remain
A-Walls-ExternalBrick | MF | Wall existing :2,SHE-02.MEZZANINE.dgn ,Design Model:93577 | A_BSUK_WallsExternal_Brick 0.1 m | Wall existing | general | Existing to Remain
A-Walls-ExternalBrick | MF | Wall existing :2,SHE-02.MEZZANINE.dgn ,Design Model:93586 | A_BSUK_WallsExternal_Brick 0.1 m | Wall existing | general | Existing to Remain
A-Walls-ExternalBrick | MF | Wall existing :2,SHE-02.MEZZANINE.dgn ,Design Model:93604 | A_BSUK_WallsExternal_Brick 0.1 m | Wall existing | general | Existing to Remain
A-Walls-ExternalBrick | MF | Wall existing :2,SHE-02.MEZZANINE.dgn ,Design Model:93613 | A_BSUK_WallsExternal_Brick 0.1 m | Wall existing | general | Existing to Remain
A-Walls-ExternalBrick | MF | Wall existing :2,SHE-02.MEZZANINE.dgn ,Design Model:93622 | A_BSUK_WallsExternal_Brick 0.1 m | Wall existing | general | Existing to Remain
A-Walls-ExternalBrick | MF | Wall existing :2,SHE-02.MEZZANINE.dgn ,Design Model:93640 | A_BSUK_WallsExternal_Brick 0.1 m | Wall existing | general | Existing to Remain
A-Walls-ExternalBrick | MF | Wall existing :2,SHE-02.MEZZANINE.dgn ,Design Model:93737 | A_BSUK_WallsExternal_Brick 0.1 m | Wall existing | general | Existing to Remain
A-Walls-ExternalBrick | MF | Wall existing :2,SHE-02.MEZZANINE.dgn ,Design Model:93749 | A_BSUK_WallsExternal_Brick 0.1 m | Wall existing | general | Existing to Remain
A-Walls-ExternalBrick | MF | Wall existing :2,SHE-02.MEZZANINE.dgn ,Design Model:93768 | A_BSUK_WallsExternal_Brick 0.1 m | Wall existing | general | Existing to Remain
A-Walls-ExternalBrick | MF | Wall existing :2,SHE-02.MEZZANINE.dgn ,Design Model:93779 | A_BSUK_WallsExternal_Brick 0.1 m | Wall existing | general | Existing to Remain
A-Walls-ExternalBrick | MF | Wall existing :2,SHE-02.MEZZANINE.dgn ,Design Model:93804 | A_BSUK_WallsExternal_Brick 0.1 m | Wall existing | general | Existing to Remain
A-Walls-ExternalBrick | MF | Wall existing :2,SHE-02.MEZZANINE.dgn ,Design Model:93835 | A_BSUK_WallsExternal_Brick 0.1 m | Wall existing | general | Existing to Remain
A-Walls-ExternalBrick | MF | Wall existing :2,SHE-02.MEZZANINE.dgn ,Design Model:93844 | A_BSUK_WallsExternal_Brick 0.1 m | Wall existing | general | Existing to Remain
A-Walls-ExternalBrick | MF | Wall existing :2,SHE-02.MEZZANINE.dgn ,Design Model:93853 | A_BSUK_WallsExternal_Brick 0.1 m | Wall existing | general | Existing to Remain
A-Walls-ExternalBrick | MF | Wall existing :2,SHE-02.MEZZANINE.dgn ,Design Model:93862 | A_BSUK_WallsExternal_Brick 0.1 m | Wall existing | general | Existing to Remain
A-Walls-ExternalBrick | MF | Wall existing :2,SHE-02.MEZZANINE.dgn ,Design Model:93871 | A_BSUK_WallsExternal_Brick 0.1 m | Wall existing | general | Existing to Remain
A-Walls-ExternalBrick | MF | Wall existing :2,SHE-02.MEZZANINE.dgn ,Design Model:93907 | A_BSUK_WallsExternal_Brick 0.1 m | Wall existing | general | Existing to Remain
A-Walls-ExternalBrick | MF | Wall existing :2,SHE-02.MEZZANINE.dgn ,Design Model:93916 | A_BSUK_WallsExternal_Brick 0.1 m | Wall existing | general | Existing to Remain
A-Walls-ExternalBrick | MF | Wall existing :2,SHE-02.MEZZANINE.dgn ,Design Model:93925 | A_BSUK_WallsExternal_Brick 0.1 m | Wall existing | general | Existing to Remain
A-Walls-ExternalBrick | MF | Wall existing :2,SHE-02.MEZZANINE.dgn ,Design Model:94127 | A_BSUK_WallsExternal_Brick 0.1 m | Wall existing | general | Existing to Remain
A-Walls-ExternalBrick | MF | Wall existing :2,SHE-02.MEZZANINE.dgn ,Design Model:94136 | A_BSUK_WallsExternal_Brick 0.1 m | Wall existing | general | Existing to Remain
A-Walls-ExternalBrick | MF | Wall existing :2,SHE-02.MEZZANINE.dgn ,Design Model:94174 | A_BSUK_WallsExternal_Brick 0.1 m | Wall existing | general | Existing to Remain
A-Walls-ExternalBrick | MF | Wall existing :2,SHE-02.MEZZANINE.dgn ,Design Model:94221 | A_BSUK_WallsExternal_Brick 0.1 m | Wall existing | general | Existing to Remain
A-Walls-ExternalBrick | MF | Wall existing :2,SHE-02.MEZZANINE.dgn ,Design Model:94230 | A_BSUK_WallsExternal_Brick 0.1 m | Wall existing | general | Existing to Remain
A-Walls-ExternalBrick | MF | Wall existing :2,SHE-02.MEZZANINE.dgn ,Design Model:94248 | A_BSUK_WallsExternal_Brick 0.1 m | Wall existing | general | Existing to Remain
A-Walls-ExternalBrick | MF | Wall existing :2,SHE-02.MEZZANINE.dgn ,Design Model:94257 | A_BSUK_WallsExternal_Brick 0.1 m | Wall existing | general | Existing to Remain
A-Walls-ExternalBrick | MF | Wall existing :2,SHE-02.MEZZANINE.dgn ,Design Model:94302 | A_BSUK_WallsExternal_Brick 0.1 m | Wall existing | general | Existing to Remain
A-Walls-ExternalBrick | MF | Wall existing :2,SHE-02.MEZZANINE.dgn ,Design Model:116685 | A_BSUK_WallsExternal_Brick 0.1 m | Wall existing | general | Existing to Remain
A-Walls-ExternalBrick | MF | Wall existing :2,SHE-02.MEZZANINE.dgn ,Design Model:116959 | A_BSUK_WallsExternal_Brick 0.1 m | Wall existing | general | Existing to Remain
A-Walls-ExternalBrick | MF | Wall existing :2,SHE-02.MEZZANINE.dgn ,Design Model:116968 | A_BSUK_WallsExternal_Brick 0.1 m | Wall existing | general | Existing to Remain
A-Walls-ExternalBrick | MF | Wall existing :2,SHE-02.MEZZANINE.dgn ,Design Model:116977 | A_BSUK_WallsExternal_Brick 0.1 m | Wall existing | general | Existing to Remain
A-Walls-ExternalBrick | MF | Wall existing :2,SHE-02.MEZZANINE.dgn ,Design Model:116986 | A_BSUK_WallsExternal_Brick 0.1 m | Wall existing | general | Existing to Remain
A-Walls-ExternalBrick | MF | Wall existing :2,SHE-02.MEZZANINE.dgn ,Design Model:117599 | A_BSUK_WallsExternal_Brick 0.1 m | Wall existing | general | Existing to Remain
A-Walls-ExternalBrick | MF | Wall existing :2,SHE-02.MEZZANINE.dgn ,Design Model:130076 | A_BSUK_WallsExternal_Brick 0.1 m | Wall existing | general | Existing to Remain
A-Walls-ExternalBrick | 1F | FacadeFacingBrick :3,SHE-09.FACADE.dgn ,Design Model:104882 | A_BSUK_WallsExternal_Brick 0.1 m | FacadeFacingBrick | front elevation - existing | Existing to Remain | Pset_WallCommon - AcousticRating: Rw 52dB Rw+Ctr 48dB; Acoustical Parameters - Acoustic Rating (STC): Rw 52dB Rw+Ctr 48dB
A-Walls-ExternalBrick | 1F | FacadeFacingBrick :3,SHE-09.FACADE.dgn ,Design Model:104955 | A_BSUK_WallsExternal_Brick 0.1 m | FacadeFacingBrick | side elevation - existing | Existing to Remain | Pset_WallCommon - AcousticRating: Rw 52dB Rw+Ctr 48dB; Acoustical Parameters - Acoustic Rating (STC): Rw 52dB Rw+Ctr 48dB
A-Walls-ExternalBrick | 1F | FacadeFacingBrick :3,SHE-09.FACADE.dgn ,Design Model:105002 | A_BSUK_WallsExternal_Brick 0.1 m | FacadeFacingBrick | back elevation - existing | Existing to Remain | Pset_WallCommon - AcousticRating: Rw 52dB Rw+Ctr 48dB; Acoustical Parameters - Acoustic Rating (STC): Rw 52dB Rw+Ctr 48dB
A-Walls-ExternalBrick | 1F | FacadeFacingBrick :3,SHE-09.FACADE.dgn ,Design Model:105053 | A_BSUK_WallsExternal_Brick 0.1 m | FacadeFacingBrick | back elevation - existing | Existing to Remain | Pset_WallCommon - AcousticRating: Rw 52dB Rw+Ctr 48dB; Acoustical Parameters - Acoustic Rating (STC): Rw 52dB Rw+Ctr 48dB
A-Walls-ExternalBrick | 1F | FacadeFacingBrick :3,SHE-09.FACADE.dgn ,Design Model:105096 | A_BSUK_WallsExternal_Brick 0.1 m | FacadeFacingBrick | side elevation - existing | Existing to Remain | Pset_WallCommon - AcousticRating: Rw 52dB Rw+Ctr 48dB; Acoustical Parameters - Acoustic Rating (STC): Rw 52dB Rw+Ctr 48dB

# IfcWallStandardCase: A-Walls-Internal (64)
Type - Wall Parameters - Type: Wall; Compound Wall Assembly: no
Type - Thermal Transmittance - Is External: no; Is Below Grade: no
Type - Space Bounding - Is Space Bounding: yes
Type - Materials - Part Definition: A-Walls::A_BSUK_WallsInternal
Type - LEED Parameters - LEED | Pre-consumer Recycled (%): 0; LEED | Regional Material: no; LEED | Post-consumer Recycled (%): 0
Type - Fire Resistance - Fire | IsCombustible: no; Fire | Compartmentation: no
Type - Discipline - Discipline: Architectural
Type - Classification - Uniclass2015: EF_25_10
Pset_WallCommon - Combustible: no; Compartmentation: no; IsExternal: no; LoadBearing: no
Name | In | Description | Material | ID | Description | ID | Notes | Phase
A-Walls-Internal | GF | Wall existing :1,SHE-01.GROUND.dgn,Design Model:96115 | A_BSUK_WallsInternal 0.405 m | Wall existing | general | Existing to Remain
A-Walls-Internal | GF | Wall existing :1,SHE-01.GROUND.dgn,Design Model:96124 | A_BSUK_WallsInternal 0.66 m | Wall existing | general | Existing to Remain
A-Walls-Internal | GF | Wall existing :1,SHE-01.GROUND.dgn,Design Model:96196 | A_BSUK_WallsInternal 0.073 m | Wall existing | general | Existing to Remain
A-Walls-Internal | GF | Wall existing :1,SHE-01.GROUND.dgn,Design Model:96205 | A_BSUK_WallsInternal 0.073 m | Wall existing | general | Existing to Remain
A-Walls-Internal | GF | Wall existing :1,SHE-01.GROUND.dgn,Design Model:96239 | A_BSUK_WallsInternal 0.263 m | Wall existing | general | Existing to Remain
A-Walls-Internal | GF | Wall existing :1,SHE-01.GROUND.dgn,Design Model:96283 | A_BSUK_WallsInternal 0.107 m | Wall existing | general | Existing to Remain
A-Walls-Internal | GF | Wall existing :1,SHE-01.GROUND.dgn,Design Model:96294 | A_BSUK_WallsInternal 0.07 m | Wall existing | general | Existing to Remain
A-Walls-Internal | GF | Wall existing :1,SHE-01.GROUND.dgn,Design Model:96313 | A_BSUK_WallsInternal 0.103 m | Wall existing | general | Existing to Remain
A-Walls-Internal | GF | Wall existing :1,SHE-01.GROUND.dgn,Design Model:96332 | A_BSUK_WallsInternal 0.103 m | Wall existing | general | Existing to Remain
A-Walls-Internal | GF | Wall existing :1,SHE-01.GROUND.dgn,Design Model:96341 | A_BSUK_WallsInternal 0.711 m | Wall existing | general | Existing to Remain
A-Walls-Internal | GF | Wall existing :1,SHE-01.GROUND.dgn,Design Model:96395 | A_BSUK_WallsInternal 0.15 m | Wall existing | general | Existing to Remain
A-Walls-Internal | GF | Wall existing :1,SHE-01.GROUND.dgn,Design Model:96404 | A_BSUK_WallsInternal 0.15 m | Wall existing | general | Existing to Remain
A-Walls-Internal | GF | Wall existing :1,SHE-01.GROUND.dgn,Design Model:96711 | A_BSUK_WallsInternal 0.073 m | Wall existing | general | Existing to Remain
A-Walls-Internal | MF | Wall existing :2,SHE-02.MEZZANINE.dgn,Design Model:93934 | A_BSUK_WallsInternal 0.13 m | Wall existing | general | Existing to Remain
A-Walls-Internal | MF | Wall existing :2,SHE-02.MEZZANINE.dgn,Design Model:93946 | A_BSUK_WallsInternal 0.108 m | Wall existing | general | Existing to Remain
A-Walls-Internal | MF | Wall existing :2,SHE-02.MEZZANINE.dgn,Design Model:93961 | A_BSUK_WallsInternal 0.12 m | Wall existing | general | Existing to Remain
A-Walls-Internal | MF | Wall existing :2,SHE-02.MEZZANINE.dgn,Design Model:93989 | A_BSUK_WallsInternal 0.113 m | Wall existing | general | Existing to Remain
A-Walls-Internal | MF | Wall existing :2,SHE-02.MEZZANINE.dgn,Design Model:142907 | A_BSUK_WallsInternal 0.113 m | Wall existing | general | Existing to Remain
7C | 1F | SFSWall fire lining :7,SHE-06.FOURTH.dgn,Design Model:101110 | A_BSUK_WallsInternal 0.025 m | SFSWall fire lining | fire board - internal mansard roof finish | New Construction | Pset_WallCommon - FireRating: F60; Identification - ID | Number: 7C; Fire Resistance - Fire | Rating: F60
7C | 1F | SFSWall fire lining :7,SHE-06.FOURTH.dgn,Design Model:101137 | A_BSUK_WallsInternal 0.025 m | SFSWall fire lining | fire board - internal mansard roof finish | New Construction | Pset_WallCommon - FireRating: F60; Identification - ID | Number: 7C; Fire Resistance - Fire | Rating: F60
7C | 1F | SFSWall fire lining :7,SHE-06.FOURTH.dgn,Design Model:101146 | A_BSUK_WallsInternal 0.025 m | SFSWall fire lining | fire board - internal mansard roof finish | New Construction | Pset_WallCommon - FireRating: F60; Identification - ID | Number: 7C; Fire Resistance - Fire | Rating: F60
7C | 1F | SFSWall fire lining :7,SHE-06.FOURTH.dgn,Design Model:101508 | A_BSUK_WallsInternal 0.025 m | SFSWall fire lining | fire board - internal mansard roof finish | New Construction | Pset_WallCommon - FireRating: F60; Identification - ID | Number: 7C; Fire Resistance - Fire | Rating: F60
7C | 1F | SFSWall fire lining :7,SHE-06.FOURTH.dgn,Design Model:101553 | A_BSUK_WallsInternal 0.025 m | SFSWall fire lining | fire board - internal mansard roof finish | New Construction | Pset_WallCommon - FireRating: F60; Identification - ID | Number: 7C; Fire Resistance - Fire | Rating: F60
A-Walls-Internal | 1F | WoodPanel :7,SHE-06.FOURTH.dgn,Design Model:103246 | A_BSUK_WallsInternal 0.05 m | WoodPanel | built in wardrobes | New Construction
A-Walls-Internal | 1F | WoodPanel :7,SHE-06.FOURTH.dgn,Design Model:103255 | A_BSUK_WallsInternal 0.05 m | WoodPanel | built in wardrobes | New Construction
A-Walls-Internal | 1F | WoodPanel :7,SHE-06.FOURTH.dgn,Design Model:103264 | A_BSUK_WallsInternal 0.05 m | WoodPanel | built in wardrobes | New Construction
A-Walls-Internal | 1F | WoodPanel :7,SHE-06.FOURTH.dgn,Design Model:103327 | A_BSUK_WallsInternal 0.05 m | WoodPanel | built in wardrobes | New Construction
A-Walls-Internal | 1F | WoodPanel :7,SHE-06.FOURTH.dgn,Design Model:103336 | A_BSUK_WallsInternal 0.05 m | WoodPanel | built in wardrobes | New Construction
A-Walls-Internal | 1F | WoodPanel :7,SHE-06.FOURTH.dgn,Design Model:103345 | A_BSUK_WallsInternal 0.05 m | WoodPanel | built in wardrobes | New Construction
A-Walls-Internal | 1F | WoodPanel :7,SHE-06.FOURTH.dgn,Design Model:103354 | A_BSUK_WallsInternal 0.05 m | WoodPanel | built in wardrobes | New Construction
A-Walls-Internal | 1F | WoodPanel :7,SHE-06.FOURTH.dgn,Design Model:103363 | A_BSUK_WallsInternal 0.05 m | WoodPanel | built in wardrobes | New Construction
A-Walls-Internal | 1F | WoodPanel :7,SHE-06.FOURTH.dgn,Design Model:103372 | A_BSUK_WallsInternal 0.05 m | WoodPanel | built in wardrobes | New Construction
A-Walls-Internal | 1F | WoodPanel :7,SHE-06.FOURTH.dgn,Design Model:103381 | A_BSUK_WallsInternal 0.05 m | WoodPanel | built in wardrobes | New Construction
A-Walls-Internal | 1F | WoodPanel :7,SHE-06.FOURTH.dgn,Design Model:103390 | A_BSUK_WallsInternal 0.05 m | WoodPanel | built in wardrobes | New Construction
A-Walls-Internal | 1F | WoodPanel :7,SHE-06.FOURTH.dgn,Design Model:103399 | A_BSUK_WallsInternal 0.05 m | WoodPanel | built in wardrobes | New Construction
A-Walls-Internal | 1F | WoodPanel :7,SHE-06.FOURTH.dgn,Design Model:103408 | A_BSUK_WallsInternal 0.05 m | WoodPanel | built in wardrobes | New Construction
A-Walls-Internal | 1F | WoodPanel :7,SHE-06.FOURTH.dgn,Design Model:103426 | A_BSUK_WallsInternal 0.05 m | WoodPanel | built in wardrobes | New Construction
A-Walls-Internal | 1F | WoodPanel :7,SHE-06.FOURTH.dgn,Design Model:103435 | A_BSUK_WallsInternal 0.05 m | WoodPanel | built in wardrobes | New Construction
A-Walls-Internal | 1F | WoodPanel :7,SHE-06.FOURTH.dgn,Design Model:103444 | A_BSUK_WallsInternal 0.05 m | WoodPanel | built in wardrobes | New Construction
A-Walls-Internal | 1F | WoodPanel :7,SHE-06.FOURTH.dgn,Design Model:103453 | A_BSUK_WallsInternal 0.05 m | WoodPanel | built in wardrobes | New Construction
A-Walls-Internal | 1F | WoodPanel :7,SHE-06.FOURTH.dgn,Design Model:103462 | A_BSUK_WallsInternal 0.05 m | WoodPanel | built in wardrobes | New Construction
A-Walls-Internal | 1F | WoodPanel :7,SHE-06.FOURTH.dgn,Design Model:103480 | A_BSUK_WallsInternal 0.05 m | WoodPanel | built in wardrobes | New Construction
A-Walls-Internal | 1F | WoodPanel :7,SHE-06.FOURTH.dgn,Design Model:103489 | A_BSUK_WallsInternal 0.05 m | WoodPanel | built in wardrobes | New Construction
A-Walls-Internal | 1F | WoodPanel :7,SHE-06.FOURTH.dgn,Design Model:103498 | A_BSUK_WallsInternal 0.05 m | WoodPanel | built in wardrobes | New Construction
A-Walls-Internal | 1F | WoodPanel :7,SHE-06.FOURTH.dgn,Design Model:103507 | A_BSUK_WallsInternal 0.05 m | WoodPanel | built in wardrobes | New Construction
A-Walls-Internal | 1F | WoodPanel :7,SHE-06.FOURTH.dgn,Design Model:103516 | A_BSUK_WallsInternal 0.05 m | WoodPanel | built in wardrobes | New Construction
A-Walls-Internal | 1F | WoodPanel :7,SHE-06.FOURTH.dgn,Design Model:103525 | A_BSUK_WallsInternal 0.05 m | WoodPanel | built in wardrobes | New Construction
A-Walls-Internal | 1F | WoodPanel :7,SHE-06.FOURTH.dgn,Design Model:103534 | A_BSUK_WallsInternal 0.05 m | WoodPanel | built in wardrobes | New Construction
A-Walls-Internal | 1F | WoodPanel :7,SHE-06.FOURTH.dgn,Design Model:238252 | A_BSUK_WallsInternal 0.05 m | WoodPanel | built in wardrobes | New Construction
A-Walls-Internal | 1F | WoodPanel :7,SHE-06.FOURTH.dgn,Design Model:238261 | A_BSUK_WallsInternal 0.05 m | WoodPanel | built in wardrobes | New Construction
A-Walls-Internal | 1F | WoodPanel :7,SHE-06.FOURTH.dgn,Design Model:238270 | A_BSUK_WallsInternal 0.05 m | WoodPanel | built in wardrobes | New Construction
7C | 1F | SFSWall fire lining :7,SHE-06.FOURTH.dgn,Design Model:469951 | A_BSUK_WallsInternal 0.015 m | SFSWall fire lining | fire board - internal mansard roof finish | New Construction | Pset_WallCommon - FireRating: F60; Identification - ID | Number: 7C; Fire Resistance - Fire | Rating: F60
7C | 1F | SFSWall fire lining :7,SHE-06.FOURTH.dgn,Design Model:104228 | A_BSUK_WallsInternal 0.015 m | SFSWall fire lining | fire board - internal mansard roof finish | New Construction | Pset_WallCommon - FireRating: F60; Identification - ID | Number: 7C; Fire Resistance - Fire | Rating: F60
7C | 1F | SFSWall fire lining :7,SHE-06.FOURTH.dgn,Design Model:104266 | A_BSUK_WallsInternal 0.015 m | SFSWall fire lining | fire board - internal mansard roof finish | New Construction | Pset_WallCommon - FireRating: F60; Identification - ID | Number: 7C; Fire Resistance - Fire | Rating: F60
7C | 1F | SFSWall fire lining :7,SHE-06.FOURTH.dgn,Design Model:470048 | A_BSUK_WallsInternal 0.015 m | SFSWall fire lining | fire board - internal mansard roof finish | New Construction | Pset_WallCommon - FireRating: F60; Identification - ID | Number: 7C; Fire Resistance - Fire | Rating: F60
7C | 1F | SFSWall fire lining :7,SHE-06.FOURTH.dgn,Design Model:470057 | A_BSUK_WallsInternal 0.015 m | SFSWall fire lining | fire board - internal mansard roof finish | New Construction | Pset_WallCommon - FireRating: F60; Identification - ID | Number: 7C; Fire Resistance - Fire | Rating: F60
7C | 1F | SFSWall fire lining :7,SHE-06.FOURTH.dgn,Design Model:470066 | A_BSUK_WallsInternal 0.015 m | SFSWall fire lining | fire board - internal mansard roof finish | New Construction | Pset_WallCommon - FireRating: F60; Identification - ID | Number: 7C; Fire Resistance - Fire | Rating: F60
7C | 1F | SFSWall fire lining :7,SHE-06.FOURTH.dgn,Design Model:470075 | A_BSUK_WallsInternal 0.015 m | SFSWall fire lining | fire board - internal mansard roof finish | New Construction | Pset_WallCommon - FireRating: F60; Identification - ID | Number: 7C; Fire Resistance - Fire | Rating: F60
7C | 1F | SFSWall fire lining :7,SHE-06.FOURTH.dgn,Design Model:470084 | A_BSUK_WallsInternal 0.015 m | SFSWall fire lining | fire board - internal mansard roof finish | New Construction | Pset_WallCommon - FireRating: F60; Identification - ID | Number: 7C; Fire Resistance - Fire | Rating: F60
A-Walls-Internal | 1F | StairFireWall :7,SHE-06.FOURTH.dgn,Design Model:483592 | A_BSUK_WallsInternal 0.015 m | StairFireWall | lift wall enforcement | New Construction | Pset_WallCommon - FireRating: F120; Fire Resistance - Fire | Rating: F120; Wall Parameters - Cavity: Insulation: Fire
A-Walls-Internal | 1F | StairFireWall :7,SHE-06.FOURTH.dgn,Design Model:483601 | A_BSUK_WallsInternal 0.015 m | StairFireWall | lift wall enforcement | New Construction | Pset_WallCommon - FireRating: F120; Fire Resistance - Fire | Rating: F120; Wall Parameters - Cavity: Insulation: Fire
A-Walls-Internal | 5F | WoodPanel :8,SHE-07.FIFTH.dgn,Design Model:94365 | A_BSUK_WallsInternal 0.05 m | WoodPanel | built in wardrobes | New Construction
A-Walls-Internal | 5F | WoodPanel :8,SHE-07.FIFTH.dgn,Design Model:94374 | A_BSUK_WallsInternal 0.05 m | WoodPanel | built in wardrobes | New Construction
A-Walls-Internal | 5F | WoodPanel :8,SHE-07.FIFTH.dgn,Design Model:94383 | A_BSUK_WallsInternal 0.05 m | WoodPanel | built in wardrobes | New Construction

# IfcWallStandardCase: A-Walls-InternalBlock (7)
Type - Wall Parameters - Type: Wall; Compound Wall Assembly: no
Type - Thermal Transmittance - Is External: no; Is Below Grade: no
Type - Structural Usage - Structural | Material: Blockwork
Type - Space Bounding - Is Space Bounding: yes
Type - Materials - Part Definition: A-Walls::A_BSUK_WallsInternal_Block
Type - LEED Parameters - LEED | Pre-consumer Recycled (%): 0; LEED | Regional Material: no; LEED | Post-consumer Recycled (%): 0
Type - Fire Resistance - Fire | Compartmentation: no
Type - Discipline - Discipline: Architectural
Type - Classification - Uniclass2015: Pr_20_93_52_01
Pset_WallCommon - Combustible: no; Compartmentation: no; IsExternal: no; LoadBearing: no
Identification - ID | Description: Wall existing; ID | Notes: general
Fire Resistance - Fire | IsCombustible: no
Construction Phase - Phase: Existing to Remain
Name | In | Description | Material
A-Walls-InternalBlock | GF | Wall existing :1,SHE-01.GROUND.dgn ,Design Model:96078 | A_BSUK_WallsInternal_Block 0.18 m
A-Walls-InternalBlock | GF | Wall existing :1,SHE-01.GROUND.dgn ,Design Model:96151 | A_BSUK_WallsInternal_Block 0.1938 m
A-Walls-InternalBlock | GF | Wall existing :1,SHE-01.GROUND.dgn ,Design Model:96163 | A_BSUK_WallsInternal_Block 0.264 m
A-Walls-InternalBlock | GF | Wall existing :1,SHE-01.GROUND.dgn ,Design Model:96448 | A_BSUK_WallsInternal_Block 0.131 m
A-Walls-InternalBlock | GF | Wall existing :1,SHE-01.GROUND.dgn ,Design Model:178785 | A_BSUK_WallsInternal_Block 0.131 m
A-Walls-InternalBlock | MF | Wall existing :2,SHE-02.MEZZANINE.dgn ,Design Model:93268 | A_BSUK_WallsInternal_Block 0.232195 m
A-Walls-InternalBlock | MF | Wall existing :2,SHE-02.MEZZANINE.dgn ,Design Model:93277 | A_BSUK_WallsInternal_Block 0.264 m

# IfcWallStandardCase: SHE_A-Walls_Type03c_Firewall_F120_100mm (5)
Type - Description: SHE_A-Walls_Type03c_Firewall_F120_100mm
Type - Wall Parameters - Type: Wall; Compound Wall Assembly: yes
Type - Thermal Transmittance - Is External: no; Is Below Grade: no
Type - Space Bounding - Is Space Bounding: yes
Type - Materials - Part Definition: A-CompoundWalls::SHE_A-Walls_Type03c_Firewall_F120_100mm
Type - LEED Parameters - LEED | Pre-consumer Recycled (%): 0; LEED | Regional Material: no; LEED | Post-consumer Recycled (%): 0
Type - Identification - ID | Type ID: A206067A (EN); ID | Description: SHE_A-Walls_Type03c_Firewall_F120_100mm; ID | Notes: https://www.british-gypsu m.com/Specification/White-Book-Specification-Selector/internal-partitions-walls/gypwall-single-frame/a206067a-en
Type - Fire Resistance - Fire | Rating: F120; Fire | IsCombustible: no; Fire | Compartmentation: no
Type - Discipline - Discipline: Architectural
Type - Classification - Uniclass2015: EF_25_10
Type - Acoustical Parameters - Acoustic Rating (STC): 42 (Rw)
Pset_WallCommon - Combustible: no; Compartmentation: no; FireRating: F120; IsExternal: no; LoadBearing: no
Identification - ID | Number: 3C; ID | Description: StairFireWall; ID | Keynote: https://www.british-gyp sum.com/Specification/White-Book-Specification-Selector/internal-partitions-walls/gypwall-single-frame/a206067a-en; ID | Notes: SHE_A-Walls_Type03c_Firewall_F120_100mm
Construction Phase - Phase: New Construction
Name | In | Description | Material | AcousticRating
3C | 1F | A206067A (EN ) - StairFireWall :4,SHE-03.FIRST.dgn,Design Model:349110 | A_BSUK_Walls_Timber 0.015 m, A_BSUK_WallInternal_Finishes_Plasterboard 0.013 m, A_BSUK_WallInternal_Finishes_Plasterboard 0.012 m, Air Cavity 0.05 m, A_BSUK_WallInternal_Finishes_Plasterboard 0.012 m, A_BSUK_WallInternal_Finishes_Plasterboard 0.013 m | 42 (Rw)
3C | 3F | A206067A (EN ) - StairFireWall :6,SHE-05.THIRD.dgn,Design Model:401692 | A_BSUK_Walls_Timber 0.015 m, A_BSUK_WallInternal_Finishes_Plasterboard 0.013 m, A_BSUK_WallInternal_Finishes_Plasterboard 0.012 m, Air Cavity 0.05 m, A_BSUK_WallInternal_Finishes_Plasterboard 0.012 m, A_BSUK_WallInternal_Finishes_Plasterboard 0.013 m | 42 (Rw)
3C | 1F | A206067A (EN ) - StairFireWall :7,SHE-06.FOURTH.dgn,Design Model:396553 | A_BSUK_Walls_Timber 0.015 m, A_BSUK_WallInternal_Finishes_Plasterboard 0.013 m, A_BSUK_WallInternal_Finishes_Plasterboard 0.012 m, Air Cavity 0.05 m, A_BSUK_WallInternal_Finishes_Plasterboard 0.012 m, A_BSUK_WallInternal_Finishes_Plasterboard 0.013 m | 42 (Rw)
3C | 1F | A206067A (EN ) - StairFireWall :7,SHE-06.FOURTH.dgn,Design Model:451300 | A_BSUK_WallInternal_Finishes_Plasterboard 0.013 m, A_BSUK_WallInternal_Finishes_Plasterboard 0.012 m, Air Cavity 0.05 m, A_BSUK_WallInternal_Finishes_Plasterboard 0.012 m, A_BSUK_WallInternal_Finishes_Plasterboard 0.013 m, A_BSUK_Walls_Timber 0.015 m | 58 (req. 55) | Acoustical Parameters - Acoustic Rating (STC): 58 (req. 55)
3C | 2F | A206067A (EN ) - StairFireWall :18,SHE-04.SECOND.dgn,Design Model:356913 | A_BSUK_Walls_Timber 0.015 m, A_BSUK_WallInternal_Finishes_Plasterboard 0.013 m, A_BSUK_WallInternal_Finishes_Plasterboard 0.012 m, Air Cavity 0.05 m, A_BSUK_WallInternal_Finishes_Plasterboard 0.012 m, A_BSUK_WallInternal_Finishes_Plasterboard 0.013 m | 42 (Rw)

# IfcWallStandardCase: SHE_A-Walls_Type04c_RiserWall_102mm_tall (9)
Type - Description: SHE_A-Walls_Type04c_RiserWall_102mm_tall
Type - Wall Parameters - Type: Wall; Compound Wall Assembly: yes
Type - Thermal Transmittance - Is External: no; Is Below Grade: no
Type - Space Bounding - Is Space Bounding: yes
Type - Materials - Part Definition: A-CompoundWalls::SHE_A-Walls_Type04c_RiserWall_102mm_tall
Type - LEED Parameters - LEED | Pre-consumer Recycled (%): 0; LEED | Regional Material: no; LEED | Post-consumer Recycled (%): 0
Type - Identification - ID | Type ID: A206078 (EN); ID | Description: SHE_A-Walls_Type04c_RiserWall_102mm_tall; ID | Notes: https://www.british-gypsu m.com/Specification/White-Book-Specification-Selector/internal-partitions-walls/gypwall-single-frame/a206078-en
Type - Fire Resistance - Fire | Rating: F60; Fire | IsCombustible: no; Fire | Compartmentation: no
Type - Discipline - Discipline: Architectural
Type - Construction Phase - Phase: New Construction
Type - Classification - Uniclass2015: EF_25_10
Type - Acoustical Parameters - Acoustic Rating (STC): 37 (min. tbc )
Material: A_BSUK_WallInternal_Finishes_Plasterboard 0.015 m, Air Cavity 0.072 m, A_BSUK_WallInternal_Finishes_Plasterboard 0.015 m, A_BSUK_Walls_Timber 0.015 m
Pset_WallCommon - AcousticRating: 37 (req. tbc); Combustible: no; Compartmentation: no; FireRating: F60; IsExternal: no; LoadBearing: no
Identification - ID | Number: 4C; ID | Description: RiserWall; ID | Keynote: https://www.british-gyp sum.com/Specification/White-Book-Specification-Selector/internal-partitions-walls/gypwall-single-frame/a206078-en; ID | Notes: SHE_A-Walls_Type04c_RiserWall_102mm_tall
Acoustical Parameters - Acoustic Rating (STC): 37 (req. tbc )
Name | In | Description
4C | 1F | A206078 (EN ) - RiserWall :4,SHE-03.FIRST.dgn,Design Model:162958
4C | 1F | A206078 (EN ) - RiserWall :4,SHE-03.FIRST.dgn,Design Model:162987
4C | 1F | A206078 (EN ) - RiserWall :4,SHE-03.FIRST.dgn,Design Model:163015
4C | 3F | A206078 (EN ) - RiserWall :6,SHE-05.THIRD.dgn,Design Model:162958
4C | 3F | A206078 (EN ) - RiserWall :6,SHE-05.THIRD.dgn,Design Model:162987
4C | 3F | A206078 (EN ) - RiserWall :6,SHE-05.THIRD.dgn,Design Model:163015
4C | 2F | A206078 (EN ) - RiserWall :18,SHE-04.SECOND.dgn,Design Model:162958
4C | 2F | A206078 (EN ) - RiserWall :18,SHE-04.SECOND.dgn,Design Model:162987
4C | 2F | A206078 (EN ) - RiserWall :18,SHE-04.SECOND.dgn,Design Model:163015

# IfcWallStandardCase: SHE_A-Walls_Type05c_PreWallShell_65mm (133)
Type - Description: SHE_A-Walls_Type05c_PreWallShell_65mm
Type - Wall Parameters - Type: Wall; Compound Wall Assembly: yes
Type - Thermal Transmittance - Is External: no; Is Below Grade: no
Type - Space Bounding - Is Space Bounding: yes
Type - Materials - Part Definition: A-CompoundWalls::SHE_A-Walls_Type05c_PreWallShell_65mm
Type - LEED Parameters - LEED | Pre-consumer Recycled (%): 0; LEED | Regional Material: no; LEED | Post-consumer Recycled (%): 0
Type - Identification - ID | Description: SHE_A-Walls_Type05c_PreWallShell_65mm
Type - Fire Resistance - Fire | IsCombustible: no; Fire | Compartmentation: no
Type - Discipline - Discipline: Architectural
Type - Construction Phase - Phase: New Construction
Type - Classification - Uniclass2015: EF_25_10
Pset_WallCommon - Combustible: no; Compartmentation: no; IsExternal: no; LoadBearing: no
Identification - ID | Number: 5C; ID | Description: PreShellWall; ID | Notes: SHE_A-Walls_Type05c_PreWallShell_65mm
Name | In | Description | Material
5C | GF | PreShellWall :1 ,SHE-01.GROUND.dgn,Design Model:155310 | A_BSUK_Walls_Timber 0.015 m, A_BSUK_OpeningsClearance 0.05 m
5C | GF | PreShellWall :1 ,SHE-01.GROUND.dgn,Design Model:155425 | A_BSUK_Walls_Timber 0.015 m, A_BSUK_OpeningsClearance 0.05 m
5C | GF | PreShellWall :1 ,SHE-01.GROUND.dgn,Design Model:155449 | A_BSUK_Walls_Timber 0.015 m, A_BSUK_OpeningsClearance 0.05 m
5C | GF | PreShellWall :1 ,SHE-01.GROUND.dgn,Design Model:214056 | A_BSUK_OpeningsClearance 0.05 m, A_BSUK_Walls_Timber 0.015 m
5C | MF | PreShellWall :2 ,SHE-02.MEZZANINE.dgn,Design Model:134079 | A_BSUK_OpeningsClearance 0.05 m, A_BSUK_Walls_Timber 0.015 m
5C | MF | PreShellWall :2 ,SHE-02.MEZZANINE.dgn,Design Model:134098 | A_BSUK_OpeningsClearance 0.05 m, A_BSUK_Walls_Timber 0.015 m
5C | MF | PreShellWall :2 ,SHE-02.MEZZANINE.dgn,Design Model:134165 | A_BSUK_OpeningsClearance 0.05 m, A_BSUK_Walls_Timber 0.015 m
5C | MF | PreShellWall :2 ,SHE-02.MEZZANINE.dgn,Design Model:134184 | A_BSUK_OpeningsClearance 0.05 m, A_BSUK_Walls_Timber 0.015 m
5C | MF | PreShellWall :2 ,SHE-02.MEZZANINE.dgn,Design Model:134216 | A_BSUK_OpeningsClearance 0.05 m, A_BSUK_Walls_Timber 0.015 m
5C | MF | PreShellWall :2 ,SHE-02.MEZZANINE.dgn,Design Model:159495 | A_BSUK_OpeningsClearance 0.05 m, A_BSUK_Walls_Timber 0.015 m
5C | 1F | PreShellWall :4 ,SHE-03.FIRST.dgn,Design Model:143085 | A_BSUK_OpeningsClearance 0.05 m, A_BSUK_Walls_Timber 0.015 m
5C | 1F | PreShellWall :4 ,SHE-03.FIRST.dgn,Design Model:143086 | A_BSUK_OpeningsClearance 0.05 m, A_BSUK_Walls_Timber 0.015 m
5C | 1F | PreShellWall :4 ,SHE-03.FIRST.dgn,Design Model:143088 | A_BSUK_OpeningsClearance 0.05 m, A_BSUK_Walls_Timber 0.015 m
5C | 1F | PreShellWall :4 ,SHE-03.FIRST.dgn,Design Model:143097 | A_BSUK_Walls_Timber 0.015 m, A_BSUK_OpeningsClearance 0.05 m
5C | 1F | PreShellWall :4 ,SHE-03.FIRST.dgn,Design Model:143098 | A_BSUK_Walls_Timber 0.015 m, A_BSUK_OpeningsClearance 0.05 m
5C | 1F | PreShellWall :4 ,SHE-03.FIRST.dgn,Design Model:143322 | A_BSUK_Walls_Timber 0.015 m, A_BSUK_OpeningsClearance 0.05 m
5C | 1F | PreShellWall :4 ,SHE-03.FIRST.dgn,Design Model:143323 | A_BSUK_Walls_Timber 0.015 m, A_BSUK_OpeningsClearance 0.05 m
5C | 1F | PreShellWall :4 ,SHE-03.FIRST.dgn,Design Model:143324 | A_BSUK_Walls_Timber 0.015 m, A_BSUK_OpeningsClearance 0.05 m
5C | 1F | PreShellWall :4 ,SHE-03.FIRST.dgn,Design Model:176874 | A_BSUK_Walls_Timber 0.015 m, A_BSUK_OpeningsClearance 0.05 m
5C | 1F | PreShellWall :4 ,SHE-03.FIRST.dgn,Design Model:176991 | A_BSUK_OpeningsClearance 0.05 m, A_BSUK_Walls_Timber 0.015 m
5C | 1F | PreShellWall :4 ,SHE-03.FIRST.dgn,Design Model:228570 | A_BSUK_OpeningsClearance 0.05 m, A_BSUK_Walls_Timber 0.015 m
5C | 1F | PreShellWall :4 ,SHE-03.FIRST.dgn,Design Model:228571 | A_BSUK_OpeningsClearance 0.05 m, A_BSUK_Walls_Timber 0.015 m
5C | 1F | PreShellWall :4 ,SHE-03.FIRST.dgn,Design Model:229415 | A_BSUK_Walls_Timber 0.015 m, A_BSUK_OpeningsClearance 0.05 m
5C | 1F | PreShellWall :4 ,SHE-03.FIRST.dgn,Design Model:272034 | A_BSUK_Walls_Timber 0.015 m, A_BSUK_OpeningsClearance 0.05 m
5C | 1F | PreShellWall :4 ,SHE-03.FIRST.dgn,Design Model:277751 | A_BSUK_OpeningsClearance 0.05 m, A_BSUK_Walls_Timber 0.015 m
5C | 1F | PreShellWall :4 ,SHE-03.FIRST.dgn,Design Model:277793 | A_BSUK_OpeningsClearance 0.05 m, A_BSUK_Walls_Timber 0.015 m
5C | 1F | PreShellWall :4 ,SHE-03.FIRST.dgn,Design Model:280763 | A_BSUK_OpeningsClearance 0.05 m, A_BSUK_Walls_Timber 0.015 m
5C | 1F | PreShellWall :4 ,SHE-03.FIRST.dgn,Design Model:291908 | A_BSUK_OpeningsClearance 0.05 m, A_BSUK_Walls_Timber 0.015 m
5C | 1F | PreShellWall :4 ,SHE-03.FIRST.dgn,Design Model:297632 | A_BSUK_Walls_Timber 0.015 m, A_BSUK_OpeningsClearance 0.05 m
5C | 1F | PreShellWall :4 ,SHE-03.FIRST.dgn,Design Model:297747 | A_BSUK_Walls_Timber 0.015 m, A_BSUK_OpeningsClearance 0.05 m
5C | 1F | PreShellWall :4 ,SHE-03.FIRST.dgn,Design Model:300520 | A_BSUK_Walls_Timber 0.015 m, A_BSUK_OpeningsClearance 0.05 m
5C | 1F | PreShellWall :4 ,SHE-03.FIRST.dgn,Design Model:300521 | A_BSUK_Walls_Timber 0.015 m, A_BSUK_OpeningsClearance 0.05 m
5C | 1F | PreShellWall :4 ,SHE-03.FIRST.dgn,Design Model:300568 | A_BSUK_Walls_Timber 0.015 m, A_BSUK_OpeningsClearance 0.05 m
5C | 1F | PreShellWall :4 ,SHE-03.FIRST.dgn,Design Model:300569 | A_BSUK_Walls_Timber 0.015 m, A_BSUK_OpeningsClearance 0.05 m
5C | 1F | PreShellWall :4 ,SHE-03.FIRST.dgn,Design Model:306845 | A_BSUK_Walls_Timber 0.015 m, A_BSUK_OpeningsClearance 0.05 m
5C | 1F | PreShellWall :4 ,SHE-03.FIRST.dgn,Design Model:306866 | A_BSUK_OpeningsClearance 0.05 m, A_BSUK_Walls_Timber 0.015 m
5C | 1F | PreShellWall :4 ,SHE-03.FIRST.dgn,Design Model:327268 | A_BSUK_OpeningsClearance 0.05 m, A_BSUK_Walls_Timber 0.015 m
5C | 1F | PreShellWall :4 ,SHE-03.FIRST.dgn,Design Model:327269 | A_BSUK_Walls_Timber 0.015 m, A_BSUK_OpeningsClearance 0.05 m
5C | 1F | PreShellWall :4 ,SHE-03.FIRST.dgn,Design Model:327337 | A_BSUK_OpeningsClearance 0.05 m, A_BSUK_Walls_Timber 0.015 m
5C | 1F | PreShellWall :4 ,SHE-03.FIRST.dgn,Design Model:327376 | A_BSUK_OpeningsClearance 0.05 m, A_BSUK_Walls_Timber 0.015 m
5C | 3F | PreShellWall :6 ,SHE-05.THIRD.dgn,Design Model:143085 | A_BSUK_OpeningsClearance 0.05 m, A_BSUK_Walls_Timber 0.015 m
5C | 3F | PreShellWall :6 ,SHE-05.THIRD.dgn,Design Model:143086 | A_BSUK_OpeningsClearance 0.05 m, A_BSUK_Walls_Timber 0.015 m
5C | 3F | PreShellWall :6 ,SHE-05.THIRD.dgn,Design Model:143088 | A_BSUK_OpeningsClearance 0.05 m, A_BSUK_Walls_Timber 0.015 m
5C | 3F | PreShellWall :6 ,SHE-05.THIRD.dgn,Design Model:143097 | A_BSUK_Walls_Timber 0.015 m, A_BSUK_OpeningsClearance 0.05 m
5C | 3F | PreShellWall :6 ,SHE-05.THIRD.dgn,Design Model:143098 | A_BSUK_Walls_Timber 0.015 m, A_BSUK_OpeningsClearance 0.05 m
5C | 3F | PreShellWall :6 ,SHE-05.THIRD.dgn,Design Model:143322 | A_BSUK_Walls_Timber 0.015 m, A_BSUK_OpeningsClearance 0.05 m
5C | 3F | PreShellWall :6 ,SHE-05.THIRD.dgn,Design Model:143323 | A_BSUK_Walls_Timber 0.015 m, A_BSUK_OpeningsClearance 0.05 m
5C | 3F | PreShellWall :6 ,SHE-05.THIRD.dgn,Design Model:143324 | A_BSUK_Walls_Timber 0.015 m, A_BSUK_OpeningsClearance 0.05 m
5C | 3F | PreShellWall :6 ,SHE-05.THIRD.dgn,Design Model:176874 | A_BSUK_Walls_Timber 0.015 m, A_BSUK_OpeningsClearance 0.05 m
5C | 3F | PreShellWall :6 ,SHE-05.THIRD.dgn,Design Model:176991 | A_BSUK_OpeningsClearance 0.05 m, A_BSUK_Walls_Timber 0.015 m
5C | 3F | PreShellWall :6 ,SHE-05.THIRD.dgn,Design Model:228570 | A_BSUK_OpeningsClearance 0.05 m, A_BSUK_Walls_Timber 0.015 m
5C | 3F | PreShellWall :6 ,SHE-05.THIRD.dgn,Design Model:228571 | A_BSUK_OpeningsClearance 0.05 m, A_BSUK_Walls_Timber 0.015 m
5C | 3F | PreShellWall :6 ,SHE-05.THIRD.dgn,Design Model:229415 | A_BSUK_Walls_Timber 0.015 m, A_BSUK_OpeningsClearance 0.05 m
5C | 3F | PreShellWall :6 ,SHE-05.THIRD.dgn,Design Model:272034 | A_BSUK_Walls_Timber 0.015 m, A_BSUK_OpeningsClearance 0.05 m
5C | 3F | PreShellWall :6 ,SHE-05.THIRD.dgn,Design Model:277751 | A_BSUK_OpeningsClearance 0.05 m, A_BSUK_Walls_Timber 0.015 m
5C | 3F | PreShellWall :6 ,SHE-05.THIRD.dgn,Design Model:277793 | A_BSUK_OpeningsClearance 0.05 m, A_BSUK_Walls_Timber 0.015 m
5C | 3F | PreShellWall :6 ,SHE-05.THIRD.dgn,Design Model:280763 | A_BSUK_OpeningsClearance 0.05 m, A_BSUK_Walls_Timber 0.015 m
5C | 3F | PreShellWall :6 ,SHE-05.THIRD.dgn,Design Model:291908 | A_BSUK_OpeningsClearance 0.05 m, A_BSUK_Walls_Timber 0.015 m
5C | 3F | PreShellWall :6 ,SHE-05.THIRD.dgn,Design Model:297632 | A_BSUK_Walls_Timber 0.015 m, A_BSUK_OpeningsClearance 0.05 m
5C | 3F | PreShellWall :6 ,SHE-05.THIRD.dgn,Design Model:297747 | A_BSUK_Walls_Timber 0.015 m, A_BSUK_OpeningsClearance 0.05 m
5C | 3F | PreShellWall :6 ,SHE-05.THIRD.dgn,Design Model:300520 | A_BSUK_Walls_Timber 0.015 m, A_BSUK_OpeningsClearance 0.05 m
5C | 3F | PreShellWall :6 ,SHE-05.THIRD.dgn,Design Model:300521 | A_BSUK_Walls_Timber 0.015 m, A_BSUK_OpeningsClearance 0.05 m
5C | 3F | PreShellWall :6 ,SHE-05.THIRD.dgn,Design Model:300568 | A_BSUK_OpeningsClearance 0.05 m, A_BSUK_Walls_Timber 0.015 m
5C | 3F | PreShellWall :6 ,SHE-05.THIRD.dgn,Design Model:300569 | A_BSUK_OpeningsClearance 0.05 m, A_BSUK_Walls_Timber 0.015 m
5C | 3F | PreShellWall :6 ,SHE-05.THIRD.dgn,Design Model:306845 | A_BSUK_Walls_Timber 0.015 m, A_BSUK_OpeningsClearance 0.05 m
5C | 3F | PreShellWall :6 ,SHE-05.THIRD.dgn,Design Model:306866 | A_BSUK_OpeningsClearance 0.05 m, A_BSUK_Walls_Timber 0.015 m
5C | 3F | PreShellWall :6 ,SHE-05.THIRD.dgn,Design Model:327268 | A_BSUK_Walls_Timber 0.015 m, A_BSUK_OpeningsClearance 0.05 m
5C | 3F | PreShellWall :6 ,SHE-05.THIRD.dgn,Design Model:327269 | A_BSUK_Walls_Timber 0.015 m, A_BSUK_OpeningsClearance 0.05 m
5C | 3F | PreShellWall :6 ,SHE-05.THIRD.dgn,Design Model:327337 | A_BSUK_OpeningsClearance 0.05 m, A_BSUK_Walls_Timber 0.015 m
5C | 3F | PreShellWall :6 ,SHE-05.THIRD.dgn,Design Model:327376 | A_BSUK_OpeningsClearance 0.05 m, A_BSUK_Walls_Timber 0.015 m
5C | 1F | PreShellWall :7 ,SHE-06.FOURTH.dgn,Design Model:243791 | A_BSUK_Walls_Timber 0.015 m, A_BSUK_OpeningsClearance 0.05 m
5C | 1F | PreShellWall :7 ,SHE-06.FOURTH.dgn,Design Model:244079 | A_BSUK_OpeningsClearance 0.05 m, A_BSUK_Walls_Timber 0.015 m
5C | 1F | PreShellWall :7 ,SHE-06.FOURTH.dgn,Design Model:244100 | A_BSUK_Walls_Timber 0.015 m, A_BSUK_OpeningsClearance 0.05 m
5C | 1F | PreShellWall :7 ,SHE-06.FOURTH.dgn,Design Model:244310 | A_BSUK_OpeningsClearance 0.05 m, A_BSUK_Walls_Timber 0.015 m
5C | 1F | PreShellWall :7 ,SHE-06.FOURTH.dgn,Design Model:245274 | A_BSUK_OpeningsClearance 0.05 m, A_BSUK_Walls_Timber 0.015 m
5C | 1F | PreShellWall :7 ,SHE-06.FOURTH.dgn,Design Model:245275 | A_BSUK_OpeningsClearance 0.05 m, A_BSUK_Walls_Timber 0.015 m
5C | 1F | PreShellWall :7 ,SHE-06.FOURTH.dgn,Design Model:245276 | A_BSUK_Walls_Timber 0.015 m, A_BSUK_OpeningsClearance 0.05 m
5C | 1F | PreShellWall :7 ,SHE-06.FOURTH.dgn,Design Model:245428 | A_BSUK_Walls_Timber 0.015 m, A_BSUK_OpeningsClearance 0.05 m
5C | 1F | PreShellWall :7 ,SHE-06.FOURTH.dgn,Design Model:248737 | A_BSUK_Walls_Timber 0.015 m, A_BSUK_OpeningsClearance 0.05 m
5C | 1F | PreShellWall :7 ,SHE-06.FOURTH.dgn,Design Model:248738 | A_BSUK_Walls_Timber 0.015 m, A_BSUK_OpeningsClearance 0.05 m
5C | 1F | PreShellWall :7 ,SHE-06.FOURTH.dgn,Design Model:248739 | A_BSUK_OpeningsClearance 0.05 m, A_BSUK_Walls_Timber 0.015 m
5C | 1F | PreShellWall :7 ,SHE-06.FOURTH.dgn,Design Model:248818 | A_BSUK_OpeningsClearance 0.05 m, A_BSUK_Walls_Timber 0.015 m
5C | 1F | PreShellWall :7 ,SHE-06.FOURTH.dgn,Design Model:256500 | A_BSUK_OpeningsClearance 0.05 m, A_BSUK_Walls_Timber 0.015 m
5C | 1F | PreShellWall :7 ,SHE-06.FOURTH.dgn,Design Model:256501 | A_BSUK_OpeningsClearance 0.05 m, A_BSUK_Walls_Timber 0.015 m
5C | 1F | PreShellWall :7 ,SHE-06.FOURTH.dgn,Design Model:256502 | A_BSUK_Walls_Timber 0.015 m, A_BSUK_OpeningsClearance 0.05 m
5C | 1F | PreShellWall :7 ,SHE-06.FOURTH.dgn,Design Model:256518 | A_BSUK_Walls_Timber 0.015 m, A_BSUK_OpeningsClearance 0.05 m
5C | 1F | PreShellWall :7 ,SHE-06.FOURTH.dgn,Design Model:408023 | A_BSUK_OpeningsClearance 0.05 m, A_BSUK_Walls_Timber 0.015 m
5C | 1F | PreShellWall :7 ,SHE-06.FOURTH.dgn,Design Model:408024 | A_BSUK_OpeningsClearance 0.05 m, A_BSUK_Walls_Timber 0.015 m
5C | 1F | PreShellWall :7 ,SHE-06.FOURTH.dgn,Design Model:408025 | A_BSUK_Walls_Timber 0.015 m, A_BSUK_OpeningsClearance 0.05 m
5C | 1F | PreShellWall :7 ,SHE-06.FOURTH.dgn,Design Model:408035 | A_BSUK_Walls_Timber 0.015 m, A_BSUK_OpeningsClearance 0.05 m
5C | 1F | PreShellWall :7 ,SHE-06.FOURTH.dgn,Design Model:408036 | A_BSUK_Walls_Timber 0.015 m, A_BSUK_OpeningsClearance 0.05 m
5C | 1F | PreShellWall :7 ,SHE-06.FOURTH.dgn,Design Model:408037 | A_BSUK_OpeningsClearance 0.05 m, A_BSUK_Walls_Timber 0.015 m
5C | 1F | PreShellWall :7 ,SHE-06.FOURTH.dgn,Design Model:483191 | A_BSUK_OpeningsClearance 0.05 m, A_BSUK_Walls_Timber 0.015 m
5C | 1F | PreShellWall :7 ,SHE-06.FOURTH.dgn,Design Model:483214 | A_BSUK_Walls_Timber 0.015 m, A_BSUK_OpeningsClearance 0.05 m
5C | 1F | PreShellWall :7 ,SHE-06.FOURTH.dgn,Design Model:513853 | A_BSUK_Walls_Timber 0.015 m, A_BSUK_OpeningsClearance 0.05 m
5C | 1F | PreShellWall :7 ,SHE-06.FOURTH.dgn,Design Model:513854 | A_BSUK_Walls_Timber 0.015 m, A_BSUK_OpeningsClearance 0.05 m
5C | 1F | PreShellWall :7 ,SHE-06.FOURTH.dgn,Design Model:513855 | A_BSUK_OpeningsClearance 0.05 m, A_BSUK_Walls_Timber 0.015 m
5C | 1F | PreShellWall :7 ,SHE-06.FOURTH.dgn,Design Model:514019 | A_BSUK_Walls_Timber 0.015 m, A_BSUK_OpeningsClearance 0.05 m
5C | 1F | PreShellWall :7 ,SHE-06.FOURTH.dgn,Design Model:514020 | A_BSUK_Walls_Timber 0.015 m, A_BSUK_OpeningsClearance 0.05 m
5C | 1F | PreShellWall :7 ,SHE-06.FOURTH.dgn,Design Model:514021 | A_BSUK_OpeningsClearance 0.05 m, A_BSUK_Walls_Timber 0.015 m
5C | 1F | PreShellWall :7 ,SHE-06.FOURTH.dgn,Design Model:514108 | A_BSUK_Walls_Timber 0.015 m, A_BSUK_OpeningsClearance 0.05 m
5C | 1F | PreShellWall :7 ,SHE-06.FOURTH.dgn,Design Model:514109 | A_BSUK_Walls_Timber 0.015 m, A_BSUK_OpeningsClearance 0.05 m
5C | 1F | PreShellWall :7 ,SHE-06.FOURTH.dgn,Design Model:514110 | A_BSUK_OpeningsClearance 0.05 m, A_BSUK_Walls_Timber 0.015 m
5C | 2F | PreShellWall :18,SHE-04.SECOND.dgn,Design Model:143085 | A_BSUK_OpeningsClearance 0.05 m, A_BSUK_Walls_Timber 0.015 m
5C | 2F | PreShellWall :18,SHE-04.SECOND.dgn,Design Model:143086 | A_BSUK_OpeningsClearance 0.05 m, A_BSUK_Walls_Timber 0.015 m
5C | 2F | PreShellWall :18,SHE-04.SECOND.dgn,Design Model:143088 | A_BSUK_OpeningsClearance 0.05 m, A_BSUK_Walls_Timber 0.015 m
5C | 2F | PreShellWall :18,SHE-04.SECOND.dgn,Design Model:143097 | A_BSUK_Walls_Timber 0.015 m, A_BSUK_OpeningsClearance 0.05 m
5C | 2F | PreShellWall :18,SHE-04.SECOND.dgn,Design Model:143098 | A_BSUK_Walls_Timber 0.015 m, A_BSUK_OpeningsClearance 0.05 m
5C | 2F | PreShellWall :18,SHE-04.SECOND.dgn,Design Model:143322 | A_BSUK_Walls_Timber 0.015 m, A_BSUK_OpeningsClearance 0.05 m
5C | 2F | PreShellWall :18,SHE-04.SECOND.dgn,Design Model:143323 | A_BSUK_Walls_Timber 0.015 m, A_BSUK_OpeningsClearance 0.05 m
5C | 2F | PreShellWall :18,SHE-04.SECOND.dgn,Design Model:143324 | A_BSUK_Walls_Timber 0.015 m, A_BSUK_OpeningsClearance 0.05 m
5C | 2F | PreShellWall :18,SHE-04.SECOND.dgn,Design Model:176874 | A_BSUK_Walls_Timber 0.015 m, A_BSUK_OpeningsClearance 0.05 m
5C | 2F | PreShellWall :18,SHE-04.SECOND.dgn,Design Model:176991 | A_BSUK_OpeningsClearance 0.05 m, A_BSUK_Walls_Timber 0.015 m
5C | 2F | PreShellWall :18,SHE-04.SECOND.dgn,Design Model:228570 | A_BSUK_OpeningsClearance 0.05 m, A_BSUK_Walls_Timber 0.015 m
5C | 2F | PreShellWall :18,SHE-04.SECOND.dgn,Design Model:228571 | A_BSUK_OpeningsClearance 0.05 m, A_BSUK_Walls_Timber 0.015 m
5C | 2F | PreShellWall :18,SHE-04.SECOND.dgn,Design Model:229415 | A_BSUK_Walls_Timber 0.015 m, A_BSUK_OpeningsClearance 0.05 m
5C | 2F | PreShellWall :18,SHE-04.SECOND.dgn,Design Model:272034 | A_BSUK_Walls_Timber 0.015 m, A_BSUK_OpeningsClearance 0.05 m
5C | 2F | PreShellWall :18,SHE-04.SECOND.dgn,Design Model:277751 | A_BSUK_OpeningsClearance 0.05 m, A_BSUK_Walls_Timber 0.015 m
5C | 2F | PreShellWall :18,SHE-04.SECOND.dgn,Design Model:277793 | A_BSUK_OpeningsClearance 0.05 m, A_BSUK_Walls_Timber 0.015 m
5C | 2F | PreShellWall :18,SHE-04.SECOND.dgn,Design Model:280763 | A_BSUK_OpeningsClearance 0.05 m, A_BSUK_Walls_Timber 0.015 m
5C | 2F | PreShellWall :18,SHE-04.SECOND.dgn,Design Model:291908 | A_BSUK_OpeningsClearance 0.05 m, A_BSUK_Walls_Timber 0.015 m
5C | 2F | PreShellWall :18,SHE-04.SECOND.dgn,Design Model:297632 | A_BSUK_Walls_Timber 0.015 m, A_BSUK_OpeningsClearance 0.05 m
5C | 2F | PreShellWall :18,SHE-04.SECOND.dgn,Design Model:297747 | A_BSUK_Walls_Timber 0.015 m, A_BSUK_OpeningsClearance 0.05 m
5C | 2F | PreShellWall :18,SHE-04.SECOND.dgn,Design Model:300520 | A_BSUK_Walls_Timber 0.015 m, A_BSUK_OpeningsClearance 0.05 m
5C | 2F | PreShellWall :18,SHE-04.SECOND.dgn,Design Model:300521 | A_BSUK_Walls_Timber 0.015 m, A_BSUK_OpeningsClearance 0.05 m
5C | 2F | PreShellWall :18,SHE-04.SECOND.dgn,Design Model:300568 | A_BSUK_Walls_Timber 0.015 m, A_BSUK_OpeningsClearance 0.05 m
5C | 2F | PreShellWall :18,SHE-04.SECOND.dgn,Design Model:300569 | A_BSUK_Walls_Timber 0.015 m, A_BSUK_OpeningsClearance 0.05 m
5C | 2F | PreShellWall :18,SHE-04.SECOND.dgn,Design Model:306845 | A_BSUK_Walls_Timber 0.015 m, A_BSUK_OpeningsClearance 0.05 m
5C | 2F | PreShellWall :18,SHE-04.SECOND.dgn,Design Model:306866 | A_BSUK_OpeningsClearance 0.05 m, A_BSUK_Walls_Timber 0.015 m
5C | 2F | PreShellWall :18,SHE-04.SECOND.dgn,Design Model:327268 | A_BSUK_OpeningsClearance 0.05 m, A_BSUK_Walls_Timber 0.015 m
5C | 2F | PreShellWall :18,SHE-04.SECOND.dgn,Design Model:327269 | A_BSUK_Walls_Timber 0.015 m, A_BSUK_OpeningsClearance 0.05 m
5C | 2F | PreShellWall :18,SHE-04.SECOND.dgn,Design Model:327337 | A_BSUK_OpeningsClearance 0.05 m, A_BSUK_Walls_Timber 0.015 m
5C | 2F | PreShellWall :18,SHE-04.SECOND.dgn,Design Model:327376 | A_BSUK_OpeningsClearance 0.05 m, A_BSUK_Walls_Timber 0.015 m

# IfcWallStandardCase: default (114)
Name | In | Description | Material | Wall Function | Part Definition
default | 1F | 4 ,SHE-03.FIRST.dgn,Design Model:126329 | A_BSUK_WallInternal_Finishes_Plasterboard 0.015 m | Finish | A-Walls::A_BSUK_WallInternal_Finishes_Plasterboard
default | 1F | 4 ,SHE-03.FIRST.dgn,Design Model:126338 | A_BSUK_WallInternal_Finishes_Plasterboard 0.015 m | Finish | A-Walls::A_BSUK_WallInternal_Finishes_Plasterboard
default | 1F | 4 ,SHE-03.FIRST.dgn,Design Model:126347 | A_BSUK_Insulation 0.05 m | Structure | A-Walls::A_BSUK_Insulation
default | 1F | 4 ,SHE-03.FIRST.dgn,Design Model:126356 | A_BSUK_WallInternal_Finishes_Plasterboard 0.015 m | Finish | A-Walls::A_BSUK_WallInternal_Finishes_Plasterboard
default | 1F | 4 ,SHE-03.FIRST.dgn,Design Model:126365 | A_BSUK_WallInternal_Finishes_Plasterboard 0.015 m | Finish | A-Walls::A_BSUK_WallInternal_Finishes_Plasterboard
default | 1F | 4 ,SHE-03.FIRST.dgn,Design Model:126374 | A_BSUK_Walls_Timber 0.015 m | Finish | A-Walls::A_BSUK_Walls_Timber
default | 1F | 4 ,SHE-03.FIRST.dgn,Design Model:126646 | A_BSUK_WallInternal_Finishes_Plasterboard 0.013 m |  | A-Walls::A_BSUK_WallInternal_Finishes_Plasterboard
default | 1F | 4 ,SHE-03.FIRST.dgn,Design Model:128119 | A_BSUK_Walls_Timber 0.015 m |  | A-Walls::A_BSUK_Walls_Timber
default | 1F | 4 ,SHE-03.FIRST.dgn,Design Model:128128 | A_BSUK_WallInternal_Finishes_Plasterboard 0.015 m |  | A-Walls::A_BSUK_WallInternal_Finishes_Plasterboard
default | 1F | 4 ,SHE-03.FIRST.dgn,Design Model:128137 | A_BSUK_WallInternal_Finishes_Plasterboard 0.015 m |  | A-Walls::A_BSUK_WallInternal_Finishes_Plasterboard
default | 1F | 4 ,SHE-03.FIRST.dgn,Design Model:128146 | A_BSUK_Insulation 0.05 m |  | A-Walls::A_BSUK_Insulation
default | 1F | 4 ,SHE-03.FIRST.dgn,Design Model:128155 | A_BSUK_WallInternal_Finishes_Plasterboard 0.015 m |  | A-Walls::A_BSUK_WallInternal_Finishes_Plasterboard
default | 1F | 4 ,SHE-03.FIRST.dgn,Design Model:128166 | A_BSUK_WallInternal_Finishes_Plasterboard 0.015 m |  | A-Walls::A_BSUK_WallInternal_Finishes_Plasterboard
default | 1F | 4 ,SHE-03.FIRST.dgn,Design Model:128177 | A_BSUK_Walls_Timber 0.015 m |  | A-Walls::A_BSUK_Walls_Timber
default | 1F | 4 ,SHE-03.FIRST.dgn,Design Model:130799 | A_BSUK_Walls_Timber 0.015 m |  | A-Walls::A_BSUK_Walls_Timber
default | 1F | 4 ,SHE-03.FIRST.dgn,Design Model:132321 | A_BSUK_Walls_Timber 0.015 m |  | A-Walls::A_BSUK_Walls_Timber
default | 3F | 6 ,SHE-05.THIRD.dgn,Design Model:123270 | A_BSUK_WallInternal_Finishes_Plasterboard 0.013 m | Finish | A-Walls::A_BSUK_WallInternal_Finishes_Plasterboard
default | 3F | 6 ,SHE-05.THIRD.dgn,Design Model:123279 | A_BSUK_Insulation 0.036 m | Rigid Insulation | A-Walls::A_BSUK_Insulation
default | 3F | 6 ,SHE-05.THIRD.dgn,Design Model:123414 | A_BSUK_WallInternal_Finishes_Plasterboard 0.013 m | Finish | A-Walls::A_BSUK_WallInternal_Finishes_Plasterboard
default | 3F | 6 ,SHE-05.THIRD.dgn,Design Model:123423 | A_BSUK_Insulation 0.036 m | Rigid Insulation | A-Walls::A_BSUK_Insulation
default | 3F | 6 ,SHE-05.THIRD.dgn,Design Model:123522 | A_BSUK_WallInternal_Finishes_Plasterboard 0.013 m | Finish | A-Walls::A_BSUK_WallInternal_Finishes_Plasterboard
default | 3F | 6 ,SHE-05.THIRD.dgn,Design Model:123531 | A_BSUK_Insulation 0.036 m | Rigid Insulation | A-Walls::A_BSUK_Insulation
default | 3F | 6 ,SHE-05.THIRD.dgn,Design Model:123540 | A_BSUK_WallInternal_Finishes_Plasterboard 0.013 m | Finish | A-Walls::A_BSUK_WallInternal_Finishes_Plasterboard
default | 3F | 6 ,SHE-05.THIRD.dgn,Design Model:123549 | A_BSUK_Insulation 0.036 m | Rigid Insulation | A-Walls::A_BSUK_Insulation
default | 3F | 6 ,SHE-05.THIRD.dgn,Design Model:124260 | A_BSUK_WallInternal_Finishes_Plasterboard 0.013 m | Finish | A-Walls::A_BSUK_WallInternal_Finishes_Plasterboard
default | 3F | 6 ,SHE-05.THIRD.dgn,Design Model:124269 | A_BSUK_Insulation 0.036 m | Rigid Insulation | A-Walls::A_BSUK_Insulation
default | 3F | 6 ,SHE-05.THIRD.dgn,Design Model:124296 | A_BSUK_WallInternal_Finishes_Plasterboard 0.013 m | Finish | A-Walls::A_BSUK_WallInternal_Finishes_Plasterboard
default | 3F | 6 ,SHE-05.THIRD.dgn,Design Model:124305 | A_BSUK_Insulation 0.036 m | Rigid Insulation | A-Walls::A_BSUK_Insulation
default | 3F | 6 ,SHE-05.THIRD.dgn,Design Model:124314 | A_BSUK_WallInternal_Finishes_Plasterboard 0.013 m | Finish | A-Walls::A_BSUK_WallInternal_Finishes_Plasterboard
default | 3F | 6 ,SHE-05.THIRD.dgn,Design Model:124323 | A_BSUK_Insulation 0.036 m | Rigid Insulation | A-Walls::A_BSUK_Insulation
default | 3F | 6 ,SHE-05.THIRD.dgn,Design Model:124350 | A_BSUK_WallInternal_Finishes_Plasterboard 0.013 m | Finish | A-Walls::A_BSUK_WallInternal_Finishes_Plasterboard
default | 3F | 6 ,SHE-05.THIRD.dgn,Design Model:124359 | A_BSUK_Insulation 0.036 m | Rigid Insulation | A-Walls::A_BSUK_Insulation
default | 3F | 6 ,SHE-05.THIRD.dgn,Design Model:124899 | A_BSUK_WallInternal_Finishes_Plasterboard 0.013 m | Finish | A-Walls::A_BSUK_WallInternal_Finishes_Plasterboard
default | 3F | 6 ,SHE-05.THIRD.dgn,Design Model:124908 | A_BSUK_Insulation 0.036 m | Rigid Insulation | A-Walls::A_BSUK_Insulation
default | 3F | 6 ,SHE-05.THIRD.dgn,Design Model:124917 | A_BSUK_WallInternal_Finishes_Plasterboard 0.013 m | Finish | A-Walls::A_BSUK_WallInternal_Finishes_Plasterboard
default | 3F | 6 ,SHE-05.THIRD.dgn,Design Model:124926 | A_BSUK_Insulation 0.036 m | Rigid Insulation | A-Walls::A_BSUK_Insulation
default | 3F | 6 ,SHE-05.THIRD.dgn,Design Model:125025 | A_BSUK_WallInternal_Finishes_Plasterboard 0.013 m | Finish | A-Walls::A_BSUK_WallInternal_Finishes_Plasterboard
default | 3F | 6 ,SHE-05.THIRD.dgn,Design Model:125034 | A_BSUK_Insulation 0.036 m | Rigid Insulation | A-Walls::A_BSUK_Insulation
default | 3F | 6 ,SHE-05.THIRD.dgn,Design Model:125160 | A_BSUK_WallInternal_Finishes_Plasterboard 0.013 m | Finish | A-Walls::A_BSUK_WallInternal_Finishes_Plasterboard
default | 3F | 6 ,SHE-05.THIRD.dgn,Design Model:125169 | A_BSUK_Insulation 0.036 m | Rigid Insulation | A-Walls::A_BSUK_Insulation
default | 3F | 6 ,SHE-05.THIRD.dgn,Design Model:126329 | A_BSUK_WallInternal_Finishes_Plasterboard 0.015 m | Finish | A-Walls::A_BSUK_WallInternal_Finishes_Plasterboard
default | 3F | 6 ,SHE-05.THIRD.dgn,Design Model:126338 | A_BSUK_WallInternal_Finishes_Plasterboard 0.015 m | Finish | A-Walls::A_BSUK_WallInternal_Finishes_Plasterboard
default | 3F | 6 ,SHE-05.THIRD.dgn,Design Model:126347 | A_BSUK_Insulation 0.05 m | Structure | A-Walls::A_BSUK_Insulation
default | 3F | 6 ,SHE-05.THIRD.dgn,Design Model:126356 | A_BSUK_WallInternal_Finishes_Plasterboard 0.015 m | Finish | A-Walls::A_BSUK_WallInternal_Finishes_Plasterboard
default | 3F | 6 ,SHE-05.THIRD.dgn,Design Model:126365 | A_BSUK_WallInternal_Finishes_Plasterboard 0.015 m | Finish | A-Walls::A_BSUK_WallInternal_Finishes_Plasterboard
default | 3F | 6 ,SHE-05.THIRD.dgn,Design Model:126374 | A_BSUK_Walls_Timber 0.015 m | Finish | A-Walls::A_BSUK_Walls_Timber
default | 3F | 6 ,SHE-05.THIRD.dgn,Design Model:128119 | A_BSUK_Walls_Timber 0.015 m |  | A-Walls::A_BSUK_Walls_Timber
default | 3F | 6 ,SHE-05.THIRD.dgn,Design Model:128128 | A_BSUK_WallInternal_Finishes_Plasterboard 0.015 m |  | A-Walls::A_BSUK_WallInternal_Finishes_Plasterboard
default | 3F | 6 ,SHE-05.THIRD.dgn,Design Model:128137 | A_BSUK_WallInternal_Finishes_Plasterboard 0.015 m |  | A-Walls::A_BSUK_WallInternal_Finishes_Plasterboard
default | 3F | 6 ,SHE-05.THIRD.dgn,Design Model:128146 | A_BSUK_Insulation 0.05 m |  | A-Walls::A_BSUK_Insulation
default | 3F | 6 ,SHE-05.THIRD.dgn,Design Model:128155 | A_BSUK_WallInternal_Finishes_Plasterboard 0.015 m |  | A-Walls::A_BSUK_WallInternal_Finishes_Plasterboard
default | 3F | 6 ,SHE-05.THIRD.dgn,Design Model:128166 | A_BSUK_WallInternal_Finishes_Plasterboard 0.015 m |  | A-Walls::A_BSUK_WallInternal_Finishes_Plasterboard
default | 3F | 6 ,SHE-05.THIRD.dgn,Design Model:128177 | A_BSUK_Walls_Timber 0.015 m |  | A-Walls::A_BSUK_Walls_Timber
default | 3F | 6 ,SHE-05.THIRD.dgn,Design Model:128834 | A_BSUK_Walls_Timber 0.015 m |  | A-Walls::A_BSUK_Walls_Timber
default | 3F | 6 ,SHE-05.THIRD.dgn,Design Model:128843 | A_BSUK_WallInternal_Finishes_Plasterboard 0.013 m |  | A-Walls::A_BSUK_WallInternal_Finishes_Plasterboard
default | 3F | 6 ,SHE-05.THIRD.dgn,Design Model:128852 | A_BSUK_Insulation 0.036 m |  | A-Walls::A_BSUK_Insulation
default | 3F | 6 ,SHE-05.THIRD.dgn,Design Model:130799 | A_BSUK_Walls_Timber 0.015 m |  | A-Walls::A_BSUK_Walls_Timber
default | 3F | 6 ,SHE-05.THIRD.dgn,Design Model:132321 | A_BSUK_Walls_Timber 0.015 m |  | A-Walls::A_BSUK_Walls_Timber
